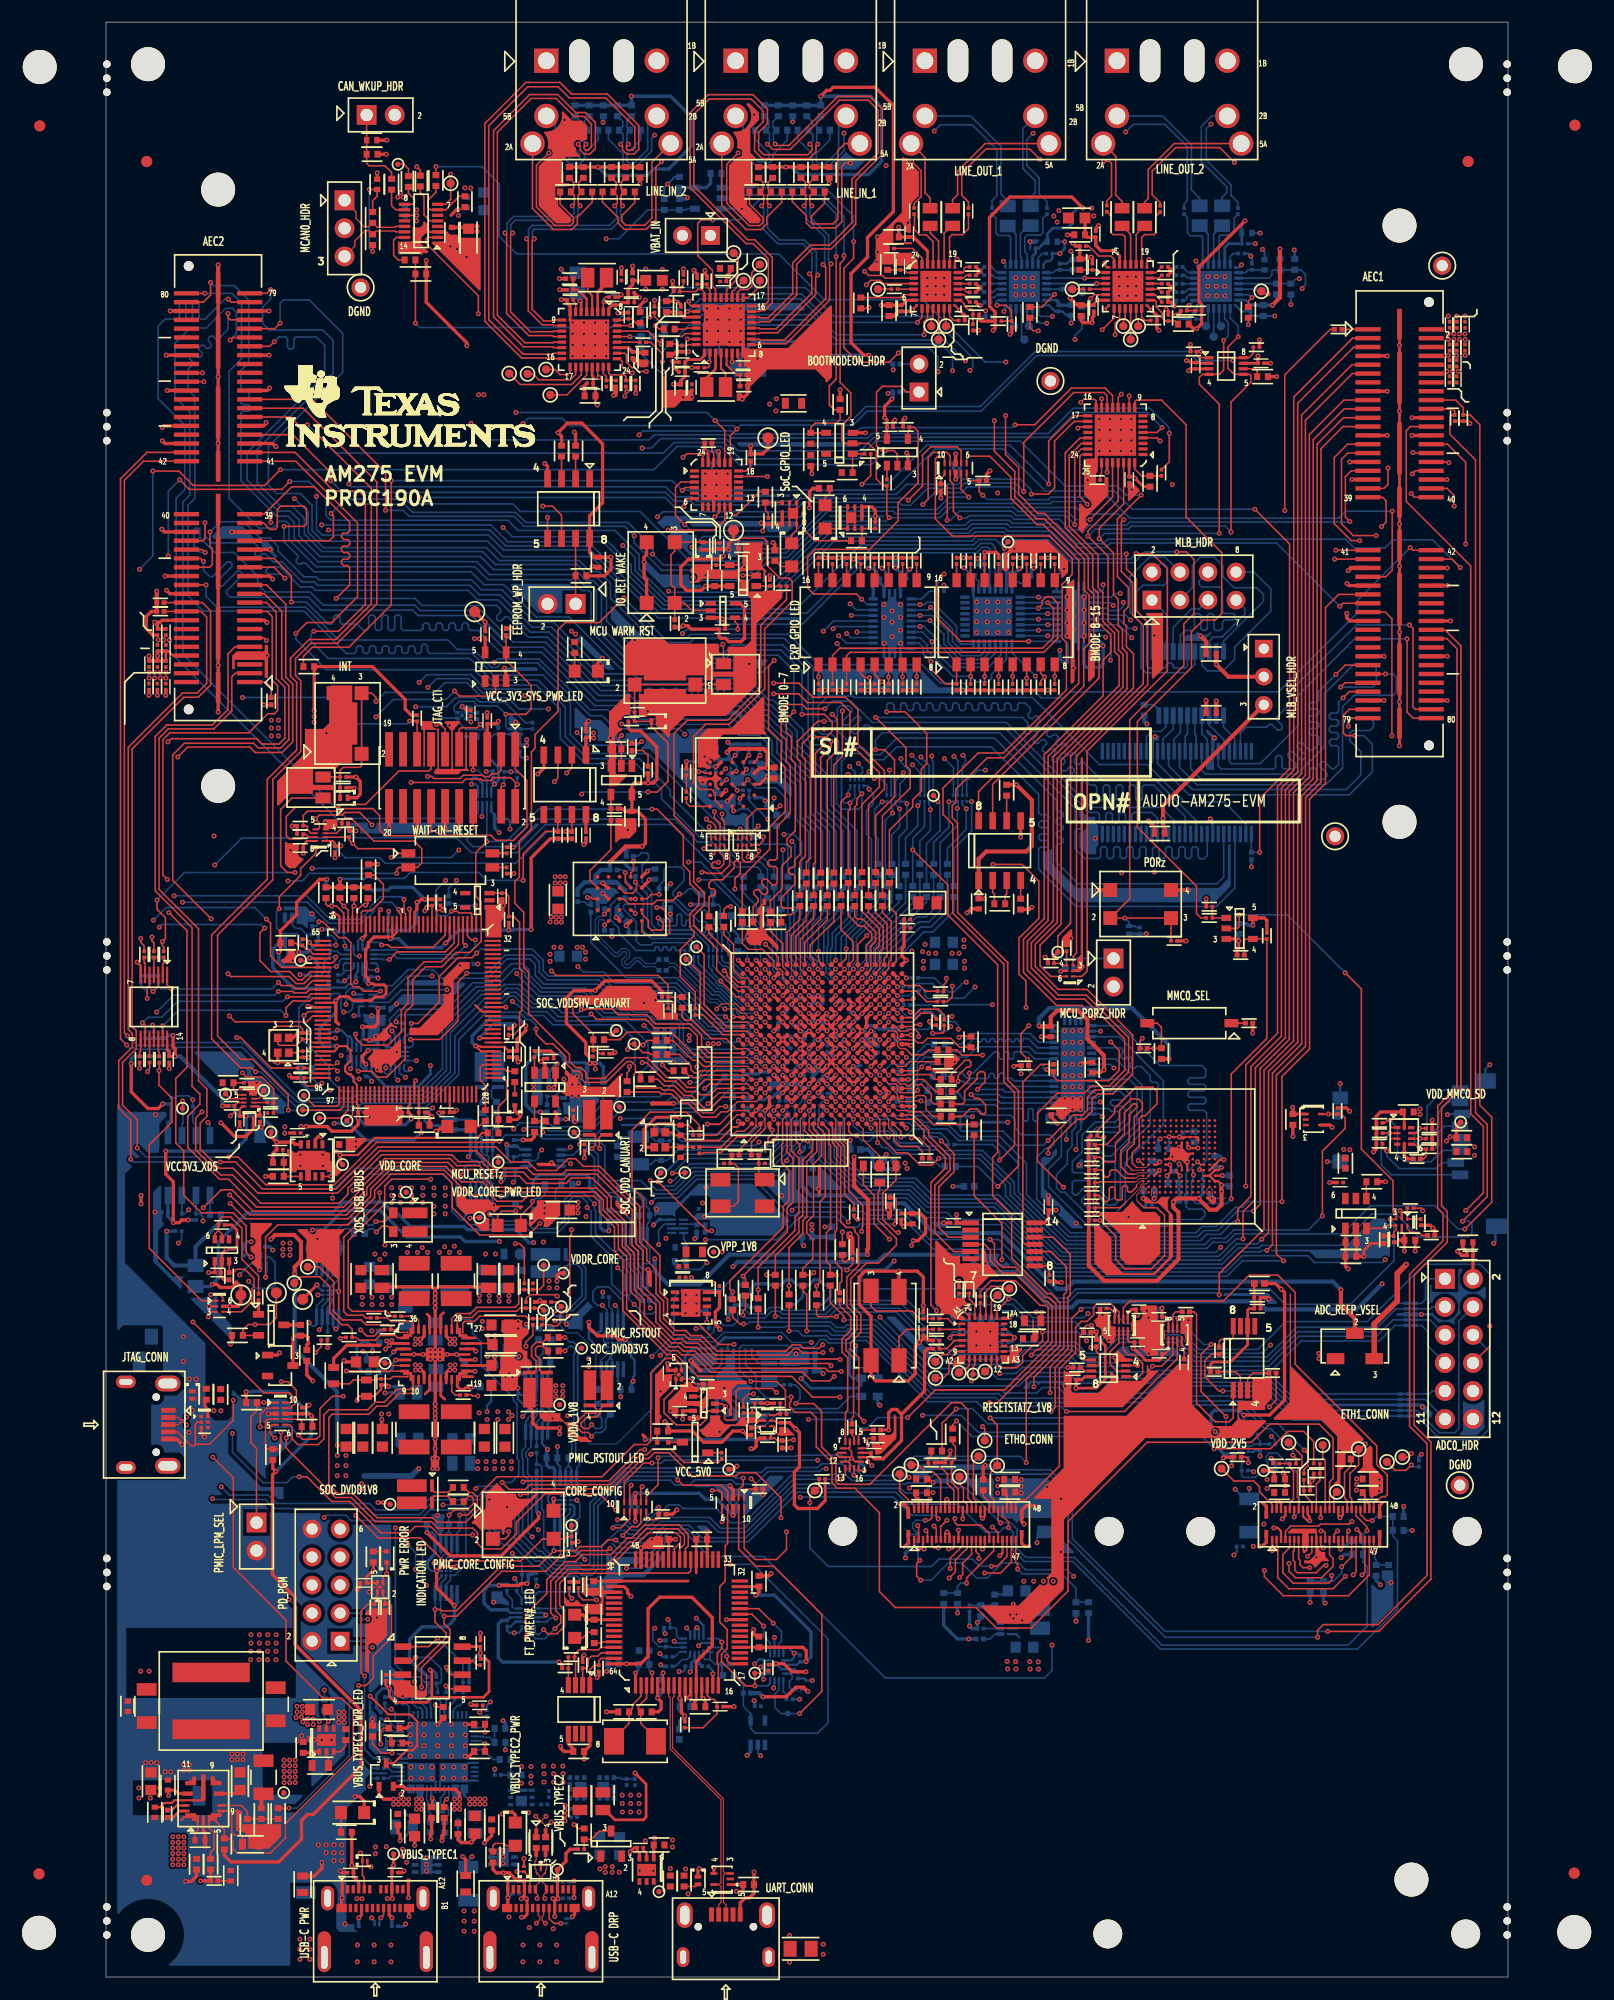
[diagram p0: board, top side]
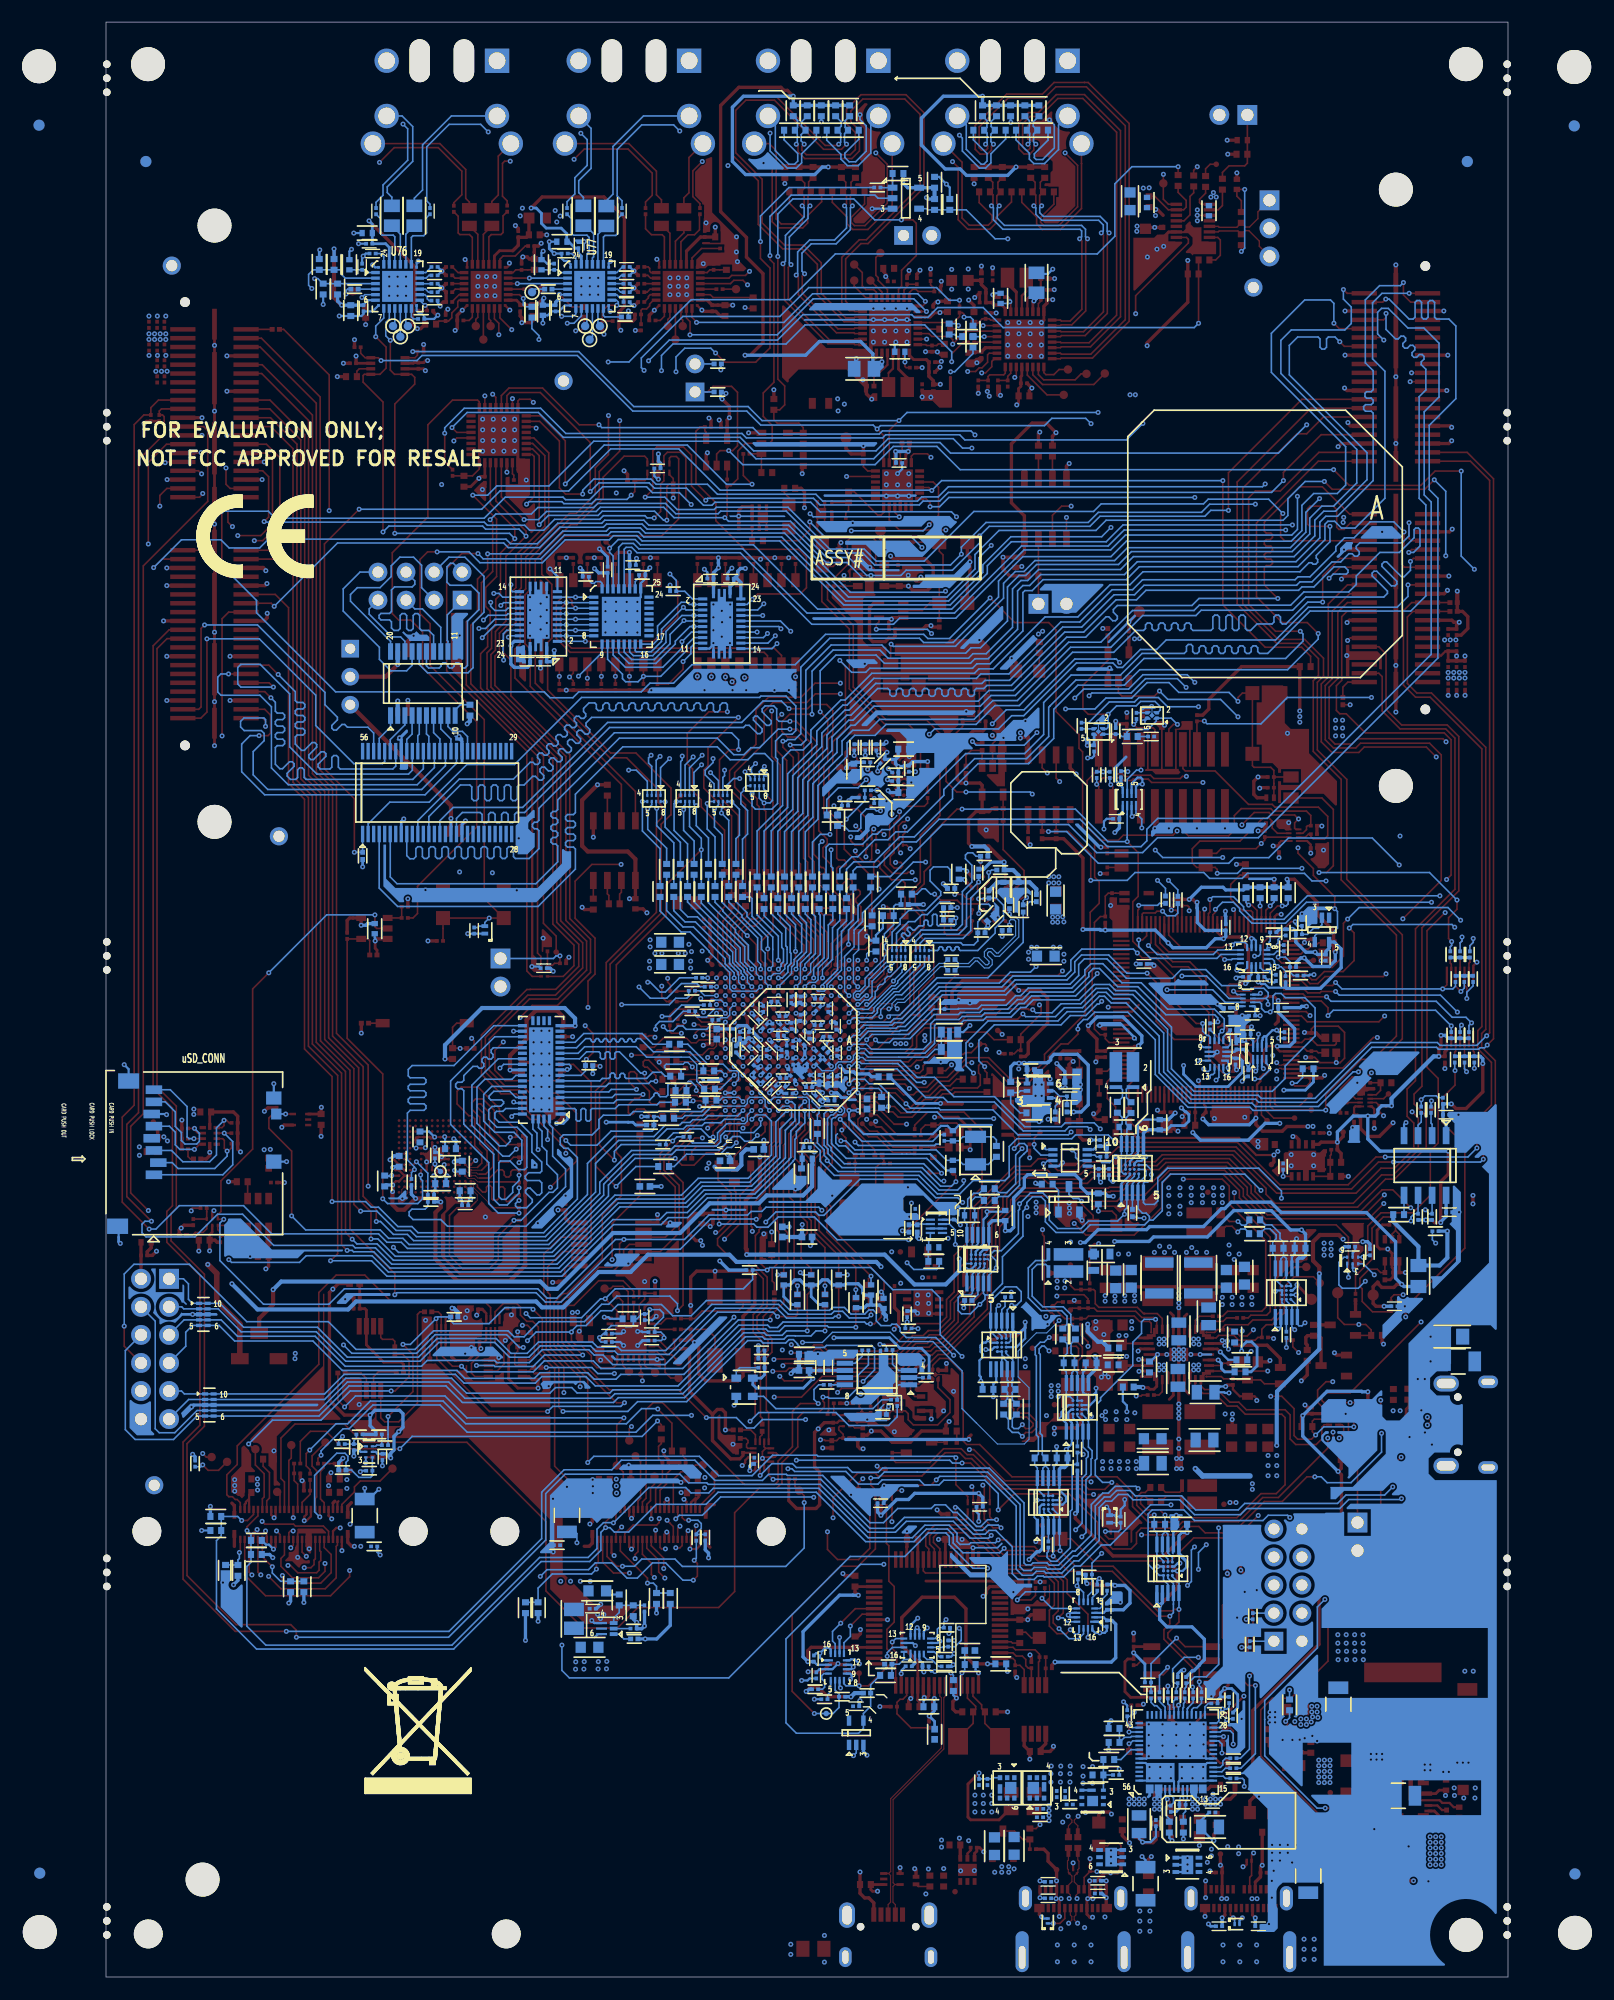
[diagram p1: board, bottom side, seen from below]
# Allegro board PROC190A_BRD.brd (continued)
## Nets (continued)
MCAN0_RX: R81.1 U136.B4
MCAN0_RX_R: R81.2 U3068.4
MCAN0_STB#: R102.1 U3068.14
MCAN0_T: C107.1 R88.1 R93.2
MCAN0_TX: R82.2 U136.C4
MCAN0_TX_R: R82.1 U3068.1
MCAN0_WAKE_R: R5635.1 U3068.9(WAKE)
MCAN1_RX: R5670.1 U136.D5
MCAN1_RX_R: J13.53 R5670.2
MCAN1_TX: J13.51 R5671.1
MCAN1_TX_R: R5671.2 U136.A4
MCAN4_RX: R5650.1 U136.B6
MCAN4_RX_R: J12.53 R5650.2
MCAN4_TX: J12.51 R5649.1
MCAN4_TX_R: R5649.2 U136.R4
MCASP0_ACLKR: J12.43 R5648.1 RA7.7
MCASP0_ACLKR_R: R5648.2 U136.R16
MCASP0_ACLKX: J12.37 R178.1 RA6.8
MCASP0_AFSR: J12.41 R498.2 RA7.6
MCASP0_AFSR_R: R498.1 U136.T17
MCASP0_AFSX: J12.39 R191.2 RA2.8
MCASP0_AFSX_R: R191.1 U136.M19
MCASP0_AXR0: J12.27 R176.2 RA5.8
MCASP0_AXR0_R: R176.1 U136.N17
MCASP0_AXR1: J12.29 R499.2 RA2.7
MCASP0_AXR1_R: R499.1 U136.M16
MCASP0_AXR2: J12.28 R493.2 RA2.6
MCASP0_AXR2_R: R493.1 U136.N18
MCASP0_AXR3: J12.30 R494.2 RA6.5
MCASP0_AXR3_R: R494.1 U136.M18
MCASP0_AXR4: J12.32 R495.2 RA7.5
MCASP0_AXR4_R: R495.1 U136.N16
MCASP0_AXR5: J12.34 R492.2 RA5.6
MCASP0_AXR5_R: R492.1 U136.P17
MCASP0_AXR6_R: R5718.1 U136.P18
MCASP0_AXR7: J12.38 R177.2 RA2.5
MCASP0_AXR7_R: R177.1 U136.P19
MCASP0_AXR8_R: R5719.1 U136.P16
MCASP0_AXR9: J12.40 R491.2 RA7.8
MCASP0_AXR9_R: R491.1 U136.R17
MCASP1_ACLKR_R: R179.2 U136.T18
MCASP1_ACLKX_R: R5646.2 U136.H19
MCASP1_AFSR_R: R5640.1 U136.T19
MCASP1_AFSX_R: R5647.1 U136.J17
MCASP1_AXR0_R: R500.1 U136.J18
MCASP1_AXR1_R: R5645.1 U136.J19
MCASP1_AXR2_R: R190.1 U136.J16
MCASP2_ACLKR: J13.43 R5669.1
MCASP2_ACLKR_R: R5669.2 U136.G17
MCASP2_ACLKX: J13.37 R5668.1
MCASP2_ACLKX_R: R5668.2 U136.L19
MCASP2_AFSR: J13.41 R5667.2
MCASP2_AFSR_R: R5667.1 U136.G16
MCASP2_AFSX: J13.39 R5666.2
MCASP2_AFSX_R: R5666.1 U136.K19
MCASP2_AXR0: J13.27 R5660.2
MCASP2_AXR0_R: R5660.1 U136.L17
MCASP2_AXR1: J13.29 R5661.2
MCASP2_AXR1_R: R5661.1 U136.K16
MCASP2_AXR2: J13.28 R5662.2
MCASP2_AXR2_R: R5662.1 U136.L18
MCASP2_AXR3: J13.30 R5663.2
MCASP2_AXR3_R: R5663.1 U136.K18
MCASP2_AXR4: J13.32 R5664.2
MCASP2_AXR4_R: R5664.1 U136.L16
MCASP2_AXR5: J13.34 R5665.2
MCASP2_AXR5_R: R5665.1 U136.M17
MCASP3_ACLKR: J13.78 R5683.1
MCASP3_ACLKX: J13.77 R5677.1
MCASP3_AFSR: J13.80 R5682.2
MCASP3_AFSX: J13.79 R5676.2
MCASP3_AXR0: J13.67 R5672.2
MCASP3_AXR1: J13.69 R5673.2
MCASP3_AXR2: J13.71 R5674.2
MCASP3_AXR3: J13.73 R5675.2
MCASP4_ACLKR: J12.78 U3072.54
MCASP4_ACLKR_FET: R5651.1 RA6.6 U3072.2
MCASP4_ACLKR_HDR: J28.3 U2345.20
MCASP4_ACLKR_LT: U2345.1 U3072.53
MCASP4_ACLKR_R: R5651.2 U136.R18
MCASP4_ACLKX: J12.77 U3072.39
MCASP4_ACLKX_FET: R5653.1 U3072.18
MCASP4_ACLKX_HDR: J28.1 U2345.12
MCASP4_ACLKX_LT: U2345.9 U3072.37
MCASP4_ACLKX_R: R5653.2 R5683.2 U136.F18
MCASP4_AFSR: J12.80 U3072.52
MCASP4_AFSR_FET: R5652.2 RA6.7 U3072.4
MCASP4_AFSR_HDR: J28.7 U2345.18
MCASP4_AFSR_LT: U2345.3 U3072.51
MCASP4_AFSR_R: R5652.1 U136.R19
MCASP4_AFSX: J12.79 U3072.41
MCASP4_AFSX_FET: R5655.2 U3072.15
MCASP4_AFSX_HDR: J28.5 U2345.13
MCASP4_AFSX_LT: U2345.8 U3072.40
MCASP4_AFSX_R: R5655.1 R5682.1 U136.F17
MCASP4_AXR0: J12.67 U3072.50
MCASP4_AXR0_FET: R5654.2 U3072.6
MCASP4_AXR0_HDR: J28.8 U2345.17
MCASP4_AXR0_LT: U2345.4 U3072.48
MCASP4_AXR0_R: R5654.1 U136.F19
MCASP4_AXR3: J12.69 U3072.43
MCASP4_AXR3_FET: R5658.2 U3072.13
MCASP4_AXR3_LT: U2345.7 U3072.42
MCASP4_AXR3_MLB0_SIG_HDR: J28.6 U2345.14
MCASP4_AXR3_R: R5658.1 U136.U18
MCASP4_AXR4: J12.71 U3072.47
MCASP4_AXR4_FET: R5656.2 U3072.9
MCASP4_AXR4_LT: U2345.5 U3072.46
MCASP4_AXR4_MLB0_CLK_HDR: J28.4 U2345.16
MCASP4_AXR4_R: R5656.1 U136.U19
MCASP4_AXR5: J12.73 U3072.45
MCASP4_AXR5_FET: R5657.2 U3072.11
MCASP4_AXR5_LT: U2345.6 U3072.44
MCASP4_AXR5_MLB0_DAT_HDR: J28.2 U2345.15
MCASP4_AXR5_R: R5657.1 U136.V19
MCASP4_FET_SEL: R5681.1 R5764.1 U18.4 U3072.1
MCASP_VSEL_HDR: C3702.1 J29.2 U2345.19(VCCB)
MCU_GPIO0_1_INTN: R108.1 R547.2 U136.C7
MCU_INTN: R299.1 U136.M2
MCU_OSC0_XI: R249.2 R252.2 U136.A2
MCU_OSC0_XO: R253.2 R254.2 U136.B1
MCU_PORZ: J32.1 R238.1 R242.2 R5775.1 R5776.1 TP49.1(TP) U43.4(Y) U136.E3
MCU_RESETZ: R550.2 TP50.1(TP) U98.7 U136.D9
MCU_SAFETY_ERRORZ_1V8: R281.1 U3091.7
MCU_SAFETY_ERRORZ_1V8_BUF: R5842.1 TP54.1(TP) U136.F3
MIC1_BIAS: C3.1 C329.1 C379.1 R7.1 R8.1 R9.1 R10.1 R405.1 R406.1 R407.1 R408.1 U7.6
MIC2_BIAS: C2.1 C330.1 C363.1 R3.1 R4.1 R5.1 R6.1 R409.1 R410.1 R411.1 R412.1 U8.6
MMC0_CLK: R558.1 U57.2
MMC0_FET_EN: R5215.2 R5216.2 U18.3 U57.8
MMC0_SD_EN: R21.1 U21.4
MMC0_SD_LS_EN: R17.1 R5823.2 U2.4(Y) U4.3
MMC0_SDIO_VSEL: U56.11 U3087.4(Y)
MMC0_SEL_1V8: U3077.4 U3086.1 U3087.1
MMC0_SEL_3V3: R5758.1 U3077.11
MMC0_SEL_IO: R5846.1 U18.17
OBSCLK0: R5719.2 RA5.5 TP587.1(TP)
OSC0: C217.2 U48.88 Y5.3
OSC1: C223.2 U48.89 Y5.1
OSC1_XI: R3732.1 U136.C1
OSC1_XO: R3733.1 U136.C2
OSPI0_CSN0: R206.2 U136.A17
OSPI0_RESET_OUT0: R121.1 U136.A16
OSPI_CLK: R197.1 R451.1 U28.B2
OSPI_CS: R206.1 R447.1 R5826.2 R5827.2
OSPI_DQ0: R446.1 RA3.1 U28.D3
OSPI_DQ1: R450.1 RA3.2 U28.D2
OSPI_DQ2: R452.1 RA3.3 U28.C4
OSPI_DQ3: R449.1 RA3.4 U28.D4
OSPI_DQ4: R448.1 RA4.1 U28.D5
OSPI_DQ5: R445.1 RA4.2 U28.E3
OSPI_DQ6: R444.1 RA4.3 U28.E2
OSPI_DQ7: R443.1 RA4.4 U28.E1
OSPI_DQS: R453.1 U28.C3
OSPI_DQS_SOC: R453.2 R454.1 R504.1 U136.B19
OSPI_INTN: R123.1 R125.1
OSPI_RSTN: R124.1 R5821.2 U27.4(Y) U28.A4
P2_PP_EXT_ENABLE: R669.1 U129.49
PCM1_ADDR_0: R20.2 R26.1 U7.24
PCM1_ADDR_1: R22.1 R23.2 U7.23
PCM1_AREG: C89.1 C378.1 U7.2
PCM1_BSTOUT: C92.2 C96.1 U7.5
PCM1_DREG: C81.1 C82.1 U7.32
PCM1_GPIO1: R34.2 R432.1 U7.28
PCM1_IN1N: C17.2 R9.2 U7.10
PCM1_IN1P: C18.2 R10.2 U7.9
PCM1_IN2N: C15.2 R7.2 U7.12
PCM1_IN2P: C16.2 R8.2 U7.11
PCM1_IN3N: C334.2 R408.2 U7.14
PCM1_IN3P: C333.2 R407.2 U7.13
PCM1_IN4N: C332.2 R406.2 U7.16
PCM1_IN4P: C331.2 R405.2 U7.15
PCM1_INT_1V8: R34.1 U21.15
PCM1_MCASP1_AXR0: R38.2 U7.29
PCM1_RESETN: R68.2 R78.1 U7.22 U14.4(Y)
PCM1_VREF: C87.1 U7.7
PCM2_ADDR_0: R62.2 R63.1 U8.24
PCM2_ADDR_1: R60.2 R61.1 U8.23
PCM2_AREG: C64.1 C368.1 U8.2
PCM2_BSTOUT: C54.1 C60.2 U8.5
PCM2_IN1N: C13.2 R5.2 U8.10
PCM2_IN1P: C14.2 R6.2 U8.9
PCM2_IN2N: C11.2 R3.2 U8.12
PCM2_IN2P: C12.2 R4.2 U8.11
PCM2_IN3N: C338.2 R412.2 U8.14
PCM2_IN3P: C337.2 R411.2 U8.13
PCM2_IN4N: C336.2 R410.2 U8.16
PCM2_IN4P: C335.2 R409.2 U8.15
PCM2_INT_1V8: R46.1 U21.16
PCM2_MCASP1_AXR0: R431.2 R433.1
PCM2_RESETN: R415.2 R416.1 U8.22 U75.4(Y)
PCM2_VREF: C65.1 U8.7
PCM6240_MCASP1_ACLKR: R179.1 U7.30 U8.30
PCM6240_MCASP1_AFSR: R5640.2 U7.31 U8.31
PCM6240_MCASP1_AXR0: R38.1 R431.1 R500.2
PCM6240_MCASP1_AXR2: R190.2 R435.1
PD_GPIO0: R674.2 U129.16
PD_HRESET: C301.1 R662.1 U129.44
PD_I2C_IRQ: R645.2 R655.1 U18.6
PD_MS_I2C1_IRQ: R660.2 U129.29
PD_MS_I2C1_SCL: R633.1 R664.2 U129.27
PD_MS_I2C1_SDA: R627.1 R658.2 U129.28
PD_S_I2C2_IRQ: R655.2 U129.34
PD_S_I2C2_SCL: R657.2 U129.32
PD_S_I2C2_SDA: R656.2 U129.33
PD_SPI_CLK: J21.7 R652.2 U69.6
PD_SPI_MISO: J21.5 R644.2 R654.2 U69.2
PD_SPI_MOSI: J21.8 R653.2 U69.5
PD_SPI_SS: J21.9 R646.2 R651.2 U69.1
PD_VIN_3V3: C320.2 U129.5(VIN_3V3)
PMIC_EN: R317.2 U56.17
PMIC_ENABLE: U54.6 U2356.10
PMIC_I2C_SCL_1V8: R296.2 TP72.1(TP) U56.1
PMIC_I2C_SDA_1V8: R294.2 TP73.1(TP) U56.2
PMIC_INT_B: R288.2 R299.2 R300.2 TP70.1(TP) U56.27
PMIC_INTN: R205.1 R300.1 U136.P3
PMIC_LPM_EN0: R5737.1 R5750.2 TP75.1(TP) U2356.2 U2356.7
PMIC_LPM_SEL: J16.1 R318.1 U2356.1 U2356.5
PMIC_NSLEEP: U56.10 U2356.6
PMIC_POWERGOOD: R290.1 U86.1
PMIC_RSTOUT: R286.1 R290.2 R291.2 TP67.1(TP) U56.28
PORT1_15W: R386.1 R5767.1 U71.2
PORT2_15W: R381.1 R390.1 U71.1
PP1_CABLE: C309.1 U129.25
PP2_CABLE: C631.1 R665.2 U129.46
PRI/SEC_REF_SEL: R75.2 R76.1 U15.4
RESET_STATZ: R5738.1 TP592.1(TP) U136.H4
RESETSTATZ: R366.1 R605.1 R5843.2 U18.24 U3083.6
RESETSTATZ_1V8: J12.55 J13.55 R377.2 R5738.2 R5760.2 TP100.1(TP) U2.3 U14.2 U15.8 U21.28 U26.2 U27.2 U75.2 U2348.2 U3083.3 U3088.2
RESETSTATZ_1V8_INV: R5832.1 R5844.1 R5845.2 U3088.4(Y)
RESETSTATZ_1V8_INV_RC: C3781.1 R5844.2 U3091.4
RGMII1_INH_3V3: J18.26 TP65.1(TP)
RGMII1_RX_ER: J18.39 TP99.1(TP)
RGMII1_RX_LINK: J18.43 R360.2 TP98.1(TP)
RGMII2_INH_3V3: J19.26 TP59.1(TP)
RGMII2_RX_ER: J19.39 TP89.1(TP)
RGMII2_RX_LINK: J19.43 R347.2 TP91.1(TP)
SD_MMC0_CLK: J26.5 R54.1 R202.1 U10.6 U57.41
SD_MMC0_CMD: J26.3 R66.1 U10.1 U57.23
SD_MMC0_D0: J26.7 R65.1 U10.8 U57.38
SD_MMC0_D1: J26.8 R57.1 U10.7 U57.36
SD_MMC0_D2: J26.1 R64.1 U10.2 U57.29
SD_MMC0_D3: J26.2 R55.1 U10.3 U57.39
SD_MMC0_SDCD: J26.9 R70.1 U12.5 U136.N2
SEC_REF_N: R74.1 U15.2
SEC_REF_P: R73.1 U15.1
SEL_XDS: U39.5 U93.4(Y) U97.1 U97.16 U109.4
SEL_XDS110_INV: J14.8 R531.2 R536.1 U90.4 U93.2 U102.5 U110.1 U110.16 U2355.2
SEL_XDS110_INV_3V3: R5735.1 U87.2 U88.2 U2355.4(Y)
SOC_CLKIN: R249.1 R349.2
SOC_DVDD1V8: C429.1 C437.1 C440.1 C453.1 C461.1 C502.1 C506.1 R334.3 TP86.1(TP) U56.24 U136.E13 U136.F8 U136.F9 U136.F12 U136.H14 U136.J6 U136.J14 U136.K6 U136.K14 U136.M6
SOC_DVDD1V8_N: C603.2 R335.1 U123.D1 U123.D2 U124.8 U124.9
SOC_DVDD1V8_P: C603.1 R331.1 U123.D3 U124.10
SOC_DVDD3V3: C451.1 C471.1 FL19.1 R327.3 TP83.1(TP) U56.22 U136.H5 U136.P11 U136.P12
SOC_DVDD3V3_FB1: C3645.1 FL19.2 U136.R9
SOC_DVDD3V3_N: C428.2 R539.1 U91.8 U91.9 U92.D1 U92.D2
SOC_DVDD3V3_P: C428.1 R540.1 U91.10 U92.D3
SOC_EMU0: R225.2 SW3.1 U39.2 U102.2 U136.C9
SOC_EMU1: R220.2 SW3.2 U39.3 U102.3 U136.C10
SOC_GPIO0_38: R213.1 U136.K17
SOC_HYPERBUS0_DQ0: RA8.8 U136.A13
SOC_HYPERBUS0_DQ1: RA8.7 U136.D12
SOC_HYPERBUS0_DQ2: RA8.5 U136.D13
SOC_HYPERBUS0_DQ3: RA8.6 U136.C13
SOC_HYPERBUS0_DQ4: RA9.8 U136.A15
SOC_HYPERBUS0_DQ5: RA9.5 U136.C15
SOC_HYPERBUS0_DQ6: RA9.7 U136.B14
SOC_HYPERBUS0_DQ7: RA9.6 U136.C14
SOC_I2C0_SCL: J18.40 J19.40 R56.2 R622.2 R625.1 R657.1 U11.8 U18.19 U25.2 U91.2 U91.5 U92.A1 U92.B3 U113.A1 U114.5 U115.A1 U116.5 U118.1 U118.5 U119.A1 U119.C3 U123.A1 U124.5 U2357.8 U3078.5 U3079.2 U3079.5 U3080.A1 U3081.A1 U3081.B3
SOC_I2C0_SDA: J18.42 J19.42 R58.2 R616.1 R618.2 R656.1 U11.1 U18.20 U25.3 U91.4 U92.A2 U113.A2 U114.4 U115.A2 U116.4 U118.4 U119.A2 U123.A2 U124.4 U2357.7 U3078.2 U3078.4 U3079.4 U3080.A2 U3080.B3 U3081.A2
SOC_MMC0_CLK: R558.2 U136.V5
SOC_MMC0_CMD: R5819.1 U57.14
SOC_MMC0_CMD_R: R5819.2 U136.T6
SOC_MMC0_DAT0: R5811.1 U57.4
SOC_MMC0_DAT0_R: R5811.2 U136.W4
SOC_MMC0_DAT1: R5812.1 U57.5
SOC_MMC0_DAT1_R: R5812.2 U136.W5
SOC_MMC0_DAT2: R5813.1 U57.11
SOC_MMC0_DAT2_R: R5813.2 U136.V6
SOC_MMC0_DAT3: R5814.1 U57.3
SOC_MMC0_DAT3_R: R5814.2 U136.U6
SOC_MMC0_DAT4: R5815.1 U57.13
SOC_MMC0_DAT4_R: R5815.2 U136.U7
SOC_MMC0_DAT5: R5816.1 U57.12
SOC_MMC0_DAT5_R: R5816.2 U136.T7
SOC_MMC0_DAT6: R5817.1 U57.6
SOC_MMC0_DAT6_R: R5817.2 U136.V7
SOC_MMC0_DAT7: R5818.1 U57.7
SOC_MMC0_DAT7_R: R5818.2 U136.W7
SOC_OSPI_CLK: R197.2 U136.B17
SOC_OSPI_DQ0: RA3.8 U136.B16
SOC_OSPI_DQ1: RA3.7 U136.D17
SOC_OSPI_DQ2: RA3.6 U136.C17
SOC_OSPI_DQ3: RA3.5 U136.D16
SOC_OSPI_DQ4: RA4.8 U136.E16
SOC_OSPI_DQ5: RA4.7 U136.B18
SOC_OSPI_DQ6: RA4.6 U136.D18
SOC_OSPI_DQ7: RA4.5 U136.C18
SOC_PORZ: R480.2 U43.3 U86.4(Y)
SOC_PORZ_PB: R268.2 TP55.1(TP) U43.1 U98.2
SOC_RGMII_MDC: R338.1 R352.1 R548.2
SOC_RGMII_MDIO: R340.1 R345.1 R541.2
SOC_TCK: R534.1 R544.1 R566.1 U136.A10
SOC_TDI: R554.1 U97.6 U110.9 U136.D10
SOC_TDO: R542.1 U90.2 U109.2
SOC_TMS: R533.1 U97.8 U110.8 U136.C11
SOC_TRST#: R564.1 U97.9 U110.6 U136.B10
SOC_UART0_RXD: R5734.2 U136.L2
SOC_UART0_RXD_XDS: R5730.1 U2353.13
SOC_UART0_TXD: R5732.2 U2353.8
SOC_UART0_TXD_XDS: R5731.1 U2353.15
SOC_USB0_DM: L10.4(OUT2) R400.1 U136.W9
SOC_USB0_DP: L10.1 R399.1 U136.V9
SOC_USB0_DRVVBUS: U136.W2 U3077.5
SOC_USB0_DRVVBUS_3V3: R673.1 R674.1 U3077.10
SOC_USB0_RCALIB: R553.1 U136.V8
SOC_USB0_VBUS: R398.1 R560.1 U136.U9
SOC_VDD_CANUART: C224.1 R3731.1 R5786.2 TP52.1(TP) U136.F6
SOC_VDD_CANUART_N: C3761.2 R5780.1 U3078.8 U3078.9 U3080.D1 U3080.D2
SOC_VDD_CANUART_P: C3761.1 R5781.1 U3078.10 U3080.D3
SOC_VDDSHV5_SDIO: C3655.1 R243.2 U136.P9 U136.R8
SOC_VDDSHV_CANUART: C512.1 R5787.2 TP597.1(TP) U136.F7
SOC_VDDSHV_CANUART_N: C3763.2 R5784.1 U3079.8 U3079.9 U3081.D1 U3081.D2
SOC_VDDSHV_CANUART_P: C3763.1 R5785.1 U3079.10 U3081.D3
SPI0_CLK: J12.17 R216.1
SPI0_CLK_R: R216.2 U136.M1
SPI0_CS0: J12.23 U136.J3
SPI0_CS1: J12.24 U136.J4
SPI0_D0: J12.19 U136.K3
SPI0_D1: J12.21 U136.K4
SPI1_CLK: J13.17 R5659.1
SPI1_CLK_R: R5659.2 U136.U2
SPI1_CS0: J13.23 U136.U1
SPI1_CS1: J13.24 U136.D15
SPI1_D0: J13.19 U136.T3
SPI1_D1: J13.21 U136.U3
SPI_HOLDN: R374.2 U69.7
SPI_WPN: R378.2 U69.3(W\P\(IO2))
SW_2V5: L11.1 U127.5
SYNC1_OUT: R5788.1 U3083.2
SYNC1_OUT_3V3: R5793.1 U3084.1
SYNC1_OUT_ETH1: J18.38 R5791.2 TP93.1(TP)
SYNC1_OUT_ETH2: J19.38 R5792.2 TP87.1(TP)
SYS_BOOTMODE0: R153.1 SW2.1 U81.10 U82.1
SYS_BOOTMODE1: R154.1 SW2.2 U81.9 U82.2
SYS_BOOTMODE2: R155.1 SW2.3 U81.8 U82.3
SYS_BOOTMODE3: R156.1 SW2.4 U81.7 U82.4
SYS_BOOTMODE4: R157.1 SW2.5 U81.6 U82.5
SYS_BOOTMODE5: R158.1 SW2.6 U81.5 U82.6
SYS_BOOTMODE6: R159.1 SW2.7 U81.4 U82.7
SYS_BOOTMODE7: R160.1 SW2.8 U81.3 U82.8
SYS_BOOTMODE8: R145.1 SW1.1 U82.9 U83.10
SYS_BOOTMODE9: R146.1 SW1.2 U82.10 U83.9
SYS_BOOTMODE10: R147.1 SW1.3 U82.11 U83.8
SYS_BOOTMODE11: R148.1 SW1.4 U82.12 U83.7
SYS_BOOTMODE12: R149.1 SW1.5 U82.13 U83.6
SYS_BOOTMODE13: R150.1 SW1.6 U82.14 U83.5
SYS_BOOTMODE14: R151.1 SW1.7 U82.15 U83.4
SYS_BOOTMODE15: R152.1 SW1.8 U82.16 U83.3
SYSBOOT_BUF_ENZ: R377.1 U23.1
TAD1_ADDR1: R29.2 R37.2 U5.13
TAD1_DREG_OUT: C42.1 C45.1 U5.1
TAD1_GPI1: R31.1 U5.12
TAD1_MICBIAS: C66.1 U5.14
TAD1_VREF: C38.1 U5.24
TAD2_ADDR2: R33.2 R36.2 U77.13
TAD2_DREG_OUT: C356.1 C358.1 U77.1
TAD2_GPI1: R429.1 U77.12
TAD2_MICBIAS: C370.1 U77.14
TAD2_VREF: C354.1 U77.24
TAD3_ADDR3: R30.1 R35.1 U6.13
TAD3_DREG_OUT: C43.1 C46.1 U6.1
TAD3_GPI3: R32.1 U6.12
TAD3_MICBIAS: C67.1 U6.14
TAD3_VREF: C35.1 U6.24
TAD4_ADDR4: R27.1 R28.1 U76.13
TAD4_DREG_OUT: C355.1 C357.1 U76.1
TAD4_GPI4: R430.1 U76.12
TAD4_MICBIAS: C369.1 U76.14
TAD4_VREF: C353.1 U76.24
TAD5212_1_DIN: R5641.2 U5.5
TAD5212_2_DIN: R5642.2 U77.5
TAD5212_3_DIN: R5643.2 U6.5
TAD5212_4_DIN: R5644.2 U76.5
TAD5212_MCASP1_ACLKX: R418.2 R419.1 R5646.1 U5.2 U6.2 U76.2 U77.2
TAD5212_MCASP1_AFSX: R422.2 R423.1 R5647.2 U5.3 U6.3 U76.3 U77.3
TAD5212_MCASP1_AXR1: R5641.1 R5642.1 R5643.1 R5644.1 R5645.2
TCA6424_EXP_INT: R457.1 U82.32
TEST_GPIO1: Q7.1 R235.1 R526.2
TEST_GPIO2: R283.1 R285.2 U21.18
TEST_GPIO3: J10.1 R227.1 R439.1 R516.2 U23.2
TEST_GPIO4: R221.1 R511.2 U82.28
TEST_PORZN: R219.1 R507.2 U43.6
TEST_POWERDOWN: R233.1 R524.2 U54.1
TEST_WARMRESETN: Q12.1 R224.1 R513.2
TM4C129_TCK: TP66.1(TP) U48.100
TM4C129_TDI: TP64.1(TP) U48.98
TM4C129_TDO: TP62.1(TP) U48.97
TM4C129_TMS: TP63.1(TP) U48.99
TMP411_ALERT: R5741.2 U2357.6
TMP411_THERM: R5742.2 U2357.4
TPS65224_EN: Q4.2(S) R303.1 R317.1 TP81.1(TP)
UART2_FET_SEL: R5799.2 U21.13 U2351.1 U2351.5
UART2_RXD: J12.62 U2351.4
UART2_RXD_FET: R5718.2 RA5.7 U2351.6
UART2_TXD: J12.60 U2351.2
UART2_TXD_FET: U136.T4 U2351.10
UART3_FET_SEL: R5800.2 U21.14 U2352.1 U2352.5
UART3_RXD: J13.62 U2352.4
UART3_RXD_FET: U136.C6 U2352.6
UART3_TXD: J13.60 U2352.2
UART3_TXD_FET: U136.N4 U2352.10
UART_SHIELD: J22.6 J22.7 J22.8 J22.9 R385.2
USB_TYPEC1_EARTH: C648.1 J24.SH1 J24.SH2 J24.SH3 J24.SH4 R404.1
USB_TYPEC2_EARTH: C651.1 J25.SH1 J25.SH2 J25.SH3 J25.SH4 R403.1
USBC_CONN1_CC1: C307.1 D7.1(CATHODE) J24.A5 U129.24
USBC_CONN1_CC2: C306.1 D17.1(CATHODE) J24.B5 U129.26
USBC_CONN2_CC1: C305.1 D8.1(CATHODE) J25.A5 U129.45
USBC_CONN2_CC2: C312.1 D16.1(CATHODE) J25.B5 U129.47
USBC_CONN2_DM: D9.3(IO2) J25.A7 J25.B7 L10.3 R400.2
USBC_CONN2_DP: D9.2 J25.A6 J25.B6 L10.2 R399.2
VMAIN: C310.1 C3625.1 C3628.1 C3629.1 C3630.1 C3631.1 C3697.2 R395.1 R5636.1 R5740.1 TP104.1(TP) U73.1(VOUT) U134.8 U134.12(VIN2) U3068.10
VMAIN_EN: LD14.1(CATHODE) R382.1 U71.4(Y)
VMAIN_PD: C302.1 C322.1 C323.1 C324.1 U73.6 U129.1 U129.11
VMON1: C3750.2 R5773.1 R5774.2 U56.9
VPHY_3V3_FT4232: C606.2 FL17.1 U64.4
VPLL_3V3_FT4232: C607.2 FL18.1 R357.2 U64.9
VPP_1V8: C517.1 R304.2 TP69.1(TP) U136.G5
VPP_EN: R319.1 U21.5
VPP_SUPPLY: C247.2 C251.2 R304.1 U59.1(OUT)
VSEL_SD_SOC: R5751.2 R5830.1 U3086.2
WD_DISABLE: R281.2 R282.2 TP56.1(TP) U56.29
WKUP_I2C0_SCL: C245.1 R284.1 R297.1 R301.2
WKUP_I2C0_SCL_RC: R284.2 U136.B9
WKUP_I2C0_SDA: C248.1 R256.1 R259.2 R307.1
WKUP_I2C0_SDA_RC: R256.2 U136.A8
WKUP_LFOSCO_XI: C216.2 R568.1 U136.E1 Y4.1
WKUP_LFOSCO_XO: C213.2 R261.2 R568.2 Y4.2
WKUP_UART0_CTSN: R322.2 U117.9 U136.D6
WKUP_UART0_RTSN: R593.2 U117.7 U136.C5
WKUP_UART0_RXD: R326.2 U117.8 U136.B5
WKUP_UART0_TXD: R592.2 U117.6 U136.A5
XDS110_DIR: R555.2 U97.4 U97.5
XDS110_EMU0: R237.2 U48.42 U102.7
XDS110_EMU1: R236.2 U48.43 U102.6
XDS110_TCK: U48.35 U97.14
XDS110_TDI: U48.38 U97.15
XDS110_TDO: U48.37 U109.7
XDS110_TMS: U48.36 U97.13
XDS110_TRST#: U48.40 U97.12
XDS_GPIO1: R235.2 U40.2
XDS_GPIO2: R283.2 U51.2
XDS_GPIO3: R227.2 U40.4
XDS_GPIO4: R221.2 U40.6
XDS_PORZN: R219.2 U40.8
XDS_POWERDOWN: R233.2 U40.12
XDS_RSTN: R549.1 R556.1 TP51.1(TP) U48.70
XDS_SHIELD: C605.2 J17.6 J17.7 J17.8 J17.9 R610.2
XDS_USB_DM: J17.2 U48.93
XDS_USB_DP: J17.3 U48.94
XDS_USB_ID: J17.4 R271.2 U60.2
XDS_USB_VBUS: C244.1 C250.1 C267.1 D1.2 J17.1(VBUS) R295.1 R314.1 R576.1 TP78.1(TP) U55.1 U55.2 U60.6(VCC)
XDS_VREF: C190.1 C215.2 R241.2 U41.3 U48.9
XDS_WARMRESETN: R224.2 U40.10
ZENER_CLAMP: D2.3 R298.1 R308.1
N16856152: C270.1 U64.3 Y6.2
N16856224: C269.1 U64.2 Y6.1
N16857368: C283.2 U66.2
N16880083: R18.1 R21.2 U2.1
N16956459: R121.2 R122.1 U27.1
N16994873: R483.2 U88.4(Y)
N16994875: R476.2 U87.4(Y)
N16995245: C417.1 R487.2
N16997746: R218.1 U48.59
N17030208: R544.2 U97.7
N17031262: LD9.2 R402.2
N17078974: J10.2 R438.2
N17269599: R363.1 R366.2 U68.6
N17269609: R362.1 R364.2 R367.1 U68.1
N17378539: LD7.1(CATHODE) R330.2
N17479799: R314.2 U55.8
N17479805: C243.2 R306.2 R313.1 U55.5
N17479881: C203.2 R246.1 U48.68
N17481587: LD5.2 R287.2
N17481598: C225.2 R576.2 U48.96
N17481613: R271.1 U48.95
N17481619: R289.1 R295.2 U48.1
N17481621: R232.2 R520.1 U48.60
N17481627: R276.1 U48.3
N17481631: LD3.2 R276.2
N17481633: R229.2 R523.1 U48.63
N17481635: R231.2 R521.1 U48.61
N17481637: R287.1 U48.4
N17481641: R230.2 R522.1 U48.62
N17824845: R654.1 U129.36
N17824852: R653.1 U129.37
N17824859: R652.1 U129.38
N17824866: R651.1 U129.39
N19741013: R390.2 U129.18
N19806973: R566.2 U110.7
N21761137: R5750.1 U136.A7
N21784165: R548.1 U136.V11
N21784176: R541.1 U136.U11
N22498870: R602.1 R605.2 U120.6
N22498881: R601.1 R604.2 R606.1 U120.1
N22682556: J21.1 R633.2
N22682559: J21.3 R627.2
N24306091: C3746.2 R293.1 U3076.5(QOD) U3076.6
N24306103: Q4.1 R293.2
N24306157: D5.3(K) R308.2
N24306190: Q4.3 R298.2
N24307354: R5828.2 U56.4
N24307356: R5829.2 U56.6
N24478126: C70.1 U4.4
N24517110: R214.2 SW3.3
N24517112: R217.2 SW3.4
N24605604: C18.1 J2.5A
N24605606: C16.1 J2.2A
N24605709: R84.2 R90.1 U14.1
N24605835: TP5.1(TP) U7.20
N24605846: L3.2 U7.4
N24605909: C333.1 J2.5B
N24606047: TP8.1(TP) U7.19
N24606049: TP9.1(TP) U7.17
N24606166: C331.1 J2.2B
N24847876: R421.1 U77.4
N24847884: C348.1 J3.5B
N24847886: C347.1 J3.2B
N24847888: C347.2 U77.21
N24847892: C344.2 U77.19
N24847894: C343.2 U77.22
N24847910: C348.2 U77.20
N24847912: TP113.1(TP) U77.11
N24847957: C367.1 U77.15
N24847963: C365.1 U77.16
N24847969: C362.1 U77.17
N24847975: C360.1 U77.18
N24847993: TP112.1(TP) U77.9
N24847995: TP115.1(TP) U77.10
N24848039: R24.1 U5.4
N24848041: C25.1 J3.5A
N24848043: C24.1 J3.2A
N24848045: C24.2 U5.21
N24848047: C23.2 U5.19
N24848049: C22.2 U5.22
N24848518: C25.2 U5.20
N24848523: TP18.1(TP) U5.11
N24848568: C61.1 U5.15
N24848574: C56.1 U5.16
N24848580: C50.1 U5.17
N24848586: C47.1 U5.18
N24848600: R24.2 TP12.1(TP)
N24848612: R421.2 TP109.1(TP)
N24848616: TP17.1(TP) U5.9
N24848618: TP22.1(TP) U5.10
N24851304: R420.1 U76.4
N24851306: R420.2 TP14.1(TP)
N24851312: C346.1 J4.5B
N24851314: C345.1 J4.2B
N24851316: C345.2 U76.21
N24851320: C342.2 U76.19
N24851322: C341.2 U76.22
N24851338: C346.2 U76.20
N24851340: TP111.1(TP) U76.11
N24851385: C366.1 U76.15
N24851391: C364.1 U76.16
N24851397: C361.1 U76.17
N24851403: C359.1 U76.18
N24851421: TP110.1(TP) U76.9
N24851423: TP114.1(TP) U76.10
N24851452: R25.1 U6.4
N24851454: R25.2 TP11.1(TP)
N24851456: C27.1 J4.5A
N24851458: C26.1 J4.2A
N24851460: C26.2 U6.21
N24851462: C21.2 U6.19
N24851464: C20.2 U6.22
N24851486: C27.2 U6.20
N24851488: TP20.1(TP) U6.11
N24851535: C62.1 U6.15
N24851541: C57.1 U6.16
N24851547: C51.1 U6.17
N24851553: C48.1 U6.18
N24851571: TP19.1(TP) U6.9
N24851573: TP23.1(TP) U6.10
N25521527: TP6.1(TP) U7.18
N25809420: C610.1 J18.SH1 J18.SH2 J18.SH3 J18.SH4 R623.2
N25815350: C611.1 J19.SH1 J19.SH2 J19.SH3 J19.SH4 R624.2
N26271323: R386.2 U129.17
N27107689: C308.1 U73.3
N27107697: R382.2 U73.5
N27107782: R395.2 U73.2
N27116765: R319.2 R320.1 U59.5
N27118410: R240.2 U46.3
N27118414: R255.2 R258.1 U46.4
N27132714: R137.1 SW2.13
N27132716: R136.1 SW2.14
N27132718: R135.1 SW2.15
N27132720: R134.1 SW2.16
N27132816: R131.1 SW1.11
N27132818: R130.1 SW1.12
N27132820: R129.1 SW1.13
N27132822: R128.1 SW1.14
N27132824: R133.1 SW1.9
N27132826: R132.1 SW1.10
N27132828: R127.1 SW1.15
N27132836: R126.1 SW1.16
N27133243: R141.1 SW2.9
N27133247: R140.1 SW2.10
N27133249: R139.1 SW2.11
N27133251: R138.1 SW2.12
N27148451: R125.2 U28.A5
N27161108: D6.3 R398.2 R401.1
N27162147: C640.1 Q8.1 Q8.2 Q8.5 Q8.6 Q8.8(S5) Q9.1 Q9.2 Q9.5 Q9.6 Q9.8(S5) R680.1
N27162183: C317.2 C318.2 C638.2 C639.2 C640.2 Q8.3 Q9.3 R675.2 R676.2 R677.1 R680.2
N27162293: Q10.1 Q10.2 Q10.5 Q10.6 Q10.8 R677.2
N27162479: Q10.3 R669.2 R672.1 R673.2
N27173972: Q1.3 R203.2 R213.2
N27173989: Q5.3 R441.2 R442.2
N27174010: LD10.1(CATHODE) Q5.1 Q5.2 Q5.5 Q5.6 Q5.8
N27174034: LD1.1(CATHODE) Q1.1 Q1.2 Q1.5 Q1.6 Q1.8
N27174097: LD1.2 R180.1
N27174144: LD10.2 R440.1
N27175817: C104.2 R74.2 Y1.1
N27175821: C105.1 R73.2 Y1.3
N27175987: C121.1 C382.1 C383.1 C384.1 C385.1 C386.1 C387.1 R97.1 U15.3 U15.15 U15.16 U15.24(VDD_VCO)
N27176057: TP36.1(TP) U15.7
N27176072: R89.2 U15.22
N27176107: TP39.1(TP) U15.21
N27176638: TP37.1(TP) U15.11
N27176640: TP38.1(TP) U15.20
N27224404: R432.2 R433.2 R435.2 U8.29
N27224468: C337.1 J1.5B
N27224561: L2.2 U8.4
N27224667: C335.1 J1.2B
N27224751: TP27.1(TP) U8.18
N27224753: TP31.1(TP) U8.20
N27224897: C14.1 J1.5A
N27225024: C77.1 C78.1 U8.32
N27225078: C12.1 J1.2A
N27225127: TP26.1(TP) U8.19
N27225129: TP25.1(TP) U8.17
N27225150: R46.2 U8.28
N27226002: R413.1 R414.2 U75.1
N27239473: R591.2 U117.5
N27239479: R590.1 U117.4
N27239774: R5832.2 R5833.1 U125.1 U125.16
N27239926: R635.2 U126.5
N27239932: R636.1 U126.4
N27240077: R613.2 U125.5
N27240083: R614.1 U125.4
N27243596: TP61.1(TP) U51.3
N27243598: TP58.1(TP) U51.6
N27248134: R579.2 U107.2
N27248136: R580.2 U107.3
N27566274: LD2.1(CATHODE) Q2.3
N27566278: LD2.2 R260.1
N27566306: Q2.1 R272.2
N27566380: LD4.2 R292.1
N27566388: LD4.1(CATHODE) Q3.3
N27566452: C613.2 D13.2 SW7.2
N27765807: C3639.1 R3661.2
N27766023: R5805.1 U134.13
N27780868: R3723.2 R3724.1 U135.2
N27781327: R3725.2 U135.4
N27827107: TP594.1(TP) U136.A12
N27866324: LD6.2 R324.1
N27969798: R329.1 U62.1
N27969912: R348.1 U65.2
N27970038: R349.1 U65.3
N27970040: R358.1 U65.5(Y2)
N27970042: R359.1 U65.8
N27972730: R261.1 U136.D2
N27975044: C205.2 R252.1 Y3.1
N27975050: C209.2 R253.1 Y3.3
N27975317: C3657.2 R3733.2 Y8.1
N27975321: C3658.1 R3732.2 Y8.3
N27995683: R5752.2 U140.C3
N28038972: R5213.1 U2.6
N28044811: C1.1 J34.1 R5635.2 R5636.2
N28049053: R69.2 U11.6
N28071414: R5684.1 U2345.10
N28080788: R143.1 U29.4
N28081065: R5686.2 U2347.7
N28082506: TP586.1(TP) U136.B11
N28084397: R530.1 U136.U13
N28084399: R535.1 U136.W13
N28084409: R537.1 U136.T14
N28084411: R529.1 U136.U14
N28084427: R509.1 U136.V16
N28084429: R518.1 U136.W16
N28084431: R527.1 U136.V17
N28084433: R528.1 U136.W18
N28084995: R5687.1 U120.3
N28086994: R5688.1 U68.3
N28088261: R5694.2 U136.A14
N28088302: R5695.2 U136.B13
N28088339: R5696.2 U136.B12
N28088462: R5697.2 R5699.1 U2348.1
N28118724: R5730.2 U48.33
N28118727: R5731.2 U48.34
N28118756: R5732.1 U136.L1
N28122339: R542.2 U136.A11
N28129103: R5736.1 U2356.4 U2356.9
N28133286: R5743.1 U2357.2
N28133288: R5743.2 U2357.3
N28157125: LD13.2 R3933.2
N28224119: R297.2 U56.36
N28224122: R307.2 U56.35
N28224348: R5751.1 U136.B7
N28238385: R166.2 U3077.8
N28248996: R5637.2 TP593.1(TP)
N28268314: R5757.1 U136.C16
N28271262: R115.2 R116.2 U26.1
N28389021: R5766.1 U54.4(Y) U3076.3
N28496978: J12.1 R5775.2
N28497016: J13.1 R5776.2
N28895418: R5790.2 U3084.2
N28895646: R5791.1 U3084.3
N28895649: R5792.1 U3084.8(Y1)
N28896188: R5789.1 U3083.4
N28896306: R5793.2 U3083.7
N28962728: R5806.1 U3086.4(Y) U3087.2
N29136309: R5808.1 U2353.5
N29136335: R5733.1 U2353.4
N29218455: R5734.1 U2353.6
N29295413: R5826.1 U28.C2
N29295438: R5827.1 U28.A3
N29438875: C615.2 R632.1 R634.2 U127.3
N29438936: R5777.2 U127.1
N29440900: R5758.2 R5759.1 R5846.2 SW9.2 U57.9 U57.10
N29522203: R562.1 TP116.1(TP) U49.H5
N29598897: R5837.2 R5842.2 U3091.2
N29649563: R5672.1 U136.G18
N29649575: R5673.1 U136.H16
N29649587: R5674.1 U136.H18
N29649599: R5675.1 U136.H17
N29649611: R5676.1 U136.G19
N29649623: R5677.2 U136.E19
N29649892: R538.1 U136.V1
N29650058: R178.2 U136.N19
N29729537: R3736.1 SW9.1
N271759124: TP32.1(TP) U15.5
N271759125: TP33.1(TP) U15.6
N275664200: Q3.1 R286.2
N284070661: LD14.2 R195.2

Pads without a net: D2 2; D6 2; J12 13 14 48 52 54 56 59 61 63 64 68 70 72 74; J13 5 13 14 38 40 48 52 54 56 59 61 63 64 68 70 72 74; J14 17 18 19; J21 4 6; J22 4; J24 A2 A3 A6 A7 A8 A10 A11 B2 B3 B6 B7 B8 B10 B11; J25 A2 A3 A8 A10 A11 B2 B3 B8 B10 B11; J31 10; U10 4 9; U12 2 3; U15 9 10 13 14 17 18; U18 1 2 5 7 8 13 14 15 16; U21 1 2 3 6 7 8 11 20; U25 5; U28 A2 B1 B5 C5; U41 2 4 5; U48 2 5 6 11 12 13 14 15 18 19 20 21 22 23 24 25 27 29 30 31 32 41 44 45 46 53 54 56 57 65 67 75 83 84 85 86 91 92 102 103 104 105 106 107 108 109 110 111 112 116 117 118 119 120 121 123 124 125 126 127 128; U49 A1 A2 A7 A8 A9 A10 A11 A12 A13 A14 B1 B7 B8 B9 B10 B11 B12 B13 B14 C1 C3 C5 C7 C8 C9 C10 C11 C12 C13 C14 D1 D2 D3 D4 D12 D13 D14 E1 E2 E3 E5 E8 E9 E10 E12 E13 E14 F1 F2 F3 F10 F12 F13 F14 G1 G2 G3 G10 G12 G13 G14 H1 H2 H3 H12 H13 H14 J1 J2 J3 J12 J13 J14 K1 K2 K3 K6 K7 K10 K12 K13 K14 L1 L2 L3 L12 L13 L14 M1 M2 M3 M7 M8 M9 M10 M11 M12 M13 M14 N1 N3 N6 N7 N8 N9 N10 N11 N12 N13 N14 P1 P2 P7 P8 P9 P10 P11 P12 P13 P14; U55 7; U57 15 16 18 19 20 21 25 27 32 34; U59 2 3 6 7; U60 1 4 5; U61 6 7; U64 18 19 21 22 23 24 28 29 30 32 33 34 36 43 44 45 46 48 52 53 54 55 57 58 59; U65 7; U66 5; U67 2; U82 17 18 19 20 21 22 23 24; U92 B2 C2; U93 1; U113 B2 C2; U115 B2 C2; U119 B2 C2; U123 B2 C2; U129 21 22 23 30 31 40 41 42 43 48 50 53 54 55; U136 A3 A18 B3 E2 E4 G3 W8; U140 A2 A5 B5 C2 C5; U2355 1; U2358 1; U3068 11; U3070 1; U3072 3 5 7 10 12 14 16 20 21 22 23 24 25 26 27 28 29 30 31 32 33 34 35 36 55 56; U3076 4; U3077 2 6 9 13; U3080 B2 C2; U3081 B2 C2; U3084 5 7; U3088 1

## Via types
v1: diameter 0.457, hole 0.203, TOP to BOTTOM, 2913 vias

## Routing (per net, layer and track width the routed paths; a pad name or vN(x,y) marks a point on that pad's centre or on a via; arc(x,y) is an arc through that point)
AVDD_3V3_DAC: length 80.7
  TOP w0.254: U5.23 74.42,156.27 ; U6.23 91.82,155.83 91.35,156.3 90.15,156.3
  TOP w0.305: R33.1 80.54,149.28 v1(80.37,149.1) ; R33.1 80.54,150.75 80.04,151.26 80.04,159.31 81.89,161.16 87.49,161.16 v1(88.49,160.17) ; R33.1 79.28,149.93 79.09,150.12 R29.1 ; 90.15,156.3 89.65,156.79 C30.1 88.92,157.51 C31.1 88.69,159.26 FL1.2 ; v1(103.17,159) 99.01,154.84 99.01,151.66 99.24,151.43 R28.2 99.24,149.68 v1(98.8,149.24) 98.49,149.24 R35.2 ; 74.42,156.27 73.15,157.54 C29.1 71.82,157.54 C32.1 v1(71.81,158.44)
  L03_SIG1 w0.381: v1(80.37,149.1) 81.13,149.86 82.02,149.86 83.13,150.98 89.01,150.98 89.53,151.5 91.51,151.5 93.17,149.83 98.21,149.83 v1(98.8,149.24)
  BOTTOM w0.254: v1(88.49,160.17) 88.03,160.17 87.55,159.69 87.55,158.78 87.12,158.34 85.76,158.34 85.27,157.85 85.27,157.12 C350.1 85.08,157.12 84.49,156.52 C352.1 84.2,156.52 84.2,156.07 83.94,155.81 U77.23 ; U76.23 101.34,156.6 101.67,156.93 C351.1 C349.1 102.88,158.71 v1(103.17,159)
  vias: v1(89.28,160.15) v1(89.48,159.45)
DGND: length 1401.3
  TOP w0.081: v1(100.15,70.48) 99.71,70.93 99.71,71.3 U49.N2 100.21,71.3 100.21,70.54 v1(100.15,70.48)
  TOP w0.091: C3774.1 51.04,54.54 U3087.3 ; v1(23.85,34.86) 24.28,35.29 U71.3
  TOP w0.102: 52.48,61.76 52.48,61.75 52.98,61.24 U59.9
  TOP w0.132: U136.W6 v1(72.64,81.26) ; 60.06,76.05 60.35,76.34 v1(60.35,76.68) ; 58.17,76.33 58.89,77.05 58.89,77.66 U136.B2 58.1,78.45 56.84,78.45 55.6,77.22
  TOP w0.147: v1(102.23,164.3) 100.89,165.63 96.9,165.63 94.77,163.5 94.77,161.37 95.49,160.64 C21.1 ; v1(57.27,165.16) 56.23,164.12 56.23,160.59 58.25,158.57 59.2,158.57 59.51,158.88 59.51,159.31 58.28,160.53 C15.1 ; C23.1 78.13,160.71 77.52,161.32 77.52,163.32 79.71,165.51 83.67,165.51 v1(84.6,164.58) ; v1(72.99,164.38) 73.84,163.52 73.84,161.2 73.2,160.56 C22.1 ; v1(50.32,164.36) 49.81,163.86 49.81,159.11 48.95,158.24 46.94,158.24 46.38,158.8 46.38,159.31 44.98,160.71 C13.1 ; v1(40.12,165.16) 38.99,164.03 38.99,160.27 40.69,158.57 42.04,158.57 42.34,158.88 42.34,159.31 41.14,160.51 C11.1 ; C17.1 62.17,160.74 63.44,159.47 63.44,158.81 63.88,158.37 66.1,158.37 66.66,158.92 66.66,163.94 66.95,164.24 v1(67.44,164.24) ; v1(90.38,164.4) 90.89,164.4 91.08,164.21 91.08,161.24 90.66,160.82 C20.1
  TOP w0.152: v1(74.92,44.78) 74.61,45.09 C272.2 ; 67.24,46.66 67.37,46.53 U2353.14 ; 67.24,46.66 v1(67.54,46.96) ; 67.24,46.66 U2353.12 ; U2353.7 67.39,48.45 67.39,48.01 67.24,47.86 ; v1(93.51,73.93) 93.58,73.93 U49.A6 ; 67.24,47.86 67.54,47.57 v1(67.54,46.96) ; 67.24,47.86 U2353.9 ; v1(68.68,45.85) 68.33,45.85 68.17,46 U2353.16 ; v1(67.54,46.96) 67.44,47.06 U2353.11 66.41,47.06 66.16,47.31 66.32,47.46 U2353.10 ; v1(67.54,46.96) 67.84,46.66 U2353.1 ; 58.17,76.33 57.91,76.07 57.15,76.07 55.73,74.65 54.17,74.65 54.09,74.57 R254.1 ; C223.1 17.5,83.26 17.03,82.79 v1(15.56,82.79) 15.2,82.79 14.81,83.18 14.81,85.52 15.37,86.08 17.56,86.08 17.81,85.83 C217.1 ; 60.06,76.05 59.97,75.96 59.97,75.47 59.74,75.23 59.74,74.68 ; v1(13.65,80.96) 13.65,80.76 13.39,80.5 U51.4
  TOP w0.178: v1(54.48,77.22) 55.6,77.22 ; Y3.4 51.26,76.47 51.52,76.22 C205.1 52.1,76.22 52.57,75.74 55.55,75.74 56.77,76.96 57.22,76.96 57.52,77.25 ; U3083.5 97.44,59.21 97.69,59.46 v1(98.05,59.46) ; v1(19.86,104.52) 20.07,104.52 20.27,104.32 20.27,104.06 20.11,103.91 U39.4
  TOP w0.203: U48.80 18.67,87.81 18.59,87.88 v1(18.26,87.88) ; J18.15 76.01,40.17 76.12,40.28 v1(76.2,40.28) 76.41,40.08 J18.17 ; U15.A3 81.91,56.14 v1(82.19,55.85) ; J18.16 76.01,43.1 v1(76.16,43.25) 76.41,43.01 J18.18 ; C203.1 18.14,93.96 v1(18.43,93.67) 18.43,93.63 18.65,93.41 U48.66 ; U49.C4 95.43,73.02 v1(95.43,73.03) ; v1(90.83,57.63) 91.03,57.63 91.36,57.95 U29.5 ; U5.A2 v1(73.02,150.92) ; C3750.1 24.92,53.2 24.3,52.58 R5773.2 22.96,52.58 22.76,52.37 v1(22.76,52.2) ; v1(24,9.98) 23.87,9.98 23.67,10.19 D7.2 ; v1(106.55,41.48) 106.82,41.75 106.82,41.77 106.84,41.79 J19.8 ; J19.18 108.84,41.88 109.04,41.68 v1(109.04,41.31) 108.84,41.31 108.44,41.71 J19.16 ; J19.31 111.64,38.93 v1(111.83,38.74) 112.04,38.94 J19.33 ; U5.A1 73.12,155.12 72.91,155.12 v1(72.9,155.13) ; J13.8 6.06,119.64 5.67,120.04 C168.2 ; D9.1 v1(39.39,10.33) ; J19.17 108.84,39.02 v1(108.59,38.77) 108.44,38.92 J19.15 ; U68.2 59.11,50.37 58.96,50.51 R367.2 58.08,50.51 v1(58.04,50.47) ; U5.A4 76.89,155.32 v1(77.1,155.52) ; J18.24 v1(77.61,41.48) ; v1(2.82,91.88) 3.14,91.56 U40.7 ; U48.10 v1(33.85,85.01) ; v1(80.97,38.16) 81.21,38.39 J18.41 ; J19.24 v1(110.04,41.59) ; U48.48 27.53,96.63 v1(27.48,96.69) ; D8.2 v1(37.86,10.71) ; J18.33 79.61,38.94 v1(79.4,38.74) 79.21,38.93 J18.31 ; v1(28.04,81.15) 28.04,81.13 27.93,81.02 U48.114 ; U49.K8 98.24,74.55 97.96,74.27 v1(97.96,73.8) U49.J5 ; J18.32 79.21,41.72 v1(79.4,41.53) 79.61,41.74 J18.34 ; v1(105.63,38.6) 105.63,39.02 105.64,39.02 J19.1 ; v1(77.22,40.46) 77.22,39.63 J18.21 ; J18.8 74.41,42.69 74.42,42.7 74.42,43.02 v1(74.65,43.25) ; U6.A3 v1(94.73,150.91) ; C55.2 56.19,153.76 56.37,153.94 v1(56.37,153.96) ; U49.P4 101.1,72.55 v1(101.12,72.57) ; v1(97.21,75.11) 97.46,75.36 U49.H10 ; v1(88.42,91.48) 88.03,91.09 U43.2 ; v1(96.6,74.27) 96.38,74.05 U49.E7 ; v1(94.47,155.5) 94.29,155.32 U6.A4 ; v1(97.31,72.54) 96.96,72.89 U49.G5 ; U49.N5 U49.P6 100.9,73.99 v1(101.27,73.99) ; U6.A1 90.66,154.8 90.46,155 v1(90.46,155.18) ; U5.A3 v1(77.33,150.91) ; J18.5 74.01,38.84 v1(74.1,38.75) 73.51,38.75 73.21,39.05 J18.1 ; U136.A1 57.52,77.25 57.3,77.47 v1(57.28,77.47) ; v1(20.55,96.22) 20.93,96.22 21.13,96.01 U48.64 ; U48.55 24.73,96.51 v1(24.87,96.65) ; v1(113.31,40.51) 113.64,40.19 J19.41 ; U54.2 v1(9.35,60.73) ; U6.A2 v1(90.42,150.92) ; J19.34 112.04,41.84 v1(111.77,41.58) 111.64,41.71 J19.32 ; U48.58 23.53,94.33 ; v1(105.78,40.66) 106.14,40.66 106.44,40.37 J19.5 ; U48.17 v1(36.22,87.81) ; J19.21 v1(109.64,38)
  TOP w0.229: v1(117.22,69.38) 117.38,69.23 U2.2
  TOP w0.254: v1(36.39,8.7) J25.A1 v1(36.39,7.18) ; U21.25 89.68,136.48 ; C3659.2 v1(84.73,85.14) ; v1(27.39,8.7) J24.A12 v1(27.39,7.18) ; C68.2 C63.2 47.87,152.5 v1(48.31,152.06) ; v1(73.23,78.82) 72.82,78.82 72.78,78.86 U136.W3 ; v1(19.12,62.67) 18.41,61.96 18.41,61.95 TP106.1 ; v1(52.48,60.1) 52.32,60.1 52.28,60.05 U59.4 ; U64.25 v1(56.21,32.35) ; v1(117.17,111.48) J12.88 v1(117.17,115.46) J12.87 v1(117.17,121.76) J12.86 v1(117.17,127.73) J12.85 v1(117.17,131.54) J12.84 J12.83 v1(117.17,141.78) J12.82 v1(117.17,147.73) J12.81 ; 42.04,150.02 U8.8 42.04,151.27 ; R5822.2 102.45,92.98 102.62,93.14 v1(102.62,93.8) ; v1(45,98.12) 45.51,97.61 U140.B3 ; C89.2 v1(53.07,145.71) ; U27.3 58.89,128.86 58.4,129.36 R5821.1 ; U3068.2 30.74,158 31.25,157.49 ; R5766.2 10.68,63.12 10.41,63.39 C3747.2 10.41,64.16 10.5,64.25 U3076.2 10.5,65.52 v1(10.9,65.91) 11.61,65.91 11.86,66.17 11.86,67.61 11.38,68.1 C3746.1 ; U60.3 8.62,49.19 v1(8.92,48.89) ; v1(48.72,74.9) 48.72,76.75 49.81,77.85 v1(51.94,77.85) ; v1(21.39,8.7) J24.A1 v1(21.39,7.18) ; U7.8 57.71,147.8 v1(57.49,148.02) ; 52.97,25.51 U64.11 ; v1(47.49,11.33) 47.86,11.71 C283.1 48.12,11.39 48.32,11.19 U66.3 ; R289.2 37.27,77.63 37.54,77.9 v1(37.54,78.16) ; U11.2 99.16,146.11 99.1,146.17 C101.2 98.23,146.17 98.04,146.35 v1(97.87,146.35) ; C245.2 49.79,87.14 v1(48.74,88.19) ; R5823.1 114.58,66.42 113.94,65.79 v1(113.94,65.24) ; v1(67.41,67.28) 67.41,66.88 67.64,66.65 C182.1 ; v1(55.3,134.09) 55.05,133.84 U18.9 ; U10.5 v1(117.6,74.66) ; C415.1 32.61,114.71 v1(32.28,115.04) ; U28.C1 59.22,107.99 v1(59.92,108.69) ; U64.13 53.97,25.35 ; U64.10 52.47,25.47 ; C172.2 C168.2 ; C3721.1 69.85,47.88 v1(70.21,48.23) 70.21,48.24 R5733.2 ; U64.51 v1(44.81,34.85) ; U64.15 54.97,27.46 ; U64.1 v1(47.97,27.53) ; C97.1 v1(53.07,143.06) ; U64.5 v1(49.97,25.25) ; U64.47 48.47,38.86 ; U64.35 54.47,38.93 ; J25.A12 v1(42.39,7.18)
  TOP w0.279: R5216.1 82.32,82.52 v1(82.25,82.45) ; C787.2 88.45,82.81 v1(88.27,82.63)
  TOP w0.305: v1(5.05,131.09) 5.3,130.84 J13.36 ; 54.47,38.93 54.45,38.95 C281.1 v1(54.45,40.35) ; C3738.2 v1(36.61,58.17) ; v1(29.59,46.03) v1(29.59,46.94) 29.82,47.17 ; v1(29.59,46.03) v1(30.02,46.03) ; v1(29.59,46.03) 29.82,46.25 ; v1(56.37,153.96) 56.34,153.99 56.34,154.12 56.59,154.46 C49.2 ; J22.5 57.45,6.71 57.9,7.16 58.28,7.16 58.7,7.57 C295.2 v1(58.7,9.51) ; v1(93.9,57) 93.73,57.17 C151.1 ; R229.1 R230.1 ; R230.1 21.19,99.39 v1(21.18,99.39) ; R230.1 R231.1 R232.1 ; D2.1 15.52,56.31 v1(15.72,56.52) ; U15.A1 77.34,59.64 v1(77.16,59.82) ; v1(68.5,87.25) U136.R14 v1(69.3,88.05) ; v1(60.35,76.68) 60.1,76.94 U136.D1 ; v1(70.84,69.44) 71.02,69.62 R560.2 ; v1(44.81,34.85) C263.2 ; C29.2 72.76,158.66 72.64,158.78 v1(72.64,158.83) ; U136.W1 v1(72.5,76.85) ; 4.45,122.66 4.9,122.66 5.08,122.84 J13.16 ; 4.45,122.66 4.65,122.46 4.65,122.41 4.66,122.39 C160.2 C161.2 ; 4.45,122.66 v1(4.42,122.66) ; R5767.2 25.3,32.77 25.12,32.59 24.59,32.59 v1(24.54,32.54) 24.33,32.75 R381.2 ; v1(6.9,48.2) 6.39,48.71 J17.5 ; C609.1 48.49,114.58 v1(49.07,114.58) 49.61,114.58 50.09,114.1 D12.1 ; J14.10 v1(31.99,104) ; C320.1 30.63,12.97 30.43,12.78 v1(30.43,12.34) ; C64.2 46.46,152.11 v1(46.67,152.31) ; U136.K15 v1(64.5,88.85) U136.J15 v1(63.7,88.85) ; 48.47,38.86 v1(48.46,38.86) ; J12.46 v1(121.49,127.58) ; v1(11.28,57.3) 11.42,57.44 R303.2 ; U28.E5 v1(54.23,110.49) ; C165.1 v1(85.37,70.74) ; J13.88 J13.87 v1(10.16,144.89) J13.86 v1(10.16,138.85) J13.85 ; v1(86.89,53.49) 87.01,53.49 87.32,53.8 C3704.1 ; v1(112.39,123.47) 112.39,123.06 112.68,122.78 J12.57 ; R278.1 v1(13.65,80.96) ; C71.2 51.57,151.73 v1(51.64,151.66) 51.81,151.66 52.07,151.41 C74.2 ; J12.76 v1(121.49,115.58) ; C171.2 v1(4.66,119.6) C167.2 C168.2 ; C171.2 C170.2 v1(3.9,119.6) ; C171.2 C172.2 ; v1(41.24,151.87) C65.2 41.76,151.87 41.76,151.55 42.04,151.27 ; R3652.2 13.85,13.02 13.54,13.33 R3727.1 12.17,13.33 v1(12.12,13.39) ; C3728.1 v1(34.34,122.68) 34.34,122.68 TP42.1 ; v1(16.61,81.64) 16.84,81.41 17.36,81.41 C225.1 ; J13.35 v1(11.4,130.84) ; R158.2 v1(70.24,116.51) R157.2 v1(69.01,116.51) R156.2 ; R217.1 v1(36.88,102.29) ; U136.H11 v1(63.7,85.65) U136.J11 ; C288.1 58.92,30.83 58.66,31.08 v1(58.66,31.46) ; v1(32.54,19.98) 32.91,19.98 C312.2 ; v1(92.9,134.67) 92.86,134.72 92.86,134.72 92.68,134.9 C126.1 ; LD6.1 44.56,119.01 v1(44.96,119.41) ; U134.3 8.82,13.25 8.97,13.1 C3627.1 8.97,11.85 v1(9,11.82) ; C175.2 v1(4.65,116.04) ; U136.H3 v1(62.9,78.46) ; Y5.2 16.93,85.03 17.38,85.48 C217.1 18.22,85.48 18.26,85.52 v1(18.44,85.52) ; v1(96.04,151) 96.04,150.98 96.23,150.78 R30.2 ; v1(52.76,147.16) C81.2 51.71,147.16 v1(51.69,147.14) 51.64,147.14 51.38,146.89 C82.2 ; U136.N15 v1(67.7,88.05) U136.N14 ; R159.2 v1(72.78,116.51) R160.2 ; R76.2 74.46,57.64 C104.1 74.03,57.8 v1(73.69,57.45) 73.31,57.08 73.31,54.62 72.66,53.97 69.75,53.97 69.29,54.42 Y1.2 69.29,59.81 68.22,60.88 68.22,63.37 68.76,63.91 v1(71.83,63.91) ; U136.E11 v1(61.3,84.85) ; v1(61.3,84.85) U136.F11 ; v1(61.3,84.85) U136.F10 ; v1(61.3,84.85) U136.E10 ; U2348.3 45.74,111.15 R5760.1 v1(45.71,112.19) ; C489.1 v1(22.64,108.65) 23.03,108.26 23.03,107.07 22.72,106.77 D11.1 ; R403.2 32.58,10.63 v1(32.31,10.9) ; v1(65.3,85.65) U136.K12 v1(64.5,85.65) ; C85.2 48.19,146.09 v1(48.12,146.16) 48.11,146.17 48.11,146.28 47.8,146.58 47.69,146.58 C84.2 ; U136.F15 v1(62.1,88.85) ; C90.2 51.46,145.76 v1(51.45,145.76) ; U136.P14 v1(68.5,88.05) U136.P15 v1(68.5,88.85) ; v1(87.4,94.06) 87.01,93.67 R238.2 ; v1(67.7,81.66) U136.N7 v1(67.7,82.46) ; C249.2 21.69,55.69 v1(21.56,55.82) ; U136.N6 v1(67.7,80.86) U136.P6 ; C3733.2 44.33,127.63 44.25,127.71 v1(44.04,127.71) ; U136.E9 v1(60.5,84.06) ; U136.N13 v1(66.9,86.45) U136.M12 ; R258.2 38.82,76.09 38.51,75.78 v1(37.8,75.78) ; U2351.3 v1(47.94,41.25) ; J12.36 v1(121.46,135.58) ; R154.2 v1(66.45,116.51) R155.2 ; U136.M5 v1(66.9,80.86) ; J12.50 v1(121.49,125.98) ; U136.L9 65.7,83.71 v1(66.07,84.07) 66.07,84.09 U136.L10 v1(65.3,84.85) ; C3774.1 50.87,53.67 v1(50.22,53.03) ; v1(36.39,7.18) 36.39,6.29 J25.B12 ; v1(51.71,42.29) 51.33,41.91 R5799.1 ; v1(76.96,135.61) U2346.3 ; TP44.1 59.97,138.38 59.49,137.9 R94.2 v1(58.39,138.63) ; C323.2 34.94,12.8 v1(34.29,12.14) ; v1(15.39,138.56) 15.11,138.84 J13.45 ; v1(58.44,144.61) 58.44,144.86 58.24,145.06 C92.1 ; v1(69.3,87.25) U136.R13 U136.R12 ; J13.26 v1(5.36,126.84) ; U46.2 39.77,82.61 39.49,82.89 v1(39.39,82.89) 39.65,83.16 C197.2 ; C136.2 71.3,140.82 v1(71.45,140.97) ; v1(41.18,20.89) 41.18,20.72 41.48,20.42 C262.1 42.34,20.66 41.88,21.11 U61.5 ; J13.25 14.81,126.84 v1(15.09,126.57) ; U136.W10 72.66,84.45 72.76,84.35 v1(72.9,84.35) ; R5745.1 42.54,139.76 v1(42.42,139.88) ; v1(53.26,154.53) 53.26,154.46 53.55,154.18 R22.2 ; U136.L14 v1(66.1,87.25) U136.L13 ; 29.82,47.17 29.82,47.14 ; 29.82,47.17 v1(29.82,47.85) v1(29.82,48.7) v1(29.82,50.58) v1(29.82,51.02) v1(29.82,51.45) v1(29.82,51.88) U56.14 v1(29.82,55.93) v1(29.82,56.36) ; 29.82,47.14 29.82,46.25 ; 29.82,47.14 v1(30.02,46.94) v1(30.02,46.03) ; R5806.2 55.7,53.7 56.01,53.39 v1(56.01,53.31) 56.01,52.86 55.7,52.56 U3086.3 ; J12.66 v1(121.49,119.58) ; C236.1 13.94,77.04 v1(14.07,76.91) ; v1(66.5,143.71) 66.5,143.7 R68.1 ; U2356.3 14.72,51 v1(14.71,50.98) ; U15.A2 77.3,56.14 v1(77.07,55.91) ; U136.C3 v1(58.9,78.46) U136.B2 ; U136.D11 v1(60.5,84.85) ; C1.2 v1(25.44,166.31) ; U41.1 35.81,96.83 v1(36,97.01) 35.87,97.14 C190.2 ; C109.2 63.93,136.72 v1(63.93,136.11) ; Q12.3 58.12,118.75 v1(58.27,118.9) ; J12.31 v1(112.67,137.18) ; C76.2 88.33,149.97 88.52,149.78 v1(89.33,149.78) 89.33,150.24 89.48,150.39 C73.2 ; v1(51.33,153.54) 51.33,153.1 51.41,153.03 R26.2 ; U136.G8 v1(62.1,83.26) U136.G9 ; 29.82,62.23 30.08,62.49 34.56,62.49 C228.2 ; 29.82,62.23 v1(29.82,61.89) v1(29.82,61.46) v1(29.82,61.02) v1(29.82,60.59) U56.32 v1(29.82,56.79) v1(29.82,56.36) ; 29.82,62.23 29.56,62.49 25.08,62.49 C227.2 ; v1(72.38,141.14) 72.2,140.96 R112.1 ; v1(56.52,44.48) 56.52,44.42 56.81,44.13 U2352.3 ; Y5.4 v1(15.56,82.79) ; v1(14.86,129.24) J13.31 ; C3732.1 78.36,96.71 v1(78,96.35) ; U136.G13 v1(62.1,86.45) ; U27.3 58.01,127.83 v1(57.81,127.64) ; C100.2 43.36,143.64 v1(43.13,143.86) C95.2 ; v1(24.56,163.35) C107.2 ; U136.N9 v1(66.9,83.26) U136.M8 ; J12.7 v1(116.05,146.78) ; v1(46.1,83.72) 45.98,83.6 C248.2 ; U136.R5 v1(68.5,80.06) ; R203.1 v1(69.68,132.27) 69.68,132.8 69.38,133.1 Q1.4 Q1.7 ; C235.1 v1(12.12,76.83) ; SW7.4 v1(40.54,43.29) ; v1(53.74,9.8) 53.62,9.68 D3.1 ; R3736.2 v1(103.87,85.46) ; U136.D8 v1(59.7,83.26) ; J14.16 v1(28.18,104) ; J13.84 J13.83 J13.82 v1(10.16,118.75) J13.81 v1(10.16,114.53) ; U136.H6 v1(62.9,80.86) ; v1(58.42,47.83) 58.67,47.83 58.9,48.06 58.9,48.52 59.18,48.8 R373.2 ; C31.2 v1(87.08,157.74) ; v1(73.02,150.92) 72.91,150.81 72.08,150.81 C72.2 71.76,150.81 71.34,150.39 C75.2 ; J12.25 v1(116.05,139.58) ; U136.U5 v1(70.9,80.06) U136.U4 ; v1(51.33,146.28) 51.4,146.21 C86.2 ; C289.1 60.05,36.33 v1(60.25,36.53) ; J13.76 v1(5.82,150.84) ; v1(43.28,102.51) 43.47,102.7 C147.2 ; U136.U8 v1(70.1,82.46) ; C306.2 27.22,22.53 v1(27.56,22.88) ; U136.T16 v1(70.1,89.65) ; v1(21.39,7.18) 21.34,7.13 J24.B12 ; 42.04,150.02 v1(42.27,149.8) ; v1(96.94,150.46) 97.05,150.46 97.36,150.77 R27.2 ; SW8.1 89.82,98.42 v1(89.79,98.39) ; U136.L7 v1(65.3,81.66) ; C3705.2 47.64,104.04 47.45,103.86 v1(47.27,103.86) 46.78,103.86 46.4,104.25 R5820.1 ; C50.2 v1(79.18,154.45) C47.2 ; J13.65 v1(14.76,146.84) ; C46.2 89.35,155.62 v1(89.24,155.74) 88.83,155.74 88.64,155.55 C43.2 88.2,156.17 88.2,156.17 C35.2 87.83,156.72 v1(87.58,156.97) ; v1(5.11,139.09) 5.35,138.84 J13.46 ; v1(29.9,76.58) 30.02,76.58 30.27,76.83 30.75,76.83 LD5.1 ; U136.V4 v1(70.9,79.26) ; v1(49.97,25.25) 50.28,24.94 50.28,24.26 50.03,24 C270.2 ; v1(42.25,5.45) 42.44,5.65 J25.B1 ; v1(37.34,82.85) 37.34,82.93 37.24,83.03 C222.2 C221.2 ; C257.2 24.99,49.67 v1(24.99,50.47) ; v1(68.5,84.85) U136.R10 v1(69.3,84.06) U136.T9 ; J13.15 14.37,122.84 v1(14.58,122.63) ; U136.E15 v1(60.5,88.85) ; R553.2 76.84,82.87 v1(76.89,82.83) ; C3769.1 v1(94.46,56.44) ; v1(61.3,89.65) U136.E17 ; U136.V18 v1(71.7,90.46) ; v1(16.71,102.03) 16.91,102.22 C3730.1 ; v1(30.91,56.36) v1(30.25,56.36) v1(29.82,56.36) ; U136.T10 v1(69.3,84.85) ; J12.35 v1(112.86,135.58) ; v1(77.33,150.91) 77.78,150.45 R31.2 ; v1(36.2,54.32) 36.2,53.89 C254.2 36.83,53.89 v1(36.83,54.31) ; C309.2 27.46,21.18 v1(27.58,21.06) ; J12.75 v1(115.76,115.58) ; C495.2 C497.2 72.29,93.29 72.11,93.12 72.11,92.44 v1(72.5,92.06) U136.W19 ; C241.2 16.65,76.42 16.65,76.42 ; C149.1 60.07,108.53 v1(59.92,108.69) ; U136.G4 v1(62.1,79.26) U136.F4 ; C61.2 v1(79.18,152.93) C56.2 ; SW10.4 48.98,128.78 48.74,128.55 v1(48.74,128.12) 48.74,126.72 48.98,126.49 SW10.1 ; v1(29.82,56.36) v1(29.39,56.36) v1(28.73,56.36) ; C3729.1 v1(20.74,101.35) ; R214.1 v1(36.94,99.9) ; v1(112.42,126.16) 112.6,125.98 J12.49 ; 23.53,94.33 v1(23.23,94.03) ; C305.2 v1(32.54,22.88) ; C121.2 84.12,57.89 v1(84.12,58.47) ; C215.1 36.7,85.87 v1(36.98,86.16) ; v1(71.83,63.91) 71.83,63.72 71.83,63.71 Y1.4 ; v1(71.83,63.91) 73.5,63.91 74.04,63.37 v1(74.04,60.8) C105.2 ; U136.U10 v1(70.9,84.85) ; R341.1 v1(111.79,47.64) ; v1(30.15,78.23) 30.2,78.29 C234.2 ; C148.2 v1(54.33,126.91) ; v1(96.72,151.28) 96.72,151.37 96.44,151.66 C67.2 C62.2 v1(96.58,152.93) C57.2 ; v1(27,9.6) 26.86,9.46 C326.2 ; U23.3 72.64,137.89 v1(72.52,138) ; C32.2 v1(69.89,157.55) ; v1(29.41,12.5) 29.41,12.93 29.48,13 C319.1 ; v1(43.71,113.72) 43.47,113.47 C140.2 ; U136.F14 v1(61.3,88.05) U136.E14 ; U14.3 v1(68.79,139.81) ; C87.2 58.39,145.95 58.67,146.23 58.72,146.23 v1(59.03,146.53) ; R63.2 v1(47.99,143.38) ; C232.2 26.83,77.96 v1(26.59,77.72) ; v1(95.37,149.08) 95.18,149.28 R32.2 95.18,150.45 v1(94.73,150.91) ; 29.82,46.25 29.82,46.23 v1(30.02,46.03) ; C3750.1 25.44,53.6 v1(25.58,53.47) ; v1(41.1,152.77) 41.12,152.76 C60.1 ; J12.15 v1(116.05,143.58) ; v1(5.49,125.55) 5.49,125.55 5.79,125.24 J13.22 ; C321.2 26.43,13.11 26.64,12.9 v1(26.64,12.34) ; v1(122.43,65.71) 122.8,65.33 C3745.1 123.27,65.67 122.91,66.03 C3744.2 ; v1(94.28,60.33) 94.23,60.33 94.11,60.45 C150.1 ; U140.E5 v1(49.03,100.11) ; LD9.1 37.07,14.69 36.82,14.94 36.11,14.94 v1(35.92,14.75) ; v1(57.64,142.86) 58.11,143.34 C96.2 ; J13.49 14.28,140.44 14.5,140.67 v1(14.5,140.74) ; v1(102.62,93.8) 102.43,93.99 U26.3 ; C176.2 v1(5.42,116.04) ; v1(86.84,78.54) 86.54,78.24 C3660.2 ; J13.75 v1(14.76,150.84) ; U136.E18 60.9,90.85 v1(60.5,90.45) ; v1(14.81,143.87) 14.58,143.64 J13.57 ; U55.9 18.63,73.58 18.6,73.58 18.31,73.28 U55.6 ; U136.C19 v1(58.9,92.06) ; R313.2 v1(14.46,72.49) ; v1(94.44,59.69) 94.51,59.77 C3768.1 ; U136.R6 v1(68.5,80.86) ; v1(111.07,76.93) 110.87,77.13 U12.4 ; v1(22.76,35.03) 23.02,35.29 C300.1 ; v1(113.94,65.24) C28.2 113.26,65.25 C33.1 113.22,66.54 U4.2 ; U136.T5 v1(70.1,80.06) ; v1(48.72,74.9) 48.94,75.13 Y3.2 ; U136.J7 v1(63.7,82.46) ; v1(45.97,143.21) 46.21,143.44 R61.2 ; U136.G15 v1(62.1,88.05) ; J13.50 5.24,140.44 v1(5.11,140.31) ; C37.2 v1(118.59,65.73) ; 53.97,25.35 v1(54.1,25.22) 54.29,25.03 C280.1 ; C98.2 52.05,143.27 v1(52.28,143.04) ; U2355.3 36.24,117.93 36.2,117.98 36.2,118.41 v1(36.09,118.52) ; J12.22 v1(118.3,141.18) ; v1(91.41,56.08) 91.63,55.87 U2347.4 ; U136.D19 v1(59.7,92.06) ; C52.2 v1(47.7,154.91) ; C2.2 v1(48.36,162.36) ; v1(24.13,23.37) 24.14,23.36 C307.2 ; C301.2 33.13,24.6 v1(33.03,24.7) ; U136.U17 v1(70.9,90.46) ; C70.2 v1(115.9,72) ; U3070.3 55.72,123.07 v1(55.85,122.94) 56.09,122.7 C3740.1 ; v1(106.62,45.66) 106.8,45.48 C273.2 ; R143.2 90.07,60.15 v1(90.27,59.94) ; v1(22.56,16.33) 22.99,16.33 23.38,15.94 LD13.1 ; U69.4 v1(26.87,25.41) ; U136.F16 v1(61.3,88.85) ; SW7.1 35.04,42.91 v1(34.72,43.23) ; C66.2 78.8,151.64 79.1,151.33 v1(79.17,151.33) ; v1(59.36,131.65) 59.46,131.55 R442.1 Q5.4 Q5.7 ; C246.2 v1(36.52,54.63) ; J12.58 v1(121.79,122.78) ; C3731.2 18.16,51.56 v1(18.39,51.79) ; LD3.1 37.03,78.46 37.33,78.16 v1(37.54,78.16) ; J12.65 v1(115.76,119.58) ; v1(23.85,77.84) 23.85,78.03 23.59,78.29 C231.1 ; v1(69.89,156.18) 70.21,156.5 C38.2 ; v1(79.65,46.34) 79.46,46.15 R355.1 ; C53.1 v1(46.69,154.75) ; J24.B1 v1(27.44,5.48) ; C207.2 42.34,77.57 v1(42.47,77.44) ; Q3.2 v1(55.59,49.37) ; U136.D4 U136.D3 v1(59.7,78.46) ; v1(117.6,74.66) 117.6,74.37 117.91,74.07 R202.2 ; U136.K8 v1(64.5,82.46) ; v1(24.6,100.74) 24.59,100.75 R218.2 ; U2357.5 v1(82.85,103.2) ; U136.G6 v1(62.1,80.86) ; C293.2 61.4,49.63 61.5,49.53 v1(61.52,49.53) ; C282.1 v1(56.9,24.48) ; C54.2 v1(41.07,153.77) ; C275.1 49.48,39.63 49.48,39.62 v1(49.45,39.62) ; TP41.1 56.85,130.23 56.41,129.79 v1(56.41,129.23) 56.35,129.29 C3741.1 55.09,129.29 55.03,129.23 D18.1 ; C169.2 v1(34.53,114.48) ; U136.K11 v1(64.5,84.85) ; C3695.1 32.84,155.91 v1(32.66,155.73) ; v1(89.92,158.57) 89.65,158.31 C30.2 ; R37.1 v1(79.05,149.08) ; C483.2 72.03,68.18 v1(72.26,67.94) 72.48,68.16 73.04,68.16 ; C48.2 v1(96.58,154.45) C51.2 ; v1(70.9,84.06) 71.3,84.45 U136.V10 ; J12.26 v1(118.3,139.58) ; U140.C1 v1(46.22,95.93) ; U136.E5 v1(61.3,80.86) ; v1(88.93,135.54) R107.2 89.5,136.29 89.68,136.48 ; v1(79.68,64.59) 79.47,64.38 U3077.7 ; v1(55.07,9.9) U67.4 ; J13.58 v1(5.55,143.64) ; R3651.2 8.2,9.14 7.72,8.66 v1(7.21,8.66) ; R153.2 v1(65.14,116.51) ; U136.T8 v1(69.3,82.46) ; R5800.1 v1(59.51,43.66) ; R85.2 v1(78.21,62.97) ; U28.B3 v1(56.29,106.46) ; v1(21.23,9.61) 21.39,9.45 C327.2 ; v1(45.33,24) C269.2 ; U25.4 39.66,109.46 v1(39.12,108.92) ; v1(105.33,61.37) 105.18,61.52 C3772.1 C3771.1 ; U136.N5 v1(66.9,80.06) ; U3084.4 v1(104.06,51.84) ; C192.2 v1(5.72,82.25) ; U136.R7 v1(69.3,81.66) ; v1(37.34,59.35) 36.83,59.35 C242.2 36.83,58.71 v1(37.34,58.71) ; J13.7 v1(14.61,119.64) ; U136.L15 v1(66.1,88.85) ; C325.2 31.89,12.44 32.17,12.16 33.05,12.16 v1(33.1,12.21) 33.42,12.53 C322.2 ; v1(105.49,146.11) C99.2 ; v1(62.9,85.65) U136.G12 ; U136.M15 v1(66.1,88.05) ; J13.66 v1(5.46,146.84) ; U136.L5 v1(66.1,80.06) ; C324.2 v1(27.96,11.91) ; C69.2 v1(110.84,71.93) ; R145.2 v1(77.6,116.51) R146.2 R147.2 R148.2 R149.2 R150.2 R151.2 v1(85.3,116.51) R152.2 ; v1(19.56,10.36) 19.56,9.83 18.86,9.13 R404.2 ; 31.25,157.49 C3692.1 31.33,156.83 v1(31.19,156.69) ; 54.97,27.46 v1(54.97,27.46) ; v1(47.88,121.05) SW6.1 SW6.4 ; C164.2 v1(75.9,68.28) ; C77.2 48.38,151.35 v1(48.86,151.83) ; C233.2 29.13,78.29 v1(29.51,77.9) 29.31,77.7 C240.2 ; U136.R15 v1(69.3,88.85) ; J14.20 v1(25.64,104) ; C78.2 46.91,150.7 46.87,150.66 46.85,150.66 v1(46.36,150.66) ; U136.D14 v1(59.7,88.05) ; J14.12 v1(30.72,104) ; v1(63.7,87.25) U136.J13 v1(64.5,87.25) ; C223.1 v1(18.34,83.26) ; C292.2 v1(33.91,31.14) ; C264.1 v1(43.5,33.33) ; U136.A19 v1(57.3,92.06) ; C3.2 v1(65.51,162.38) ; C3773.2 v1(51.12,51.26) ; v1(30.05,22.88) 30.54,23.37 C303.2 ; v1(72.9,155.13) C45.2 71.96,155.24 71.65,155.55 C42.2 70.05,155.55 v1(69.8,155.31) ; C102.1 v1(107.51,76.11) ; U136.P5 v1(67.7,80.06) ; R36.1 82.04,148.88 v1(81.89,148.73) ; U2358.4 40,136.79 v1(39.75,137.03) ; SW8.4 v1(98.06,98.42) ; 52.97,25.51 52.88,25.43 v1(52.88,25.3) 52.83,25.25 52.69,25.25 52.47,25.47 ; U15.A4 81.76,59.64 v1(81.86,59.74) ; C174.2 v1(3.89,116.04) ; U136.E12 v1(60.5,85.65)
  TOP w0.381: C3701.2 v1(99.65,115.59) ; v1(112.52,127.33) 112.77,127.58 J12.45 ; SW5.4 20.61,113.24 v1(19.98,112.61) 19.98,111.38 SW5.1 18.39,110.75 17.46,109.81 Q7.3 ; J13.88 v1(10.16,155.02) ; v1(94.44,104.67) 94.99,104.12 C3698.2 ; v1(99.14,121.44) 99.65,120.92 C3702.2
  L02_GND1 w0.381: 40.46,4.93 40.54,4.85 40.54,4.39 v1(40.51,4.37) ; v1(27.39,8.7) v1(27.39,7.18) 27.39,6 27.44,5.95 v1(27.44,5.48) 27.44,5.1 v1(27.14,4.79) ; v1(42.39,8.7) v1(42.39,7.18) 42.39,6.07 42.25,5.92 v1(42.25,5.45) ; v1(21.65,4.79) 21.65,5.26 21.39,5.52 v1(21.39,7.18) v1(21.39,8.7) ; v1(36.39,7.18) v1(36.39,8.7)
  L03_SIG1 w0.102: v1(24.13,56.67) 24.13,57.07 26.85,59.79 31.22,59.79 31.6,60.17 37.67,60.17 38.07,59.77 40.38,59.77 40.49,59.87 40.94,59.87 v1(41.71,59.11)
  L04_PWR1 w0.102: v1(61.3,80.86) 60.51,80.86 60.11,80.46 56.33,80.46 55.46,79.59 55.46,77.1 52.17,73.81 49.68,73.81 44.17,68.3 44.17,63.86 42.52,62.2 42.52,59.66 41.97,59.11 v1(41.71,59.11)
  BOTTOM w0.091: v1(32.28,115.04) 32.28,114.99 32.25,114.95 U87.3 ; U88.3 v1(37.1,113.63)
  BOTTOM w0.147: v1(92.37,167.06) 93.06,167.74 95.91,167.74 97.94,165.71 97.94,160.81 97.65,160.52 C342.1 ; v1(100.1,167.76) 99.67,167.34 99.67,164.49 101.9,162.26 101.9,161.32 102.54,160.68 C341.1 ; C343.1 85.24,160.74 84.53,161.44 84.53,162.91 83.41,164.02 83.41,166.36 v1(83.99,166.93) ; v1(66.84,166.94) 66.84,165.33 65.29,163.78 64.47,163.78 63.98,164.26 63.98,165.07 62.65,166.41 C332.1 ; C334.1 58.81,166.38 60.07,165.13 60.07,164.74 59.68,164.35 59.09,164.35 58.14,165.3 58.14,167.61 58.7,168.18 v1(58.7,168.61) ; C338.1 41.67,166.31 42.91,165.06 42.91,164.73 42.74,164.55 42.15,164.55 41.1,165.61 41.1,167.7 v1(41.54,168.14) ; v1(75.03,167.14) 75.58,167.69 78.47,167.69 80.7,165.47 80.7,161.26 80.26,160.83 C344.1 ; C336.1 45.51,166.41 46.84,165.07 46.84,164.26 47.32,163.78 47.88,163.78 49.43,165.33 49.43,166.49 v1(49.69,166.76)
  BOTTOM w0.152: 52.34,74.51 59.27,74.51 60.01,75.25 60.62,75.25 60.89,75.51 60.89,76.2 60.75,76.34 ; v1(59.15,75.59) 58.85,75.29 51.94,75.29 51.82,75.41 51.56,75.41
  BOTTOM w0.178: U3079.1 35.02,71.83 34.25,72.61 U3081.C3
  BOTTOM w0.197: U3091.3 U3091.6
  BOTTOM w0.203: C514.2 95.31,72.92 v1(95.43,73.03) ; v1(103.96,45.75) 103.95,45.75 103.86,45.84 R607.2 ; v1(62.1,80.86) 62.35,81.11 C3751.2 ; v1(26.31,88.09) 25.99,87.76 C500.1 ; U117.11 39.64,32.57 v1(39.84,32.77) 39.64,32.97 U117.10 ; U119.C1 40.66,43.17 v1(40.54,43.29) ; v1(80.11,57.18) 80.42,57.49 C387.2 ; v1(68.5,84.85) 68.5,84.82 C3649.2 ; C504.2 96.28,76.04 v1(96.32,76.08) ; U81.12 87.08,124.95 v1(87.07,124.93) ; 46.75,77.14 49.72,77.14 50.24,76.62 C213.1 50.34,76.62 50.78,77.06 51.36,77.06 52.11,76.31 58.36,76.31 59.7,77.65 v1(59.7,78.46) v1(58.9,78.46) ; C663.2 65.6,85.15 v1(65.3,84.85) 65.34,84.81 C658.2 ; v1(104.76,156.43) 104.95,156.24 104.95,155.55 ; C529.1 v1(4.49,78.07) ; v1(36.6,103.94) 36.6,104.62 36.36,104.86 C3726.1 ; C515.1 23.88,85.34 v1(23.88,84.84) ; v1(58.76,28.35) 59.16,28.75 59.54,28.75 59.62,28.67 U126.12 ; C369.2 96.96,151.59 96.73,151.37 96.73,151.29 v1(96.72,151.28) ; J26.SH2 124.95,82.2 v1(125.35,82.6) ; C382.2 78.4,58.39 78.46,58.45 v1(78.84,58.45) ; v1(81.86,59.74) 81.48,59.74 81.33,59.59 C385.2 ; C3718.2 48.14,42.1 47.94,41.9 v1(47.94,41.25) ; U77.A1 84.91,155.08 85.21,155.37 85.5,155.37 85.73,155.6 C354.2 v1(86.4,156.04) ; U76.A1 102.63,154.8 v1(102.85,155.02) ; v1(34.72,43.23) 34.72,42.7 35.09,42.33 C613.1 35.54,41.69 35.66,41.81 D13.1 36.09,42.28 v1(36.35,42.55) ; U3081.C1 34.25,73.84 33.52,74.57 U3079.7 33.52,77.24 33.14,77.63 C3764.2 ; C3703.2 77.33,135.9 77.04,135.61 v1(76.96,135.61) ; C516.1 20.76,85.55 20.93,85.72 v1(20.95,85.72) 21.34,85.72 21.89,85.17 ; U126.1 62.07,28.67 62.33,28.93 v1(62.33,29.31) ; C521.2 93.98,70.51 v1(93.96,70.49) 94.18,70.26 C527.2 ; U123.C1 30.22,37.16 29.92,37.47 v1(29.72,37.47) ; v1(19.12,62.67) 19.12,62.56 19.51,62.17 19.52,62.17 19.52,62.16 U113.C1 ; v1(32.54,19.98) 32.74,19.78 U129.51 ; v1(88.59,124.93) 88.58,124.95 U81.13 ; R632.2 81.36,34.63 C614.2 ; C505.2 67.51,81.85 v1(67.7,81.66) ; C644.2 33.42,12.53 v1(33.1,12.21) 32.37,12.21 31.9,12.69 C642.2 ; C358.2 87.05,155.13 87.47,155.55 87.55,155.55 87.55,156.1 v1(87.4,156.26) ; v1(54.97,27.46) 54.97,27.73 C612.1 ; C224.2 61.39,80.95 v1(61.3,80.86) 61.17,80.98 C509.2 60.4,80.98 C3653.2 ; v1(30.05,41.8) C604.2 30.05,40.58 30.31,40.33 U124.7 ; v1(17.58,90.75) 17.96,90.75 18.04,90.68 R556.2 ; 21.89,85.17 22.09,85.17 22.23,85.03 22.23,84.84 22.29,84.77 U109.6 ; 21.89,85.17 U109.5 ; U115.C3 39.81,51.78 40.45,51.15 v1(40.45,50.56) 40.01,50.12 U116.1 ; C660.2 64.63,82.32 v1(64.5,82.46) ; C508.2 62,79.35 v1(62.1,79.26) ; U129.20 27.36,19.78 v1(27.56,19.98) ; v1(62.33,29.31) 61.82,29.82 61.52,29.82 61.35,29.65 U126.16 ; v1(62.33,29.31) 62.67,29.31 C618.1 ; C448.2 62.29,87.86 v1(62.1,88.05) ; 37.32,52.95 37.32,52.83 37.31,52.83 37.31,52.33 37.86,51.78 U115.C1 ; 37.32,52.95 37.57,52.7 38.24,52.7 38.51,52.97 U116.7 38.51,54.75 38.25,55 C560.2 ; 37.32,52.95 v1(37.32,53.31) ; v1(34.52,51.18) 34.52,51.75 34.89,52.12 C555.2 ; v1(79.17,151.33) 79.32,151.33 79.56,151.57 C370.2 ; v1(105.87,150.39) C373.2 103.86,150.39 103.67,150.58 C371.2 102.85,150.81 U76.A2 ; C421.1 87.77,91.48 v1(88.42,91.48) ; J26.6 121.57,78.13 v1(121.51,78.08) ; C429.2 66.73,80.22 v1(66.9,80.06) ; v1(33.15,10.9) 32.83,10.58 C651.2 ; C653.2 42.34,7.12 v1(42.39,7.18) ; R609.1 50.24,25.51 49.98,25.25 v1(49.97,25.25) ; C361.2 v1(96.58,154.45) C359.2 ; C443.2 68.22,82.46 v1(67.7,82.46) ; 26.88,56.36 v1(27.89,56.36) ; v1(41.24,154.63) 41.67,154.2 42.71,154.2 ; v1(25.27,52.88) 25.65,52.88 25.71,52.94 C572.2 26.06,53.47 v1(25.58,53.47) ; C466.2 64.61,84.74 v1(64.5,84.85) 64.45,84.81 C485.2 ; C469.1 24.53,90.55 v1(24.64,90.45) ; v1(35.12,33.93) 35.24,34.06 35.79,34.06 36.04,33.81 C574.1 ; v1(61.3,88.05) 61.41,87.95 C434.2 ; v1(62.83,25.15) R635.1 ; R415.1 50.57,162.02 v1(50.88,162.33) 51.53,162.99 C340.2 ; v1(60.46,26.17) 60.55,26.25 U126.7 ; U125.9 52.92,31.29 v1(52.6,31.6) ; C216.1 50.86,73.02 52.34,74.51 ; U2349.8 U2349.3 v1(119.15,59.99) ; v1(35.96,10.3) 35.87,10.2 U132.1 ; U125.14 53.93,30.24 v1(53.68,30) ; v1(62.9,85.65) 63.04,85.51 C462.2 63.56,85.51 v1(63.7,85.65) ; C366.2 v1(96.58,152.93) C364.2 ; v1(49.76,88.44) 50.14,88.44 50.39,88.19 R564.2 ; U125.11 53.72,31.43 v1(53.52,31.63) 53.32,31.43 U125.10 ; C599.1 45.46,27.78 v1(45.34,27.66) ; v1(62.9,80.86) 63.03,80.72 C437.2 ; v1(70.1,80.06) v1(70.9,80.06) ; C650.2 42.31,8.61 v1(42.39,8.7) ; R606.2 104.08,47.69 103.93,47.55 U120.2 ; U114.7 19.58,65.19 19.32,65.44 19.32,65.98 C525.2 19.32,66.67 v1(19.15,66.84) ; v1(86.51,43.3) C610.2 v1(85.24,44.38) ; v1(66.9,83.26) 67.03,83.38 C493.2 ; v1(102.28,44.16) 103.17,43.28 C611.2 v1(103.56,44.24) ; C484.2 60.59,83.96 v1(60.5,84.06) ; v1(55.46,148.02) 55.55,147.93 C378.2 ; v1(67.7,88.05) 67.58,87.93 C662.2 ; C607.1 52.95,24.99 52.88,25.06 v1(52.88,25.3) ; C602.2 v1(101.96,46.28) ; C561.2 32.39,55.72 v1(31.75,56.36) ; C3725.1 24.61,84.99 v1(24.43,85.17) 24.43,85.57 R569.1 ; v1(29.03,10.19) 29.06,10.15 U133.2 ; v1(47.97,27.53) 48.23,27.79 C606.1 ; C617.1 63.27,27.03 63.45,26.85 v1(63.98,26.85) ; v1(29.03,10.77) 29.07,10.8 U133.1 ; U75.3 v1(57.6,160.11) ; C329.2 v1(62.2,167.97) ; v1(86.78,127.49) 86.11,126.82 U81.11 ; v1(79.68,150.85) 79.7,150.83 79.7,150.3 ; v1(34.44,109.14) 34.48,109.18 C3727.1 ; v1(86.49,38.49) 86.49,39.04 R623.1 ; U113.B3 U113.C3 21,62.16 v1(21.08,62.08) ; U3078.1 49.02,64.01 49.07,64.06 ; v1(63.7,87.25) 63.82,87.13 C657.2 ; v1(35.96,11.46) 35.93,11.5 U132.3 ; v1(51.92,27.66) 52.27,27.66 52.48,27.86 C608.1 ; R562.2 96.99,74.69 96.6,74.3 v1(96.6,74.27) ; U97.10 22.83,93.83 23.04,94.03 v1(23.23,94.03) U97.11 ; v1(30.43,12.34) 30.68,12.59 R681.2 ; C386.2 80.31,58.25 v1(80.11,58.45) ; v1(45.03,167.92) 45.06,167.94 C330.2 ; v1(78.86,124.5) 78.86,124.63 78.56,124.93 U82.25 78.56,126.19 78.15,126.6 R456.2 78.15,127.18 v1(77.73,127.59) ; U126.9 59.59,27.47 59.46,27.34 59.46,27.07 v1(59.57,26.95) ; v1(64.5,82.46) 64.3,82.66 C501.2 ; v1(64.5,82.46) 64.64,82.6 C3758.2 ; C3767.2 66.25,84.26 v1(66.07,84.07) 65.93,84.07 C3752.2 ; C349.2 v1(104.55,157.9) ; v1(56.52,44.48) 56.52,44.42 ; v1(66.1,87.25) 66,87.15 C494.2 ; v1(18.66,96.26) R531.1 18.35,95.73 18.17,95.91 U93.3 ; v1(89.5,119.73) 89.14,119.37 C408.2 ; U90.6 34.1,108.06 33.55,108.6 33.27,108.6 33.12,108.46 v1(33.12,108) 33.5,108 33.7,107.8 U90.5 ; U76.A4 98.86,155.22 v1(98.72,155.36) ; R622.1 112.51,39.15 112.24,39.15 v1(111.83,38.74) ; C470.1 21.71,90.2 v1(21.62,90.2) 21.56,90.14 21.46,90.14 21.37,90.06 21.15,90.06 R555.1 ; v1(70.48,120.77) 70.47,120.76 U83.13 ; C416.1 37.49,110.56 37.68,110.37 v1(38.08,110.37) ; v1(97.31,72.54) 97.18,72.41 C520.2 ; U76.A3 98.86,150.85 98.66,150.65 98.46,150.65 98.17,150.35 R430.2 97.28,150.13 v1(96.94,150.46) ; C453.2 63.78,88.77 v1(63.7,88.85) ; U126.10 59.5,27.87 v1(59.31,28.06) 59.31,28.07 59.51,28.27 U126.11 ; v1(101.12,72.57) 101.17,72.52 101.71,72.52 C518.2 ; D14.1 93.65,94.47 C622.1 v1(94.23,94.46) ; U132.2 35.93,10.85 v1(35.96,10.88) ; v1(42.67,81.53) 42.89,81.75 C3644.1 ; U125.12 54.12,31.84 v1(53.47,32.49) ; v1(24.07,5.35) 24.32,5.1 D17.2 ; U125.7 51.67,30.24 51.51,30.4 v1(51.46,30.4) ; v1(55.3,136.12) 54.88,136.53 C122.1 ; D16.2 42.09,5.29 v1(42.25,5.45) ; v1(78.94,128.44) 78.94,128.22 79,128.16 C391.1 ; C3655.2 69.3,84.42 v1(69.3,84.06) ; R610.1 v1(7.01,57.98) ; U127.4 82.76,32.04 v1(83,32.28) ; U114.1 21.08,58.88 20.87,58.67 v1(20.83,58.67) 20.78,58.67 20.58,58.88 U114.2 ; U77.A4 81.46,155.18 v1(81.3,155.34) ; C394.1 72.53,127.19 v1(72.8,127.46) ; C3645.2 69.35,84.85 v1(69.3,84.85) 69.45,85.01 C446.2 ; C447.2 62.25,86.3 v1(62.1,86.45) ; R422.1 v1(107.33,151.44) ; C605.1 v1(7.01,55.74) ; C3762.2 45.59,69.4 45.7,69.29 v1(47.19,69.29) 47.19,68.91 47.52,68.59 U3078.7 47.52,66.38 48.22,65.68 U3080.C1 ; R624.1 102.43,38.47 v1(102.16,38.21) ; C460.2 65.32,85.65 v1(65.3,85.65) ; v1(81.33,150.8) 81.46,150.93 U77.A3 ; C461.2 64.82,88.85 v1(64.5,88.85) ; v1(13.91,64.03) 14.07,64.19 U86.2 ; U90.3 34.1,105.14 34.05,105.09 v1(34.05,105.07) ; v1(9.35,60.73) 9.58,60.73 C538.2 ; 71.31,146.05 v1(71.31,145.51) ; v1(60.5,85.65) 60.62,85.78 C440.2 ; U135.3 42.99,79.59 v1(42.8,79.78) 42.8,79.31 42.65,79.15 R3724.2 ; R682.2 v1(29.41,12.5) ; C441.2 63.52,82.63 v1(63.7,82.46) 63.65,82.41 C3647.2 ; v1(46.63,52.54) 46.62,52.55 C427.2 46.62,53.69 46.36,53.95 U91.7 ; v1(58.1,94.23) 57.7,93.83 R504.2 57.26,94.33 56.62,94.96 R5709.2 ; J26.SH4 v1(111.8,80.88) ; C490.2 66.18,88.13 v1(66.1,88.05) ; U83.12 71.97,120.76 v1(71.98,120.77) 71.98,120.63 72.34,120.27 U83.11 ; v1(54.23,110.49) 54.26,110.53 C388.2 ; C353.2 103.47,156.04 v1(103.7,155.81) 103.8,155.71 C357.2 ; v1(97.23,76.05) 97.73,76.55 C498.2 ; C432.2 62.1,88.7 v1(62.1,88.85) ; C368.2 46.53,152.45 v1(46.67,152.31) ; R545.2 49.85,83.29 50.06,83.08 50.6,83.08 50.83,82.85 v1(51.38,82.85) ; v1(38.58,68.5) 38.82,68.74 Q2.2 ; C395.2 70.69,127.12 70.58,127.24 70.58,127.29 v1(70.31,127.56) ; C350.2 v1(86.84,157.12) ; 49.07,64.06 48.63,64.06 48.22,64.47 U3080.C3 ; 49.07,64.06 v1(49.1,64.06) ; U92.C1 46.52,57.03 46.77,56.78 47.27,56.78 v1(47.3,56.81) ; U110.10 26.37,83.77 v1(26.34,83.74) 26.71,83.37 U110.11 ; R618.1 v1(118.33,40.43) ; 36.64,109.16 v1(36.68,109.12) ; v1(36.68,109.12) R489.1 ; v1(36.68,109.12) R490.1 ; C362.2 v1(79.18,154.45) C360.2 ; v1(22.16,82.24) 22.29,82.37 U109.3 ; R662.2 34.5,24.58 v1(34.82,24.91) ; C455.1 v1(16.92,92.02) ; v1(26.64,12.34) 26.67,12.37 26.75,12.37 27.79,13.41 C643.2 27.79,14.18 C641.2 ; U117.16 37.65,31.41 37.4,31.16 v1(36.98,31.16) 36.53,31.16 36.35,31.34 C575.1 36.65,31.72 37.09,32.17 U117.1 ; v1(40.89,48.02) 40.88,48.01 C598.2 40.88,46.48 41.14,46.22 U118.7 ; C390.2 54.25,107.96 v1(54.05,108.15) ; U98.4 40.68,73.42 v1(40.36,73.74) ; U102.4 22.61,88.95 22.49,89.07 v1(22.43,89.07) ; C511.1 v1(24.07,87.04) ; v1(87.43,149.74) C374.2 86.99,150.45 86.63,150.81 C372.2 85.97,150.81 85.43,151.35 U77.A2 ; v1(37.02,36.08) 37.21,35.89 R591.1 ; v1(24.59,82.14) 24.69,82.24 C3724.1 ; v1(83.69,157.12) 83.79,157.12 83.84,157.08 C352.2 ; C367.2 v1(79.18,152.93) C365.2 ; U133.3 29.13,9.5 v1(29.03,9.6) ; C631.2 v1(36.17,20.56) ; U107.4 9.42,77.18 v1(9.24,77.36) ; C3759.2 61.3,85 v1(61.3,84.85) 61.42,84.85 61.7,84.58 61.7,84.41 C502.2 ; v1(77.16,59.82) 77.51,59.47 C384.2 ; C3708.2 49.23,100.31 v1(49.03,100.11) ; C351.2 v1(104.12,156.93) ; R613.1 50.45,29 v1(50.17,29.28) ; v1(35.13,69.87) 35.13,70.02 35.02,70.13 U3079.1 ; Q10.7 Q10.4 ; C146.2 102.66,94.09 102.62,94.05 v1(102.62,93.8) ; C473.1 v1(4.44,69.25) ; 59.13,145.61 59.13,146.43 v1(59.03,146.53) ; J26.SH3 v1(110.64,73.82) ; C468.2 64.68,85.84 v1(64.5,85.65) ; 125.86,66.98 125.86,67.88 J26.SH1 ; U126.14 v1(60.55,30.75)
  BOTTOM w0.254: v1(45,98.12) 45.16,97.96 R5754.1 ; C3716.2 63.12,61.6 62.4,60.88 62.23,60.88 62.22,60.88 C3717.2 ; v1(27.14,4.79) 26.93,4.59 C654.2 ; C3713.2 65.61,61.6 64.88,60.88 C3712.2 ; v1(62.1,83.26) 62.29,83.45 C659.2 ; v1(62.1,83.26) 61.89,83.05 C512.2 ; v1(62.1,83.26) 62.3,83.06 C449.1 ; v1(100.03,104.85) 100.25,104.62 U3072.8 ; C3661.2 67.51,81.05 v1(67.7,80.86) 67.88,81.04 C445.2 ; C451.2 62.24,79.4 v1(62.1,79.26) ; R5728.2 64,71.6 64.26,71.35 v1(64.54,71.35) ; C393.1 81.56,128.57 v1(82.3,129.3) ; v1(86.84,157.12) 86.84,156.49 v1(86.4,156.04) ; v1(100.41,112.19) 100.25,112.04 U3072.49 ; v1(24.08,81.1) 24.08,81.18 23.72,81.54 C528.1 ; C188.1 v1(78.49,77.9) ; R5829.1 23.28,54.79 22.73,55.33 22.73,57.02 23.22,57.51 23.7,57.51 24.13,57.07 v1(24.13,56.67) ; v1(66.1,80.06) 65.94,80.21 C506.2 65.64,80 C3656.2 ; C383.2 78.39,57.63 v1(78.84,57.18) ; v1(94.44,104.67) 94.44,104.67 94.75,104.36 U3072.19 ; C478.1 v1(37.8,75.78) ; C517.2 62.26,80.86 v1(62.1,80.86) ; R5681.2 v1(103.75,100.51) ; C290.2 62.54,56.38 v1(62.51,56.41) 62.33,56.23 C286.1 C284.1 ; C467.2 67.07,86.28 v1(66.9,86.45) 66.76,86.31 C463.2 ; v1(56.52,44.48) 56.55,44.44 C3719.2 ; U3072.38 94.75,111.86 95.02,112.12 v1(95.02,112.32) ; R561.2 97.29,71.17 97.18,71.27 C520.2 ; v1(107.63,156.37) 107.68,156.33 R418.1 ; U2350.8 U2350.3 119.08,51.79 v1(119.25,51.61) ; R451.2 56.67,106.46 v1(56.29,106.46) ; C389.2 59.36,108.87 59.37,108.88 59.73,108.88 v1(59.92,108.69) ; C454.2 65.37,81.58 v1(65.3,81.66) 65.24,81.6 C3652.2 ; C655.2 21.86,4.59 v1(21.65,4.79) ; v1(68.5,87.25) C465.2 ; 125.86,66.98 125.86,66.57 v1(125.7,66.42) ; C3779.1 54.08,68.99 v1(54.23,68.83)
  BOTTOM w0.305: R320.2 53.7,60.3 v1(53.49,60.1) ; C649.2 36.41,8.72 v1(36.39,8.7) ; v1(58.07,20.07) 58.39,20.39 U3088.3 ; C3714.2 56.62,60.52 56.93,60.83 57.58,60.83 57.7,60.95 ; R628.1 116.17,35.95 v1(116.41,35.71) ; v1(18.26,87.88) 18.69,87.88 18.81,87.76 C488.2 ; C409.1 v1(87.64,118.5) ; C652.2 36.77,7.56 v1(36.39,7.18) ; v1(15.11,65.81) 14.81,66.12 C414.1 ; v1(67.7,82.46) 67.86,82.29 C477.2 ; C3775.1 58.77,24.96 v1(58.7,25.02) ; R626.1 v1(109.08,33.91) ; C208.2 32.21,91.72 v1(32.07,91.58) ; v1(67.91,57.16) C265.2 C266.1 ; R639.1 v1(77.13,32.95) ; 57.7,60.95 57.82,60.83 58.06,60.83 58.3,60.6 C3715.2 ; 57.7,60.95 C3710.2 58.26,61.74 58.45,61.93 58.45,62.35 58.86,62.76 59.98,62.76 60.08,62.66 C3711.2 61.18,62.66 61.64,63.12 62.11,63.12 62.57,62.66 C3716.2 63.68,62.66 64.14,63.12 64.6,63.12 65.06,62.66 C3713.2 ; v1(101.27,73.99) 100.92,74.34 C503.2 ; C3720.1 68.48,46.46 68.68,46.25 v1(68.68,45.85) ; U65.4 53.25,55.57 v1(52.98,55.83) ; C3706.1 45.08,98.2 v1(45,98.12) 44.93,98.2 C3709.2 ; U62.2 69.91,51.96 v1(70.1,51.77) ; v1(68.5,84.85) 68.6,84.85 C471.2 ; v1(46.22,95.93) 46.22,95.95 C3707.2 ; C3764.2 30.75,77.63 v1(30.15,78.23) ; R606.2 v1(104.55,47.16) ; v1(25.6,96.49) 25.6,96.06 25.57,96.03 C430.1 ; R642.1 v1(87.86,32.21) ; v1(82.19,33.74) 82.58,33.35 C616.2
  BOTTOM w0.381: R5830.2 57.43,50.47 v1(58.04,50.47) ; C3714.2 56.57,60.1 56.36,59.89 v1(56.36,59.54) ; v1(94.96,121.46) 95.37,121.05 U2345.11
  vias: v1(3.58,19.41) v1(4.09,19.41) v1(4.6,19.41) v1(5.36,18.57) v1(5.87,18.57) v1(7.04,19.23) v1(7.04,18.72) v1(7.54,54.14) v1(7.53,49.3) v1(7.54,19.23) v1(7.54,18.72) v1(7.85,51.31) v1(8.17,54.14) v1(9.78,103.3) v1(11.4,20.19) v1(11.4,19.68) v1(11.91,20.19) v1(11.91,19.68) v1(12.42,20.19) v1(12.42,19.68) v1(16.2,76.98) v1(16.19,76.39) v1(17.29,21.37) v1(17.61,74.46) v1(17.61,73.44) v1(17.73,21.83) v1(18.42,21.62) v1(18.87,21.48) v1(19.24,11.96) v1(19.53,21.46) v1(19.64,74.46) v1(19.64,73.44) v1(19.95,11.96) v1(19.95,11.25) v1(20.42,21.46) v1(20.66,11.96) v1(20.66,11.25) v1(20.66,10.54) v1(20.95,81.31) v1(21.1,23.99) v1(21.11,23.52) v1(21.1,23.06) v1(21.31,83.44) v1(21.37,11.96) v1(21.37,11.25) v1(21.37,10.54) v1(21.56,23.97) v1(21.58,23.51) v1(21.58,23.05) v1(22.64,75.18) v1(22.65,75.66) v1(23.21,61.54) v1(23.2,60.9) v1(24.1,61.54) v1(24.1,60.88) v1(24.08,58.5) v1(24.99,61.54) v1(24.99,60.88) v1(24.96,50.98) v1(25.62,50.98) v1(25.88,61.54) v1(25.88,60.88) v1(26.43,161.16) v1(26.69,161.56) v1(26.91,161.16) v1(27.56,21.91) v1(28.81,22.88) v1(28.81,21.91) v1(28.81,20.95) v1(28.81,19.98) v1(29.39,56.79) v1(29.39,55.93) v1(30.05,21.91) v1(30.05,20.95) v1(30.05,19.98) v1(30.25,56.79) v1(30.25,55.93) v1(31.11,113.33) v1(31.3,22.88) v1(31.3,21.91) v1(31.3,20.95) v1(31.3,19.98) v1(31.8,156.44) v1(32.5,161.99) v1(32.54,21.91) v1(32.54,20.95) v1(33.04,161.97) v1(33.83,61.69) v1(33.83,61.19) v1(33.81,51.08) v1(34.52,50.47) v1(34.72,61.69) v1(34.72,61.19) v1(35.49,51.18) v1(35.49,50.47) v1(35.61,61.64) v1(35.61,61.17) v1(36.49,61.69) v1(36.49,61.19) v1(36.46,51.18) v1(36.46,50.47) v1(36.78,50.83) v1(37.63,19.05) v1(37.63,17.55) v1(38.28,14.88) v1(38.35,4.47) v1(38.49,19.05) v1(38.49,18.18) v1(38.49,17.55) v1(38.73,80.8) v1(38.73,80.34) v1(39.73,69.62) v1(39.73,69.14) v1(39.75,70.08) v1(40.23,92.6) v1(40.23,91.97) v1(40.34,14.02) v1(40.58,93.24) v1(40.69,99.62) v1(40.69,99.06) v1(41.15,99.62) v1(41.15,99.06) v1(41.19,93.24) v1(41.61,99.62) v1(41.61,99.06) v1(42.24,80.8) v1(42.24,79.78) v1(42.27,148.78) v1(42.27,147.76) v1(42.27,146.75) v1(42.8,80.8) v1(43.28,149.8) v1(43.28,148.78) v1(43.28,147.76) v1(43.28,146.75) v1(44.3,149.8) v1(44.3,148.78) v1(44.3,147.76) v1(44.3,146.75) v1(44.74,9.79) v1(45.23,9.99) v1(45.23,9.48) v1(45.32,149.8) v1(45.32,148.78) v1(45.32,147.76) v1(45.32,146.75) v1(45.86,9.99) v1(45.86,9.48) v1(46.5,9.48) v1(48.34,9.63) v1(49.58,9.61) v1(49.86,69.52) v1(50.72,66.88) v1(51.12,9.81) v1(51.31,12.4) v1(51.31,11.76) v1(52.52,61.76) v1(52.48,60.99) v1(52.5,9.78) v1(53.04,63.32) v1(53.49,61.75) v1(53.49,60.99) v1(54.28,136.12) v1(54.28,135.1) v1(54.28,134.09) v1(54.44,151.07) v1(54.44,150.05) v1(54.44,149.04) v1(54.44,148.02) v1(54.36,71.5) v1(55.02,62.81) v1(55.3,135.1) v1(55.46,151.07) v1(55.46,150.05) v1(55.46,149.04) v1(56.31,136.12) v1(56.31,135.1) v1(56.31,134.09) v1(56.47,151.07) v1(56.47,150.05) v1(56.47,149.04) v1(56.47,148.02) v1(57.49,151.07) v1(57.49,150.05) v1(57.49,149.04) v1(61.21,70.74) v1(64.97,2.96) v1(64.97,2.05) v1(65.74,56.77) v1(70.46,124.27) v1(70.46,123.11) v1(71.22,123.69) v1(71.19,122.67) v1(71.22,121.35) v1(71.98,124.27) v1(71.98,123.11) v1(71.98,121.94) v1(74.39,153.84) v1(74.39,153.08) v1(74.39,152.32) v1(74.9,43.86) v1(75.16,153.84) v1(75.16,153.08) v1(75.16,152.32) v1(75.92,153.84) v1(75.92,153.08) v1(75.92,152.32) v1(76.65,92.68) v1(77.28,92.68) v1(77.71,93.9) v1(77.71,93.27) v1(77.76,91.97) v1(77.76,91.34) v1(78.86,123.66) v1(78.86,122.7) v1(78.86,121.73) v1(79.83,124.5) v1(79.83,123.66) v1(79.83,122.7) v1(79.83,121.73) v1(80.77,134.37) v1(80.79,124.5) v1(80.79,123.66) v1(80.79,122.7) v1(80.79,121.73) v1(81.76,124.5) v1(81.76,123.66) v1(81.76,122.7) v1(81.76,121.73) v1(81.9,32.81) v1(82.2,32.46) v1(82.41,153.84) v1(82.41,153.08) v1(82.41,152.32) v1(82.47,32.83) v1(82.92,45.03) v1(82.89,44.43) v1(82.9,43.82) v1(83.18,153.84) v1(83.18,153.08) v1(83.18,152.32) v1(83.68,28.55) v1(83.71,27.88) v1(83.94,153.84) v1(83.94,153.08) v1(83.94,152.32) v1(84.45,28.53) v1(84.47,27.87) v1(86.84,85.67) v1(86.84,84.63) v1(86.84,83.62) v1(86.84,82.63) v1(86.84,81.61) v1(86.84,80.59) v1(86.84,79.55) v1(87.07,123.77) v1(87.07,122.6) v1(87.07,121.43) v1(87.63,124.35) v1(87.63,123.18) v1(87.63,122.01) v1(87.55,85.67) v1(87.55,84.63) v1(87.55,83.62) v1(87.55,82.63) v1(87.55,81.61) v1(87.55,80.59) v1(87.55,79.55) v1(87.55,78.54) v1(87.88,68.25) v1(88.16,73.51) v1(88.27,85.67) v1(88.27,84.63) v1(88.27,83.62) v1(88.27,81.61) v1(88.27,80.59) v1(88.27,79.55) v1(88.27,78.54) v1(88.59,123.77) v1(88.59,122.6) v1(88.59,121.43) v1(89.61,103.1) v1(89.99,141.05) v1(89.99,140.08) v1(89.99,139.12) v1(89.99,138.15) v1(90.95,141.05) v1(90.95,140.08) v1(90.95,139.12) v1(90.95,138.15) v1(91.77,153.95) v1(91.79,153.08) v1(91.77,152.22) v1(91.92,141.05) v1(91.92,140.08) v1(91.92,139.12) v1(91.92,138.15) v1(92,99.97) v1(92.53,153.95) v1(92.53,152.22) v1(92.56,153.08) v1(92.63,68.81) v1(92.88,141.05) v1(92.88,140.08) v1(92.88,139.12) v1(92.88,138.15) v1(93.29,153.95) v1(93.32,153.08) v1(93.29,152.22) v1(94.97,100.05) v1(96.6,135.13) v1(99.82,153.95) v1(99.81,153.08) v1(99.82,152.22) v1(100.58,153.95) v1(100.58,153.08) v1(100.58,152.22) v1(101.35,153.95) v1(101.34,153.08) v1(101.35,152.22) v1(106.84,44.48) v1(115.34,45.03) v1(115.34,44.5) v1(115.34,43.99) v1(119.04,78.58) v1(119.05,78.1) v1(121.58,150.38) v1(121.58,146.82) v1(122.35,150.38) v1(122.34,146.82) v1(123.11,150.38) v1(123.1,146.82) v1(123.98,75.16) v1(123.97,74.4)
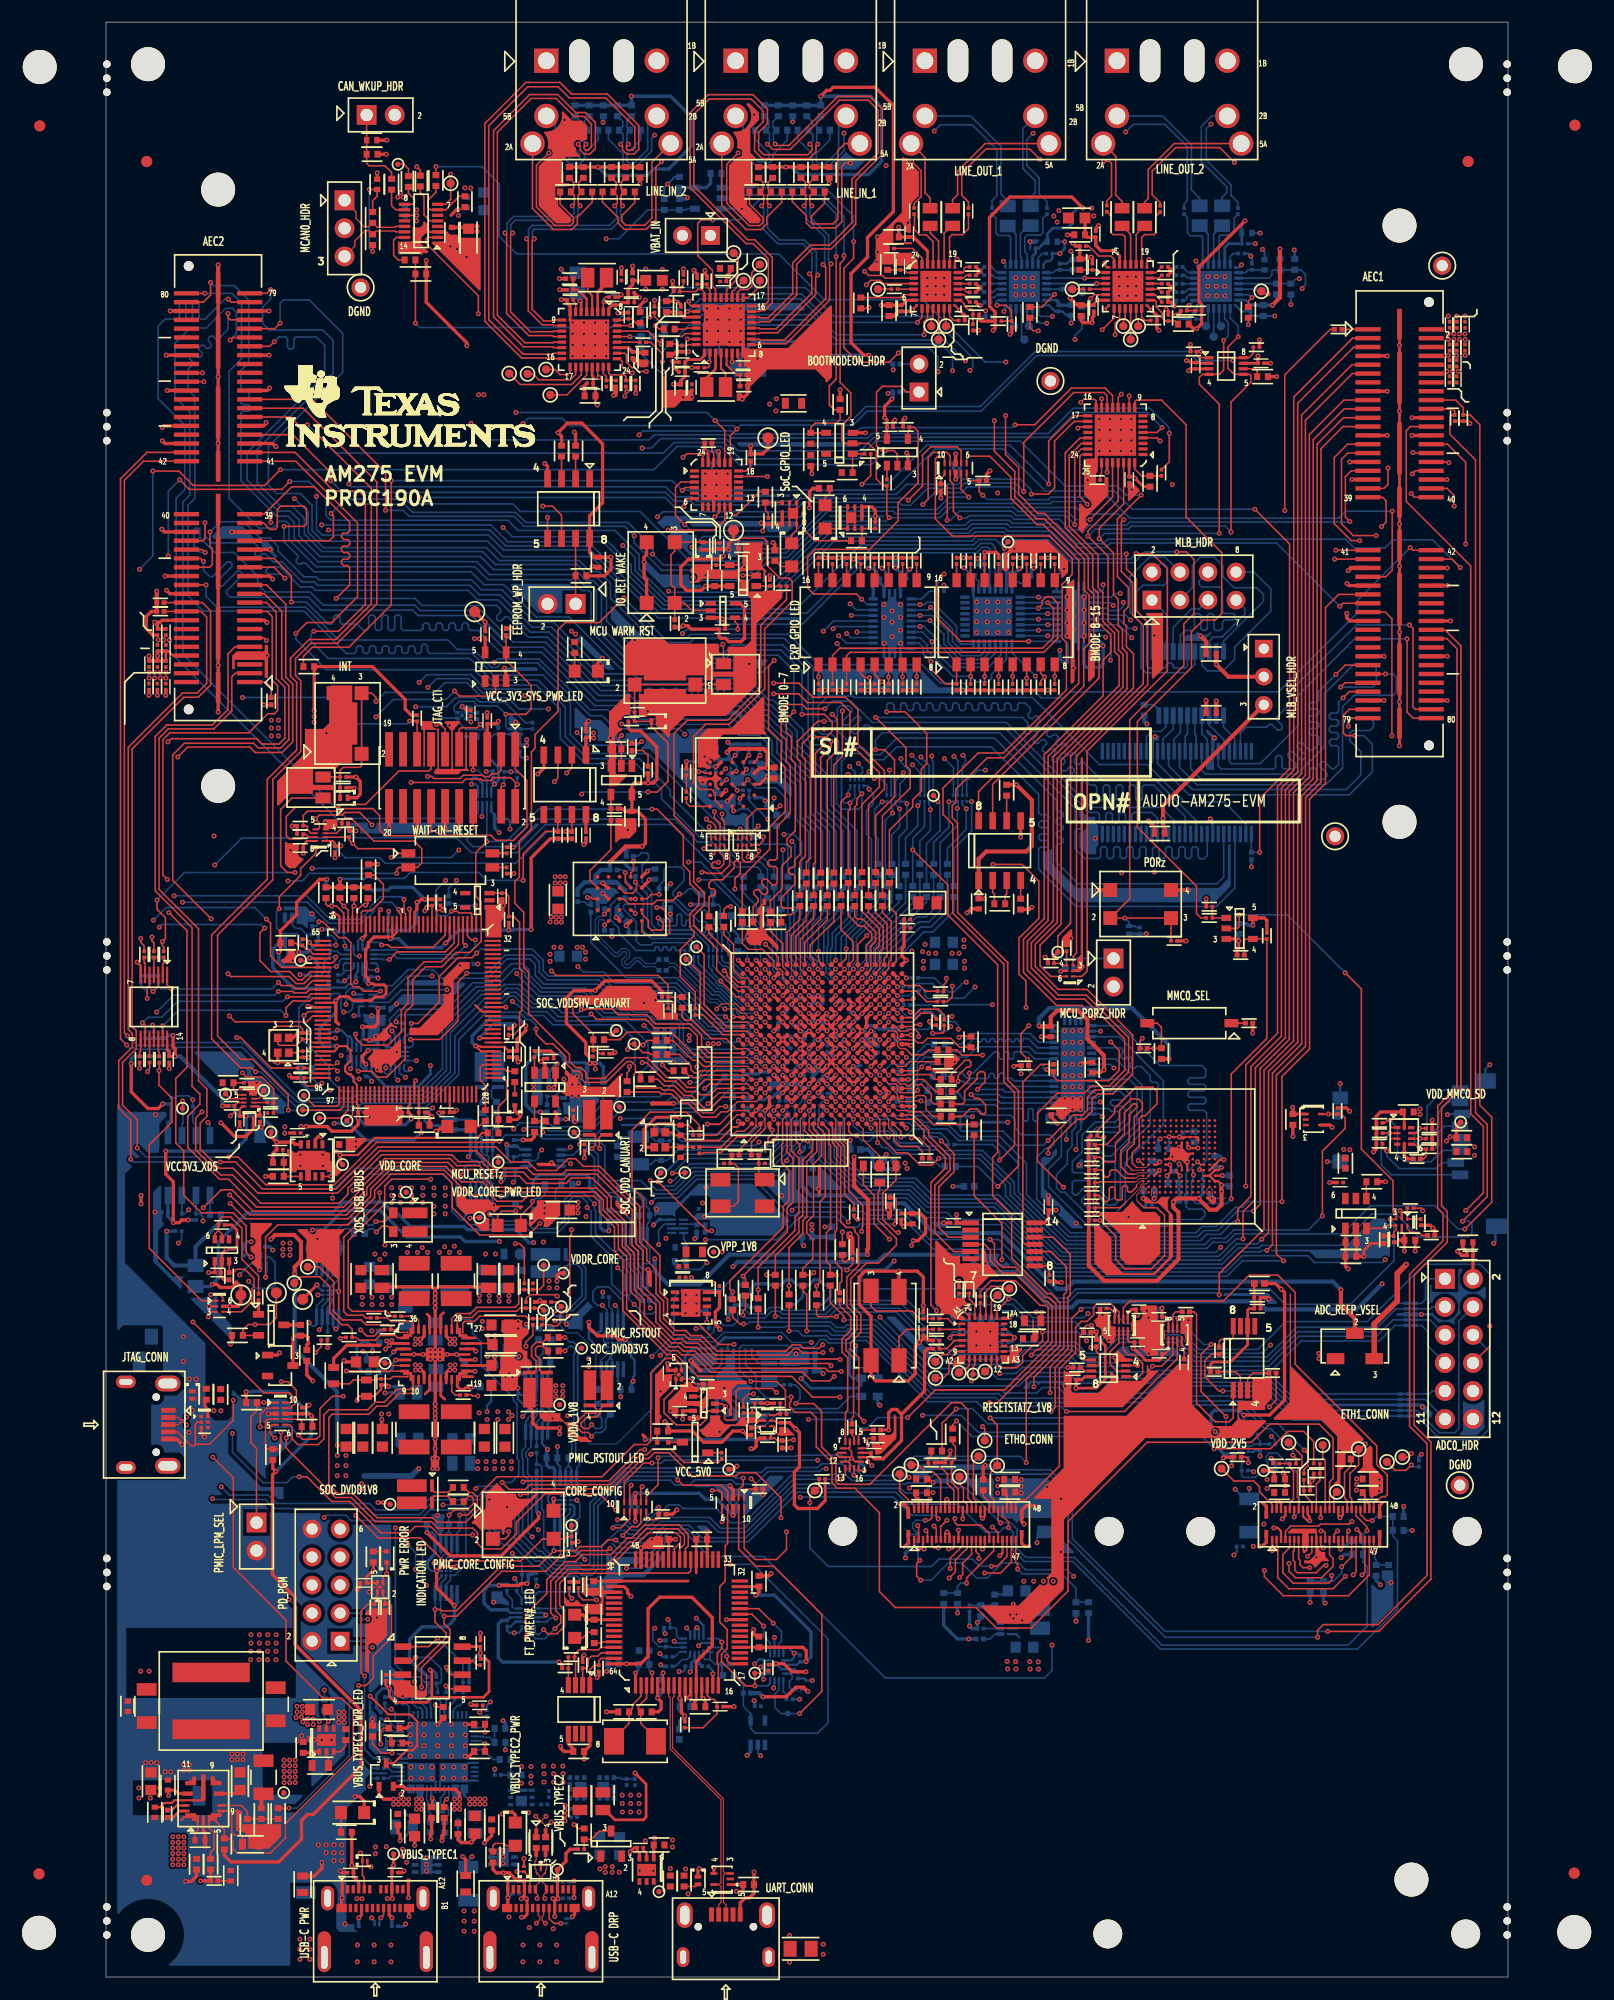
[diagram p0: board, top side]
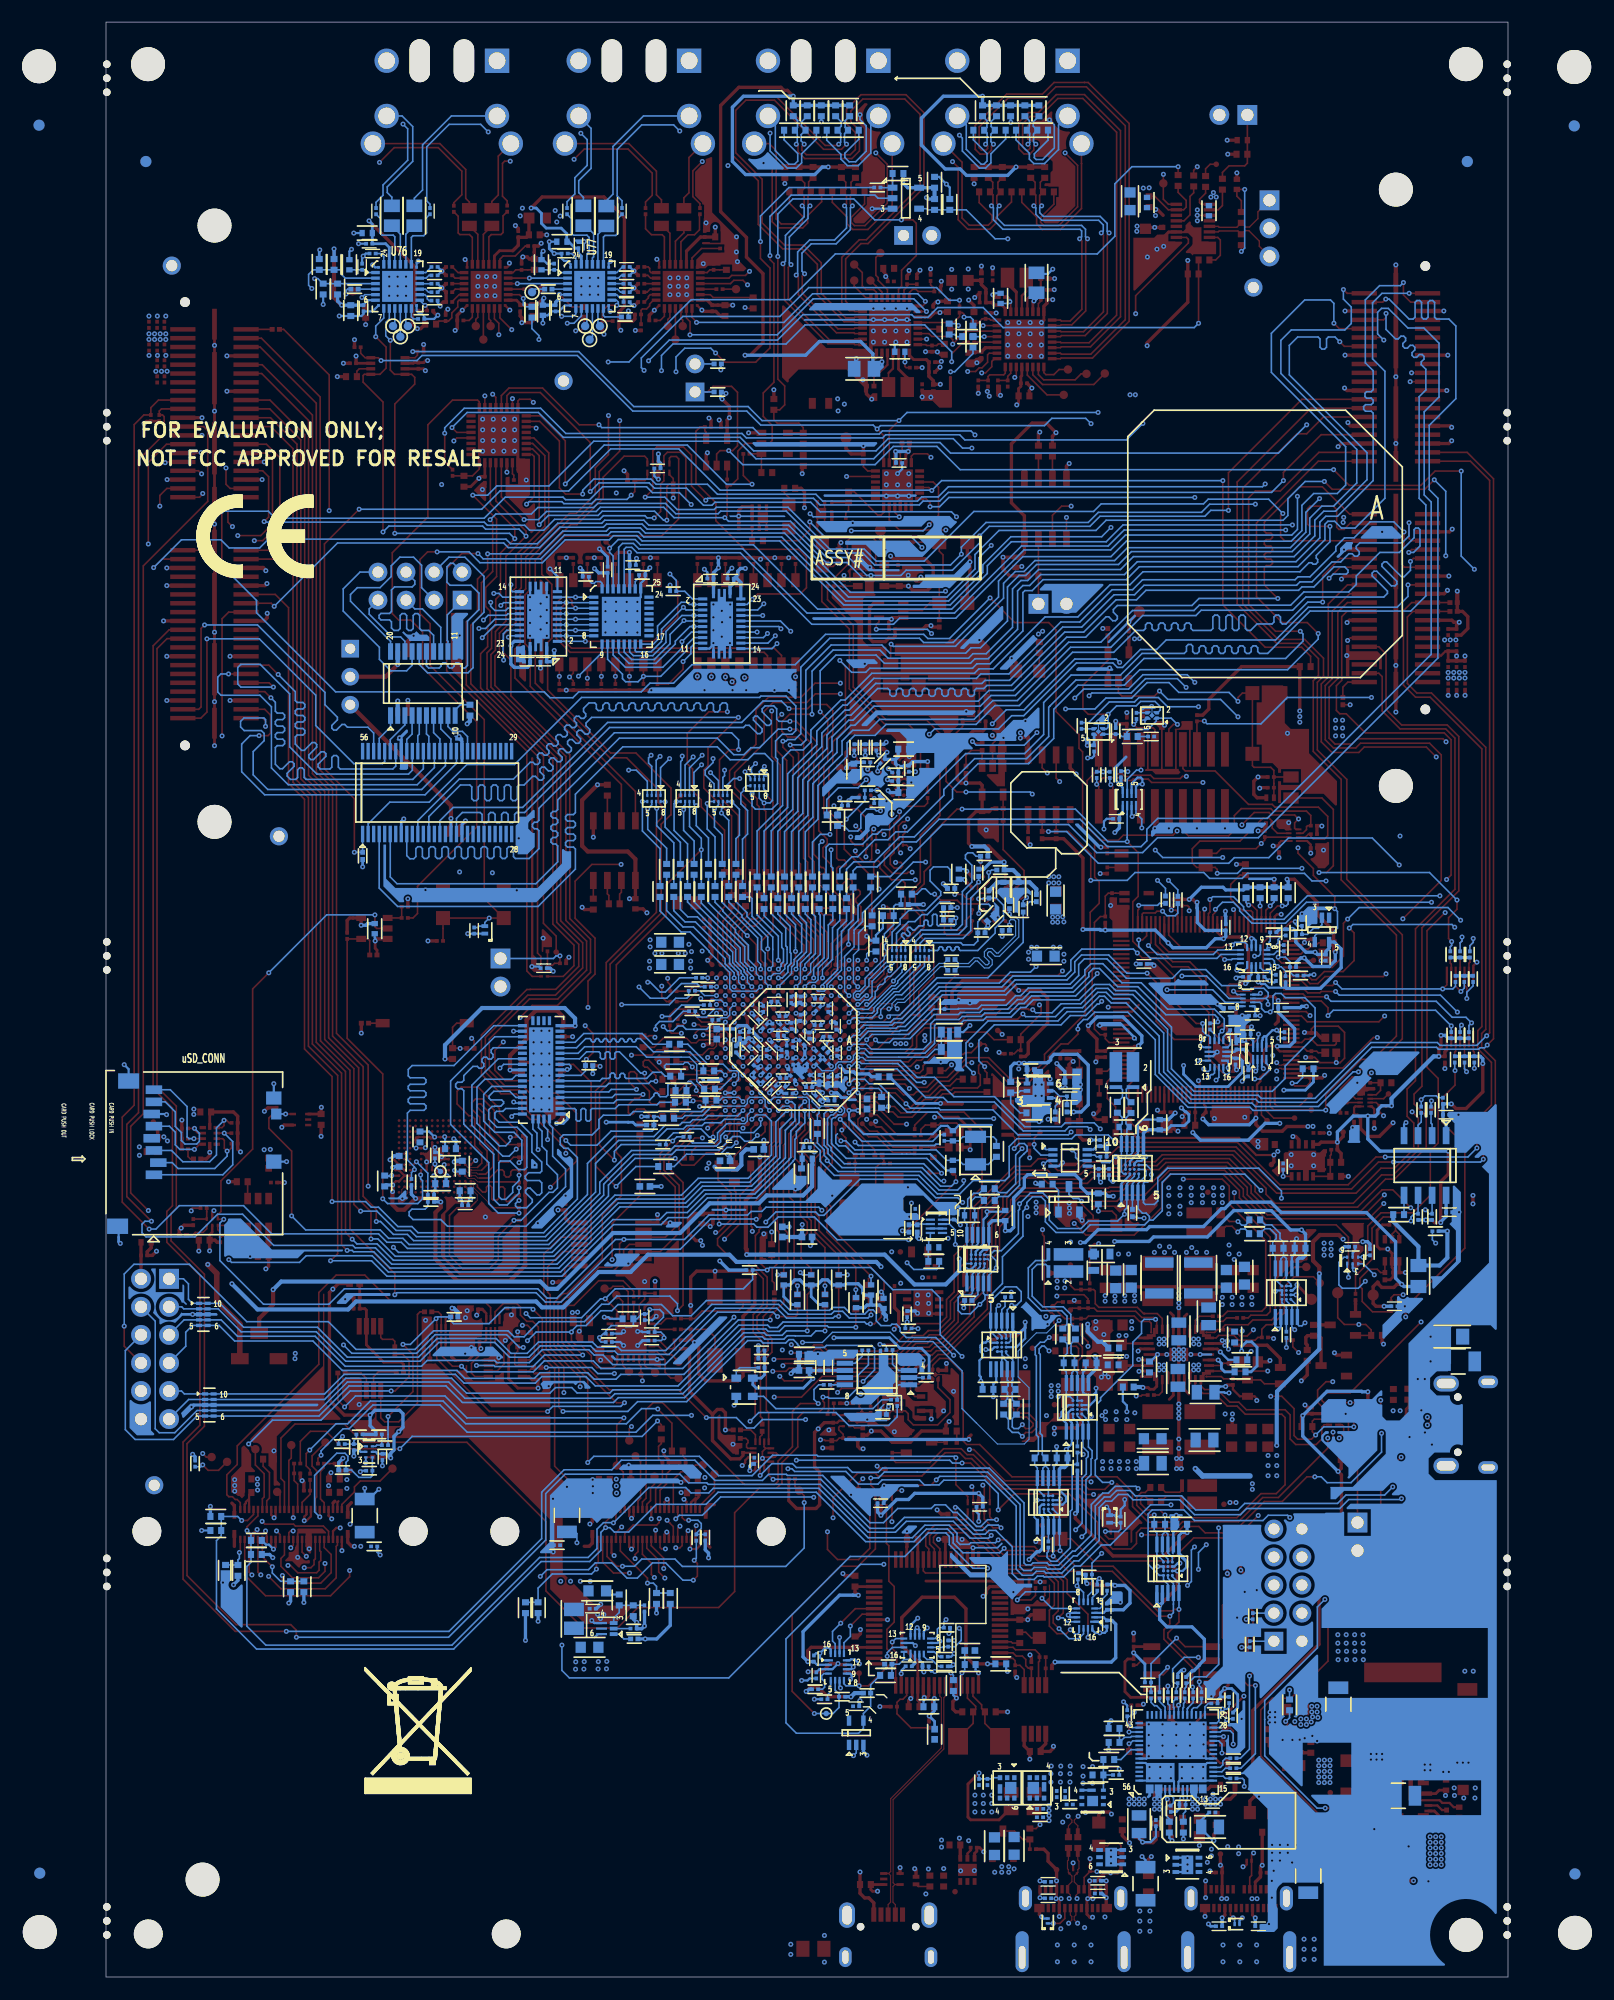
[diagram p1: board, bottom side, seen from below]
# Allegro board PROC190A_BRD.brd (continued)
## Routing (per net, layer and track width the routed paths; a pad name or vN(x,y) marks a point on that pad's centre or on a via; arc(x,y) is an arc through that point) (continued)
DVDD1V8_ALERT: length 38.4
  TOP w0.147: R305.1 19.49,57.06 v1(18.97,56.54)
  L03_SIG1 w0.091: v1(18.97,56.54) 19.76,55.75 v1(19.76,41.61)
  BOTTOM w0.147: v1(19.76,41.61) 19.96,41.81 21.72,41.81 22.2,41.33 28.4,41.33 29.36,42.29 32.23,42.29 32.6,41.92 32.6,37.38 31.59,36.36 U123.A3 31.21,35.94 30.81,35.54 U124.3
DVDD3V3_ALERT: length 4
  BOTTOM w0.147: R505.1 45.56,60.71 45.86,60.41 U91.3 45.86,58.57 45.57,58.27 45.57,58.27 45.46,58.16 U92.A3
DVDD3V3_N: length 8.3
  TOP w0.147: R327.4 44.08,51.76 44.43,51.4 44.43,51.2 44.28,51.05 43.45,51.05 42.67,50.27 42.67,49.77 43.14,49.3 43.69,49.3 43.99,49 v1(43.99,48.95)
  BOTTOM w0.147: R539.2 45.26,50.5 45.26,49.66 44.9,49.3 44.35,49.3 v1(43.99,48.95)
DVDD3V3_P: length 7.1
  TOP w0.147: R327.1 45.1,51.76 44.78,51.44 44.78,51.05 44.43,50.7 43.6,50.7 43.02,50.12 43.02,49.91 43.28,49.65 43.69,49.65 43.99,49.96 v1(43.99,50.01)
  BOTTOM w0.147: v1(43.99,50.01) 44.35,49.65 44.75,49.65 44.91,49.81 44.91,50.56 R540.2
VBAT_IN: length 28.8
  TOP w0.254: v1(44.5,142.34) 44.34,142.51 C100.1 44.34,143.82 44.13,144.03 C95.1 44.13,144.9 44.04,144.98 U8.21
  L04_PWR1 w0.381: v1(44.5,142.34) 44.5,143.08 45.89,144.47 45.89,150.15 45.72,150.32 45.72,155.96 48.87,159.11 53.33,159.11 J7.1
VBUS_TYPEC1: length 15.2
  TOP w0.254: J24.B9 23.14,5.6 v1(22.89,5.35) ; J24.B4 25.64,5.6 ; 25.89,7.13 J24.A9 C326.1 ; J24.A4 22.89,8.59
  TOP w0.305: v1(26.04,16.1) 25.15,16.1 24.73,16.52 D5.1 ; C326.1 25.89,9.96 v1(26.05,10.12) TP107.1 ; R3933.1 v1(22.26,10.11) 22.42,9.95 C327.1 22.42,9.06 22.89,8.59 ; 25.64,5.6 v1(25.89,5.35)
  BOTTOM w0.305: C655.1 v1(22.89,5.35) ; C654.1 v1(25.89,5.35)
  vias: v1(22.73,7.09) v1(23.19,7.09) v1(24.4,11.77) v1(24.4,11.16) v1(25.39,11.8) v1(25.48,7.09) v1(25.94,7.09) v1(26.04,15.65) v1(26.5,16.1) v1(26.5,15.65) v1(26.72,16.55) v1(26.87,11.57) v1(26.87,10.96) v1(26.95,16.1) v1(26.95,15.65) v1(27.24,10.38) v1(27.41,16.1) v1(27.41,15.65)
VBUS_TYPEC2: length 24
  TOP w0.254: v1(40.64,5.48) J25.B4 40.64,6.84 40.89,7.09 J25.A9 v1(40.89,8.7) ; 37.89,7.37 J25.A4 v1(37.89,8.7) ; 37.88,5.41 38.14,5.68 J25.B9 38.14,7.01
  TOP w0.305: R402.1 35.06,9.73 35.36,9.43 v1(36,9.43) 36.53,9.43 37.26,8.7 v1(37.89,8.7) ; D5.2 26.93,17.26 27.19,17 31.64,17 32.03,16.62 v1(32.03,16.1) ; v1(40.89,8.7) TP108.1 41.66,10.49 41.66,11.19 42.04,11.57 R401.2 ; 37.88,5.41 v1(37.63,5.41) ; v1(38.07,7.09) 38.14,7.01 ; 37.89,7.37 v1(37.61,7.09)
  BOTTOM w0.254: 31.49,16.27 31.49,16.86 31.57,16.94 ; 31.82,16.27 31.82,16.86 U129.3 31.65,16.43
  vias: v1(31.57,16.1) v1(31.57,15.65) v1(31.57,15.19) v1(32.03,15.65) v1(32.03,15.19) v1(36.51,5.44) v1(40.48,7.09) v1(40.94,7.09) v1(46.77,16.47) v1(46.77,15.7) v1(46.77,14.94) v1(47.53,16.47) v1(47.53,15.7) v1(47.53,14.94) v1(48.29,16.47) v1(48.29,15.7) v1(48.29,14.94)
VCC1V8_CLKBUF: length 29.8
  L03_SIG1 w0.305: v1(62.97,54.18) 61.06,56.08 v1(61.06,57.88)
  BOTTOM w0.254: U65.6 61.23,54.92 C284.2 C286.2 62.83,54.92 FL10.1 63.31,54.52 v1(62.97,54.18) 63.83,53.31 68.1,53.31 68.41,53.63 U62.4 67.65,54.22 67.35,54.52 R329.2 67.35,55.64 C266.2 C265.1 ; v1(61.06,57.88) 56.02,57.88 55.07,56.92 53.14,56.92 52.44,56.22 R348.2
VCC1V8_SYS: length 489
  TOP w0.178: C3769.2 95.96,56.44 96.24,56.72 U3083.1 ; C151.2 92.74,57.48 92.56,57.66 U29.8 ; U39.1 20.54,102.86
  TOP w0.203: U49.M4 U49.N4 ; U49.N4 U49.P5 100.79,73.05 v1(101.03,73.29) ; U49.N4 U49.P3 100.46,72.05 100.75,72.05 101.03,71.76 v1(101.03,71.71) ; U2353.3 C3721.2 ; v1(95.46,73.8) 95.21,73.55 U49.C6 ; v1(86.49,91.06) 86.52,91.09 U43.5 ; 20.54,102.86 20.74,102.65 C3729.2
  TOP w0.229: U2.5 117.38,67.45 117.61,67.21 C37.1
  TOP w0.254: v1(87.86,53.31) 89.69,53.31 90.53,54.15 90.53,57.15 89.96,57.71 R5795.1 ; R5808.2 v1(70.89,49.53) ; v1(98.07,145.44) 98.24,145.61 C101.1 U11.3 ; v1(93.22,135.69) 93.97,134.94 R5761.1 ; U21.27 v1(90.68,136.25) ; U2347.8 88.68,54.37 88.39,54.08 ; R464.1 R465.1 123.34,140.87 v1(123.55,140.67) ; v1(43.33,74.17) 43.36,74.19 R268.1 ; v1(33.07,53.37) 32.59,53.37 32.44,53.21 32.08,53.21 31.82,53.48 U56.18 ; v1(93.04,56.9) 93.19,56.74 93.29,56.74 94.21,55.83 95.38,55.83 ; U12.1 C102.2 ; C73.1 89.48,151.48 89.82,151.82 U6.6 ; C3721.2 69.29,47.21 69.59,46.91 ; U21.31 C126.2 ; U5.6 72.53,151.82 ; 33.45,57.86 U56.26
  TOP w0.305: R288.1 39.44,61.12 v1(39.29,61.26) 39.14,61.11 R291.1 ; C151.2 93.17,57.02 v1(93.04,56.9) ; v1(23.72,83.87) 23.23,83.38 23.23,82.95 v1(23.54,82.64) ; v1(22.64,103.77) 22.04,103.77 R225.1 22.03,104.08 21.92,104.19 R220.1 ; R684.1 R685.1 4.11,123.64 3.64,123.17 3.64,122.09 4.24,121.49 C160.1 ; U2352.8 v1(56.81,41.8) ; U3087.5 C3774.2 v1(50.87,55.55) ; U27.5 C148.1 v1(54.31,125.93) 53.93,125.55 52.59,125.55 52.07,126.07 52.07,127.66 52.81,128.4 R124.2 55.68,128.4 v1(55.93,128.65) ; v1(49.1,108.1) 47.84,108.1 47.64,107.9 U2348.5 C3705.1 ; v1(49.1,108.1) 49.57,108.1 49.9,108.43 49.9,111.37 48.44,112.83 47.57,112.83 47.32,113.08 R615.1 ; v1(49.1,108.1) R5699.2 ; 49.2,99.28 U140.E4 ; C3729.2 v1(21.27,102.4) ; R559.1 22.44,107.68 v1(22.49,107.63) ; v1(52.24,50.52) C3773.1 52.24,51.26 U3086.5 ; R117.1 105.16,95.66 104.93,95.89 104.63,95.89 104.63,95.89 U26.5 v1(103.89,95.22) ; v1(55.22,109.6) 55.33,109.6 U28.E4 ; U2351.8 v1(47.94,43.79) ; v1(63.58,25.86) 63.2,26.23 62.49,26.23 61.63,25.38 59.53,25.38 v1(59.52,25.36) ; v1(87.33,152.01) 87.97,151.37 C76.1 88.98,151.37 C73.1 ; R75.1 74.42,56.88 74.14,56.61 74.14,53.04 72.06,50.95 ; C3705.1 48.18,105.53 48.87,104.84 48.87,102.67 v1(48.56,102.36) ; C3705.1 47.61,105.51 47.01,105.51 46.74,105.79 R5698.2 ; v1(86.54,62.89) 86.11,62.89 86.01,62.99 R166.1 ; U140.B4 45.43,98.61 v1(45,99.04) ; v1(80.07,136.37) 79.76,136.06 R5798.1 ; R5795.1 v1(89.71,58.42) 89.28,58.42 R5796.1 ; v1(107.49,78.74) 107.51,78.72 C102.2 ; v1(112.65,78.38) 112.34,78.69 R70.2 ; R242.1 85.32,92.07 v1(85.06,92.33) ; v1(77.05,69.03) C164.1 U3077.1 ; U2346.8 v1(76.96,137.9) ; R301.1 50.36,89.24 49.41,90.19 45.19,90.19 v1(44.32,89.33) 42.39,89.33 41.71,88.65 41.71,86.36 43.46,84.61 43.46,83.6 43.72,83.34 R259.1 ; C149.2 60.48,109.46 v1(59.92,109.46) 59.19,109.46 U28.D1 ; R5744.2 41.27,139.5 v1(40.94,139.83) 41.81,140.69 43.1,140.69 44.98,138.81 44.98,133.48 43.81,132.3 U2358.8 43.81,128.96 44.22,128.55 C3733.1 v1(45.75,128.55) 45.75,127.46 45.15,126.86 R5746.2 ; v1(70.89,49.53) 70.89,51.08 71.2,51.39 71.63,51.39 72.06,50.95 ; R262.1 89.02,75.95 R263.1 R264.1 R266.1 R267.1 R269.1 R270.1 R275.1 89.02,67.55 ; v1(56.16,107.42) 56.15,107.42 56.15,107.42 U28.B4 ; R375.1 v1(97.83,93.81) ; C126.2 93.06,135.84 v1(93.22,135.69) ; C3769.2 95.68,56.13 95.38,55.83 ; R123.2 v1(52.58,110.05) ; R83.1 v1(77.26,62.99) ; R361.1 60.6,28.28 v1(60.69,28.37) 61.39,28.37 62.13,27.64 v1(63.4,27.64) ; U2355.5 C3728.2 ; 72.06,50.95 72.06,48.56 70.41,46.91 69.59,46.91 ; R115.1 v1(99.66,97.62) ; 88.39,54.08 87.89,54.08 C3704.2 87.88,53.33 v1(87.86,53.31) ; v1(70.23,151.37) C75.1 71.58,151.37 C72.1 72.53,151.82 ; R17.2 116.94,66.52 117.13,66.71 C37.1 v1(117.61,65.74) ; R18.2 119.94,68.07 v1(120.19,67.81) 120.36,67.64 R5213.2 ; R69.1 v1(106.04,144.9) ; v1(60.15,126.9) R122.2 ; R5797.1 v1(75.62,133.91) ; U140.D1 v1(47.11,95.19)
  TOP w0.381: C3701.1 v1(100.57,115.53) ; R684.1 v1(4.6,125.48) ; v1(106.34,156.46) 106.34,152.06 v1(105.65,151.37) ; v1(17.09,63.68) 17.09,64.29 17.66,64.86 17.66,66.56 17.04,67.18 15.32,67.18 v1(14.94,66.8) ; v1(48.56,102.36) 47.07,102.36 v1(45.64,100.94) ; v1(56.25,110.89) 56.57,111.2 59.59,111.2 59.92,110.87 v1(59.92,109.46) ; v1(101.03,71.71) 101.03,71.13 v1(101.05,71.11) 101.05,69.94 100.58,69.47 99.98,69.47 v1(98.96,70.49) 96.99,70.49 v1(96.68,70.17) 96.68,69.69 97.16,69.22 97.16,65 95.2,63.04 90.4,63.04 89.02,64.42 89.02,67.55
  L03_SIG1 w0.305: v1(22.49,107.63) 22.49,104.35 22.64,104.2 v1(22.64,103.77) v1(21.27,102.4) ; v1(36.3,75.39) 38.53,73.15 38.53,71.46 38,70.92 38,69.47 37.56,69.03 37.56,67.06 38,66.62 38,62.41 39.14,61.26 v1(39.29,61.26) ; v1(22.63,90.09) 23.27,89.46 23.27,88.6 22.87,88.2 22.87,87.46 v1(22.45,87.04) 22.07,86.66 22.07,84.38 22.58,83.87 v1(23.72,83.87)
  L03_SIG1 w0.381: v1(33.76,143.26) 33.12,142.62 33.12,141.45 33.66,140.92 33.66,140.41 33.5,140.26 33.5,121.78 33.38,121.65 v1(33.38,121.18) ; v1(56.81,41.8) 55.99,42.61 54.88,42.61 53.11,44.37 53.11,49.65 v1(52.24,50.52) 53.16,51.44 53.16,53.26 v1(50.87,55.55) ; v1(96.68,70.17) 94.86,72 94.86,73.27 95.38,73.8 v1(95.46,73.8) ; v1(56.25,110.89) 56.25,111.72 v1(56.33,111.8)
  L03_SIG1 w0.508: v1(28.32,46.03) 28.32,45.96 30.39,43.89 31.39,43.89 31.9,44.4 31.9,52.2 v1(33.07,53.37) 32.69,53.74 32.69,57.32 v1(34.09,58.71) v1(34.09,59.35)
  L04_PWR1 w0.305: 36.78,59.64 35.85,58.71 v1(34.09,58.71)
  L04_PWR1 w0.381: 48.46,103.53 48.56,103.43 v1(48.56,102.36) ; v1(93.04,56.9) 93.04,58.01 92.79,58.27 ; v1(34.09,59.35) 34.37,59.35 35,58.71
  BOTTOM w0.203: 53.04,28.45 53.32,28.73 U125.3 ; U90.1 34.9,105.54 35.2,105.23 ; C470.2 22.63,90.82 22.83,91.03 U97.3 ; C371.1 103.67,151.42 103.27,151.82 U76.6 ; U86.5 14.07,65.56 13.84,65.79 C414.2 ; 37.25,75.22 37.55,74.92 U98.8 ; 20.15,89.6 20.18,89.57 21.68,89.57 22.02,89.91 22.37,89.91 22.54,90.08 22.61,90.08 22.62,90.09 v1(22.63,90.09) ; C617.2 62.38,27.87 U126.3 61.19,27.87 v1(60.69,28.37) ; U102.1 23,87.9 22.9,87.8 C511.2 v1(22.45,87.04) ; U109.1 23.09,82.47 23.46,82.1 C528.2 ; C3725.2 24.61,83.92 24.77,83.77 U110.3 ; U77.6 86.08,151.82
  BOTTOM w0.254: v1(59.72,106.5) 59.79,106.43 59.79,106.07 R447.2 ; v1(81.69,77.39) 79.69,77.39 79.69,77.39 79.27,77.39 79.02,77.14 R598.1 ; R5716.2 47.37,94.93 v1(47.11,95.19) ; R5753.2 v1(45.82,94.21)
  BOTTOM w0.305: v1(35.62,103.63) 35.2,104.04 C3726.2 35.2,105.23 ; R565.1 v1(96.68,70.17) ; v1(86.49,91.06) 86.77,91.34 C421.2 ; v1(56.25,110.89) 56.28,110.89 56.44,110.72 56.44,110.26 ; v1(55.22,109.6) R449.2 55.23,109.06 R452.2 C390.1 55.98,107.24 56.15,107.42 56.15,107.42 v1(56.16,107.42) ; v1(55.22,109.6) 54.78,109.6 54.69,109.69 R448.2 54.27,109.7 53.93,110.04 53.74,110.04 53.73,110.05 v1(52.58,110.05) ; v1(55.22,109.6) 55.48,109.85 55.48,110.24 ; v1(76.96,137.9) 76.96,137.25 76.77,137.05 C3703.1 ; C528.2 v1(23.54,82.64) ; C146.1 103.3,95.38 103.45,95.22 v1(103.89,95.22) ; R480.1 12.51,66.35 12.73,66.57 v1(13.16,66.57) ; v1(101.03,73.29) 100.96,73.36 C503.1 ; C3707.1 47.11,95.54 v1(47.11,95.19) ; R612.1 50.54,31.2 v1(50.65,31.1) ; R603.1 70.58,64.01 v1(71.4,64.82) ; 56.44,110.26 56.42,110.24 55.48,110.24 ; 56.44,110.26 R446.2 ; v1(22.63,90.09) 22.63,90.12 22.63,90.12 C470.2 ; R550.1 36.36,74.89 36.3,74.96 v1(36.3,75.39) 36.46,75.22 C478.2 37.25,75.22 ; 86.08,151.82 86.27,151.63 C372.1 C374.1 87.43,151.92 v1(87.33,152.01) ; R533.2 20.72,94.86 R534.2 v1(19.57,94.86) 19.4,94.86 19.22,94.68 R536.2 19.22,93.7 18.31,92.79 v1(17.48,92.79) 17.27,92.58 C455.2 16.5,92.86 16.21,93.15 U93.5 15.75,93.71 15.11,93.07 15.11,91.39 16.99,89.51 20.06,89.51 20.15,89.6 R554.2 ; 70.12,126.61 69.84,126.61 69.49,126.27 U83.23 ; 70.12,126.61 69.78,126.96 69.78,127.28 69.52,127.53 v1(69.09,127.53) ; 70.12,126.61 C395.1 70.13,126.21 70.47,125.87 U83.24 ; v1(50.25,28.28) 50.41,28.12 R614.2 ; R5712.2 47.49,100.3 46.85,100.94 v1(45.64,100.94) ; C388.1 55.24,110.48 55.48,110.24 ; C3718.1 47.58,43.43 v1(47.94,43.79) 53.75,43.79 54.31,43.23 55.37,43.23 v1(56.81,41.8) 57.11,42.1 C3719.1 ; R636.2 63.31,26.05 63.5,25.86 v1(63.58,25.86) ; U81.24 88.58,119.59 C408.1 88.58,118.81 88.82,118.57 90.02,118.57 90.32,118.88 v1(90.32,120.52) 90.32,120.63 90.02,120.93 U81.23 ; R575.1 99.33,70.86 v1(98.96,70.49) ; R423.2 106.02,151.74 v1(105.65,151.37) C373.1 C371.1 ; R419.2 v1(106.34,156.46) ; R454.2 59.43,106.79 v1(59.72,106.5) ; C3725.2 23.84,83.98 v1(23.72,83.87) ; R5810.2 v1(52.96,97.1) ; R450.2 59.08,109.98 59.21,109.85 C389.1 59.62,109.85 59.92,109.55 v1(59.92,109.46) ; R631.1 59.53,25.38 v1(59.52,25.36) ; 53.04,28.45 C608.2 53.04,27.74 v1(52.91,27.62) ; R611.1 v1(50.17,30.47) ; R443.2 R444.2 R445.2 56.51,111.61 v1(56.33,111.8) ; v1(101.03,71.71) 101.62,71.71 C518.1
  BOTTOM w0.381: R5713.2 v1(51.13,96.24) R5711.2 ; C3708.1 49.25,99.39 v1(49.2,99.34) ; R5715.2 47.02,98.36 46.33,99.04 46.3,99.04 46.23,99.12 C3706.2 45.08,99.12 v1(45,99.04) 44.93,99.12 C3709.1 ; R5684.2 94.03,113.72 v1(94.28,113.46) ; R5714.2 50.77,98.6 v1(51.16,98.98) ; R5717.2 47.12,102.06 47.42,102.36 v1(48.56,102.36) ; v1(20.95,48.13) 20.95,52.31 20.92,52.34 20.92,53.02 17.09,56.85 v1(17.09,63.68) ; v1(33.07,53.37) 33.12,53.42 C555.1 ; C3709.1 44.34,99.73 44.83,100.23 R5710.2 v1(45.64,100.94) ; C3709.1 43.34,99.12 42.72,98.5 R5693.2 ; v1(95.46,73.8) 95.35,73.9 C514.1 ; U2345.2 v1(100.57,115.53) ; v1(53.34,66.85) 53.39,66.85 53.51,66.98 R5837.1 ; R5845.1 59.17,25.7 v1(59.52,25.36)
  BOTTOM w0.508: v1(28.32,46.03) 27.66,45.36 23.38,45.36
  vias: v1(4.73,121.06) v1(5.23,121.06) v1(5.74,121.06) v1(14.88,132.16) v1(14.94,131.7) v1(14.99,113.79) v1(14.99,113.08) v1(14.99,112.37) v1(15.62,113.79) v1(15.62,113.08) v1(15.62,112.37) v1(16.03,66.45) v1(16.03,65.89) v1(16.03,65.35) v1(16.66,66.45) v1(16.66,65.89) v1(16.66,65.35) v1(20.95,47.22) v1(20.95,46.3) v1(20.95,45.39) v1(21.74,47.22) v1(21.74,46.3) v1(21.74,45.39) v1(33.83,121.16) v1(34.24,143.26) v1(54.04,70.07) v1(60.12,142.41) v1(60.72,142.89) v1(60.68,141.79) v1(84.28,60.2) v1(84.76,60.16) v1(121.47,145.38) v1(121.98,145.38) v1(122.48,145.38)
VCC1V8_SYS_N: length 2.6
  TOP w0.147: R335.2 31.42,43.05 30.93,43.54 29.77,43.54 29.53,43.3 R334.4
VCC1V8_SYS_P: length 2.6
  TOP w0.147: R334.1 29.53,44.09 29.73,43.89 31.03,43.89 31.42,44.29 R331.2
VCC1V8_SYS_SW: length 1.5
  TOP w0.254: 28.91,52.78 29.32,53.2 U56.13
VCC1V8_TA: length 66.8
  TOP w0.203: C236.2 13.94,78.71 13.84,78.82 U51.1
  TOP w0.254: R128.2 v1(79.59,128.99)
  TOP w0.305: v1(71.19,142.87) 70.53,142.21 v1(70.53,141.18) 70.74,140.98 C136.1 U23.5 ; R141.2 R140.2 v1(71.53,128.5) 71.51,128.52 71.13,128.52 71.12,128.5 R139.2 R138.2 R137.2 67.84,128.5 v1(67.71,128.36) 67.57,128.5 R136.2 v1(66.42,128.5) R135.2 v1(65.16,128.5) R134.2 ; C236.2 13.92,78.03 13.64,78.03 13.36,77.75 13.36,76.81 12.66,76.11 11.65,76.11 v1(10.41,77.34) ; R131.2 v1(82.76,128.5) R130.2 ; R129.2 80.86,128.77 80.64,128.99 v1(79.59,128.99) ; R126.2 v1(77.68,128.5) R127.2 ; v1(5.13,79.05) 4.72,78.63 3.8,78.63 2.29,80.14 v1(2.29,82.7) ; R132.2 v1(85.3,128.5) R133.2
  BOTTOM w0.254: C393.2 U82.31 ; U82.27 79.56,127.37
  BOTTOM w0.305: v1(71.19,142.87) 71.31,142.99 71.31,143.51 ; R457.2 83.82,127.34 v1(84.04,127.56) ; R461.2 v1(75.9,126.02) ; v1(2.29,82.7) 2.29,83.13 2.51,83.36 R507.1 R513.1 R524.1 ; U81.1 C409.2 86.65,119.09 86.4,119.35 v1(86.4,120.11) ; R583.1 v1(5.5,67.53) ; U83.1 71.97,126.14 C394.2 71.97,127.14 v1(71.52,127.59) 71.52,128.02 71.53,128.03 v1(71.53,128.5) ; v1(82.75,127.51) 82.36,127.13 C393.2 ; v1(5.13,79.05) R582.1 C529.2 5.89,77.58 5.61,77.3 U107.1 ; v1(79.59,128.99) 79.59,128.33 79.56,128.3 C391.2 79.56,127.37 ; R526.1 R516.1 R511.1
  BOTTOM w0.381: v1(5.5,67.53) 5.5,65.12 6.2,64.42 R643.2 8.11,66.13 10.4,68.42 R578.1
  vias: v1(70.84,143.38)
VCC2V5_PG: length 1.5
  BOTTOM w0.147: U127.2 R637.1
VCC3V3_XDS: length 215.6
  TOP w0.203: v1(20.82,88.41) 20.62,88.21 U48.79 ; 33.45,88.01 34.05,87.41 U48.16 ; U48.39 31.13,93.97 v1(30.78,93.62) ; U48.51 26.33,94.58 25.93,94.18 U48.52 ; U40.14 5.54,83.94 ; C234.1 U48.122 ; U48.90 20.68,83.81 20.88,84.01 20.88,84.25 v1(20.9,84.28) 21.78,84.28 22.15,83.91 22.15,82.93 21.67,82.45 21.67,82.02 21.95,81.74 22.15,81.74 22.43,81.46 22.43,81.1 22.73,80.8 U48.101 22.73,79.04 22.84,78.94 C231.2 ; U48.47 27.93,96.41 28.17,96.65 ; C232.1 27.38,78.29 27.38,78.82 27.53,78.97 U48.113 ; U2353.2 68.81,47.06 69.1,46.78 69.1,46.57 v1(69.37,46.3) ; U48.69 18.52,92.21 v1(18.46,92.27) ; C235.2 12.12,78.59 12.35,78.82 U51.8 ; C221.1 36.11,84.21 U48.8 33.95,84.21 33.86,84.3 v1(33.48,84.3) 33.97,83.81 U48.7
  TOP w0.254: v1(20.82,88.41) 21.18,88.77 21.59,88.77 21.62,88.75 21.98,88.75 22.32,88.41 24.03,88.41 24.37,88.75 25.08,88.75 25.37,89.05 25.37,89.66 25.2,89.84 24.28,89.84 24.18,89.94 v1(23.77,89.94)
  TOP w0.305: R237.1 R236.1 v1(28.88,97.57) 28.55,97.57 28.29,97.31 v1(28.17,97.31) 28.17,96.65 ; v1(31.75,78.48) 31.56,78.29 C234.1 ; v1(15.46,75.59) C243.1 15.12,74.57 R306.1 ; v1(15.46,75.59) 16.93,75.59 17.12,75.39 U55.4 ; v1(15.46,75.59) 14.93,76.11 TP68.1 ; v1(38.02,86.13) 38.02,85.7 37.24,84.92 C222.1 C221.1 ; v1(15.65,92.79) 15.8,92.94 R246.2 15.8,94.71 17.27,96.19 17.27,97.31 19.35,99.39 v1(20.02,99.39) ; 21.08,86.26 20.82,86.52 v1(20.82,88.41) ; R280.1 v1(10.55,78.88) ; v1(5.41,74.78) 5.41,72.69 6.1,72.01 v1(6.1,68.3) 6.63,68.3 6.87,68.55 v1(7.44,68.55) ; v1(48.84,48.67) 48.84,48.87 48.64,49.07 ; v1(6.07,85.26) 6.07,84.24 6.26,84.05 v1(6.26,83.36) C192.1 5.72,83.77 5.54,83.94 ; v1(23.77,89.94) 23.77,90.37 23.51,90.63 23.51,93.03 23.77,93.29 23.77,93.65 24.28,94.16 25.61,94.16 v1(25.76,94) 25.93,94.18 ; v1(18.13,77.01) 20.02,77.01 20.45,76.58 22.23,76.58 22.84,77.18 v1(22.84,77.76) C231.2 ; v1(27.64,77.69) 27.64,78.03 C232.1 ; v1(23.23,86.03) 24.33,86.03 24.63,86.33 v1(24.63,87.7) ; R119.1 R118.1 40.25,103.06 38.51,101.32 v1(38.51,94.84) ; R241.1 v1(36.48,94.78) ; U25.8 C147.1 ; C235.2 v1(12.7,77.95)
  L03_SIG1 w0.381: 40.18,74.63 39.73,74.17 39.73,71.17 40.46,70.43 ; v1(31.75,78.48) 30.52,77.24 28.09,77.24 v1(27.64,77.69)
  BOTTOM w0.203: C469.2 23.23,90.76 U97.2 ; C515.2 23.31,84.99 23.09,84.77 U109.8 ; U102.8 24.44,87.9 v1(24.63,87.7)
  BOTTOM w0.305: 59.99,48.67 v1(48.84,48.67) ; R519.1 R515.1 R510.1 ; v1(10.55,78.88) 11.44,78.88 11.79,78.54 11.79,78.18 12.01,77.95 v1(12.7,77.95) ; v1(5.41,74.78) 11.6,74.78 12.7,75.88 v1(12.7,77.95) ; v1(20.82,88.41) C488.1 20.82,87.34 19.33,85.86 19.33,84.73 19.79,84.28 v1(20.9,84.28) ; U107.8 C473.2 5.61,68.86 6.1,68.37 v1(6.1,68.3) ; R551.1 v1(7.44,68.55) R552.1 ; v1(23.23,86.03) 23.31,85.95 C515.2 ; v1(22.84,77.76) 23.43,77.17 27.12,77.17 v1(27.64,77.69) ; v1(24.63,87.7) 24.7,87.76 C500.2 ; v1(38.51,94.84) 36.97,94.84 36.92,94.78 v1(36.48,94.78) 31.95,94.78 v1(30.78,93.62) 30.36,93.19 27.33,93.19 26.52,94 v1(25.76,94) 25.57,94.2 C430.2 27.42,94.76 28.14,95.48 28.14,96.75 28.17,96.77 v1(28.17,97.31) ; v1(20.02,99.39) 20.02,99.31 19.92,99.22 R523.2 R522.2 R521.2 R520.2 23.97,98.42 25.58,98.42 25.82,98.66 27.78,98.66 v1(28.88,97.57) ; v1(12.7,77.95) 14.01,77.95 15.46,76.51 v1(15.46,75.59) ; v1(6.07,85.26) 5.69,85.26 5.43,84.99 R525.1 R517.1 R512.1 ; C469.2 23.44,90.32 23.44,90.32 23.44,90.25 23.67,90.02 23.7,90.02 v1(23.77,89.94) ; v1(38.02,86.13) 37.23,86.92 34.88,86.92 33.17,85.22 33.17,84.61 v1(33.48,84.3) ; C208.1 v1(33.68,91.72) ; R549.2 19.2,91.85 18.77,92.27 v1(18.46,92.27) 17.68,91.49 16.18,91.49 15.65,92.03 v1(15.65,92.79)
  BOTTOM w0.381: v1(6.26,83.36) 6.73,83.36 10.55,79.54 v1(10.55,78.88)
  vias: v1(17.67,77.02) v1(43.48,68.86)
VCC_0V85: length 4.3
  TOP w0.147: 34.79,57.36 33.93,57.36 ; v1(35.23,58.08) 35.23,57.49 34.92,57.18 34.6,57.49 v1(34.6,58.08)
  TOP w0.254: 33.93,57.36 U56.25
VCC_1V8_FT4232: length 35.7
  TOP w0.254: 53.47,28.56 U64.12 53.47,25.09 ; 53.47,36.59 U64.37 C281.2 ; 44.19,35.85 U64.49 52.73,35.85 ; v1(47.15,28.35) U64.64
  TOP w0.305: 53.47,25.09 53.31,24.94 C280.2 ; v1(47.15,28.35) 48.43,28.35 49.1,29.02 49.1,33.34 50.14,34.38 53.07,34.38 54.92,32.54 54.92,30.01 53.47,28.56 ; 44.19,35.85 C263.1
  BOTTOM w0.147: C599.2 v1(47.15,28.35)
VCC_1V8_IOVDD: length 12.7
  TOP w0.254: v1(51.46,150.7) 51.49,150.67 C74.1 52.07,150.55 52.32,150.3 52.45,150.3 52.45,150.29 52.84,150.29 52.84,150.3 U7.27
  TOP w0.279: U8.27 46.93,147.52 46.93,147.52 47.32,147.52 ; C71.1 51.41,150.75 v1(51.46,150.7)
  TOP w0.305: R23.1 54.44,154.05 54.25,154.23 v1(54.25,154.51) ; C85.1 48.24,147.07 48.16,147.14 C84.1 47.69,147.16 47.33,147.52 47.32,147.52 ; R20.1 v1(52.31,154.65)
  BOTTOM w0.305: C340.1 U75.5 54.38,162.01 54.77,162.39 R413.2 ; v1(52.68,161.11) 52.55,160.98 R416.2
  BOTTOM w0.381: R416.2 C340.1
  vias: v1(46.99,143.13) v1(47.17,143.56)
VCC_3V3_AVDD: length 31.2
  TOP w0.254: 54.42,144.79 55.21,145.58 U7.3 ; U8.3 44.54,152.56 ; 45.85,151.38 45.54,151.08 U8.1 ; 52.69,146.44 53.83,146.44 54.21,146.82 U7.1
  TOP w0.305: v1(51.42,144.21) C98.1 52.05,144.53 52.46,144.93 C86.1 52.69,146.44 ; 44.54,152.56 45.34,153.35 L2.1 ; 54.42,144.79 L3.1 ; FL2.2 48.89,153.61 C52.1 47.7,153.24 47.3,152.83 C68.1 46.75,151.61 46.53,151.38 45.85,151.38
  L04_PWR1 w0.508: v1(48.89,154.65) v1(48.89,152.83) 48,152.83 47.45,152.27 47.45,151.05 48.36,150.14 48.36,147.29 49.61,146.05 49.61,145.15 50.55,144.21 v1(51.42,144.21)
VCC_3V3_FT4232: length 47.2
  TOP w0.254: U64.31 C289.2 ; U64.20 C288.2 ; C275.2 U64.42 ; C264.2 U64.56 ; U64.50 46.94,35.35
  TOP w0.305: v1(63.43,28.55) 63.43,29.54 63.12,29.85 C288.2 ; R333.2 44.65,27.26 v1(44.5,27.12) ; U66.1 49.62,11.95 C285.1 ; 46.94,35.35 47.24,35.04 47.24,34.77 v1(47.55,34.47) ; v1(51.59,39.62) 51.54,39.62 51.53,39.63 C275.2 ; C264.2 v1(43.5,32.35) 43.5,32.5 43.2,32.8 LD7.2 ; R328.2 43.18,29.04 v1(43.3,29.16) ; v1(43.32,19.72) C262.2 43.83,20.93 U61.8 ; R321.2 41.32,28.23 v1(41.03,28.51) ; C289.2 59.15,34.86 v1(58.85,34.56)
  BOTTOM w0.203: 53.72,28.42 U125.2 ; C618.2 62.59,28.27 U126.2 ; C575.2 36.63,32.57 U117.2
  BOTTOM w0.305: v1(41.03,28.51) 35.93,28.51 35.53,28.91 35.53,31.94 35.88,32.28 C575.2 ; C618.2 v1(63.43,28.55) 63.86,28.98 63.86,31.27 60.55,34.57 59.34,34.57 59.34,34.56 v1(58.85,34.56) ; C612.2 53.72,28.42
  vias: v1(48.86,12.34) v1(49.7,12.57)
VCC_3V3_SYS: length 397.8
  TOP w0.178: U3083.8 96.24,59.62 96.09,59.77 C3768.2 ; U39.8 18.2,102.86
  TOP w0.203: U29.1 92.56,60.09 92.68,60.22 ; U68.5 60.58,50.37 60.75,50.19 C293.1 ; U49.J10 97.96,75.2 v1(98.07,75.08) 98.1,75.05 U49.K9 v1(98.91,75.05) ; J19.44 114.04,43.66 C277.1 ; J18.46 82.01,42.91 81.84,43.08 ; v1(96.11,72.54) 96.46,72.88 U49.F5 96.46,73.46 v1(96.37,73.55) U49.E6 ; J18.44 81.61,43.58 ; J19.46 114.44,42.79 114.33,42.9 114.33,43.01 114.12,43.22 ; C3730.2 17.87,102.53 18.2,102.86
  TOP w0.254: 92.91,60.45 92.68,60.22 ; R343.2 76.04,46.84 76.47,47.27 v1(76.47,47.64) ; v1(54.33,138.13) 54.33,138.05 54.55,137.83 U18.23 ; U18.21 55.55,138.05 v1(55.47,138.13) ; U11.7 C99.1 ; 65.15,45.09 65.15,43.13
  TOP w0.279: C787.1 90.09,81.89 90.32,82.12 v1(90.4,82.12)
  TOP w0.305: v1(103.07,50.88) 105.4,50.88 106.76,52.23 106.76,61.98 v1(106.45,62.28) 105.94,62.79 FL23.2 ; v1(47.04,57.71) 46.47,57.71 46.13,58.04 44.52,58.04 44.07,58.5 44.04,58.5 43.74,58.8 v1(43.74,59.28) ; R5687.2 101.28,47.07 v1(101.21,46.99) ; R356.1 109.07,44.77 v1(109.24,44.94) 109.4,45.1 R351.2 ; v1(83.87,96.85) 83.67,96.65 R5742.1 ; v1(63.73,133.02) 63.73,134.48 64.03,134.78 R180.2 ; v1(54.33,138.13) 54.23,138.23 R98.2 ; R5759.2 v1(96.29,83.12) ; 81.61,43.58 81.39,43.8 C279.1 ; R440.2 60.59,129.71 v1(60.43,129.87) ; U25.1 C140.1 44.11,112.23 ; 92.91,60.45 C150.2 93.29,60.12 93.42,59.99 v1(93.42,59.92) ; C293.1 61.93,50.19 v1(62.48,49.63) 62.81,49.3 62.81,46.18 62.36,45.72 62.36,42.75 62.69,42.42 64.44,42.42 65.15,43.13 ; C3768.2 v1(95.66,60.55) ; C3660.1 85.62,77.85 v1(86.18,77.29) ; R5824.1 v1(62.08,47.9) ; U4.1 112.27,66.51 C33.2 112.28,65.25 C28.1 112.27,64.37 v1(112.52,64.11) ; v1(16.87,104.21) 16.9,104.24 R212.1 R211.1 ; R5688.2 58.05,49.06 v1(57.68,49.43) 56.79,49.43 55.78,48.41 54.14,48.41 53.12,49.43 R292.2 50.92,50 v1(50.63,50.29) ; R342.1 R343.2 ; v1(31.56,33.63) 29.95,35.24 v1(29.95,36.76) 30.35,37.16 v1(31.74,37.16) ; v1(105.54,46.96) 105.72,46.78 R344.1 ; R363.2 v1(59.9,51.95) R362.2 ; R58.1 v1(98.23,147.81) ; R56.1 v1(104.49,148.24) ; v1(29.07,40.23) 31.18,38.13 35.79,38.13 39.19,41.53 v1(39.19,41.96) ; R5735.2 36.65,122.09 36.65,122.1 v1(36.7,122.1) ; C99.1 v1(104.35,146.76) ; v1(86.06,69.44) C165.2 85.37,68.66 84.99,68.28 U3077.14 ; U2357.1 C3732.2 v1(79.58,97.63) ; v1(18.86,114.63) R5764.2 24.13,118.64 27.1,115.67 27.1,114.81 27.66,114.25 R482.1 ; C3730.2 v1(17.87,101.75) ; v1(35.54,113.7) 35.31,113.47 C169.1 J14.5 ; R5741.1 v1(82.48,107.95)
  TOP w0.381: U2357.1 79.04,101.21 79.74,101.9 83.36,101.9 83.87,102.41 83.87,106.55 v1(82.48,107.95) ; v1(90.4,82.12) 90.4,83.44 88.9,84.94 88.9,86.66 88.06,87.5 86.16,87.5 85.57,86.92 C3659.1 84.59,86.06 v1(84.51,86.13) ; C3698.1 95.91,104.05 95.75,104.21 v1(95.75,104.9) 95.75,106.06 J29.3
  L03_SIG1 w0.305: v1(62.08,47.9) 61.63,48.35 61.63,48.78 v1(62.48,49.63)
  L03_SIG1 w0.381: v1(37.74,50.75) 38.08,51.08 38.08,55.51 v1(37.4,56.18) ; v1(32.82,74.27) 32.82,73.63 v1(35.76,70.69) 36.1,70.36 36.1,67.06 v1(35.64,66.6) ; v1(29.39,82.52) 29.95,81.97 29.95,79.04 v1(29.59,78.69) 29.54,78.69 29.24,78.99 29.24,79.4 ; v1(47.75,53.95) 47.75,53.16 v1(50.63,50.29)
  L03_SIG1 w0.508: v1(117.54,42.61) 119.15,44.22 v1(119.15,47.33)
  L04_PWR1 w0.381: v1(45.54,67.56) 45.54,63.37 43.74,61.57 v1(43.74,59.28)
  L04_PWR1 w0.508: 43.89,37.77 43.87,37.8 v1(43.38,37.8)
  BOTTOM w0.178: U115.B1 38.14,51.38 38,51.25 38,51.01 v1(37.74,50.75)
  BOTTOM w0.203: U90.8 34.9,107.69 v1(35.2,108) ; v1(31.74,37.16) U123.C3 U123.B3 ; 43.74,58.8 43.74,57.81 44.52,57.03 U92.C3 ; U119.B1 40.34,42.77 40.03,43.07 40.03,43.49 40.64,44.09 U118.6 ; U120.5 102.58,47.55 102.4,47.37 C602.1 ; U118.2 42.14,41.57 42.43,41.86 42.43,42.56 42.22,42.77 U119.B3 ; U3081.B1 33.85,73.64 33.6,73.89 33.2,73.89 v1(32.82,74.27) ; v1(47.75,53.95) 47.75,54.33 47.88,54.46 47.88,55.83 47.55,56.15 47.56,56.16 47.56,56.39 47.78,56.61 47.78,57.01 47.78,57.02 47.78,57.18 47.52,57.44 47.31,57.44 v1(47.04,57.71) 47.04,57.61 46.86,57.43 U92.B1 ; v1(40.01,47.77) 39.51,48.27 U116.2 39.51,50.18 39.84,50.51 39.84,51.11 39.57,51.37 39.43,51.37 39.42,51.38 U115.B3 ; U110.2 25.1,83.37 24.91,83.18 C3724.2 ; U113.B1 v1(19.2,61.76) ; 47.02,68.17 U3078.6 47.02,66.04 47.22,65.84 47.52,65.84 47.81,65.55 47.81,65.39 U3080.B1 ; 29.11,37.12 29.47,36.76 v1(29.95,36.76) U123.B1
  BOTTOM w0.254: U57.30 90.38,82.13 ; C3724.2 24.29,83.18 24.06,82.94 24.06,81.92 25.36,80.62 28.27,80.62 29.39,81.74 v1(29.39,82.52) ; v1(33.05,113.64) 32.71,113.98 U87.5 ; v1(35.2,108) 35.56,108.36 35.56,109.5 34.59,110.46 ; U57.1 85.37,78.13 85.22,77.98 85.22,77.65 85.57,77.29 v1(86.18,77.29) ; v1(43.74,59.28) 43.74,58.8 44.22,58.32 44.61,58.32 44.86,58.58 U91.1 ; C3764.1 30.89,76.71 30.51,77.09 29.31,77.09 28.91,77.5 28.91,78.08 29.16,78.33 29.24,78.33 v1(29.59,78.69) ; v1(29.07,40.23) 29.54,40.23 29.81,39.97 U124.6 ; U88.5 C416.2 ; U3072.17 v1(95.75,104.9)
  BOTTOM w0.279: U57.17 v1(84.51,86.13) ; 90.38,82.13 v1(90.4,82.12)
  BOTTOM w0.305: v1(31.56,33.63) 31.56,32.37 30.89,31.7 28.63,31.7 27.51,30.58 27.51,28.73 27.95,28.28 27.95,28.23 28.45,27.74 28.58,27.74 R645.1 ; v1(31.56,33.63) 31.81,33.88 U124.1 ; v1(31.56,33.63) 31.31,33.88 U124.2 ; v1(37.4,56.18) 37.27,56.05 C560.1 37.27,55.11 38.01,54.37 U116.6 ; C122.2 55.44,138.09 v1(55.47,138.13) v1(54.33,138.13) ; v1(95.5,75.89) 95.3,75.7 C504.1 ; U124.6 29.81,38.34 29.49,38.02 29.49,38 29.11,37.62 29.11,37.12 ; v1(110.44,33.86) 110.28,34.02 R629.2 ; U118.6 40.64,45.98 40.49,46.13 40.16,46.13 39.9,46.38 C598.1 39.9,47.6 40.01,47.71 v1(40.01,47.77) ; C427.1 47.6,53.79 v1(47.75,53.95) ; U118.2 42.14,39.8 42.16,39.78 42.16,38.81 42.47,38.51 42.67,38.51 v1(43.38,37.8) ; C3727.2 35.06,108.14 v1(35.2,108) ; v1(119.15,47.33) 118.93,47.1 R347.1 ; R597.2 39.01,42.15 v1(39.19,41.96) ; C602.1 101.59,47.37 v1(101.21,46.99) 101.21,47.42 100.91,47.72 100.91,48.95 v1(100.48,49.38) 100.1,49.76 100.1,51 100.41,51.31 102.64,51.31 v1(103.07,50.88) 103.07,49.92 102.57,49.42 R602.2 R601.2 ; R5825.1 105.92,46.58 v1(105.54,46.96) ; v1(72.42,37.95) 72.42,38.38 72.72,38.68 R620.2 ; v1(35.64,66.6) 32.51,66.6 32.11,67.01 27.23,67.01 24.84,69.39 21.44,69.39 19.69,67.64 v1(18.7,67.64) 18.34,67.28 C525.1 18.34,65.35 18.6,65.1 18.93,65.1 19.08,64.95 U114.6 ; C416.2 v1(38.11,111.52) ; R616.2 v1(117.54,42.61) ; v1(111.89,37.97) 112.18,38.26 R625.2 ; v1(35.76,70.69) 36.25,70.69 36.51,70.95 R260.2 38.11,70.95 38.71,71.55 38.71,72.14 39.22,72.64 43.51,72.64 43.81,72.34 43.81,71.5 44.78,70.54 44.78,67.87 45.09,67.56 v1(45.54,67.56) C3762.1 46.71,68.48 47.02,68.17 ; R5215.1 v1(82.91,81.79) ; v1(32.82,74.27) 33.02,74.48 U3079.6 33.02,76.4 32.72,76.71 C3764.1 ; R641.2 v1(89,30.48) ; v1(115.44,35.51) 115.05,35.9 R630.2 ; R638.2 75.89,31.83 77.11,30.61 v1(78.15,30.61) R5777.1 ; v1(96.11,72.54) 96.2,72.46 C520.1 ; R485.2 v1(35.54,113.7) ; C604.1 v1(29.07,40.23)
  BOTTOM w0.381: v1(95.66,60.55) 95.5,60.55 95.12,60.17 R5843.1 ; v1(96.29,83.12) 96.29,84.38 92.94,87.73 85.45,87.73 84.51,86.79 v1(84.51,86.13) ; v1(38.11,111.52) v1(38.11,112.03)
  vias: v1(18.86,114.12) v1(18.86,113.61) v1(23.16,44.66) v1(23.16,44.15) v1(33.68,46.67) v1(33.68,46.03) v1(34.44,46.67) v1(34.44,46.03) v1(35.2,46.67) v1(35.2,46.03) v1(35.96,46.67) v1(35.96,46.03) v1(36.72,46.67) v1(36.72,46.03) v1(42.16,121.84) v1(42.54,121.59) v1(44.17,112.65) v1(44.17,112.17) v1(50.39,154.61) v1(50.39,152.81) v1(80.78,45.07) v1(80.77,44.46) v1(80.75,43.82) v1(85.86,159.43) v1(86.16,158.9) v1(86.31,159.93) v1(113.28,45.1) v1(113.28,44.6) v1(113.27,44.09)
VCC_3V3_SYS_CLK_BUF: length 10.9
  TOP w0.254: FL23.1 C3772.2 C3771.2 104.01,60.51 103.55,60.51 103.41,60.37 U3084.6 103.41,57.23 101.85,55.68 100.25,55.68 100.05,55.47 R5790.1
VCC_3V3_SYS_REG_SW: length 2
  TOP w0.254: U56.15 30.32,52.66 30.68,52.3
VCC_5V0: length 91.9
  TOP w0.203: U134.1 7.1,14.48 6.84,14.22
  TOP w0.254: v1(9.29,63.78) C3747.1 U3076.1 ; v1(33.43,54.84) 33.4,54.86 U56.20 ; 25.9,57.36 U56.3
  TOP w0.305: v1(31.17,57.76) 31.07,57.76 30.82,58.01 U56.30 ; U56.12 28.82,54.71 28.57,54.97 v1(28.47,54.97) ; v1(40.56,80.52) 40.56,80.59 40.72,80.75 U46.1 ; U56.16 30.82,54.71 31.07,54.97 v1(31.17,54.97) ; v1(28.47,57.76) 28.57,57.76 28.82,58.01 U56.34 ; R240.1 40.28,83.84 40.55,83.57 C197.1 ; v1(8.56,8.7) R3661.1 R3720.1 ; TP103.1 56.87,45.97 v1(57.15,46.25) ; 31.24,158.5 C3692.2 v1(32,158.41) 32.72,158.41 C3695.2 ; 24.79,57.18 24.77,57.2 21.82,57.2 20.62,56.01 R5774.1 ; C255.1 55.57,60.6 55.19,60.22 55.19,59.1 55.62,58.67 55.62,58.65 v1(55.6,58.65)
  TOP w0.33: U59.8 C255.1
  L03_SIG1 w0.147: v1(15.39,28.73) v1(15.39,29.49)
  L03_SIG1 w0.305: v1(15.39,28.73) 15.39,28.3 10.69,23.6 10.69,10.84 v1(8.56,8.7) ; v1(55.6,58.65) 55.62,58.65 55.62,57.07 54.74,56.18 54.74,53.75 56.13,52.35
  L04_PWR1 w0.381: v1(55.6,58.65) 55.62,58.65 55.62,58.67 54.61,58.67 51.99,56.06 51.99,55.52 51.13,54.66 47.12,54.66 46.79,54.33 39.85,54.33 38,52.48 34.79,52.48 33.68,53.58 33.68,53.67 ; v1(41.66,77.67) 41.2,78.12 41.2,78.51
  L04_PWR1 w0.508: v1(31.6,54.97) 31.7,54.86 32.87,54.86 32.89,54.84 v1(33.43,54.84)
  BOTTOM w0.203: U127.6 82.44,31.05 82.73,30.76 ; R543.1 49.35,85.55 v1(48.74,86.16)
  BOTTOM w0.305: C3643.1 40.15,81.98 v1(40.87,82.7) ; v1(35.96,23.21) 36.17,22.99 R665.1 ; R3725.1 v1(41.66,77.67)
  vias: v1(3.15,27.69) v1(3.9,118.12) v1(3.9,117.61) v1(3.91,27.69) v1(4.41,118.12) v1(4.41,117.61) v1(4.92,118.12) v1(4.92,117.61) v1(5.42,118.12) v1(5.42,117.61) v1(6.05,12.7) v1(6.05,12.19) v1(6.05,11.68) v1(6.05,11.18) v1(6.05,10.67) v1(6.05,10.16) v1(6.55,12.7) v1(6.55,12.19) v1(6.55,11.68) v1(6.55,11.18) v1(6.55,10.67) v1(6.55,10.16) v1(7.06,12.7) v1(7.06,12.19) v1(7.06,11.68) v1(7.06,11.18) v1(7.06,10.67) v1(7.06,10.16) v1(13.13,30.99) v1(13.13,30.23) v1(13.11,29.49) v1(13.11,28.73) v1(13.89,30.99) v1(13.89,30.23) v1(13.87,29.49) v1(13.87,28.73) v1(14.63,29.49) v1(14.63,28.73) v1(14.66,30.99) v1(14.66,30.23) v1(15.42,30.99) v1(15.42,30.23) v1(25.32,56.85) v1(25.43,57.58) v1(25.65,57.18) v1(25.88,57.63) v1(28.04,57.76) v1(27.99,57.28) v1(28.02,55.42) v1(28.04,54.97) v1(28.47,57.33) v1(28.47,55.4) v1(31.17,57.33) v1(31.17,55.4) v1(31.6,57.76) v1(31.6,57.3) v1(31.62,55.42) v1(33.6,158.52) v1(33.62,158.06) v1(39.65,19.09) v1(39.68,18.41) v1(39.68,17.65) v1(40.11,80.52) v1(40.52,19.09) v1(40.54,18.41) v1(40.54,17.65) v1(41.38,19.09) v1(41.41,18.41) v1(41.41,17.65) v1(41.48,81.31) v1(81.64,28.57) v1(81.67,27.9) v1(82.4,28.55) v1(82.42,27.89) v1(121.58,148.77) v1(121.58,148.27) v1(122.09,148.77) v1(122.09,148.27) v1(122.6,148.77) v1(122.6,148.27) v1(123.11,148.77) v1(123.11,148.27)
VCC_5V0_PG: length 77.2
  TOP w0.147: v1(9.27,59.77) 9.27,60.05 9.45,60.23 U54.3 ; U134.5 9.97,14.06 10.72,13.31 R3653.1 11.21,12.53 11.48,12.26 11.48,11.61 11.86,11.23 14.91,11.23 16.26,12.57 16.26,13.87 22.4,20.01 22.4,24.19 21.35,25.24 19.67,25.24 16.31,28.6 16.31,32.31 11.53,37.08 11.53,45.21 v1(9.68,47.07)
  L03_SIG1 w0.091: v1(9.68,47.07) 9.07,47.07 6.68,49.45 6.68,51.51 7.16,51.99 8.61,51.99 9.86,53.24 9.86,57.43 9.27,58.01 v1(9.27,59.77) 11.71,62.2 11.71,63.17 v1(12.12,63.58)
  BOTTOM w0.147: v1(12.12,63.58) 13.11,64.57 U86.3
VCC_CORE:
  vias: v1(24.35,65.46) v1(24.8,64.97) v1(25.27,66.27) v1(25.27,65.46) v1(27.3,65.61) v1(28.21,65.61) v1(28.65,66.04) v1(29.13,65.61) v1(30.21,65.61) v1(30.67,66.11) v1(31.12,65.61) v1(31.56,66.17) v1(32.03,65.61) v1(34.37,65.46) v1(35.29,65.46)
VCC_CORE_N: length 3.3
  TOP w0.152: v1(24.46,68.4) 25.25,68.4 R265.2
  BOTTOM w0.147: R572.2 23.43,68.41 23.77,68.07 24.13,68.07 v1(24.46,68.4)
VCC_CORE_P: length 3.3
  TOP w0.147: R265.3 25.54,67.97 25,67.97 v1(24.48,67.45)
  BOTTOM w0.147: R571.2 23.46,67.37 23.8,67.72 24.22,67.72 v1(24.48,67.45)
VDD_0V85_N: length 10.2
  BOTTOM w0.147: R581.1 41.64,64.27 41.88,64.52 42.65,64.52 43.1,64.06 43.1,61.65 42.14,60.68 40.29,60.68 39.6,59.99 39.6,59.12 R585.2
VDD_0V85_P: length 10.7
  BOTTOM w0.147: R584.2 39.95,59.09 39.95,59.84 40.44,60.33 42.28,60.33 43.45,61.5 43.45,64.2 42.79,64.87 41.78,64.87 41.64,65.01 R581.4
VDD_1V8_N: length 4.2
  TOP w0.147: R311.2 39.61,57.1 39.11,57.1 38.91,56.9 38.91,56.32 39.31,55.92 39.31,54.95 39.53,54.73 R316.4
VDD_1V8_P: length 4.8
  TOP w0.147: R310.2 39.57,57.45 38.96,57.45 38.56,57.05 38.56,56.18 38.96,55.78 38.96,54.91 38.78,54.73 R316.1
VDD_2V5: length 9.5
  TOP w0.203: J18.4 73.61,43.15 73.33,43.43 73.33,43.78 C278.1 ; J19.4 106.04,42.99 105.94,43.08 ; 106.44,42.92 J19.6 ; J18.6 74.01,42.96 73.58,43.38
  TOP w0.305: C273.1 105.82,45.66 105.62,45.85 TP92.1 ; 106.27,43.08 106.44,42.92
  BOTTOM w0.305: R634.1 79.24,32.41 78.93,32.11 v1(78.93,32.11) R637.2 78.92,31.53 78.47,31.53 v1(78.22,31.78) C615.1
  vias: v1(72.75,45.23) v1(72.78,44.28) v1(83.14,35.83) v1(84.03,35.83) v1(84.92,35.83) v1(85.81,35.83) v1(105.18,45.03) v1(105.18,44.23)
VDD_CANUART: length 0.9
  TOP w0.305: 40.67,78.33 40.81,78.19 R255.1
VDD_CANUART_ALERT: length 3.8
  BOTTOM w0.147: R5778.1 48.55,61.25 48.02,61.78 U3078.3 48.02,63.65 47.42,64.25 U3080.A3
VDD_CANUART_N: length 9.9
  TOP w0.147: R5786.1 44.93,76.25 44.68,76 44.68,75.06 v1(44.73,75.01)
  BOTTOM w0.147: R5780.2 46.13,70.67 45.27,70.67 44.24,71.69 44.24,74.14 43.83,74.55 43.81,74.55 43.56,74.8 43.56,75.21 43.81,75.46 44.27,75.46 v1(44.73,75.01)
VDD_CANUART_P: length 7.6
  TOP w0.147: v1(44.02,75.01) 44.33,75.32 44.33,76.09 44.17,76.25 R5786.4
  BOTTOM w0.147: R5781.2 46.13,71.02 45.41,71.02 44.59,71.83 44.59,74.43 v1(44.02,75.01)
VDD_CORE: length 97.7
  TOP w0.305: U136.G7 v1(62.1,81.66) ; U136.L12 v1(66.1,85.65) U136.L11 v1(66.1,84.85) ; U136.L12 v1(66.1,86.45) U136.M13 ; U136.L12 v1(65.3,86.45) U136.K13 ; U136.G14 v1(62.9,87.25) U136.H13 v1(63.7,86.45) U136.J12 v1(64.5,86.45) U136.K13 ; U136.K13 v1(65.3,87.25) ; U136.M9 v1(66.1,83.26) U136.L8 ; U136.L8 v1(65.3,82.46) U136.K7 ; U136.L8 v1(65.3,83.26) U136.K9 ; U136.L8 v1(66.1,82.46) U136.M7 v1(66.9,81.66) ; U136.P7 v1(68.5,81.66) ; U136.G11 v1(62.9,84.85) U136.H10 v1(62.9,84.06) U136.H9 v1(62.9,83.26) ; U136.P13 v1(67.7,87.25)
  L03_SIG1 w0.102: v1(41.86,59.82) 41.5,60.17 40.39,60.17 40.27,60.05 38.3,60.05 37.89,60.46 31.4,60.46 31.05,60.11 26.76,60.11 24.43,57.78 23.98,57.78 23.27,57.07 v1(23.27,56.64)
  L04_PWR1 w0.102: v1(41.86,59.82) 42.29,60.25 42.29,62.31 43.84,63.86 43.84,68.45 49.61,74.22 52.15,74.22 55.19,77.27 55.19,79.71 56.75,81.26 61.49,81.26 61.7,81.06 61.7,80.67 61.91,80.46 65.03,80.46 65.84,79.65 67.89,79.65 68.1,79.86 68.1,80.26 68.29,80.46 68.78,80.46 68.99,80.67 68.99,81.17 v1(68.5,81.66) ; v1(66.1,86.45) 66.1,86.7 66.65,87.25 66.7,87.25
  L04_PWR1 w0.127: 66.5,81.69 66.5,81.89 66.32,82.07 65.91,82.07
  L04_PWR1 w0.132: 67.64,80.46 67.89,80.46 68.1,80.66 68.1,80.77
  L04_PWR1 w0.305: v1(66.1,82.46) v1(65.3,82.46) ; v1(66.1,83.26) v1(65.3,83.26) ; v1(66.1,86.45) v1(66.1,85.65) v1(66.1,84.85) ; v1(68.5,81.66) 68.1,81.26 68.1,81.2 ; 66.52,81.2 66.9,81.58 v1(66.9,81.66)
  L04_PWR1 w0.381: v1(67.7,87.25) 66.71,87.25 66.7,87.25
  BOTTOM w0.203: v1(23.27,56.64) 23.36,56.64 23.62,56.39 R5828.1
  BOTTOM w0.254: C445.1 68.31,81.47 v1(68.5,81.66) 68.32,81.83 C477.1
  BOTTOM w0.305: v1(65.3,83.26) 65.3,83.73 C658.1 ; v1(65.3,86.45) 65.24,86.4 C468.1 ; C3752.1 65.98,83.38 v1(66.1,83.26) ; v1(66.1,84.85) 66.1,85.18 C663.1 66.16,85.6 v1(66.1,85.65) ; v1(67.7,87.25) 67.58,87.37 C662.1 ; v1(66.1,86.45) 65.93,86.29 C460.1 ; C441.1 63.08,83.07 v1(62.9,83.26) ; v1(62.9,84.85) 63,84.95 C462.1 ; C659.1 62.69,83.85 v1(62.9,84.06) ; C660.1 65.19,82.35 v1(65.3,82.46) ; C448.1 62.69,87.46 v1(62.9,87.25) ; C3661.1 67.1,81.45 v1(66.9,81.66) ; C3751.1 62.11,81.67 v1(62.1,81.66) ; C494.1 65.3,87.12 v1(65.3,87.25) ; v1(64.5,86.45) 64.38,86.57 C657.1
  vias: v1(25.88,71.46) v1(25.88,70.77) v1(25.88,70.11) v1(26.67,71.46) v1(26.67,70.77) v1(26.67,70.11) v1(27.68,71.46) v1(27.68,70.77) v1(27.68,70.11) v1(28.7,71.46) v1(28.7,70.77) v1(28.7,70.11) v1(29.71,71.46) v1(29.71,70.77) v1(29.71,69.78) v1(29.71,69.1) v1(30.73,71.46) v1(30.73,70.77) v1(30.73,69.78) v1(30.73,69.1) v1(40.23,95.53) v1(40.34,95.99) v1(40.79,95.96) v1(40.79,95.5) v1(41.25,95.96) v1(41.25,95.5) v1(42.68,93.23) v1(43.16,93.23) v1(43.43,92.79) v1(43.43,92.15) v1(73.96,92.84) v1(74.04,91.97) v1(74.04,91.34) v1(74.19,93.5) v1(74.52,92.68) v1(75.16,92.68)
VDD_CORE_ALERT: length 3.1
  BOTTOM w0.147: R586.1 U114.3 20.08,60.64 20.48,61.04 U113.A3
VDD_CORE_N: length 9.1
  BOTTOM w0.147: U113.D2 U113.D1 19.68,62.74 20.08,63.14 U114.8 20.08,65.05 20.31,65.28 ; 20.31,65.28 20.34,65.31 C524.2 20.34,66.53 20.65,66.85 20.65,67.34 21.41,68.1 22,68.1 R572.1 ; 20.31,65.28 20.58,65.02 U114.9
VDD_CORE_P: length 7
  BOTTOM w0.147: R571.1 22.03,67.75 21.56,67.75 21,67.19 21,66.85 21.32,66.53 C524.1 21.32,65.49 21.08,65.25 21.08,64.16 U114.10 21.08,63.16 U113.D3
VDD_CORE_REG_SW1: length 1.5
  TOP w0.254: 29.08,60.02 29.32,59.78 U56.33
VDD_CORE_REG_SW2: length 1.7
  TOP w0.254: 30.58,60.15 30.32,59.89 U56.31
VDD_MMC0_SD: length 1.6
  TOP w0.305: C93.2 122.32,76.61 122.35,76.64 122.35,77.05 TP21.1
  vias: v1(112.12,74.93) v1(112.67,74.9) v1(121.43,75.7) v1(121.77,76.07)
VDDA1V8: length 9.2
  TOP w0.254: 33.24,54.36 U56.19
  TOP w0.305: R316.2 38.36,51.56 38.67,51.24 38.67,50.15 39.12,49.71 v1(41.1,49.71) v1(41.1,49.17)
  BOTTOM w0.381: v1(64.95,54.64) 64.67,54.92 FL10.2 64.23,55.77 C290.1
VDDA_1V8: length 38.6
  TOP w0.305: C483.1 73.74,69.14 74.24,68.63 74.24,67.36 73.56,66.67 v1(73.13,66.67)
  L03_SIG1 w0.381: v1(63.93,68.12) v1(63.93,67.64) 63.93,65.58 63.27,64.92 55.5,64.92 55.07,65.35 55.07,66.75 58.1,69.78 v1(58.1,77.65)
  L04_PWR1 w0.254: v1(40.74,52.55) v1(41.38,52.55)
  BOTTOM w0.381: v1(63.93,67.64) 63.93,67.64 63.96,67.61 FL20.1 FL22.1 ; FL6.1 69.03,74.93 69.44,74.52 69.44,73.51 69.82,73.13 71.64,73.13 71.88,73.37
  vias: v1(40.74,53.54) v1(40.74,53.04) v1(41.38,53.54) v1(41.38,53.04) v1(72.39,73.69) v1(72.57,73.2) v1(72.97,66.24) v1(109.86,56.46) v1(109.88,55.98)
VDDA_1V8_ALERT: length 3.1
  BOTTOM w0.147: U119.A3 42.04,42.03 41.64,41.63 U118.3 R608.1
VDDA_1V8_FB1: length 16
  TOP w0.305: U136.J9 v1(63.7,83.26) ; U136.J10 v1(63.7,84.06) ; U136.M11 v1(66.9,85.65)
  L03_SIG1 w0.127: v1(63.7,84.06) 64.09,83.66 64.09,82.24 64.28,82.05 67.16,82.05 67.3,82.19 67.3,84.22 67.06,84.46 66.65,84.46 66.5,84.61 U136.M11 v1(66.9,85.65)
  L04_PWR1 w0.127: 67.34,86.69 67.5,86.86 68.02,86.86
  L04_PWR1 w0.132: 68,86.11 67.94,86.06 67.49,86.06 67.41,86.13 ; 68.1,86.79 68.02,86.87 68.02,86.86
  L04_PWR1 w0.305: v1(66.9,85.65) 66.9,85.77 67.13,86
  BOTTOM w0.305: C501.1 63.9,83.06 v1(63.7,83.26) v1(63.7,84.06) 63.7,84.33 C485.1 ; v1(66.9,85.65) 66.8,85.75 C463.1 ; v1(76.71,71.58) FL13.2
VDDA_1V8_FB2: length 13.3
  TOP w0.305: U136.K5 v1(64.5,80.06) ; v1(67.7,85.65) U136.N11
  L04_PWR1 w0.127: 67.31,82.25 67.31,82.09 67.28,82.07 ; 67.29,83.78 67.29,84.69 67.29,85.25 66.71,85.25 66.5,85.04 66.5,83.64 ; v1(67.7,85.65) 68.1,85.25 68.1,84.68 67.87,84.45 67.51,84.45 ; 66.67,82.85 66.7,82.85 ; 68.12,82.27 67.91,82.06 67.29,82.06 67.28,82.07 ; 67.28,82.07 67.28,82.06 66.71,82.06 66.5,82.27 66.5,82.68
  L04_PWR1 w0.132: 66.85,82.85 66.7,82.85 66.5,83.06 66.5,83.64 66.6,83.74 66.5,83.85 ; 67.28,83.77 67.29,83.78 ; 66.5,82.68 66.67,82.85
  L04_PWR1 w0.305: 64.49,79.55 64.5,79.56 v1(64.5,80.06) ; 67.29,85.25 v1(67.7,85.65)
  BOTTOM w0.305: C3656.1 64.55,80 v1(64.5,80.06) ; C467.1 67.52,85.83 v1(67.7,85.65)
  BOTTOM w0.381: FL6.2 v1(67.41,75.77)
VDDA_1V8_FB3: length 6.7
  TOP w0.305: U136.H7 v1(62.9,81.66)
  L03_SIG1 w0.127: 62.5,79.36 62.5,81.26 v1(62.9,81.66) 63.3,81.26 63.3,79.36
  BOTTOM w0.305: v1(62.9,81.66) 63.24,81.66 C3647.1 ; FL20.2 63.04,66.38 v1(63.2,66.22)
VDDA_1V8_FB4: length 6
  TOP w0.305: v1(67.7,84.06) U136.P10
  L04_PWR1 w0.132: 69.75,84.45 68.3,84.45 67.9,84.06 v1(67.7,84.06) 68.1,83.66 69.75,83.66
  BOTTOM w0.305: v1(67.7,84.06) 67.89,84.24 C3649.1 ; v1(70.69,74.47) 70.46,74.25 FL21.2
VDDA_1V8_FB_OSC: length 3.8
  TOP w0.305: U136.F5 v1(61.3,80.06)
  BOTTOM w0.254: 60.38,79.63 59.88,79.63 59.68,79.43 59.11,79.43
  BOTTOM w0.305: 60.38,79.63 60.8,80.06 v1(61.3,80.06) 61.01,79.77 C508.1
VDDA_1V8_N: length 17
  TOP w0.147: R311.1 v1(41.58,56.69)
  BOTTOM w0.147: v1(41.58,56.69) 42.01,57.12 42.22,57.12 42.47,56.87 42.47,56.48 42.37,56.38 42.37,49.22 42.19,49.04 42.19,47.29 C597.2 41.9,46.31 41.91,46.3 ; 41.91,46.3 42.14,46.07 U118.9 ; 41.91,46.3 41.64,46.02 U118.8 U119.D2 U119.D1
VDDA_1V8_P: length 16.2
  TOP w0.147: R310.1 v1(41.56,57.91)
  BOTTOM w0.147: U119.D3 42.64,44.17 U118.10 42.64,46.1 42.88,46.34 C597.1 42.54,47.33 42.54,48.89 42.72,49.07 42.72,56.24 42.82,56.34 42.82,57.01 42.36,57.47 42.01,57.47 41.58,57.91 v1(41.56,57.91)
VDDA_ADC0: length 2
  TOP w0.305: U136.J5 v1(64.5,80.86)
  L03_SIG1 w0.254: 64.69,80.54 64.5,80.74 v1(64.5,80.86)
  BOTTOM w0.305: FL22.2 v1(65.13,67.92) ; C3652.1 64.59,80.94 v1(64.5,80.86)
VDDA_CORE_USB: length 4.7
  TOP w0.305: U136.N10 v1(66.9,84.85)
  L03_SIG1 w0.127: 68.28,85.24 68.26,85.26 67.3,85.26 v1(66.9,84.85) 67.11,84.85 67.51,84.45 67.97,84.45
  L03_SIG1 w0.132: 69.01,84.45 67.97,84.45
  BOTTOM w0.305: C3767.1 66.7,84.66 v1(66.9,84.85)
  vias: v1(73,92.89)
VDDA_SYS_MON: length 15.5
  TOP w0.305: U136.H8 v1(62.9,82.46)
  BOTTOM w0.132: 55.19,83.29 57.96,83.29 58.33,83.65 59.06,83.65 59.29,83.42 59.29,83.1 59.53,82.86 60.65,82.86 60.89,82.62 60.89,82.3 61.13,82.06 62.13,82.06 C449.2
  BOTTOM w0.147: 55.19,83.29 52.6,83.29 51.91,83.98 R545.1 R543.2
  BOTTOM w0.254: C449.2 62.86,82.46 v1(62.9,82.46)
VDDC_1V2: length 23.5
  TOP w0.147: C240.1 28.55,76.9 v1(28.55,76.45)
  TOP w0.203: v1(20.78,85.01) U48.87 ; C240.1 28.33,77.74 C233.1 28.33,78.76 U48.115
  L03_SIG1 w0.102: v1(20.68,77.29) 21.44,78.05 21.44,82.55 21.74,82.85 21.74,83.74 21.56,83.92 21.18,83.92 21.11,83.85 20.7,83.85 20.42,84.12 20.42,84.65 v1(20.78,85.01)
  BOTTOM w0.147: 20.76,84.99 v1(20.78,85.01)
  BOTTOM w0.203: C516.2 20.76,84.99
  BOTTOM w0.305: v1(20.68,77.29) 22,77.29 23.52,75.77 27.86,75.77 v1(28.55,76.45)
VDDIM: length 3.9
  TOP w0.081: 94.71,70.74 94.71,71.3 U49.C2 95.2,71.3 95.2,70.74 v1(94.96,70.49) 94.71,70.74
  BOTTOM w0.254: C521.1 v1(94.96,70.49) 94.74,70.28 C527.1
VDDR_CANUART: length 4.4
  TOP w0.305: U136.E7 v1(60.5,82.46)
  BOTTOM w0.305: R3731.2 57.65,81.51 57.9,81.76 59.08,81.76 59.26,81.94 C3653.1 60.5,82.45 v1(60.5,82.46)
VDDR_CORE: length 14.8
  TOP w0.305: U136.H12 v1(62.9,86.45) ; TP60.1 41.1,63.72 40.84,63.47 v1(40.84,63.01) ; U136.N8 v1(66.9,82.46) ; U136.J8 v1(64.5,83.26) ; v1(66.9,88.05) U136.M14 ; U136.G10 v1(62.1,84.85) ; U136.N12 v1(67.7,86.45) ; v1(66.9,84.06) U136.M10 ; U136.K10 v1(64.5,84.06)
  L03_SIG1 w0.127: 63.3,87.45 63.5,87.66 63.93,87.66 64.08,87.5 64.13,87.55 64.16,87.55 64.26,87.65 64.73,87.65 64.81,87.58 ; 61.54,84.45 60.96,84.45
  L03_SIG1 w0.305: v1(62.1,84.85) 62.1,85.57 62.58,86.05 ; 66.5,83.64 66.9,84.04 v1(66.9,84.06) ; 66.54,82.79 66.88,82.46 v1(66.9,82.46) ; v1(67.7,86.45) 67.7,86.58 67.51,86.77 ; v1(64.5,83.26) v1(64.5,84.06)
  BOTTOM w0.305: R272.1 42.65,71.78 42.75,71.88 v1(42.8,71.88) ; C3758.1 64.59,83.16 v1(64.5,83.26) ; v1(66.9,84.06) 67.01,83.94 C493.1 ; v1(64.5,84.06) 64.62,84.18 C466.1 ; C490.1 66.74,88.22 v1(66.9,88.05) ; C447.1 62.81,86.37 v1(62.9,86.45) ; C465.1 v1(67.7,86.45) ; C3759.1 62.1,85.05 v1(62.1,84.85) ; v1(66.9,82.46) 67.11,82.24 C505.1
  vias: v1(40.13,63.02) v1(40.16,62.39) v1(40.85,62.4) v1(42.75,70.15) v1(42.75,69.67) v1(42.75,69.19) v1(54.53,84.51) v1(55.02,84.51) v1(55.5,84.51)
VDDR_CORE_ALERT: length 3.1
  BOTTOM w0.147: R596.1 U116.3 39.01,50.24 39.41,50.64 U115.A3
VDDR_CORE_N: length 7.7
  BOTTOM w0.147: R585.1 39.58,57.34 39.58,56.47 39.27,56.15 C559.2 39.27,55 39.24,54.98 ; 39.24,54.98 39.01,54.74 U116.8 U115.D2 U115.D1 ; 39.24,54.98 39.51,54.71 U116.9
VDDR_CORE_P: length 6.3
  BOTTOM w0.147: U115.D3 39.41,52.29 39.67,52.55 39.9,52.55 40.01,52.65 40.01,52.76 40.01,52.76 U116.10 40.01,54.78 40.25,55.02 C559.1 40.25,56.15 39.93,56.47 39.93,57.33 R584.1
VDDSHV_CANUART: length 194
  TOP w0.305: R326.1 v1(42.38,35.77) R322.1 ; v1(32.69,147.7) 32.69,147.96 29.01,151.64 R5692.2 v1(29.01,155.42) ; v1(42.77,39.42) 42.6,39.42 42.49,39.32 R371.1 ; v1(31.91,160.04) 31.86,159.99 31.72,159.99 31.24,159.5 ; U54.5 v1(11.23,60.73) 11.96,60.73 12.22,60.98 TP80.1 12.22,62.51 11.81,62.92 11.73,62.84 11.73,62.74 11.43,62.43 10.34,62.43 10.06,62.71 v1(9.63,62.71) ; v1(35.6,35.45) 37.41,35.45 37.57,35.62 v1(38.14,35.62) ; R3653.2 10.72,11.02 11.32,10.41 15.65,10.41 17.7,12.47 17.7,14.17 18.24,14.71 18.77,14.71 23.11,19.05 23.11,24.13 17.12,30.12 17.12,34.41 15.09,36.44 15.09,45.47 v1(15.39,45.77) 15.11,46.05 R5736.2 ; U3070.5 57.45,124.37 57.84,123.99 57.84,121.21 57.53,120.9 56.41,120.9 56.11,121.21 55.67,121.21 55.53,121.36 C3740.2 53.02,122.03 52.7,122.35 v1(52.27,122.35) 52.15,122.22 R5756.1 ; U2356.8 C3731.1 18.41,51 v1(18.59,50.83) 18.7,50.71 R5737.2 ; v1(12.7,52.98) 12.7,52.73 12.69,52.73 R318.2
  TOP w0.381: v1(44.3,82.73) v1(43.84,82.73)
  L03_SIG1 w0.381: v1(31.91,160.04) 31.44,160.04 31.11,159.71 31.11,157.53 v1(29.01,155.42) ; v1(39.62,66.55) 48.03,66.55 49.56,68.07 49.58,68.07 v1(49.61,68.1)
  L04_PWR1 w0.305: v1(42.77,39.42) 41.81,40.39 v1(41.81,50.83)
  L04_PWR1 w0.381: 42.6,50.52 42.29,50.83 v1(41.81,50.83)
  BOTTOM w0.197: U3091.8 50.23,68.57 C3780.2
  BOTTOM w0.203: C574.2 36.63,32.97 U117.3
  BOTTOM w0.254: C3780.2 50.09,68.58 v1(49.61,68.1)
  BOTTOM w0.305: v1(43.84,82.73) 43.57,82.46 C3644.2 U135.1 ; v1(43.84,82.73) v1(44.3,82.73) 44.73,82.73 45.05,82.41 R3723.1 ; v1(43.84,82.73) 43.41,82.73 43.36,82.78 41.73,82.78 41.68,82.83 41.63,82.83 41.43,83.03 41.43,83.24 41.12,83.54 39,83.54 38.02,82.57 38.02,78.97 38.67,78.32 v1(39.34,78.32) R3726.2 ; v1(12.7,52.98) 13.22,52.98 13.26,53.03 16.39,53.03 v1(18.59,50.83) 18.59,48.97 v1(15.39,45.77) ; R643.1 9.43,62.52 v1(9.63,62.71) 10.19,63.27 10.19,66.57 12.83,69.22 20.55,69.22 21.49,70.15 25.07,70.15 25.65,69.57 25.96,69.57 27.58,67.94 32.46,67.94 32.74,67.67 37.13,67.67 38.3,66.5 v1(38.73,66.5) ; R593.1 38.67,36.56 38.55,36.44 R592.1 38.25,35.72 v1(38.14,35.62) ; v1(11.23,60.73) 11.23,60.73 C538.1 ; R590.2 35.68,35.54 v1(35.6,35.45) 34.7,35.45 34.24,34.99 34.24,33.85 34.84,33.25 35.8,33.25 C574.2
  vias: v1(31.94,159.48) v1(44.32,82.22)
VDDSHV_CANUART_ALERT: length 3.5
  BOTTOM w0.147: R5782.1 U3079.3 34.02,71.82 33.45,72.39 U3081.A3
VDDSHV_CANUART_N: length 2
  BOTTOM w0.147: R5787.1 34.39,80.57 34.57,80.39 34.57,79.63 R5784.2
VDDSHV_CANUART_P: length 2
  BOTTOM w0.147: R5787.4 35.16,80.57 34.92,80.34 34.92,79.66 35.35,79.23 R5785.2
VDDSHV_CANUART_PG: length 2.5
  BOTTOM w0.147: U135.5 41.12,80.24 40.63,79.74 C3642.1 R3726.1
VDDSHV_SDIO: length 134
  TOP w0.254: 34.9,55.36 U56.21 ; U10.10 117.6,78.2
  TOP w0.305: 117.6,78.2 C103.2 115.46,78.32 115.07,77.94 R66.2 115.08,77.32 R64.2 115.07,76.39 R55.2 115.07,74.96 v1(114.82,74.7) ; 34.9,55.36 C246.1 35.21,55.67 35.21,56.15 v1(35.18,56.18) ; R54.2 R57.2 R65.2 v1(120.13,77.58)
  L03_SIG1 w0.381: v1(115.6,62.76) 115.06,62.76 113.11,64.72 113.11,67.49 117.17,71.55 118.24,71.55 120.4,73.71 120.4,77.32 v1(120.13,77.58)
  L04_PWR1 w0.381: v1(120.13,77.58) 120.13,78.65 119.38,79.4 115.95,79.4 114.82,78.26 v1(114.82,74.7) ; v1(56.79,64.31) 55.78,64.31 54.84,65.25 53.09,65.25 49.56,61.72 49.02,61.72 48.44,61.14 48.44,60.66 44.71,56.93 43.49,56.93 41.77,55.22 36.68,55.22 35.71,56.18 v1(35.18,56.18) v1(34.54,56.18)
  BOTTOM w0.381: v1(115.6,62.76) 113.27,60.44 105.06,60.44 104.34,61.16 88.04,61.16 87.5,60.63 85.57,60.63 82.37,63.83 79.48,63.83 77.91,65.39 70.53,65.39 69.88,64.74 57.23,64.74 v1(56.79,64.31)
VINT_LDO: length 3
  TOP w0.147: U56.7 25.97,55.36 25.76,55.57 TP74.1 25.15,55.69 C249.1
ADC0_AIN0: length 73.7
  TOP w0.147: v1(57.7,59.94) 57.7,60.3 57.93,60.53 R5720.2
  BOTTOM w0.147: J31.1 119.98,63.21 119.53,62.76 119.53,61.36 119.17,60.99 U2349.1 U2349.10 116.7,60.99 114.53,58.83 107.85,58.83 105.14,56.12 98.69,56.12 97.01,57.8 91.64,57.8 90.31,56.47 88.85,56.47 87.82,57.49 82.94,57.49 82.47,57.02 80.62,57.02 80.32,56.72 76.3,56.72 72.12,60.9 66.08,60.9 65.19,60.01 61.3,60.01 61.04,60.27 60.27,60.27 59.67,59.67 57.97,59.67 v1(57.7,59.94)
ADC0_AIN0_R: length 17.6
  TOP w0.132: U136.F1 61.7,75.95
  TOP w0.147: R5720.1 57.93,63.22 v1(57.7,63.45) 61.7,67.45 61.7,69.62 62.23,70.15 62.23,74.14 61.7,74.68 61.7,75.95
  BOTTOM w0.147: C3710.1 v1(57.7,63.45)
ADC0_AIN1: length 69.6
  TOP w0.147: R5721.2 v1(60.63,59.82)
  BOTTOM w0.147: v1(60.63,59.82) 60.99,59.82 61.14,59.66 65.35,59.66 66.24,60.55 71.81,60.55 75.99,56.37 80.63,56.37 80.92,56.67 82.63,56.67 83.1,57.14 87.67,57.14 88.69,56.12 90.45,56.12 91.79,57.45 96.85,57.45 98.55,55.75 105.28,55.75 107.95,58.42 114.76,58.42 116.83,60.49 U2349.9 U2349.2 119.96,60.49 120.14,60.67 J31.3
ADC0_AIN1_R: length 16.9
  TOP w0.132: 63.3,76.61 U136.H1
  TOP w0.147: 63.3,76.61 64.01,75.9 64.01,74.85 63.12,73.96 63.12,68.99 62.76,68.63 62.76,67.44 60.63,65.3 R5721.1 v1(59.84,63.58)
  BOTTOM w0.147: R5721.1 v1(59.84,63.58)
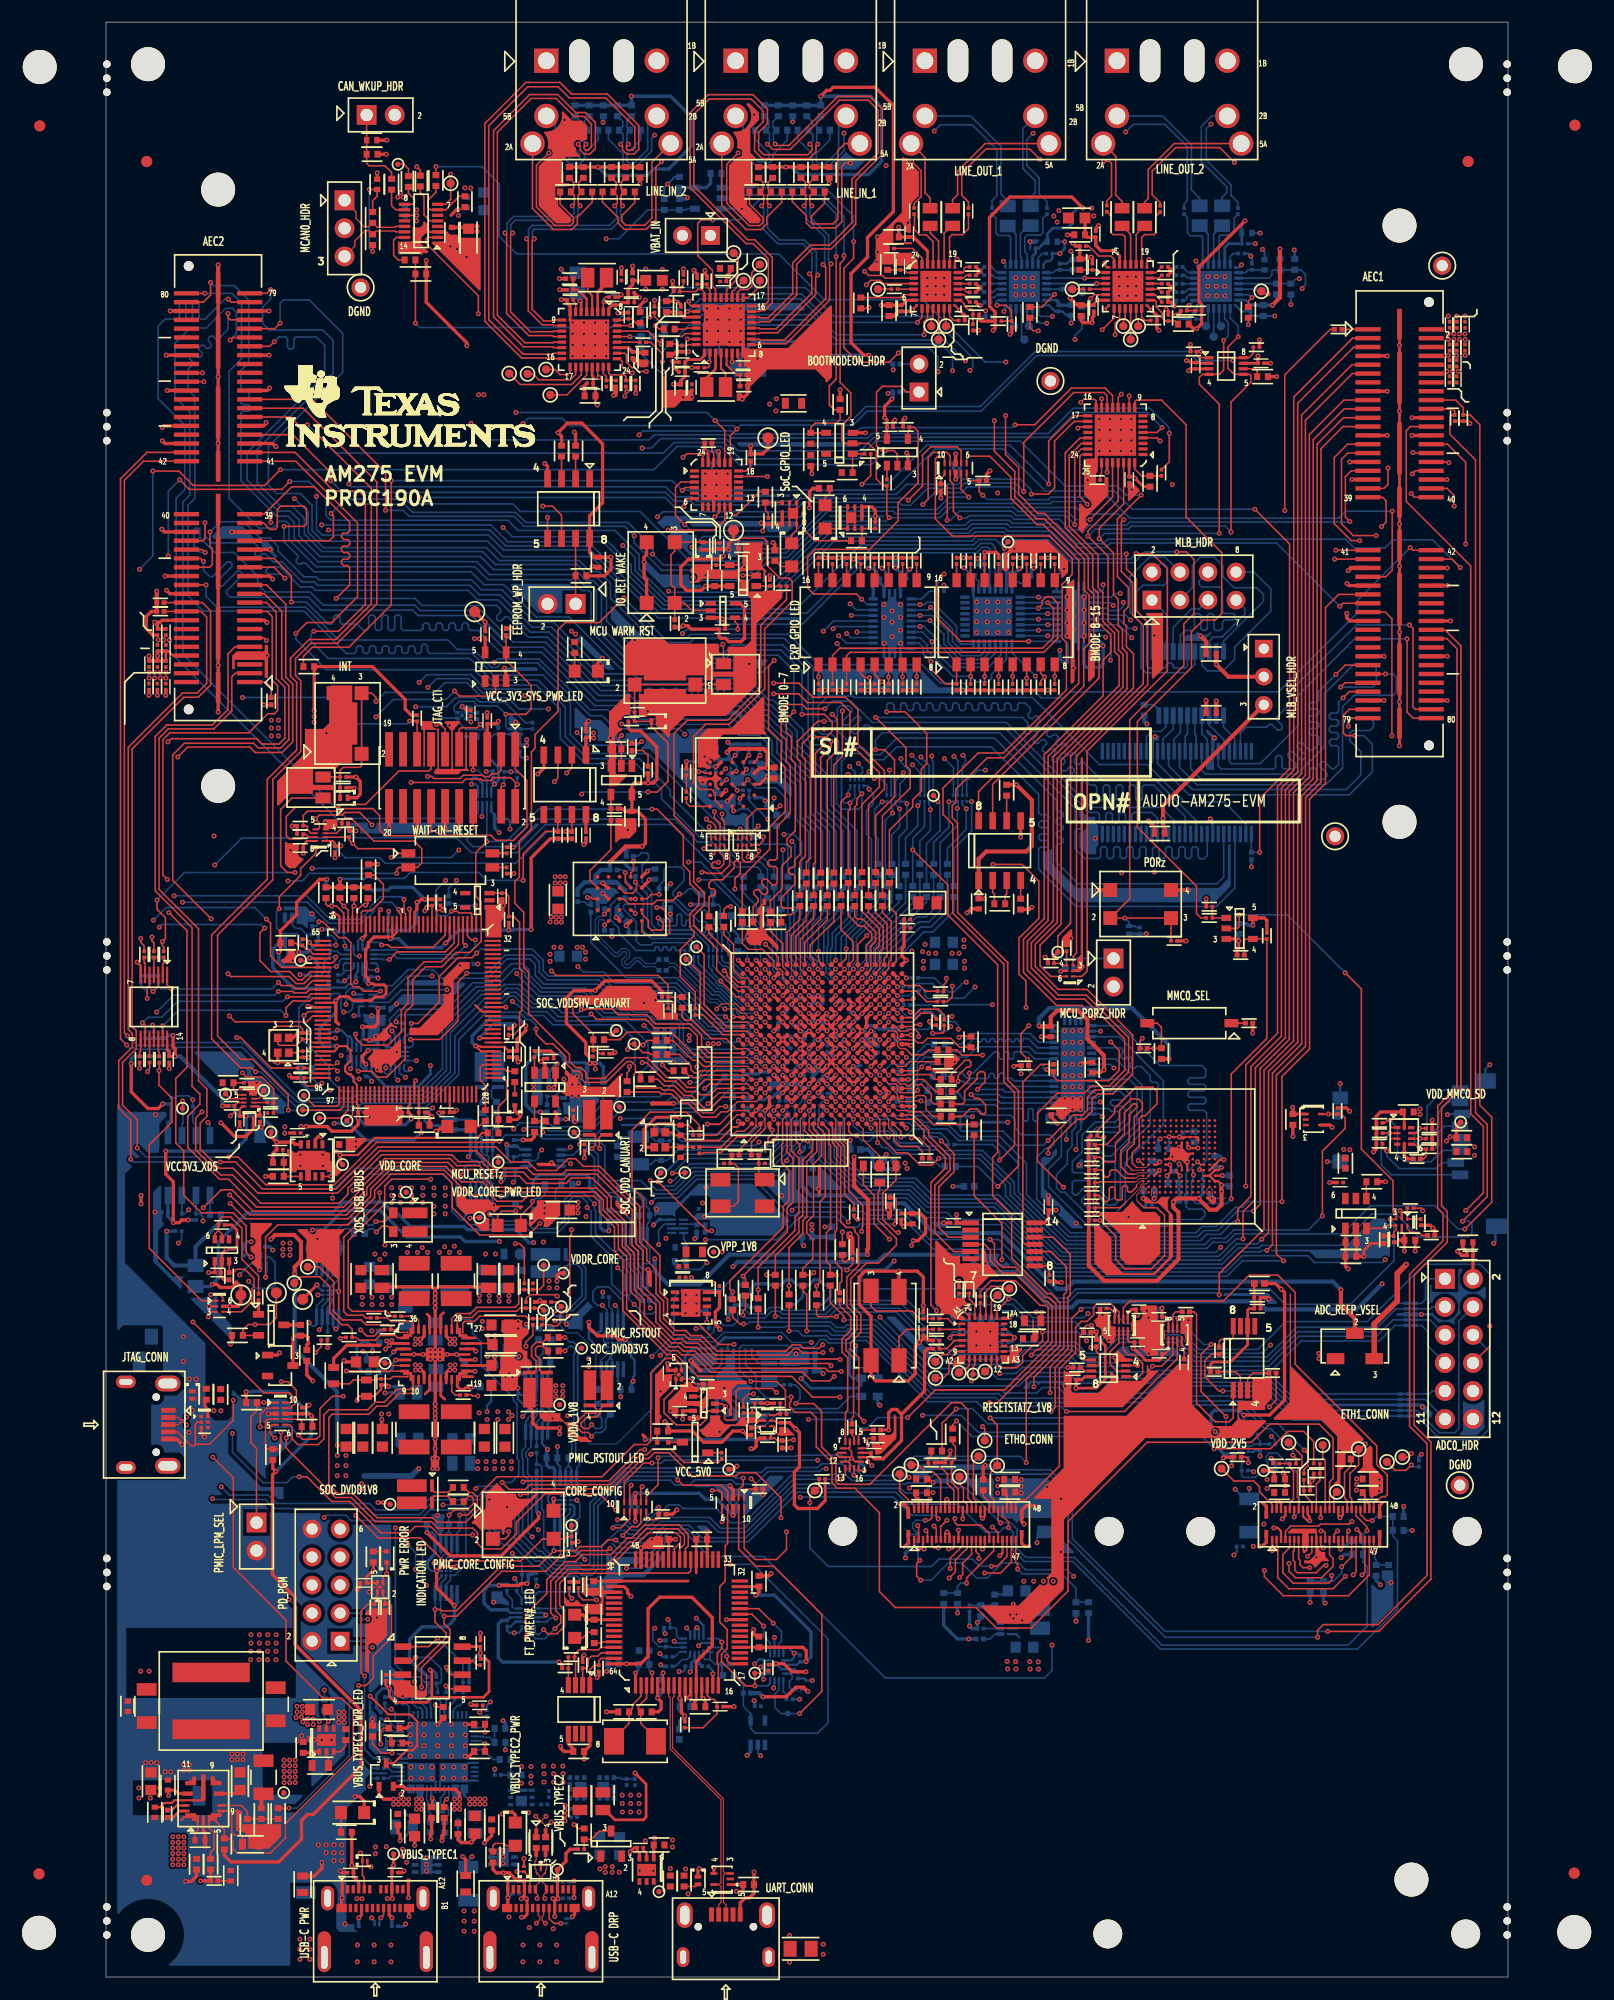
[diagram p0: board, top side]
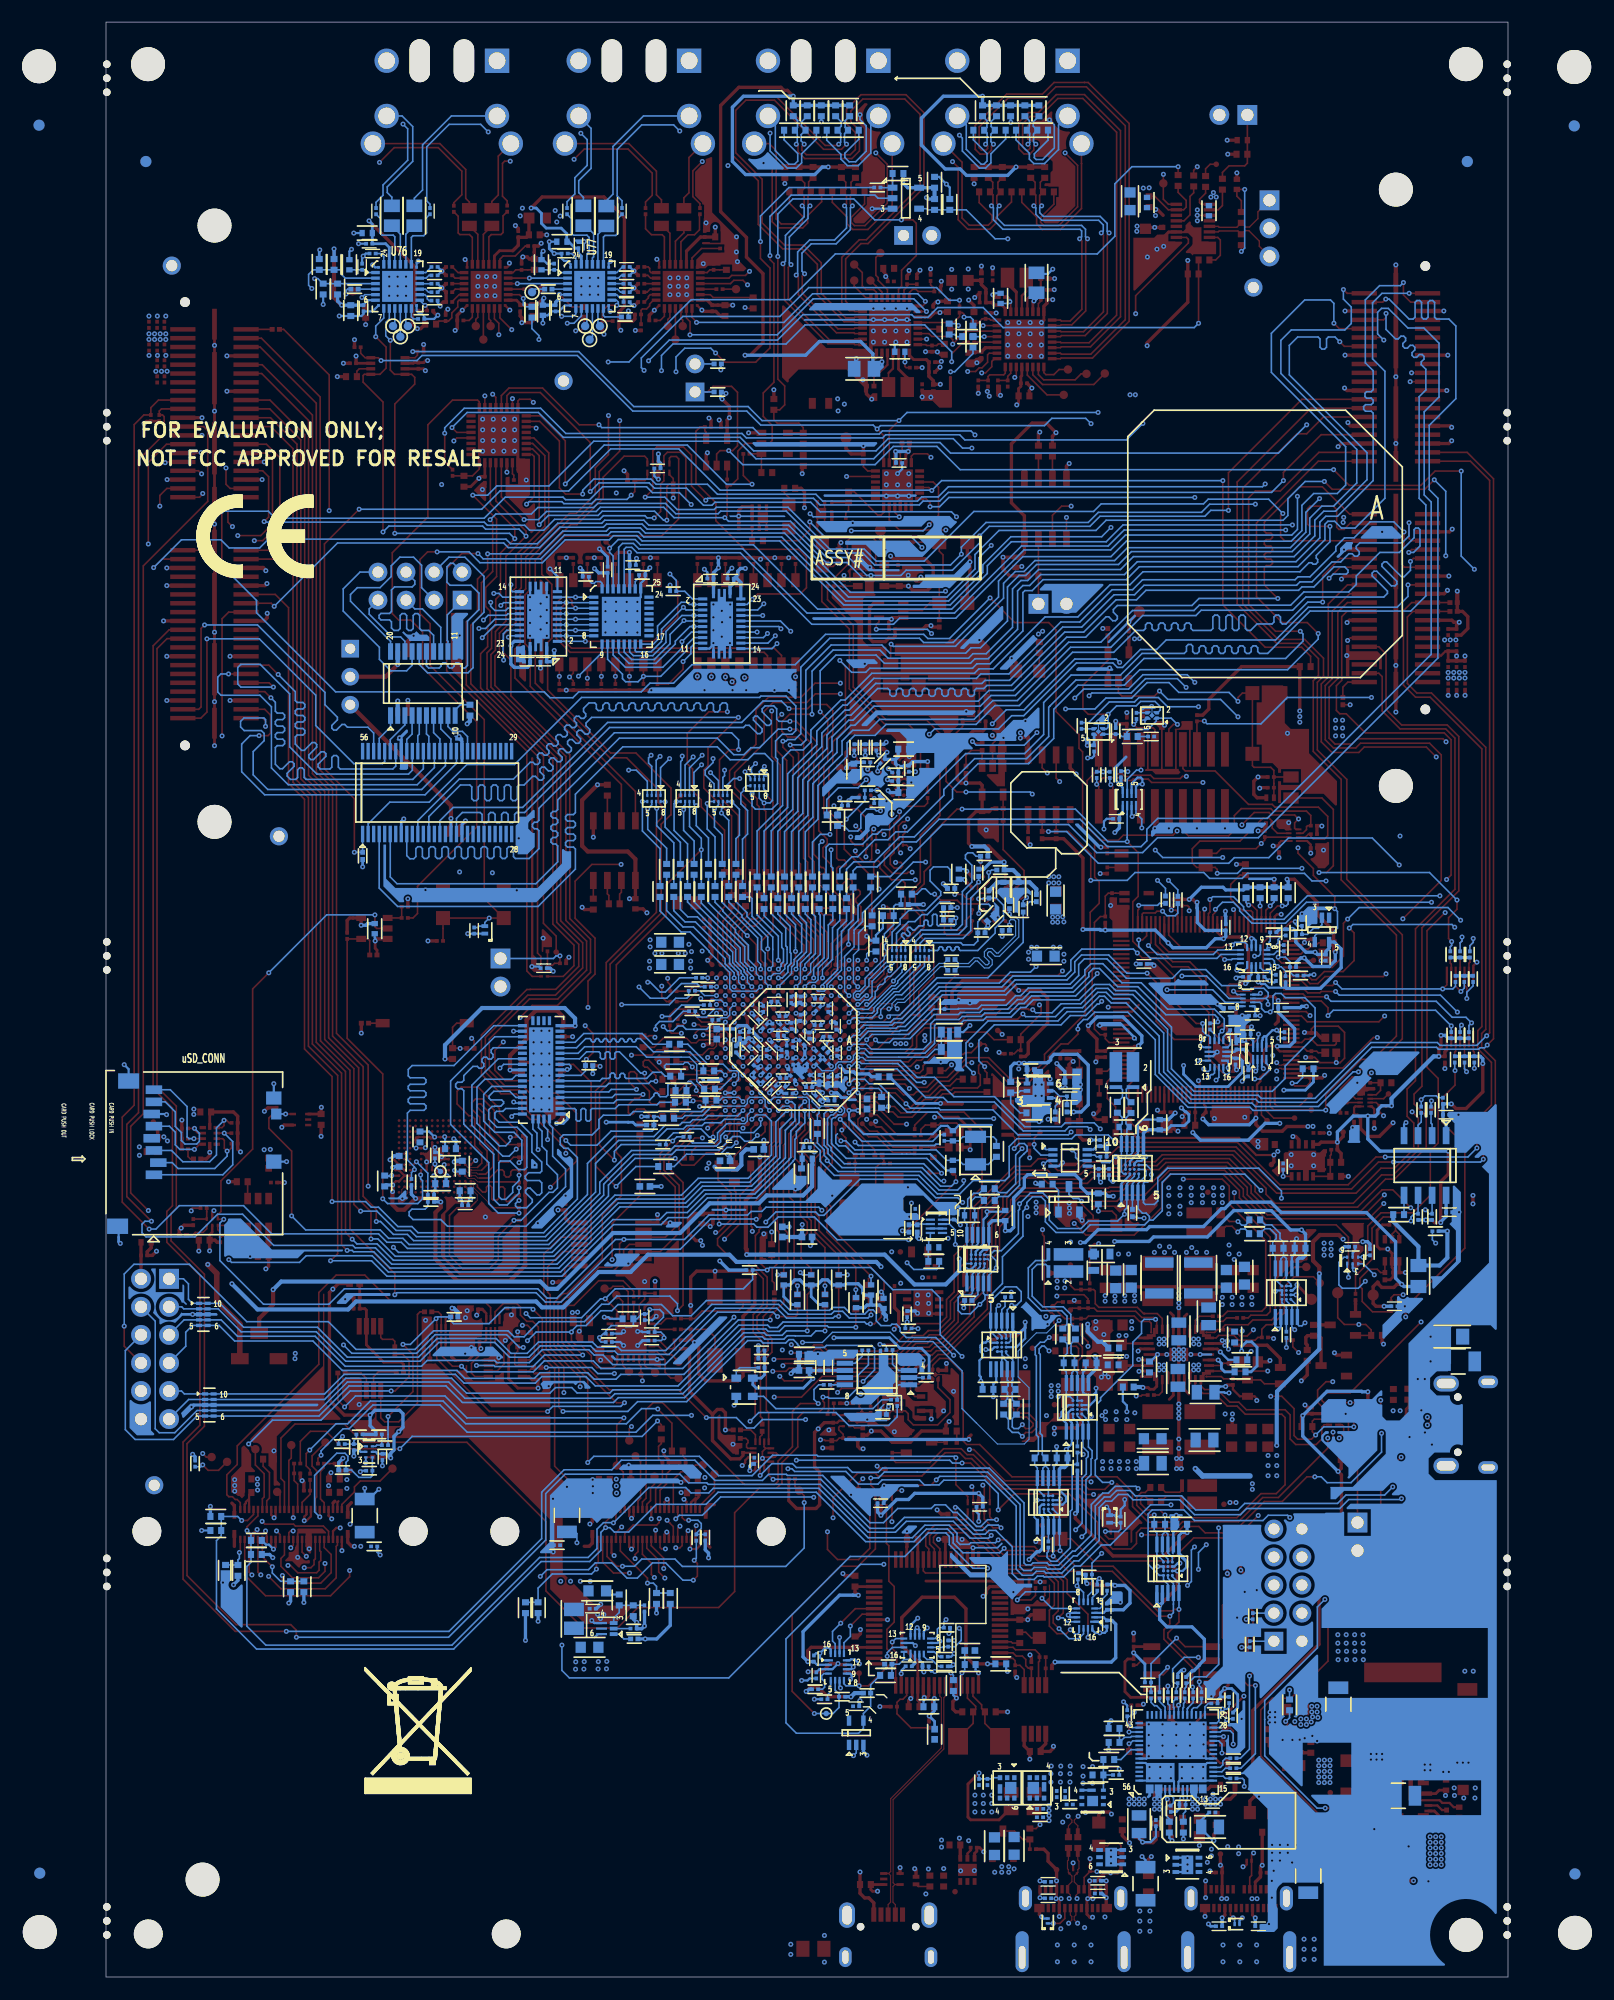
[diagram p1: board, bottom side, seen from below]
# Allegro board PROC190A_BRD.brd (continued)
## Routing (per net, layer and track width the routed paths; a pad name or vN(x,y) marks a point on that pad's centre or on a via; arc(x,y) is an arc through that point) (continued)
ADC0_AIN2: length 63.6
  TOP w0.147: v1(66.17,59.79) 64.54,59.79 64.36,59.97 R5722.2
  BOTTOM w0.147: v1(66.17,59.79) 66.57,60.2 71.61,60.2 76.35,55.45 81.1,55.45 81.97,56.31 82.78,56.31 83.26,56.79 87.48,56.79 88.65,55.63 91.6,55.63 91.8,55.82 97.9,55.82 98.43,55.3 105.33,55.3 108.05,58.01 115.09,58.01 116.57,59.49 U2349.7 U2349.4 119.93,59.49 J31.5
ADC0_AIN2_R: length 17.8
  TOP w0.132: 64.5,76.98 64.5,77.66 U136.K2
  TOP w0.147: 64.5,76.98 65.15,76.33 65.15,70.66 64.67,70.18 64.67,62.89 v1(64.36,62.59) R5722.1
  BOTTOM w0.147: R5722.1 v1(64.36,62.59)
ADC0_AIN3: length 64.9
  TOP w0.147: v1(66.83,59.49) 66.83,59.84 65.61,61.06 R5723.2
  BOTTOM w0.147: J31.7 119.78,57.1 119.78,58.38 119.16,58.99 U2349.5 U2349.6 116.75,58.99 115.34,57.58 108.25,57.58 105.59,54.92 95.2,54.92 94.49,54.2 88.19,54.2 87.68,54.71 83.36,54.71 82.78,54.13 80.8,54.13 80.37,54.56 74.65,54.56 69.72,59.49 v1(66.83,59.49)
ADC0_AIN3_R: length 15.4
  TOP w0.147: U136.K1 65.48,76.67 65.48,75.44 65.63,75.29 65.63,67.77 65.25,67.39 65.25,64.77 65.61,64.41 R5723.1 v1(66.17,63.58)
  BOTTOM w0.147: R5723.1 v1(66.17,63.58)
ADC0_AIN4: length 69.8
  TOP w0.147: R5724.2 56.77,59.76 57.4,59.13 v1(57.76,59.13)
  BOTTOM w0.147: J31.9 120.16,53.05 119.89,52.79 U2350.1 U2350.10 107.2,52.79 105.42,54.57 95.36,54.57 94.56,53.77 88.11,53.77 87.53,54.36 83.52,54.36 82.68,53.52 75.18,53.52 69.68,59.02 67.07,59.02 66.86,58.8 66.16,58.8 65.67,59.3 58.28,59.3 58.11,59.13 v1(57.76,59.13)
ADC0_AIN4_R: length 20.2
  TOP w0.132: 61.3,75.8 61.3,77.66 U136.F2
  TOP w0.147: 61.3,75.8 61.3,75.45 61.21,75.36 61.21,73.71 61.87,73.05 61.87,70.31 61.34,69.77 61.34,67.87 56.52,63.05 56.52,62.28 v1(56.77,62.03) R5724.1
  BOTTOM w0.147: C3714.1 56.57,61.82 v1(56.77,62.03)
ADC0_AIN5: length 69.1
  TOP w0.147: R5725.2 v1(59.08,58.83)
  BOTTOM w0.147: J31.11 119.51,52.29 U2350.2 U2350.9 107.2,52.29 105.27,54.22 95.69,54.22 94.34,52.86 86.79,52.86 86.28,53.37 84.81,53.37 84.33,52.88 81.36,52.88 81.08,53.16 74.96,53.16 69.45,58.67 67.23,58.67 67.01,58.45 66.01,58.45 65.51,58.95 61.67,58.95 61.54,58.83 v1(59.08,58.83)
ADC0_AIN5_R: length 19.3
  TOP w0.132: U136.G2 62.1,77.66 62.1,75.56
  TOP w0.147: 62.1,75.56 62.1,74.78 62.76,74.12 62.76,69.14 62.41,68.78 62.41,67.59 59.08,64.26 v1(59.08,62.23) R5725.1
  BOTTOM w0.147: v1(59.08,62.23) 59.08,61.54 C3715.1
ADC0_AIN6: length 80.2
  TOP w0.147: R5726.2 63.12,62.14 63.47,61.79 v1(63.47,58.5)
  BOTTOM w0.147: v1(63.47,58.5) 65.35,58.5 65.75,58.1 67.17,58.1 67.39,58.32 69.24,58.32 74.75,52.81 80.9,52.81 81.31,52.4 94.49,52.4 95.95,53.87 105.13,53.87 107.7,51.29 U2350.7 U2350.4 118.75,51.29 120.76,49.28 122.18,49.28 122.54,49.64 122.54,59.39 J31.4
ADC0_AIN6_R: length 17.3
  TOP w0.132: 64.1,76.75 U136.J1
  TOP w0.147: 64.1,76.75 64.8,76.05 64.8,74.32 64.09,73.61 64.09,68.94 63.47,68.33 63.47,67.36 64.03,66.8 64.03,65.05 63.12,64.14 R5726.1 63.91,63.58 v1(64.11,63.78)
  BOTTOM w0.147: R5726.1 63.91,63.58 v1(64.11,63.78)
ADC0_AIN7: length 80.7
  TOP w0.147: R5727.2 v1(61.87,58.5)
  BOTTOM w0.147: v1(61.87,58.5) 62.69,58.5 63.14,58.04 64.54,58.04 64.56,58.06 65.29,58.06 65.59,57.75 67.33,57.75 67.54,57.97 69.08,57.97 74.6,52.45 80.59,52.45 81.03,52.02 94.72,52.02 96.21,53.52 104.98,53.52 107.71,50.79 U2350.6 U2350.5 118.76,50.79 120.88,48.67 124.36,48.67 125.25,49.56 125.25,56.71 J31.6
ADC0_AIN7_R: length 18.5
  TOP w0.132: 63.7,76.69 63.7,77.66 U136.J2
  TOP w0.147: 63.7,76.69 64.39,76 64.39,74.73 63.48,73.81 63.48,68.84 63.12,68.48 63.12,67.28 61.87,66.04 v1(61.87,62.59) R5727.1
  BOTTOM w0.147: R5727.1 v1(61.87,62.59)
ADC0_EXT_TRIGGER: length 87
  TOP w0.132: 73.71,77.01 73.06,77.66 71.69,77.66 U136.V2
  TOP w0.147: J31.8 125.35,57.12 v1(125.35,58.93) ; v1(75.23,60.33) 74.73,60.83 74.73,71.93 76.02,73.23 76.02,74.19 74.09,76.12 74.09,76.63 73.71,77.01
  BOTTOM w0.147: v1(75.23,60.33) 75.23,60.96 75.92,61.65 80.72,61.65 81.46,60.91 82.09,60.91 83.67,59.33 87.76,59.33 89.13,57.97 90.02,57.97 90.56,58.5 97.33,58.5 99.01,56.82 104.35,56.82 106.86,59.33 114.25,59.33 119.44,64.53 124.47,64.53 125.35,63.65 v1(125.35,58.93)
ADC0_REFN: length 5.7
  TOP w0.132: U136.H2 62.9,77.66 62.9,75.88
  TOP w0.147: 62.9,75.88 63.09,75.69 v1(63.55,75.69)
  BOTTOM w0.203: R5728.1 63.94,73.27 C3742.2 63.94,75 C3743.1 63.81,75.44 v1(63.55,75.69)
ADC0_REFP: length 63.7
  TOP w0.147: v1(62.84,74.7) 62.84,75.36 62.5,75.7 U136.G1
  TOP w0.381: SW11.2 113.13,59.62 111.86,60.88 v1(111.86,62.23)
  BOTTOM w0.203: C3743.2 63.25,74.83 63.12,74.7 v1(62.84,74.7)
  BOTTOM w0.381: C3742.1 63.02,73.51 63.04,73.48 63.04,71.58 63.86,70.76 67.16,70.76 67.87,70.05 72.31,70.05 75.01,67.36 81.08,67.36 86.13,62.31 87,62.31 87.66,62.97 111.12,62.97 v1(111.86,62.23)
ADC0_REFP_HDR: length 20.5
  TOP w0.305: C3744.1 C3745.2 J31.2
  TOP w0.508: SW11.3 114.88,59.12 116.97,61.21 116.97,63.7 v1(117.78,64.52)
  L03_SIG1 w0.508: v1(117.78,64.52) 118.06,64.8 123.37,64.8 123.83,64.34 J31.2
ADCIN1: length 3.8
  BOTTOM w0.147: U129.6 30.65,16.57 30.29,16.21 30.29,15.78 R679.2 30.89,15.52 31.01,15.4 31.01,14.66 30.68,14.32 R681.1
ADCIN2: length 3.1
  BOTTOM w0.147: U129.10 29.05,16.03 29.21,15.88 R678.2 29.21,14.99 29.41,14.79 R682.1
ADDR0_IO_EXP: length 1.6
  TOP w0.147: U21.26 90.18,136.1 90.06,135.97 R107.1
ADDR1_IO_EXP: length 1.8
  TOP w0.147: R94.1 58.39,136.75 58,136.36 U18.18
AEC1_GPIO0_0: length 152.2
  TOP w0.147: U136.A6 54.23,81.26 53.52,80.55 52.65,80.55 51.74,81.46 50.8,81.46 49.02,83.24 47.04,83.24 45.16,81.36 43.61,81.36 43.48,81.48 43.48,81.89 43.03,82.35 42.55,82.35 41.99,82.91 41.99,83.54 38.28,87.25 38.28,90.96 37.85,91.39 37.85,96.39 37.03,97.21 37.03,99.17 37.44,99.58 37.44,102.85 38.54,103.94 38.54,110.93 38.86,111.25 38.86,112.5 40.94,114.58 40.94,121.97 41.61,122.63 44.68,122.63 v1(46.91,124.87) ; J12.42 118.37,129.18 v1(118.14,129.41)
  BOTTOM w0.147: v1(46.91,124.87) 50.59,121.19 52.56,121.19 52.94,121.57 61.82,121.57 64.57,118.82 73.91,118.82 75.59,117.14 77.72,117.14 78.51,116.36 84.18,116.36 84.71,115.82 86.77,115.82 87.3,116.36 106.2,116.36 113.36,123.52 113.36,124.64 v1(118.14,129.41)
AEC1_GPIO0_1: length 111.8
  TOP w0.147: v1(122.68,127.61) 121.91,128.38 J12.44
  L03_SIG1 w0.091: v1(53.7,99.34) 51.88,101.16 51.88,120.58 53.19,121.89 v1(53.19,126.75)
  BOTTOM w0.147: v1(53.19,126.75) 53.49,126.44 58.24,126.44 59.87,128.07 61.77,128.07 65.15,131.44 77.83,131.44 78.28,131.9 81.82,131.9 82.09,131.62 86.08,131.62 87.93,129.77 90.35,129.77 90.77,130.19 112.28,130.19 113.08,129.39 115.85,129.39 116.59,130.12 120.17,130.12 v1(122.68,127.61) ; v1(53.7,99.34) 54.89,99.34 57.6,96.63 R5757.2
AEC1_REFCLK_SEL: length 25
  TOP w0.147: U21.23 88.36,138.35 87.76,137.74 v1(87.76,131.5) ; U2346.1 75.96,136.02 75.62,135.68 R5797.2 75.97,135.18 76.2,134.95 v1(76.2,131.9)
  BOTTOM w0.147: v1(87.76,131.5) 86.92,132.33 82.42,132.33 82.04,132.72 77.31,132.72 76.5,131.9 v1(76.2,131.9)
AEC1_REFCLKIN: length 47.2
  TOP w0.147: v1(77.34,132.11) 76.76,132.69 76.76,135.17 76.46,135.47 U2346.2 ; J12.33 112.81,136.38 112.27,135.84 112.27,132.18 v1(112.67,131.78)
  BOTTOM w0.147: v1(112.67,131.78) 112.62,131.72 92.74,131.72 92.46,131.44 89.08,131.44 88.62,130.99 87.35,130.99 86.36,131.98 82.27,131.98 81.94,132.31 78.18,132.31 77.98,132.11 v1(77.34,132.11)
AEC1_REFCLKOUT: length 60.1
  TOP w0.147: v1(73.99,133.32) 74.47,133.8 74.47,137.57 74.96,138.05 76.15,138.05 76.46,137.74 U2346.9 ; J12.47 115.93,126.78 116.51,127.36 v1(116.51,132.72)
  BOTTOM w0.147: v1(73.99,133.32) 75.06,134.39 77.5,134.39 78.03,134.92 82.02,134.92 83.19,133.76 85.37,133.76 85.6,133.99 90.83,133.99 92.74,132.08 111.66,132.08 112.29,132.72 v1(116.51,132.72)
AEC2_GPIO0_0: length 124.6
  TOP w0.147: J13.42 3.4,137.24 1.66,135.5 1.66,85.48 v1(1.93,85.22) ; U136.A9 54.65,83.66 53.95,84.35 53.95,85.32 52.98,86.28 49.82,86.28 48.98,87.12 46.41,87.12 45.87,87.65 43.48,87.65 43.41,87.58 v1(43.05,87.58)
  BOTTOM w0.147: v1(43.05,87.58) 42.77,87.3 41.3,87.3 40.49,88.11 38.71,88.11 37.31,89.51 36.25,89.51 35.69,88.95 33.99,88.95 30.84,85.8 30.84,82.08 28.59,79.83 22.63,79.83 22.35,79.55 17.48,79.55 12.42,84.61 6.4,84.61 6.15,84.35 2.82,84.35 1.96,85.22 v1(1.93,85.22)
AEC2_GPIO0_1: length 127
  TOP w0.132: U136.B8 58.1,83.25 54.89,83.25
  TOP w0.147: J13.44 3.7,138.04 1.31,135.65 1.31,84.94 v1(1.88,84.38) ; 54.89,83.25 54.52,83.25 53.57,84.2 53.57,85.19 52.83,85.93 49.68,85.93 48.9,86.72 44.42,86.72 v1(43.94,87.2)
  BOTTOM w0.147: v1(43.94,87.2) 43.69,86.95 40.99,86.95 40.18,87.76 38.56,87.76 37.16,89.15 36.4,89.15 35.81,88.57 34.29,88.57 31.19,85.47 31.19,81.94 28.73,79.48 22.86,79.48 22.58,79.2 17.32,79.2 12.34,84.18 6.48,84.18 6.3,84 2.67,84 2.54,84.13 2.13,84.13 v1(1.88,84.38)
AEC2_REFCLK_SEL: length 18.5
  TOP w0.147: U2346.5 77.96,135.72 78.19,135.48 R5798.2 79.1,134.49 v1(79.43,134.16) ; U21.24 88.4,137.85 88.21,137.67 88.21,134.04 v1(88.9,133.35)
  BOTTOM w0.147: v1(79.43,134.16) 79.81,133.78 82.63,133.78 83.01,133.4 85.52,133.4 85.7,133.58 88.67,133.58 v1(88.9,133.35)
AEC2_REFCLKIN: length 75.6
  TOP w0.147: v1(78.16,133.99) 77.46,134.68 U2346.4 ; J13.33 20.24,130.04 20.6,130.4 20.6,132.31 v1(20.4,132.51)
  BOTTOM w0.147: v1(78.16,133.99) 76.38,133.99 75.26,132.87 71.91,132.87 71.7,133.07 65.23,133.07 61.44,129.29 58.32,129.29 57.23,128.2 52.88,128.2 48.39,132.69 37.54,132.69 36.86,133.38 27.58,133.38 27.16,133.8 21.69,133.8 v1(20.4,132.51)
AEC2_REFCLKOUT: length 72.8
  TOP w0.147: v1(20.35,135.48) 20.35,136.22 16.92,139.64 J13.47 ; v1(72.67,133.71) 73.96,135 73.96,137.79 74.7,138.53 77.11,138.53 77.46,138.18 U2346.7
  BOTTOM w0.147: v1(72.67,133.71) 72.49,133.88 62.92,133.88 62.31,133.28 53.33,133.28 52.98,133.63 51.49,133.63 50.7,134.42 21.41,134.42 v1(20.35,135.48)
AUDIO_EXT_REFCLK0: length 90.1
  TOP w0.147: U2346.10 75.96,137.52 75.82,137.67 75.34,137.67 75.12,137.45 75.12,132.01 76.67,130.47 85.45,130.47 87.52,128.39 87.52,127 86.61,126.09 86.61,121.21 87,120.83 87,116.54 81.28,110.82 78.99,110.82 75.82,107.65 75.82,105.23 75.84,105.23 76.71,104.37 76.71,96.33 81.34,91.7 81.34,81.05 82.3,80.09 82.3,75.31 v1(80.95,73.96)
  BOTTOM w0.147: R538.2 80.33,75.37 80.95,74.75 v1(80.95,73.96)
AUDIO_EXT_REFCLK1: length 85.9
  TOP w0.147: v1(80.8,71.58) 82.65,73.43 82.65,80.24 81.69,81.2 81.69,91.85 77.14,96.39 77.14,104.47 76.66,104.95 76.66,106.05 76.99,106.38 76.99,107.54 79.83,110.39 81.36,110.39 88.11,117.14 88.11,128.3 84.91,131.5 84.34,131.5 81.97,133.87 81.97,135.79 80.06,137.69 78.21,137.69 77.96,137.45 U2346.6
  BOTTOM w0.147: v1(80.8,71.58) 78.99,73.38 R506.2
AUDIO_EXT_REFCLK1__R: length 8.8
  TOP w0.132: v1(69.9,75.54) 69.82,75.62 69.82,77.13 U136.T1
  BOTTOM w0.147: v1(69.9,75.54) 70.33,75.11 70.74,75.11 71.35,74.5 74.41,74.5 75.53,73.38 R506.1
AUDIO_EXT_REFCLK2: length 29.6
  TOP w0.147: R5686.1 v1(87.12,55.18) ; R5689.1 78.64,70.74 81.15,68.22 v1(81.15,64.95)
  L03_SIG1 w0.091: v1(80.95,54.64) 81.23,54.91 81.23,64.87 v1(81.15,64.95)
  BOTTOM w0.147: v1(87.12,55.18) 82.99,55.18 82.45,54.64 v1(80.95,54.64)
AUDIO_EXT_REFCLK2_R: length 8
  TOP w0.132: U136.V3 71.69,78.46 72.68,78.46 72.8,78.33
  TOP w0.147: 72.8,78.33 73.81,78.33 74.96,77.19 R5689.2
AUDIO_EXT_REFCLK2_S0: length 150.2
  TOP w0.147: U2347.6 89.87,55.37 89.97,55.47 89.97,56.38 89.71,56.64 R5795.2 89.26,57.05 v1(89.2,57) ; U21.21 88.24,139.35 86.89,138 86.89,131.22 89.38,128.73 89.38,125.78 89.87,125.3 89.87,122.66 91.01,121.52 91.01,119.91 90.32,119.23 90.32,116 84.99,110.67 84.99,95.83 83.11,93.95 83.11,90.96 86.1,87.97 88.39,87.97 v1(89.49,86.87)
  L03_SIG1 w0.091: v1(89.49,86.87) 111.81,86.87 120.98,77.7 120.98,73.6 117.75,70.38 117.75,68.86 114.76,65.86 114.76,64.26 116.2,62.81 116.2,62.1 111.33,57.23 v1(105.49,57.23)
  BOTTOM w0.147: v1(105.49,57.23) 104.73,56.47 98.86,56.47 97.18,58.15 90.71,58.15 89.55,57 v1(89.2,57)
AUDIO_EXT_REFCLK2_S1: length 104
  TOP w0.147: U2347.5 88.64,55.87 88.19,56.32 88.19,57.89 88.19,57.89 88.19,58 88.53,58.34 R5796.2 88.54,58.73 88.81,59 v1(89.28,59) ; v1(86.74,71.5) 84.38,73.86 84.38,78.21 86.2,80.03 88.61,80.03 89.26,80.67 90.86,80.67 92.28,82.09 92.28,84.91 88.65,88.54 86.08,88.54 83.46,91.16 83.46,93.79 85.34,95.67 85.34,110.51 91.77,116.94 91.77,119.58 91.36,119.99 91.36,121.67 90.3,122.73 90.3,125.36 89.87,125.79 89.87,128.74 87.25,131.36 87.25,137.74 88.35,138.85 U21.22
  L03_SIG1 w0.091: v1(86.74,71.5) 87.27,70.97 87.27,67.97 89.65,65.59 89.65,59.38 v1(89.28,59)
BOOTMODE0: length 38.4
  L03_SIG1 w0.091: v1(90.32,126.06) 90.32,123.98 91.41,122.89 91.41,118.92 87.63,115.14 83.16,115.14 77.62,109.6 73.81,109.6 73.23,110.18 72.87,110.18 72.55,109.86 68.99,109.86 68.03,108.89 v1(67.21,108.89)
  BOTTOM w0.147: v1(90.32,126.06) 90.32,125.58 90.18,125.43 U81.14 ; v1(67.21,108.89) 67.31,108.89 67.42,108.78 RA6.1
BOOTMODE1: length 41.2
  L03_SIG1 w0.091: v1(69.6,108.51) 70.13,108.51 70.46,108.18 79.73,108.18 84.96,113.41 88.42,113.41 94.03,119.02 94.03,123.44 92.2,125.27 v1(91.87,125.27)
  BOTTOM w0.147: RA2.1 70.72,107.94 70.15,108.51 v1(69.6,108.51) ; U81.15 91.06,124.93 91.4,125.27 v1(91.87,125.27)
BOOTMODE2: length 33.2
  L03_SIG1 w0.091: v1(91.24,124.18) 91.68,123.73 91.68,118.79 87.73,114.83 83.26,114.83 77.75,109.32 73.48,109.32 v1(73.05,109.75)
  BOTTOM w0.147: v1(73.05,109.75) 73.74,109.06 RA5.1 ; v1(91.24,124.18) 90.99,124.43 U81.16
BOOTMODE3: length 36.8
  L03_SIG1 w0.091: v1(70.97,109.27) 71.25,109.55 72.33,109.55 72.87,109.02 77.85,109.02 83.39,114.55 87.86,114.55 92.15,118.85 v1(92.15,124.46)
  BOTTOM w0.147: RA2.2 71.12,108.61 70.97,108.76 v1(70.97,109.27) ; v1(92.15,124.46) 92.15,124.11 91.77,123.72 90.81,123.72 90.6,123.93 U81.17
BOOTMODE4: length 34.6
  L03_SIG1 w0.091: v1(92.81,122.86) 92.81,122.25 92.43,121.87 92.43,118.67 88.04,114.27 87.8,114.27 87.79,114.27 83.64,114.27 78.11,108.74 72.54,108.74 v1(72.24,109.04)
  BOTTOM w0.147: v1(92.81,122.86) 92.38,123.29 90.73,123.29 90.59,123.43 U81.18 ; RA2.3 71.52,108.32 v1(72.24,109.04)
BOOTMODE5: length 38
  L03_SIG1 w0.091: v1(93.22,122.1) 93.73,121.59 93.73,119.13 88.29,113.69 83.87,113.69 79.93,109.75 79.93,109.6 80.09,109.45 80.09,109.09 79.83,108.84 78.61,108.84 78.23,108.46 70.59,108.46 69.93,109.12 v1(69.11,109.12)
  BOTTOM w0.147: U81.19 91.77,122.93 92.61,122.1 v1(93.22,122.1) ; RA6.4 68.62,108.63 v1(69.11,109.12)
BOOTMODE6: length 27.3
  L03_SIG1 w0.091: v1(92.91,121.26) 92.91,118.72 88.19,114 87.93,114 87.91,113.97 87.68,113.97 87.66,114 83.77,114 79.65,109.88 v1(79.65,109.27)
  BOTTOM w0.147: RA7.4 77.96,108.27 78.97,109.27 v1(79.65,109.27) ; v1(92.91,121.26) 91.74,122.43 U81.20
BOOTMODE7: length 29.1
  L03_SIG1 w0.091: v1(73.81,110.46) 74.4,109.88 77.49,109.88 83.2,115.6 87.35,115.6 v1(90.98,119.23)
  BOTTOM w0.147: RA5.3 74.54,109.74 v1(73.81,110.46) ; v1(90.98,119.23) 90.98,119.58 91.03,119.63 91.03,121.08 91.01,121.1 91.01,121.62 90.69,121.93 U81.21
BOOTMODE8: length 20.9
  L03_SIG1 w0.091: v1(66.22,120.73) 66.22,119.46 67.59,118.08 67.59,116.1 68.99,114.71 69.7,114.71 73,111.4 v1(73,110.62)
  BOTTOM w0.147: U83.14 66.67,120.27 v1(66.22,120.73) ; v1(73,110.62) 74.14,109.47 RA5.2
BOOTMODE9: length 21.9
  L03_SIG1 w0.091: v1(72.01,110.31) 71.32,110.31 68.99,112.65 68.99,114.27 67.28,115.98 67.28,116.89 66.55,117.63 66.55,118.44 65.76,119.23 65.76,121.15 66.05,121.44 v1(66.37,121.44)
  BOTTOM w0.147: v1(66.37,121.44) 67.04,120.77 U83.15 ; RA2.4 71.92,108.04 72.72,108.84 72.72,109.25 72.01,109.96 v1(72.01,110.31)
BOOTMODE10: length 22.1
  L03_SIG1 w0.091: v1(74.8,110.54) 74.8,112.04 71.86,114.99 69.11,114.99 67.87,116.23 67.87,118.52 67.08,119.3 v1(67.08,121.64)
  BOTTOM w0.147: v1(67.08,121.64) 67.45,121.27 U83.16 ; RA5.4 74.94,110.05 74.8,110.19 v1(74.8,110.54)
BOOTMODE11: length 21.9
  L03_SIG1 w0.091: v1(68.02,121.77) 67.54,121.29 67.54,119.33 68.15,118.72 68.15,116.36 69.24,115.27 71.98,115.27 75.95,111.3 v1(75.95,110.31)
  BOTTOM w0.147: v1(75.95,110.31) 76.76,109.49 RA7.1 ; U83.17 v1(68.02,121.77)
BOOTMODE12: length 19
  L03_SIG1 w0.091: v1(68.16,109.87) 68.16,114.69 66.95,115.9 66.95,116.81 66.27,117.5 66.27,118.31 65.38,119.2 65.38,121.59 v1(65.86,122.07)
  BOTTOM w0.147: v1(68.16,109.87) 68.53,109.5 68.53,109.04 68.22,108.74 RA6.3 ; U83.18 66.06,122.27 v1(65.86,122.07)
BOOTMODE13: length 20.9
  L03_SIG1 w0.091: v1(67.36,109.6) 66.55,110.41 66.55,111.34 67.72,112.51 67.72,114.63 65.94,116.41 65.94,117.02 64.44,118.52 64.44,121.31 v1(64.97,121.84)
  BOTTOM w0.147: v1(67.36,109.6) 67.82,109.14 RA6.2 ; U83.19 65.9,122.77 v1(64.97,121.84)
BOOTMODE14: length 24.3
  L03_SIG1 w0.091: v1(76.81,110.52) 76.81,111.02 72.29,115.54 69.37,115.54 68.43,116.48 68.43,120.12 68.81,120.5 68.81,121.98 v1(67.51,123.27)
  BOTTOM w0.147: v1(67.51,123.27) U83.20 ; v1(76.81,110.52) 77.16,110.16 RA7.2
BOOTMODE15: length 25.7
  L03_SIG1 w0.091: v1(67.41,124.33) 69.19,122.56 69.19,120.47 68.73,120.02 68.73,117.4 70.28,115.85 72.39,115.85 v1(77.62,110.62)
  BOTTOM w0.147: U83.21 67.97,123.77 v1(67.41,124.33) ; RA7.3 77.56,109.62 77.85,109.91 77.85,110.39 v1(77.62,110.62)
BOOTMODE_I2C_EN: length 1.7
  BOTTOM w0.147: U107.5 R578.2
BOOTMODE_I2C_SCL: length 155.9
  TOP w0.147: v1(6.93,79.32) TP71.1
  L03_SIG1 w0.091: v1(20.14,131.01) 20.14,131.7 19.94,131.9 18.77,131.9 17.27,130.4 6.76,130.4 5.21,128.85 5.21,128.19 6.45,126.95 6.45,120.39 4.93,118.87 4.05,118.87 3.17,118 3.17,97.87 6.93,94.11 v1(6.93,79.32) 6.93,66.83 v1(6.55,66.45)
  BOTTOM w0.147: R579.1 6.97,79.28 v1(6.93,79.32) ; v1(6.55,66.45) 6.85,66.75 R583.2 ; U82.29 80.56,129.45 80.21,129.8 79.22,129.8 78.73,129.31 69.31,129.31 63.5,123.49 50.14,123.49 44.07,129.57 36.22,129.57 34.77,131.01 v1(20.14,131.01)
BOOTMODE_I2C_SDA: length 135.5
  TOP w0.147: TP45.1 81.38,129.61 v1(81.38,129.36)
  L03_SIG1 w0.091: v1(7.86,79.43) 7.34,79.95 7.34,95.71 4.33,98.71 4.33,114.16 19.53,129.36 v1(19.53,131.47)
  BOTTOM w0.147: R582.2 6.33,79.61 6.5,79.78 7.51,79.78 v1(7.86,79.43) R580.1 ; v1(19.53,131.47) 34.87,131.47 36.4,129.95 44.99,129.95 47.17,127.77 47.17,127.08 50.39,123.85 62.53,123.85 68.35,129.67 78.59,129.67 79.07,130.15 80.6,130.15 v1(81.38,129.36) 81.38,128.98 81.06,128.66 U82.30
BOOTMODEON: length 57.2
  TOP w0.147: U23.4 72.64,139.87 72.76,139.99 R112.2 73.17,140.34 73.56,139.95 73.56,135.28 71.75,133.48 71.75,131.85 69.16,129.26 64.26,129.26 63.55,128.55 63.55,125.78 64.11,125.22 67.97,125.22 v1(68.45,124.74)
  L03_SIG1 w0.091: v1(68.45,124.74) 70.16,126.45 76.47,126.45 76.63,126.29 81.5,126.29 84.44,123.36 84.67,123.36 85.04,122.99 85.88,122.99 86.16,122.71 86.16,121.62 87.33,120.45 88.98,120.45 89.84,121.31 v1(90.55,121.31)
  BOTTOM w0.147: U81.22 90.43,121.43 v1(90.55,121.31) ; v1(68.45,124.74) 68.92,124.27 U83.22
BUF_BOOTMODE_I2C0_SCL: length 60.5
  TOP w0.147: v1(11.18,87.01) 11.7,86.49 18.19,86.49 18.71,87.01 U48.82 ; v1(41.63,103.71) 41.73,103.71 41.75,103.72 R119.2 U25.7
  L03_SIG1 w0.091: v1(11.18,87.01) 11.66,87.49 11.66,91.01 10.39,92.28 10.39,100.15 v1(9.86,100.69)
  BOTTOM w0.147: v1(9.86,100.69) 12.29,103.12 19.89,103.12 21.67,101.35 24.79,101.35 25.3,100.84 37.11,100.84 39.98,103.71 v1(41.63,103.71)
BUF_BOOTMODE_I2C0_SDA: length 46
  TOP w0.147: U25.6 R118.2 39.82,103.72 37.8,101.7 v1(37.8,99.29) ; U48.81 18.3,87.41 v1(17.93,87.05)
  L03_SIG1 w0.091: v1(16.48,99.24) 16.89,98.83 16.89,96.11 18.9,94.11 18.9,87.48 18.47,87.05 v1(17.93,87.05)
  BOTTOM w0.147: v1(37.8,99.29) 34.49,99.29 33.78,100 27.56,100 27.03,99.47 24.08,99.47 23.62,99.92 18.44,99.92 17.75,99.24 v1(16.48,99.24)
BUF_BOOTMODE_I2C_SCL: length 57.2
  TOP w0.147: U48.49 27.13,96.28 27,96.42 v1(27,97.56)
  L03_SIG1 w0.091: v1(6.17,97.89) 6.17,97.31 7.67,95.81 7.67,80.54 8.31,79.91 8.31,79.2 7.49,78.38 v1(7.49,69.47)
  BOTTOM w0.147: v1(27,97.56) 26.75,97.81 24.86,97.81 23.95,96.9 23.95,96.66 23.05,95.76 20.3,95.76 18.17,97.89 v1(6.17,97.89) ; U107.7 R552.2 7.15,69.11 7.47,69.42 7.47,69.44 v1(7.49,69.47)
BUF_BOOTMODE_I2C_SDA: length 55.9
  TOP w0.147: v1(26.51,96.67) 26.51,96.4 26.73,96.18 U48.50
  L03_SIG1 w0.091: v1(8.79,68.45) 7.92,69.32 7.92,78.23 8.59,78.89 8.59,80.04 7.95,80.67 7.95,96.29 v1(6.93,97.31)
  BOTTOM w0.147: v1(6.93,97.31) 18.26,97.31 20.16,95.41 23.19,95.41 24.31,96.52 24.31,96.75 24.87,97.31 25.87,97.31 v1(26.51,96.67) ; U107.6 R551.2 8.49,69.11 8.79,68.81 v1(8.79,68.45)
BUF_TEST_GPIO1: length 17.6
  TOP w0.147: U48.74 18.71,90.21 17.98,89.48 17.17,89.48 16.89,89.77 15.9,89.77 v1(15.62,90.04) ; v1(5.92,89.46) 5.54,89.84 U40.1
  BOTTOM w0.147: R519.2 4.76,89.7 5,89.46 v1(5.92,89.46) 15.04,89.46 v1(15.62,90.04)
BUF_TEST_GPIO2: length 24.7
  TOP w0.147: U48.73 18.6,90.61 17.93,89.94 17.22,89.94 16.58,90.58 11.3,90.58 v1(11.05,90.83) ; U51.7 11.94,79.17 R280.2 11.64,78.34 v1(11.28,77.98)
  L03_SIG1 w0.091: v1(11.05,90.83) 10.44,90.22 10.44,83.54 11,82.98 11,78.25 v1(11.28,77.98)
BUF_TEST_GPIO3: length 29
  TOP w0.147: v1(4.27,89.23) 4.74,89.7 U40.3 ; U48.72 18.49,91.01 17.78,90.3 17.37,90.3 16.64,91.03 14.94,91.03 13.94,92.02 13.94,94.54 v1(14.38,94.97)
  L03_SIG1 w0.091: v1(4.27,89.23) 5.56,90.53 5.56,94.31 v1(4.83,95.05)
  BOTTOM w0.147: R515.2 3.96,89.53 v1(4.27,89.23) ; v1(4.83,95.05) 5.08,95.3 14.05,95.3 v1(14.38,94.97)
BUF_TEST_GPIO4: length 31.4
  TOP w0.147: v1(3.73,88.6) 3.73,89.56 3.94,89.77 U40.5 ; U48.71 15.93,91.41 14.91,92.43 14.91,95.4 v1(14.53,95.78)
  L03_SIG1 w0.091: v1(4.29,95.68) 4.29,94.87 4.67,94.49 4.67,90.73 3.73,89.79 v1(3.73,88.6)
  BOTTOM w0.147: v1(3.73,88.6) 3.73,89.16 3.16,89.73 R510.2 ; v1(14.53,95.78) 13.48,96.83 5.44,96.83 v1(4.29,95.68)
BUF_TEST_PORZN: length 19.9
  TOP w0.147: v1(3.3,86.39) 3.54,86.15 U40.9 ; U48.77 18.57,89.01 18.31,88.75 v1(16.43,88.75)
  BOTTOM w0.147: v1(16.43,88.75) 16.03,88.34 6.5,88.34 5.05,86.89 3.81,86.89 v1(3.3,86.39) 3.54,86.15 R512.2
BUF_TEST_POWERDOWN: length 18.1
  TOP w0.147: v1(5.14,86.11) U40.13 ; v1(16.31,87.05) 16.31,87.76 16.92,88.37 18.47,88.37 18.71,88.61 U48.78
  BOTTOM w0.147: v1(16.31,87.05) 15.82,87.53 6.56,87.53 v1(5.14,86.11) R525.2
BUF_TEST_WARMRESETN: length 19.3
  TOP w0.147: v1(4.22,86.18) 4.34,86.06 U40.11 ; U48.76 18.44,89.41 18.14,89.1 17.04,89.1 16.92,89.23 v1(15.62,89.23)
  L03_SIG1 w0.091: v1(4.22,86.18) 4.22,86.99 v1(4.59,87.36)
  BOTTOM w0.147: v1(15.62,89.23) 15.29,88.9 6.12,88.9 v1(4.59,87.36) ; R517.2 4.34,86.06 v1(4.22,86.18)
CAN-FD_INH: length 167.1
  TOP w0.147: U3068.7 30.76,160.5 31.22,160.97 TP585.1 31.22,163.21 v1(31.22,163.22) ; R3028.2 v1(16.56,15.29)
  L03_SIG1 w0.091: v1(16.59,34.19) 16.59,42.95 18.54,44.91 18.54,50.16 17.96,50.75 17.96,57.85 21.73,61.62 21.73,82.44 22.02,82.73 22.02,83.87 21.49,84.4 21.49,86.69 22.23,87.43 22.23,88.42 19.79,90.86 19.79,94.46 20.02,94.69 20.02,97.16 23.57,100.71 23.57,105.36 24.89,106.67 24.89,154.05 28.68,157.84 28.68,161.75 30.15,163.22 v1(31.22,163.22)
  BOTTOM w0.147: v1(16.56,15.29) 17.3,15.29 22.04,20.03 22.04,23.32 22.04,23.32 22.04,25.03 17.27,29.8 17.27,33.51 v1(16.59,34.19)
CAP_VDDS0: length 0.9
  TOP w0.305: U136.L6 v1(66.1,81.66)
  BOTTOM w0.305: C454.1 65.93,81.49 v1(66.1,81.66)
CAP_VDDS1: length 0.9
  TOP w0.305: U136.F13 v1(61.3,87.25)
  BOTTOM w0.305: v1(61.3,87.25) 61.43,87.39 C434.1
CAP_VDDS2: length 0.9
  TOP w0.305: U136.R11 v1(69.3,85.65)
  BOTTOM w0.305: C446.1 69.38,85.57 v1(69.3,85.65)
CAP_VDDS3: length 0.9
  TOP w0.305: U136.H15 v1(62.9,88.85)
  BOTTOM w0.305: v1(62.9,88.85) 62.78,88.73 C432.1
CAP_VDDS5: length 1
  TOP w0.305: U136.P8 v1(67.7,83.26)
  BOTTOM w0.305: C443.1 67.93,83.02 v1(67.7,83.26)
CAP_VDDS_CANUART: length 0.9
  TOP w0.305: U136.E6 v1(60.5,81.66)
  BOTTOM w0.305: C509.1 60.68,81.66 v1(60.5,81.66)
CAP_VDDS_MCU: length 0.9
  TOP w0.147: U136.E8 v1(60.5,83.26)
  BOTTOM w0.305: v1(60.5,83.26) 60.64,83.4 C484.1
CDCE_CLKOUT_1: length 24.2
  TOP w0.147: R89.1 79.2,62.08 80.16,63.04 82.37,63.04 84.61,60.81 85.14,60.81 85.34,60.6 85.34,57.61 84.56,56.82 84.33,56.82 v1(83.82,56.31) ; U2347.3 v1(93.44,55.37)
  BOTTOM w0.147: v1(93.44,55.37) 91.87,55.37 91.77,55.27 88.32,55.27 87.27,56.31 v1(83.82,56.31)
CLKOUT0: length 2.3
  BOTTOM w0.147: U65.1 55.19,53.62 55.33,53.48 R337.2
CLKOUT_OSC: length 13.3
  BOTTOM w0.147: R336.1 56.73,52.26 57.53,51.46 66.32,51.46 67.43,52.57 U62.3
CORE_CONFIG: length 42.8
  TOP w0.147: TP76.1 R371.2 41.75,39.88 41.54,39.67 SW7.3 39.57,39.67 37.57,37.67 30.56,37.67 28.47,39.75 24.66,39.75 v1(22.63,41.78) ; v1(21.77,54.86) U56.8
  L03_SIG1 w0.091: v1(22.63,41.78) 23.7,42.85 23.7,52.93 v1(21.77,54.86)
CPSW_ETH_INTN: length 54.7
  TOP w0.147: v1(73.72,37.73) 73.43,37.44 73.43,36.29 v1(73.8,35.93) ; v1(85.52,52.91) 85.52,55.24 87.12,56.85 87.12,61.49 87.34,61.71 87.34,65.45 85.81,66.98 U3077.12
  L03_SIG1 w0.091: v1(87.66,36.27) 87.66,49.66 86.31,51 86.31,52.12 v1(85.52,52.91)
  BOTTOM w0.147: R621.1 73.53,37.91 v1(73.72,37.73) ; v1(87.66,36.27) 87.05,36.88 83.29,36.88 82.68,37.49 81.18,37.49 79.81,36.12 78.87,36.12 77.5,37.49 76.3,37.49 74.74,35.93 v1(73.8,35.93)
CPSW_ETH_INTN_1V8: length 13.2
  TOP w0.147: U3077.3 76.33,66.98 75.44,67.87 75.44,71.53 76.81,72.9 76.81,74.55 v1(75.67,75.69)
  BOTTOM w0.147: R205.2 75.29,76.07 v1(75.67,75.69)
CPSW_RGMII1_BCLK: length 25.4
  TOP w0.147: J18.48 82.41,42.94 82.67,43.21 83.31,43.21 86.36,46.25 86.36,55.07 87.83,56.54 87.83,58.85 88.34,59.36 88.88,59.36 89.46,59.94 89.46,60.65 89.77,60.97 91.01,60.97 91.76,60.22 U29.3
CPSW_RGMII1_BCLK_1V8: length 5
  TOP w0.147: U29.6 91.76,57.41 90.96,56.62 90.96,55.47 91.56,54.87 U2347.2
CPSW_RGMII1_BRD_CONN_DET: length 2
  TOP w0.147: J18.36 80.01,43 79.46,43.55 R355.2
CPSW_RGMII1_COL: length 5.9
  TOP w0.147: J18.14 75.61,45.04 74.9,45.75 74.22,45.75 73.61,46.35 TP590.1
CPSW_RGMII1_CRS: length 5.1
  TOP w0.147: TP591.1 78.58,46.68 78.58,43.34 78.81,43.11 J18.30
CPSW_RGMII1_ETH1_CLK: length 36.6
  TOP w0.147: v1(62.48,51.92) 64.11,51.92 64.82,51.21 64.82,48.01 66.12,46.71 66.12,44.87 66.39,44.6 69.19,44.6 76.58,51.99 77.44,51.99 78.08,51.36 78.08,43.34 78.41,43.02 J18.28
  BOTTOM w0.147: v1(62.48,51.92) 62.87,52.3 62.87,53.19 62.44,53.62 R359.2
CPSW_RGMII1_MDC: length 6.9
  TOP w0.147: J18.20 76.81,44.07 76.23,44.65 76.23,45.54 75.63,46.13 74.76,46.13 74.49,46.4 R342.2 74.49,46.91 74.76,47.17 R338.2
CPSW_RGMII1_MDIO: length 6.8
  TOP w0.147: J18.22 77.21,44.18 76.6,44.79 R343.1 76.94,46.92 76.94,48.05 76.7,48.3 R340.2
CPSW_RGMII1_RD0: length 67.5
  TOP w0.147: J18.23 77.61,39.05 76.48,37.92 v1(76.48,36.98) ; U136.W11 72.51,85.25 72.54,85.29 v1(72.9,85.29)
  L03_SIG1 w0.091: v1(72.9,85.29) 73.33,84.86 73.33,84 74.35,82.98 74.35,81.25 74.75,80.85 74.75,77.98 75.01,77.72 75.01,75.31 75.87,74.45 75.87,73.56 74.88,72.57 74.88,63.6 72.69,61.42 72.69,54.19 71.37,52.86 71.37,50.13 71.59,49.91 71.59,45.84 70.23,44.48 70.23,37.9 71.75,36.37 74.88,36.37 75.95,37.44 77.95,37.44 78.64,36.75 78.64,36.59 78.47,36.42 78.21,36.42 77.65,36.98 v1(76.48,36.98)
CPSW_RGMII1_RD1: length 67.5
  TOP w0.147: J18.25 78.01,38.82 76.94,37.74 76.94,36.68 v1(76.38,36.12) ; U136.T11 v1(70.1,84.85)
  L03_SIG1 w0.091: v1(76.38,36.12) 76.38,35.38 75.41,34.42 71.04,34.42 69.6,35.86 69.6,44.75 70.92,46.08 70.92,48.9 70.46,49.35 70.46,49.71 70.66,49.91 70.66,52.93 72.14,54.4 72.14,61.75 74.3,63.91 74.3,77.47 73.48,78.28 73.1,78.28 72.85,78.54 72.85,78.97 73.03,79.15 73.03,83.26 72.64,83.64 71.93,83.64 71.1,84.48 70.47,84.48 v1(70.1,84.85)
CPSW_RGMII1_RD2: length 67.5
  TOP w0.147: v1(77.33,36.17) 77.6,36.44 77.6,37.47 78.41,38.28 J18.27 ; U136.T12 v1(70.1,86.45)
  L03_SIG1 w0.091: v1(70.1,86.45) 70.33,86.23 70.33,86.11 72.47,83.97 72.9,83.97 73.51,83.36 73.51,81.03 74.27,80.26 74.27,78.05 74.6,77.72 74.6,63.78 72.42,61.59 72.42,54.3 71.09,52.98 71.09,50.02 71.32,49.79 71.32,46.07 69.9,44.65 69.9,36.14 70.71,35.33 74.78,35.33 76,36.55 76.95,36.55 v1(77.33,36.17)
CPSW_RGMII1_RD3: length 67.5
  TOP w0.147: U136.U12 v1(70.9,86.45) ; v1(79.07,37.88) 79.07,38.25 78.81,38.51 J18.29
  L03_SIG1 w0.091: v1(79.07,37.88) 80.25,37.88 80.42,38.05 80.42,39.09 80.06,39.45 79.36,39.45 77.99,38.07 73.99,38.07 71.73,40.34 71.73,45.2 72.14,45.61 72.14,50.13 71.92,50.36 71.92,52.63 73.25,53.97 73.25,61.01 75.46,63.22 75.46,68.96 77.13,70.63 77.13,72.34 76.63,72.85 76.63,77.17 75.44,78.36 75.44,81.97 74.96,82.45 74.96,83.29 74.19,84.05 74.19,85.09 72.83,86.45 v1(70.9,86.45)
CPSW_RGMII1_RESETN: length 23.5
  TOP w0.147: v1(62.28,48.64) 61.93,48.64 61.85,48.56 R5824.2 60.81,48.56 60.57,48.8 R373.1 60.22,49.14 60.63,49.54 60.63,49.76 60.52,49.87 U68.4 ; v1(75.39,41.48) 75.21,41.66 J18.12
  L03_SIG1 w0.091: v1(62.28,48.64) 62.89,48.03 v1(62.89,43.43)
  BOTTOM w0.147: v1(75.39,41.48) 75.06,41.81 72.97,41.81 71.32,43.46 62.89,43.46 v1(62.89,43.43)
CPSW_RGMII1_RX_DV: length 67.5
  TOP w0.132: U136.V12 71.54,86.05 71.93,85.66 72.63,85.66 72.75,85.78 73.32,85.78 73.61,85.49 v1(73.61,85.14)
  TOP w0.147: J18.45 82.01,37.56 81.03,36.58 v1(79.58,36.58)
  L03_SIG1 w0.091: v1(73.61,85.14) 73.86,84.89 73.86,83.9 74.65,83.11 74.65,82.3 75.11,81.84 75.11,78.18 76.2,77.09 76.2,73.36 75.16,72.31 75.16,63.48 72.98,61.3 72.98,54.08 71.64,52.75 71.64,50.24 71.87,50.02 71.87,45.73 71.42,45.28 71.42,38 72.16,37.26 75.31,37.26 75.84,37.8 78.36,37.8 v1(79.58,36.58)
CPSW_RGMII1_RXC: length 67.4
  TOP w0.147: v1(76.33,38.76) 76.68,38.76 76.81,38.89 J18.19 ; U136.W12 73.1,86.05 73.28,86.23 v1(73.74,86.23)
  L03_SIG1 w0.091: v1(73.74,86.23) 74.47,85.5 74.47,84.25 75.23,83.49 75.23,82.63 75.79,82.07 75.79,78.54 76.96,77.37 76.96,73.05 77.5,72.52 77.5,70.46 76.56,69.52 76.56,65.87 75.77,65.08 75.77,63.14 73.61,60.98 73.61,60.17 73.72,60.06 74.11,60.06 74.22,59.96 74.22,59.81 74.11,59.7 73.72,59.7 73.61,59.59 73.61,59.44 73.72,59.33 74.11,59.33 74.22,59.23 74.22,59.07 74.11,58.97 73.72,58.97 73.61,58.86 73.61,58.14 74.12,57.63 74.12,57.28 73.63,56.79 73.63,56.15 73.74,56.04 74.24,56.04 74.35,55.93 74.35,55.78 74.24,55.67 73.74,55.67 73.63,55.57 73.63,55.42 73.74,55.31 74.24,55.31 74.35,55.2 74.35,55.05 74.24,54.94 73.74,54.94 73.63,54.84 73.63,53.96 72.19,52.52 72.19,50.47 72.42,50.25 72.42,49.85 72.52,49.74 72.71,49.74 72.82,49.64 72.82,49.48 72.71,49.38 72.52,49.38 72.42,49.27 72.42,49.12 72.52,49.01 72.71,49.01 72.82,48.9 72.82,48.75 72.71,48.65 72.52,48.65 72.42,48.54 72.42,48.39 72.52,48.28 72.71,48.28 72.82,48.17 72.82,48.02 72.71,47.91 72.52,47.91 72.42,47.81 72.42,47.66 72.52,47.55 72.71,47.55 72.82,47.44 72.82,47.29 72.71,47.18 72.52,47.18 72.42,47.08 72.42,46.92 72.52,46.82 72.71,46.82 72.82,46.71 72.82,46.56 72.71,46.45 72.52,46.45 72.42,46.34 72.42,45.5 72.1,45.19 72.1,43.52 72.21,43.41 72.45,43.41 72.54,43.32 72.54,43.15 72.44,43.05 72.21,43.05 72.1,42.94 72.1,42.79 72.21,42.68 72.44,42.68 72.54,42.57 72.54,42.42 72.44,42.31 72.21,42.31 72.1,42.21 72.1,42.06 72.21,41.95 72.44,41.95 72.54,41.84 72.54,41.69 72.44,41.58 72.21,41.58 72.1,41.48 72.1,40.37 73.27,39.2 74.28,39.2 75.13,38.35 75.92,38.35 v1(76.33,38.76)
CPSW_RGMII1_TD0: length 59.1
  TOP w0.147: v1(74.27,40.41) 74.41,40.27 J18.7
  L03_SIG1 w0.091: v1(77.22,85.8) 76.84,85.42 76.84,84.84 79.65,82.02 79.65,77.65 79.32,77.32 79.32,65.38 79.1,65.15 79.1,63.75 79.32,63.53 79.32,62.03 78.89,61.59 78.89,59.51 78.14,58.76 78.14,54.67 75.97,52.5 75.97,49.38 78.61,46.75 78.61,40.79 77.36,39.55 75.57,39.55 74.7,40.41 v1(74.27,40.41)
  BOTTOM w0.147: R530.2 74.71,87.44 75.64,86.51 76.86,86.51 77.22,86.15 v1(77.22,85.8)
CPSW_RGMII1_TD1: length 58.5
  TOP w0.147: J18.9 74.81,39.06 75.01,38.86 v1(75.39,38.86) ; R535.2 75.92,85.59 75.77,85.45 v1(74.88,85.45)
  L03_SIG1 w0.091: v1(74.88,85.45) 75.13,85.19 75.13,84.38 76.02,83.49 76.02,82.68 76.33,82.37 76.33,79.04 77.5,77.88 77.5,75.74 77.93,75.31 77.93,69.13 77.82,69.02 77.6,69.02 77.5,68.91 77.5,68.76 77.6,68.65 77.82,68.65 77.93,68.55 77.93,68.4 77.82,68.29 77.62,68.29 77.51,68.19 77.51,68.03 77.63,67.92 77.82,67.92 77.93,67.82 77.93,67.66 77.82,67.56 77.62,67.56 77.51,67.45 77.51,67.3 77.63,67.19 77.82,67.19 77.93,67.08 77.93,66.29 77.62,65.99 77.62,65.44 77.52,65.33 77.17,65.33 77.06,65.22 77.06,65.07 77.17,64.96 77.52,64.96 77.62,64.86 77.62,64.44 77.36,64.18 77.21,64.18 76.98,64.41 76.8,64.41 76.71,64.32 76.71,64.16 76.95,63.92 76.95,63.77 76.85,63.66 76.69,63.66 76.51,63.84 76.39,63.84 76.28,63.74 76.28,63.56 76.44,63.41 76.44,63.25 76,62.81 76,58.45 75.16,57.61 75.16,54.71 74.02,53.57 74.02,52.22 73.25,51.46 73.25,43.61 73.03,43.38 73.03,40.46 73.86,39.62 74.95,39.62 75.39,39.19 v1(75.39,38.86)
CPSW_RGMII1_TD2: length 60.4
  TOP w0.147: v1(75.01,40.82) 75.21,40.61 J18.11
  L03_SIG1 w0.091: v1(76.53,86.06) 76.28,85.81 76.28,84.98 79.38,81.89 79.38,77.77 79.04,77.44 79.04,65.51 78.82,65.28 78.82,63.63 79.04,63.4 79.04,62.15 78.59,61.7 78.59,59.61 77.83,58.85 77.83,54.89 75.52,52.58 75.52,49.24 78.33,46.43 78.33,40.92 77.27,39.85 75.97,39.85 v1(75.01,40.82)
  BOTTOM w0.147: R537.2 72.08,86.31 72.59,85.8 74.45,85.8 74.75,86.11 75.18,86.11 75.62,85.67 76.15,85.67 v1(76.53,86.06)
CPSW_RGMII1_TD3: length 60.8
  TOP w0.147: J18.13 75.61,40.78 75.92,41.1 75.92,41.1 v1(76.17,41.35)
  L03_SIG1 w0.091: v1(76.17,41.35) 76.56,40.96 77.84,40.96 78.05,41.17 78.05,44.36 77.7,44.71 77.7,44.87 77.83,45 77.83,45.15 77.73,45.26 77.58,45.26 77.44,45.13 77.29,45.13 77.18,45.23 77.18,45.38 77.32,45.52 77.32,45.67 77.21,45.78 77.06,45.78 76.92,45.64 76.77,45.64 76.67,45.75 76.67,45.9 76.8,46.04 76.8,46.19 76.69,46.29 76.54,46.29 76.41,46.16 76.26,46.16 75.19,47.23 75.19,52.77 77.52,55.1 77.52,58.95 78.31,59.74 78.31,61.82 78.77,62.28 78.77,63.27 78.54,63.5 78.54,65.41 78.77,65.63 78.77,77.57 78.92,77.72 78.92,78.08 77.93,79.07 77.93,80.82 78.69,81.58 78.69,82.17 76,84.86 76,86.33 v1(76.63,86.97)
  BOTTOM w0.147: v1(76.63,86.97) 75.9,86.97 74.86,88 R529.2
CPSW_RGMII1_TX_EN: length 63.3
  TOP w0.147: J18.35 80.01,40.16 79.25,40.92 77.12,40.92 76.89,41.15 v1(76.89,41.5) ; U136.T13 v1(70.1,87.25)
  L03_SIG1 w0.091: v1(70.1,87.25) 70.47,87.63 71.05,87.63 71.32,87.36 71.32,87.1 71.54,86.88 73.36,86.88 73.47,86.99 74.75,86.99 75.72,86.02 75.72,84.63 77.62,82.73 77.62,78.56 78.05,78.13 78.05,76 78.49,75.56 78.49,66.04 78.26,65.81 78.26,63.83 77.77,63.35 77.77,62.89 76.71,61.82 76.71,59.66 77.04,59.33 77.04,57.68 76.61,57.25 76.61,54.81 74.88,53.09 74.88,46.05 75.25,45.68 75.4,45.68 75.68,45.96 75.84,45.96 75.94,45.85 75.94,45.7 75.66,45.42 75.66,45.27 75.77,45.16 75.92,45.16 76.2,45.44 76.35,45.44 76.46,45.33 76.46,45.18 76.18,44.9 76.18,44.75 76.89,44.04 76.89,43.8 76.99,43.69 77.26,43.69 77.38,43.58 77.38,43.42 77.28,43.33 76.99,43.33 76.89,43.22 76.89,43.07 76.99,42.96 77.25,42.96 77.34,42.87 77.34,42.69 77.25,42.6 76.99,42.6 76.89,42.49 v1(76.89,41.5)
CPSW_RGMII1_TXC: length 58.6
  TOP w0.132: 74.9,86.18 74.73,86.18 74.6,86.31 v1(74.6,86.51)
  TOP w0.147: 74.9,86.18 R239.2 ; v1(73.53,40.87) 73.61,40.79 J18.3
  L03_SIG1 w0.091: v1(74.6,86.51) 75.41,85.7 75.41,84.51 76.35,83.57 76.35,82.75 76.61,82.5 76.61,79.17 77.77,78 77.77,75.87 78.21,75.44 78.21,66.17 77.98,65.94 77.98,64.39 76.28,62.69 76.28,58.32 75.44,57.48 75.44,57.21 75.55,57.1 76.05,57.1 76.17,56.99 76.17,56.84 76.07,56.74 75.55,56.74 75.44,56.63 75.44,56.48 75.55,56.37 76.05,56.37 76.17,56.26 76.17,56.1 76.07,56 75.55,56 75.44,55.9 75.44,55.75 75.55,55.64 76.04,55.64 76.14,55.54 76.14,55.36 76.05,55.27 75.55,55.27 75.44,55.17 75.44,54.58 74.3,53.44 74.3,52.1 73.53,51.33 73.53,49.32 73.64,49.21 73.84,49.21 73.94,49.11 73.94,48.95 73.84,48.85 73.64,48.85 73.53,48.74 73.53,48.59 73.64,48.48 73.84,48.48 73.94,48.37 73.94,48.22 73.84,48.12 73.64,48.12 73.53,48.01 73.53,47.86 73.64,47.75 73.84,47.75 73.94,47.64 73.94,47.49 73.84,47.38 73.64,47.38 73.53,47.28 73.53,47.12 73.64,47.02 73.84,47.02 73.94,46.91 73.94,46.76 73.84,46.65 73.64,46.65 73.53,46.54 73.53,46.39 73.64,46.29 73.78,46.29 73.92,46.14 73.92,46.01 73.83,45.92 73.64,45.92 73.53,45.81 73.53,45.66 73.64,45.55 73.81,45.55 73.92,45.45 73.92,45.3 73.81,45.19 73.64,45.19 73.53,45.08 73.53,44.93 73.64,44.82 73.81,44.82 73.92,44.72 73.92,44.56 73.81,44.46 73.64,44.46 73.53,44.35 v1(73.53,40.87)
CPSW_RGMII2_BCLK: length 42.4
  TOP w0.147: U29.2 92.16,60.61 92.74,61.19 101.19,61.19 103.56,63.55 106.15,63.55 107.72,61.98 107.72,55.47 115.11,48.08 115.11,46.41 116.05,45.47 116.05,43.66 115.87,43.48 115.54,43.48 115.29,43.23 115.12,43.23 114.84,42.95 J19.48
CPSW_RGMII2_BCLK_1V8: length 6.4
  TOP w0.147: U2347.1 93.59,54.37 93.9,54.68 93.9,55.56 93.12,56.34 92.61,56.34 92.16,56.79 U29.7
CPSW_RGMII2_BRD_CONN_DET: length 4.9
  TOP w0.147: J19.36 112.44,43.11 112.19,43.36 112.19,45.67 112.77,46.24 R341.2
CPSW_RGMII2_COL: length 6.8
  TOP w0.147: J19.14 108.04,43.35 107.92,43.46 107.92,45.84 108.33,46.25 108.33,47.18 TP588.1
CPSW_RGMII2_CRS: length 1.7
  TOP w0.147: TP589.1 111.24,43.66 J19.30
CPSW_RGMII2_ETH2_CLK: length 91.1
  TOP w0.147: v1(62.05,52.5) 62.05,52.13 61.93,52 61.93,51.63 62.42,51.13 63.83,51.13 64.34,50.62 64.34,48 65.77,46.57 65.77,44.73 66.24,44.25 67.84,44.25 70.05,42.04 70.05,34.9 71.5,33.45 78.82,33.45 80.67,31.6 83.79,31.6 87.15,34.95 87.15,41.25 94.31,48.41 103.76,48.41 105.41,50.06 109.88,50.06 111.15,48.79 111.15,45.14 110.84,44.82 J19.28
  BOTTOM w0.147: v1(62.05,52.5) 61.62,52.5 61.52,52.4 59.84,52.4 58.88,53.37 58.88,54.48 57.94,55.42 R358.2
CPSW_RGMII2_MDC: length 3
  TOP w0.147: J19.20 109.24,42.97 108.51,43.7 R356.2 R352.2
CPSW_RGMII2_MDIO: length 4.3
  TOP w0.147: R345.2 R351.1 109.96,44.95 109.64,44.63 J19.22
CPSW_RGMII2_RD0: length 86.1
  TOP w0.147: v1(110.26,38.86) 110.04,39.09 J19.23 ; U136.U15 v1(70.9,88.85)
  L03_SIG1 w0.091: v1(70.9,88.85) 71.27,88.48 71.92,88.48 72.77,89.33 74.04,89.33 74.37,89 76.94,89 81.79,84.15 81.79,78.49 82.6,77.67 82.6,66.6 83.41,65.79 83.41,59.79 84.38,58.83 85.01,58.83 85.29,58.55 85.29,55.75 86.44,54.61 87.2,54.61 87.78,54.03 88.16,54.03 88.57,53.62 88.57,52.7 95.86,45.42 99.67,45.42 102.84,42.24 103.51,42.24 103.62,42.13 103.62,41.66 103.73,41.55 103.88,41.55 103.98,41.66 103.98,42.13 104.09,42.24 104.24,42.24 104.35,42.13 104.35,41.66 104.46,41.55 104.61,41.55 104.72,41.66 104.72,42.13 104.82,42.24 104.97,42.24 105.08,42.13 105.08,41.66 105.19,41.55 105.34,41.55 105.45,41.66 105.45,42.13 105.56,42.24 106.14,42.24 106.25,42.35 106.25,42.84 106.35,42.95 106.5,42.95 106.61,42.84 106.61,42.35 106.72,42.24 106.87,42.24 106.98,42.35 106.98,42.84 107.08,42.95 107.24,42.95 107.34,42.84 107.34,42.35 107.45,42.24 107.6,42.24 107.71,42.35 107.71,42.84 107.82,42.95 107.97,42.95 108.08,42.84 108.08,42.35 108.18,42.24 108.76,42.24 109.86,41.15 110.24,41.15 110.52,40.87 110.52,39.78 110.26,39.52 v1(110.26,38.86)
CPSW_RGMII2_RD1: length 86.1
  TOP w0.147: v1(110.04,40.38) 110.28,40.38 110.44,40.23 J19.25 ; U136.V15 v1(71.7,88.05)
  L03_SIG1 w0.091: v1(71.7,88.05) 72.02,88.05 72.94,88.97 73.87,88.97 74.12,88.72 76.76,88.72 81.51,83.97 81.51,78.36 82.32,77.55 82.32,66.45 83.13,65.63 83.13,58.98 83.69,58.42 83.69,57.76 84.53,56.92 84.53,56.06 86.36,54.23 87.17,54.23 87.66,53.75 88.04,53.75 88.29,53.49 88.29,53.14 88.04,52.88 88.04,52.55 95.48,45.11 99.57,45.11 105,39.67 105.3,39.67 105.41,39.78 105.41,39.9 105.51,40.01 105.67,40.01 105.77,39.9 105.77,39.78 105.88,39.67 106.26,39.67 106.42,39.83 106.42,40.76 106.53,40.87 106.68,40.87 106.79,40.76 106.79,39.83 106.89,39.73 107.05,39.73 107.15,39.83 107.15,40.76 107.26,40.87 107.41,40.87 107.52,40.76 107.52,39.83 107.63,39.73 107.78,39.73 107.88,39.83 107.88,40.76 107.99,40.87 108.14,40.87 108.25,40.76 108.25,39.83 108.36,39.73 108.51,39.73 108.62,39.83 108.62,40.76 108.72,40.87 108.87,40.87 108.98,40.76 108.98,39.43 109.19,39.22 109.45,39.22 110.04,39.81 v1(110.04,40.38)
CPSW_RGMII2_RD2: length 86.1
  TOP w0.147: J19.27 110.84,38.21 111.15,37.9 111.15,37.19 110.11,36.14 107.75,36.14 107.16,36.73 v1(107.16,37.44) ; U136.W14 72.57,87.65 v1(72.87,87.36)
  L03_SIG1 w0.091: v1(72.87,87.36) 73.24,87.73 76.53,87.73 80.67,83.59 80.67,75.77 81.41,75.03 81.41,65.84 82.3,64.95 82.3,58.5 82.73,58.06 82.73,56.39 94.87,44.25 99.22,44.25 102.95,40.52 102.95,35.53 103.94,34.54 106.78,34.54 107.67,35.43 107.67,36.93 v1(107.16,37.44)
CPSW_RGMII2_RD3: length 86.1
  TOP w0.147: v1(111.55,40.38) 111.55,40.38 111.24,40.06 J19.29 ; U136.T15 v1(70.1,88.85)
  L03_SIG1 w0.091: v1(111.55,40.38) 111.2,40.38 111,40.59 111,41.26 108.75,43.51 108.18,43.51 108.08,43.62 108.08,43.89 107.97,43.99 107.82,43.99 107.71,43.89 107.71,43.62 107.6,43.51 107.45,43.51 107.34,43.62 107.34,43.89 107.24,43.99 107.08,43.99 106.98,43.89 106.98,43.62 106.87,43.51 106.72,43.51 106.61,43.62 106.61,43.89 106.5,43.99 106.35,43.99 106.25,43.89 106.25,43.62 106.14,43.51 105.6,43.51 105.49,43.4 105.49,42.98 105.39,42.88 105.24,42.88 105.13,42.98 105.13,43.4 105.02,43.51 104.87,43.51 104.76,43.4 104.76,42.98 104.66,42.88 104.5,42.88 104.4,42.98 104.4,43.4 104.29,43.51 104.14,43.51 104.03,43.4 104.03,42.98 103.92,42.88 103.77,42.88 103.66,42.98 103.66,43.4 103.56,43.51 103.41,43.51 103.3,43.4 103.3,42.98 103.19,42.88 103.04,42.88 102.93,42.98 102.93,43.4 102.83,43.51 102.31,43.51 99.85,45.97 96.01,45.97 89.48,52.5 89.48,53.44 85.83,57.1 85.83,60.33 84.25,61.9 84.25,66.6 83.08,67.77 83.08,78.16 82.48,78.76 82.48,79.91 82.59,80.01 82.8,80.01 82.91,80.12 82.91,80.27 82.8,80.38 82.59,80.38 82.48,80.49 82.48,80.64 82.59,80.74 82.84,80.74 82.93,80.84 82.93,80.98 82.8,81.11 82.59,81.11 82.48,81.22 82.48,82.07 82.68,82.27 82.68,83.74 77.14,89.28 75.08,89.28 74.6,89.76 72.62,89.76 72.11,89.26 70.5,89.26 v1(70.1,88.85)
CPSW_RGMII2_RSTN: length 14.3
  TOP w0.147: J19.12 v1(107.64,41.66)
  BOTTOM w0.147: U120.4 102.87,47.04 R607.1 102.87,45.4 103.03,45.24 104.1,45.24 104.76,45.9 R5825.2 105.26,46.6 105.08,46.78 105.08,47.15 105.35,47.42 106.1,47.42 108.1,45.42 108.1,42.12 v1(107.64,41.66)
CPSW_RGMII2_RX_DV: length 86.1
  TOP w0.147: U136.V14 v1(71.7,87.25) ; v1(104.93,36.8) 104.93,36.25 106.65,34.52 112.55,34.52 114.44,36.41 J19.45
  L03_SIG1 w0.091: v1(104.93,36.8) 103.23,38.51 103.23,40.63 99.33,44.53 94.98,44.53 83.01,56.5 83.01,58.19 82.58,58.62 82.58,65.38 81.71,66.24 81.71,75.16 80.95,75.92 80.95,83.72 76.66,88.01 72.45,88.01 v1(71.7,87.25)
CPSW_RGMII2_RXC: length 86.1
  TOP w0.132: U136.W15 72.99,88.45 v1(73.13,88.6)
  TOP w0.147: v1(108.85,38.09) 109.24,38.47 J19.19
  L03_SIG1 w0.091: v1(73.13,88.6) 73.36,88.37 76.71,88.37 81.23,83.85 81.23,76.05 81.99,75.29 81.99,66.37 82.85,65.51 82.85,58.75 83.29,58.32 83.29,57.58 84.25,56.62 84.25,55.78 86.08,53.95 87.04,53.95 87.43,53.56 87.43,52.52 95.12,44.83 99.41,44.83 104.93,39.32 104.93,37.85 105.35,37.42 105.35,36.49 105.08,36.22 104.7,36.22 104.44,35.97 104.44,35.46 104.67,35.23 105.51,35.23 105.94,35.66 105.94,37.82 106.34,38.22 106.34,39.16 106.45,39.27 106.6,39.27 106.71,39.16 106.71,38.19 106.82,38.09 106.97,38.09 107.07,38.19 107.07,39.16 107.18,39.27 107.33,39.27 107.44,39.16 107.44,38.19 107.55,38.09 v1(108.85,38.09)
CPSW_RGMII2_TD0: length 96.8
  TOP w0.147: v1(112.86,41.25) 112.61,41 110.01,41 109.84,40.83 107.31,40.83 106.84,40.35 J19.7
  L03_SIG1 w0.091: v1(80.29,88.04) 84.35,83.97 84.35,82.93 83.95,82.52 83.95,68.28 85.12,67.11 85.12,66.34 85.22,66.23 85.92,66.23 86.03,66.12 86.03,65.97 85.92,65.86 85.22,65.86 85.12,65.76 85.12,65.61 85.22,65.5 85.95,65.5 86.06,65.39 86.06,65.24 85.95,65.13 85.22,65.13 85.12,65.03 85.12,64.87 85.22,64.77 85.99,64.77 86.08,64.68 86.08,64.53 85.95,64.4 85.22,64.4 85.12,64.29 85.12,64.14 85.22,64.04 85.97,64.04 86.08,63.93 86.08,63.78 85.97,63.67 85.22,63.67 85.12,63.56 85.12,63.41 85.22,63.3 85.97,63.3 86.08,63.2 86.08,63.05 85.97,62.94 85.22,62.94 85.12,62.83 85.12,62.26 86.72,60.66 86.72,57.43 96.74,47.4 97.06,47.4 97.2,47.53 97.2,48.02 97.3,48.13 97.45,48.13 97.56,48.02 97.56,47.49 97.65,47.4 97.8,47.4 97.9,47.51 97.9,48.02 98.01,48.13 98.16,48.13 98.27,48.02 98.27,47.51 98.38,47.4 98.53,47.4 98.63,47.51 98.63,48.02 98.74,48.13 98.89,48.13 99,48.02 99,47.51 99.11,47.4 99.26,47.4 99.37,47.51 99.37,48.02 99.47,48.13 99.62,48.13 99.73,48.02 99.73,47.51 99.84,47.4 100.56,47.4 100.85,47.69 101.08,47.69 101.18,47.8 101.18,48.02 101.29,48.13 101.44,48.13 101.55,48.02 101.55,47.8 101.66,47.69 101.81,47.69 101.92,47.8 101.92,48.02 102.02,48.13 102.17,48.13 102.28,48.02 102.28,47.8 102.39,47.69 102.54,47.69 102.65,47.8 102.65,48.02 102.75,48.13 102.91,48.13 103.01,48.02 103.01,47.8 103.12,47.69 103.39,47.69 104.71,46.38 109.04,46.38 113.36,42.06 113.36,41.75 v1(112.86,41.25)
  BOTTOM w0.147: v1(80.29,88.04) 75.97,88.04 75.39,88.62 74.38,88.62 74.21,88.79 R509.2
CPSW_RGMII2_TD1: length 99.5
  TOP w0.147: v1(111.02,36.35) 111.02,35.92 110.77,35.66 107.54,35.66 106.6,36.6 106.6,38.25 107.24,38.88 J19.9 ; R518.2 76.22,88.32 76.66,88.75 v1(76.66,89.71)
  L03_SIG1 w0.091: v1(111.02,36.35) 109.14,36.35 108.62,36.88 108.62,37.24 108.87,37.49 109.73,37.49 110.69,38.45 110.69,38.98 111.42,39.71 111.69,39.71 111.99,40.01 111.99,40.74 111.33,41.4 111.33,41.91 110.82,42.41 110.82,42.57 111.19,42.93 111.19,43.09 111.09,43.19 110.93,43.19 110.57,42.82 110.41,42.82 110.31,42.93 110.31,43.08 110.68,43.45 110.68,43.6 110.57,43.71 110.42,43.71 110.05,43.34 109.9,43.34 109.79,43.45 109.79,43.6 110.16,43.97 110.16,44.12 110.05,44.23 109.9,44.23 109.53,43.86 109.38,43.86 108.03,45.21 107.73,45.21 107.63,45.32 107.63,45.56 107.52,45.67 107.37,45.67 107.26,45.56 107.26,45.32 107.15,45.21 106.27,45.21 106.03,45.46 104.59,45.46 104.09,44.96 103.46,44.96 103.35,45.07 103.35,45.79 103.25,45.9 103.1,45.9 102.99,45.79 102.99,45.07 102.88,44.96 102.73,44.96 102.62,45.07 102.62,45.79 102.52,45.9 102.36,45.9 102.26,45.79 102.26,45.07 102.15,44.96 101.63,44.96 101.41,45.17 101.41,45.32 101.69,45.6 101.69,45.75 101.59,45.86 101.43,45.86 101.15,45.58 101,45.58 100.89,45.69 100.89,45.84 101.17,46.12 101.17,46.27 101.07,46.38 100.92,46.38 100.64,46.1 100.48,46.1 100.33,46.25 96.14,46.25 89.76,52.63 89.76,53.57 86.11,57.23 86.11,60.45 84.53,62.03 84.53,66.73 83.39,67.87 83.39,82.58 83.06,82.91 83.06,84.15 78.99,88.21 78.64,88.21 77.14,89.71 v1(76.66,89.71)
CPSW_RGMII2_TD2: length 98.4
  TOP w0.147: J19.11 107.64,38.6 107.54,38.51 107.54,37.72 107.7,37.57 107.7,36.83 107.92,36.6 109.63,36.6 110.29,37.26 v1(110.52,37.26)
  L03_SIG1 w0.091: v1(78.71,89.64) 82.12,89.64 85.6,86.16 85.6,83.38 84.51,82.29 84.51,68.71 87.33,65.89 87.33,57.63 88.75,56.21 90.07,56.21 90.25,56.02 90.25,55.87 90.14,55.76 90.14,55.61 90.25,55.5 90.4,55.5 90.51,55.61 90.66,55.61 90.77,55.51 90.77,55.36 90.66,55.24 90.66,55.09 90.76,54.98 90.91,54.98 91.03,55.1 91.18,55.1 91.29,54.99 91.29,54.84 91.17,54.72 91.17,54.57 91.28,54.47 91.43,54.47 91.55,54.58 91.7,54.58 91.81,54.47 91.81,54.32 91.69,54.21 91.69,54.05 91.8,53.95 91.95,53.95 92.06,54.06 92.22,54.06 92.32,53.96 92.32,53.8 92.21,53.69 92.21,53.54 92.31,53.43 92.47,53.43 92.58,53.55 92.73,53.55 92.84,53.44 92.84,53.29 92.72,53.17 92.72,53.02 92.83,52.91 92.98,52.91 93.1,53.03 93.25,53.03 93.36,52.92 93.36,52.77 93.24,52.65 93.24,52.5 93.35,52.4 93.5,52.4 93.62,52.51 93.77,52.51 93.87,52.4 93.87,52.25 93.76,52.14 93.76,51.99 93.87,51.88 94.02,51.88 94.13,51.99 94.28,51.99 94.39,51.89 94.39,51.74 94.25,51.6 94.25,51.47 94.36,51.36 94.54,51.36 94.65,51.48 94.8,51.48 97.6,48.68 104.85,48.68 105.31,48.21 109.3,48.21 112.24,45.26 112.24,44.12 114.13,42.23 114.13,41.29 114.66,40.77 114.66,40.24 113.58,39.16 111.65,39.16 111.38,38.89 111.38,37.45 111.19,37.26 v1(110.52,37.26)
  BOTTOM w0.147: v1(78.71,89.64) 77.7,88.62 76.2,88.62 74.87,89.95 73.46,89.95 73.17,89.65 R527.2
CPSW_RGMII2_TD3: length 98.5
  TOP w0.147: v1(109.04,37.06) 108.43,37.06 108.15,37.34 108.15,37.74 108.04,37.86 J19.13
  L03_SIG1 w0.091: v1(77.93,90.07) 77.93,89.74 78.9,88.77 81.1,88.77 82.14,87.73 82.14,86.87 84.79,84.23 84.79,82.96 84.23,82.4 84.23,68.58 87.04,65.77 87.04,57.51 88.62,55.93 89.33,55.93 89.62,55.64 89.62,55.49 89.51,55.38 89.51,55.23 89.62,55.12 89.77,55.12 89.88,55.23 90.03,55.23 90.14,55.13 90.14,54.97 90.03,54.86 90.03,54.71 90.13,54.6 90.28,54.6 90.4,54.72 90.55,54.72 90.65,54.61 90.65,54.46 90.54,54.35 90.54,54.19 90.65,54.09 90.8,54.09 90.91,54.2 91.06,54.2 91.17,54.09 91.17,53.94 91.06,53.83 91.06,53.68 91.17,53.57 91.32,53.57 91.43,53.68 91.58,53.68 91.69,53.57 91.69,53.42 91.58,53.31 91.58,53.16 91.68,53.05 91.84,53.05 91.95,53.16 92.1,53.16 92.21,53.06 92.21,52.91 92.09,52.79 92.09,52.64 92.2,52.53 92.35,52.53 92.46,52.65 92.62,52.65 92.72,52.54 92.72,52.39 92.61,52.28 92.61,52.12 92.72,52.02 92.87,52.02 92.98,52.13 93.13,52.13 93.24,52.02 93.24,51.87 93.13,51.76 93.13,51.61 93.24,51.5 93.39,51.5 93.5,51.61 93.65,51.61 93.76,51.5 93.76,51.35 93.65,51.24 93.65,51.09 93.75,50.98 93.9,50.98 94.02,51.09 94.17,51.09 94.28,50.99 94.28,50.84 94.16,50.72 94.16,50.57 94.27,50.47 94.42,50.47 94.53,50.58 94.69,50.58 94.79,50.47 94.79,50.32 94.68,50.21 94.68,50.06 94.79,49.95 94.94,49.95 95.05,50.06 95.2,50.06 95.31,49.95 95.31,49.8 95.2,49.69 95.2,49.54 95.31,49.43 95.46,49.43 95.57,49.54 95.72,49.54 95.83,49.44 95.83,49.28 95.72,49.17 95.72,49.02 95.82,48.91 95.97,48.91 96.09,49.03 96.24,49.03 96.86,48.4 104.71,48.4 106.38,46.74 109.09,46.74 109.3,46.53 109.45,46.53 109.7,46.79 109.86,46.79 109.96,46.68 109.96,46.53 109.71,46.27 109.71,46.12 109.82,46.01 109.97,46.01 110.22,46.27 110.37,46.27 110.48,46.16 110.48,46.01 110.23,45.75 110.23,45.6 110.33,45.5 110.48,45.5 110.74,45.75 110.89,45.75 111,45.64 111,45.49 110.74,45.24 110.74,45.09 110.85,44.98 111,44.98 111.31,45.28 111.48,45.28 111.59,45.18 111.59,45.03 111.26,44.7 111.26,44.57 113.74,42.09 113.74,39.72 113.45,39.44 111.54,39.44 110.96,38.86 110.96,38.33 109.69,37.06 v1(109.04,37.06)
  BOTTOM w0.147: R528.2 75.04,90.46 76.33,89.18 76.81,89.18 77.7,90.07 v1(77.93,90.07)
CPSW_RGMII2_TX_EN: length 99.5
  TOP w0.147: v1(112.55,40.39) 112.44,40.27 J19.35 ; U136.U16 v1(70.9,89.65)
  L03_SIG1 w0.091: v1(70.9,89.65) 71.31,90.07 71.83,90.07 71.91,89.99 76.3,89.99 76.48,90.17 77.09,90.17 78.77,88.49 79.2,88.49 83.34,84.35 83.34,83.85 83.92,83.26 83.92,82.91 83.67,82.65 83.67,68 84.84,66.83 84.84,62.13 86.39,60.58 86.39,57.35 90.47,53.27 90.47,53.12 90.19,52.85 90.19,52.69 90.3,52.59 90.45,52.59 90.72,52.86 90.88,52.86 90.98,52.76 90.98,52.6 90.71,52.33 90.71,52.18 90.81,52.07 90.97,52.07 91.24,52.35 91.39,52.35 91.5,52.24 91.5,52.09 91.22,51.81 91.22,51.66 91.33,51.55 91.48,51.55 91.76,51.83 91.91,51.83 92.02,51.72 92.02,51.57 91.74,51.29 91.74,51.14 91.85,51.03 92,51.03 92.28,51.31 92.43,51.31 92.53,51.2 92.53,51.05 92.26,50.78 92.26,50.62 92.37,50.52 92.52,50.52 92.79,50.79 92.94,50.79 93.05,50.69 93.05,50.54 92.78,50.26 92.78,50.11 92.88,50 93.03,50 93.31,50.28 93.46,50.28 93.57,50.17 93.57,50.02 93.29,49.74 93.29,49.59 93.4,49.48 93.55,49.48 93.83,49.76 93.98,49.76 94.09,49.65 94.09,49.5 93.81,49.22 93.81,49.07 93.92,48.97 94.07,48.97 94.35,49.24 94.5,49.24 94.6,49.13 94.6,48.98 94.33,48.71 94.33,48.56 94.43,48.45 94.59,48.45 94.86,48.72 95.01,48.72 95.12,48.62 95.12,48.47 94.84,48.19 94.84,48.04 94.95,47.93 95.1,47.93 95.38,48.21 95.53,48.21 95.64,48.1 95.64,47.97 95.31,47.65 95.31,47.5 95.42,47.39 95.57,47.39 95.87,47.69 96.05,47.69 96.15,47.58 96.15,47.46 95.8,47.1 95.8,47 95.95,46.85 96.09,46.85 96.41,47.17 96.57,47.17 96.65,47.09 97.31,47.09 97.42,46.98 97.42,46.63 97.52,46.53 97.67,46.53 97.78,46.63 97.78,46.98 97.89,47.09 98.04,47.09 98.15,46.98 98.15,46.63 98.25,46.53 98.41,46.53 98.51,46.63 98.51,46.98 98.62,47.09 98.77,47.09 98.88,46.98 98.88,46.63 98.99,46.53 99.14,46.53 99.24,46.63 99.24,46.98 99.35,47.09 99.5,47.09 99.61,46.98 99.61,46.63 99.72,46.53 99.87,46.53 99.98,46.63 99.98,46.98 100.08,47.09 100.64,47.09 100.96,47.42 101.69,47.42 101.79,47.31 101.79,46.81 101.9,46.71 102.05,46.71 102.16,46.81 102.16,47.31 102.27,47.42 102.42,47.42 102.55,47.29 102.55,46.61 102.66,46.5 102.81,46.5 102.92,46.61 102.92,47.33 103.01,47.42 103.28,47.42 104.6,46.1 104.82,46.1 104.92,45.99 104.92,45.84 105.03,45.73 105.18,45.73 105.29,45.84 105.29,45.99 105.4,46.1 105.55,46.1 105.66,45.99 105.66,45.84 105.76,45.73 105.91,45.73 106.02,45.84 106.02,45.99 106.13,46.1 107.92,46.1 108.08,45.94 108.08,45.57 108.19,45.47 108.34,45.47 108.45,45.57 108.45,46.01 108.54,46.1 108.71,46.1 112.27,42.55 112.27,41.02 112.55,40.74 v1(112.55,40.39)
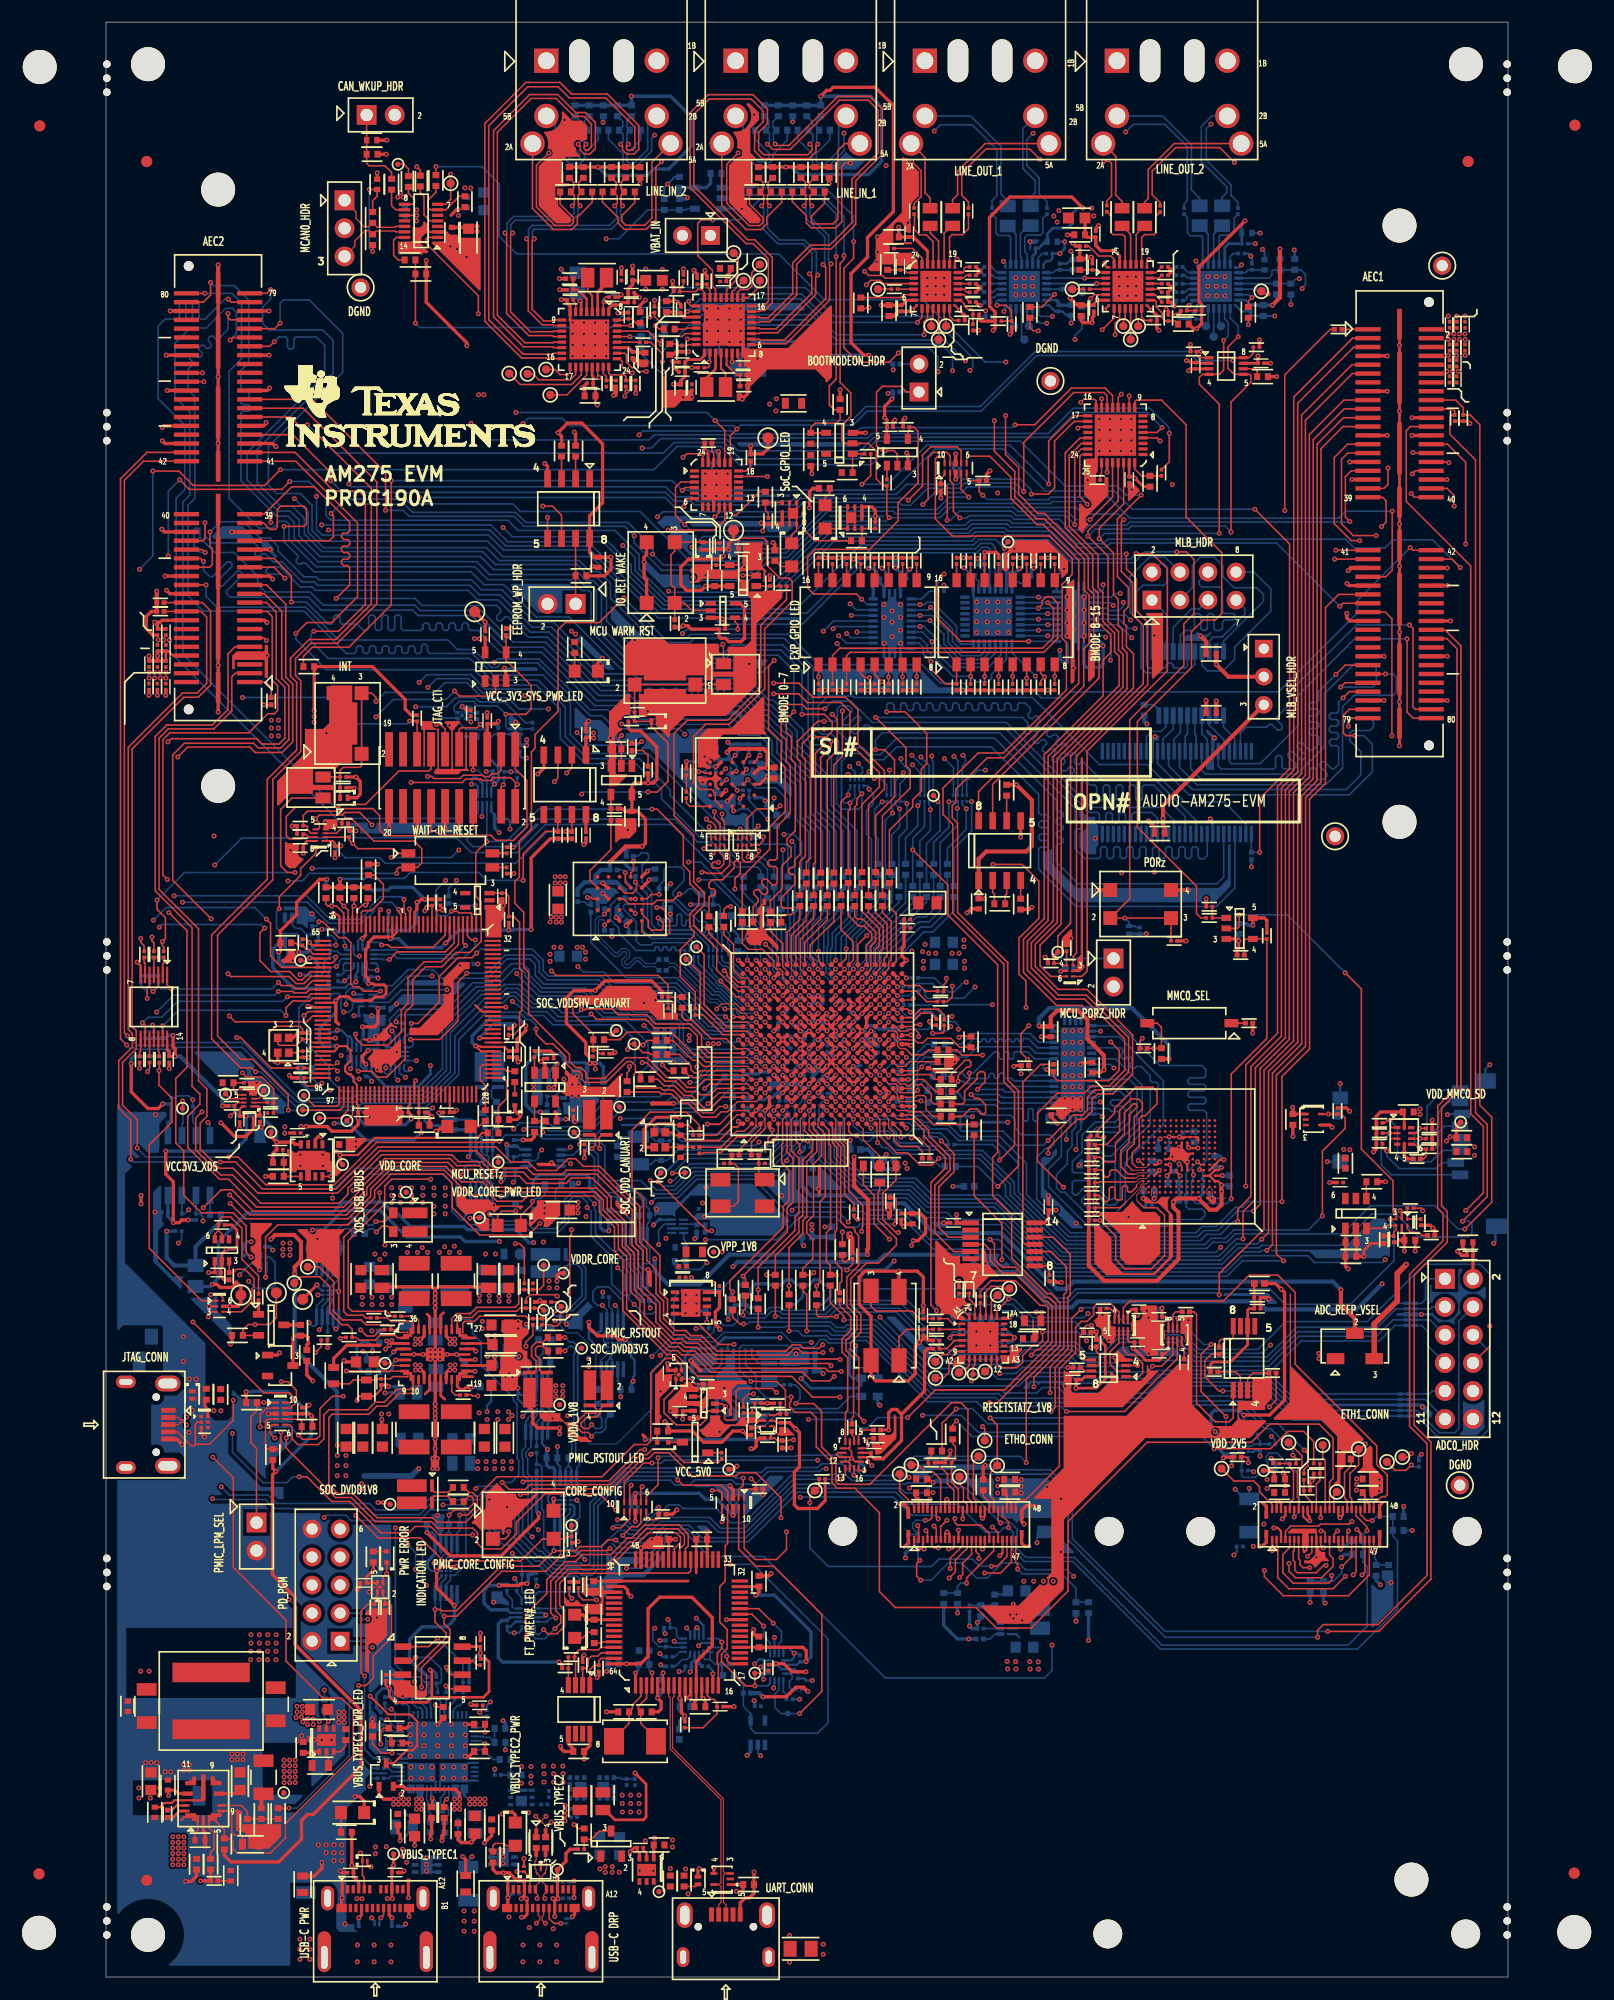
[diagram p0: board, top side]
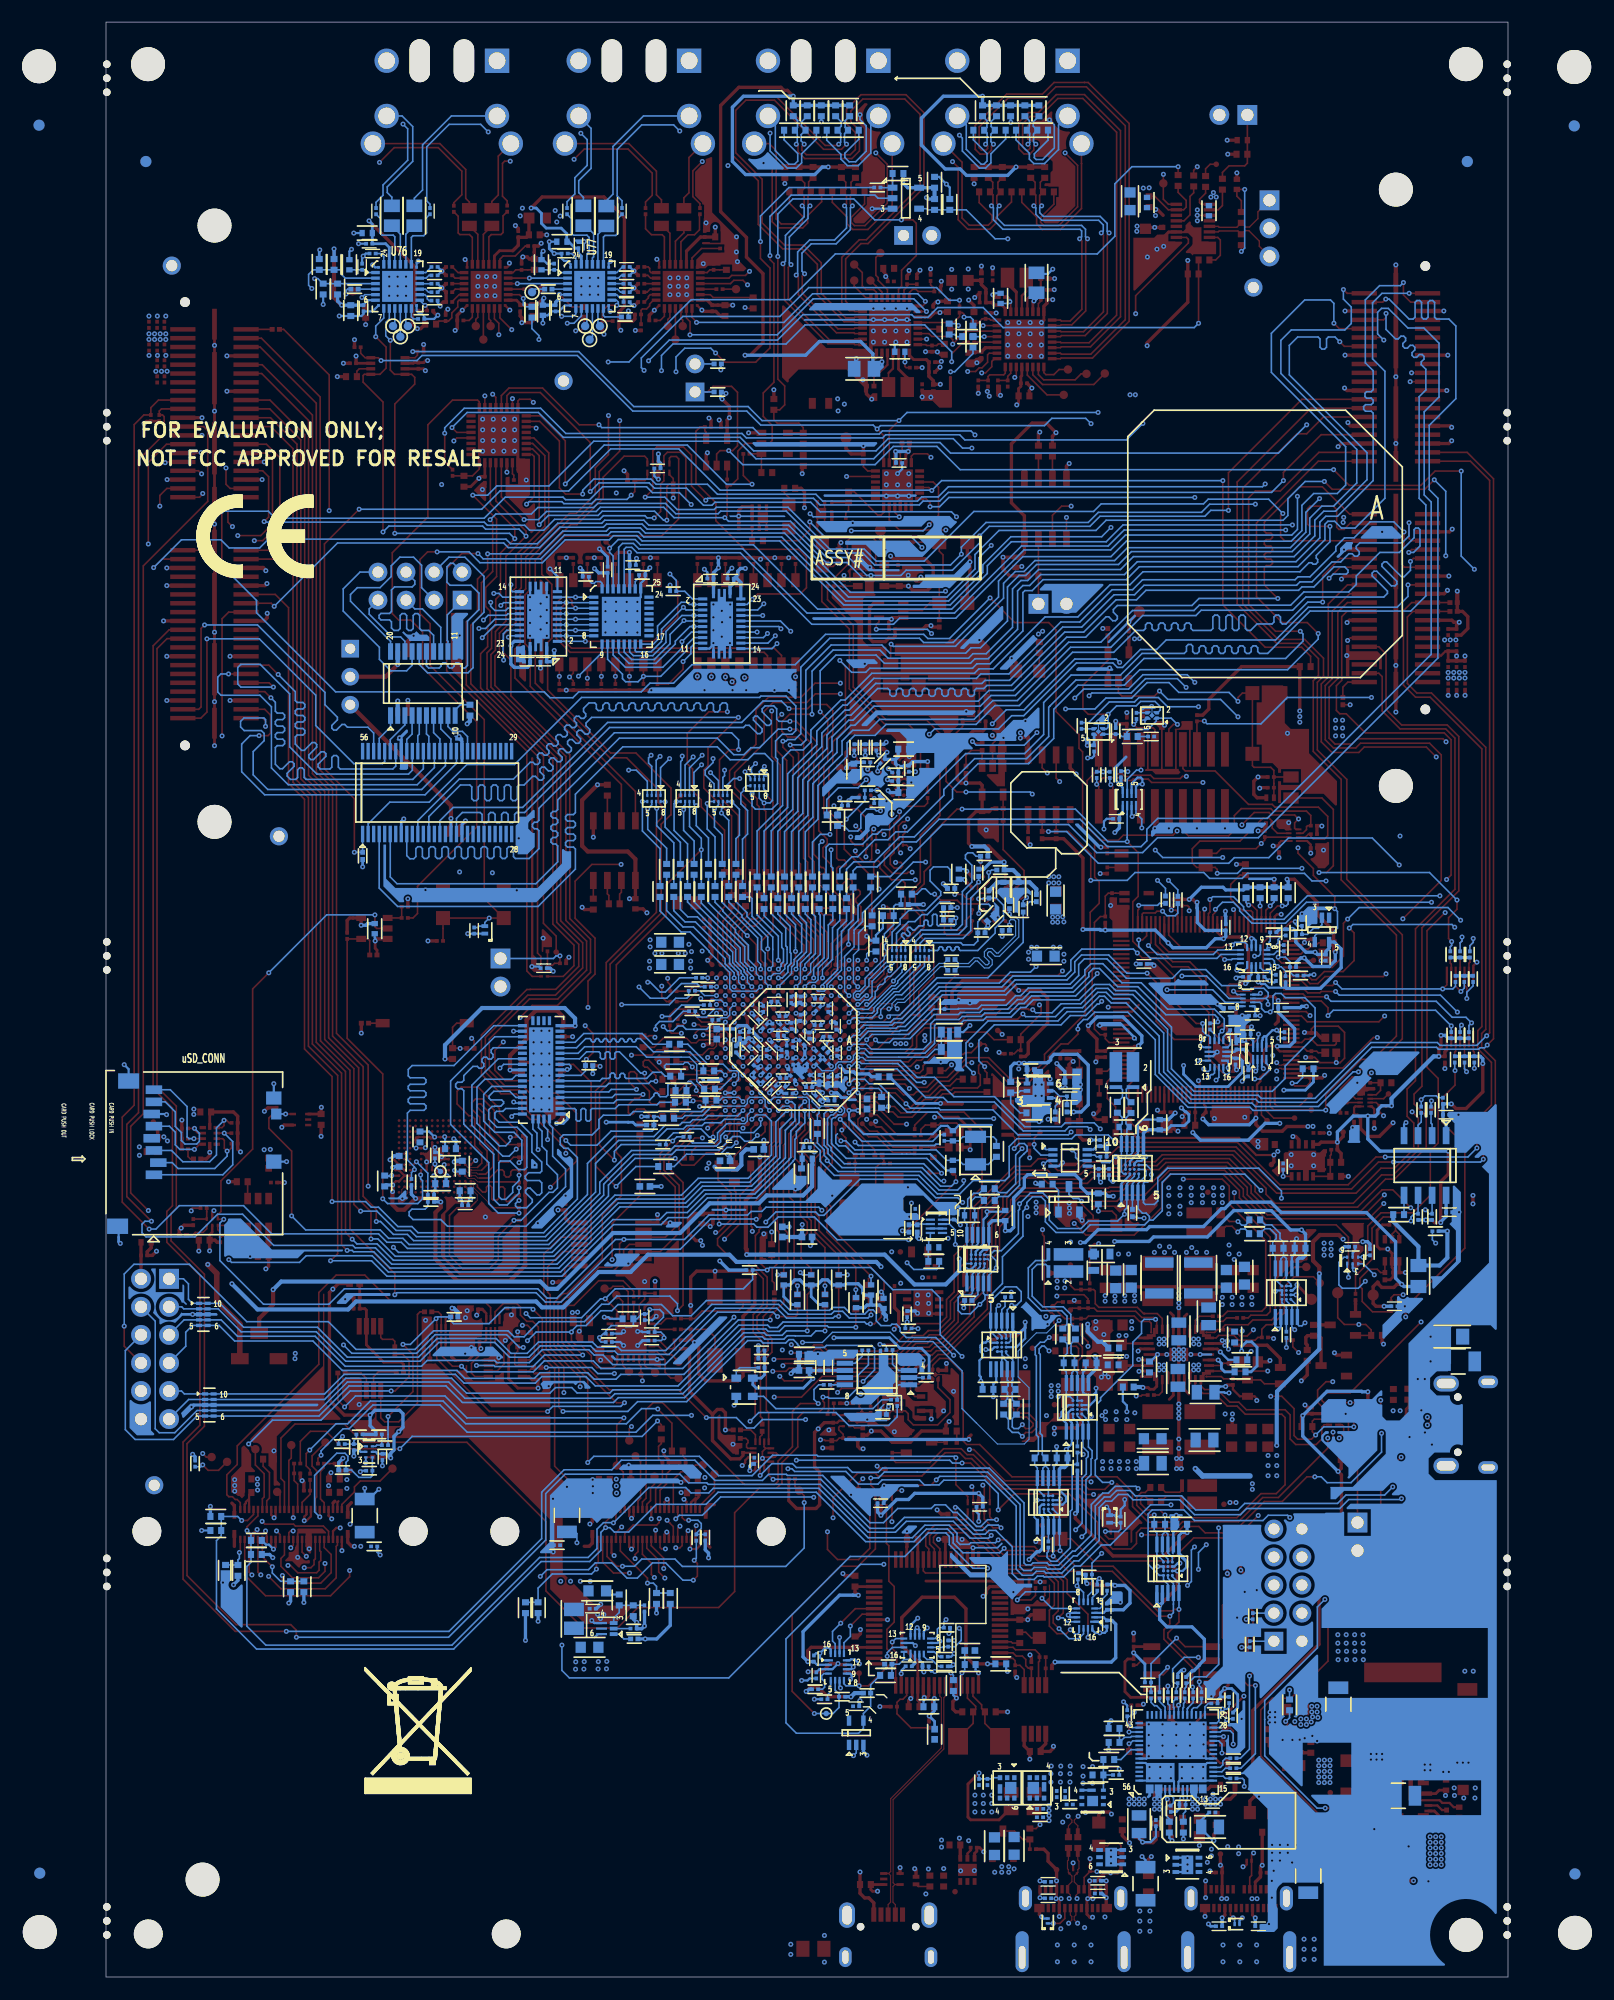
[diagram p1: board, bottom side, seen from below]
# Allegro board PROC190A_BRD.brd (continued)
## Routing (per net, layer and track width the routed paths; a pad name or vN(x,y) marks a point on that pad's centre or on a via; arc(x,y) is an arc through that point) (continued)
CPSW_RGMII2_TXC: length 95.9
  TOP w0.147: R228.2 75.88,89.83 76.12,90.07 v1(76.12,90.42) ; J19.3 106.04,39.1 106.15,38.99 106.15,36.14 107.14,35.15 111.15,35.15 v1(112.27,36.27)
  L03_SIG1 w0.091: v1(76.12,90.42) 76.53,90.83 81.36,90.83 85.88,86.31 85.88,81.03 84.79,79.93 84.79,68.83 87.61,66.01 87.61,57.75 88.87,56.49 90.4,56.49 96.9,49.99 103.92,49.99 105.4,48.51 109.7,48.51 111.99,46.23 112.98,46.23 113.89,45.31 113.89,42.86 115.14,41.62 115.14,40.23 112.62,37.72 112.62,37.06 112.27,36.7 v1(112.27,36.27)
CPSW_RGMII2_TXC_R: length 3.6
  TOP w0.147: U136.W17 72.38,89.77 73.68,89.77 74.2,89.25 R228.1
CPSW_RGMII_INTN: length 52.7
  TOP w0.147: J18.10 74.81,41.59 74.57,41.35 v1(74.22,41.35) ; R346.1 107.8,46.96 v1(107.52,47.24)
  L03_SIG1 w0.091: v1(74.22,41.35) 74.22,48.92 74.52,49.23 74.52,50.29 v1(73.96,50.85)
  BOTTOM w0.147: v1(74.22,41.35) 73.37,41.35 73.08,41.06 73.08,40.62 73.53,40.17 R621.2 72.73,40.07 R620.1 ; v1(107.52,47.24) 107.52,47.64 105.52,49.63 104.98,49.63 102.82,51.79 96.75,51.79 94.28,49.33 78.99,49.33 77.47,50.85 v1(73.96,50.85)
CPSW_RGMII_INTN_R: length 5.4
  TOP w0.147: R344.2 106.73,46.49 106.74,46.48 R346.2 107.24,46.1 107.57,45.77 107.57,43.28 107.42,43.13 107.42,43.13 107.24,42.95 J19.10
CPSW_RGMII_TXC_R: length 4.6
  TOP w0.132: 73.05,86.46 71.69,86.46
  TOP w0.147: 71.69,86.46 U136.V13 ; R239.1 75.21,86.75 74.69,87.27 73.86,87.27 73.05,86.46
DEBOUNCE_GPIO_INT_MCU_SOC: length 78.1
  TOP w0.147: C489.2 21.21,109.24 21.49,109.52 23.01,109.52 23.15,109.67 SW5.2 SW5.3 24.06,116.25 24.46,115.85 v1(24.46,115.49) ; C489.2 21.21,108.05 R559.2 D11.2 ; C489.2 Q7.2
  L03_SIG1 w0.091: v1(42.09,73.63) 41.02,74.7 41.02,77.24 41.2,77.42 41.2,80.49 40.89,80.8 40.89,81.74 41.92,82.76 41.92,85.65 43.48,87.22 43.48,87.76 41.3,89.94 41.3,90.75 40.51,91.54 40.05,91.54 39.73,91.86 39.73,95.05 39.27,95.5 39.27,107.95 40.08,108.76 v1(40.08,114.81)
  BOTTOM w0.147: U98.3 41.7,73.92 41.99,73.63 v1(42.09,73.63) ; v1(24.46,115.49) 25.28,116.31 29.82,116.31 30.71,117.2 32.69,117.2 34.09,115.8 36.42,115.8 37.41,114.81 v1(40.08,114.81)
DEBOUNCE_IORET_WAKE: length 14.9
  TOP w0.147: SW10.2 51.52,125.75 51.18,126.09 51.18,128.76 51.52,129.1 SW10.3 D18.2 55.08,129.91 55.14,129.85 C3741.2 ; SW10.2 R5756.2 ; SW10.2 52.38,124.41 53.06,123.72 U3070.2
DEBOUNCE_MCU_RESETZ: length 63.3
  TOP w0.147: Q12.2 SW6.3 SW6.2 47.88,116.2 C609.2 47.88,114.2 R615.2 D12.2 49.41,113.21 50.9,111.72 50.9,108.25 49.94,107.29 v1(49.1,107.29)
  L03_SIG1 w0.091: v1(43.09,107.1) 42.52,106.53 42.52,94.89 43.92,93.5 43.92,91.59 43.54,91.21 43.54,89.03 44.93,87.63 44.93,86.77 43.03,84.87 43.03,82.24 43.56,81.71 43.56,76.63 v1(42.06,75.13)
  BOTTOM w0.147: v1(42.06,75.13) 41.85,74.92 U98.1 ; v1(49.1,107.29) 43.28,107.29 v1(43.09,107.1)
DEBOUNCE_SOC_PORZ: length 179.7
  TOP w0.147: R375.2 96.47,94.94 96.47,94.94 SW8.3 v1(92.29,95.88) SW8.2 92.74,97.64 92.74,113.84 97.64,118.75 97.64,122.52 98.55,123.44 98.55,128.35 97.87,129.03 v1(97,129.03)
  L03_SIG1 w0.091: v1(35.97,131.24) 35.97,120.35 36.91,119.41 36.91,116.33 35.08,114.5 35.08,110.85 33.93,109.7 33.93,106.22 36.07,104.09 36.07,103.31 35.46,102.7 35.46,94.03 38.33,91.16 38.33,88.67 36.28,86.62 36.28,80.3 39.07,77.52 39.07,75.29 v1(39.47,74.88)
  BOTTOM w0.147: U98.6 38.89,73.92 39.17,74.19 39.17,74.57 v1(39.47,74.88) ; v1(92.29,95.88) 92.68,95.48 D14.2 93.19,95.15 93.31,95.02 C622.2 ; v1(97,129.03) 94.11,129.03 93.12,128.05 87.47,128.05 85.39,130.12 81.41,130.12 81.03,130.5 78.91,130.5 78.44,130.02 65.96,130.02 60.17,124.23 50.52,124.23 47.57,127.18 47.57,127.86 45.03,130.4 36.8,130.4 v1(35.97,131.24)
DIR: length 20.5
  TOP w0.147: v1(83.58,120.93) 77.42,120.93 75.21,123.14 75.21,126.32 v1(75.92,127.03)
  BOTTOM w0.147: v1(75.92,127.03) 75.34,126.45 R461.1 74.57,125.47 73.88,124.77 U83.2 ; U81.2 v1(83.58,120.93)
DRAIN1: length 3.2
  BOTTOM w0.191: v1(29.54,18) 29.85,17.69 U129.8 ; v1(27.61,18) 27.4,17.78 U129.15 ; U129.19 27.25,19.38 v1(27.61,19.01)
  vias: v1(28.58,19.01) v1(28.58,18) v1(29.54,19.01)
DRAIN2: length 3.2
  BOTTOM w0.191: U129.56 32.69,17.78 v1(32.47,18) ; U129.7 30.25,17.71 v1(30.54,18) ; U129.52 32.84,19.38 v1(32.47,19.01)
  vias: v1(30.54,19.01) v1(31.5,19.01) v1(31.5,18)
ECAP0_IN_APWM_OUT: length 172.8
  TOP w0.147: J13.11 14.29,121.24 v1(14.53,121.01) ; v1(16.33,48.79) 16.33,47.88 20.8,43.41 22.23,43.41 24.41,41.22 29.48,41.22 30.06,40.64 33.23,40.64 33.65,40.22 33.65,39.25 34.14,38.76 35.81,38.76 37.19,40.13 37.19,41.17 39.75,43.74 44.73,43.74 v1(46.18,42.29) ; R5685.1 71.56,72.17 70.36,70.97 70.36,68.61 71.55,67.41 v1(71.78,67.41)
  L03_SIG1 w0.091: v1(71.78,67.41) 72.19,67.01 72.19,65.01 70.56,63.38 70.56,57.19 65.38,52.01 65.38,46.17 v1(65.23,46.02) ; v1(16.33,48.79) 15.75,48.21 14.76,48.21 13.36,49.61 13.36,54.66 14.27,55.58 14.27,62.76 13.28,63.75 13.28,64.08 12.34,65.02 12.34,68.78 12.7,69.14 12.7,77.04 12.27,77.47 12.27,78.74 11.94,79.07 11.94,83.6 12.6,84.25 12.6,91.01 11.25,92.35 11.25,103.94 13.46,106.15 13.46,119.94 v1(14.53,121.01)
  BOTTOM w0.147: v1(65.23,46.02) 64.87,46.02 64.62,45.77 59.99,45.77 58.84,44.63 57.07,44.63 56.69,45.01 53.31,45.01 52.86,44.55 51.53,44.55 51.11,44.98 47.39,44.98 46.18,43.77 v1(46.18,42.29)
ECAP1_IN_APWM_OUT: length 131.2
  TOP w0.147: U136.P2 v1(68.5,77.65) ; J12.9 112.86,145.98 108.3,141.42 108.3,108.96 106.83,107.49 106.83,85.04 104.11,82.32 104.11,70.41 103,69.29 v1(103,66.83)
  BOTTOM w0.132: v1(68.5,77.65) 68.1,78.05 67.28,78.05
  BOTTOM w0.147: 67.28,78.05 66.73,77.5 66.73,74.42 68.83,72.31 73.36,72.31 74.88,70.79 80.9,70.79 86.44,65.25 100.8,65.25 102.37,66.83 v1(103,66.83)
ECAP2_IN_APWM_OUT: length 123.5
  TOP w0.147: U136.R3 v1(69.3,78.46) ; v1(103.94,69.34) 104.54,69.95 104.54,82.24 107.19,84.89 107.19,107.34 108.65,108.8 108.65,140.93 112.89,145.18 J12.11
  BOTTOM w0.147: v1(69.3,78.46) 69.77,77.98 72.47,77.98 72.82,77.62 73.84,77.62 74.09,77.37 74.81,77.37 75.04,77.14 76.33,77.14 77.37,76.1 80.95,76.1 83.39,73.66 83.39,70.84 87.2,67.03 98.88,67.03 99.44,67.59 100.71,67.59 102.46,69.34 v1(103.94,69.34)
ECAP3_IN_APWM_OUT: length 156.5
  TOP w0.147: U136.P4 v1(68.5,79.26) ; J13.9 11.7,120.44 11.05,119.79 11.05,114.78 9.63,113.36 5.5,113.36 4.46,112.31 4.46,98.34 7.8,95 7.8,80.64 8.51,79.93 8.51,79.04 7.41,77.94 7.41,75.11 10.28,72.24 11.1,72.24 13.63,69.71 21.5,69.71 22.91,71.11 22.91,71.76 25.24,74.09 31.16,74.09 31.8,73.46 33.81,73.46 34.75,72.52 37.44,72.52 38.1,71.86 41.68,71.86 42.16,72.34 44.04,72.34 45.75,70.63 45.75,69.7 47.11,68.34 47.11,66.29 47.86,65.54 47.86,62.24 48.77,61.33 48.77,59.86 51.22,57.41 52.06,57.41 52.45,57.02 53.5,57.02 54.97,55.55 65.48,55.55 v1(65.68,55.35)
  L03_SIG1 w0.091: v1(65.68,55.35) 66.07,55.73 66.07,56.08 68.12,58.14 68.12,66.17 68.91,66.95 68.91,72.03 69.25,72.37 69.25,75.75 69.67,76.18 69.67,78.61 69.43,78.85 68.9,78.85 v1(68.5,79.26)
EEPROM_A1: length 2
  TOP w0.147: U2358.2 R5745.2
EEPROM_A2: length 2
  TOP w0.147: U2358.3 R5744.1
EEPROM_WP: length 5.9
  TOP w0.147: U2358.7 R5746.1 J33.1
EMMC_CLK: length 30.2
  TOP w0.147: v1(98.88,73.81) 99.15,73.55 U49.M6
  BOTTOM w0.147: v1(98.88,73.81) 97.85,72.78 R561.1 R565.2 97.85,69.77 98.09,69.52 99.29,69.52 99.54,69.27 99.54,68.93 99.18,68.58 96.67,68.58 96.06,67.97 88.95,67.97 85.37,71.55 85.37,73.15 86.54,74.32 86.54,76.89 86.83,77.18 U57.42
EMMC_CMD: length 31.1
  TOP w0.147: U49.M5 99.11,73.05 v1(99.06,73.1)
  BOTTOM w0.147: U57.22 91.87,86.13 95.48,82.52 99.26,82.52 99.62,82.17 99.62,81.59 99.45,81.41 98.19,81.41 98.02,81.24 98.02,81 98.19,80.83 99.45,80.83 99.62,80.65 99.62,80.41 99.45,80.24 98.19,80.24 98.02,80.06 98.02,79.82 98.19,79.65 99.45,79.65 99.62,79.47 99.62,79.23 99.45,79.06 98.19,79.06 98.02,78.89 98.02,78.64 98.19,78.47 99.45,78.47 99.7,78.22 99.7,73.98 99.06,73.34 v1(99.06,73.1) 99.33,72.83 R575.2
EMMC_D0: length 30.2
  TOP w0.081: U49.A3 93.71,72.05 93.35,71.7
  TOP w0.147: v1(89.58,70.31) R269.2 89.94,70.79 90.52,70.21 90.68,70.21 90.88,70.4 90.88,71.37 91.05,71.55 91.26,71.55 91.41,71.4 91.41,70.51 91.56,70.36 91.96,70.36 92.05,70.45 92.05,71.5 92.21,71.65 92.38,71.65 92.53,71.51 92.53,71.17 92.64,71.07 92.89,71.07 93.35,71.54 93.35,71.7
  BOTTOM w0.147: U57.37 90.8,78.63 91.05,78.38 91.62,78.38 91.77,78.23 91.77,77.76 91.4,77.39 89.59,77.39 88.42,76.23 88.42,74.68 87.53,73.79 87.53,72.97 87.68,72.82 88.72,72.82 89.03,72.52 89.03,72.31 88.83,72.11 87.73,72.11 87.53,71.91 87.53,71.01 87.72,70.81 87.97,70.81 88.58,71.43 88.79,71.43 88.99,71.22 88.99,71.01 88.38,70.4 88.38,70.15 88.89,69.65 89.74,69.65 89.91,69.81 89.91,70.02 89.62,70.31 v1(89.58,70.31)
EMMC_D1: length 30.2
  TOP w0.081: U49.A4 93.53,72.55 93.32,72.34 93.17,72.34
  TOP w0.147: 93.17,72.34 92.25,72.34 91.51,73.08 91.1,73.08 90.92,72.91 90.92,72.6 90.75,72.43 90.51,72.43 90.33,72.6 90.33,72.91 90.16,73.08 R266.2 v1(89.58,72.59)
  BOTTOM w0.147: U57.35 89.86,79.63 90.41,80.19 91.87,80.19 92.29,79.77 92.29,79.56 92.15,79.41 91.16,79.41 90.98,79.24 90.98,79.1 91.24,78.84 91.8,78.84 91.82,78.82 92.03,78.82 92.33,78.52 92.33,77.67 91.59,76.94 89.76,76.94 88.87,76.05 88.87,73.3 89.08,73.1 89.62,73.1 90.4,73.88 91.27,73.88 91.41,73.73 91.41,70.66 91.16,70.41 90.78,70.41 90.16,71.03 90.16,71.54 89.58,72.11 v1(89.58,72.59)
EMMC_D2: length 30.3
  TOP w0.081: U49.A5 92.97,73.05
  TOP w0.147: v1(89.84,74.96) 89.58,75.21 R263.2 90.63,75.37 91.82,76.56 91.82,78.46 92.86,79.5 93.52,79.5 93.88,79.15 93.88,78.59 93.14,77.85 93.14,75.46 92.48,74.8 92.48,73.53 92.97,73.05
  BOTTOM w0.147: v1(89.84,74.96) 90.47,74.32 91.06,74.32 93.85,77.11 93.85,80.75 91.47,83.13 U57.28
EMMC_D3: length 30.6
  TOP w0.081: U49.B2 94.21,71.3 93.85,71.3 93.37,70.82 93.37,70.31 93.52,70.15
  TOP w0.147: R275.2 v1(90.04,68.51) 91.47,67.08 91.47,64.95 92.3,64.11 94.69,64.11 95.89,65.3 95.89,68.96 95.2,69.65 94.03,69.65 93.52,70.15
  BOTTOM w0.147: v1(90.04,68.51) 89.4,68.51 86.87,71.04 86.51,71.04 86.11,71.45 86.11,72.64 87.07,73.61 87.07,74.78 87.5,75.21 87.5,76.58 87.83,76.91 U57.40
EMMC_D4: length 30.3
  TOP w0.081: U49.B3 94.2,71.8 93.84,71.8 93.7,71.65 93.7,71.48 92.38,70.15
  TOP w0.147: 92.38,70.15 91.88,69.65 R270.2 v1(89.58,69.16)
  BOTTOM w0.147: v1(89.58,69.16) 91.47,69.16 92.33,70.03 92.33,73.74 95.78,77.19 95.78,81.13 91.78,85.13 U57.24
EMMC_D5: length 30.3
  TOP w0.081: 93.17,71.99 93.31,71.99 93.62,72.3 94.2,72.3 U49.B4
  TOP w0.147: 93.17,71.99 89.99,71.99 89.94,71.94 R267.2 v1(89.58,71.45)
  BOTTOM w0.147: v1(89.58,71.45) 89.58,70.97 90.65,69.9 91.36,69.9 91.87,70.41 91.87,74.5 94.59,77.22 94.59,80.25 94.76,80.42 95.15,80.42 95.33,80.59 95.33,80.84 95.15,81.01 94.76,81.01 94.59,81.18 94.59,81.61 93.75,82.44 93.36,82.44 93.19,82.28 92.95,82.28 92.77,82.45 92.77,82.69 92.94,82.86 92.94,83.11 92.77,83.28 92.53,83.28 92.36,83.11 92.11,83.11 91.94,83.28 91.94,83.53 92.11,83.69 92.11,83.94 91.91,84.13 U57.26
EMMC_D6: length 30.4
  TOP w0.081: U49.B5 94.21,72.8 93.42,72.8 93.32,72.69 93.17,72.69
  TOP w0.147: 93.17,72.69 92.61,72.69 91.95,73.36 91.95,74.85 92.68,75.59 92.68,78.06 93.36,78.74 93.36,78.95 93.26,79.05 93.05,79.05 92.25,78.26 92.25,76.34 91.44,75.52 91.44,73.93 91.29,73.79 90.53,73.79 90.09,74.22 R264.2 v1(89.58,73.74)
  BOTTOM w0.147: U57.33 92.06,80.63 92.79,79.91 92.79,77.5 91.77,76.48 90.04,76.48 89.33,75.77 89.33,73.99 v1(89.58,73.74)
EMMC_D7: length 30.1
  TOP w0.081: 93.35,73.3 94.21,73.3 U49.B6
  TOP w0.147: v1(90.37,76.02) 89.92,76.02 R262.2 89.79,76.63 91.36,78.21 91.36,78.64 93.29,80.57 94.82,80.57 95.2,80.19 95.2,79.04 94.13,77.98 93.88,77.98 93.6,77.7 93.6,75.26 92.96,74.63 92.96,73.69 93.35,73.3
  BOTTOM w0.147: v1(90.37,76.02) 90.37,75.67 90.79,75.25 91.35,75.25 93.4,77.29 93.4,80.57 92.68,81.28 90.22,81.28 89.87,81.63 U57.31
EMMC_RSTN: length 34.9
  TOP w0.147: R5822.1 103.11,93.83 103.27,93.99 U26.4 R117.2 105.16,84.99 101.93,81.76 v1(101.93,70.46) ; U49.K5 98.46,72.66 v1(98.5,72.62)
  BOTTOM w0.147: v1(101.93,70.46) 101.5,70.03 98.76,70.03 98.32,70.46 98.32,72.09 98.5,72.27 v1(98.5,72.62)
EN_VSYS_5V0: length 6.1
  TOP w0.147: R3028.1 R5740.2 R3727.2 12.8,14.99 12.26,15.53 U134.7
EPWM0_A: length 127.3
  TOP w0.132: 72.82,74.42 72.62,74.63 71.58,74.63 70.1,76.11 70.1,77.65
  TOP w0.147: 72.82,74.42 72.82,74.42 73.73,73.51 74.83,73.51 v1(75.44,74.12) ; v1(103.25,71.6) 103.25,82.58 106.12,85.45 106.12,107.8 107.6,109.28 107.6,143.06 112.92,148.38 J12.3 ; 70.1,77.65 U136.T2
  L03_SIG1 w0.091: v1(100.97,66.07) 100.97,67.92 103.25,70.21 v1(103.25,71.6)
  BOTTOM w0.147: v1(75.44,74.12) 79.07,74.12 81.48,71.7 81.48,70.71 86.59,65.61 100.51,65.61 v1(100.97,66.07)
EPWM0_B: length 125.4
  TOP w0.147: J12.5 113.03,147.58 107.95,142.49 107.95,109.12 106.48,107.65 106.48,85.19 103.71,82.42 103.71,70.69 102.51,69.49 v1(102.51,68.4) ; U136.R2 v1(69.3,77.65)
  BOTTOM w0.147: v1(102.51,68.4) 102.13,68.4 100.97,67.23 99.69,67.23 99.14,66.67 87.05,66.67 82.65,71.07 82.65,73.66 80.57,75.74 77.22,75.74 76.17,76.78 74.7,76.78 74.4,77.09 73,77.09 72.75,77.34 71.3,77.34 70.99,77.65 v1(69.3,77.65)
EPWM1_A: length 147.1
  TOP w0.147: U136.R1 v1(69.3,76.85) ; J13.3 11.7,118.04 11.4,117.74 11.4,114.63 9.77,113 5.64,113 4.81,112.17 4.81,98.48 8.38,94.91 8.38,81.15 9.14,80.39 9.14,77.92 8.53,77.32 8.53,74.97 10.28,73.23 11.51,73.23 13.77,70.97 20.95,70.97 24.78,74.8 33.56,74.8 35.11,73.24 38.14,73.24 38.71,72.67 41.33,72.67 41.7,73.05 44.58,73.05 48,69.62 48,66.4 48.64,65.75 48.64,62.57 50.16,61.05 50.16,59.46 51.48,58.14 52.41,58.14 52.83,57.72 53.79,57.72 55.2,56.31 61.75,56.31 62.31,56.87 62.71,56.87 63.09,56.49 64.9,56.49 v1(64.95,56.54)
  L03_SIG1 w0.091: v1(69.3,76.85) 69.3,76.13 68.98,75.81 68.98,72.51 68.55,72.09 68.55,68.33 67.92,67.69 67.92,67.08 65.53,64.69 65.53,57.25 64.95,56.67 v1(64.95,56.54)
EXT_CLKOUT0: length 41.4
  TOP w0.147: v1(68.66,50.32) 68.2,50.77 68.2,56.08 67.44,56.84 67.44,57.43 68.38,58.37 68.38,59.97 67.46,60.88 67.46,63.22 68.88,64.64 69.98,64.64 71.6,66.27 71.6,66.85 69.95,68.5 69.95,71.07 70.08,71.2 R170.1
  BOTTOM w0.147: R337.1 55.33,50.72 56.11,49.94 59.71,49.94 60.88,51.1 67.87,51.1 v1(68.66,50.32)
EXT_CLKOUT0_R: length 4.6
  TOP w0.132: 69.98,74.42 68.58,75.82 68.58,76.77 U136.P1
  TOP w0.147: R5788.2 70.08,74.32 69.98,74.42
EXT_VMON2_1: length 3.8
  TOP w0.147: TP95.1 71.89,43.99 73.21,42.67 J18.2
EXT_VMON2_2: length 6.6
  TOP w0.147: TP94.1 102.17,44.91 103.96,44.91 104.5,44.37 104.5,43.92 105.64,42.78 J19.2
FT4232_DO: length 2.5
  TOP w0.147: U61.4 R321.1 R323.2
FT4232_EECLK: length 5.3
  TOP w0.147: U64.62 44.84,29.35 44.55,29.06 43.99,29.06 43.68,28.75 43.68,28.19 43.45,27.96 R328.1 U61.2
FT4232_EECS: length 4.3
  TOP w0.147: U64.63 44.85,28.85 44.65,28.64 R333.1 44.22,28.22 43.83,27.83 U61.1
FT4232_EEDATA: length 6.7
  TOP w0.147: U64.61 44.83,29.85 44.61,29.62 42.84,29.62 42.44,29.22 R323.1 42.44,28.6 42.53,28.51 U61.3
FT4232_REF: length 1.9
  TOP w0.147: U64.6 v1(50.47,27.54)
  BOTTOM w0.147: v1(50.47,27.54) 50.24,27.31 R609.2
FT4232_RESET: length 6.5
  TOP w0.147: U64.14 54.47,25.49 54.81,25.15 55.07,25.15 55.35,24.87 C282.2 55.35,23.83 54.09,22.57 R357.1
FT4232_SOC_UART2_RX_3V3: length 5.3
  TOP w0.147: U64.16 55.47,28.35 55.37,28.45 55.37,29.34 55.78,29.74 v1(55.78,30.33)
  BOTTOM w0.147: U125.13 55.46,30.64 v1(55.78,30.33)
FT4232_SOC_UART2_TX_3V3: length 3.7
  TOP w0.147: U64.17 56.56,28.35 56.24,28.68 v1(56.24,29.03)
  BOTTOM w0.147: U125.15 55.76,29.84 56.24,29.36 v1(56.24,29.03)
FT4232_SOC_UART3_RX_3V3: length 5.3
  TOP w0.147: U64.26 58.5,32.85 v1(59.57,31.78)
  BOTTOM w0.147: v1(59.57,31.78) 59.57,30.84 60.15,30.26 U126.13
FT4232_SOC_UART3_TX_3V3: length 6.7
  TOP w0.147: v1(60.44,32.03) 59.13,33.35 U64.27
  BOTTOM w0.147: U126.15 60.95,30.18 61.19,30.42 61.19,31.29 v1(60.44,32.03)
FT4232_UART2_RXD_1V8: length 17.3
  TOP w0.147: U2351.7 48.44,44.28 v1(48.56,44.4)
  L03_SIG1 w0.091: v1(50.9,32.36) 50.9,39.19 48.56,41.53 v1(48.56,44.4)
  BOTTOM w0.147: U125.8 51.91,30.64 51.69,30.86 51.69,31.49 51.56,31.62 R612.2 51.1,32.16 v1(50.9,32.36)
FT4232_UART2_TXD_1V8: length 20.2
  TOP w0.147: U2351.9 47.44,44.39 v1(47.57,44.53)
  L03_SIG1 w0.091: v1(47.57,44.53) 46.89,43.84 46.89,41.3 49.71,38.48 v1(49.71,31.57)
  BOTTOM w0.147: U125.6 51.23,29.84 51.16,29.91 R611.2 50.09,29.91 49.53,30.47 49.53,31.39 v1(49.71,31.57)
FT4232_UART3_RXD_1V8: length 23
  TOP w0.147: R361.2 59.67,27.72 59.46,27.51 TP97.1 v1(58.78,26.36) 57.95,26.36 55.75,28.56 55.75,29.21 56.26,29.72 56.26,31.47 55.6,32.13 55.6,35.36 56.09,35.84 56.09,39.04 56.31,39.26 U2352.7
  BOTTOM w0.147: v1(58.78,26.36) 59.96,26.36 60.15,26.55 U126.8
FT4232_UART3_TXD_1V8: length 28.7
  TOP w0.147: U2352.9 57.31,38.76 58.88,37.19 60.48,37.19 64.85,32.82 64.85,25.86 v1(62.84,23.85)
  BOTTOM w0.147: v1(62.84,23.85) TP117.1 61.14,23.85 60.6,24.4 R631.2 60.6,25.63 60.95,25.98 U126.6
FT4232_USB_DM: length 23.4
  TOP w0.107: 55.54,8.37 55.71,8.2 55.71,6.77 55.5,6.55 J22.2 ; 55.54,8.37 U67.5 ; 55.54,8.37 55.7,8.53 55.7,16.05 51.11,20.65 51.11,25.28 50.97,25.42 U64.7
FT4232_USB_DP: length 23.4
  TOP w0.107: 56.1,9.37 55.92,9.55 55.92,16.14 51.33,20.74 51.33,25.28 51.47,25.42 U64.8 ; 56.1,9.37 56.1,9.36 55.93,9.19 55.93,6.77 56.15,6.55 J22.3 ; 56.1,9.37 U67.3
FT4232_USB_VBUS: length 8.3
  TOP w0.147: D3.2 53.43,8.2 C291.2
  TOP w0.254: U67.1 C295.1 57.72,7.91 57.57,7.76 v1(57.11,7.76)
  L04_PWR1 w0.254: v1(52.73,7.52) 53.27,8.05 56.82,8.05 v1(57.11,7.76)
FT4232_WKUP_UART0_CTSN_3V3: length 22
  TOP w0.147: U64.40 51.97,38.76 52.39,39.18 52.39,39.96 51.78,40.57 48.95,40.57 47.78,39.4 47.42,39.4 45.29,37.26 41.73,37.26 40.28,35.82 40.28,32.97 v1(40.74,32.51)
  BOTTOM w0.147: v1(40.74,32.51) 40.29,32.51 39.94,32.17 U117.12
FT4232_WKUP_UART0_RTSN_3V3: length 23.5
  TOP w0.147: v1(40.67,31.54) 41.2,32.07 41.2,32.7 40.74,33.16 40.74,35.78 41.87,36.91 45.44,36.91 47.57,39.04 47.93,39.04 49.11,40.22 51.63,40.22 52.04,39.81 52.04,39.35 51.47,38.77 U64.41
  BOTTOM w0.147: v1(40.67,31.54) 39.76,30.63 38.88,30.63 38.45,31.07 U117.14
FT4232_WKUP_UART0_RXD_3V3: length 21.2
  TOP w0.147: U64.38 52.97,36.77 52.77,36.58 47.37,36.58 47.35,36.55 42.01,36.55 41.1,35.64 41.1,33.65 41.55,33.21 41.55,31.77 40.86,31.08 40.01,31.08 v1(39.65,31.45)
  BOTTOM w0.147: v1(39.65,31.45) 39.23,31.02 39.02,31.02 38.85,31.19 U117.13
FT4232_WKUP_UART0_TXD_3V3: length 24.4
  TOP w0.147: U64.39 52.47,38.75 52.74,39.03 52.74,40.1 51.92,40.92 48.8,40.92 47.62,39.75 47.24,39.75 45.74,38.25 43.18,38.25 42.55,37.62 41.59,37.62 39.93,35.96 39.93,34.72 38.05,32.84 v1(38.05,30.75)
  BOTTOM w0.147: v1(38.05,30.75) 38.05,30.75 U117.15
FT_PWREN#: length 1.8
  TOP w0.147: R330.1 44.89,30.23 45,30.35 U64.60
GPIO2_BUF_EN: length 2.7
  TOP w0.147: R278.2 12.48,80.97 R277.1 11.55,80.27 11.95,79.87 U51.5
GPIO_CPSW1_RST: length 92.7
  TOP w0.147: U18.11 56.05,131.92 55.14,131.01 v1(50.93,131.01) ; v1(58.64,52.79) 58.23,52.79 57.74,52.3 R364.1
  L03_SIG1 w0.091: v1(58.64,52.79) 57.99,53.44 57.99,57.91 56.97,58.93 56.97,59.77 54.15,62.59 53.17,62.59 52.04,63.71 52.04,70.41 52.37,70.74 52.37,73.69 49.53,76.53 49.53,81.03 49.83,81.33 49.83,82.83 50.46,83.46 50.46,93.21 51.56,94.31 51.56,96.8 51.13,97.23 51.13,98.4 50.53,99 50.53,126.6 50.93,127 v1(50.93,131.01)
GPIO_CPSW2_RST: length 170.1
  TOP w0.147: U18.10 55.55,132.61 v1(55.14,132.21)
  L03_SIG1 w0.091: v1(105.57,48.94) 116.59,59.95 116.59,62.94 115.45,64.08 115.45,65.99 118.11,68.65 118.11,70.28 124.05,76.23 124.05,135.97 121.57,138.45 111.88,138.45 110.41,136.98 68.71,136.98 64.24,132.51 63.25,132.51 63.25,132.49 v1(63.22,132.49)
  BOTTOM w0.147: R604.1 105.92,48.26 105.92,48.59 v1(105.57,48.94) ; v1(55.14,132.21) 62.94,132.21 v1(63.22,132.49)
GPIO_EMMC_RSTN: length 58.8
  TOP w0.147: R116.1 99.18,95.89 98.78,96.29 98.78,98.76 93.42,104.11 93.42,113.67 98.32,118.57 98.32,121.79 99.39,122.86 100.48,122.86 101.07,123.44 101.07,128.96 97.84,132.18 97.84,140.54 95.61,142.77 93.34,142.77 93.18,142.61 U21.9
GPIO_HYPERRAM_RSTN: length 47.8
  TOP w0.147: U136.C12 v1(58.9,86.45) ; v1(48.51,111.86) 48.37,111.71 R5697.1
  L03_SIG1 w0.091: v1(42.75,91.49) 42.25,91.99 42.25,107.18 42.67,107.6 v1(42.67,112.67)
  BOTTOM w0.132: v1(58.9,86.45) 58.05,86.45
  BOTTOM w0.147: v1(42.75,91.49) 43.26,90.98 45.09,90.98 46.08,89.99 51.69,89.99 54.91,86.77 55.61,86.77 55.93,86.45 58.05,86.45 ; v1(42.67,112.67) 43.81,111.53 48.18,111.53 v1(48.51,111.86)
GPIO_MCU_SOC: length 2.1
  BOTTOM w0.147: R546.1 R547.1 37.35,73.16 37.6,73.42 U98.5
GPIO_MCU_SOC_INTN: length 34.3
  TOP w0.147: U136.C8 v1(58.9,83.26)
  L03_SIG1 w0.091: v1(36.93,76.78) 36.5,77.22 35.23,77.22 34.39,76.37 34.39,73.44 v1(35.79,72.03)
  BOTTOM w0.132: v1(58.9,83.26) 58.45,83.26 58.18,82.98 55.04,82.98
  BOTTOM w0.147: v1(36.93,76.78) 37.48,77.33 40.12,77.33 40.46,76.99 43.79,76.99 46.51,79.71 50.19,79.71 51.94,81.46 53.52,81.46 55.04,82.98 ; R546.2 36.14,72.18 35.99,72.03 v1(35.79,72.03)
GPIO_PCM1_RST: length 31.3
  TOP w0.147: v1(68.48,135.15) 69.27,135.94 R84.1 ; v1(85.39,135.18) 85.39,139.09 87.65,141.35 U21.17
  BOTTOM w0.147: v1(85.39,135.18) 81.87,138.7 74.34,138.7 70.79,135.15 v1(68.48,135.15)
GPIO_PCM2_RST: length 51
  TOP w0.147: v1(67.72,157.12) 67.72,155.6 66.85,154.74 66.85,147.5 68.15,146.2 70.94,146.2 v1(71.78,147.04) ; v1(88.04,140.23) 88.15,140.35 U21.19
  L03_SIG1 w0.091: v1(88.04,140.23) 87.6,139.8 80.91,139.8 v1(75.37,145.34)
  BOTTOM w0.147: v1(71.78,147.04) 72.21,147.47 74.57,147.47 75.37,146.68 v1(75.37,145.34) ; v1(67.72,157.12) 67.72,159.44 65.13,162.02 R414.1
HW/SW_CTRL_SEL: length 3.3
  TOP w0.147: R83.2 78.2,61.9 R85.1 78.21,61.37 78.7,60.88 U15.23
HYPERBUS0_CK: length 12.7
  TOP w0.108: U140.B2 v1(45.16,96.24)
  BOTTOM w0.108: R5754.2 v1(45.16,96.24) 44.94,96.02 44.63,96.02 44.31,95.7 44.31,94.16 46.06,92.42 46.45,92.42 46.86,92.83 47.02,92.83 47.14,92.71 47.14,92.5 46.72,92.08 46.72,91.66 47.02,91.36 47.44,91.36 48.06,91.99 48.24,91.99 48.76,91.47 49.76,91.47 50.08,91.15 R5694.1
HYPERBUS0_CK#: length 12.1
  TOP w0.108: U140.B1 v1(45.16,95.24)
  BOTTOM w0.108: R5695.1 49.72,91.76 48.88,91.76 48.36,92.28 47.94,92.28 47.32,91.65 47.14,91.65 47.01,91.78 47.01,91.96 47.43,92.38 47.43,92.83 47.14,93.12 46.74,93.12 46.33,92.71 46.18,92.71 44.6,94.28 44.6,95.58 44.75,95.73 45.05,95.73 45.16,95.62 v1(45.16,95.24) R5753.1
HYPERBUS0_CS#: length 3.1
  TOP w0.147: v1(43.61,97.74) 43.96,97.74 44.09,97.61 U140.A3
  BOTTOM w0.147: R5693.1 43.33,97.36 43.61,97.08 R5696.1 43.92,97.43 v1(43.61,97.74)
HYPERBUS0_DQ0: length 13.8
  TOP w0.147: v1(47.96,97.61) U140.D3
  BOTTOM w0.147: RA8.1 51.68,92.94 51.57,93.05 51.57,93.17 51.46,93.28 51.31,93.28 51.2,93.17 51.2,93.05 51.09,92.94 50.94,92.94 50.83,93.05 50.83,93.17 50.72,93.28 50.57,93.28 50.46,93.17 50.46,93.05 50.36,92.94 50.2,92.94 50.1,93.05 50.1,93.17 49.99,93.28 49.84,93.28 49.73,93.17 49.73,93.05 49.62,92.94 48.03,92.94 46.46,94.51 46.46,94.97 45.69,95.73 45.69,97.03 46.35,97.69 R5715.1 47.5,97.69 47.58,97.61 v1(47.96,97.61)
HYPERBUS0_DQ1: length 11.7
  TOP w0.147: U140.D2 47.62,96.61 v1(47.94,96.29)
  BOTTOM w0.147: RA8.2 52.86,93.4 52.6,93.65 49.58,93.65 49.38,93.45 48.39,93.45 48.03,93.8 R5716.1 48.03,95.53 46.89,96.67 46.89,96.98 47.04,97.13 47.79,97.13 47.94,96.98 v1(47.94,96.29)
HYPERBUS0_DQ2: length 13.6
  TOP w0.147: v1(47.96,99.14) 48.06,99.03 48.06,98.45 47.73,98.12 47.03,98.12 U140.C4
  BOTTOM w0.147: RA8.4 53.66,93.76 53.01,94.41 49.76,94.41 49.05,95.12 49.05,98.04 v1(47.96,99.14) R5712.1
HYPERBUS0_DQ3: length 14.1
  TOP w0.147: v1(47.04,100) 47.04,99.11 U140.D4
  BOTTOM w0.147: R5710.1 46.79,100.23 47.02,100 v1(47.04,100) 47.04,99.31 48.67,97.69 48.67,94.74 49.38,94.03 52.81,94.03 53.26,93.59 RA8.3
HYPERBUS0_DQ4: length 16.8
  TOP w0.147: U140.D5 47.53,99.97 47.78,100.21 v1(47.78,101.02)
  BOTTOM w0.147: v1(47.78,101.02) R5717.1 48.18,101.47 48.49,101.78 48.95,101.78 49.15,101.57 49.15,101.24 48.56,100.66 48.56,99.14 49.43,98.27 49.43,95.3 49.94,94.79 53.16,94.79 54.59,93.36 RA9.1
HYPERBUS0_DQ5: length 16.6
  TOP w0.147: v1(50.11,98.02) 49.4,98.02 49,97.61 U140.E3
  BOTTOM w0.147: RA9.4 55.79,94.6 55.07,95.33 55.07,95.79 54.28,96.57 52.76,96.57 51.38,97.94 51.38,98.27 52.35,99.24 52.35,100.2 52.04,100.51 50.77,100.51 50.55,100.28 50.55,99.26 50.11,98.83 R5714.1 v1(50.11,98.02)
HYPERBUS0_DQ6: length 16.2
  TOP w0.147: v1(50.01,95.89) 50.47,95.43 50.47,94.97 50.3,94.79 49.4,94.79 49.15,95.05 49.15,95.64 48.53,96.26 U140.E2
  BOTTOM w0.147: RA9.2 54.99,93.55 54.69,93.85 54.69,94.01 54.93,94.25 54.93,94.41 54.83,94.51 54.67,94.51 54.43,94.27 54.27,94.27 54.17,94.37 54.17,94.53 54.41,94.77 54.41,94.93 54.31,95.03 54.15,95.03 53.91,94.79 53.75,94.79 53.37,95.17 53.01,95.17 52.9,95.28 52.9,95.57 52.79,95.68 52.64,95.68 52.53,95.57 52.53,95.28 52.42,95.17 52.27,95.17 52.14,95.31 52.14,96.11 52.03,96.22 51.83,96.22 51.72,96.11 51.72,95.28 51.61,95.17 50.16,95.17 50.01,95.33 v1(50.01,95.89) 50.09,95.81 50.34,95.81 R5713.1
HYPERBUS0_DQ7: length 15.4
  TOP w0.147: v1(49.89,96.82) 50.32,96.82 50.67,96.47 50.67,96.04 51.05,95.66 51.05,94.56 50.83,94.34 48.87,94.34 48.53,94.67 U140.E1
  BOTTOM w0.147: 55.39,92.94 55.39,94.47 54.31,95.55 53.72,95.55 53.09,96.19 52.6,96.19 51.46,97.33 50.59,97.33 50.47,97.22 R5711.1 v1(49.89,96.82)
HYPERBUS0_RST#: length 9.5
  TOP w0.147: U2348.4 R5698.1 R5820.2 45.74,102.07 43.84,100.18 43.84,99.31 U140.A4
HYPERBUS0_RWDS: length 13.9
  TOP w0.147: U136.B15 v1(58.1,88.85)
  BOTTOM w0.132: 56.49,94.44 56.49,94.15 56.31,93.97 56.31,93.62 56.49,93.44 56.49,93.09 56.31,92.92 56.31,92.57 56.49,92.39 56.49,92.18 58.24,90.42 58.24,89.75 58.73,89.26 59.05,89.26 59.29,89.02 59.29,88.69 59.06,88.46 58.73,88.46 58.34,88.85 v1(58.1,88.85)
  BOTTOM w0.147: 56.49,94.44 55.64,95.28 R5709.1 55.64,96.93 55.47,97.1 R5810.1 R5752.1
I2C0_SCL_1V8: length 374.7
  TOP w0.147: U2358.6 41.27,132.34 40.44,133.17 v1(39.57,133.17) ; v1(90.25,149.15) 91.32,150.22 U6.7 ; v1(47.68,145.24) 47.32,145.24 46.76,145.8 46.76,146.28 46.52,146.52 U8.25 ; v1(84.84,58.39) 84.84,57.61 84.4,57.18 83.95,57.18 83.03,56.26 83.03,55.67 82.53,55.17 81.04,55.17 80.7,55.51 U15.12 ; v1(85.34,75.74) 87.66,78.05 88.47,78.05 88.9,78.49 88.9,79.65 89.56,80.31 91.01,80.31 92.63,81.94 92.63,85.06 88.8,88.9 86.28,88.9 83.82,91.36 83.82,93.64 85.82,95.63 85.82,110.48 92.13,116.79 92.13,119.74 91.72,120.14 91.72,121.82 90.78,122.76 90.78,128.63 v1(88.95,130.45) 88.95,130.91 91.68,133.64 U21.29 ; v1(52.78,151.71) 52.78,151.53 53.01,151.3 U7.25 ; v1(101.9,130.84) 101.9,142.6 103.71,144.4 103.71,145 103.6,145.11 U11.5 102.19,145.11 101.63,145.67 101.63,147.58 v1(102.57,148.51) ; v1(23.06,58.6) 23.62,58.04 24.28,58.04 24.86,58.61 R296.1 ; U5.7 73.92,150.27 73.51,149.86 v1(73.51,149.81)
  L03_SIG1 w0.091: v1(85.34,75.74) 86.31,74.78 86.31,70.92 86.92,70.31 86.92,67.87 89.38,65.41 89.38,59.89 88.82,59.34 v1(88.82,57.61) ; v1(23.06,58.6) 21.89,57.43 21.89,56.52 23.95,54.46 25.19,54.46 26.43,53.22 26.43,41.82 28.4,39.85 v1(28.4,38.94) ; v1(52.78,151.71) 52.78,152.07 52.35,152.5 50.98,152.5 49.86,151.38 49.1,151.38 48.18,150.47 47.04,150.47 46.69,150.11 46.69,148.18 47.68,147.19 v1(47.68,145.24) 48.64,144.27 48.64,141.63 40.18,133.17 v1(39.57,133.17) ; v1(73.51,149.81) 73.96,149.81 75.12,148.66 81.19,148.66 81.71,149.17 82.35,149.17 83.53,150.36 v1(85.72,150.36) 87.59,150.36 88.8,149.15 v1(90.25,149.15) 91.56,149.15 92.05,148.66 101.56,148.66 101.7,148.51 v1(102.57,148.51) ; v1(50.22,56.29) 50.22,53.92 51.94,52.2 51.94,50.85 51.74,50.65 51.74,47.65 52.53,46.86 52.53,42.16 51.87,41.5 49.71,41.5 49.1,42.11 49.1,44.6 48.75,44.95 45.94,44.95 44.96,43.97 44.96,35.66 42.88,33.58 41.66,33.58 39.01,36.22 37.97,36.22 36.35,34.59 29.9,34.59 v1(29.03,35.46)
  BOTTOM w0.147: R234.2 76.84,77.75 76.99,77.9 C188.2 R598.2 77.37,76.75 77.54,76.58 81.25,76.58 82.52,75.31 84.91,75.31 v1(85.34,75.74) ; v1(101.9,130.84) 101.37,131.37 92.89,131.37 92.61,131.09 89.59,131.09 v1(88.95,130.45) ; v1(102.57,148.51) 102.57,149.48 101.84,150.21 U76.7 ; v1(28.4,38.94) 28.68,38.66 28.68,35.81 v1(29.03,35.46) ; v1(52.78,151.71) 53.47,152.4 62.99,152.4 65.58,149.81 v1(73.51,149.81) ; v1(50.22,56.29) 51.83,57.9 54.5,57.9 55.07,58.46 55.07,58.76 55.14,58.84 55.14,58.85 55.4,59.11 55.8,59.11 55.93,58.98 56.79,58.98 57.23,59.41 57.23,60.11 57.51,60.4 57.89,60.4 58.27,60.02 59.51,60.02 60.11,60.62 61.2,60.62 61.46,60.36 65.03,60.36 65.92,61.25 72.61,61.25 73.99,59.87 75.67,59.87 76.68,60.88 80.62,60.88 81.18,60.33 82.17,60.33 83.52,58.98 84.33,58.98 84.84,58.47 v1(84.84,58.39) 88.04,58.39 v1(88.82,57.61) ; U77.7 84.44,150.58 84.66,150.36 v1(85.72,150.36)
I2C0_SCL_1V8_RC: length 11
  TOP w0.147: U136.M3 v1(66.9,78.46)
  BOTTOM w0.132: v1(66.9,78.46) 67.29,78.85 67.29,79.41 67.53,79.65 68.68,79.65 68.9,79.44 68.9,79.09 69.14,78.85 72.1,78.85
  BOTTOM w0.147: R234.1 74.8,77.75 74.56,77.99 72.96,77.99 72.1,78.85
I2C0_SDA_1V8: length 352.3
  TOP w0.147: v1(74.1,148.69) 74.1,148.73 74.09,148.74 74.09,149.88 74.42,150.2 U5.8 ; v1(101.24,148.18) 101.24,145.49 100.86,145.11 U11.4 99.31,145.11 99.03,144.83 99.03,144.22 100.84,142.42 v1(100.84,130.71) ; v1(85.34,74.57) 85.34,75.03 87.96,77.65 88.57,77.65 89.33,78.41 89.33,79.45 89.84,79.96 91.21,79.96 92.99,81.74 92.99,85.29 88.87,89.41 88.59,89.41 88.57,89.42 86.26,89.42 84.18,91.5 84.18,93.5 86.17,95.49 86.17,110.32 92.48,116.64 92.48,119.89 92.08,120.29 92.08,121.97 91.69,122.35 91.69,124.74 91.26,125.17 91.26,128.93 v1(89.97,130.23) 89.97,131.17 92.18,133.38 U21.30 ; v1(21.23,57.81) 21.33,57.91 R294.1 ; v1(48.95,145.36) 48.23,145.36 47.9,145.69 47.65,145.69 47.14,146.2 47.14,146.87 47,147.02 U8.26 ; v1(52.68,150.8) 52.81,150.8 52.81,150.8 U7.26 ; U2358.5 v1(40,132.15) ; U6.8 91.82,150.14 91.41,149.73 v1(91.41,148.69) ; U15.19 80.7,60.33 v1(81.78,61.4) ; v1(67.11,64.01) 67.64,64.54 C182.2 67.3,65.01 67.04,64.75 66.85,64.75 66.7,64.9 R210.2
  L03_SIG1 w0.091: v1(74.1,148.69) 74.75,148.03 82.8,148.03 84.51,149.73 v1(85.22,149.73) 86.26,148.69 v1(91.41,148.69) 91.74,148.36 101.07,148.36 v1(101.24,148.18) ; v1(49.45,56.18) 49.45,52.91 50.24,52.12 51.13,52.12 51.56,51.69 51.56,51.08 51.46,50.98 51.46,46.35 51.05,45.95 51.05,42.34 50.81,42.09 49.89,42.09 49.48,42.5 49.48,44.7 48.79,45.39 45.92,45.39 44.6,44.07 44.6,35.71 42.75,33.86 41.84,33.86 38.95,36.75 37.1,36.75 36.61,36.27 28.68,36.27 v1(28.04,36.91) ; v1(40,132.15) 40,132.6 48.95,141.55 v1(48.95,145.36) 48.95,146.33 46.96,148.31 46.96,149.99 47.17,150.19 48.31,150.19 49.23,151.1 49.99,151.1 50.98,152.1 51.99,152.1 52.3,151.79 52.3,151.18 v1(52.68,150.8) ; v1(27.33,39.14) 27.33,40.46 26.11,41.68 26.11,51.31 24.38,53.04 24.38,53.62 21.23,56.77 v1(21.23,57.81) ; v1(85.34,74.57) 86.03,73.89 86.03,70.79 86.61,70.21 86.61,67.77 88.95,65.43 v1(88.95,60.07)
  BOTTOM w0.147: U76.8 101.34,150.12 101.66,149.8 101.66,148.59 v1(101.24,148.18) ; v1(28.04,36.91) 28.04,38.43 v1(27.33,39.14) ; v1(100.84,130.71) 90.45,130.71 v1(89.97,130.23) ; v1(49.45,56.18) 51.44,58.17 51.44,61.48 52.2,62.24 55.74,62.24 57.73,64.23 66.88,64.23 v1(67.11,64.01) R603.2 68.43,63.15 69.27,62.31 80.87,62.31 v1(81.78,61.4) 82.21,61.4 83.92,59.69 88.57,59.69 v1(88.95,60.07) ; v1(85.22,149.73) 84.6,149.73 83.94,150.4 U77.8 ; v1(74.1,148.69) 66.2,148.69 62.94,151.94 53.82,151.94 v1(52.68,150.8)
I2C0_SDA_1V8_RC: length 13.7
  TOP w0.147: U136.N3 v1(67.7,78.45) ; R210.1 v1(66.7,67.46)
  L03_SIG1 w0.091: v1(66.7,67.46) 66.7,68.68 67.69,69.67 67.69,72.09 68.43,72.82 68.43,77.11 68.1,77.44 68.1,78.05 v1(67.7,78.45)
I2C3_SCL_1V8: length 144.3
  TOP w0.147: v1(123.09,67.72) 125.53,70.15 125.53,77.85 124.45,78.93 124.45,140.55 123.57,141.43 R465.2 122.94,142.09 122.25,142.78 J12.18 ; v1(68,76.2) 67.64,76.2 67.3,76.54 U136.N1
  BOTTOM w0.147: v1(68,76.2) 68.53,75.67 69.14,75.67 69.57,76.1 70.23,76.1 71.45,74.88 75.34,74.88 75.74,74.47 79.22,74.47 81.92,71.78 81.92,70.79 86.74,65.96 99.69,65.96 100.25,66.52 101.55,66.52 102.31,67.28 111.99,67.28 114.54,69.84 120.36,69.84 122.48,67.72 v1(123.09,67.72)
I2C3_SDA_1V8: length 151.5
  TOP w0.147: v1(122.89,68.43) 125.11,70.66 125.11,77.2 124.05,78.26 124.05,137.36 121.73,139.68 121.73,141.28 121.88,141.43 R464.2 122.17,141.78 121.98,141.98 J12.20 ; U136.L3 v1(66.1,78.46)
  BOTTOM w0.132: v1(66.1,78.46) 65.7,78.85 65.13,78.85 64.9,78.62 64.9,77.82
  BOTTOM w0.147: 64.9,77.82 65.95,76.77 65.95,74.18 68.53,71.6 72.97,71.6 74.5,70.08 80.59,70.08 86.13,64.54 101.12,64.54 102.59,66.01 104.42,66.01 104.65,66.24 111.81,66.24 114.63,69.06 116.89,69.06 118.95,67.01 123.37,67.01 123.74,67.37 123.74,68.16 123.47,68.43 v1(122.89,68.43)
I2C5_SCL_1V8: length 160.8
  TOP w0.147: v1(2.24,74.04) 2.24,77.6 1.15,78.68 1.15,82.96 2.39,84.2 2.39,85.42 2.02,85.79 2.02,111.33 6.94,116.26 8.26,116.26 9.12,117.12 9.12,123.13 8.61,123.64 J13.18 R685.2 ; v1(10.36,73.79) 11.73,73.79 14.17,71.35 20.83,71.35 24.63,75.15 35.32,75.15 36.68,73.79 38.25,73.79 39.01,73.03 40.79,73.03 41.86,74.09 42.55,74.09 43.24,73.4 44.72,73.4 48.35,69.77 48.35,66.54 48.99,65.9 48.99,64.88 49.82,64.04 49.82,61.88 50.51,61.19 50.51,59.61 51.59,58.53 52.52,58.53 52.55,58.49 52.56,58.49 52.97,58.07 53.94,58.07 54.14,57.87 55.34,56.67 61.59,56.67 62.15,57.23 62.87,57.23 63.17,56.92 64.59,56.92 v1(64.92,57.25) ; U136.L4 v1(66.1,79.26)
  L03_SIG1 w0.091: v1(64.92,57.25) 65.25,57.58 65.25,64.8 66.24,65.79 66.24,68.86 66.52,69.14 66.52,72.54 65.72,73.34 65.72,78.88 v1(66.1,79.26)
  BOTTOM w0.147: v1(10.36,73.79) 2.49,73.79 v1(2.24,74.04)
I2C5_SDA_1V8: length 136.2
  TOP w0.147: U136.M4 v1(66.9,79.26) ; v1(2.82,75.06) 2.82,77.62 1.5,78.94 1.5,82.81 2.74,84.04 2.74,85.68 2.37,86.05 2.37,111.19 7.05,115.87 8.37,115.87 9.47,116.98 9.47,123.7 8.73,124.44 J13.20 R684.2 ; v1(35.64,75.67) 35.28,75.67 35.18,75.56 24.51,75.56 20.68,71.73 14.48,71.73 11.96,74.24 v1(11.13,74.24)
  BOTTOM w0.132: 63.88,79.65 63.53,79.65 63.3,79.43 63.3,77.75 ; 63.88,79.65 66.5,79.65
  BOTTOM w0.147: 63.88,79.65 63.88,79.65 ; v1(35.64,75.67) 36.21,76.24 39.18,76.24 39.52,75.9 44.48,75.9 45.19,75.19 45.19,72.49 45.57,72.11 48.45,72.11 49.65,70.9 51.69,70.9 53.36,72.58 61.02,72.58 62.31,73.86 62.31,74.83 63.14,75.67 63.14,77.6 63.3,77.75 ; v1(2.82,75.06) 3.63,74.24 v1(11.13,74.24) ; 66.5,79.65 v1(66.9,79.26)
I2C_ADDR0_A0: length 11.2
  TOP w0.147: J18.47 82.41,37.55 82.58,37.39 v1(82.58,36.93)
  BOTTOM w0.147: v1(82.58,36.93) 83.02,36.49 86.58,36.49 87.86,35.21 R642.2 R641.1
I2C_ADDR0_A2: length 7.8
  TOP w0.147: v1(77.95,35.66) 77.95,36.12 80.41,38.58 J18.37
  BOTTOM w0.147: R638.1 R639.2 77.13,35.37 77.42,35.66 v1(77.95,35.66)
I2C_ADDR1_A0: length 3.5
  TOP w0.147: v1(114.92,38.43) 114.84,38.52 J19.47
  BOTTOM w0.147: R628.2 R630.1 115.05,37.76 114.92,37.89 v1(114.92,38.43)
I2C_ADDR1_A2: length 6.6
  TOP w0.147: v1(111.93,37.14) 112.84,38.05 J19.37
  BOTTOM w0.147: v1(111.93,37.14) 111.93,36.58 111.18,35.82 R629.1 R626.2
INA_ALERT: length 188.3
  TOP w0.147: R305.2 20.05,57.02 v1(20.08,57) ; TP46.1 33.39,68.74 33.35,68.71 v1(32.97,68.71)
  L03_SIG1 w0.091: v1(49.3,60.58) 49.3,62.56 47.14,64.72 46.08,64.72 45,63.64 v1(45,62) 45,61.87 44.42,61.29 44.42,48.77 42.97,47.32 v1(38.48,47.32) 38.48,46.74 38.73,46.48 38.73,42.34 37.77,41.38 37.77,38.23 36.73,37.19 32.87,37.19 32,38.05 27.2,38.05 24.31,40.94 22.4,40.94 20.08,43.27 v1(20.08,57) 20.08,58.63 22.38,60.93 22.38,69.62 23.42,70.66 23.42,79.25 25.96,81.79 25.96,83.24 25.45,83.74 25.45,85.67 25.15,85.98 25.15,88.93 25.48,89.26 25.48,90.85 24.74,91.59 21.74,91.59 21.03,90.88 20.69,90.88 20.35,91.23 20.35,93.54 22.02,95.22 22.02,97.54 v1(25.84,101.36) ; v1(32.97,68.71) 31.61,70.07 31.61,74.64 32.86,75.89 32.86,88.03 33.15,88.32 33.15,93.59 32.84,93.9 32.84,97.31 31.22,98.94 31.22,101.3 v1(31.95,102.03)
  BOTTOM w0.147: R5782.2 33.61,68.84 33.48,68.71 v1(32.97,68.71) ; v1(25.84,101.36) 31.28,101.36 v1(31.95,102.03) ; R608.2 41.64,38.52 41.76,38.4 41.76,38 41.4,37.64 40.87,37.64 39.65,38.86 39.65,42.16 39.48,42.33 39.48,46.22 39.28,46.42 R597.1 R596.2 38.64,47.48 v1(38.48,47.32) ; v1(20.08,57) R586.2 ; v1(45,62) R505.2 ; v1(49.3,60.58) 49.22,60.66 R5778.2
IO_EXP0_INTN: length 3.2
  TOP w0.147: U21.32 93.18,136.53 93.8,135.92 R5761.2 R108.2
IO_EXP1_INTN: length 1.8
  TOP w0.147: R98.1 54.89,138.1 55.05,137.94 U18.22
IO_EXP_ADDR: length 1.4
  BOTTOM w0.147: R456.1 78.71,126.69 79.06,126.34 U82.26
IO_EXP_TEST_LED: length 4.7
  TOP w0.147: R441.1 59.22,134.48 57.11,132.37 56.79,132.37 56.55,132.6 U18.12
IO_MCAN0_EN: length 76.2
  TOP w0.147: U21.10 v1(92.68,143.15) ; R5639.2 v1(29.88,163.91)
  L03_SIG1 w0.091: v1(92.68,143.15) 92.68,143.48 89.93,146.23 v1(81.51,146.23)
  BOTTOM w0.147: v1(29.88,163.91) 34.06,163.91 35.61,162.36 35.61,157.61 37.21,156.01 60.93,156.01 65.07,151.87 73.99,151.87 79.63,146.23 v1(81.51,146.23)
IO_MCAN0_STB#: length 75.4
  TOP w0.147: v1(91.97,143.31) 91.68,143.02 U21.12 ; v1(28.03,149.73) R5692.1 R102.2
  L03_SIG1 w0.091: v1(91.97,143.31) 89.51,145.77 79.02,145.77 78.46,146.33 v1(77.85,146.33)
  BOTTOM w0.147: v1(28.03,149.73) 28.42,149.34 45.73,149.34 47.55,151.15 51.67,151.15 52.55,150.27 53.77,150.27 54.01,150.51 63.87,150.51 66.17,148.21 75.97,148.21 v1(77.85,146.33)
IORET_WAKE: length 57.1
  TOP w0.147: U3070.4 56.98,122.69 57.23,122.45 v1(57.23,122.02) ; U136.D7 v1(59.7,82.46)
  L03_SIG1 w0.091: v1(52.88,81) 52.17,81.71 52.17,82.75 51.34,83.59 51.34,92.46 52.4,93.52 52.4,97.49 52.65,97.74 52.65,99.77 51.6,100.82 51.6,121.02 v1(52.22,121.64)
  BOTTOM w0.132: 55.75,82.7 58.57,82.7 58.72,82.85 59.06,82.85 59.46,82.46 v1(59.7,82.46)
  BOTTOM w0.147: 55.75,82.7 55.27,82.7 53.57,81 v1(52.88,81) ; v1(52.22,121.64) 52.6,122.02 v1(57.23,122.02)
JTAG_CTI_RTCK: length 4.5
  TOP w0.147: J14.9 31.99,112.93 32.16,113.11 33.6,113.11 v1(33.91,113.41)
  BOTTOM w0.147: R476.1 33.66,113.64 33.88,113.41 v1(33.91,113.41)
JTAG_CTI_TCK: length 10.9
  TOP w0.147: v1(29.95,113.41) 30.3,113.41 30.72,112.99 J14.11
  BOTTOM w0.147: v1(29.95,113.41) 30.52,113.98 U87.1 31.86,113.71 32.61,112.95 34.26,112.95 34.53,112.69 R487.1 34.97,112.31 35.18,112.53 R485.1 U88.1
JTAG_DIR: length 3.1
  BOTTOM w0.147: U110.5 25.79,85.13 R569.2 25.17,84.4 25.4,84.17 U110.4
JTAG_EMU0: length 21.6
  TOP w0.147: J14.13 29.45,109.41 29.23,109.19 26.53,109.19 23.51,106.17 21.36,106.17 21.11,105.92 17.17,105.92 16.33,105.08 16.33,103.33 16.63,103.03 17.63,103.03 17.87,103.27 R211.2 18.07,103.48 18.35,103.21 U39.7
JTAG_EMU1: length 18.5
  TOP w0.147: U39.6 18.59,103.56 18.25,103.89 18.25,104.15 18.16,104.24 R212.2 17.87,105.17 18.26,105.56 21.26,105.56 21.48,105.79 24.16,105.79 24.79,105.16 24.79,103.84 25.3,103.33 28.96,103.33 29.45,103.82 J14.14
JTAG_EMU_RSTN: length 84.3
  TOP w0.147: v1(27.51,113.72) 28.15,113.72 R482.2 J14.15
  L03_SIG1 w0.091: v1(12.93,62.99) 12.93,63.98 12.07,64.84 12.07,69.07 12.38,69.38 12.38,74.26 11.56,75.08 11.56,77.14 11.98,77.56 11.98,78.55 11.67,78.86 11.67,83.73 12.32,84.38 12.32,90.83 10.92,92.23 10.92,100.25 6.53,104.65 6.53,109.14 12.37,114.99 v1(12.37,115.85)
  BOTTOM w0.147: v1(12.37,115.85) 19.99,115.85 22.37,113.47 27.26,113.47 v1(27.51,113.72) ; v1(12.93,62.99) 13.56,62.36 15.01,62.36 15.32,62.66 15.32,64.7 14.85,65.17 U86.6
JTAG_TCK: length 51.8
  L03_SIG1 w0.091: v1(27.13,81.46) 27.13,82.8 28.85,84.53 28.85,86.56 27.86,87.55 27.86,93.47 25.73,95.61 24.79,95.61 24.43,95.96 24.43,97.28 27.05,99.9 27.05,106.73 28.68,108.36 28.68,109.42 28.04,110.06 v1(28.04,115.01)
  BOTTOM w0.147: v1(28.04,115.01) 30.84,115.01 31.67,115.84 33.43,115.84 33.83,115.44 36.12,115.44 37.99,113.57 R483.1 ; U110.14 26.58,81.85 26.73,81.71 26.88,81.71 v1(27.13,81.46)
JTAG_TDI: length 38.7
  TOP w0.147: v1(29.13,108.71) 29.49,108.71 29.69,108.51 32.08,108.51 32.38,108.81 34.11,108.81 34.24,108.69 34.7,108.69 34.95,108.94 35.46,108.94 35.8,109.28 J14.3
  L03_SIG1 w0.091: v1(29.13,108.71) 29.13,107.75 27.33,105.94 27.33,99.57 26.04,98.27 26.04,95.94 28.15,93.82 28.15,87.68 29.13,86.69 29.13,83.99 v1(28.12,82.97)
  BOTTOM w0.147: v1(28.12,82.97) U110.12
JTAG_TDIS: length 2.7
  TOP w0.147: v1(35.98,107.96) 35.8,107.77 J14.4
  BOTTOM w0.147: v1(35.98,107.96) 36.07,108.04 R490.2
JTAG_TDO: length 4.7
  TOP w0.147: J14.7 33.26,109.28 v1(33.25,109.27)
  BOTTOM w0.147: v1(33.25,109.27) 33.66,109.27 34.5,108.43 U90.7
JTAG_TMS: length 42.7
  TOP w0.147: J14.1 37.07,109.39 38.13,108.33 38.13,104.11 36.93,102.92 35.31,102.92 34.85,103.38 30.35,103.38 v1(29.97,103.76)
  L03_SIG1 w0.091: v1(27.56,82.21) 27.98,82.21 29.41,83.64 29.41,86.82 28.57,87.66 28.57,93.9 27.03,95.45 27.03,96.93 26.44,97.51 26.44,97.84 27.84,99.24 27.84,101.63 v1(29.97,103.76)
  BOTTOM w0.147: U110.13 26.98,82.14 27.13,81.99 27.34,81.99 v1(27.56,82.21)
JTAG_TRST#: length 45.9
  TOP w0.147: v1(27.64,108.15) 32.28,108.15 32.59,108.46 33.96,108.46 34.09,108.33 34.85,108.33 35.1,108.58 36.66,108.58 v1(37.26,107.99) 37.07,107.8 J14.2
  L03_SIG1 w0.091: v1(26.44,81.2) 26.67,81.43 26.67,82.75 28.57,84.66 28.57,86.44 27.58,87.43 27.58,93.34 25.65,95.28 24.59,95.28 24.05,95.81 24.05,98.35 26.77,101.07 26.77,107.29 v1(27.64,108.15)
  BOTTOM w0.147: R489.2 v1(37.26,107.99) ; v1(26.44,81.2) 26.19,81.46 U110.15
LDO_1V8: length 1.7
  TOP w0.147: v1(29.84,24.61) 29.87,24.59 29.88,24.59 30.02,24.44 C303.1
  BOTTOM w0.147: v1(29.84,24.61) 29.84,24.56 29.85,24.55 U129.35
LDO_3V3: length 71.4
  TOP w0.254: 29.51,25.32 34.18,25.32 34.7,25.83 34.7,28.54 34.44,28.79 R374.1 v1(33.91,29.35) C292.1 U69.8 ; 29.51,25.32 29.06,24.87 26.21,24.87 25.66,25.42 v1(25.66,26.12) 25.34,26.44 R378.1 ; 29.51,25.32 29.51,27.64 v1(29.36,27.79) ; v1(29.55,16.18) 29.55,15.46 C319.2 ; R195.1 24.22,36.84 v1(24.21,36.83) 23.58,36.21 C300.2 U71.5
  L03_SIG1 w0.305: v1(29.55,16.18) 29.55,16.88 29.11,17.32 25.98,17.32 25.38,16.72 23.67,16.72 22.81,17.59 22.81,21.08 24.49,22.76 25.7,22.76 25.86,22.91 26.77,22.91 29.36,25.5 v1(29.36,27.79) 29.36,28.74 26.31,31.79 26.31,36.42 25.64,37.1 24.48,37.1 v1(24.21,36.83)
  BOTTOM w0.229: U129.9 29.45,16.28 v1(29.55,16.18) 29.77,15.97 R678.1 29.77,15.24 30.05,14.96 R679.1
  BOTTOM w0.254: R646.1 32.89,28.33 v1(33.91,29.35) ; R660.1 26.31,25.1 26.06,25.36 ; v1(29.36,27.79) 29.59,27.79 29.92,27.46 R644.1 ; 26.06,25.36 R658.1 ; 26.06,25.36 26.06,25.72 v1(25.66,26.12) 25.04,26.12 24.49,25.57 24.49,24.37 24.91,23.95 R664.1
LM61460_BOOT: length 1.9
  TOP w0.254: U134.14 6.67,15.03 6.1,14.45 R5805.2
LM61460_FB: length 3.9
  TOP w0.147: U134.4 9.35,13.49 9.78,13.06 9.78,11.61 9.47,11.3 R3720.2
LM61460_RT: length 4.5
  TOP w0.147: U134.6 11.11,15.03 11.38,14.76 11.38,13.13 11.68,12.83 12.22,12.83 12.37,12.68 R3652.1
LM61460_SW: length 5.7
  TOP w0.203: U134.10 8.82,16.16 8.66,16 6.2,16 5.95,15.76 5.3,15.76 4.91,15.37 C3494.2
LM61460_VCC: length 2
  TOP w0.147: U134.2 8.3,13.27 8.05,13.03 C3627.2
MCAN0_CAN_H: length 7
  TOP w0.127: J9.3 22.53,156.71 22.53,157.18 23.47,158.12 23.83,158.12 R88.2 24.46,158.09 26.17,158.09 26.25,158 U3068.13
MCAN0_CAN_L: length 7.2
  TOP w0.127: U3068.12 26.25,158.5 26.17,158.42 24.56,158.42 R93.1 23.77,158.45 23.42,158.45 22.66,159.21 22.66,159.82 J9.1
MCAN0_EN: length 6.2
  TOP w0.147: R5638.1 31.99,161.23 30.77,160 U3068.6 29.39,160 29.15,160.24 29.15,160.85 29.88,161.58 R5639.1
MCAN0_FAULT#: length 2.6
  TOP w0.147: R5637.1 27.39,161.5 27.94,160.96 27.94,160.66 27.79,160.5 U3068.8
MCAN0_RX: length 119.5
  TOP w0.132: 54.89,79.43 55.51,80.05 58.1,80.05 U136.B4
  TOP w0.147: v1(28.15,163.91) 28.47,163.58 R81.1 ; v1(54.53,79.07) 54.89,79.43
  L03_SIG1 w0.091: v1(39.57,76.5) 39.57,77.47 36.56,80.49 36.56,86.47 38.56,88.47 38.56,88.49 38.61,88.54 38.61,91.29 36.93,92.96 36.93,96.7 36.37,97.26 36.37,102.88 37.03,103.54 37.03,107.54 36.12,108.46 36.12,113.54 37.31,114.73 37.31,139.27 36.27,140.31 36.27,155.85 34.85,157.28 34.85,160.76 31.28,164.33 28.57,164.33 v1(28.15,163.91)
  BOTTOM w0.147: v1(54.53,79.07) 54.13,78.66 51.56,78.66 51.41,78.51 46.66,78.51 44.4,76.25 39.83,76.25 v1(39.57,76.5)
MCAN0_RX_R: length 4.2
  TOP w0.147: U3068.4 29.35,159 28.8,159.55 28.8,161.21 28.47,161.54 R81.2
MCAN0_STB#: length 3.6
  TOP w0.147: R102.1 26.48,155.46 26.06,155.88 26.06,157.28 26.29,157.5 U3068.14
MCAN0_T: length 9.2
  TOP w0.147: v1(23.85,161.85) C107.1 24.56,161.24 24.16,160.83 R93.2 ; R88.1 v1(24.16,156.24)
  BOTTOM w0.147: v1(24.16,156.24) 23.85,156.54 v1(23.85,161.85)
MCAN0_TX: length 13.8
  TOP w0.132: 55.57,78.18 55.73,78.33 56.29,78.33 57.21,79.26 58.9,79.26 U136.C4
  TOP w0.147: 55.57,78.18 55.24,77.85 53.98,77.85 52.73,79.1 52.07,79.1 51.21,79.96 50.27,79.96 50.1,80.13 R82.2
MCAN0_TX_R: length 94.1
  TOP w0.147: v1(47.4,82.42) 47.4,82.07 47.2,81.87 R82.1 ; v1(33.73,150.6) 33.73,152.22 28.96,157 28.96,157.33 29.13,157.5 U3068.1
  L03_SIG1 w0.091: v1(36.8,88.34) 37.72,89.26 37.72,90.96 34.72,93.95 34.72,97.59 33.88,98.42 33.88,104.55 32.33,106.1 32.33,108.33 31.55,109.12 31.55,114.96 34.49,117.91 34.49,119.18 35.53,120.22 35.53,148.79 v1(33.73,150.6)
  BOTTOM w0.147: v1(47.4,82.42) 47.93,82.95 47.93,84.81 46.53,86.21 40.49,86.21 39.65,87.05 38.25,87.05 37.21,88.09 37.05,88.09 v1(36.8,88.34)
MCAN0_WAKE_R: length 2.8
  TOP w0.147: U3068.9 26.25,160 25.87,160.39 R5635.1
MCAN1_RX: length 4.3
  TOP w0.147: U136.D5 v1(59.7,80.06)
  BOTTOM w0.132: R5670.1 56.74,80.18 57.02,80.45 59.3,80.45 v1(59.7,80.06)
MCAN1_RX_R: length 136
  TOP w0.132: v1(56.13,78.82) 55.58,78.82 54.99,78.23 54.1,78.23 53.45,78.88
  TOP w0.147: v1(38.96,85.83) 38.96,85.37 39.85,84.48 40.49,84.48 41.63,83.34 41.63,82.75 42.39,81.99 42.88,81.99 43.13,81.74 43.13,81.25 43.38,81 45.31,81 47.19,82.88 47.6,82.88 47.96,82.52 47.96,81.84 47.8,81.69 47.8,80.75 48.06,80.49 50.24,80.49 50.42,80.31 51.36,80.31 52.22,79.45 52.88,79.45 53.45,78.88 ; v1(16.51,78.49) 16.51,79.86 13.28,83.08 12.22,83.08 10.11,85.19 10.11,94.34 15.11,99.34 15.11,108.43 17.64,110.96 17.64,117.36 17.17,117.83 17.17,119.37 18.55,120.75 20.96,120.75 24.54,124.33 24.54,135.36 17.85,142.04 J13.53
  BOTTOM w0.132: v1(56.13,78.82) 56.25,78.7 R5670.2
  BOTTOM w0.147: v1(38.96,85.83) 38.96,86.18 38.45,86.69 38.1,86.69 37.44,87.35 34.44,87.35 31.95,84.86 31.95,81.71 28.98,78.74 23.37,78.74 23.09,78.46 16.54,78.46 v1(16.51,78.49)
MCAN1_TX: length 124.9
  TOP w0.147: v1(13.55,81.95) 13.18,82.32 12.19,82.32 9.58,84.94 9.58,94.36 14.61,99.39 14.61,108.43 17.27,111.1 17.27,117.22 16.71,117.78 16.71,119.41 18.41,121.11 20.82,121.11 24.03,124.32 24.03,134.8 19.1,139.73 18.24,139.73 16.72,141.24 J13.51 ; R5671.1 v1(48.41,81.84)
  BOTTOM w0.147: v1(13.55,81.95) 14.03,81.95 17.17,78.82 22.89,78.82 23.19,79.12 28.87,79.12 31.6,81.85 31.6,85.19 34.59,88.19 35.94,88.19 36.55,88.8 37.01,88.8 38.4,87.4 39.93,87.4 40.77,86.56 47.1,86.56 49.1,84.57 49.1,82.52 v1(48.41,81.84)
MCAN1_TX_R: length 9.8
  TOP w0.147: U136.A4 55.78,79.66 54.74,78.61 54.23,78.61 53.04,79.81 52.37,79.81 51.49,80.7 50.55,80.7 49.95,81.29 R5671.2
MCAN4_RX: length 6.7
  TOP w0.132: U136.B6 58.1,81.65 54.89,81.65
  TOP w0.147: R5650.1 52.39,82.02 52.81,81.59 53.05,81.59 53.24,81.41 53.7,81.41 53.94,81.65 54.89,81.65
MCAN4_RX_R: length 114.7
  TOP w0.147: v1(111.76,124.1) 112.03,124.38 J12.53 ; v1(50.41,82.59) 50.94,82.06 R5650.2
  L03_SIG1 w0.091: v1(50.95,125.48) 50.95,100.1 51.69,99.36 51.69,98.91 51.51,98.73 51.51,97.26 51.84,96.93 51.84,94.18 50.77,93.12 50.77,83.34 50.41,82.97 v1(50.41,82.59)
  BOTTOM w0.147: v1(50.95,125.48) 51.05,125.37 59.59,125.37 65.3,131.09 77.98,131.09 78.44,131.55 81.66,131.55 81.94,131.27 85.88,131.27 87.72,129.42 90.56,129.42 90.98,129.84 106.03,129.84 v1(111.76,124.1)
MCAN4_TX: length 106.2
  TOP w0.147: v1(106.52,70.21) 106.52,81.53 109.02,84.02 109.02,106.63 110.46,108.08 110.46,123.98 111.67,125.18 J12.51
  BOTTOM w0.147: R5649.1 72.69,78.72 73.05,78.36 79.22,78.36 79.55,78.03 81.94,78.03 82.35,77.62 82.35,76.86 82.96,76.25 85.57,76.25 85.85,75.97 85.85,75.36 85.52,75.03 85.14,75.03 84.3,74.19 84.3,70.43 87.35,67.39 98.73,67.39 99.29,67.94 100.56,67.94 102.31,69.7 102.97,69.7 103.48,70.21 v1(106.52,70.21)
MCAN4_TX_R: length 3.2
  TOP w0.147: U136.R4 v1(69.3,79.26)
  BOTTOM w0.132: v1(69.3,79.26) 69.69,79.65 71.12,79.65 71.39,79.39
  BOTTOM w0.147: R5649.2 71.39,79.39
MCASP0_ACLKR: length 86.4
  TOP w0.147: v1(111.3,128.38) J12.43
  L03_SIG1 w0.091: v1(111.3,128.38) 110.65,128.38 108.36,126.09 107.36,126.09 107.26,126.19 107.26,126.74 107.15,126.85 107,126.85 106.89,126.74 106.89,126.19 106.78,126.09 106.63,126.09 106.52,126.19 106.52,126.74 106.42,126.85 106.27,126.85 106.16,126.74 106.16,126.19 106.05,126.09 105.9,126.09 105.79,126.19 105.79,126.74 105.69,126.85 105.53,126.85 105.43,126.74 105.43,126.19 105.32,126.09 105.17,126.09 105.06,126.19 105.06,126.74 104.95,126.85 104.8,126.85 104.7,126.74 104.7,126.19 104.59,126.09 104.44,126.09 104.33,126.19 104.33,126.74 104.22,126.85 104.07,126.85 103.96,126.74 103.96,126.19 103.86,126.09 101.9,126.09 101.24,125.43 101.24,122.71 91.97,113.44 91.97,112.95 91.39,112.37 91.24,112.37 90.68,112.93 90.53,112.93 90.42,112.82 90.42,112.67 90.98,112.11 90.98,111.96 90.87,111.85 90.72,111.85 90.16,112.41 90.01,112.41 89.9,112.3 89.9,112.15 90.46,111.59 90.46,111.44 90.35,111.33 90.2,111.33 89.64,111.89 89.49,111.89 89.38,111.79 89.38,111.63 89.94,111.08 89.94,110.92 89.84,110.82 89.68,110.82 89.12,111.38 88.97,111.38 88.87,111.27 88.87,111.12 89.43,110.56 89.43,110.41 89.32,110.3 89.17,110.3 88.61,110.86 88.46,110.86 88.35,110.75 88.35,110.6 88.91,110.04 88.91,109.89 88.8,109.78 88.65,109.78 88.09,110.34 87.94,110.34 87.83,110.23 87.83,110.08 88.39,109.52 88.39,109.37 88.28,109.26 88.13,109.26 87.57,109.82 87.42,109.82 87.31,109.72 87.31,109.57 87.87,109.01 87.87,108.85 87.77,108.75 87.62,108.75 87.06,109.31 86.9,109.31 86.8,109.2 86.8,109.05 87.36,108.49 87.36,108.34 87.25,108.23 87.1,108.23 86.54,108.79 86.39,108.79 86.28,108.68 86.28,108.53 86.84,107.97 86.84,107.82 86.73,107.71 86.58,107.71 86.02,108.27 85.87,108.27 85.76,108.17 85.76,108.01 86.32,107.45 86.32,107.3 86.22,107.2 86.06,107.2 85.5,107.76 85.35,107.76 85.25,107.65 85.25,107.5 85.81,106.94 85.81,106.79 85.7,106.68 85.55,106.68 84.99,107.24 84.84,107.24 84.73,107.13 84.73,106.98 85.29,106.42 85.29,106.27 85.18,106.16 85.03,106.16 84.47,106.72 84.32,106.72 84.21,106.61 84.21,106.46 84.77,105.9 84.77,105.75 84.36,105.34 77.59,105.34 v1(77.11,105.82)
  BOTTOM w0.147: R5648.1 75.56,102.69 77.11,104.24 v1(77.11,105.82) 77.16,105.87 RA7.7
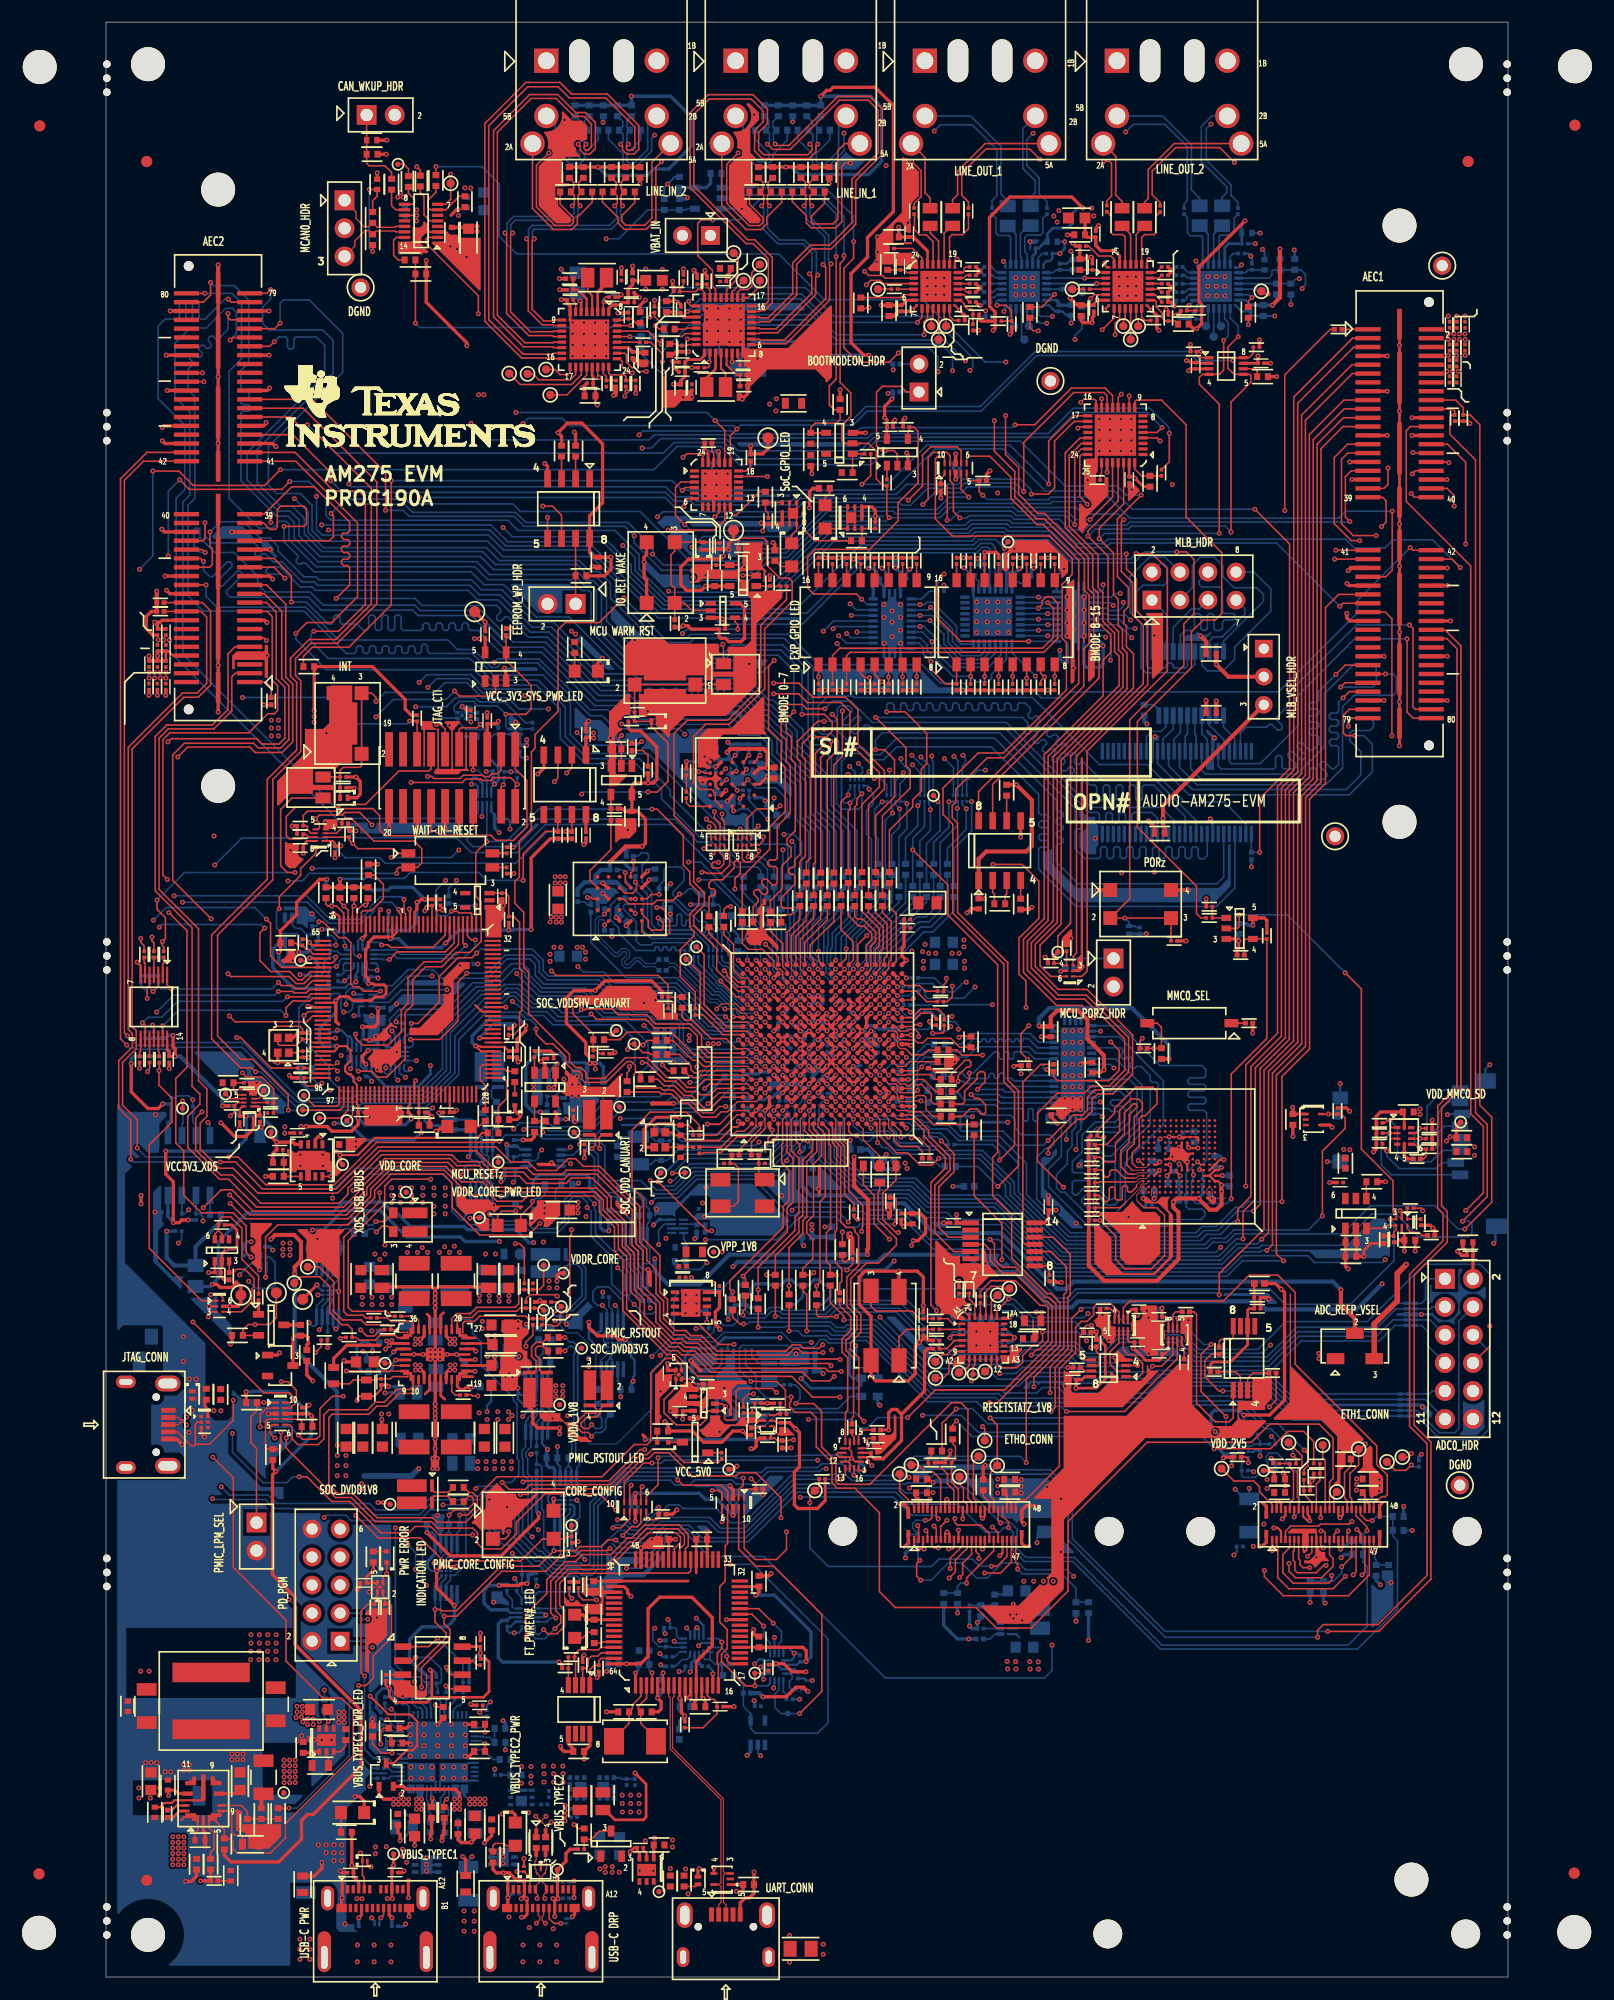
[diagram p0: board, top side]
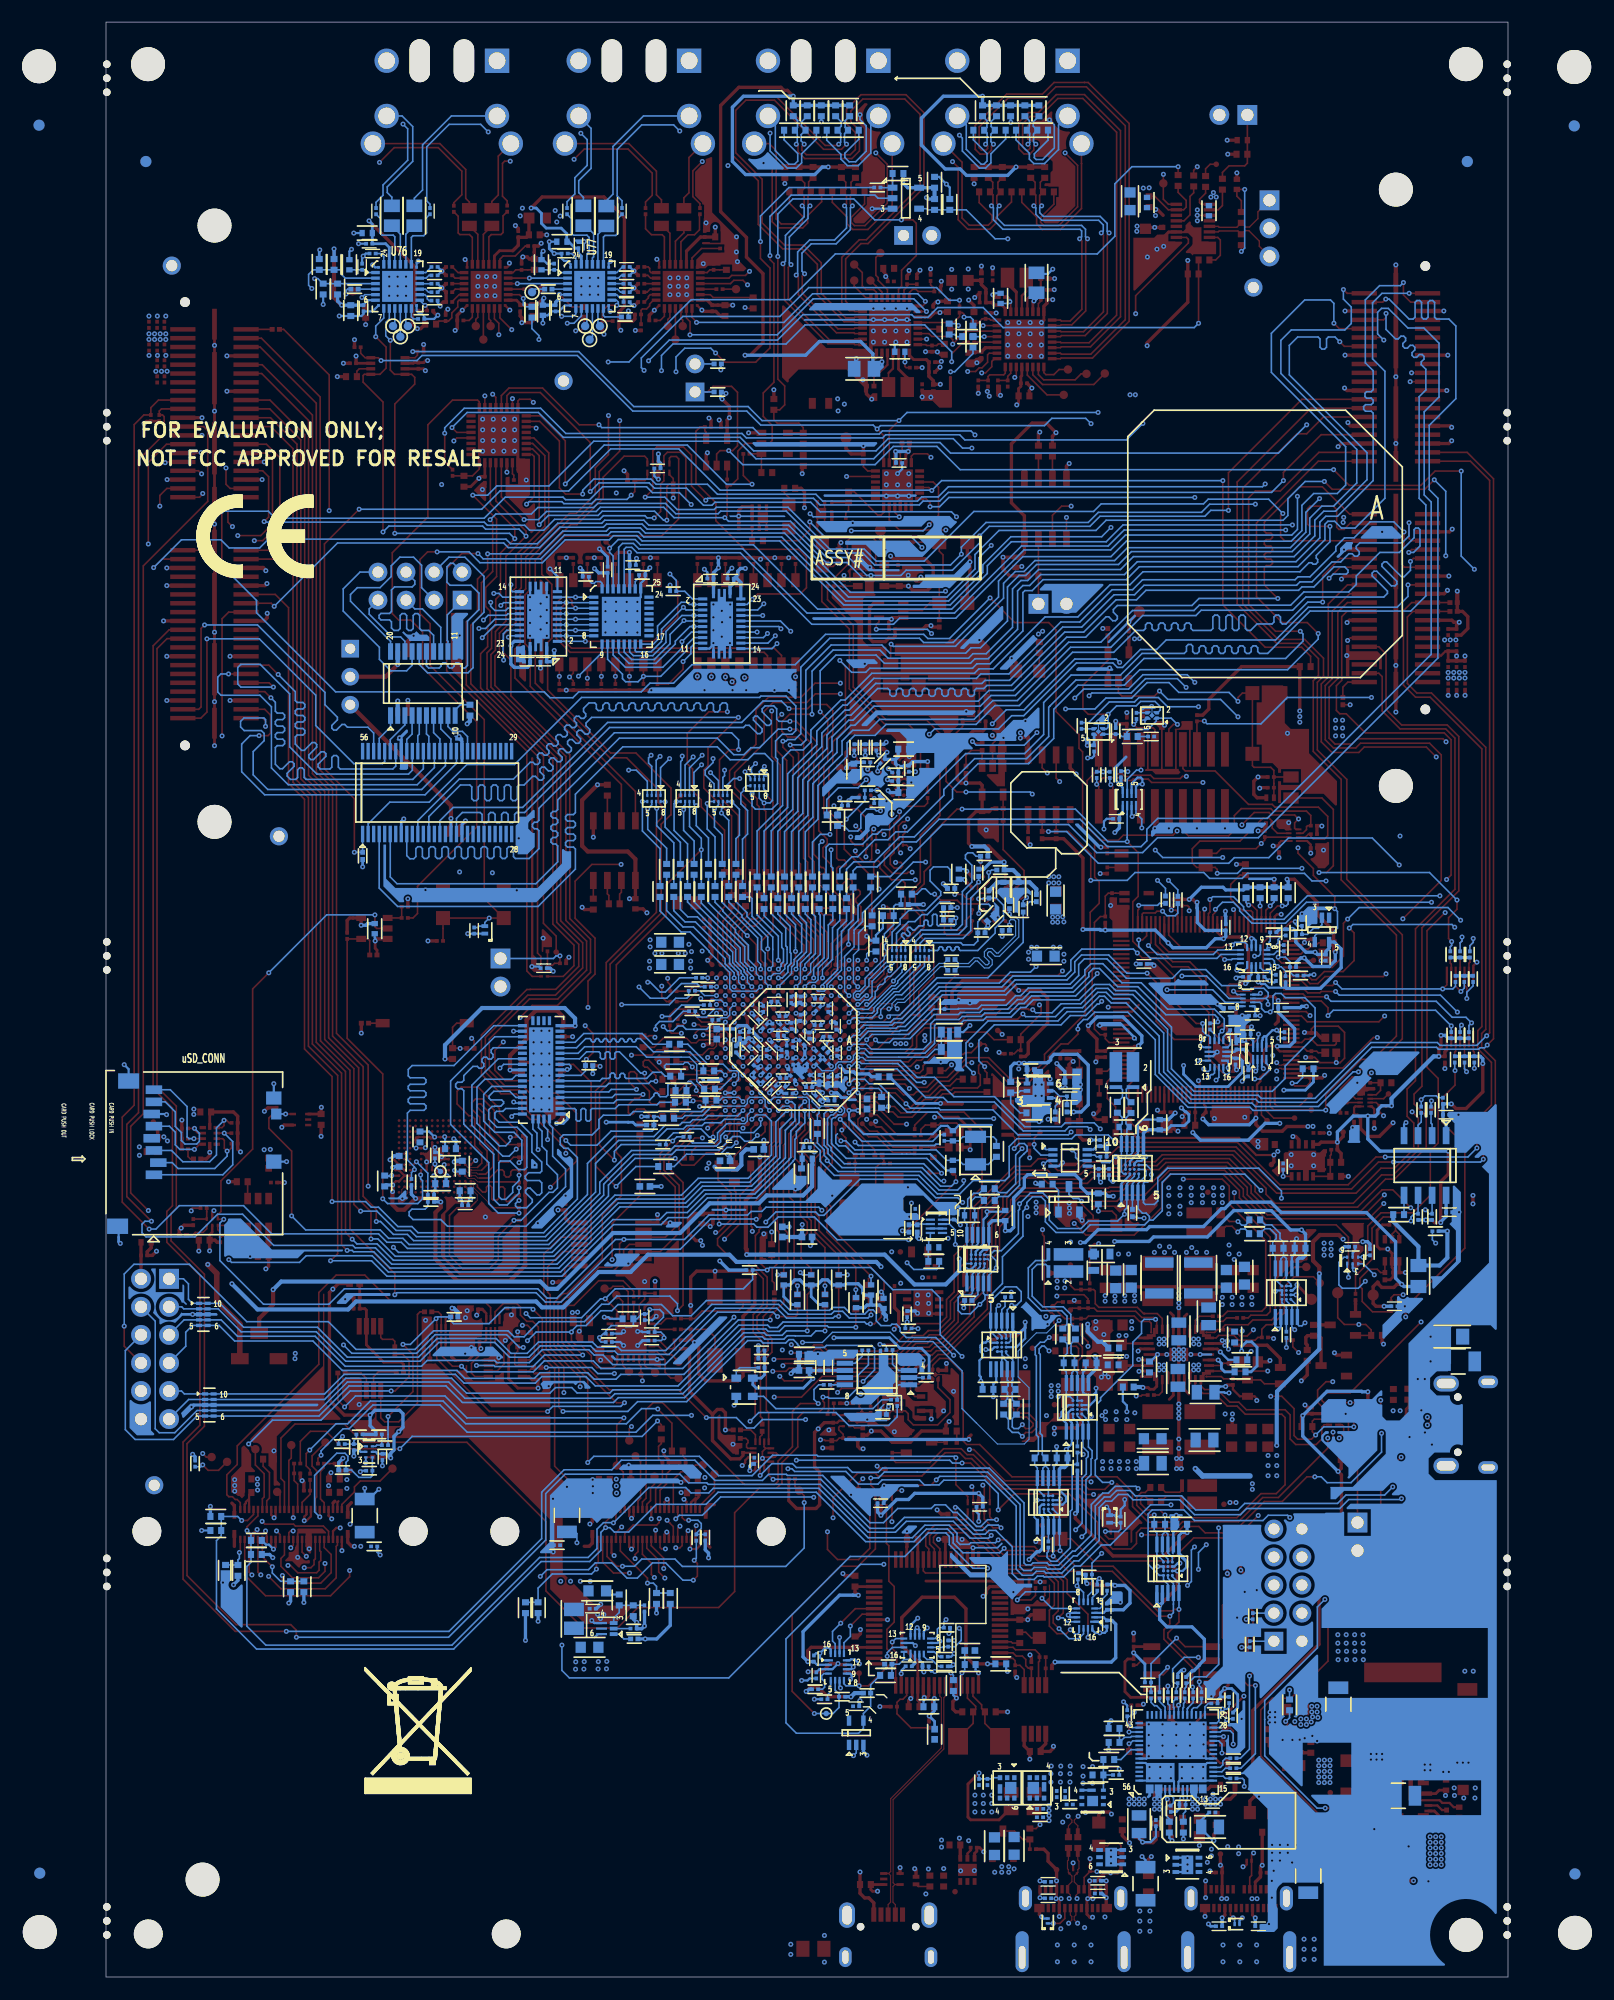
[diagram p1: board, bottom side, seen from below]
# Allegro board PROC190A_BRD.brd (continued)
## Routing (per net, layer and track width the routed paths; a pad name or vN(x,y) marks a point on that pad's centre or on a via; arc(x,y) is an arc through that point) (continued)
MCASP0_ACLKR_R: length 11.8
  TOP w0.147: U136.R16 v1(69.3,89.65)
  BOTTOM w0.132: v1(69.3,89.65) 69.7,90.06 69.7,90.73 69.75,90.78 69.75,90.98
  BOTTOM w0.147: 69.75,90.98 70.51,91.74 70.51,92.43 73.61,95.53 74.55,95.53 75.56,96.55 R5648.2
MCASP0_ACLKX: length 92.9
  TOP w0.147: R178.1 66.58,106.38 v1(67.23,107.04) ; J12.37 115.75,134.78 116.13,135.15 v1(116.13,136.63)
  L03_SIG1 w0.091: v1(116.13,136.63) 112.45,136.63 107.54,131.72 101.31,131.72 101.2,131.83 101.2,132.23 101.09,132.33 100.94,132.33 100.84,132.23 100.84,131.83 100.73,131.72 100.58,131.72 100.47,131.83 100.47,132.23 100.36,132.33 100.21,132.33 100.1,132.23 100.1,131.83 100,131.72 99.85,131.72 99.74,131.83 99.74,132.23 99.63,132.33 99.48,132.33 99.37,132.23 99.37,131.83 99.27,131.72 99.11,131.72 99.01,131.83 99.01,132.23 98.9,132.33 98.75,132.33 98.64,132.23 98.64,131.83 98.53,131.72 97.76,131.72 96.57,130.53 96.57,129.11 96.02,128.56 96.02,120.61 88.54,113.13 85.17,113.13 84.37,112.34 84.37,112.19 84.67,111.89 84.67,111.74 84.56,111.63 84.41,111.63 84.11,111.93 83.96,111.93 83.86,111.82 83.86,111.67 84.15,111.38 84.15,111.22 84.04,111.12 83.89,111.12 83.6,111.41 83.45,111.41 83.34,111.3 83.34,111.15 83.63,110.86 83.63,110.71 83.52,110.6 83.37,110.6 83.08,110.89 82.93,110.89 82.82,110.79 82.82,110.63 83.11,110.34 83.11,110.19 83.01,110.08 82.86,110.08 82.56,110.38 82.41,110.38 82.3,110.27 82.3,110.12 82.6,109.82 82.6,109.67 82.49,109.57 82.34,109.57 82.04,109.86 81.89,109.86 81.79,109.75 81.79,109.6 82.08,109.31 82.08,109.16 81.97,109.05 81.82,109.05 81.53,109.34 81.38,109.34 81.27,109.23 81.27,109.08 81.56,108.79 81.56,108.64 81.45,108.53 81.3,108.53 81.01,108.82 80.86,108.82 80.75,108.72 80.75,108.57 81.04,108.27 81.04,108.12 80.94,108.01 80.79,108.01 80.49,108.31 80.34,108.31 80.21,108.18 80.14,108.18 79.86,107.9 69.37,107.9 69.09,108.18 67.64,108.18 67.23,107.77 v1(67.23,107.04)
  BOTTOM w0.147: RA6.8 67.42,107.58 67.23,107.39 v1(67.23,107.04)
MCASP0_AFSR: length 85.7
  TOP w0.147: v1(111.4,129.18) J12.41
  L03_SIG1 w0.091: v1(111.4,129.18) 111.16,128.93 106.85,128.93 106.74,128.82 106.74,128.25 106.63,128.14 106.48,128.14 106.38,128.25 106.38,128.82 106.27,128.93 106.12,128.93 106.01,128.82 106.01,128.25 105.9,128.14 105.75,128.14 105.64,128.25 105.64,128.82 105.54,128.93 105.39,128.93 105.28,128.82 105.28,128.25 105.17,128.14 105.02,128.14 104.91,128.25 104.91,128.82 104.81,128.93 104.65,128.93 104.55,128.82 104.55,128.25 104.44,128.14 104.29,128.14 104.18,128.25 104.18,128.82 104.07,128.93 102.15,128.93 100.94,127.72 100.94,123.98 100.17,123.21 100.17,123.06 100.61,122.61 100.61,122.46 100.5,122.36 100.35,122.36 99.91,122.8 99.76,122.8 99.65,122.69 99.65,122.54 100.09,122.1 100.09,121.95 99.99,121.84 99.84,121.84 99.39,122.28 99.24,122.28 98.39,121.43 98.39,121.28 98.83,120.84 98.83,120.68 98.73,120.58 98.57,120.58 98.13,121.02 97.98,121.02 97.78,120.81 97.78,120.66 98.22,120.22 98.22,120.07 98.11,119.96 97.96,119.96 97.52,120.4 97.37,120.4 97.26,120.3 97.26,120.15 97.7,119.7 97.7,119.55 97.59,119.45 97.44,119.45 97,119.89 96.85,119.89 96.74,119.78 96.74,119.63 97.18,119.19 97.18,119.04 97.08,118.93 96.93,118.93 96.48,119.37 96.33,119.37 96.23,119.26 96.23,119.11 96.67,118.67 96.67,118.52 96.56,118.41 96.41,118.41 95.97,118.85 95.82,118.85 95.71,118.75 95.71,118.59 96.15,118.15 96.15,118 96.04,117.89 95.89,117.89 95.45,118.34 95.3,118.34 95.19,118.23 95.19,118.08 95.63,117.64 95.63,117.48 95.53,117.38 95.37,117.38 94.93,117.82 94.78,117.82 94.67,117.71 94.67,117.56 95.12,117.12 95.12,116.97 95.01,116.86 94.86,116.86 94.41,117.3 94.26,117.3 94.16,117.19 94.16,117.04 94.6,116.6 94.6,116.45 94.49,116.34 94.34,116.34 93.9,116.78 93.75,116.78 93.64,116.68 93.64,116.53 94.08,116.08 94.08,115.93 93.97,115.82 93.82,115.82 93.38,116.27 93.23,116.27 93.12,116.16 93.12,116.01 93.56,115.57 93.56,115.41 93.46,115.31 93.3,115.31 92.86,115.75 92.71,115.75 92.6,115.64 92.6,115.49 93.05,115.05 93.05,114.9 92.94,114.79 92.79,114.79 92.35,115.23 92.19,115.23 92.09,115.12 92.09,114.97 92.53,114.53 92.53,114.38 92.42,114.27 92.27,114.27 91.83,114.71 91.68,114.71 91.57,114.61 91.57,114.46 92.01,114.01 92.01,113.86 91.9,113.76 91.75,113.76 91.31,114.2 91.16,114.2 90.96,114 90.96,113.84 91.5,113.3 91.5,113.15 91.39,113.04 91.24,113.04 90.7,113.59 90.55,113.59 84.77,107.81 84.62,107.81 84.49,107.94 84.34,107.94 84.23,107.83 84.23,107.68 84.36,107.55 84.36,107.4 84.26,107.29 84.1,107.29 83.98,107.42 83.82,107.42 83.72,107.31 83.72,107.16 83.85,107.03 83.85,106.88 82.73,105.77 v1(77.93,105.77)
  BOTTOM w0.147: R498.2 76.22,102.2 77.93,103.91 v1(77.93,105.77) 77.56,106.13 RA7.6
MCASP0_AFSR_R: length 13
  TOP w0.147: U136.T17 v1(70.1,90.45)
  BOTTOM w0.132: 70.1,90.92 v1(70.1,90.45)
  BOTTOM w0.147: 70.1,90.92 70.92,91.74 70.92,92.2 73.79,95.07 74.73,95.07 76.22,96.56 R498.1
MCASP0_AFSX: length 88.6
  TOP w0.147: v1(115.54,131.32) 115.95,131.72 115.95,133.66 115.63,133.98 J12.39
  L03_SIG1 w0.091: v1(115.54,131.32) 116.51,131.32 117.68,130.15 117.68,125.7 108.36,116.38 102.51,116.38 101.47,115.34 101.47,109.83 94.92,103.28 94.77,103.28 94.15,103.9 94,103.9 93.89,103.8 93.89,103.64 94.51,103.02 94.51,102.87 94.41,102.76 94.25,102.76 93.63,103.38 93.48,103.38 93.37,103.28 93.37,103.13 93.99,102.5 93.99,102.35 93.89,102.24 93.74,102.24 93.11,102.87 92.96,102.87 92.85,102.76 92.85,102.61 93.48,101.99 93.48,101.83 93.27,101.63 71.02,101.63 70.31,102.34 v1(70.31,106.4)
  BOTTOM w0.147: R191.2 69.94,103.06 69.62,103.38 69.62,105.71 v1(70.31,106.4) 70.34,106.43 RA2.8
MCASP0_AFSX_R: length 9.6
  TOP w0.147: v1(67.06,93.09) 67.06,92.21 U136.M19
  BOTTOM w0.147: R191.1 69.94,97.37 68.94,96.37 68.94,96.04 67.06,94.16 v1(67.06,93.09)
MCASP0_AXR0: length 86.3
  TOP w0.147: v1(113.56,130.05) 112.8,130.05 111.25,131.6 111.25,137.57 112.46,138.78 J12.27
  L03_SIG1 w0.091: v1(73.53,106.05) 75.64,103.94 78.61,103.94 78.72,103.83 78.72,103.12 78.83,103.01 78.98,103.01 79.09,103.12 79.09,103.83 79.19,103.94 79.57,103.94 79.68,103.83 79.68,103.15 79.78,103.05 79.93,103.05 80.04,103.15 80.04,103.83 80.15,103.94 80.3,103.94 80.41,103.83 80.41,103.15 80.51,103.05 80.67,103.05 80.77,103.15 80.77,103.83 80.88,103.94 81.03,103.94 81.14,103.83 81.14,103.15 81.25,103.05 81.4,103.05 81.5,103.15 81.5,103.83 81.61,103.94 81.76,103.94 81.87,103.83 81.87,103.15 81.98,103.05 82.13,103.05 82.24,103.15 82.24,103.83 82.34,103.94 83.75,103.94 83.86,103.83 83.86,103.28 83.96,103.17 84.11,103.17 84.22,103.28 84.22,103.83 84.33,103.94 86.33,103.94 88.63,106.23 88.78,106.23 88.95,106.06 89.11,106.06 89.21,106.16 89.21,106.31 89.04,106.49 89.04,106.64 89.15,106.75 89.3,106.75 89.47,106.57 89.62,106.57 89.73,106.68 89.73,106.83 89.56,107.01 89.56,107.16 89.66,107.26 89.81,107.26 89.99,107.09 90.14,107.09 90.25,107.2 90.25,107.35 90.07,107.52 90.07,107.68 90.18,107.78 90.33,107.78 90.51,107.61 90.66,107.61 90.77,107.71 90.77,107.87 90.59,108.04 90.59,108.19 90.7,108.3 90.85,108.3 91.02,108.12 91.18,108.12 91.28,108.23 91.28,108.38 91.11,108.56 91.11,108.71 91.21,108.82 91.37,108.82 91.54,108.64 91.69,108.64 91.8,108.75 91.8,108.9 91.62,109.08 91.62,109.23 93.68,111.28 93.68,113.87 102.49,122.68 108.03,122.68 112.24,126.9 112.7,126.9 113.56,127.76 v1(113.56,130.05)
  BOTTOM w0.147: R176.2 72.43,103.13 73.53,104.24 v1(73.53,106.05) 73.59,106.05 73.74,106.19 RA5.8
MCASP0_AXR0_R: length 11.9
  TOP w0.147: U136.N17 v1(67.7,90.45)
  BOTTOM w0.132: v1(67.7,90.45) 68.1,90.86 68.1,91.42 68.81,92.13
  BOTTOM w0.147: 68.81,92.13 68.81,93.42 69.98,94.59 69.98,94.82 72.43,97.27 R176.1
MCASP0_AXR1: length 88.9
  TOP w0.147: v1(115.06,130.51) 112.98,130.51 111.92,131.57 111.92,137.42 112.48,137.98 J12.29
  L03_SIG1 w0.091: v1(115.06,130.51) 115.57,130 115.57,124.94 109.75,119.13 101.75,119.13 99.09,116.46 99.09,110.59 97.12,108.62 97.12,108.47 97.41,108.18 97.41,108.03 97.3,107.92 97.15,107.92 96.86,108.21 96.71,108.21 96.6,108.11 96.6,107.96 96.89,107.66 96.89,107.51 96.79,107.4 96.63,107.4 96.34,107.7 96.19,107.7 96.08,107.59 96.08,107.44 96.38,107.15 96.38,106.99 96.27,106.89 96.12,106.89 95.82,107.18 95.67,107.18 95.57,107.07 95.57,106.92 95.86,106.63 95.86,106.48 95.75,106.37 95.6,106.37 95.31,106.66 95.16,106.66 90.4,101.9 74.27,101.9 71.25,104.93 v1(71.25,105.38)
  BOTTOM w0.147: R499.2 70.59,104.72 v1(71.25,105.38) 71.25,105.74 71.12,105.87 RA2.7
MCASP0_AXR1_R: length 10.2
  TOP w0.147: U136.M16 v1(66.9,89.65)
  BOTTOM w0.132: 67.61,93.04 67.29,92.72 67.29,90.05 v1(66.9,89.65)
  BOTTOM w0.147: 67.61,93.04 67.61,94.18 69.39,95.96 69.39,96.14 70.59,97.33 R499.1
MCASP0_AXR2: length 88.1
  TOP w0.147: v1(123.16,129.74) 123.16,137.13 121.52,138.78 J12.28
  L03_SIG1 w0.091: v1(123.16,129.74) 120.85,132.05 115.37,132.05 114.64,131.32 114.64,126.34 110.36,122.07 102.79,122.07 97.38,116.66 97.38,113.51 86.11,102.23 75.41,102.23 v1(71.88,105.77)
  BOTTOM w0.147: RA2.6 71.52,106.13 v1(71.88,105.77) 71.88,104.11 71.18,103.41 R493.2
MCASP0_AXR2_R: length 10.6
  TOP w0.147: U136.N18 v1(67.7,91.26)
  BOTTOM w0.132: 67.97,93.04 67.97,91.98 67.7,91.7 v1(67.7,91.26)
  BOTTOM w0.147: R493.1 71.18,97.29 67.97,94.08 67.97,93.04
MCASP0_AXR3: length 89.6
  TOP w0.147: J12.30 118.43,137.98 v1(118.39,138.02)
  L03_SIG1 w0.091: v1(118.39,138.02) 116.37,136 112.41,136 106.25,129.84 105.42,129.84 105.31,129.95 105.31,130.3 105.2,130.41 105.05,130.41 104.95,130.3 104.95,129.95 104.84,129.84 104.69,129.84 104.58,129.95 104.58,130.3 104.47,130.41 104.32,130.41 104.21,130.3 104.21,129.95 104.11,129.84 103.96,129.84 103.85,129.95 103.85,130.3 103.74,130.41 103.59,130.41 103.48,130.3 103.48,129.95 103.38,129.84 103.22,129.84 103.12,129.95 103.12,130.3 103.01,130.41 102.86,130.41 102.75,130.3 102.75,129.95 102.64,129.84 102.49,129.84 102.39,129.95 102.39,130.3 102.28,130.41 102.13,130.41 102.02,130.3 102.02,129.95 101.91,129.84 101.76,129.84 101.65,129.95 101.65,130.3 101.55,130.41 101.4,130.41 101.29,130.3 101.29,129.95 101.18,129.84 100.52,129.84 98.4,127.72 98.4,122.58 88.67,112.85 86.23,112.85 85.95,112.57 85.95,112.42 86.78,111.6 86.78,111.44 86.67,111.34 86.52,111.34 85.7,112.16 85.54,112.16 85.44,112.06 85.44,111.9 86.26,111.08 86.26,110.93 86.16,110.82 86,110.82 85.18,111.65 85.03,111.65 84.92,111.54 84.92,111.39 85.75,110.56 85.75,110.41 85.64,110.3 85.49,110.3 84.66,111.13 84.51,111.13 80.82,107.44 69.54,107.44 69.44,107.54 v1(69.11,107.54)
  BOTTOM w0.147: R494.2 69.34,103.02 68.88,103.48 68.88,105.61 69.49,106.22 69.49,107.17 v1(69.11,107.54) 69.11,107.71 68.97,107.86 RA6.5
MCASP0_AXR3_R: length 8.8
  TOP w0.147: U136.M18 v1(66.9,91.26)
  BOTTOM w0.132: 66.6,93.04 66.6,91.55 v1(66.9,91.26)
  BOTTOM w0.147: R494.1 68.63,97.79 68.48,97.64 68.48,96.04 66.6,94.16 66.6,93.04
MCASP0_AXR4: length 83.2
  TOP w0.147: J12.32 121.57,137.18 v1(121.64,137.11)
  L03_SIG1 w0.091: v1(121.64,137.11) 118.36,137.11 116.46,135.2 115.32,135.2 112.53,132.42 112.38,132.42 112.06,132.73 111.91,132.73 111.8,132.63 111.8,132.48 112.12,132.16 112.12,132.01 112.01,131.9 111.86,131.9 111.54,132.22 111.39,132.22 111.28,132.11 111.28,131.96 111.6,131.64 111.6,131.49 111.49,131.38 111.34,131.38 111.02,131.7 110.87,131.7 110.77,131.59 110.77,131.44 111.08,131.12 111.08,130.97 110.98,130.86 110.83,130.86 110.51,131.18 110.36,131.18 110.25,131.08 110.25,130.92 110.57,130.61 110.57,130.45 110.46,130.35 110.31,130.35 109.99,130.67 109.84,130.67 109.73,130.56 109.73,130.41 110.05,130.09 110.05,129.94 109.5,129.39 100.45,129.39 98.68,127.62 98.68,122.45 88.8,112.57 88.44,112.57 85.58,109.71 85.43,109.71 85.09,110.04 84.94,110.04 84.84,109.93 84.84,109.78 85.17,109.45 85.17,109.3 85.06,109.19 84.91,109.19 84.58,109.52 84.43,109.52 84.32,109.41 84.32,109.26 84.65,108.93 84.65,108.78 84.54,108.67 84.39,108.67 84.06,109 83.91,109 83.8,108.9 83.8,108.74 84.13,108.41 84.13,108.26 84.02,108.15 83.87,108.15 83.54,108.49 83.39,108.49 83.28,108.38 83.28,108.23 83.61,107.9 83.61,107.74 82.3,106.43 81.87,106.43 81.76,106.54 81.76,106.95 81.65,107.06 81.5,107.06 81.39,106.95 81.39,106.54 81.29,106.43 81.13,106.43 81.03,106.54 81.03,106.95 80.92,107.06 80.77,107.06 80.66,106.95 80.66,106.54 80.55,106.43 80.4,106.43 80.29,106.54 80.29,106.95 80.19,107.06 80.04,107.06 79.93,106.95 79.93,106.54 79.82,106.43 79.67,106.43 79.56,106.54 79.56,106.95 79.46,107.06 79.3,107.06 79.2,106.95 79.2,106.54 79.09,106.43 v1(78.41,106.43)
  BOTTOM w0.147: RA7.5 v1(78.41,106.43) 78.41,103.76 76.81,102.16 R495.2
MCASP0_AXR4_R: length 15
  TOP w0.147: U136.N16 v1(67.7,89.65)
  BOTTOM w0.132: 72.36,92.81 70.5,90.95 70.5,89.5 70.26,89.26 68.09,89.26 v1(67.7,89.65)
  BOTTOM w0.147: 72.36,92.81 72.36,92.89 74.09,94.61 74.9,94.61 76.81,96.52 R495.1
MCASP0_AXR5: length 86.7
  TOP w0.147: v1(118.34,136.09) 118.62,136.38 J12.34
  L03_SIG1 w0.091: v1(74.68,105.69) 75.31,105.69 75.48,105.52 75.48,105.37 75.19,105.08 75.19,104.93 75.29,104.82 75.44,104.82 75.74,105.11 75.89,105.11 76.66,104.35 76.78,104.35 76.88,104.44 76.88,104.68 76.98,104.79 77.13,104.79 77.24,104.68 77.24,104.37 77.35,104.27 77.5,104.27 77.61,104.37 77.61,104.68 77.71,104.79 77.87,104.79 77.97,104.68 77.97,104.37 78.08,104.27 78.23,104.27 78.34,104.37 78.34,104.68 78.45,104.79 78.6,104.79 78.7,104.68 78.7,104.37 78.81,104.27 78.96,104.27 79.07,104.37 79.07,104.68 79.18,104.79 79.33,104.79 79.44,104.68 79.44,104.37 79.54,104.27 79.7,104.27 79.8,104.37 79.8,104.68 79.91,104.79 80.06,104.79 80.17,104.68 80.17,104.37 80.28,104.27 80.43,104.27 80.53,104.37 80.53,104.68 80.64,104.79 80.79,104.79 80.9,104.68 80.9,104.37 81.01,104.27 81.16,104.27 81.27,104.37 81.27,104.68 81.37,104.79 81.52,104.79 81.63,104.68 81.63,104.37 81.74,104.27 81.89,104.27 82,104.37 82,104.68 82.1,104.79 82.26,104.79 82.36,104.68 82.36,104.37 82.47,104.27 82.62,104.27 82.73,104.37 82.73,104.68 82.84,104.79 82.99,104.79 83.09,104.68 83.09,104.37 83.2,104.27 83.35,104.27 83.46,104.37 83.46,104.68 83.57,104.79 83.72,104.79 83.83,104.68 83.83,104.37 83.93,104.27 84.08,104.27 84.19,104.37 84.19,104.68 84.3,104.79 84.45,104.79 84.56,104.68 84.56,104.37 84.66,104.27 84.82,104.27 84.92,104.37 84.92,104.68 85.03,104.79 85.18,104.79 85.29,104.68 85.29,104.37 85.4,104.27 85.8,104.27 86.09,104.55 86.24,104.55 86.32,104.47 86.48,104.47 86.58,104.57 86.58,104.73 86.5,104.81 86.5,104.96 86.6,105.07 86.76,105.07 86.84,104.98 86.99,104.98 87.1,105.09 87.1,105.24 87.01,105.33 87.01,105.48 87.12,105.59 87.27,105.59 87.36,105.5 87.51,105.5 87.62,105.61 87.62,105.76 87.53,105.85 87.53,106 87.64,106.1 87.79,106.1 87.88,106.02 88.03,106.02 88.14,106.13 88.14,106.28 88.05,106.36 88.05,106.51 88.16,106.62 88.31,106.62 88.39,106.54 88.55,106.54 88.65,106.64 88.65,106.79 88.57,106.88 88.57,107.03 88.67,107.14 88.82,107.14 88.91,107.05 89.06,107.05 89.17,107.16 89.17,107.31 89.08,107.4 89.08,107.55 89.19,107.66 89.34,107.66 89.43,107.57 89.58,107.57 89.69,107.68 89.69,107.83 89.6,107.92 89.6,108.07 89.71,108.17 89.86,108.17 89.95,108.09 90.1,108.09 90.2,108.19 90.2,108.35 90.12,108.43 90.12,108.58 90.23,108.69 90.38,108.69 90.46,108.6 90.61,108.6 90.72,108.71 90.72,108.86 90.64,108.95 90.64,109.1 90.74,109.21 90.89,109.21 90.98,109.12 91.13,109.12 91.24,109.23 91.24,109.38 91.15,109.47 91.15,109.62 91.26,109.73 91.41,109.73 91.5,109.64 91.65,109.64 91.76,109.75 91.76,109.9 91.67,109.98 91.67,110.14 91.78,110.24 91.93,110.24 92.01,110.16 92.17,110.16 92.27,110.26 92.27,110.42 92.19,110.5 92.19,110.65 92.53,111 92.53,111.55 92.64,111.66 92.83,111.66 92.94,111.77 92.94,111.92 92.83,112.03 92.64,112.03 92.53,112.13 92.53,112.29 92.64,112.39 92.83,112.39 92.94,112.5 92.94,112.65 92.83,112.76 92.64,112.76 92.53,112.87 92.53,113.13 102.36,122.96 107.37,122.96 112.83,128.42 112.83,130.35 116.16,133.68 118.74,133.68 119.15,134.09 119.15,135.28 v1(118.34,136.09)
  BOTTOM w0.147: R492.2 73.73,102.86 74.68,103.81 v1(74.68,105.69) 74.68,105.99 74.54,106.13 RA5.6
MCASP0_AXR5_R: length 12.1
  TOP w0.147: U136.P17 v1(68.5,90.45)
  BOTTOM w0.132: v1(68.5,90.45) 68.5,90.67 68.91,91.08 68.91,91.29 69.55,91.92
  BOTTOM w0.147: 69.55,91.92 69.55,93.17 73.73,97.35 R492.1
MCASP0_AXR6_R: length 9
  TOP w0.147: U136.P18 v1(68.5,91.26)
  BOTTOM w0.132: 69.14,91.9 v1(68.5,91.26)
  BOTTOM w0.147: R5718.1 73.08,97.23 69.14,93.29 69.14,91.9
MCASP0_AXR7: length 90.7
  TOP w0.147: J12.38 121.48,134.78 122.12,134.14 v1(122.12,133.17)
  L03_SIG1 w0.091: v1(122.12,133.17) 121.89,133.4 116.27,133.4 114.15,131.28 114.15,127.25 109.25,122.35 102.67,122.35 97.1,116.79 97.1,113.67 88.93,105.49 88.78,105.49 88.64,105.63 88.48,105.63 88.38,105.52 88.38,105.37 88.52,105.23 88.52,105.08 88.41,104.97 88.26,104.97 88.12,105.11 87.97,105.11 87.86,105 87.86,104.85 88,104.71 88,104.56 87.89,104.45 87.74,104.45 87.6,104.59 87.45,104.59 87.34,104.49 87.34,104.34 87.48,104.19 87.48,104.04 87.38,103.94 87.22,103.94 87.08,104.08 86.93,104.08 86.82,103.97 86.82,103.82 86.97,103.68 86.97,103.53 86.86,103.42 86.71,103.42 86.57,103.56 86.41,103.56 86.31,103.45 86.31,103.3 86.45,103.16 86.45,103.01 86.11,102.67 85.19,102.67 85.08,102.77 85.08,103.35 84.97,103.45 84.82,103.45 84.71,103.35 84.71,102.77 84.61,102.67 78.57,102.67 78.23,103 78.23,103.55 78.13,103.66 77.97,103.66 77.87,103.55 77.87,103 77.76,102.9 77.61,102.9 77.5,103 77.5,103.55 77.39,103.66 77.24,103.66 77.14,103.55 77.14,103 77.03,102.9 76.88,102.9 76.77,103 76.77,103.55 76.66,103.66 76.51,103.66 76.4,103.55 76.4,103 76.3,102.9 76.15,102.9 76.04,103 76.04,103.55 75.93,103.66 75.13,103.66 74.63,104.17 74.47,104.17 74.25,103.94 74.1,103.94 73.99,104.05 73.99,104.2 74.22,104.42 74.22,104.58 74.11,104.68 73.96,104.68 73.73,104.46 73.58,104.46 73.47,104.56 73.47,104.72 73.7,104.94 73.7,105.09 73.59,105.2 73.44,105.2 73.21,104.97 73.06,104.97 72.95,105.08 72.95,105.23 73.18,105.46 73.18,105.61 v1(72.54,106.25)
  BOTTOM w0.147: RA2.5 72.36,106.43 v1(72.54,106.25) 72.54,103.94 71.83,103.23 R177.2
MCASP0_AXR7_R: length 7.7
  TOP w0.147: v1(68.91,94.28) 68.1,93.47 U136.P19
  BOTTOM w0.147: R177.1 71.83,97.31 71.12,96.6 71.12,96.49 v1(68.91,94.28)
MCASP0_AXR8_R: length 11.2
  TOP w0.147: U136.P16 v1(68.5,89.65)
  BOTTOM w0.132: v1(68.5,89.65) 68.9,90.06 68.9,90.69 69.19,90.98 69.19,91.19 69.95,91.95 69.95,93.04 70.77,93.86
  BOTTOM w0.147: 70.77,93.86 70.84,93.86 74.32,97.34 R5719.1
MCASP0_AXR9: length 85.6
  TOP w0.147: J12.40 118.52,133.98 118.24,134.26 v1(118.24,134.32)
  L03_SIG1 w0.091: v1(76.35,106.4) 76.35,105.33 76.62,105.06 86.07,105.06 86.63,105.63 86.63,105.78 86.19,106.23 86.19,106.38 86.3,106.49 86.45,106.49 86.89,106.04 87.04,106.04 87.15,106.15 87.15,106.3 86.71,106.75 86.71,106.9 86.81,107.01 86.96,107.01 87.41,106.56 87.56,106.56 87.67,106.67 87.67,106.82 87.22,107.26 87.22,107.42 87.33,107.52 87.48,107.52 87.93,107.08 88.08,107.08 88.19,107.18 88.19,107.34 87.74,107.78 87.74,107.93 87.85,108.04 88,108.04 88.44,107.59 88.6,107.59 88.7,107.7 88.7,107.85 88.26,108.3 88.26,108.45 88.36,108.56 88.52,108.56 88.96,108.11 89.11,108.11 89.22,108.22 89.22,108.37 88.77,108.82 88.77,108.97 88.88,109.07 89.03,109.07 89.48,108.63 89.63,108.63 89.74,108.74 89.74,108.89 89.29,109.33 89.29,109.48 89.4,109.59 89.55,109.59 90,109.15 90.15,109.15 90.25,109.25 90.25,109.41 89.81,109.85 89.81,110 89.92,110.11 90.07,110.11 90.51,109.66 90.66,109.66 90.77,109.77 90.77,109.92 90.33,110.37 90.33,110.52 90.43,110.63 90.59,110.63 91.03,110.18 91.18,110.18 91.29,110.29 91.29,110.44 90.84,110.89 90.84,111.04 90.95,111.14 91.1,111.14 91.55,110.7 91.7,110.7 92.25,111.25 92.25,113.26 102.23,123.24 107.24,123.24 107.88,123.88 107.88,124.03 107.59,124.33 107.59,124.48 107.7,124.59 107.85,124.59 108.14,124.29 108.29,124.29 108.4,124.4 108.4,124.55 108.11,124.85 108.11,125 108.21,125.1 108.36,125.1 108.66,124.81 108.81,124.81 108.92,124.92 108.92,125.07 108.62,125.36 108.62,125.51 108.73,125.62 108.88,125.62 109.17,125.33 109.33,125.33 109.43,125.44 109.43,125.59 109.14,125.88 109.14,126.03 109.25,126.14 109.4,126.14 109.69,125.85 109.84,125.85 109.95,125.95 109.95,126.1 109.66,126.4 109.66,126.55 109.76,126.66 109.92,126.66 110.21,126.36 110.36,126.36 112.37,128.37 112.37,130.45 116.23,134.32 v1(118.24,134.32)
  BOTTOM w0.147: R491.2 74.97,102.73 76.35,104.11 v1(76.35,106.4) 76.38,106.43 RA7.8
MCASP0_AXR9_R: length 12.8
  TOP w0.147: v1(69.3,90.46) U136.R17
  BOTTOM w0.132: 71.14,93.69 70.23,92.79 70.23,91.85 69.47,91.08 69.47,90.88 69.3,90.71 v1(69.3,90.46)
  BOTTOM w0.147: 71.14,93.69 73.43,95.99 74.3,95.99 74.97,96.66 R491.1
MCASP1_ACLKR_R: length 6.9
  TOP w0.132: U136.T18 70.09,91.25 70.09,92.86 70.27,93.04
  TOP w0.147: R179.2 69.07,96.39 70.4,95.06 70.4,93.17 70.27,93.04
MCASP1_ACLKX_R: length 6.1
  TOP w0.147: R5646.2 65.34,95.71 63.3,93.68 U136.H19
MCASP1_AFSR_R: length 8.2
  TOP w0.132: 69.7,93.04 69.7,93.04 U136.T19
  TOP w0.147: R5640.1 68.48,96.49 70.05,94.92 70.05,93.39 69.7,93.04
MCASP1_AFSX_R: length 7.4
  TOP w0.147: U136.J17 v1(63.7,90.45)
  BOTTOM w0.132: 62.31,92.58 63.17,91.72 63.17,90.98 v1(63.7,90.45)
  BOTTOM w0.147: 62.31,92.58 62.31,96.14 62.41,96.24 R5647.1
MCASP1_AXR0_R: length 8.5
  TOP w0.147: U136.J18 v1(63.7,91.26)
  BOTTOM w0.132: v1(63.7,91.26) 63.7,91.7 63.07,92.33
  BOTTOM w0.147: 63.07,92.33 62.74,92.66 62.74,96.01 63,96.28 R500.1
MCASP1_AXR1_R: length 8.4
  TOP w0.147: U136.J19 64.1,92.06 63.78,92.38 63.78,93.42 65.93,95.57 R5645.1
MCASP1_AXR2_R: length 9
  TOP w0.147: U136.J16 v1(63.7,89.65)
  BOTTOM w0.132: 61.57,93.78 61.57,92.25 62.49,91.33 62.49,90.3 62.74,90.05 63.3,90.05 v1(63.7,89.65)
  BOTTOM w0.147: 61.57,93.78 61.57,95.25 61.16,95.66 R190.1
MCASP2_ACLKR: length 81.6
  TOP w0.147: J13.43 17.13,138.04 20.62,134.54 22.89,134.54 23.5,133.93 23.5,124.28 21.06,121.84 v1(18.82,121.84)
  BOTTOM w0.147: R5669.1 60.53,100.33 59.44,101.42 58.9,101.42 57.35,102.97 56.16,102.97 55.45,103.68 54.41,103.68 51.1,106.98 51.1,107.52 48.31,110.31 43.61,110.31 41.61,112.32 41.61,114.96 41.5,115.06 41.5,115.07 39.15,117.42 34.92,117.42 32.97,119.38 20.14,119.38 18.57,120.95 18.57,121.59 v1(18.82,121.84)
MCASP2_ACLKR_R: length 9.4
  TOP w0.147: U136.G17 v1(62.1,90.45)
  BOTTOM w0.132: 61.65,91.67 62.1,91.22 v1(62.1,90.45)
  BOTTOM w0.147: R5669.2 60.53,95.66 61.19,95 61.19,92.13 61.65,91.67
MCASP2_ACLKX: length 82.9
  TOP w0.147: v1(16.13,131.34) 17.96,131.34 18.16,131.55 18.16,132.94 17.93,133.17 15.82,133.17 15.52,132.87 15.52,131.27 15.32,131.06 14.86,131.06 14.28,131.64 J13.37
  BOTTOM w0.147: R5668.1 68.02,103.76 65.71,106.07 65.71,110.36 64.97,111.1 63.86,111.1 63.14,111.81 63.14,112.9 60.43,115.62 60.05,115.62 57.63,118.03 48.34,118.03 47.93,118.44 46.63,118.44 41.94,123.14 38.96,123.14 36.04,126.06 34.24,126.06 33.07,127.23 18.85,127.23 18.03,128.05 17.79,128.05 17.66,127.92 17.41,127.92 17.24,128.09 17.24,128.34 17.37,128.46 17.37,128.71 16.13,129.95 v1(16.13,131.34)
MCASP2_ACLKX_R: length 8
  TOP w0.147: U136.L19 v1(66.1,92.06)
  BOTTOM w0.147: R5668.2 68.02,96.16 66.1,94.24 v1(66.1,92.06)
MCASP2_AFSR: length 82.3
  TOP w0.147: v1(17.2,121.64) 18.19,122.63 20.45,122.63 22.78,124.97 22.78,131.65 17.19,137.24 J13.41
  BOTTOM w0.147: R5667.2 59.92,100.3 59.26,100.97 57.38,100.97 55.12,103.23 53.77,103.23 50.32,106.68 50.32,107.54 48.01,109.86 43.43,109.86 41.15,112.14 41.15,114.78 38.96,116.97 34.75,116.97 33.35,118.36 19.96,118.36 17.2,121.13 v1(17.2,121.64)
MCASP2_AFSR_R: length 8.5
  TOP w0.147: U136.G16 v1(62.1,89.65)
  BOTTOM w0.147: R5667.1 59.92,95.63 60.73,94.82 60.73,91.19 62.1,89.82 v1(62.1,89.65)
MCASP2_AFSX: length 83.3
  TOP w0.147: v1(20.85,124.82) 22.07,126.03 22.07,127.61 21.9,127.79 21.53,127.79 21.34,127.99 21.34,128.23 21.48,128.38 21.9,128.38 22.07,128.55 22.07,128.79 21.9,128.97 21.53,128.97 21.34,129.16 21.34,129.41 21.48,129.55 21.9,129.55 22.07,129.73 22.07,129.97 21.9,130.14 21.53,130.14 21.34,130.34 21.34,130.59 21.48,130.73 21.9,130.73 22.07,130.91 22.07,131.72 18.87,134.92 16.82,134.92 14.34,132.44 J13.39
  BOTTOM w0.147: v1(20.85,124.82) 27.99,124.82 28.63,124.18 35.38,124.18 35.75,123.82 35.75,123.57 35.39,123.21 35.39,122.97 35.56,122.8 35.81,122.8 36.16,123.15 36.41,123.15 38.25,121.31 39.98,121.31 44.81,116.48 47.02,116.48 47.98,115.52 57.61,115.52 59.33,113.79 59.72,113.79 61.24,112.27 61.24,111.05 63.88,108.41 63.88,105.36 65.53,103.71 R5666.2
MCASP2_AFSX_R: length 7.6
  TOP w0.147: U136.K19 64.54,92.01 v1(64.54,92.86)
  BOTTOM w0.132: 64.54,93.21 v1(64.54,92.86)
  BOTTOM w0.147: 64.54,93.21 64.54,95.28 65.53,96.27 R5666.1
MCASP2_AXR0: length 83
  TOP w0.147: v1(16.21,126.64) 15.21,127.64 J13.27
  BOTTOM w0.147: R5660.2 66.14,103.73 64.34,105.54 64.34,108.58 61.7,111.23 61.7,112.45 59.89,114.25 59.51,114.25 57.1,116.66 56.17,116.66 56,116.49 56,116.13 55.82,115.96 55.58,115.96 55.41,116.13 55.41,116.49 55.24,116.66 54.99,116.66 54.82,116.49 54.82,116.13 54.65,115.96 54.4,115.96 54.23,116.13 54.23,116.49 54.06,116.66 53.81,116.66 53.64,116.49 53.64,116.13 53.47,115.96 53.22,115.96 53.05,116.13 53.05,116.49 52.88,116.66 52.63,116.66 52.46,116.49 52.46,116.13 52.29,115.96 52.04,115.96 51.87,116.13 51.87,116.49 51.7,116.66 51.46,116.66 51.28,116.49 51.28,116.13 51.11,115.96 50.87,115.96 50.69,116.13 50.69,116.49 50.52,116.66 50.28,116.66 50.1,116.49 50.1,116.13 49.93,115.96 49.69,115.96 49.51,116.13 49.51,116.49 49.34,116.66 49.1,116.66 48.93,116.49 48.93,116.13 48.75,115.96 48.51,115.96 48.34,116.13 48.34,116.49 48.16,116.66 47.47,116.66 47.19,116.94 44.98,116.94 40.16,121.77 38.43,121.77 35.51,124.69 33.66,124.69 32.79,125.55 18.97,125.55 18.67,125.86 17.59,125.86 15.77,127.68 14.79,127.68 14.5,127.38 14.5,127.17 14.64,127.02 15.83,127.02 v1(16.21,126.64)
MCASP2_AXR0_R: length 8
  TOP w0.147: U136.L17 v1(66.1,90.45)
  BOTTOM w0.147: R5660.1 66.14,96.24 65.02,95.12 65.02,92.76 64.95,92.68 64.95,91.77 65.23,91.49 65.23,90.97 65.74,90.45 v1(66.1,90.45)
MCASP2_AXR1: length 82.8
  TOP w0.147: J13.29 15.22,128.44 16.79,126.87 v1(16.79,124.49)
  BOTTOM w0.147: R5661.2 63.65,103.68 62.51,104.83 62.51,107.87 59.87,110.52 59.87,111.73 59.18,112.42 57.33,112.42 56.34,113.41 48.18,113.41 46.48,115.11 44.27,115.11 39.45,119.94 35.71,119.94 33.73,121.92 33.01,121.92 32.84,122.09 32.84,122.42 32.67,122.59 32.42,122.59 32.25,122.42 32.25,122.09 32.08,121.92 31.83,121.92 31.66,122.09 31.66,122.42 31.49,122.59 31.24,122.59 31.07,122.42 31.07,122.09 30.9,121.92 30.65,121.92 30.48,122.09 30.48,122.42 30.31,122.59 30.06,122.59 29.89,122.42 29.89,122.09 29.72,121.92 29.47,121.92 29.3,122.09 29.3,122.42 29.13,122.59 28.89,122.59 28.71,122.42 28.71,122.09 28.54,121.92 26.91,121.92 26.73,122.09 26.73,123.13 26.56,123.31 26.32,123.31 26.15,123.13 26.15,122.09 25.97,121.92 25.73,121.92 25.56,122.09 25.56,123.13 25.38,123.31 25.14,123.31 24.97,123.13 24.97,122.09 24.79,121.92 24.55,121.92 24.38,122.09 24.38,123.13 24.21,123.31 23.96,123.31 23.79,123.13 23.79,122.09 23.62,121.92 23.32,121.92 22.73,122.5 21.37,122.5 21.2,122.68 21.2,123.13 21.03,123.31 20.78,123.31 20.61,123.13 20.61,122.68 20.44,122.5 20.12,122.5 18.14,124.49 v1(16.79,124.49)
MCASP2_AXR1_R: length 8.4
  TOP w0.147: U136.K16 v1(64.5,89.65)
  BOTTOM w0.132: v1(64.5,89.65) 64.09,90.06 64.09,91.79 63.45,92.43
  BOTTOM w0.147: 63.45,92.43 63.14,92.74 63.14,95.74 63.65,96.24 R5661.1
MCASP2_AXR2: length 84.2
  TOP w0.147: v1(9.42,130.84) 9.42,129.52 9.63,129.31 9.63,127.89 9.38,127.64 J13.28
  BOTTOM w0.147: R5662.2 67.39,103.76 65.25,105.89 65.25,108.94 62.61,111.58 62.61,112.8 60.25,115.16 59.87,115.16 57.45,117.58 48.16,117.58 47.75,117.98 45.21,117.98 40.51,122.68 38.79,122.68 35.86,125.6 34.01,125.6 33.11,126.51 19.29,126.51 19.02,126.77 17.94,126.77 15.6,129.11 15.6,129.51 14.81,130.3 13.94,130.3 12.5,131.75 10.34,131.75 v1(9.42,130.84)
MCASP2_AXR2_R: length 6.9
  TOP w0.147: U136.L18 v1(66.1,91.26)
  BOTTOM w0.147: R5662.1 67.39,96.09 65.79,94.49 65.79,93.22 65.63,93.07 65.63,91.92 65.85,91.71 65.85,91.5 v1(66.1,91.26)
MCASP2_AXR3: length 82.5
  TOP w0.147: v1(8.84,128.17) 8.57,128.44 J13.30
  BOTTOM w0.147: R5663.2 64.25,103.72 62.97,105 62.97,108.05 60.33,110.69 60.33,111.91 59.36,112.88 57.91,112.88 56.92,113.87 48.36,113.87 46.66,115.57 44.45,115.57 39.62,120.4 35.97,120.4 33.1,123.27 28.27,123.27 27.79,123.75 19.51,123.75 18.31,124.94 11.25,124.94 10.92,125.27 10.92,125.48 12.31,126.87 12.31,127.11 12.14,127.28 11.89,127.28 10.56,125.95 10.24,125.95 10.07,126.13 10.07,126.37 11.42,127.72 11.42,127.93 11.21,128.14 11,128.14 9.65,126.79 9.41,126.79 8.84,127.36 v1(8.84,128.17)
MCASP2_AXR3_R: length 8.6
  TOP w0.147: U136.K18 v1(64.5,91.26)
  BOTTOM w0.147: R5663.1 64.25,96.15 63.55,95.45 63.55,92.81 64.39,91.97 64.39,91.36 v1(64.5,91.26)
MCASP2_AXR4: length 82.3
  TOP w0.147: J13.32 8.73,129.24 v1(8.99,128.98)
  BOTTOM w0.147: R5664.2 64.9,103.71 63.42,105.18 63.42,108.23 60.78,110.87 60.78,112.09 59.54,113.33 59.16,113.33 57.43,115.06 47.8,115.06 46.84,116.03 44.63,116.03 39.8,120.85 36.88,120.85 34.01,123.72 28.45,123.72 27.97,124.21 19.68,124.21 18.49,125.4 14.43,125.4 13.75,126.08 13.75,126.84 11.61,128.98 9.84,128.98 8.51,130.31 8.51,131.04 8.36,131.19 8.12,131.19 7.98,131.04 7.98,129.57 8.56,128.98 v1(8.99,128.98)
MCASP2_AXR4_R: length 8.9
  TOP w0.147: U136.L16 v1(66.1,89.65)
  BOTTOM w0.132: v1(66.1,89.65) 64.9,90.85 64.9,91.44 64.67,91.67 64.67,92.13 64.08,92.71
  BOTTOM w0.147: 64.08,92.71 63.98,92.81 63.98,95.33 64.9,96.24 R5664.1
MCASP2_AXR5: length 80.8
  TOP w0.147: v1(8.97,131.67) 8.97,131.32 8.97,131.32 8.97,130.25 8.76,130.04 J13.34
  BOTTOM w0.147: R5665.2 66.74,103.77 64.8,105.71 64.8,108.76 62.15,111.4 62.15,112.62 60.07,114.71 59.69,114.71 57.28,117.12 47.65,117.12 47.37,117.4 45.16,117.4 40.34,122.22 38.61,122.22 35.69,125.15 33.83,125.15 32.97,126.01 19.15,126.01 18.85,126.31 17.75,126.31 15.95,128.12 15.16,128.12 14.41,128.87 14.12,128.87 13.89,128.64 13.65,128.64 13.48,128.81 13.48,129.06 13.75,129.33 13.75,129.53 13.44,129.84 9.6,129.84 8.97,130.48 v1(8.97,131.67)
MCASP2_AXR5_R: length 10.3
  TOP w0.147: U136.M17 v1(66.9,90.45)
  BOTTOM w0.132: 66.5,90.85 65.94,90.85 65.51,91.29 65.51,91.59 65.3,91.8 65.3,93.04
  BOTTOM w0.147: 65.3,93.04 65.3,93.24 65.42,93.36 65.42,94.96 66.74,96.28 R5665.1 ; 66.5,90.85 v1(66.9,90.45)
MCASP3_ACLKR: length 111.1
  TOP w0.147: v1(62.31,114.55) 61.62,113.87 61.62,112.73 62.08,112.27 62.08,110.24 62.43,109.88 62.43,103.78 61.67,103.02 61.67,102.62 62.05,102.23 62.05,101.45 61.26,100.66 61.26,98.53 60.19,97.45 R5683.1 ; J13.78 8.82,151.64 9.47,152.3 v1(9.47,153.42)
  BOTTOM w0.147: v1(62.31,114.55) 62.31,118.26 60.88,119.68 57.23,119.68 56.49,118.95 48.69,118.95 48.29,119.35 47.09,119.35 44.42,122.02 44.42,125.5 43.94,125.98 43.33,125.98 42.34,126.97 34.75,126.97 33.58,128.14 19.2,128.14 17.04,130.3 17.04,131.72 16.51,132.26 15.44,132.26 12.22,135.48 12.22,141.6 12.39,141.77 12.91,141.77 13.08,141.94 13.08,142.19 12.91,142.36 12.39,142.36 12.22,142.53 12.22,142.78 12.39,142.95 12.81,142.95 12.95,143.1 12.95,143.39 12.81,143.54 12.39,143.54 12.22,143.71 12.22,145.44 12.93,146.15 12.93,151.84 11.63,153.14 9.75,153.14 v1(9.47,153.42)
MCASP3_ACLKX: length 108.4
  TOP w0.147: J13.77 11.35,151.64 v1(11.07,151.92)
  BOTTOM w0.147: R5677.1 55.94,99.63 51.23,104.34 39.8,104.34 37.26,101.8 33.1,101.8 31.75,103.15 22.62,103.15 6.35,119.42 6.35,133.88 7.14,134.67 7.14,140.49 4.72,142.9 4.72,149.48 5.36,150.11 6.48,150.11 6.65,150.29 6.65,151.62 6.82,151.79 7.07,151.79 7.24,151.62 7.24,150.29 7.41,150.11 7.66,150.11 7.83,150.29 7.83,151.62 8,151.79 8.25,151.79 8.42,151.62 8.42,150.29 8.59,150.11 8.97,150.11 10.77,151.92 v1(11.07,151.92)
MCASP3_AFSR: length 108.4
  TOP w0.147: v1(8.96,152.44) J13.80 ; R5682.2 57.64,99.62 60.12,102.11 60.12,104.14 61.52,105.54 61.52,109.52 61.16,109.88 61.16,111.84 60.02,112.98 60.02,118.69 v1(60.53,119.2)
  BOTTOM w0.147: v1(8.96,152.44) 11.41,152.44 12.27,151.59 12.27,146.51 11.15,145.39 11.15,133.88 13.84,131.19 15.09,131.19 15.7,131.8 16.31,131.8 16.59,131.53 16.59,130.12 19.02,127.69 33.4,127.69 34.57,126.52 42.11,126.52 43.1,125.53 43.76,125.53 43.94,125.35 43.94,121.87 46.91,118.9 48.11,118.9 48.51,118.49 57.81,118.49 58.18,118.13 59.45,118.13 v1(60.53,119.2)
MCASP3_AFSX: length 110.3
  TOP w0.147: R5676.2 64.09,100.77 64.26,100.94 64.26,110.79 v1(65.02,111.56) ; v1(14.91,152.78) 14.57,152.44 J13.79
  BOTTOM w0.147: v1(14.91,152.78) 14.91,151.92 14.2,151.21 14.2,149.71 14.78,149.12 19.63,149.12 20.57,148.18 20.57,145.19 13.7,138.31 13.7,135.27 15.8,133.17 16.87,133.17 17.96,132.08 17.96,130.66 19.56,129.06 34.11,129.06 35.28,127.89 42.7,127.89 43.69,126.9 44.3,126.9 45.34,125.86 45.34,122.78 47.78,120.35 48.64,120.35 49.12,119.86 55.98,119.86 56.72,120.6 61.32,120.6 63.6,118.31 63.6,111.99 64.03,111.56 v1(65.02,111.56)
MCASP3_AXR0: length 107.3
  TOP w0.147: J13.67 14.83,147.64 v1(15.24,148.06) ; v1(63.04,114.33) 65.07,114.33 65.79,113.61 65.79,112.8 65.25,112.27 64.3,112.27 63.8,111.77 63.8,101.3 63.44,100.93 R5672.2
  BOTTOM w0.147: v1(15.24,148.06) 15.67,148.49 16.27,148.49 16.44,148.32 16.44,147.57 16.61,147.4 16.86,147.4 17.03,147.57 17.03,148.32 17.2,148.49 19.05,148.49 19.81,147.73 19.81,145.06 12.78,138.02 12.78,135.56 15.62,132.72 16.69,132.72 17.5,131.9 17.5,130.48 19.38,128.6 33.93,128.6 35.1,127.43 42.52,127.43 43.51,126.44 44.12,126.44 44.88,125.68 44.88,122.2 47.27,119.81 48.46,119.81 48.87,119.41 56.16,119.41 56.9,120.14 61.14,120.14 63.04,118.24 v1(63.04,114.33)
MCASP3_AXR1: length 104.3
  TOP w0.147: v1(11.25,148.21) 11.49,148.44 J13.69
  BOTTOM w0.147: R5673.2 59.32,100.16 58.98,100.51 57.15,100.51 54.89,102.77 53.59,102.77 51.54,104.83 38.77,104.83 36.29,102.34 33.24,102.34 32.72,102.87 32.72,103.92 31.73,104.9 21.81,104.9 6.96,119.75 6.96,133.55 7.59,134.19 7.59,141.71 6.25,143.05 6.25,147.93 7.62,149.3 9.07,149.3 10.85,151.08 11.46,151.08 11.81,150.72 11.81,148.77 v1(11.25,148.21)
MCASP3_AXR2: length 107.2
  TOP w0.147: v1(15.77,149.73) 15.28,149.24 J13.71 ; v1(65.68,111.89) 65.68,111.35 64.74,110.41 R5674.2
  BOTTOM w0.147: v1(15.77,149.73) 15.77,151.54 16.08,151.84 18.41,151.84 21.44,148.82 21.44,145.29 14.71,138.56 14.71,135.08 15.47,134.32 17.6,134.32 18.67,133.25 18.67,130.96 19.63,130 34.57,130 35.97,128.6 43.94,128.6 46.15,126.39 46.15,124.94 50.27,120.83 52.93,120.83 53.31,121.21 61.44,121.21 64.06,118.59 64.06,112.57 64.59,112.04 65.25,112.04 65.41,111.89 v1(65.68,111.89)
MCASP3_AXR3: length 107.1
  TOP w0.147: J13.73 11.28,150.04 11.05,150.27 v1(11.05,150.62)
  BOTTOM w0.147: v1(11.05,150.62) 11.05,149.17 10.19,148.31 9.95,148.31 9.69,148.57 9.45,148.57 9.28,148.39 9.28,148.15 9.53,147.9 9.53,147.65 9.36,147.48 9.11,147.48 8.86,147.73 8.62,147.73 8.44,147.56 8.44,147.32 8.7,147.06 8.7,146.82 8.52,146.65 8.28,146.65 8.03,146.9 7.78,146.9 7.61,146.73 7.61,146.48 7.86,146.23 7.86,145.99 7.44,145.57 7.44,143.69 8.05,143.08 8.05,133.88 7.44,133.27 7.44,125.04 8.81,123.67 17.93,123.67 21.77,119.84 22.5,119.84 22.67,120.01 22.67,120.35 22.84,120.52 23.09,120.52 23.26,120.35 23.26,120.01 23.43,119.84 23.68,119.84 23.85,120.01 23.85,120.35 24.02,120.52 24.27,120.52 24.44,120.35 24.44,120.01 24.61,119.84 24.86,119.84 25.03,120.01 25.03,120.35 25.2,120.52 25.45,120.52 25.62,120.35 25.62,120.01 25.79,119.84 26.03,119.84 26.21,120.01 26.21,120.35 26.38,120.52 26.62,120.52 26.8,120.35 26.8,120.01 26.97,119.84 27.21,119.84 27.39,120.01 27.39,120.35 27.56,120.52 27.8,120.52 27.98,120.35 27.98,120.01 28.15,119.84 28.39,119.84 28.56,120.01 28.56,120.5 28.71,120.65 28.96,120.65 29.13,120.48 29.13,120.04 29.33,119.84 33.15,119.84 35.1,117.88 39.57,117.88 42.06,115.39 42.06,112.5 43.79,110.77 49.12,110.77 56.01,103.89 56.72,103.89 57.12,103.48 57.56,103.48 58.47,102.57 61.5,102.57 61.77,102.29 R5675.2
MCASP4_ACLKR: length 32.7
  TOP w0.147: J12.78 118.6,114.78 118.39,114.99 118.39,122.1 v1(118.07,122.42)
  BOTTOM w0.147: v1(118.07,122.42) 113.27,122.42 107.16,116.31 107.16,115.19 106.04,114.07 106.04,113.82 106.54,113.32 106.54,113.07 106.37,112.9 106.13,112.9 105.62,113.4 105.38,113.4 105.13,113.16 103.28,113.16 102.75,112.63 U3072.54
MCASP4_ACLKR_FET: length 69
  TOP w0.147: v1(68.48,107.14) 68.02,106.68 68.02,106.15 67.83,105.95 67.83,98.67 67.83,98.66 R5651.1
  BOTTOM w0.147: RA6.6 68.22,107.39 v1(68.48,107.14) 68.48,106.05 68.17,105.74 66.67,105.74 66.17,106.25 66.17,110.26 66.34,110.44 66.34,111.91 65.74,112.52 64.85,112.52 64.52,112.85 64.52,115.09 65.4,115.98 67.67,115.98 67.79,115.85 83.92,115.85 89.99,109.78 94.31,109.78 97.71,106.38 101.29,106.38 103.25,104.41 U3072.2
MCASP4_ACLKR_HDR: length 19
  BOTTOM w0.147: J28.3 98.41,125.79 98.41,127.82 99.14,128.55 100.38,128.55 101.17,127.76 101.17,126.8 102.17,125.79 104.23,125.79 104.85,125.17 104.85,124.57 101.22,120.94 U2345.20
MCASP4_ACLKR_LT: length 3.7
  BOTTOM w0.147: U3072.53 102.25,112.15 101.22,113.18 U2345.1
MCASP4_ACLKR_R: length 7.5
  TOP w0.132: 69.29,93.32 69.29,91.25 U136.R18
  TOP w0.147: R5651.2 67.83,96.03 68.07,95.78 68.55,95.78 69.7,94.63 69.7,93.73 69.29,93.32
MCASP4_ACLKX: length 32.2
  TOP w0.147: J12.77 112.62,114.78 112.09,114.25 112.09,112.62 112.32,112.39 v1(113.13,112.39)
  BOTTOM w0.147: v1(113.13,112.39) 113.94,112.39 114.71,111.63 114.71,109.12 112.62,107.04 98.09,107.04 95.25,109.88 U3072.39
MCASP4_ACLKX_FET: length 69.1
  TOP w0.147: v1(65.05,113.69) 64.48,113.69 62.63,111.84 62.63,110.32 62.89,110.06 62.89,101.65 62.38,101.14 62.38,100.62 62.21,100.45 62.03,100.45 61.85,100.28 61.85,100.03 62.03,99.86 62.21,99.86 62.38,99.69 62.38,98.93 61.17,97.72 61.17,96.95 61.34,96.77 62.06,96.77 62.23,96.6 62.23,96.36 62.06,96.18 61.34,96.18 61.17,96.01 R5653.1
  BOTTOM w0.147: U3072.18 95.25,104.9 94.72,105.44 93.1,105.44 92.93,105.26 92.93,104.69 92.76,104.51 92.51,104.51 92.34,104.69 92.34,105.26 92.17,105.44 91.93,105.44 91.75,105.26 91.75,104.69 91.58,104.51 91.34,104.51 91.16,104.69 91.16,105.26 90.99,105.44 90.75,105.44 90.57,105.26 90.57,104.69 90.4,104.51 90.16,104.51 89.98,104.69 89.98,105.26 89.81,105.44 89.08,105.44 81.38,113.13 69.25,113.13 69.05,113.33 68.73,113.33 67.98,112.58 67.74,112.58 67.57,112.75 67.57,113.02 68.35,113.81 68.35,114.01 68.21,114.16 68,114.16 67.16,113.32 66.92,113.32 66.74,113.5 66.74,113.74 67.56,114.55 67.56,114.82 67.3,115.08 66.51,115.08 66.25,114.82 66.25,113.9 66.04,113.69 v1(65.05,113.69)
MCASP4_ACLKX_HDR: length 5.2
  BOTTOM w0.147: J28.1 96.09,123.32 96.09,121 96.02,120.94 U2345.12
MCASP4_ACLKX_LT: length 4.5
  BOTTOM w0.147: U2345.9 96.02,113.22 95.58,112.78 94.72,112.78 94.25,112.31 U3072.37
MCASP4_ACLKX_R: length 5.3
  TOP w0.132: 61.3,93.04 61.3,91.49 61.7,91.09 U136.F18
  TOP w0.147: R5683.2 60.19,94.68 61.3,93.56 61.3,93.04
MCASP4_AFSR: length 32.4
  TOP w0.147: v1(117.86,121.16) 117.86,114.53 118.41,113.98 J12.80
  BOTTOM w0.147: U3072.52 101.75,110.06 101.96,109.86 104.55,109.86 108,113.31 108,116.05 113.11,121.16 v1(117.86,121.16)
MCASP4_AFSR_FET: length 68.8
  TOP w0.147: R5652.2 67.23,105.53 67.39,105.69 v1(67.39,106.3)
  BOTTOM w0.147: U3072.4 102.25,98.59 100.58,96.93 87.86,96.93 84.48,100.3 84.48,102.13 84.65,102.3 85.2,102.3 85.37,102.47 85.37,102.72 85.2,102.89 84.65,102.89 84.48,103.06 84.48,103.31 84.65,103.48 85.2,103.48 85.37,103.65 85.37,103.9 85.2,104.07 84.65,104.07 84.48,104.24 84.48,104.49 84.65,104.66 85.2,104.66 85.37,104.83 85.37,105.08 85.2,105.25 84.65,105.25 84.48,105.42 84.48,107.09 80.19,111.38 71.63,111.38 70.46,110.21 68.86,110.21 68.3,110.77 67.33,110.77 66.62,110.07 66.62,106.53 66.85,106.3 v1(67.39,106.3) 67.82,106.74 RA6.7
MCASP4_AFSR_HDR: length 6.8
  BOTTOM w0.147: U2345.18 99.92,120.94 100.31,121.33 101.1,121.33 103.16,123.39 103.16,123.87 J28.7
MCASP4_AFSR_LT: length 3.8
  BOTTOM w0.147: U3072.51 101.25,112.03 99.92,113.36 U2345.3
MCASP4_AFSR_R: length 8.8
  TOP w0.147: U136.R19 68.9,93.42 69.36,93.89 69.36,94.47 68.69,95.15 68.21,95.15 67.23,96.13 R5652.1
MCASP4_AFSX: length 32.6
  TOP w0.147: J12.79 112.81,113.98 112.55,113.72 v1(112.55,113.23)
  BOTTOM w0.147: U3072.41 96.25,109.67 98.4,107.52 112.34,107.52 113.67,108.84 113.67,110.95 112.67,111.94 112.67,112.6 112.93,112.85 114.48,112.85 114.81,113.18 114.81,113.69 114.5,114 112.69,114 112.55,113.85 v1(112.55,113.23)
MCASP4_AFSX_FET: length 67.4
  TOP w0.147: v1(65.13,114.83) 63.45,114.83 63.07,115.21 61.72,115.21 61.16,114.66 61.16,112.47 61.62,112.01 61.62,110.06 61.98,109.7 61.98,105.36 60.81,104.19 60.81,101.31 60.64,101.13 60.12,101.13 59.94,100.96 59.94,100.72 60.12,100.55 60.64,100.55 60.81,100.37 60.81,99.09 60.58,98.86 60.37,98.86 59.83,99.41 59.58,99.41 59.41,99.24 59.41,98.99 59.91,98.49 59.91,98.19 59.74,98.02 59.52,98.02 59.09,98.45 58.85,98.45 58.68,98.28 58.68,98.03 59.08,97.63 59.08,97.36 58.62,96.89 R5655.2
  BOTTOM w0.147: U3072.15 96.75,104.7 95.55,105.89 89.26,105.89 81.56,113.59 69.42,113.59 67.48,115.53 65.82,115.53 v1(65.13,114.83)
MCASP4_AFSX_HDR: length 6.4
  BOTTOM w0.147: J28.5 99.02,123.87 98.34,123.87 96.67,122.2 U2345.13
MCASP4_AFSX_LT: length 3.6
  BOTTOM w0.147: U3072.40 95.75,112.08 96.67,113 U2345.8
MCASP4_AFSX_R: length 8.1
  TOP w0.132: U136.F17 61.3,90.45 61.3,91.01 61.05,91.26 60.73,91.26 60.5,91.49 60.5,92 59.46,93.04 58.19,93.04
  TOP w0.147: 58.19,93.04 57.64,93.6 R5655.1
MCASP4_AXR0: length 32.3
  TOP w0.147: J12.67 112.25,118.78 v1(111.4,117.93)
  BOTTOM w0.147: v1(111.4,117.93) 109.86,116.38 109.86,115.57 109.68,115.4 109.16,115.4 108.99,115.23 108.99,114.98 109.16,114.81 109.68,114.81 109.86,114.64 109.86,114.39 109.68,114.22 109.16,114.22 108.99,114.05 108.99,113.8 109.16,113.63 109.68,113.63 109.86,113.46 109.86,113.22 109.68,113.04 109.16,113.04 108.99,112.87 108.99,112.63 109.16,112.45 109.68,112.45 109.86,112.28 109.86,111.63 109.28,111.06 109.04,111.06 108.33,111.77 108.09,111.77 107.91,111.6 107.91,111.35 108.62,110.64 108.62,110.4 108.45,110.23 108.21,110.23 107.5,110.94 107.25,110.94 107.08,110.76 107.08,110.52 107.79,109.81 107.79,109.57 107.59,109.37 106.71,109.37 106.54,109.54 106.54,110.42 106.37,110.59 106.12,110.59 105.95,110.42 105.95,109.54 105.78,109.37 101.02,109.37 100.75,109.64 U3072.50
MCASP4_AXR0_FET: length 69.7
  TOP w0.147: v1(65.05,112.98) 64.39,112.98 63.07,111.66 63.07,110.52 63.35,110.24 63.35,101.47 62.85,100.97 R5654.2
  BOTTOM w0.147: U3072.6 101.25,99.6 100.63,98.98 88.06,98.98 86.08,100.97 86.08,102.41 86.25,102.58 86.52,102.58 86.69,102.75 86.69,103 86.52,103.17 86.25,103.17 86.08,103.34 86.08,103.59 86.25,103.76 86.52,103.76 86.69,103.93 86.69,104.18 86.52,104.35 86.25,104.35 86.08,104.52 86.08,104.77 86.25,104.94 86.52,104.94 86.69,105.11 86.69,105.36 86.52,105.53 86.25,105.53 86.08,105.7 86.08,106.58 80.49,112.17 71.63,112.17 70.13,110.67 69.21,110.67 68.58,111.3 67.79,111.3 66.12,112.98 v1(65.05,112.98)
MCASP4_AXR0_HDR: length 16.4
  BOTTOM w0.147: U2345.17 99.27,118.76 99.77,118.26 101.19,118.26 102.23,119.3 102.23,120.4 105.51,123.67 105.51,125.68 103.99,127.2 J28.8
MCASP4_AXR0_LT: length 3.4
  BOTTOM w0.147: U3072.48 99.75,112.06 99.27,112.54 U2345.4
MCASP4_AXR0_R: length 5.8
  TOP w0.147: R5654.1 62.85,95.74 61.7,94.59 U136.F19
MCASP4_AXR3: length 32.5
  TOP w0.147: J12.69 v1(115.9,117.98)
  BOTTOM w0.147: v1(115.9,117.98) 116.59,117.98 116.87,117.7 116.87,116.34 116.59,116.05 113.06,116.05 112.01,115.01 112.01,109.47 110.49,107.95 98.81,107.95 97.25,109.5 U3072.43
MCASP4_AXR3_FET: length 68.9
  TOP w0.147: R5658.2 70.33,105.13 72.85,107.65 72.85,109.3 72.47,109.68 72.47,111.3 v1(69.72,114.05)
  BOTTOM w0.147: U3072.13 97.75,105.07 94.89,107.92 94.04,107.92 93.87,107.75 93.87,106.68 93.69,106.51 93.45,106.51 93.28,106.68 93.28,107.75 93.1,107.92 92.86,107.92 92.69,107.75 92.69,106.68 92.51,106.51 92.27,106.51 92.1,106.68 92.1,107.75 91.93,107.92 91.68,107.92 91.51,107.75 91.51,106.68 91.34,106.51 91.09,106.51 90.92,106.68 90.92,107.75 90.75,107.92 90.5,107.92 90.33,107.75 90.33,106.68 90.16,106.51 89.91,106.51 89.74,106.68 89.74,107.75 89.57,107.92 89.13,107.92 88.35,108.71 88.1,108.71 87.76,108.37 87.52,108.37 87.35,108.54 87.35,108.78 87.69,109.12 87.69,109.37 87.51,109.54 87.27,109.54 86.93,109.2 86.68,109.2 86.51,109.37 86.51,109.62 86.85,109.96 86.85,110.2 86.68,110.37 86.44,110.37 86.1,110.03 85.85,110.03 85.68,110.21 85.68,110.45 86.02,110.79 86.02,111.03 85.85,111.21 85.6,111.21 85.26,110.87 85.02,110.87 84.85,111.04 84.85,111.28 85.19,111.62 85.19,111.87 85.01,112.04 84.77,112.04 84.43,111.7 84.18,111.7 84.01,111.87 84.01,112.12 84.35,112.46 84.35,112.7 84.18,112.87 83.94,112.87 83.6,112.53 83.35,112.53 83.18,112.71 83.18,112.95 83.52,113.29 83.52,113.53 83.01,114.05 v1(69.72,114.05)
MCASP4_AXR3_LT: length 3.5
  BOTTOM w0.147: U3072.42 96.75,112.09 97.32,112.66 U2345.7
MCASP4_AXR3_MLB0_SIG_HDR: length 19.9
  BOTTOM w0.147: U2345.14 97.32,121.48 97.76,121.92 98.41,121.92 98.59,122.09 98.59,123.27 98.76,123.44 99,123.44 99.17,123.27 99.17,122.09 99.35,121.92 99.59,121.92 99.76,122.09 99.76,123.27 99.94,123.44 100.18,123.44 100.35,123.27 100.35,122.09 100.53,121.92 100.91,121.92 101.14,122.15 101.14,122.7 101.32,122.87 102.09,122.87 102.26,123.04 102.26,123.29 102.09,123.46 101.32,123.46 101.14,123.63 101.14,125.58 100.86,125.86 99.26,125.86 99.02,126.1 99.02,126.41 J28.6
MCASP4_AXR3_R: length 6.7
  TOP w0.132: U136.U18 70.89,91.25 70.89,91.82 71.12,92.05
  TOP w0.147: R5658.1 70.33,96.39 71.12,95.6 71.12,92.05
MCASP4_AXR4: length 32.2
  TOP w0.147: J12.71 112.23,117.18 v1(111.84,116.79)
  BOTTOM w0.147: U3072.47 99.25,109.26 99.59,108.92 107.9,108.92 110.36,111.38 110.36,116.18 113.03,118.85 114.78,118.85 115.06,118.57 115.06,117.07 114.78,116.79 v1(111.84,116.79)
MCASP4_AXR4_FET: length 67.7
  TOP w0.147: v1(69.7,111.12) 70.51,111.12 71.42,110.21 71.42,106.86 69.72,105.15 R5656.2
  BOTTOM w0.147: v1(69.7,111.12) 69.7,112.01 70.33,112.65 80.95,112.65 87.78,105.82 87.78,104.72 87.95,104.55 88.19,104.55 88.37,104.38 88.37,104.13 88.19,103.96 87.95,103.96 87.78,103.79 87.78,102.16 88.67,101.27 89.92,101.27 90.09,101.44 90.09,102.16 90.26,102.34 90.51,102.34 90.68,102.16 90.68,101.44 90.85,101.27 91.1,101.27 91.27,101.44 91.27,102.16 91.44,102.34 91.68,102.34 91.86,102.16 91.86,101.44 92.03,101.27 92.27,101.27 92.45,101.44 92.45,102.16 92.62,102.34 92.86,102.34 93.04,102.16 93.04,101.44 93.21,101.27 93.45,101.27 93.63,101.44 93.63,102.16 93.8,102.34 94.04,102.34 94.21,102.16 94.21,101.44 94.39,101.27 94.63,101.27 94.8,101.44 94.8,102.16 94.98,102.34 95.22,102.34 95.39,102.16 95.39,101.44 95.57,101.27 95.81,101.27 95.98,101.44 95.98,102.16 96.15,102.34 96.4,102.34 96.57,102.16 96.57,101.44 96.74,101.27 96.99,101.27 97.16,101.44 97.16,102.16 97.33,102.34 97.58,102.34 97.75,102.16 97.75,101.44 97.92,101.27 98.17,101.27 98.34,101.44 98.34,102.16 98.51,102.34 98.76,102.34 98.93,102.16 98.93,101.44 99.13,101.24 99.47,101.24 99.75,101.53 U3072.9
MCASP4_AXR4_LT: length 3.3
  BOTTOM w0.147: U3072.46 98.75,112.4 98.62,112.53 U2345.5
MCASP4_AXR4_MLB0_CLK_HDR: length 21
  BOTTOM w0.147: J28.4 95.94,128.55 94.49,128.55 92.76,126.82 92.76,123.56 93.75,122.57 93.75,118.54 94.21,118.08 97.87,118.08 98.62,118.84 U2345.16
MCASP4_AXR4_R: length 7.9
  TOP w0.147: U136.U19 70.5,92.16 70.75,92.42 70.75,95.34 69.72,96.37 R5656.1
MCASP4_AXR5: length 32.2
  TOP w0.147: J12.73 112.62,116.38 v1(112.06,115.82)
  BOTTOM w0.147: v1(112.06,115.82) 111.66,115.42 111.66,114.61 111.49,114.44 110.99,114.44 110.82,114.26 110.82,114.02 110.99,113.85 111.49,113.85 111.66,113.67 111.66,113.43 111.49,113.26 110.99,113.26 110.82,113.08 110.82,112.84 110.99,112.67 111.49,112.67 111.66,112.5 111.66,112.25 111.49,112.08 110.99,112.08 110.82,111.91 110.82,111.66 110.99,111.49 111.49,111.49 111.66,111.32 111.66,109.8 111.25,109.4 111.01,109.4 110.38,110.03 110.13,110.03 109.96,109.86 109.96,109.61 110.59,108.98 110.59,108.74 110.29,108.43 109.81,108.43 109.64,108.61 109.64,109.3 109.47,109.47 109.22,109.47 109.05,109.3 109.05,108.61 108.88,108.43 99.21,108.43 98.25,109.39 U3072.45
MCASP4_AXR5_FET: length 67.8
  TOP w0.147: R5657.2 70.97,103.84 73.08,105.94 73.08,106.58 73.86,107.37 73.86,109.37 74.35,109.86 74.35,112.6 72.39,114.55 v1(70.71,114.55)
  BOTTOM w0.147: v1(70.71,114.55) 70.71,115.21 70.86,115.36 71.16,115.36 71.39,115.13 71.39,114.74 71.58,114.54 71.83,114.54 71.98,114.69 71.98,115.21 72.12,115.36 72.34,115.36 72.56,115.13 72.56,114.84 72.74,114.67 72.98,114.67 73.15,114.84 73.15,115.21 73.3,115.36 73.52,115.36 73.74,115.13 73.74,114.84 73.92,114.67 74.16,114.67 74.33,114.84 74.33,115.21 74.48,115.36 74.7,115.36 74.92,115.13 74.92,114.84 75.09,114.67 75.34,114.67 75.51,114.84 75.51,115.21 75.66,115.36 75.88,115.36 76.1,115.13 76.1,114.84 76.27,114.67 76.52,114.67 76.69,114.84 76.69,115.21 76.84,115.36 77.06,115.36 77.28,115.13 77.28,114.84 77.45,114.67 77.7,114.67 77.87,114.84 77.87,115.21 78.02,115.36 78.23,115.36 78.46,115.13 78.46,114.84 78.63,114.67 78.87,114.67 79.05,114.84 79.05,115.21 79.19,115.36 79.41,115.36 79.64,115.13 79.64,114.84 79.81,114.67 80.05,114.67 80.23,114.84 80.23,115.21 80.37,115.36 80.59,115.36 80.81,115.13 80.81,114.84 80.99,114.67 81.23,114.67 81.4,114.84 81.4,115.21 81.55,115.36 81.77,115.36 81.99,115.13 81.99,114.84 82.17,114.67 82.41,114.67 82.58,114.84 82.58,115.21 82.73,115.36 83.25,115.36 83.74,114.86 83.74,114.57 83.55,114.38 83.55,114.13 83.72,113.96 83.96,113.96 84.16,114.15 84.4,114.15 84.57,113.98 84.57,113.73 84.38,113.54 84.38,113.3 84.55,113.12 84.8,113.12 85.02,113.34 85.28,113.34 85.46,113.17 85.46,112.95 85.21,112.71 85.21,112.46 85.39,112.29 85.63,112.29 85.82,112.48 86.07,112.48 86.24,112.31 86.24,112.07 86.05,111.87 86.05,111.63 86.22,111.46 86.46,111.46 86.66,111.65 86.9,111.65 87.07,111.48 87.07,111.23 86.88,111.04 86.88,110.8 87.05,110.62 87.3,110.62 87.49,110.82 87.73,110.82 87.91,110.64 87.91,110.4 87.71,110.21 87.71,109.96 87.89,109.79 88.13,109.79 88.32,109.98 88.57,109.98 90.09,108.46 95,108.46 98.75,104.7 U3072.11
MCASP4_AXR5_LT: length 3.3
  BOTTOM w0.147: U3072.44 97.75,112.33 97.97,112.55 U2345.6
MCASP4_AXR5_MLB0_DAT_HDR: length 19.8
  BOTTOM w0.147: J28.2 95.54,128 95.8,128 96.11,127.69 96.11,126.29 95.83,126.01 93.93,126.01 93.22,125.3 93.22,123.8 94.26,122.76 94.26,118.75 94.49,118.52 94.7,118.52 94.87,118.69 94.87,118.81 95.05,118.99 95.29,118.99 95.46,118.81 95.46,118.69 95.64,118.52 95.88,118.52 96.05,118.69 96.05,118.81 96.22,118.99 96.47,118.99 96.64,118.81 96.64,118.69 96.81,118.52 97.76,118.52 97.97,118.72 U2345.15
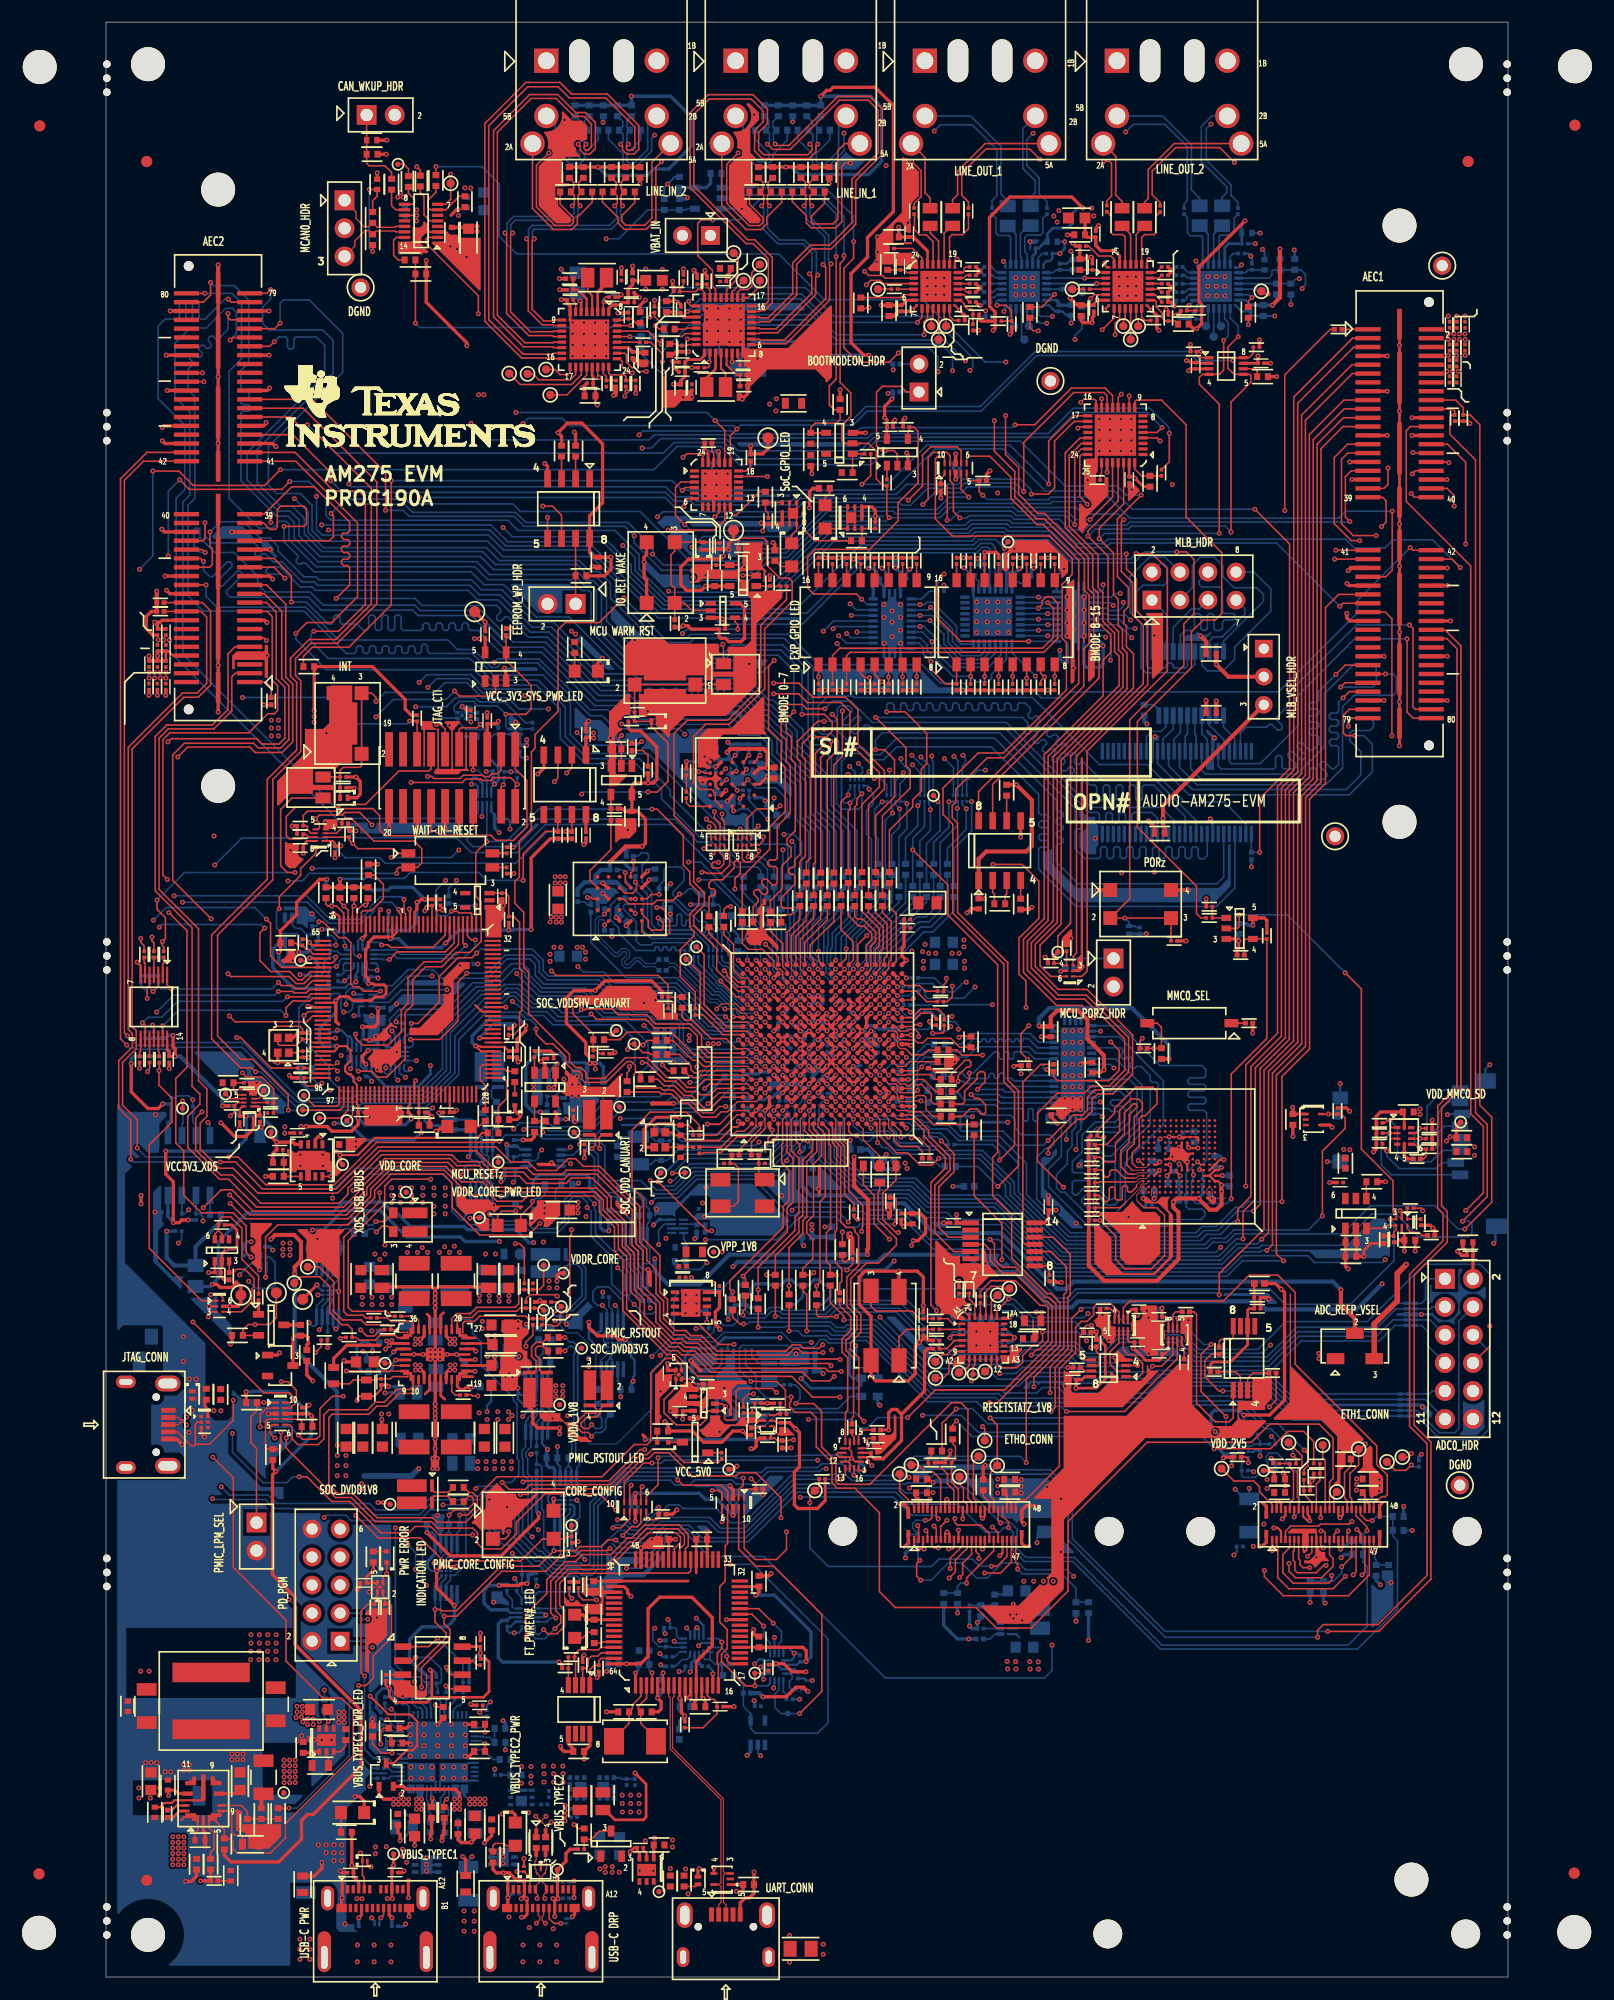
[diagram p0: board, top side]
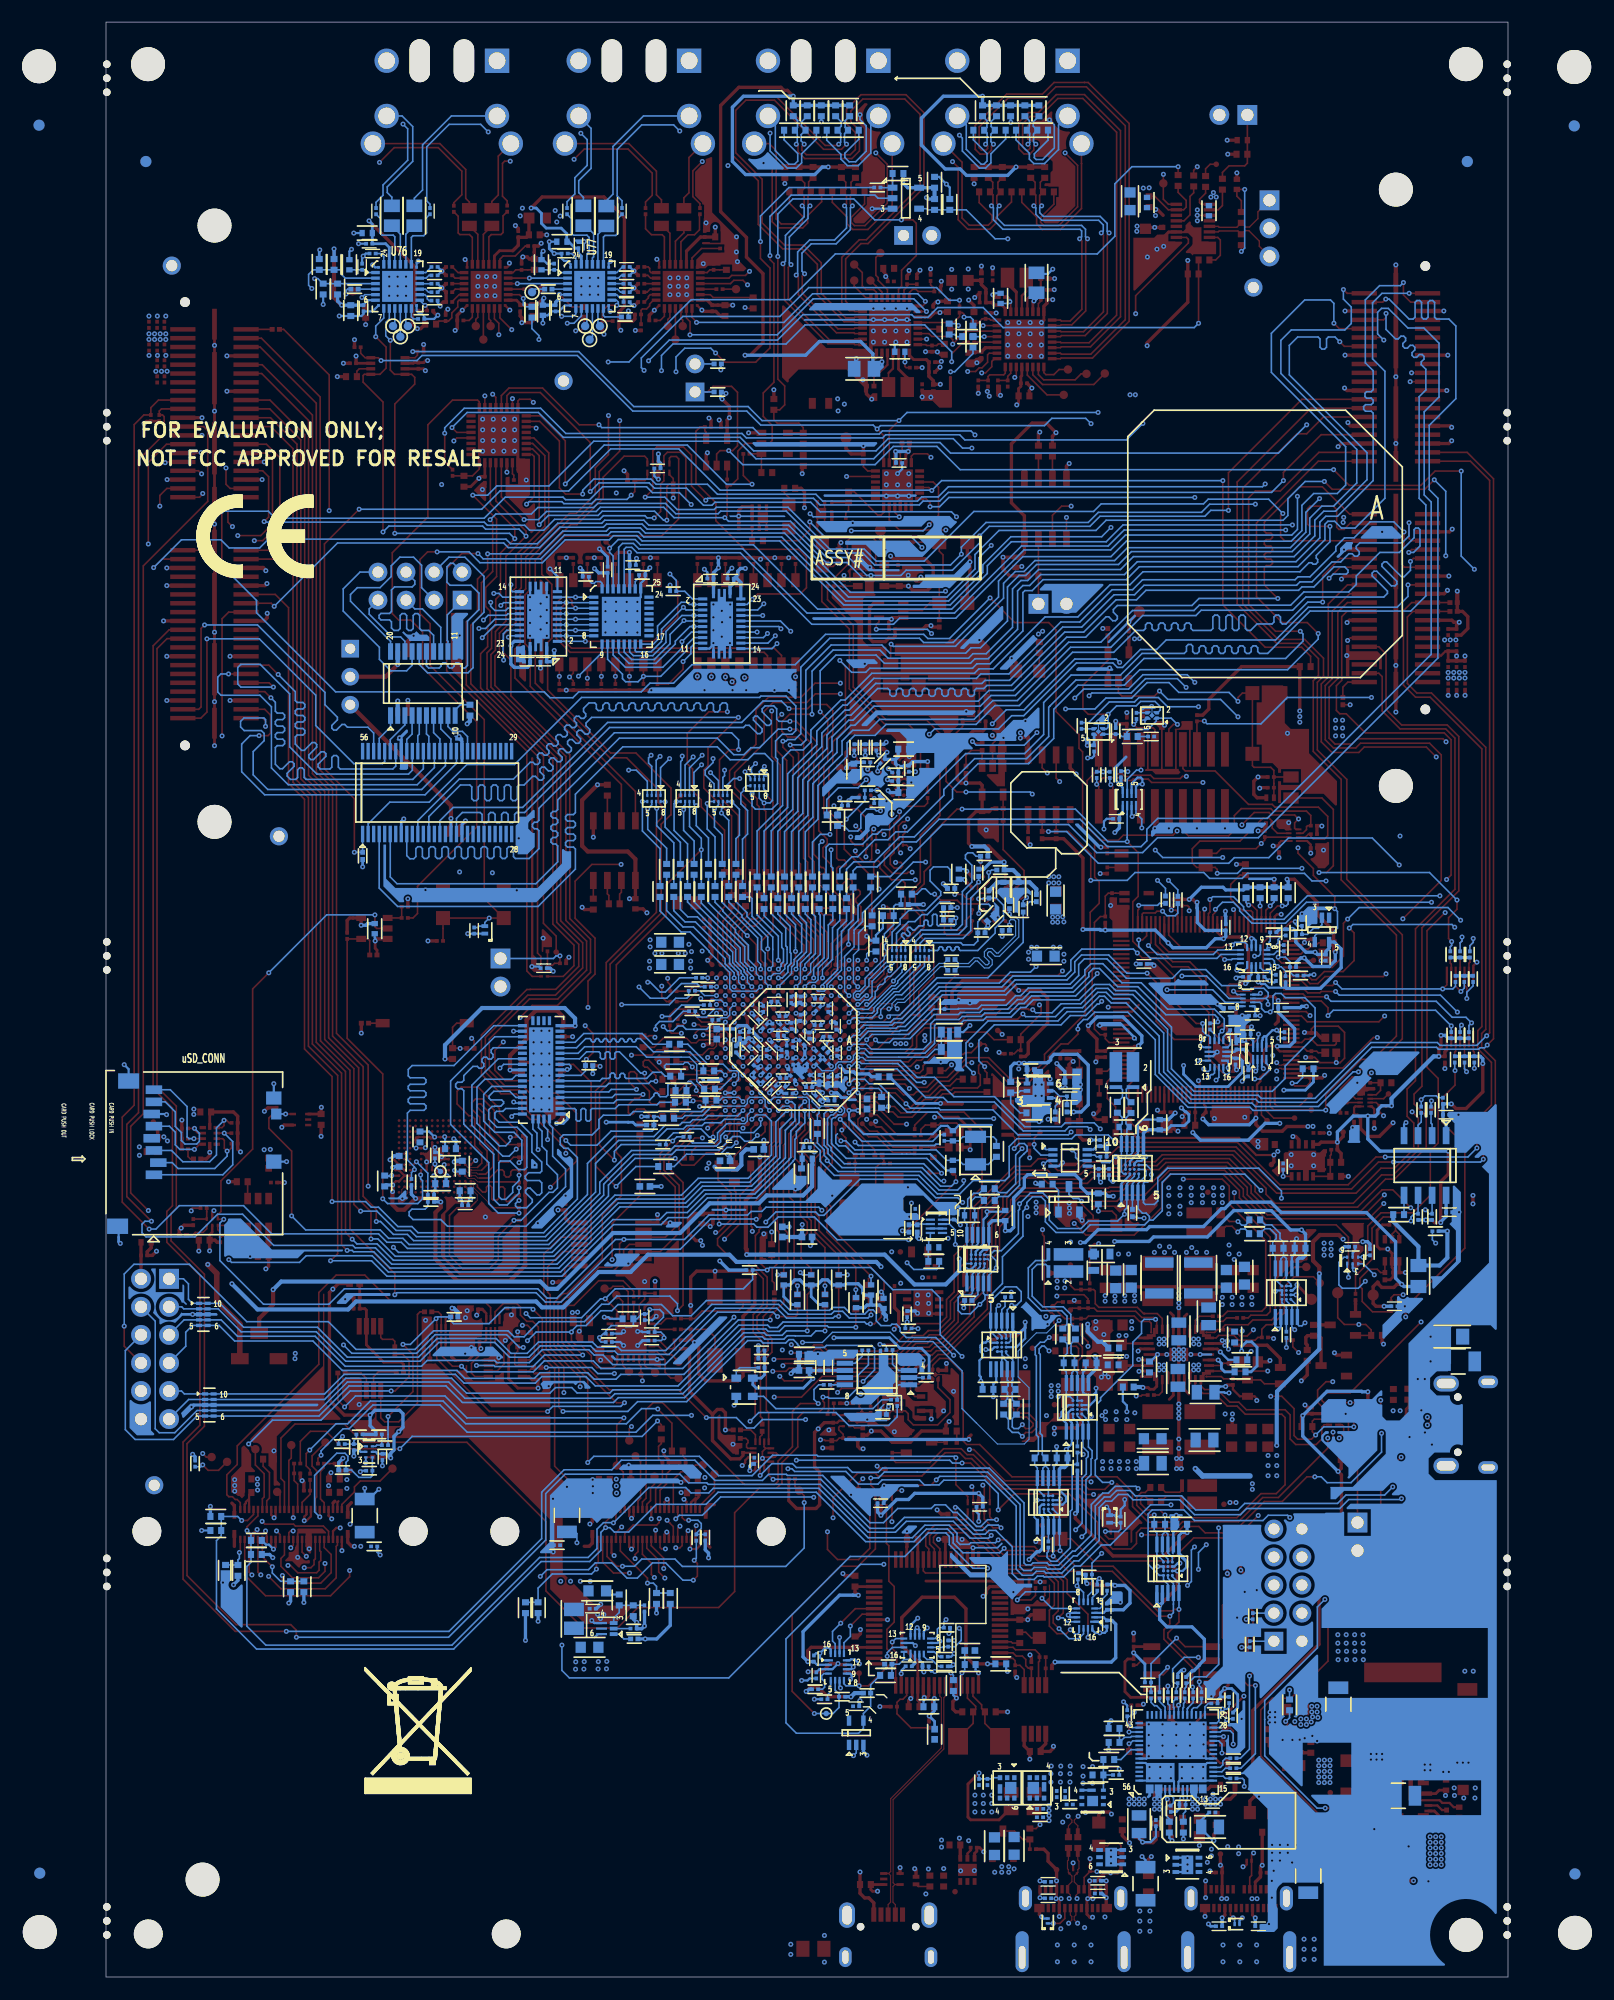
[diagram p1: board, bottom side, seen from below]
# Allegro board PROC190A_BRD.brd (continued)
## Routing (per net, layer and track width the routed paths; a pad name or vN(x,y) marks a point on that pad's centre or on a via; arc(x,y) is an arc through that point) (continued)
MCASP4_AXR5_R: length 7.8
  TOP w0.147: R5657.1 70.97,96.9 71.58,96.29 71.58,91.94 U136.V19
MCASP4_FET_SEL: length 141.6
  TOP w0.147: v1(104.07,132.89) 107.21,129.75 107.21,109.4 104.5,106.69 v1(104.5,101.84) ; v1(52.2,134.59) 52.46,134.86 U18.4 ; R5764.1 17.88,119.58 18.69,120.4 22,120.4 25.83,124.23 v1(25.83,135.48)
  BOTTOM w0.147: v1(104.07,132.89) 92.96,132.89 91.31,134.54 85.09,134.54 81.28,138.35 75.11,138.35 71.37,134.62 52.22,134.62 v1(52.2,134.59) 51.31,135.48 v1(25.83,135.48) ; U3072.1 R5681.1 v1(104.5,101.84)
MCASP_VSEL_HDR: length 6.9
  TOP w0.381: C3702.1 v1(100.57,118.83) 101.68,117.73 J29.2
  BOTTOM w0.381: U2345.19 v1(100.57,118.83)
MCU_GPIO0_1_INTN: length 172.3
  TOP w0.147: R108.1 96.32,137.19 v1(96.32,139.78) ; U136.C7 v1(58.9,82.46)
  L03_SIG1 w0.091: v1(33.08,140.67) 32.85,140.44 32.84,140.44 32.13,139.73 32.13,116.15 30.51,114.53 30.51,109.75 32.05,108.2 32.05,105.97 33.6,104.42 33.6,98.3 34.44,97.46 34.44,93.7 35.23,92.91 35.23,79.07 37.13,77.17 37.41,77.17 v1(37.85,76.73) 37.64,76.53 37.29,76.53 37.11,76.35 36.75,76.35 36.27,76.83 35.26,76.83 34.66,76.24 34.66,74.2 v1(36.9,71.97)
  BOTTOM w0.132: 55.87,82.21 58.65,82.21 v1(58.9,82.46)
  BOTTOM w0.147: v1(96.32,139.78) 96.32,140.27 94.55,142.04 87.63,142.04 85.35,139.75 69.4,139.75 68.99,139.35 56.66,139.35 56.38,139.63 49.66,139.63 49.2,139.17 34.57,139.17 v1(33.08,140.67) ; v1(37.85,76.73) 38.1,76.98 39.76,76.98 40.13,76.61 43.92,76.61 46.53,79.22 50.75,79.22 51.16,79.63 52.76,79.63 55.34,82.21 55.87,82.21 ; v1(36.9,71.97) 37.08,72.14 R547.2
MCU_INTN: length 91.1
  TOP w0.132: U136.M2 66.89,77.66 66.89,75.63 67.28,75.23
  TOP w0.147: 67.28,75.23 67.28,71.12 68.55,69.85 68.55,67.97 68.45,67.87 v1(68.45,67.51) ; v1(38.05,57.1) 38.05,57.51 38.67,58.13 R299.1 ; v1(61.14,41.58) 61.14,43.38 58.88,45.64 57.35,45.64 57.07,45.36 53.09,45.36 50.98,47.47 49.68,47.47 49.15,46.94 48.59,46.94 45.84,44.19 38.73,44.19 38.23,43.69 v1(37.54,43.69)
  L03_SIG1 w0.091: v1(61.14,41.58) 61.65,41.58 63.32,43.26 63.32,47.52 64.33,48.53 64.33,54.63 65.79,56.08 65.79,56.21 67.84,58.26 67.84,66.42 68.45,67.03 v1(68.45,67.51) ; v1(38.05,57.1) 36.58,57.1 35.61,56.13 35.61,53.93 33.25,51.57 33.25,45.82 35.38,43.69 v1(37.54,43.69)
MCU_OSC0_XI: length 4.7
  TOP w0.132: U136.A2 57.15,78.05 56.35,77.25
  TOP w0.147: 56.35,77.25 55.31,76.21 R249.2
MCU_OSC0_XO: length 5.6
  TOP w0.132: U136.B1 57.82,76.58 57.15,76.58
  TOP w0.147: 57.15,76.58 55.7,75.13 R254.2
MCU_PORZ: length 260.4
  TOP w0.147: v1(106.78,132.77) 106.78,145.06 110.9,149.18 R5775.1 ; R5776.1 v1(14.3,115.19) ; U136.E3 v1(60.5,78.46) ; v1(92.2,131.95) 91.97,131.72 91.97,127.25 92.99,126.24 92.99,123.34 93.95,122.38 93.95,117.09 87.38,110.52 87.38,95.4 86.22,94.25 TP49.1 v1(85.88,92.45) R242.2 86.38,91.78 86.56,91.59 U43.4 R238.1
  L03_SIG1 w0.091: v1(106.78,132.77) 105.92,133.63 93.88,133.63 v1(92.2,131.95) ; v1(49.52,128.83) 49.52,127.37 48.65,126.5 48.65,112.85 48.94,112.55 48.94,109.57 48.67,109.3 48.67,105.43 49.63,104.48 49.63,98.98 49.28,98.63 49.28,89.79 48.32,88.83 48.32,85.97 49.34,84.95 49.34,83.58 49,83.24 49,81.71 48.71,81.42 48.71,75.68 50.8,73.58 50.8,72.36 v1(51.1,72.06) ; v1(14.3,115.19) 22.45,123.34 22.45,132.92 v1(22.89,133.35)
  BOTTOM w0.132: v1(60.5,78.46) 60.74,78.46 61.13,78.06 61.31,78.06 61.65,77.72
  BOTTOM w0.147: 61.65,77.72 61.65,75.41 61.32,75.08 61.32,74.83 60.12,73.63 52.93,73.63 51.36,72.06 v1(51.1,72.06) ; v1(22.89,133.35) 27.03,133.35 27.76,132.61 37.11,132.61 38.03,131.69 47.28,131.69 49.52,129.46 v1(49.52,128.83) 50.5,127.85 57.38,127.85 58.46,128.93 61.59,128.93 65.38,132.72 71.32,132.72 71.55,132.49 75.39,132.49 76.32,133.42 82.45,133.42 82.83,133.05 87.88,133.05 88.47,132.46 91.69,132.46 v1(92.2,131.95) ; J32.1 86.47,92.22 86.23,92.45 v1(85.88,92.45)
MCU_RESETZ: length 53.8
  TOP w0.147: U136.D9 v1(59.7,84.06) ; v1(35.53,74.3) TP50.1
  L03_SIG1 w0.091: v1(37.21,90.86) 35.51,89.15 35.51,79.2 37.25,77.45 38.01,77.45 38.46,77.01 38.46,76.63 38.05,76.23 37.37,76.23 37.22,76.07 36.63,76.07 36.32,76.38 35.2,76.38 34.94,76.11 34.94,74.89 v1(35.53,74.3)
  BOTTOM w0.132: v1(59.7,84.06) 59.3,84.45 58.11,84.45 57.66,84 55.04,84
  BOTTOM w0.147: 55.04,84 52.96,84 52.3,84.66 52.3,86.31 51.92,86.69 49.73,86.69 49.45,86.97 47.7,86.97 47.4,87.27 45.16,87.27 44.3,88.14 43.84,88.14 43.15,88.82 39.17,88.82 37.21,90.78 v1(37.21,90.86) ; U98.7 37.43,74.42 37.28,74.27 R550.2 36.92,73.88 36.78,73.74 36.09,73.74 v1(35.53,74.3)
MCU_SAFETY_ERRORZ_1V8: length 68.3
  TOP w0.147: v1(37.08,66.4) 37.47,66.4 37.89,65.97 R281.1 ; v1(37.77,44.83) 37.87,44.93 45.57,44.93 48.39,47.75 v1(48.79,47.75)
  L03_SIG1 w0.091: v1(37.77,44.83) 37.77,48.13 39.34,49.71 39.34,53.24 42.82,56.72 42.82,60.02 42.04,60.81 40.24,60.81 40.11,60.68 38.63,60.68 37.08,62.23 v1(37.08,66.4) ; v1(48.79,47.75) 51.05,50.01 51.05,50.72 49.03,52.75 49.03,56.37 50.39,57.73 50.39,65.99 v1(50.06,66.32)
  BOTTOM w0.147: v1(50.06,66.32) 50.06,67.64 50.59,68.17 U3091.7
MCU_SAFETY_ERRORZ_1V8_BUF: length 26.3
  TOP w0.147: U136.F3 v1(61.3,78.46) ; v1(54.86,67.56) 54.46,67.56 v1(50.01,72.01) 50.01,72.55 TP54.1
  BOTTOM w0.147: R5842.1 54.74,67.44 v1(54.86,67.56) ; v1(61.3,78.46) 61.65,78.46 61.95,78.16 61.95,75.31 61.59,74.96 61.59,74.55 60.33,73.28 53.07,73.28 51.4,71.61 50.42,71.61 v1(50.01,72.01)
MIC1_BIAS: length 81.4
  TOP w0.254: U7.6 v1(56.71,146.25)
  TOP w0.305: v1(69.11,146.84) 68.64,146.84 67.49,147.99 67.49,154.23 68.98,155.72 68.98,157.5 71.32,159.84 71.32,169.44 69.67,171.09 65.86,171.09 65.58,170.81 65.27,170.81 v1(64.75,170.29) ; R7.1 R8.1 v1(61.57,163.88) R9.1 R10.1 C3.1
  BOTTOM w0.305: R408.1 R407.1 C329.1 R406.1 R405.1 v1(64.75,170.29) 69.26,170.29 70.26,169.29 70.26,164.39 69.06,163.19 62.79,163.19 62.11,163.88 v1(61.57,163.88) ; v1(69.11,146.84) 63.63,146.84 62.38,148.08 58.65,148.08 57.53,146.97 57.53,145.61 C379.1 56.9,145.61 56.71,145.8 v1(56.71,146.25)
  vias: v1(70.66,164.01)
MIC2_BIAS: length 45.9
  TOP w0.254: U8.6 43.04,151.65
  TOP w0.305: C2.1 R6.1 R5.1 v1(44.57,163.88) R4.1 R3.1 ; 43.04,151.65 v1(42.94,151.75)
  L03_SIG1 w0.305: v1(42.94,151.75) 42.94,158.92 44.57,160.54 v1(44.57,163.88)
  BOTTOM w0.305: R412.1 R411.1 C330.1 R410.1 R409.1 v1(47.6,170.29) 51.15,170.29 53.14,168.3 53.14,165.86 50.98,163.7 49.63,163.7 49.05,163.12 45.33,163.12 v1(44.57,163.88) ; 42.71,152.6 C363.1 42.71,151.98 v1(42.94,151.75)
MMC0_CLK: length 14.6
  BOTTOM w0.147: U57.2 84.55,78.63 84.42,78.5 84.42,77.62 84.29,77.5 84.11,77.5 83.98,77.62 83.98,78.5 83.85,78.63 83.67,78.63 83.54,78.5 83.54,77.62 83.41,77.5 83.23,77.5 83.1,77.62 83.1,78.5 82.97,78.63 80.88,78.63 80.54,78.97 77.09,78.97 76.86,79.2 R558.1
MMC0_FET_EN: length 86.2
  TOP w0.147: v1(52.43,131.5) 51.59,132.33 51.59,134.87 52.07,135.36 U18.3 ; v1(83.59,86.13) 82.88,85.42 82.88,83.69 v1(83.49,83.08) 83.57,83.01 R5216.2 ; v1(83.34,87.78) 83.34,90.17 82.7,90.81 82.7,94.06 84.51,95.86 84.51,99.21 82.98,100.74 v1(80.34,100.74)
  L03_SIG1 w0.091: v1(83.59,86.13) 83.34,86.39 v1(83.34,87.78) ; v1(59.49,130.94) 60.2,130.94 63.6,127.53 63.6,118.07 64.36,117.3 64.95,117.3 65.66,116.59 65.66,116.28 67.31,114.63 67.31,112.88 65.74,111.3 65.74,105.69 70.69,100.74 v1(80.34,100.74)
  BOTTOM w0.147: U57.8 83.96,81.63 83.57,82.03 R5216.2 83.57,83.01 v1(83.49,83.08) ; v1(59.49,130.94) 52.98,130.94 v1(52.43,131.5)
MMC0_SD_EN: length 101.8
  TOP w0.147: v1(119.28,69.37) 119.28,69.52 119.19,69.62 R21.1 ; v1(95.49,139.08) 95.22,139.35 U21.4
  L03_SIG1 w0.091: v1(95.49,139.08) 121.55,139.08 124.38,136.25 124.38,76.17 119.28,71.06 v1(119.28,69.37)
MMC0_SD_LS_EN: length 4.8
  TOP w0.147: R5823.2 R17.1 116.65,67.44 116.88,67.67 U2.4 116.13,68.05 115.86,67.78 U4.3
MMC0_SDIO_VSEL: length 60.5
  TOP w0.147: U56.11 28.32,53.52 27.64,52.83 26.57,52.83 25.43,51.69 24.54,51.69 23.8,50.95 20.5,50.95 20.19,50.65 20.19,44.57 21,43.76 22.38,43.76 24.56,41.58 29.62,41.58 30.02,41.17 32.59,41.17 34.01,42.59 34.01,43.89 35.41,45.29 44.93,45.29 47.85,48.21 49.03,48.21 49.35,48.53 49.35,54.67 50.69,56.01 51.48,56.01 52.11,55.37 U3087.4
MMC0_SEL_1V8: length 61.4
  TOP w0.147: U3077.4 79.59,66.33 80.11,65.81 80.11,64.85 81.23,63.73 82.35,63.73 84.91,61.16 85.29,61.16 85.7,60.76 85.7,57.45 81.41,53.16 75.13,53.16 v1(72.62,50.65) ; v1(60.73,52.93) 60.38,53.29 57.35,53.29 57.07,53.01 57.07,50.62 56.87,50.42 56.18,50.42 56.03,50.57 56.03,51.05 55.83,51.26 U3086.1 54.58,51.26 54.33,51 54.33,50.45 53.87,49.99 51.66,49.99 50.55,51.1 50.55,52.28 51.63,53.37 U3087.1
  L03_SIG1 w0.091: v1(63.63,50.47) 63.2,50.47 v1(60.73,52.93)
  BOTTOM w0.147: v1(72.62,50.65) 69.9,50.65 68.96,49.71 68.3,49.71 67.54,50.47 v1(63.63,50.47)
MMC0_SEL_3V3: length 19.1
  TOP w0.147: R5758.1 84.66,82.63 83.06,81.03 83.06,66.52 83.25,66.33 U3077.11
MMC0_SEL_IO: length 75
  TOP w0.147: R5846.1 93.66,84.77 v1(93.88,84.99) ; U18.17 v1(59.92,135.86)
  L03_SIG1 w0.091: v1(93.88,84.99) 92.58,86.28 88.82,86.28 74.85,100.25 70.36,100.25 64.19,106.43 64.19,115.57 61.34,118.41 61.34,126.82 58.01,130.15 58.01,133.95 v1(59.92,135.86)
OBSCLK0: length 9.4
  TOP w0.147: v1(75.35,106.43) 75.35,106.58 TP587.1
  BOTTOM w0.147: RA5.5 75.35,106.43 v1(75.35,106.43) 75.54,106.24 75.54,103.81 74.32,102.59 R5719.2
OSC0: length 5
  TOP w0.147: Y5.3 15.56,84.5 15.7,84.36 17.26,84.36 17.81,84.9 C217.2 18.39,84.92 18.69,84.61 U48.88
OSC1: length 3.3
  TOP w0.147: Y5.1 17.19,83.68 17.33,83.82 C223.2 18.19,83.82 18.57,84.21 U48.89
OSC1_XI: length 3.6
  TOP w0.132: 58.74,76.28 59.3,76.83 U136.C1
  TOP w0.147: 58.74,76.28 58.74,76.28 57.35,74.89 R3732.1
OSC1_XO: length 4.3
  TOP w0.132: R3733.1 58.47,75.57 59.69,76.79 59.69,77.66 U136.C2
OSPI0_CSN0: length 6.5
  TOP w0.147: R206.2 54.62,94.51 56.54,92.58 56.54,90.81 57.29,90.05 U136.A17
OSPI0_RESET_OUT0: length 46.7
  TOP w0.132: U136.A16 57.23,89.25 55.32,91.16 55.32,93.12 55.04,93.4
  TOP w0.147: R121.1 61.64,124.71 59.31,122.38 59.31,116.79 56.31,113.79 52.65,113.79 51.46,112.6 51.46,105.16 53.24,103.38 53.24,99.14 54.2,98.17 54.2,97.05 53.24,96.09 53.24,95.2 55.04,93.4
OSPI_CLK: length 29.7
  TOP w0.147: R197.1 55.96,96.65 56.24,96.93 v1(56.59,96.93) ; v1(57.41,106.71) 57.44,106.71 U28.B2
  L03_SIG1 w0.091: v1(57.41,106.71) 57.18,106.94 55.29,106.94 55.16,107.07 55.16,108.28 55.05,108.39 54.9,108.39 54.79,108.28 54.79,107.03 54.7,106.94 54.56,106.94 54.45,107.04 54.45,107.62 54.35,107.73 54.19,107.73 54.09,107.62 54.09,107.04 53.98,106.94 53.83,106.94 53.72,107.04 53.72,107.62 53.61,107.73 53.46,107.73 53.36,107.62 53.36,107.04 53.25,106.94 53.01,106.94 52.73,106.65 52.73,106.37 52.84,106.26 53.54,106.26 53.64,106.15 53.64,106 53.54,105.89 52.84,105.89 52.73,105.79 52.73,105.63 52.84,105.53 53.54,105.53 53.64,105.42 53.64,105.27 53.54,105.16 52.84,105.16 52.73,105.05 52.73,104.9 52.84,104.8 53.54,104.8 53.64,104.69 53.64,104.54 53.54,104.43 52.84,104.43 52.73,104.32 52.73,104.06 53.21,103.58 54.81,103.58 55.91,102.49 55.91,101.24 56.54,100.61 56.54,98.32 56.95,97.92 56.95,97.28 v1(56.59,96.93)
  BOTTOM w0.147: v1(57.41,106.71) R451.1
OSPI_CS: length 23
  TOP w0.147: v1(56.97,98.5) 56.97,99.46 57.45,99.94 57.45,100.86 57.25,101.06 57.04,101.06 56.9,100.91 56.9,100.41 55.83,99.34 54.91,99.34 54.62,99.04 54.62,98.68 54.79,98.51 55.05,98.51 55.19,98.36 55.19,98.07 55.05,97.92 54.79,97.92 54.62,97.75 R206.1
  L03_SIG1 w0.091: v1(56.97,98.5) 56.97,100.71 56.29,101.4 56.29,102.41 56.87,103 57.71,103 58.6,103.89 58.6,104.55 60.2,106.15 60.2,106.43 v1(60.53,106.76)
  BOTTOM w0.147: R5826.2 60.73,105.68 60.35,106.06 R447.1 60.34,106.34 60.53,106.53 v1(60.53,106.76)
OSPI_DQ0: length 9.6
  TOP w0.147: v1(57.1,109.17) 57.05,109.12 56.85,109.12 U28.D3 ; v1(55.8,105.31) 55.8,104.83 56.02,104.61 RA3.1
  L03_SIG1 w0.091: v1(57.1,109.17) 57.42,109.17 57.71,108.88 57.71,108.23 57.89,108.06 57.89,106.5 57.61,106.22 56.87,106.22 56.64,105.99 56.11,105.99 55.8,105.69 v1(55.8,105.31)
  BOTTOM w0.147: R446.1 57.1,109.63 57.1,109.61 57.12,109.59 57.12,109.19 v1(57.1,109.17)
OSPI_DQ1: length 11.5
  TOP w0.147: U28.D2 57.73,109.06 v1(58.01,109.35) ; RA3.2 55.62,104.45 55.12,104.95 v1(55.12,105.51)
  L03_SIG1 w0.091: v1(58.01,109.35) 58.57,108.79 58.57,108.22 58.17,107.82 58.17,106.25 56.74,104.83 55.48,104.83 55.12,105.19 v1(55.12,105.51)
  BOTTOM w0.147: v1(58.01,109.35) 57.77,109.59 R450.1
OSPI_DQ2: length 15.2
  TOP w0.147: U28.C4 55.8,107.99 v1(56.21,108.41) ; RA3.3 55.22,104.22 54.83,104.6 54.63,104.6 v1(54.38,104.85)
  L03_SIG1 w0.091: v1(54.38,104.85) 54.76,104.85 55.12,104.5 56.82,104.5 58.45,106.12 58.45,107.7 58.85,108.1 58.85,109.11 58.19,109.77 57.73,109.77 57.56,109.6 56.93,109.6 56.56,109.23 56.56,108.76 v1(56.21,108.41)
  BOTTOM w0.147: R452.1 56.12,108.29 56.21,108.38 v1(56.21,108.41)
OSPI_DQ3: length 14.2
  TOP w0.147: v1(54.64,104.14) 54.64,103.58 54.82,103.4 RA3.4 ; U28.D4 v1(56.13,109.4)
  L03_SIG1 w0.091: v1(56.13,109.4) 56.61,109.88 57.43,109.88 57.6,110.05 58.35,110.05 59.21,109.19 59.21,108.05 58.72,107.57 58.72,105.99 56.87,104.14 v1(54.64,104.14)
  BOTTOM w0.147: v1(56.13,109.4) 55.8,109.06 R449.1
OSPI_DQ4: length 18.9
  TOP w0.147: RA4.1 58.44,103.57 v1(59.08,104.22) ; U28.D5 54.23,108.99 54.09,109.13 v1(53.68,109.13)
  L03_SIG1 w0.091: v1(59.08,104.22) 59.51,104.65 59.51,105 59.77,105.26 60.38,105.26 60.63,105.51 60.63,106.22 61.04,106.63 61.04,109.88 59.72,111.2 57.99,111.2 57.61,110.82 57.61,110.52 57.25,110.15 54.7,110.15 v1(53.68,109.13)
  BOTTOM w0.147: v1(53.68,109.13) R448.1
OSPI_DQ5: length 16.3
  TOP w0.147: v1(57,110.62) 56.73,110.35 U28.E3 ; 58.04,103.04 58.04,104.85 58.95,105.77 60.78,105.77 v1(61.06,106.05)
  L03_SIG1 w0.091: v1(61.06,106.05) 61.44,106.43 61.44,110.24 60.2,111.48 57.86,111.48 v1(57,110.62)
  BOTTOM w0.147: R445.1 57.23,110.85 v1(57,110.62)
OSPI_DQ6: length 10.5
  TOP w0.147: v1(58.23,110.62) 57.98,110.37 57.98,110.24 U28.E2 ; v1(57.45,103.94) 57.45,103.92 57.64,103.74 RA4.3
  L03_SIG1 w0.091: v1(58.23,110.62) 58.55,110.62 59.21,109.96 59.21,109.6 59.49,109.32 59.49,107.92 59,107.44 59,105.87 57.91,104.78 57.91,104.39 v1(57.45,103.94)
  BOTTOM w0.147: R444.1 v1(58.23,110.62)
OSPI_DQ7: length 13
  TOP w0.147: RA4.4 57.24,103.48 57.05,103.68 56.77,103.68 v1(56.52,103.43) ; v1(59.23,110.59) 58.98,110.34 58.98,110.24 U28.E1
  L03_SIG1 w0.091: v1(59.23,110.59) 59.87,110.59 60.45,110.01 60.45,108.15 59.28,106.98 59.28,105.74 58.19,104.65 58.19,103.91 57.71,103.43 v1(56.52,103.43)
  BOTTOM w0.147: R443.1 v1(59.23,110.59)
OSPI_DQS: length 1.3
  TOP w0.147: v1(57.18,107.44) 57.15,107.47 57.15,107.57 U28.C3
  BOTTOM w0.147: R453.1 v1(57.18,107.44)
OSPI_DQS_SOC: length 36
  TOP w0.147: U136.B19 v1(58.1,92.06)
  L03_SIG1 w0.091: v1(59.94,104.83) 60.45,104.83 61.72,106.1 61.72,106.27 61.82,106.38 62.06,106.38 62.15,106.28 62.15,105.94 60.53,104.32 59.98,104.32 58.3,102.64 57.05,102.64 56.67,102.26 56.67,101.6 57.81,100.46 57.81,100.24 57.7,100.13 57.51,100.13 57.4,100.02 57.4,99.87 57.51,99.77 57.7,99.77 57.81,99.66 57.81,99.51 57.7,99.4 57.51,99.4 57.4,99.29 57.4,99.14 57.51,99.03 57.7,99.03 57.81,98.93 57.81,98.78 57.7,98.67 57.51,98.67 57.4,98.56 57.4,98.41 57.51,98.3 57.7,98.3 57.81,98.2 57.81,97.41 57.4,97 57.4,96.43 57.3,96.32 56.64,96.32 56.54,96.22 56.54,96.06 56.64,95.96 57.3,95.96 57.4,95.85 57.4,95.7 57.3,95.59 56.64,95.59 56.54,95.48 56.54,95.33 56.64,95.23 57.3,95.23 57.4,95.12 57.4,94.97 57.3,94.86 56.64,94.86 56.54,94.75 56.54,94.6 56.64,94.49 57.3,94.49 57.4,94.39 57.4,94.24 57.3,94.13 56.64,94.13 56.54,94.02 56.54,93.87 56.64,93.76 57.3,93.76 57.4,93.66 57.4,93.5 57.3,93.4 56.64,93.4 56.54,93.29 56.54,93.14 56.64,93.03 57.3,93.03 57.4,92.92 57.4,92.75 v1(58.1,92.06)
  BOTTOM w0.132: v1(58.1,92.06) 58.1,92.63 57.87,92.85 R504.1
  BOTTOM w0.147: R453.2 58.26,107.44 R454.1 58.26,106.51 v1(59.94,104.83)
OSPI_INTN: length 1.5
  TOP w0.147: R125.1 R123.1
OSPI_RSTN: length 39
  TOP w0.147: R124.1 55.26,127.83 U27.4 57.11,127.83 57.28,128 R5821.2 57.28,130.05 57.51,130.28 59.59,130.28 59.84,130.02 59.84,127.84 61.04,126.64 61.87,126.64 62.15,126.36 62.15,124.54 59.66,122.05 59.66,116.64 56.46,113.44 54.33,113.44 53.22,112.33 53.22,108.12 53.82,107.52 54.84,107.52 55.18,107.18 55.18,106.54 U28.A4
P2_PP_EXT_ENABLE: length 2.6
  BOTTOM w0.147: R669.1 35.06,19.69 34.17,20.58 U129.49
PCM1_ADDR_0: length 4
  TOP w0.147: 51.98,152.6 53.42,152.6 53.63,152.81 53.93,152.81 54.21,152.52 U7.24 ; 51.98,152.6 R26.1 ; 51.98,152.6 51.98,152.88 52.31,153.21 R20.2
PCM1_ADDR_1: length 2.2
  TOP w0.147: R22.1 R23.2 54.44,153.02 54.71,152.74 U7.23
PCM1_AREG: length 2.7
  TOP w0.147: C89.1 54.53,145.71 54.63,145.82 v1(54.63,146.22) 54.71,146.3 U7.2
  BOTTOM w0.147: C378.1 v1(54.63,146.22)
PCM1_BSTOUT: length 3.7
  TOP w0.147: C96.1 57.43,145.06 C92.2 57.12,145.06 56.6,145.58
  TOP w0.203: U7.5 56.21,145.97 56.6,145.58
PCM1_DREG: length 2.5
  TOP w0.147: C82.1 51.6,147.87 51.75,147.72 C81.1 52.66,147.72 52.74,147.8 U7.32
PCM1_GPIO1: length 6.6
  TOP w0.147: v1(49.28,150.29) 49.28,150.55 49.43,150.7 R34.2 49.68,150.34 50.23,149.8 U7.28
  BOTTOM w0.147: v1(49.28,150.29) 48.69,150.29 48.46,150.06 R432.1
PCM1_IN1N: length 20.6
  TOP w0.147: v1(64.95,155.04) 65.2,154.79 65.2,151.96 61.46,148.22 59.24,148.22 59.16,148.3 U7.10 ; v1(63.23,160.36) 63.41,160.54 63.41,161.31 63.15,161.57 C17.2 63.15,161.65 63.35,161.85 63.35,162.53 62.99,162.9 R9.2
  BOTTOM w0.147: v1(64.95,155.04) 65.1,155.2 65.1,157.54 63.41,159.23 63.41,160.18 v1(63.23,160.36)
PCM1_IN1P: length 21.4
  TOP w0.147: R10.2 64.18,162.9 63.71,162.42 63.71,161.99 64.07,161.63 C18.2 63.76,161.27 63.76,160.54 v1(63.94,160.36) ; v1(65.68,155.12) 65.55,154.99 65.55,151.82 61.6,147.87 59.24,147.87 59.16,147.8 U7.9
  BOTTOM w0.147: v1(65.68,155.12) 65.45,155.34 65.45,157.68 63.76,159.37 63.76,160.18 v1(63.94,160.36)
PCM1_IN2N: length 21.1
  TOP w0.147: v1(59.39,160.36) 59.57,160.54 59.57,161.32 C15.2 59.51,161.88 59.51,162.5 R7.2 ; v1(63.72,154.21) 63.93,153.99 63.93,152.46 60.69,149.22 59.24,149.22 59.16,149.3 U7.12
  BOTTOM w0.147: v1(63.72,154.21) 63.95,154.45 63.95,156.08 63.11,156.92 60.86,156.92 59.57,158.21 59.57,160.18 v1(59.39,160.36)
PCM1_IN2P: length 21.7
  TOP w0.147: v1(64.48,154.09) 64.28,153.9 64.28,152.32 60.84,148.87 59.24,148.87 59.16,148.8 U7.11 ; v1(60.1,160.36) 59.92,160.54 59.92,161.32 C16.2 59.98,161.87 59.98,162.5 R8.2
  BOTTOM w0.147: v1(60.1,160.36) 59.92,160.18 59.92,158.35 61,157.27 63.26,157.27 64.35,156.18 64.35,154.22 v1(64.48,154.09)
PCM1_IN3N: length 41
  TOP w0.147: U7.14 59.16,150.3 59.24,150.22 59.99,150.22 62.21,152.44 62.21,155.21 63.81,156.81 65.55,156.81 67.56,158.83 67.56,162.78 69.96,165.17 69.96,169.01 69.03,169.93 66.45,169.93 62,165.48 60.38,165.48 v1(59.92,165.95)
  BOTTOM w0.147: R408.2 60.05,168.07 60.05,167.46 C334.2 60.1,166.91 60.1,166.12 v1(59.92,165.95)
PCM1_IN3P: length 41.3
  TOP w0.147: v1(60.63,165.95) 60.74,165.83 61.85,165.83 66.3,170.28 69.18,170.28 70.31,169.15 70.31,165.02 67.91,162.63 67.91,158.68 65.7,156.46 63.96,156.46 62.56,155.07 62.56,152.3 60.13,149.87 59.24,149.87 59.16,149.8 U7.13
  BOTTOM w0.147: R407.2 60.4,167.97 60.4,167.57 60.73,167.24 C333.2 60.45,166.93 60.45,166.13 v1(60.63,165.95)
PCM1_IN4N: length 43.4
  TOP w0.147: U7.16 59.16,151.3 59.24,151.22 59.5,151.22 60,151.72 60,155.56 58.61,156.94 57.97,156.94 52.91,162.01 52.91,168.79 54.54,170.43 58.61,170.43 59.92,169.11 59.92,167.8 59.12,167.01 59.12,165.45 59.58,164.99 63.56,164.99 63.96,165.4 63.96,165.74 v1(63.76,165.95)
  BOTTOM w0.147: R406.2 64.01,167.95 64.01,167.59 C332.2 64.03,166.81 64.03,166.24 63.85,166.06 63.85,166.04 v1(63.76,165.95)
PCM1_IN4P: length 43.6
  TOP w0.147: v1(64.47,165.95) 64.31,165.79 64.31,165.25 63.7,164.64 59.44,164.64 58.75,165.33 58.75,167.19 59.52,167.97 59.52,168.95 58.44,170.03 54.64,170.03 53.26,168.65 53.26,162.16 58.12,157.29 58.76,157.29 60.35,155.7 60.35,151.57 59.65,150.87 59.24,150.87 59.16,150.8 U7.15
  BOTTOM w0.147: R405.2 64.36,168.09 64.36,167.45 C331.2 64.38,167 64.38,166.03 v1(64.47,165.95)
PCM1_INT_1V8: length 47.5
  TOP w0.147: v1(90.18,142.9) U21.15 ; R34.1 v1(49.68,151.82)
  L03_SIG1 w0.091: v1(90.18,142.9) 90.06,143.03 80.7,143.03 v1(78.26,145.47)
  BOTTOM w0.147: v1(78.26,145.47) 78.51,145.72 78.51,146.59 74.74,150.35 65.96,150.35 63.35,152.96 51.77,152.96 50.62,151.82 v1(49.68,151.82)
PCM1_MCASP1_AXR0: length 2
  TOP w0.147: R38.2 52.5,149.2 52.6,149.3 U7.29
PCM1_RESETN: length 45.8
  TOP w0.147: U7.22 55.21,152.81 54.93,153.09 54.93,154.53 53.6,155.86 53.6,158.78 53.91,159.09 v1(54.95,159.09) ; v1(66.14,155.78) 66.14,144.68 65.52,144.06 65.52,142.34 65.97,141.89 R68.2 66.5,141 66.19,140.69 64.24,140.69 63.84,140.29 R78.1 U14.4
  BOTTOM w0.147: v1(66.14,155.78) 66.14,159.62 64.78,160.98 59.26,160.98 57.36,159.09 v1(54.95,159.09)
PCM1_VREF: length 1.2
  TOP w0.147: U7.7 57.21,146.58 57.43,146.36 C87.1
PCM2_ADDR_0: length 3.5
  TOP w0.147: R63.1 R62.2 47.1,144.91 46.95,145.06 45.69,145.06 45.54,145.2 U8.24
PCM2_ADDR_1: length 2.2
  TOP w0.147: R61.1 R60.2 45.32,144.93 45.04,145.2 U8.23
PCM2_AREG: length 2.6
  TOP w0.147: C64.1 45.27,152.11 45.13,151.96 v1(45.13,151.69) 45.04,151.6 U8.2
  BOTTOM w0.147: v1(45.13,151.69) 45.29,151.53 C368.1
PCM2_BSTOUT: length 3.8
  TOP w0.203: C54.1 C60.2 42.74,152.76 43.54,151.96 U8.5
PCM2_IN1N: length 23.8
  TOP w0.147: v1(38.09,157.38) 38.25,157.22 38.25,150.85 39.52,149.59 40.48,149.59 40.54,149.52 U8.10 ; v1(46.08,160.36) 46.3,160.58 46.3,161.28 C13.2 45.96,161.67 46.21,161.93 46.21,162.5 R5.2
  BOTTOM w0.147: v1(46.08,160.36) 46.26,160.18 46.26,159.24 45.61,158.59 38.63,158.59 38.27,158.24 38.27,157.56 v1(38.09,157.38)
PCM2_IN1P: length 23.1
  TOP w0.147: v1(38.8,157.38) 38.6,157.18 38.6,151 39.66,149.94 40.46,149.94 40.54,150.02 U8.9 ; R6.2 46.68,162.5 46.68,161.93 46.93,161.67 C14.2 46.65,161.36 46.65,160.5 v1(46.79,160.36)
  BOTTOM w0.147: v1(38.8,157.38) 38.62,157.56 38.62,158.09 38.77,158.24 45.76,158.24 46.61,159.1 46.61,160.18 v1(46.79,160.36)
PCM2_IN2N: length 24.4
  TOP w0.147: v1(36.13,157.91) 36.3,157.75 36.3,150.62 38.3,148.62 40.45,148.62 40.54,148.52 U8.12 ; R3.2 42.37,162.5 42.37,161.93 42.12,161.67 C11.2 42.42,161.32 42.42,160.54 v1(42.24,160.36)
  BOTTOM w0.147: v1(42.24,160.36) 42.42,160.19 42.42,159.74 42.08,159.41 36.94,159.41 36.31,158.78 36.31,158.06 36.16,157.91 v1(36.13,157.91)
PCM2_IN2P: length 23.8
  TOP w0.147: R4.2 42.84,162.5 42.84,161.93 43.09,161.67 43.09,161.65 C12.2 42.78,161.34 42.78,160.54 v1(42.96,160.36) ; U8.11 40.54,149.02 40.49,148.97 38.45,148.97 36.65,150.77 36.65,157.72 v1(36.84,157.91)
  BOTTOM w0.147: v1(42.96,160.36) 42.77,160.17 42.77,159.6 42.23,159.05 37.08,159.05 36.66,158.63 36.66,158.09 v1(36.84,157.91)
PCM2_IN3N: length 43.6
  TOP w0.147: U8.14 40.54,147.52 40.47,147.6 37.82,147.6 35.1,150.32 35.1,167.17 38.37,170.43 40.92,170.43 42.55,168.81 43.43,168.81 44.32,167.92 44.32,165.54 43.84,165.06 43.31,165.06 42.95,165.41 42.95,165.76 v1(42.77,165.95)
  BOTTOM w0.147: R412.2 43.01,167.97 43.01,167.57 C338.2 42.98,166.88 42.98,166.15 v1(42.77,165.95)
PCM2_IN3P: length 40.6
  TOP w0.147: v1(43.48,165.95) 43.3,165.76 43.3,165.56 43.45,165.41 43.7,165.41 43.97,165.68 43.97,167.78 43.29,168.46 42.4,168.46 40.77,170.08 38.51,170.08 35.45,167.03 35.45,150.46 37.95,147.97 40.49,147.97 40.54,148.02 U8.13
  BOTTOM w0.147: v1(43.48,165.95) 43.33,166.1 43.33,166.95 C337.2 43.59,167.24 43.36,167.46 43.36,168.08 R411.2
PCM2_IN4N: length 51.1
  TOP w0.147: U8.16 40.54,146.52 40.48,146.58 37.64,146.58 34.32,149.91 34.32,167.82 38.03,171.53 38.36,171.53 41.12,171.53 42.17,170.48 45.42,170.48 48.26,167.64 48.26,165.48 47.83,165.05 47.14,165.05 46.79,165.4 46.79,165.76 v1(46.61,165.95)
  BOTTOM w0.147: v1(46.61,165.95) 46.84,166.17 46.84,166.86 C336.2 46.82,167.54 46.82,167.99 R410.2
PCM2_IN4P: length 48
  TOP w0.147: v1(47.32,165.95) 47.14,165.78 47.14,165.55 47.29,165.4 47.69,165.4 47.91,165.63 47.91,167.49 45.28,170.13 41.97,170.13 40.96,171.14 38.2,171.14 34.67,167.62 34.67,150.05 37.79,146.93 40.46,146.93 40.54,147.02 U8.15
  BOTTOM w0.147: v1(47.32,165.95) 47.19,166.08 47.19,166.95 C335.2 47.2,167.46 47.2,168.08 R409.2
PCM2_INT_1V8: length 48.3
  TOP w0.147: R46.1 49.35,148.01 50.39,146.96 v1(50.39,146.25) ; U21.16 89.68,142.7 89.54,142.85 88.57,142.85 v1(88.29,142.57)
  L03_SIG1 w0.091: v1(88.29,142.57) 79.55,142.57 v1(76.68,145.44)
  BOTTOM w0.147: v1(50.39,146.25) 50.39,147.14 52.83,149.58 63.68,149.58 65.41,147.85 75.64,147.85 76.68,146.81 v1(76.68,145.44)
PCM2_MCASP1_AXR0: length 1.3
  BOTTOM w0.147: R433.1 49.93,148.52 50.13,148.72 R431.2
PCM2_RESETN: length 23.7
  TOP w0.147: U8.22 44.54,144.97 v1(44.68,144.83)
  L03_SIG1 w0.091: v1(44.68,144.83) 43.79,145.72 43.79,155.85 v1(45.31,157.38)
  BOTTOM w0.147: U75.4 52.66,160.11 52.56,160 R416.1 R415.2 49.08,160 46.46,157.38 v1(45.31,157.38)
PCM2_VREF: length 1.2
  TOP w0.147: C65.1 42.32,151.73 42.54,151.51 U8.7
PCM6240_MCASP1_ACLKR: length 72.7
  TOP w0.147: v1(60.48,117.14) 62.76,117.14 64.03,115.87 66.98,115.87 68.12,114.73 68.12,111.61 70.51,109.22 70.51,107.57 69.07,106.13 R179.1 ; U8.30 49.12,149.02 v1(50.3,147.84) 50.3,148.24 50.6,148.54 52.2,148.54 52.45,148.8 U7.30
  L03_SIG1 w0.091: v1(60.48,117.14) 58.14,117.14 56.52,118.77 56.52,122.33 56.85,122.66 56.85,129.4 53.67,132.58 53.67,144.17 52.32,145.52 52.32,147.27 51.76,147.84 v1(50.3,147.84)
PCM6240_MCASP1_AFSR: length 68
  TOP w0.147: v1(47.55,149.52) U8.31 ; v1(60.48,116.18) 62.74,116.18 63.53,115.39 66.58,115.39 67.39,114.59 67.39,111.71 70.05,109.04 70.05,107.75 68.48,106.17 R5640.2 ; U7.31 v1(52.66,148.3)
  L03_SIG1 w0.091: v1(47.55,149.52) 49.11,149.52 49.6,150.01 50.95,150.01 v1(52.66,148.3) 54.08,146.88 54.08,141.22 54.87,140.43 54.87,133.29 57.2,130.96 57.2,122.61 56.79,122.2 56.79,121.44 60.9,117.33 60.9,116.61 v1(60.48,116.18)
PCM6240_MCASP1_AXR0: length 67.7
  TOP w0.147: R38.1 50.11,149.2 v1(49.78,149.53)
  L03_SIG1 w0.091: v1(61.42,103.45) 63.37,105.41 63.37,111.38 55.42,119.33 55.42,123.73 55.51,123.82 56.18,123.82 56.29,123.93 56.29,124.08 56.18,124.18 55.5,124.18 55.37,124.32 55.37,124.46 55.46,124.55 56.18,124.55 56.29,124.66 56.29,124.81 56.18,124.92 55.5,124.92 55.37,125.05 55.37,125.19 55.46,125.28 56.18,125.28 56.29,125.39 56.29,125.54 56.18,125.65 55.5,125.65 55.37,125.78 55.37,125.93 55.48,126.04 56.01,126.04 56.11,126.15 56.11,126.3 56.01,126.4 55.48,126.4 55.37,126.51 55.37,126.66 55.48,126.77 56.01,126.77 56.11,126.88 56.11,127.03 56.01,127.14 55.48,127.14 55.37,127.24 55.37,127.39 55.48,127.5 56.01,127.5 56.11,127.61 56.11,127.76 56.01,127.87 55.48,127.87 55.37,127.97 55.37,128.5 53.29,130.58 53.29,141.2 51,143.49 51,145.45 50.82,145.62 50.82,146.56 49.78,147.6 v1(49.78,149.53)
  BOTTOM w0.147: v1(61.42,103.45) 62.31,103.45 63,102.76 R500.2 ; v1(49.78,149.53) 49.95,149.7 R431.1
PCM6240_MCASP1_AXR2: length 66.2
  L03_SIG1 w0.091: v1(50.5,145.34) 50.5,143.41 52.98,140.92 52.98,130.43 55.09,128.32 55.09,125.51 54.99,125.4 54.26,125.4 54.15,125.29 54.15,125.14 54.26,125.04 54.99,125.04 55.09,124.93 55.09,124.78 54.99,124.67 54.26,124.67 54.15,124.56 54.15,124.41 54.26,124.3 54.99,124.3 55.09,124.2 55.09,124.05 54.99,123.94 54.18,123.94 54.08,123.83 54.08,123.68 54.18,123.57 54.99,123.57 55.09,123.47 55.09,123.31 54.99,123.21 54.13,123.21 54.03,123.1 54.03,122.95 54.13,122.84 54.99,122.84 55.09,122.73 55.09,122.58 54.99,122.48 54.11,122.48 54,122.37 54,122.22 54.11,122.11 54.95,122.11 55.04,122.02 55.04,119.3 63.09,111.25 63.09,105.77 60.83,103.5 60.83,102.54 v1(61.32,102.06)
  BOTTOM w0.147: R435.1 48.46,146.99 50.11,145.34 v1(50.5,145.34) ; v1(61.32,102.06) 61.32,100.56 61.16,100.41 R190.2
PD_GPIO0: length 1.6
  BOTTOM w0.147: R674.2 25.6,17.98 25.8,18.18 U129.16
PD_HRESET: length 3.4
  TOP w0.147: v1(33.86,23.96) 34.13,24.23 C301.1
  BOTTOM w0.147: v1(33.86,23.96) 34.21,23.6 R662.1 34.5,23.04 34.04,22.58 U129.44
PD_I2C_IRQ: length 146.7
  TOP w0.147: v1(52.35,133.12) 52.35,133.48 52.73,133.86 U18.6
  L03_SIG1 w0.091: v1(28.37,133.96) 26.34,131.93 26.34,101.14 23.06,97.87 23.06,96.27 24.41,94.92 25.45,94.92 27.3,93.07 27.3,87.3 28.29,86.32 28.29,84.83 26.34,82.88 26.34,81.74 24.46,79.86 24.46,71.29 22.68,69.51 22.68,59.87 20.8,57.99 20.8,55.88 21.31,55.37 21.95,55.37 24.1,53.21 24.1,42.77 v1(26.21,40.67)
  BOTTOM w0.147: R655.1 29.29,26.13 29.16,26.26 R645.2 28.97,26.6 28.4,27.18 27.33,27.18 26.21,28.3 v1(26.21,40.67) ; v1(28.37,133.96) 50.65,133.96 51.49,133.12 v1(52.35,133.12)
PD_MS_I2C1_IRQ: length 1.4
  BOTTOM w0.147: R660.2 27.15,24.77 27.45,24.46 U129.29
PD_MS_I2C1_SCL: length 10
  L03_SIG1 w0.091: v1(24.13,29.84) 24.79,29.18 24.79,23.98 v1(25.48,23.29)
  BOTTOM w0.147: R633.1 v1(24.13,29.84) ; R664.2 25.39,23.38 v1(25.48,23.29) 26.19,22.58 U129.27
PD_MS_I2C1_SDA: length 12.4
  L03_SIG1 w0.091: v1(23.71,32.38) 25.07,31.03 25.07,25.04 v1(25.86,24.26)
  BOTTOM w0.147: R627.1 v1(23.71,32.38) ; U129.28 26.39,22.98 26.19,23.18 26.19,23.93 v1(25.86,24.26) 25.46,24.26 25.26,24.45 R658.2
PD_S_I2C2_IRQ: length 1.6
  BOTTOM w0.147: U129.34 29.45,24.34 29.39,24.41 29.39,24.77 29.29,24.87 R655.2
PD_S_I2C2_SCL: length 2
  BOTTOM w0.147: R657.2 27.76,24.78 28.16,24.38 28.47,24.38 28.65,24.21 28.65,24.1 28.65,24.1 U129.32
PD_S_I2C2_SDA: length 1.7
  BOTTOM w0.147: R656.2 28.52,24.84 29.01,24.36 29.01,24.33 29.03,24.31 29.03,24.28 29.05,24.26 U129.33
PD_SPI_CLK: length 21.9
  TOP w0.147: U69.6 31.23,27.37 30.84,27.76 v1(30.84,28.04)
  L03_SIG1 w0.091: J21.7 21.99,38.8 25.31,38.8 27.33,36.78 27.33,31.98 30.84,28.47 v1(30.84,28.04)
  BOTTOM w0.147: v1(30.84,28.04) 31.57,27.31 R652.2
PD_SPI_MISO: length 17.8
  TOP w0.147: U69.2 27.75,28.64 v1(28.05,28.94)
  L03_SIG1 w0.091: J21.5 24.33,35.48 25.58,34.24 25.58,31.42 v1(28.05,28.94)
  BOTTOM w0.147: R654.2 30.05,26.15 29.92,26.28 R644.2 30.23,26.6 30.38,26.75 30.38,27.89 29.32,28.94 v1(28.05,28.94)
PD_SPI_MOSI: length 23.5
  TOP w0.147: v1(30.81,26.34) 31.05,26.1 U69.5
  L03_SIG1 w0.091: v1(30.81,26.34) 30.05,27.1 30.05,28.75 26.87,31.93 26.87,36.75 25.98,37.64 23.01,37.64 22.25,36.88 19.81,36.88 J21.8
  BOTTOM w0.147: R653.2 v1(30.81,26.34)
PD_SPI_SS: length 24.8
  TOP w0.147: v1(30.02,30.68) 29.25,29.91 U69.1
  L03_SIG1 w0.091: v1(30.02,30.68) 29.41,30.68 27.61,32.49 27.61,36.91 23.95,40.56 J21.9
  BOTTOM w0.147: v1(30.02,30.68) 32.33,28.37 R646.2 R651.2
PD_VIN_3V3: length 1.8
  TOP w0.147: v1(30.86,16.11) 30.63,15.88 C320.2
  BOTTOM w0.147: U129.5 31.05,16.3 v1(30.86,16.11)
PMIC_EN: length 2
  TOP w0.147: R317.2 31.62,52.69 31.32,52.99 U56.17
PMIC_ENABLE: length 17.5
  TOP w0.147: v1(9.5,61.77) 10.32,61.77 10.59,61.5 U54.6 ; U2356.10 16.67,52 16.87,52.2 16.87,52.65 16.64,52.88 14.3,52.88 v1(7.87,59.31)
  L03_SIG1 w0.091: v1(7.87,59.31) 7.87,60.15 v1(9.5,61.77)
PMIC_I2C_SCL_1V8: length 13.2
  TOP w0.147: TP72.1 19.3,64.29 20.62,62.97 20.62,60.28 21.42,59.49 23.11,59.49 23.55,59.05 25.6,59.05 25.79,58.86 R296.2 26.32,58.61 26.58,58.36 U56.1
PMIC_I2C_SDA_1V8: length 14.7
  TOP w0.147: TP73.1 17.62,63.4 19.35,63.4 20.27,62.48 20.27,60.14 21.35,59.06 21.89,59.06 22.3,58.65 R294.2 22.65,57.91 22.9,57.66 24.4,57.66 24.83,58.09 26.21,58.09 26.44,57.86 U56.2
PMIC_INT_B: length 11.7
  TOP w0.147: R288.2 40.82,61.12 TP70.1 40.15,59.61 R300.2 R299.2 38.23,59.61 38,59.84 33.86,59.84 33.38,59.36 32.49,59.36 32.32,59.19 U56.27
PMIC_INTN: length 59.1
  TOP w0.147: U136.P3 v1(68.5,78.46) ; v1(42.16,67.67) 42.16,67.21 42.01,67.06 42.01,60.71 41.45,60.15 41.3,60.15 41.15,59.99 41.15,59.23 40.87,58.95 40.46,58.95 40.37,59.05 R300.1
  L03_SIG1 w0.091: v1(68.5,78.46) 68.87,78.08 68.87,76.04 68.7,75.86 68.7,72.64 68.15,72.09 68.15,69.27 v1(67.23,68.35) ; v1(42.16,67.67) 42.49,67.99 47.26,67.99 v1(49.4,70.13)
  BOTTOM w0.132: 70.77,77.26 69.13,77.26 68.9,77.49 68.9,78.05 v1(68.5,78.46)
  BOTTOM w0.147: v1(49.4,70.13) 49.42,70.13 49.84,70.55 51.84,70.55 53.51,72.23 58.7,72.23 61.97,68.96 62.4,68.96 62.71,69.27 66.32,69.27 v1(67.23,68.35) ; R205.1 74.13,75.76 73.88,75.51 71.91,75.51 71.6,75.82 71.6,76.43 70.77,77.26
PMIC_LPM_EN0: length 103.7
  TOP w0.147: U2356.7 17.55,50.5 17.72,50.33 R5737.1 17.72,49.37 v1(17.42,49.07) 17.81,48.69 19.05,48.69 19.38,49.02 19.38,51.46 20.5,52.58 v1(21.49,52.58) ; v1(47.25,83.97) 47.25,84.36 47.37,84.48 TP75.1 48.62,83.69 49.17,83.69 49.34,83.53 R5750.2 ; v1(13.97,49.81) 13.97,50.93 14.55,51.5 U2356.2
  L03_SIG1 w0.091: v1(21.49,52.58) 22.2,51.87 22.2,41.58 22.55,41.24 24.63,41.24 27.53,38.33 32.23,38.33 33.1,37.47 36.55,37.47 37.47,38.38 37.47,41.48 38.28,42.29 38.28,46.46 38.05,46.69 38.05,48.01 39.62,49.58 39.62,53.09 43.26,56.72 43.26,62.79 46.3,65.84 48,65.84 50.31,68.15 50.31,69.91 49.56,70.66 49.12,70.66 46.08,73.71 46.08,79.88 46.76,80.57 46.76,81.64 46.41,81.99 46.41,83.12 v1(47.25,83.97)
  BOTTOM w0.147: v1(17.42,49.07) 16.69,49.81 v1(13.97,49.81)
PMIC_LPM_SEL: length 18.4
  TOP w0.147: U2356.5 15.03,50 14.88,49.86 14.88,49.2 v1(15.29,48.79) ; U2356.1 v1(14.31,52) R318.1 13.67,51.29 13.13,50.74 13.13,48.37 13.64,47.86 J16.1
  L03_SIG1 w0.091: v1(15.29,48.79) 15.29,51.02 v1(14.31,52)
PMIC_NSLEEP: length 17
  TOP w0.147: U2356.6 16.64,50 16.87,49.78 16.87,48.72 17.37,48.21 19.23,48.21 19.74,48.72 19.74,50.9 20.19,51.36 23.7,51.36 24.38,52.04 25.2,52.04 26.34,53.19 27.49,53.19 27.82,53.52 U56.10
PMIC_POWERGOOD: length 47.6
  TOP w0.147: v1(39.29,68.22) 38.24,67.17 33.86,67.17 31.37,69.67 31.37,71.84 30.51,72.69 25.82,72.69 24.34,71.21 24.34,70.55 21.88,68.1 15.57,68.1 14.45,66.98 v1(14.45,63.35) ; R290.1 38.04,61.4 38.41,61.77 40.74,61.77 v1(40.87,61.65)
  L03_SIG1 w0.091: v1(40.87,61.65) 40.13,61.65 39.16,62.62 39.16,68.09 v1(39.29,68.22)
  BOTTOM w0.147: v1(14.45,63.35) 14.45,63.7 14.57,63.82 U86.1
PMIC_RSTOUT: length 50.2
  TOP w0.147: v1(35.89,44.78) 36.53,44.15 37.97,44.15 38.4,44.58 45.72,44.58 48.44,47.29 49,47.29 49.53,47.83 51.13,47.83 52.37,46.58 55.45,46.58 R286.1 ; TP67.1 39.48,60.55 R291.2 R290.2 37.49,60.55 37.21,60.27 33.73,60.27 33.17,59.72 32.1,59.72 v1(31.93,59.54) 31.82,59.44 U56.28
  BOTTOM w0.147: v1(31.93,59.54) 32.96,59.54 33.2,59.31 33.2,58.27 33.99,57.48 33.99,56.86 33.99,55.37 36.91,52.45 36.91,52.2 37.24,51.87 37.24,46.93 37.39,46.78 37.39,45.44 36.73,44.78 v1(35.89,44.78)
PORT1_15W: length 19.1
  TOP w0.147: v1(22.89,26.39) 23.55,26.39 24.21,27.05 24.21,29.08 25.86,30.73 25.86,33.65 25.71,33.8 R5767.1 25.3,34.29 25.08,34.51 U71.2
  BOTTOM w0.147: v1(22.89,26.39) 22.89,20.22 24.2,18.9 R386.1
PORT2_15W: length 16.9
  TOP w0.147: v1(23.42,27.25) 23.1,27.58 23.1,33.13 23.72,33.76 R381.1 24.33,34.28 24.6,34.56 U71.1
  BOTTOM w0.147: v1(23.42,27.25) 23.42,20.62 24.24,19.81 R390.1
PP1_CABLE: length 1.6
  TOP w0.147: C309.1 25.88,21.66 v1(25.77,21.77)
  BOTTOM w0.147: v1(25.77,21.77) 25.79,21.78 U129.25
PP2_CABLE: length 3.3
  BOTTOM w0.147: U129.46 34.11,21.78 34.19,21.7 34.73,21.7 C631.1 R665.2
PRI/SEC_REF_SEL: length 3.1
  TOP w0.147: U15.4 76.89,57.64 76.14,56.88 R75.2 R76.1
RESET_STATZ: length 22.7
  TOP w0.147: TP592.1 52.39,72.77 v1(51.31,72.77) ; v1(63.7,80.06) U136.H4
  BOTTOM w0.132: v1(63.7,80.06) 63.56,80.06 63.04,79.53 63.04,79.27 62.41,78.64 ; 60.65,78.06 60.33,78.06 60.1,78.29 60.1,78.62 60.33,78.85 62.19,78.85 62.41,78.64 ; R5738.1 62.56,78.05 62.41,78.21 62.41,78.64 ; 60.68,78.05 60.93,77.8 61.11,77.8 61.26,77.65
  BOTTOM w0.147: 61.26,77.65 61.26,75.44 59.94,74.12 52.65,74.12 v1(51.31,72.77) ; 60.65,78.06 60.66,78.05 60.68,78.05
RESETSTATZ: length 168.3
  TOP w0.147: U3083.6 97.04,59.54 97.1,59.6 v1(97.1,59.61) ; v1(52.27,137.59) 52.59,137.91 53.83,137.91 54.05,137.69 U18.24 ; v1(100.1,57.28) 99.19,56.37 99.19,53 v1(101.45,50.75) ; v1(88.32,60.45) 87.48,59.61 87.48,56.69 85.98,55.19 85.98,51.58 v1(85.6,51.21) ; v1(58.42,53.92) 60.76,53.92 61.54,53.14 61.54,51.28 61.63,51.19 R366.1
  L03_SIG1 w0.091: v1(58.42,53.92) 58.42,57.87 57.25,59.04 57.25,59.97 52.32,64.9 52.32,70.28 52.65,70.61 52.65,73.91 49.8,76.76 49.8,80.79 50.85,81.84 50.85,82.98 51.05,83.19 51.05,92.84 52.12,93.9 52.12,97.61 52.37,97.87 52.37,99.64 51.33,100.69 51.33,125.01 51.74,125.43 51.74,137.06 v1(52.27,137.59)
  BOTTOM w0.147: v1(100.1,57.28) 99.43,57.28 v1(97.1,59.61) 96.94,59.77 R5843.2 95.78,59.43 95.51,59.16 92.3,59.16 90.86,60.6 88.47,60.6 v1(88.32,60.45) ; v1(101.45,50.75) 101.45,49.13 101.45,49.12 R605.1 ; v1(58.42,53.92) 57.38,54.97 57.38,56.92 57.64,57.19 61.74,57.19 61.92,57 64.09,57 64.36,57.27 64.36,57.33 64.73,57.71 65.13,57.71 65.43,57.4 67.49,57.4 67.7,57.62 68.87,57.62 74.4,52.09 78.85,52.09 79.73,51.21 v1(85.6,51.21)
RESETSTATZ_1V8: length 461.2
  TOP w0.147: U15.8 78.7,55.43 78.55,55.28 TP100.1 78.41,54.45 v1(78.41,53.98) ; v1(70.94,132.13) 70.74,132.34 R377.2 70.4,135.02 69.77,135.64 69.77,138.15 69.06,138.86 U14.2 66.91,138.86 66.65,139.12 66.65,140.49 67.46,141.3 67.46,143.42 66.5,144.39 66.5,155.14 66.85,155.5 v1(66.85,155.85) ; U26.2 102.48,94.94 102.64,95.1 v1(102.64,96.16) ; U27.2 58.1,126.88 58.09,126.9 v1(57.71,126.9) ; v1(89.13,131.95) 91.18,134.01 U21.28 ; v1(80.09,66.78) 80.48,66.38 80.48,64.98 81.2,64.26 82.36,64.26 85.1,61.52 85.45,61.52 86.06,60.91 86.06,57.3 80.75,51.99 v1(80.04,51.99) ; U3083.3 97.04,55.97 92.26,51.2 v1(86.99,51.2) ; J12.55 115.89,123.58 116.48,122.98 v1(116.48,112.37) ; v1(46.71,112.42) 46.46,112.17 46.46,111.9 46.69,111.67 R5760.2 U2348.2 ; v1(116.33,68.61) 116.83,68.61 U2.3 116.88,69.01 116.59,69.3 116.59,72.09 113.72,74.96 113.72,89.46 v1(112.26,90.92) ; J13.55 18.68,142.84 25.32,136.19 v1(25.32,132.79)
  L03_SIG1 w0.091: v1(116.48,112.37) 116.48,111.35 102.64,97.51 v1(102.64,96.16) ; v1(47.85,130.48) 47.85,126.8 46.08,125.02 46.08,113.06 v1(46.71,112.42) 46.84,112.29 46.84,100.86 48.39,99.31 48.39,98.96 48.69,98.65 48.69,90.35 47.77,89.42 47.77,85.71 47.95,85.52 47.95,83.64 46.98,82.66 46.98,82.23 47.32,81.89 47.32,74.09 v1(49.3,72.11) ; v1(80.04,51.99) 80.04,52.35 v1(78.41,53.98) 78.09,53.98 76.44,52.32 76.44,49.44 78.95,46.93 78.95,41.21 81.48,38.68 81.48,35.92 65.6,20.04 v1(59.29,20.04) ; v1(62.15,69.42) 61.67,69.9 v1(61.67,73.91)
  BOTTOM w0.147: v1(49.3,72.11) 49.3,71.81 49.86,71.25 51.55,71.25 53.22,72.93 60.69,72.93 v1(61.67,73.91) 61.67,74.12 61.95,74.4 61.95,74.9 62.56,75.51 R5738.2 ; v1(59.29,20.04) 59.04,20.29 U3088.2 ; v1(80.04,51.99) 80.36,51.67 86.53,51.67 v1(86.99,51.2) ; v1(116.33,68.61) 116.68,68.26 116.68,64.86 112.73,60.91 106.8,60.91 105.41,62.31 87.88,62.31 87.05,61.47 86.16,61.47 80.85,66.78 v1(80.09,66.78) 74.6,66.78 72.39,68.99 68.88,68.99 68.55,69.32 67.59,69.32 67.21,69.7 62.43,69.7 v1(62.15,69.42) ; v1(25.32,132.79) 26.92,132.79 27.46,132.26 36.96,132.26 37.87,131.34 46.99,131.34 v1(47.85,130.48) 47.85,129.85 50.33,127.37 54.52,127.37 54.99,126.9 v1(57.71,126.9) 58.09,126.9 59.72,128.52 61.72,128.52 65,131.8 70.61,131.8 v1(70.94,132.13) 75.54,132.13 76.48,133.07 82.22,133.07 82.6,132.69 87.1,132.69 87.83,131.95 v1(89.13,131.95) ; v1(102.64,96.16) 107.01,96.16 v1(112.26,90.92) ; v1(66.85,155.85) 66.85,159.41 64.93,161.33 57.35,161.33 57.07,161.06 U75.2
RESETSTATZ_1V8_INV: length 67.8
  L03_SIG1 w0.091: v1(56.54,37.36) 56.54,38.53 60.28,42.27 60.28,49.97 60.43,50.12 60.43,52.1 60.15,52.37 60.15,59.66 55.58,64.23 54.87,64.23 v1(54.43,64.67)
  BOTTOM w0.147: v1(56.54,37.36) 58.65,37.36 65.41,30.61 65.41,23.01 64.47,22.07 58.83,22.07 58.39,22.51 U3088.4 58.39,23.86 57.73,24.51 R5845.2 57.73,26.45 R5832.1 ; v1(54.43,64.67) 53.82,64.06 51.77,64.06 51.53,64.29 R5844.1
RESETSTATZ_1V8_INV_RC: length 2.6
  BOTTOM w0.147: R5844.2 52.51,66.04 C3781.1 52.48,66.65 52.33,66.8 U3091.4
RGMII1_INH_3V3: length 3.3
  TOP w0.147: TP65.1 77.32,44.63 77.67,44.27 77.67,43.13 78.01,42.79 J18.26
RGMII1_RX_ER: length 12.1
  TOP w0.147: J18.39 80.81,40.22 v1(80.29,40.74) ; v1(79.4,49.83) 79.6,49.64 TP99.1
  L03_SIG1 w0.091: v1(79.4,49.83) 80.29,48.95 v1(80.29,40.74)
RGMII1_RX_LINK: length 27.6
  TOP w0.147: R360.2 64.59,44.42 TP98.1 63.75,43.58 v1(63.75,42.95) ; v1(80.21,37.19) 80.72,37.19 81.61,38.07 J18.43
  BOTTOM w0.147: v1(80.21,37.19) 79.12,37.19 78.47,37.84 75.46,37.84 74.79,37.17 65.42,37.17 63.75,38.84 v1(63.75,42.95)
RGMII2_INH_3V3: length 5.9
  TOP w0.147: J19.26 110.44,46.76 110.21,46.99 TP59.1
RGMII2_RX_ER: length 17.4
  TOP w0.147: TP89.1 117.91,47.07 v1(118.24,47.4) ; J19.39 113.24,36.67 v1(112.98,36.41)
  L03_SIG1 w0.091: v1(118.24,47.4) 116.18,45.34 116.18,40.74 112.98,37.54 v1(112.98,36.41)
RGMII2_RX_LINK: length 18.6
  TOP w0.147: J19.43 114.04,36.66 v1(113.78,36.4) ; v1(118.24,46.37) 117.75,45.87 116.8,45.87 TP91.1
  L03_SIG1 w0.091: v1(118.24,46.37) 116.76,44.89 116.76,40.92 113.78,37.94 v1(113.78,36.4)
  BOTTOM w0.147: R347.2 118.41,46.2 v1(118.24,46.37)
SD_MMC0_CLK: length 44.4
  TOP w0.147: U10.6 118.52,75.4 v1(118.99,74.93) 119.01,74.95 R54.1 119.57,74.29 119.35,74.07 R202.1
  L03_SIG1 w0.091: v1(118.99,74.93) 118.72,75.2 114.35,75.2 113.41,74.27 105.59,74.27 102.49,77.37 88.54,77.37 v1(87,75.82)
  BOTTOM w0.147: J26.5 121.25,77.03 120.73,76.5 120.73,75.35 120.31,74.93 v1(118.99,74.93) ; v1(87,75.82) 87,76.71 87.33,77.04 U57.41
SD_MMC0_CMD: length 43.5
  TOP w0.147: U10.1 116.49,76.9 116.31,77.09 v1(116.31,77.57) 116.07,77.57 115.84,77.33 R66.1
  L03_SIG1 w0.091: v1(116.31,77.57) 115.06,78.81 110.03,78.81 109.12,77.9 106.25,77.9 104.09,80.06 94.61,80.06 90.08,84.59 v1(90.08,85.63)
  BOTTOM w0.147: J26.3 121.06,74.83 120.04,73.81 117.6,73.81 116.99,74.42 116.99,76.88 v1(116.31,77.57) ; U57.23 v1(90.08,85.63)
SD_MMC0_D0: length 43
  TOP w0.147: U10.8 118.7,76.4 118.98,76.69 v1(118.98,76.83) R65.1
  L03_SIG1 w0.091: v1(118.98,76.83) 117.74,75.59 105.18,75.59 102.44,78.33 93.85,78.33 93.74,78.23 93.74,78.09 93.63,77.98 93.48,77.98 93.38,78.09 93.38,78.23 93.27,78.33 93.12,78.33 93.01,78.23 93.01,78.09 92.9,77.98 92.75,77.98 92.64,78.09 92.64,78.23 92.54,78.33 92.39,78.33 92.28,78.23 92.28,78.09 92.17,77.98 92.02,77.98 91.91,78.09 91.91,78.23 91.81,78.33 90.68,78.33 v1(90.25,77.9)
  BOTTOM w0.147: v1(90.25,77.9) 90.02,78.13 U57.38 ; v1(118.98,76.83) 118.54,76.39 118.54,75.66 118.78,75.42 119.85,75.42 120.17,75.74 120.17,76.45 120.73,77.01 120.73,78.33 121.62,79.23 J26.7
SD_MMC0_D1: length 42.6
  TOP w0.147: R57.1 119.56,75.9 v1(119.03,75.9) U10.7
  L03_SIG1 w0.091: v1(119.03,75.9) 119.52,75.9 119.66,76.05 119.66,76.91 119.1,77.47 118.08,77.47 116.59,75.97 110.08,75.97 109.3,76.76 105.05,76.76 102.97,78.84 90.45,78.84 v1(90.07,79.22)
  BOTTOM w0.147: v1(119.03,75.9) 119.49,75.9 119.65,76.07 119.65,78.81 121.18,80.33 J26.8 ; U57.36 89.98,79.13 v1(90.07,79.22)
SD_MMC0_D2: length 43
  TOP w0.147: R64.1 v1(116.29,76.4) U10.2
  L03_SIG1 w0.091: v1(91.31,82.3) 91.31,79.98 91.92,79.38 103.81,79.38 105.87,77.32 109.52,77.32 110.44,76.4 v1(116.29,76.4)
  BOTTOM w0.147: v1(91.31,82.3) 90.98,82.63 U57.29 ; v1(116.29,76.4) 115.52,75.64 115.52,73.53 116.42,72.63 J26.1
SD_MMC0_D3: length 44.2
  TOP w0.147: U10.3 116.43,75.9 116.28,75.76 116.28,75.03 v1(116.03,74.78) 115.93,74.78 115.63,75.07 R55.1
  L03_SIG1 w0.091: v1(116.03,74.78) 114.45,73.2 105.54,73.2 101.9,76.83 89.79,76.83 v1(87.86,74.9)
  BOTTOM w0.147: J26.2 121,73.73 120.47,73.2 117.14,73.2 116.03,74.32 v1(116.03,74.78) ; v1(87.86,74.9) 87.86,74.93 87.96,75.03 87.96,76.4 88.33,76.77 U57.39
SD_MMC0_SDCD: length 63.1
  TOP w0.147: U12.5 v1(110.73,78.13) R70.1 111.88,78.13 112.24,77.78 112.24,76.83 110.19,74.78 v1(110.19,68.91) ; U136.N2 v1(67.7,77.65)
  BOTTOM w0.147: J26.9 v1(110.73,78.13) ; v1(110.19,68.91) 108.92,67.64 102.16,67.64 101.4,66.88 100.1,66.88 99.54,66.32 86.89,66.32 82.27,70.94 82.27,71.96 79.4,74.83 75.9,74.83 75.49,75.23 71.7,75.23 71.32,75.62 71.32,76.16 70.9,76.58 69.62,76.58 69.49,76.45 68.33,76.45 67.7,77.08 v1(67.7,77.65)
SEC_REF_N: length 2.1
  TOP w0.147: U15.2 R74.1
SEC_REF_P: length 2.3
  TOP w0.147: U15.1 76.74,59.14 76.26,59.61 R73.1
SEL_XDS: length 59.1
  TOP w0.147: v1(24.1,104.32) 22.99,105.44 21.64,105.44 21.41,105.21 19.33,105.21 v1(18.97,104.85) 19.33,104.5 19.33,104.01 19.22,103.91 U39.5 ; v1(19.02,102.23) 19.02,101.75 17.63,100.36 17.63,99.74 15.7,97.81 v1(15.7,96.72)
  L03_SIG1 w0.091: v1(18.97,104.85) 18.67,104.55 18.67,102.59 v1(19.02,102.23) ; v1(24.1,104.32) 24.1,100.63 21.11,97.64 21.11,95.25 20.07,94.21 20.07,90.98 20.45,90.6 21.16,90.6 21.72,91.16 v1(24.56,91.16) 25.07,90.65 25.07,90.14 24.41,89.48 24.41,88.7 23.29,87.58 23.29,86.64 24.23,85.7 24.61,85.7 24.87,85.45 24.87,83.24 v1(22.94,81.31)
  BOTTOM w0.147: U97.1 23.63,91.38 23.85,91.16 v1(24.56,91.16) 24.64,91.24 24.64,91.6 24.46,91.78 U97.16 ; U93.4 17.51,94.27 17.31,94.47 15.94,94.47 15.45,94.97 15.45,96.47 v1(15.7,96.72) ; U109.4 21.89,82.73 21.64,82.48 21.64,82.09 22.43,81.31 v1(22.94,81.31)
SEL_XDS110_INV: length 79.7
  TOP w0.147: U2355.2 35.29,116.29 34.98,115.98 32.03,115.98 v1(31.57,116.43) ; v1(33.17,104.04) 33.2,104.06 33.2,104.11 33.26,104.18 J14.8 ; v1(19.28,95.55) 19.65,95.55 21.09,94.11 21.72,94.11 22.17,93.65 22.17,89.89 22.43,89.64 22.94,89.64 23.32,89.26 v1(24.87,89.26)
  L03_SIG1 w0.091: v1(19.28,95.55) 19.28,96.82 23.29,100.84 23.29,105.49 24.46,106.65 v1(24.46,114.1) ; v1(24.87,89.26) 24.87,88.67 23.57,87.38 23.57,86.77 24.36,85.98 24.74,85.98 25.15,85.57 25.15,83.21 25.35,83.01 v1(25.35,82.32) ; v1(31.57,116.43) 29.39,114.25 29.39,110.46 31.72,108.13 31.72,105.49 v1(33.17,104.04)
  BOTTOM w0.147: U90.4 33.7,105.38 33.17,104.85 v1(33.17,104.04) ; v1(24.46,114.1) 26.04,115.67 30.81,115.67 v1(31.57,116.43) ; v1(19.28,95.55) 19.28,95.35 19.1,95.17 R531.2 R536.1 18.17,94.4 17.63,94.95 17.18,94.95 16.86,95.27 U93.2 ; v1(24.87,89.26) 24.83,89.26 24.52,88.95 U102.5 ; U110.16 25.79,81.93 25.6,81.74 25.38,81.74 25.24,81.88 25.24,82.21 v1(25.35,82.32) 25.35,82.82 25.5,82.97 U110.1
SEL_XDS110_INV_3V3: length 17.9
  TOP w0.147: v1(36.22,114.33) 38.02,114.33 38.51,114.81 38.51,116.95 36.24,119.21 U2355.4 36.24,120.9 36.25,120.9 R5735.1
  BOTTOM w0.147: U87.2 31.74,114.46 31.51,114.7 31.51,115.02 31.98,115.49 33.28,115.49 33.68,115.09 35.46,115.09 v1(36.22,114.33) 36.22,113.87 36.22,113.87 36.22,113.16 36.37,113.01 U88.2
SOC_CLKIN: length 33.9
  TOP w0.147: R249.1 53.75,77.12 52.56,78.31 49.28,78.31 47.64,76.67 47.64,71.51 48.7,70.45 48.7,66.79 50.17,65.32 50.17,62.02 50.66,61.54 50.86,61.34 50.86,59.75 51.46,59.16 53.63,59.16 55.51,57.28 v1(56.9,57.28)
  BOTTOM w0.147: v1(56.9,57.28) 56.47,57.28 56.31,57.12 R349.2
SOC_DVDD1V8: length 92.2
  TOP w0.254: U56.24 33.31,56.86
  TOP w0.305: U136.K14 v1(64.5,88.05) ; v1(66.1,80.86) U136.M6 ; U136.F9 v1(61.3,84.06) ; 33.31,56.86 v1(33.5,56.67) ; v1(24.64,42.96) v1(25.19,42.96) ; U136.F8 v1(61.3,83.26) ; U136.E13 v1(61.3,86.45) U136.F12 ; U136.J14 v1(63.7,88.05) ; U136.J6 v1(63.7,80.86) ; U136.H14 v1(62.9,88.05) ; U136.K6 v1(65.3,80.86)
  L03_SIG1 w0.102: v1(63.7,80.86) 64.1,80.46 64.1,69.76 64.52,69.34 64.52,65.13 64.92,64.72 64.92,58.47 v1(63.91,57.45) ; v1(40.67,59.44) 38.76,57.53 34.37,57.53 v1(33.5,56.67)
  L03_SIG1 w0.254: 61.3,83.8 61.66,83.44 ; 61.3,83.8 v1(61.3,83.26) ; 61.3,83.8 v1(61.3,84.06) ; 61.3,83.8 60.93,83.44 ; v1(61.3,84.06) 60.84,83.6 ; v1(61.3,84.06) 61.75,83.6 ; 63.7,88.08 v1(63.7,88.05)
  L03_SIG1 w0.305: v1(63.7,80.86) 63.7,81.51
  L03_SIG1 w0.381: v1(64.5,88.05) v1(63.7,88.05) v1(62.9,88.05) v1(61.3,86.45) 60.75,87
  BOTTOM w0.102: v1(40.67,59.44) 41.78,58.32 42.72,58.32 44.37,56.67 44.37,54.33 43.38,53.34 43.38,48.69 43.81,48.26 46.25,48.26 48.16,50.16
  BOTTOM w0.127: 48.16,50.16 49.45,51.46 49.45,54.89 52.1,57.53 55.12,57.53 55.96,58.37 61.2,58.37 62.11,57.45 v1(63.91,57.45)
  BOTTOM w0.254: C461.1 64.79,88.05
  BOTTOM w0.305: C429.1 66.26,80.7 v1(66.1,80.86) ; v1(61.3,86.45) 60.98,86.45 C440.1 ; C437.1 63.59,80.75 v1(63.7,80.86) ; v1(61.3,84.06) 61.64,83.71 C502.1 ; 64.79,88.05 v1(64.5,88.05) 64.34,88.21 C453.1 63.94,88.05 v1(63.7,88.05) ; C506.1 65.45,80.7 v1(65.3,80.86)
  vias: v1(52.83,85.24) v1(52.83,84.79)
SOC_DVDD1V8_N: length 11.9
  TOP w0.147: v1(31.07,41.82) 31.53,42.29 32.71,42.29 33.28,42.86 33.28,43.3 33.07,43.51 32.86,43.51 R335.1
  BOTTOM w0.147: 31.04,40.32 31.31,40.06 U124.9 31.31,38.34 30.81,37.84 U123.D2 ; 31.04,40.32 31.07,40.35 C603.2 v1(31.07,41.82) ; 31.04,40.32 30.81,40.09 U124.8 30.81,38.38 30.41,37.98 U123.D1
SOC_DVDD1V8_P: length 8.9
  TOP w0.147: R331.1 32.86,43.86 33.22,43.86 33.63,43.45 33.63,42.71 32.75,41.83 v1(32.05,41.83)
  BOTTOM w0.147: U123.D3 31.21,37.65 31.81,38.25 U124.10 31.81,40.2 32.05,40.44 C603.1 v1(32.05,41.83)
SOC_DVDD3V3: length 58.1
  TOP w0.254: U56.22 33.41,55.86 v1(33.45,55.91)
  TOP w0.305: U136.P12 v1(68.5,85.65) U136.P11 v1(67.7,84.85) ; U136.H5 v1(62.9,80.06)
  L04_PWR1 w0.102: v1(33.45,55.91) 35.53,53.82 38.13,53.82 39.12,54.81 41.89,54.81 43.64,56.57 45.08,56.57 48.87,60.35 48.87,60.86 49.28,61.26 49.73,61.26 52.22,63.75 56.9,63.75 57.47,64.33 57.47,74.79 57.68,75.01 57.68,78.31 58.57,79.2 59.82,79.2 60.27,79.65 62.45,79.65
  L04_PWR1 w0.127: v1(62.9,80.06) 62.47,79.63 62.45,79.65
  BOTTOM w0.203: C451.1 62.72,79.87 v1(62.9,80.06)
  BOTTOM w0.305: v1(67.7,84.85) v1(68.5,85.65) ; v1(68.5,85.65) 68.68,85.65 C471.1 ; v1(68.5,85.65) 68.98,86.14 69.71,86.14 70.01,85.83 FL19.1
  vias: v1(43.73,55.98) v1(43.73,55.27)
SOC_DVDD3V3_FB1: length 1.4
  TOP w0.305: U136.R9 v1(69.3,83.26)
  BOTTOM w0.305: C3645.1 69.47,83.26 v1(69.3,83.26)
SOC_DVDD3V3_N: length 6.9
  BOTTOM w0.147: 45.66,56.12 45.66,56 45.36,55.7 U91.9 45.36,54.05 45.29,53.97 45.29,53.52 C428.2 45.34,52.94 45.34,52.35 45.68,52.01 R539.1 ; 45.66,56.12 45.84,56.3 45.84,56.61 U92.D2 U92.D1 ; 45.66,56.12 45.86,55.92 U91.8
SOC_DVDD3V3_P: length 5.4
  BOTTOM w0.147: R540.1 44.91,52.27 44.91,52.92 C428.1 44.94,53.52 44.94,53.97 44.86,54.05 U91.10 44.86,55.86 45.46,56.46 U92.D3
SOC_EMU0: length 94.7
  TOP w0.147: U136.C9 v1(58.9,84.06) ; SW3.1 26.41,101.73 25.98,102.16 22.82,102.16 v1(22.35,102.63) 22.03,102.95 R225.2 U39.2
  L03_SIG1 w0.091: v1(22.35,102.63) 22.35,101.73 21.54,100.91 18.49,100.91 17.55,99.97 17.55,95.85 19.2,94.2 19.2,89.05 20.88,87.37 v1(21.54,87.37)
  BOTTOM w0.132: v1(58.9,84.06) 58.25,84.06 57.84,83.64
  BOTTOM w0.147: 57.84,83.64 52.82,83.64 51.94,84.52 51.94,86.14 51.75,86.33 49.58,86.33 49.3,86.61 47.55,86.61 47.24,86.92 45.01,86.92 44.15,87.78 43.69,87.78 43,88.47 38.86,88.47 37.47,89.87 36.09,89.87 35.53,89.31 33.78,89.31 30.49,86.01 30.49,82.23 28.45,80.19 21.35,80.19 20.19,81.35 20.19,82.47 17.48,85.19 17.48,87.74 18.41,88.67 20.17,88.67 20.55,89.05 21.06,89.05 21.29,88.82 21.29,87.62 v1(21.54,87.37) 22.01,87.37 22.33,87.69 22.33,88.1 22.47,88.25 U102.2
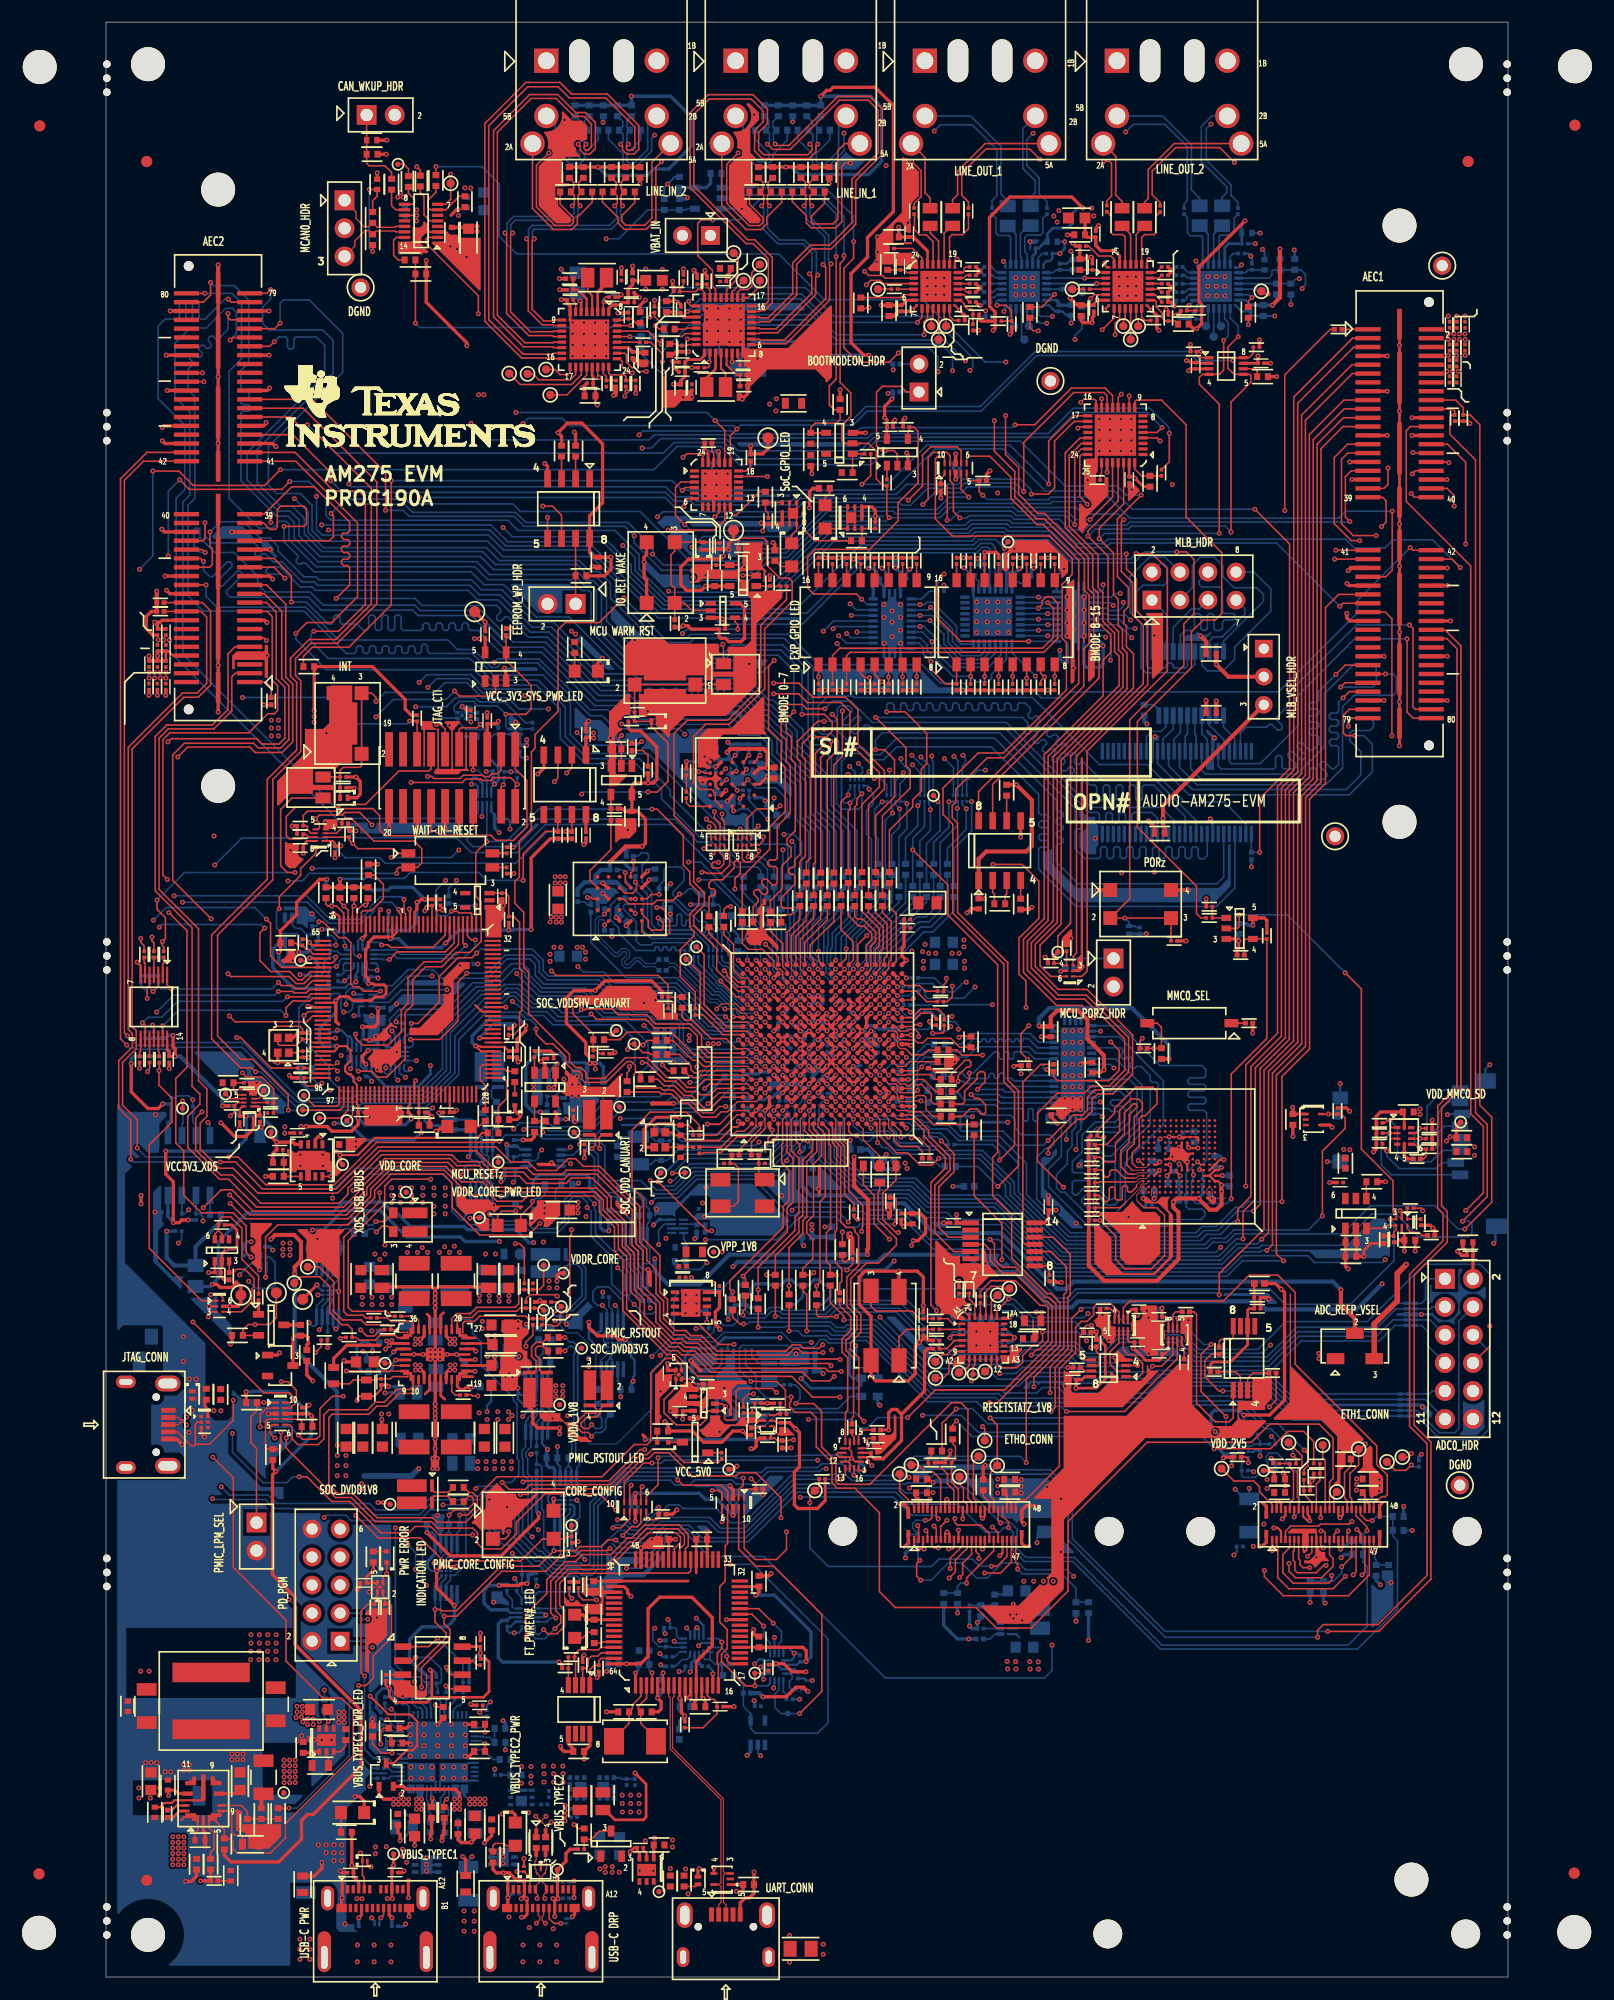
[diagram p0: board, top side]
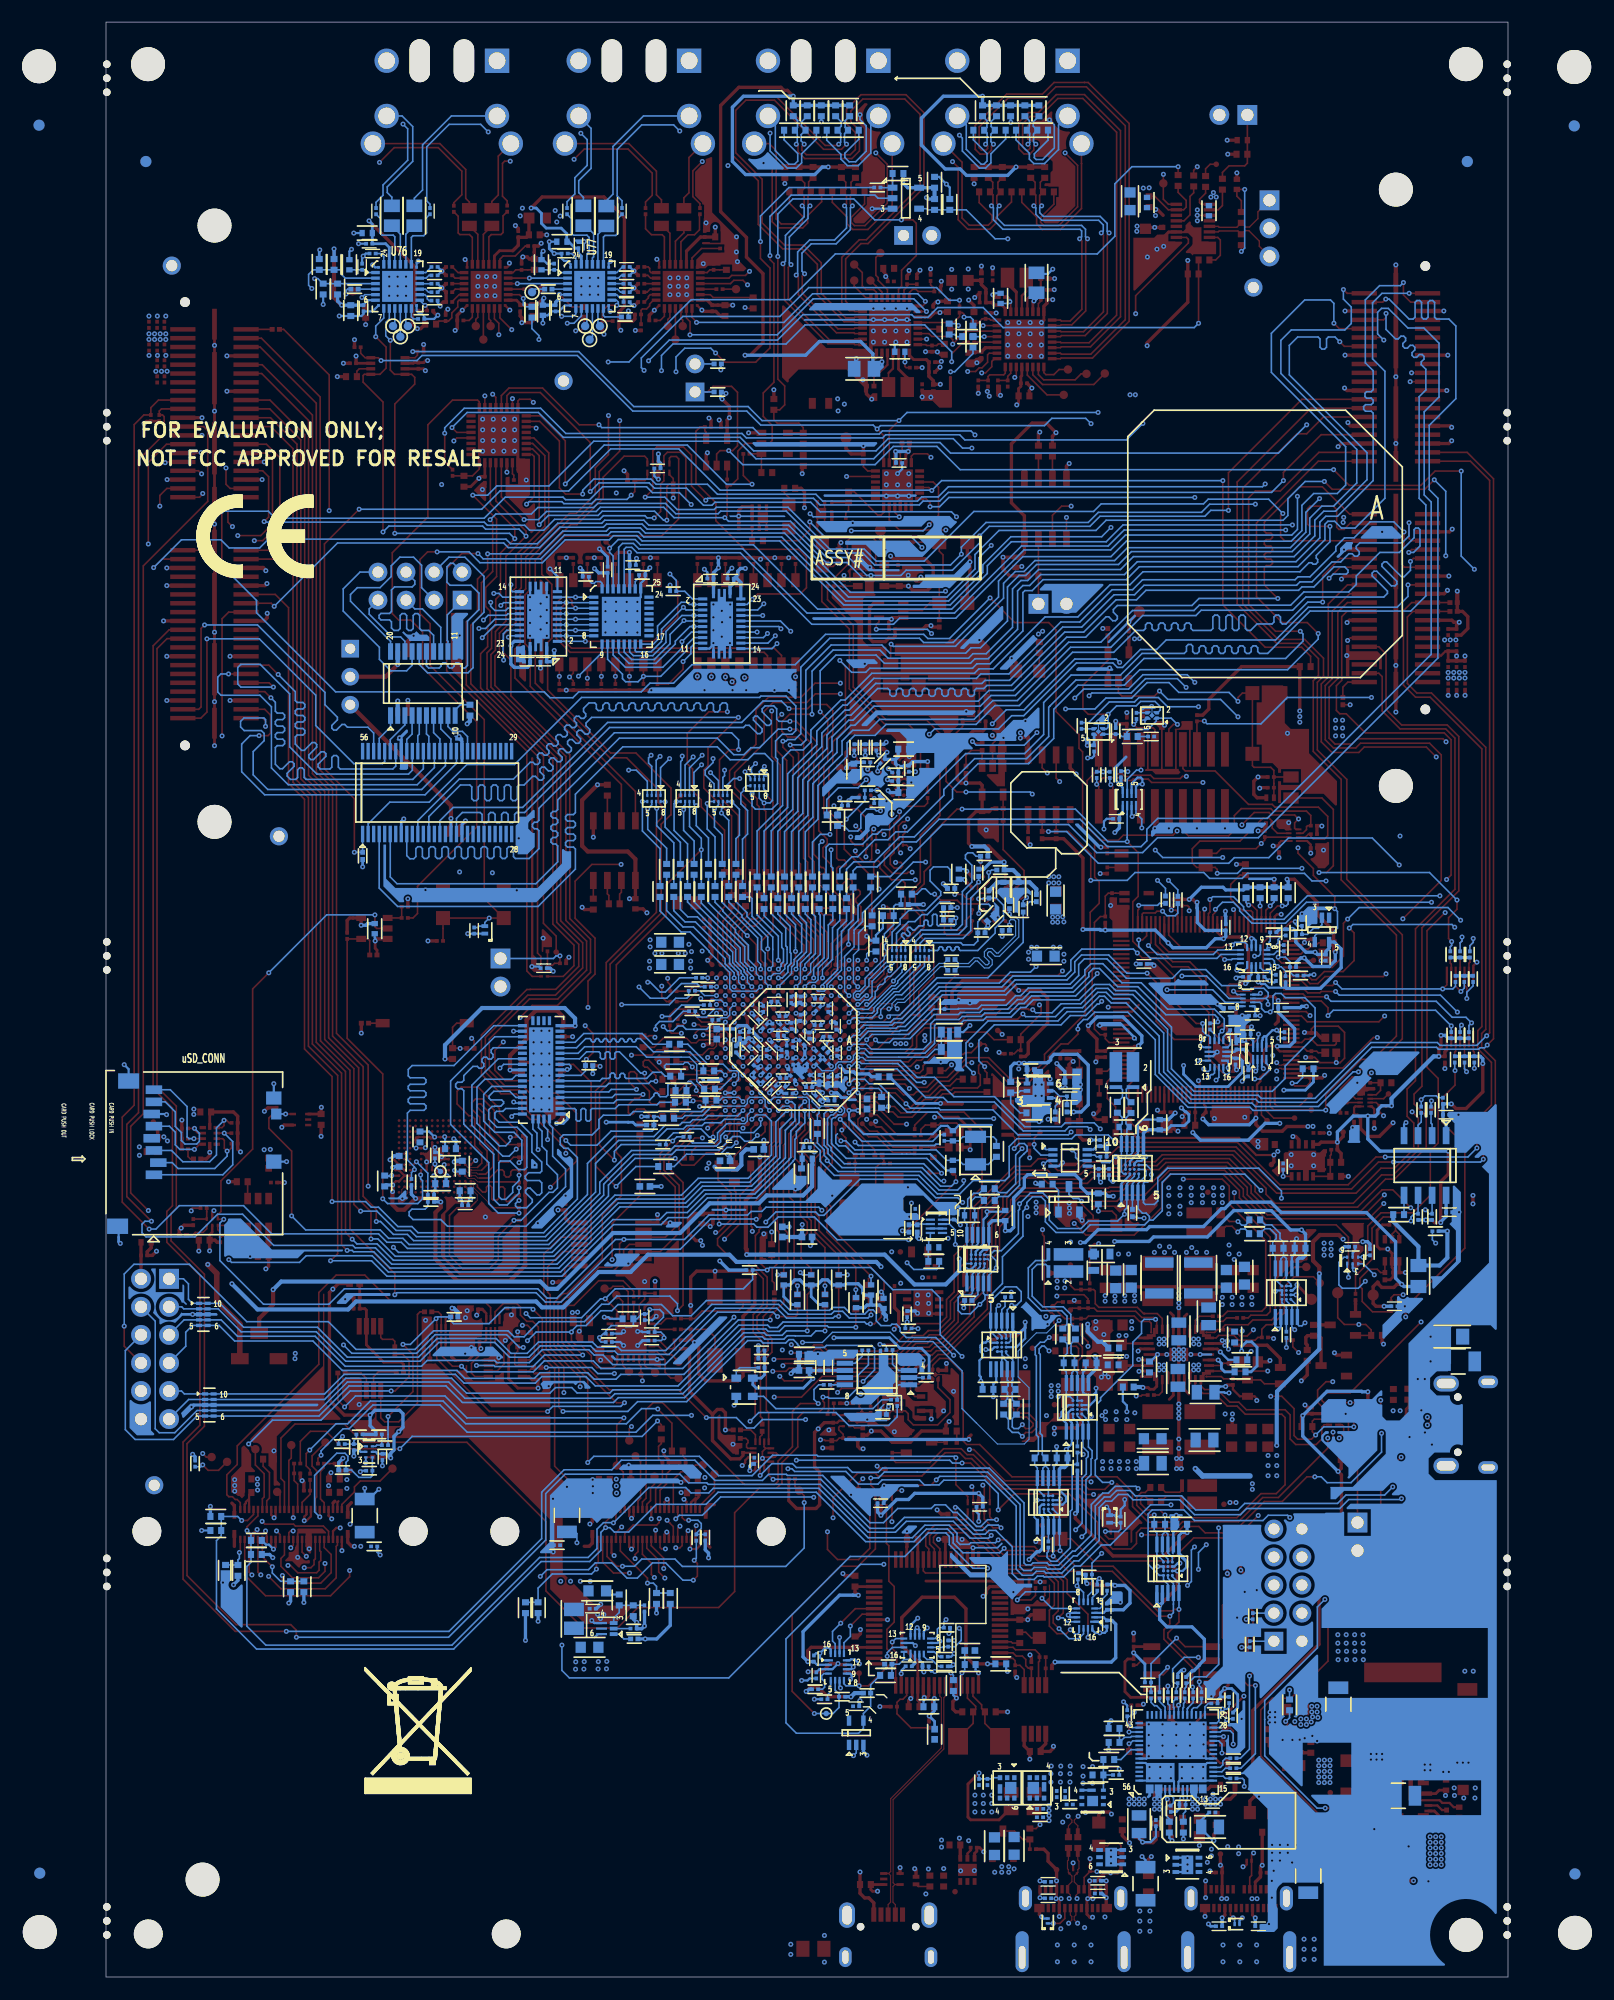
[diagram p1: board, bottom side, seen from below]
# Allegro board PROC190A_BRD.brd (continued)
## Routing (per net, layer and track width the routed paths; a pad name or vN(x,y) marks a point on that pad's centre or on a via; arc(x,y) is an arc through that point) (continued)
SOC_EMU1: length 82.9
  TOP w0.147: U136.C10 v1(58.9,84.85) ; U39.3 20.89,103.56 21.36,104.03 R220.2 21.36,104.65 21.64,104.93 22.2,104.93 24.28,102.84 27.91,102.84 28.6,102.16 28.6,100.86 28.2,100.46 SW3.2 26.53,100.46 26.34,100.28 v1(26.34,99.92)
  L03_SIG1 w0.091: v1(21.74,88.06) 21.74,88.44 19.48,90.7 19.48,94.31 17.88,95.91 17.88,99.59 v1(18.67,100.38)
  BOTTOM w0.147: U102.3 21.92,88.6 ; 21.92,88.6 21.73,88.79 21.73,89.13 22.12,89.52 23.28,89.52 23.44,89.36 23.98,89.36 24.38,89.76 25.93,89.76 27.38,91.21 29.62,91.21 30.4,90.42 34.57,90.42 36.32,92.18 38.38,92.18 38.89,91.67 38.89,90.68 39.67,89.89 44.53,89.89 45.49,88.93 51.23,88.93 54.46,85.7 55.04,85.7 55.12,85.62 57.94,85.62 58.71,84.85 v1(58.9,84.85) ; 21.92,88.6 21.74,88.41 v1(21.74,88.06) ; v1(26.34,99.92) 24.51,99.92 24.05,100.38 v1(18.67,100.38)
SOC_GPIO0_38: length 62.9
  TOP w0.147: v1(63.25,131.75) 63.25,131.01 64.21,130.05 R213.1 ; U136.K17 v1(64.5,90.45)
  L03_SIG1 w0.091: v1(53.09,129.44) 53.64,128.88 53.64,119.86 62.59,110.92 62.59,105.66 60.48,103.56 60.48,101.9 64.92,97.46 64.92,90.88 v1(64.5,90.45)
  BOTTOM w0.147: v1(63.25,131.75) 61.93,130.43 54.08,130.43 v1(53.09,129.44)
SOC_HYPERBUS0_DQ0: length 8.5
  TOP w0.147: v1(56.82,86.94) 57.3,86.94 57.39,86.85 U136.A13
  BOTTOM w0.132: v1(56.82,86.94) 56.82,87.58 55.47,88.93 54.97,88.93
  BOTTOM w0.147: RA8.8 52.46,91.38 54.91,88.93 54.97,88.93
SOC_HYPERBUS0_DQ1: length 10.6
  TOP w0.147: U136.D12 v1(59.7,86.45)
  BOTTOM w0.132: 57.95,86.85 59.3,86.85 v1(59.7,86.45) ; 54.81,89.56 55.17,89.2 55.6,89.2 57.07,87.73
  BOTTOM w0.147: 57.95,86.85 57.6,86.85 57.12,87.33 57.12,87.68 57.07,87.73 ; RA8.7 52.86,91.52 54.81,89.56
SOC_HYPERBUS0_DQ2: length 9.2
  TOP w0.147: U136.D13 v1(59.7,87.25)
  BOTTOM w0.132: v1(59.7,87.25) 59.3,87.65 58.47,87.65 58.42,87.6 57.96,87.6 55.82,89.74 55.54,89.74 55.28,90.01 55.28,90.17 54.89,90.56
  BOTTOM w0.147: 54.89,90.56 53.66,91.8 RA8.5
SOC_HYPERBUS0_DQ3: length 9
  TOP w0.147: U136.C13 v1(58.9,87.25)
  BOTTOM w0.132: v1(58.9,87.25) 57.63,87.25 57.43,87.45 57.43,87.76 55.7,89.48 55.41,89.48 54.88,90.02
  BOTTOM w0.147: 54.88,90.02 53.26,91.64 RA8.6
SOC_HYPERBUS0_DQ4: length 5.4
  TOP w0.147: v1(55.68,90.17) 57.11,88.74 57.41,88.74 U136.A15
  BOTTOM w0.132: 54.89,91.16 54.89,90.98 55.68,90.2 v1(55.68,90.17)
  BOTTOM w0.147: RA9.8 54.59,91.46 54.89,91.16
SOC_HYPERBUS0_DQ5: length 5.7
  TOP w0.147: U136.C15 v1(58.9,88.85)
  BOTTOM w0.132: RA9.5 55.79,92.07 56.01,91.85 56.36,91.85 57.89,90.32 57.89,89.74 58.77,88.85 v1(58.9,88.85)
SOC_HYPERBUS0_DQ6: length 6.6
  TOP w0.147: U136.B14 v1(58.1,88.05)
  BOTTOM w0.132: v1(58.1,88.05) 57.92,88.05 57.33,88.65 57.33,89.2 57.11,89.43 57.11,89.63 56.87,89.87 56.67,89.87 56.44,90.09 56.44,90.35 56.19,90.59 55.94,90.59 54.99,91.54 RA9.7
SOC_HYPERBUS0_DQ7: length 6.9
  TOP w0.147: U136.C14 v1(58.9,88.05)
  BOTTOM w0.132: 55.39,92.39 55.39,92.01 55.88,91.52 56.24,91.52 57.61,90.14 57.61,88.78 57.93,88.46 58.3,88.46 58.71,88.05 v1(58.9,88.05)
SOC_I2C0_SCL: length 476.7
  TOP w0.147: U2357.8 79.04,107.34 88.57,116.87 88.57,120.24 89.05,120.72 89.05,125.12 88.62,125.55 88.62,128.4 84.99,132.03 84.3,132.03 82.32,134.01 82.32,136.3 80.47,138.15 v1(80.47,140.92) ; v1(41.73,109.02) 42.2,109.49 U25.2 ; J19.40 113.24,41.75 114.22,40.76 v1(114.22,40.41) ; v1(27.97,26.72) 27.97,27.9 30.81,30.74 30.81,31.14 29.81,32.14 v1(29.81,33.28) 30.27,33.28 30.4,33.15 31.72,33.15 35.76,37.19 39.17,37.19 v1(40.58,38.6) 42.52,38.6 42.89,38.96 44.83,38.96 45.44,39.57 v1(46.18,39.57) ; J18.40 80.81,41.34 v1(81.04,41.11) ; v1(57.15,140.16) 56.55,139.56 U18.19 ; R56.2 103.93,147.02 103.52,146.61 U11.8 102.34,146.61 v1(102.08,146.35)
  L03_SIG1 w0.091: v1(32.31,72.64) 32.31,71.5 v1(34.75,69.06) ; v1(18.39,59.23) 19.84,60.68 19.84,69.82 v1(20.52,70.51) ; v1(80.47,140.92) 81.66,140.92 82.52,141.78 95.53,141.78 100.1,146.35 v1(102.08,146.35) ; v1(37.77,140.64) 38.38,140.03 38.38,118.31 41.73,114.96 v1(41.73,109.02) 41.73,108.43 40.03,106.73 40.03,97.87 41.96,95.94 41.96,90.2 44.64,87.51 44.64,86.88 42.72,84.96 42.72,82.14 43.23,81.64 43.23,77.19 41.64,75.6 41.64,74.9 41.96,74.57 42.16,74.57 44.25,72.49 v1(44.25,70) ; v1(40.58,38.6) 39.87,38.6 v1(38.61,39.85) 38.61,40.56 40.54,42.49 41.97,42.49 v1(42.65,43.17) 42.65,45.69 44.96,48.01 v1(44.96,60.81) 46.35,62.2 v1(46.35,64.21)
  BOTTOM w0.147: U3078.5 47.02,63.55 v1(46.35,64.21) 46.35,64.85 46.9,65.39 ; U118.1 42.64,41.34 42.91,41.62 42.91,42.91 v1(42.65,43.17) U119.C3 ; v1(40.58,38.6) 40.58,39.05 40.64,39.11 U118.5 40.64,41.77 U119.A1 ; v1(102.08,146.35) 98.83,146.35 98.37,146.81 84.31,146.81 79.28,141.78 68.96,141.78 67.69,140.51 57.51,140.51 v1(57.15,140.16) 56.85,140.46 41.99,140.46 41.33,141.12 38.25,141.12 v1(37.77,140.64) ; v1(38.61,39.85) 38.23,40.23 38.23,45.02 37.77,45.47 37.77,46.89 37.68,46.99 37.68,47.65 38.01,47.99 U116.5 38.01,50.28 38.2,50.47 38.2,50.57 U115.A1 ; v1(29.81,33.28) U124.5 29.81,35.66 30.41,36.26 U123.A1 ; v1(46.18,39.57) 46.43,39.32 48.67,39.32 48.82,39.17 49.64,39.17 49.91,39.44 49.91,40.18 50.63,40.91 52.82,40.91 53.96,39.77 57.96,39.77 62.43,44.25 71.98,44.25 72.4,43.83 74,43.83 74.49,44.31 77.84,44.31 v1(81.04,41.11) 81.06,41.14 81.93,41.14 82.52,40.55 82.52,38.79 83.33,37.98 87.72,37.98 95.66,30.05 112.52,30.05 114.24,31.76 114.24,37.17 113.87,37.54 R625.1 R622.2 113.87,40.05 v1(114.22,40.41) ; v1(18.39,59.23) 18.67,58.95 18.93,58.95 19.08,59.1 U114.5 19.08,60.76 U113.A1 ; v1(27.97,26.72) 27.97,26.37 27.76,26.16 R657.1 ; U92.A1 46.86,58.43 U91.5 46.86,61.17 45.54,62.48 44.53,62.48 44.1,62.05 44.1,61.23 44.52,60.81 v1(44.96,60.81) 45.36,60.4 U91.2 45.36,58.53 45.24,58.4 45.24,58.39 45.06,58.22 45.06,57.57 45.18,57.45 45.19,57.45 45.21,57.43 45.31,57.43 45.32,57.43 U92.B3 ; 46.9,65.39 U3080.A1 ; 46.9,65.39 46.53,65.76 45.9,65.76 44.35,67.31 44.35,69.4 44.25,69.51 v1(44.25,70) 43.26,70.99 43.24,70.99 43.23,70.99 42.14,70.99 41.55,70.41 41.55,68.53 40.79,67.77 38.68,67.77 38,68.45 35.36,68.45 v1(34.75,69.06) 34.75,69.42 34.52,69.64 U3079.2 34.52,71.83 33.85,72.5 U3081.B3 ; U3081.A1 32.75,73.52 32.31,73.08 v1(32.31,72.64) 32.31,72.29 32.63,71.97 32.93,71.97 33.02,71.88 U3079.5 33.02,70.11 32.86,69.95 32.03,69.95 31.72,70.26 31.72,72.34 30.84,73.23 22.58,73.23 20.52,71.17 v1(20.52,70.51)
SOC_I2C0_SDA: length 469.9
  TOP w0.147: J18.42 81.21,41.74 81.74,41.2 v1(81.74,40.68) ; v1(99.21,147.17) 99.19,147.17 99.18,147.17 R58.2 98.79,146.83 99.01,146.61 U11.1 ; U18.20 56.05,140.04 v1(55.17,140.92) ; v1(81.48,141.38) 81.48,137.85 82.68,136.65 82.68,134.24 84.4,132.51 85.01,132.51 88.98,128.55 88.98,125.69 89.48,125.18 89.48,120.7 89.95,120.23 89.95,117.61 80.31,107.98 U2357.7 ; v1(114.71,41.33) 114.18,41.33 113.64,41.88 J19.42 ; U25.3 40.93,108.55 v1(40.61,108.23) ; v1(28.58,26.25) 28.58,27.99 31.17,30.58 31.17,31.45 30.63,31.98 v1(30.63,32.66) 31.78,32.66 35.84,36.73 39.83,36.73 v1(41.2,38.1) 42.52,38.1 43.03,38.61 45.44,38.61 v1(45.64,38.81)
  L03_SIG1 w0.091: v1(81.48,141.38) 82.17,142.06 95.29,142.06 99.21,145.98 v1(99.21,147.17) ; v1(37.13,141.66) 37.13,140.36 37.9,139.6 37.9,118.19 40.84,115.24 40.84,108.46 v1(40.61,108.23) 39.62,107.24 39.62,95.54 41.68,93.48 41.68,90.07 44.37,87.38 44.37,87.02 42.19,84.84 42.19,81.36 41.81,80.98 41.81,78.89 42.9,77.81 42.9,77.27 41.36,75.73 41.36,75.73 41.35,75.72 41.35,74.78 41.99,74.14 42.19,74.14 43.59,72.75 v1(43.59,69.67) ; v1(46.13,60.81) 46.22,60.9 v1(47.84,60.9) 47.84,60.46 45.67,58.29 45.67,48.18 43.18,45.69 43.18,43.03 42.19,42.04 40.72,42.04 v1(39.17,40.49) 39.17,40.06 40.08,39.14 40.64,39.14 41.2,38.58 v1(41.2,38.1) ; v1(22.38,71.22) 22.02,70.86 22.02,61.31 v1(19.32,58.61)
  BOTTOM w0.147: U119.A2 41.64,42.18 41.14,41.68 U118.4 41.14,38.52 41.2,38.45 v1(41.2,38.1) ; v1(114.71,41.33) 115.07,41.7 R616.1 R618.2 116.56,39.93 116.99,39.5 116.99,33.32 113.36,29.69 95.5,29.69 87.58,37.62 83.19,37.62 82.17,38.63 82.17,40.26 v1(81.74,40.68) 81.35,40.68 80.95,40.29 79.65,40.29 77.14,42.79 72.65,42.79 71.55,43.89 62.66,43.89 58.19,39.42 53.81,39.42 52.67,40.56 50.78,40.56 50.26,40.04 50.26,39.29 49.38,38.41 46.05,38.41 v1(45.64,38.81) ; 47.38,61.75 47.52,61.89 U3078.4 47.52,63.63 46.94,64.21 46.94,64.83 47.1,64.99 U3080.A2 ; 47.38,61.75 47.38,61.36 v1(47.84,60.9) 48.69,60.05 49.5,60.05 49.81,60.35 49.81,61.52 49.58,61.75 48.66,61.75 48.52,61.89 U3078.2 48.52,63.62 47.82,64.32 U3080.B3 ; 47.38,61.75 46.83,61.75 45.8,62.79 45.8,65.21 43.94,67.07 43.94,69.32 v1(43.59,69.67) 43.59,70.13 43.08,70.63 42.29,70.63 41.91,70.26 41.91,68.38 40.94,67.41 38.53,67.41 37.85,68.1 32.92,68.1 32.49,68.53 ; v1(19.32,58.61) 19.58,58.86 U114.4 19.58,60.72 20.08,61.22 U113.A2 ; v1(30.63,32.66) 30.31,32.99 30.31,33.76 30.31,33.76 U124.4 30.31,35.61 30.81,36.11 U123.A2 ; 32.49,68.53 32.16,68.53 31.32,69.37 31.32,71.96 30.58,72.69 23.85,72.69 v1(22.38,71.22) ; 32.49,68.53 32.49,68.87 32.78,69.16 33.12,69.16 33.52,69.57 U3079.4 33.52,71.84 32.79,72.57 32.79,72.97 32.94,73.12 U3081.A2 ; v1(37.13,141.66) 54.43,141.66 v1(55.17,140.92) 67.56,140.92 68.83,142.19 79.19,142.19 84.17,147.17 v1(99.21,147.17) ; U115.A2 39.01,50.79 38.51,50.29 U116.4 38.51,47.99 38.03,47.51 38.03,47.13 38.2,46.96 38.2,45.54 38.58,45.16 38.58,41.08 v1(39.17,40.49) ; U92.A2 45.86,58.02 46.36,58.52 U91.4 46.36,60.57 v1(46.13,60.81) ; v1(28.58,26.25) 28.52,26.2 R656.1
SOC_MMC0_CLK: length 4.1
  TOP w0.132: v1(73.81,79.32) 73.1,79.32 73.04,79.26 71.93,79.26 71.69,79.5 71.69,79.93 71.3,80.33 U136.V5
  BOTTOM w0.147: R558.2 73.94,79.2 v1(73.81,79.32)
SOC_MMC0_CMD: length 10.6
  BOTTOM w0.147: U57.14 84.51,84.63 83.72,85.42 78.44,85.42 77.47,84.45 R5819.1
SOC_MMC0_CMD_R: length 8.1
  TOP w0.147: U136.T6 v1(70.1,80.86)
  BOTTOM w0.132: v1(70.1,80.86) 69.7,81.25 69.7,81.92 69.83,82.05 70.49,82.05 71.09,82.65 72.49,82.65 72.9,83.06
  BOTTOM w0.147: 72.9,83.06 74.29,84.45 R5819.2
SOC_MMC0_DAT0: length 13.7
  TOP w0.147: v1(78.36,79.91) 78.71,79.55 79.1,79.55 79.68,78.97 79.68,78.25 79.53,78.11 79.29,78.11 79.15,78.25 79.15,78.36 78.92,78.59 78.26,78.59 77.6,77.93 R5811.1
  BOTTOM w0.147: U57.4 81.15,79.63 80.87,79.91 v1(78.36,79.91)
SOC_MMC0_DAT0_R: length 5
  TOP w0.132: 74.9,77.93 74.27,78.56 74.27,79.65 74.11,79.81 73.46,79.81 73.31,79.66 U136.W4
  TOP w0.147: 74.9,77.93 R5811.2
SOC_MMC0_DAT1: length 13.9
  TOP w0.147: R5812.1 77.6,79.04 77.77,79.22 77.77,80.19 78.92,81.33 78.92,81.74 79.15,81.97 79.48,81.97 79.63,81.82 79.63,81.05 v1(78.95,80.36)
  BOTTOM w0.147: U57.5 81.46,80.13 81.23,80.36 v1(78.95,80.36)
SOC_MMC0_DAT1_R: length 4.8
  TOP w0.132: U136.W5 73.06,80.46 73.41,80.8 73.89,80.8 74.75,79.93 74.75,79.27 74.9,79.12
  TOP w0.147: R5812.2 74.98,79.04 74.9,79.12
SOC_MMC0_DAT2: length 13.4
  TOP w0.147: v1(78.21,81.84) 78.21,81.25 77.11,80.16 R5813.1
  BOTTOM w0.147: U57.11 84.1,83.13 83.46,83.77 82.35,83.77 82.22,83.64 82.22,83.24 82.09,83.11 81.91,83.11 81.78,83.24 81.78,83.64 81.65,83.77 81.47,83.77 81.34,83.64 81.34,83.24 81.21,83.11 81.03,83.11 80.9,83.24 80.9,83.64 80.77,83.77 80.49,83.77 78.56,81.84 v1(78.21,81.84)
SOC_MMC0_DAT2_R: length 5.2
  TOP w0.132: U136.V6 71.53,81.26 71.93,80.85 72.41,80.85 72.54,80.72 72.85,80.72 73.38,81.25 74.07,81.25 74.9,80.42
  TOP w0.147: R5813.2 75.16,80.16 74.9,80.42
SOC_MMC0_DAT3: length 12.7
  BOTTOM w0.147: R5814.1 75.4,80.76 75.55,80.9 75.97,80.9 76.1,80.77 76.1,79.86 76.25,79.71 76.8,79.71 76.93,79.83 76.93,79.91 77.06,80.04 77.25,80.04 77.38,79.91 77.38,79.78 77.73,79.43 80.72,79.43 81.01,79.13 U57.3
SOC_MMC0_DAT3_R: length 6
  TOP w0.132: v1(73.53,80.26) 73.51,80.26 73.3,80.06 71.93,80.06 71.7,80.29 71.7,80.7 71.54,80.86 70.89,80.86 U136.U6
  BOTTOM w0.147: v1(73.53,80.26) 73.53,80.62 74,81.09 74.24,81.09 74.42,80.9 R5814.2
SOC_MMC0_DAT4: length 16.9
  BOTTOM w0.147: R5815.1 72.89,82.53 74.12,83.77 77.42,83.77 78.61,84.96 78.89,84.96 79,84.86 79,84.78 79.1,84.67 79.26,84.67 79.36,84.78 79.36,84.86 79.47,84.96 79.62,84.96 79.73,84.86 79.73,84.78 79.84,84.67 79.99,84.67 80.1,84.78 80.1,84.86 80.21,84.96 80.36,84.96 80.47,84.86 80.47,84.78 80.58,84.67 80.73,84.67 80.84,84.78 80.84,84.86 80.94,84.96 81.1,84.96 81.2,84.86 81.2,84.78 81.31,84.67 81.47,84.67 81.57,84.78 81.57,84.86 81.68,84.96 81.83,84.96 81.94,84.86 81.94,84.78 82.05,84.67 82.2,84.67 82.31,84.78 82.31,84.86 82.42,84.96 82.57,84.96 82.68,84.86 82.68,84.78 82.79,84.67 82.94,84.67 83.05,84.78 83.05,84.86 83.15,84.96 83.54,84.96 84.37,84.13 U57.13
SOC_MMC0_DAT4_R: length 1.7
  TOP w0.132: U136.U7 v1(70.9,81.66)
  BOTTOM w0.147: R5815.2 71.28,82.04 v1(70.9,81.66)
SOC_MMC0_DAT5: length 15.8
  BOTTOM w0.132: R5816.1 72.81,80.43 73.48,81.1 73.48,82.63 74.14,83.29 74.9,83.29
  BOTTOM w0.147: U57.12 84.24,83.63 83.64,84.23 78.97,84.23 78.03,83.29 74.9,83.29
SOC_MMC0_DAT5_R: length 2.8
  TOP w0.147: U136.T7 v1(70.1,81.66)
  BOTTOM w0.132: 70.99,80.77 v1(70.1,81.66)
  BOTTOM w0.147: 70.99,80.77 71.36,80.39 R5816.2
SOC_MMC0_DAT6: length 14.1
  TOP w0.147: v1(77.19,81.1) 77.19,81.61 77.95,82.37 78.19,82.37 78.33,82.52 78.33,82.86 78.19,83.01 77.83,83.01 76.6,81.77 R5817.1
  BOTTOM w0.147: U57.6 81.72,80.63 81.46,80.9 77.85,80.9 77.65,81.1 v1(77.19,81.1)
SOC_MMC0_DAT6_R: length 4.7
  TOP w0.132: 72.86,81.7 72.46,81.7 72.41,81.65 71.7,81.65 71.69,81.66
  TOP w0.147: 72.86,81.7 74.66,81.7 75.08,81.28 R5817.2 ; 71.69,81.66 U136.V7
SOC_MMC0_DAT7: length 11.7
  BOTTOM w0.147: U57.7 82.27,81.13 82.04,81.36 81.46,81.36 81.33,81.49 81.33,81.71 81.2,81.84 81.02,81.84 80.89,81.71 80.89,81.49 80.76,81.36 80.58,81.36 80.45,81.49 80.45,81.68 80.32,81.81 80.14,81.81 80.01,81.68 80.01,81.49 79.88,81.36 78.03,81.36 77.47,81.92 76.7,81.92 76.34,81.56 R5818.1
SOC_MMC0_DAT7_R: length 7
  TOP w0.132: U136.W7 73.55,82.06 v1(73.89,82.4)
  BOTTOM w0.132: 74.9,82.64 74.72,82.64 74.56,82.8 74.3,82.8 v1(73.89,82.4)
  BOTTOM w0.147: 74.9,82.64 76.26,82.64 76.4,82.49 76.4,82.35 76.26,82.2 75.05,82.2 74.91,82.05 R5818.2
SOC_OSPI_CLK: length 6.4
  TOP w0.132: 56.85,92.25 56.85,91.14 57.54,90.45 58.1,90.45 U136.B17
  TOP w0.147: 56.85,92.25 56.85,93.49 55.96,94.37 R197.2
SOC_OSPI_DQ0: length 26.8
  TOP w0.132: U136.B16 58.1,89.65 57.29,89.65 56.26,90.68 56.26,90.85 v1(56,91.11)
  TOP w0.147: v1(53.98,100.03) 54.33,100.03 54.43,99.92 55.75,99.92 56.49,100.66 56.49,101.57 56.02,102.05 RA3.8
  L03_SIG1 w0.091: v1(56,91.11) 53.62,91.11 53.01,91.72 53.01,92.46 53.12,92.57 53.69,92.57 53.8,92.68 53.8,92.83 53.69,92.94 53.12,92.94 53.01,93.04 53.01,93.19 53.12,93.3 53.69,93.3 53.8,93.41 53.8,93.56 53.69,93.67 53.12,93.67 53.01,93.77 53.01,93.93 53.12,94.03 53.69,94.03 53.8,94.14 53.8,94.29 53.69,94.4 53.12,94.4 53.01,94.51 53.01,94.66 53.12,94.76 53.69,94.76 53.8,94.87 53.8,95.02 53.69,95.13 53.12,95.13 53.01,95.24 53.01,95.39 53.12,95.5 53.69,95.5 53.8,95.6 53.8,95.75 53.69,95.86 53.35,95.86 53.24,95.97 53.24,96.57 53.44,96.77 53.44,97.92 54.36,98.83 54.36,99.65 v1(53.98,100.03)
SOC_OSPI_DQ1: length 25
  TOP w0.147: v1(55.48,100.92) 55,100.92 54.86,100.77 54.86,100.55 55,100.41 55.6,100.41 55.96,100.76 55.96,101.45 55.62,101.79 RA3.7 ; U136.D17 v1(59.7,90.45)
  L03_SIG1 w0.091: v1(55.48,100.92) 56.16,100.23 56.16,99.57 56.06,99.46 55.93,99.46 55.82,99.35 55.82,99.2 55.93,99.09 56.06,99.09 56.16,98.99 56.16,98.84 56.06,98.73 55.93,98.73 55.82,98.62 55.82,98.47 55.93,98.36 56.06,98.36 56.16,98.26 56.16,98.1 56.06,98 55.93,98 55.82,97.89 55.82,97.74 55.93,97.63 56.06,97.63 56.16,97.52 56.16,95.37 56.06,95.26 55.05,95.26 54.94,95.15 54.94,95 55.05,94.89 56.06,94.89 56.16,94.79 56.16,94.63 56.06,94.53 55.05,94.53 54.94,94.42 54.94,94.27 55.05,94.16 56.06,94.16 56.16,94.05 56.16,93.7 56.06,93.59 55.38,93.59 55.27,93.49 55.27,93.33 55.38,93.23 56.06,93.23 56.16,93.12 56.16,92.37 57.68,90.86 59.3,90.86 v1(59.7,90.45)
SOC_OSPI_DQ2: length 20.8
  TOP w0.147: RA3.6 55.22,101.98 v1(55.02,101.78) ; U136.C17 v1(58.9,90.45)
  L03_SIG1 w0.091: v1(55.02,101.78) 55.02,100.71 55.55,100.18 55.55,98.63 54.66,97.74 54.66,97.52 54.77,97.41 55.52,97.41 55.63,97.31 55.63,97.16 55.52,97.05 54.77,97.05 54.66,96.94 54.66,96.79 54.77,96.68 55.52,96.68 55.63,96.57 55.63,96.42 55.52,96.32 54.77,96.32 54.66,96.21 54.66,96.06 54.77,95.95 55.52,95.95 55.63,95.84 55.63,95.69 55.52,95.58 54.77,95.58 54.66,95.48 54.66,93.42 57.63,90.45 v1(58.9,90.45)
SOC_OSPI_DQ3: length 21.9
  TOP w0.147: RA3.5 54.48,102.49 v1(54.15,102.16) ; v1(59.7,89.65) U136.D16
  L03_SIG1 w0.091: v1(59.7,89.65) 59.3,90.06 57.59,90.06 54.2,93.45 54.2,97.99 55.19,98.98 55.19,100 54.25,100.94 53.62,100.94 52.91,101.65 52.91,102.92 53.21,103.23 53.87,103.23 54.15,102.95 v1(54.15,102.16)
SOC_OSPI_DQ4: length 17.4
  TOP w0.147: RA4.8 59.16,102.49 59.54,102.87 v1(59.54,103.23) ; U136.E16 v1(60.5,89.65)
  L03_SIG1 w0.091: v1(60.5,89.65) 60.12,90.03 60.12,90.96 61.62,92.46 61.62,99.85 59.97,101.5 59.97,102.8 v1(59.54,103.23)
SOC_OSPI_DQ5: length 19.9
  TOP w0.147: 58.04,102.49 58.04,102.13 58.17,102.01 v1(58.17,101.42) ; U136.B18 v1(58.1,91.26)
  L03_SIG1 w0.091: v1(58.17,101.42) 58.47,101.12 58.47,100.66 58.58,100.55 58.73,100.55 58.83,100.46 58.83,100.28 58.73,100.19 58.58,100.19 58.47,100.08 58.47,99.93 58.58,99.82 58.9,99.82 59.01,99.71 59.01,99.56 58.9,99.45 58.58,99.45 58.47,99.35 58.47,99.2 58.58,99.09 58.9,99.09 59.01,98.98 59.01,98.83 58.9,98.72 58.58,98.72 58.47,98.62 58.47,98.46 58.58,98.36 58.9,98.36 59.01,98.25 59.01,98.1 58.9,97.99 58.58,97.99 58.47,97.88 58.47,97.73 58.58,97.63 58.9,97.63 59.01,97.52 59.01,97.37 58.9,97.26 58.58,97.26 58.47,97.15 58.47,97 58.58,96.89 58.9,96.89 59.01,96.79 59.01,96.64 58.9,96.53 58.58,96.53 58.47,96.42 58.47,96.27 58.58,96.16 58.9,96.16 59.01,96.06 59.01,95.9 58.9,95.8 58.58,95.8 58.47,95.69 58.47,95.54 58.58,95.43 58.9,95.43 59.01,95.32 59.01,95.17 58.9,95.06 58.58,95.06 58.47,94.96 58.47,94.81 58.58,94.7 58.9,94.7 59.01,94.59 59.01,94.44 58.9,94.33 58.58,94.33 58.47,94.23 58.47,94.07 58.58,93.97 58.87,93.97 58.96,93.88 58.96,93.73 58.83,93.6 58.58,93.6 58.47,93.49 58.47,91.63 v1(58.1,91.26)
SOC_OSPI_DQ6: length 25.6
  TOP w0.147: RA4.6 57.64,101.21 57.88,100.97 58.35,100.97 59.12,101.74 v1(59.12,101.96) ; U136.D18 v1(59.7,91.26)
  L03_SIG1 w0.091: v1(59.12,101.96) 59.12,101.54 60.33,100.34 60.33,99.84 60.43,99.74 60.93,99.74 61.04,99.63 61.04,99.48 60.93,99.37 60.43,99.37 60.33,99.26 60.33,99.11 60.43,99.01 60.9,99.01 61.01,98.9 61.01,98.75 60.9,98.64 60.43,98.64 60.33,98.53 60.33,98.38 60.43,98.27 60.9,98.27 61.01,98.17 61.01,98.02 60.9,97.91 60.43,97.91 60.33,97.8 60.33,97.65 60.43,97.54 60.9,97.54 61.01,97.44 61.01,97.28 60.9,97.18 60.43,97.18 60.33,97.07 60.33,96.92 60.43,96.81 60.9,96.81 61.01,96.7 61.01,96.55 60.9,96.45 60.43,96.45 60.33,96.34 60.33,96.19 60.43,96.08 60.9,96.08 61.01,95.97 61.01,95.82 60.9,95.71 60.43,95.71 60.33,95.61 60.33,95.46 60.43,95.35 60.9,95.35 61.01,95.24 61.01,95.09 60.9,94.98 60.43,94.98 60.33,94.88 60.33,94.72 60.43,94.62 60.9,94.62 61.01,94.51 61.01,94.36 60.9,94.25 60.43,94.25 60.33,94.14 60.33,93.99 60.43,93.89 60.9,93.89 61.01,93.78 61.01,93.63 60.9,93.52 60.43,93.52 60.33,93.41 60.33,91.88 v1(59.7,91.26)
SOC_OSPI_DQ7: length 23.1
  TOP w0.147: U136.C18 v1(58.9,91.26) ; RA4.5 57.24,102.04 v1(57.1,101.9)
  L03_SIG1 w0.091: v1(57.1,101.9) 58.37,101.9 59.28,100.99 59.28,99.99 59.39,99.88 59.89,99.88 60.02,99.75 60.02,99.61 59.93,99.52 59.39,99.52 59.28,99.41 59.28,99.26 59.39,99.15 59.89,99.15 59.99,99.05 59.99,98.89 59.89,98.79 59.39,98.79 59.28,98.68 59.28,98.53 59.39,98.42 59.89,98.42 59.99,98.31 59.99,98.16 59.89,98.06 59.39,98.06 59.28,97.95 59.28,97.8 59.39,97.69 59.89,97.69 59.99,97.58 59.99,97.43 59.89,97.32 59.39,97.32 59.28,97.22 59.28,97.07 59.39,96.96 59.89,96.96 59.99,96.85 59.99,96.7 59.89,96.59 59.39,96.59 59.28,96.49 59.28,96.33 59.39,96.23 59.89,96.23 59.99,96.12 59.99,95.97 59.89,95.86 59.39,95.86 59.28,95.75 59.28,95.6 59.39,95.5 59.89,95.5 59.99,95.39 59.99,95.24 59.89,95.13 59.39,95.13 59.28,95.02 59.28,94.87 59.39,94.76 59.89,94.76 59.99,94.66 59.99,94.51 59.89,94.4 59.39,94.4 59.28,94.29 59.28,91.64 v1(58.9,91.26)
SOC_PORZ: length 218.2
  TOP w0.147: v1(13.14,65.17) 12.7,65.61 12.7,67.99 11.51,69.19 8.63,69.19 7.04,70.78 7.04,74.8 6.32,75.51 6.32,81.36 7.34,82.37 7.34,94.73 v1(5.69,96.37) ; U43.3 87.61,92.41 87.91,92.71 87.91,110.54 94.36,116.99 94.36,122.68 93.34,123.7 93.34,126.57 92.43,127.48 v1(92.43,128.85) ; v1(16.64,135.41) 15.93,134.7 7.54,134.7 v1(6.68,135.56)
  L03_SIG1 w0.091: v1(5.69,96.37) 5.16,96.37 3.46,98.07 3.46,116.22 4.42,117.17 5.59,117.17 6.91,118.49 6.91,127.41 v1(5.64,128.68)
  BOTTOM w0.147: U86.4 v1(13.14,65.17) 12.97,65.34 R480.2 ; v1(92.43,128.85) 87.68,128.85 85.62,130.91 81.69,130.91 81.4,131.2 78.59,131.2 78.13,130.73 65.53,130.73 59.74,124.94 50.83,124.94 48.29,127.48 48.29,128.79 46.1,130.97 37.33,130.97 36.41,131.9 20.37,131.9 19.94,132.33 19.94,133.84 18.37,135.41 v1(16.64,135.41) ; v1(5.64,128.68) 5.64,134.52 v1(6.68,135.56)
SOC_PORZ_PB: length 160.7
  TOP w0.147: U43.1 88.38,90.59 88.88,91.08 88.88,111 96.14,118.26 96.14,127.51 94.77,128.88 v1(93.31,128.88) ; R268.2 v1(42.93,75.39) 42.93,75.96 TP55.1
  L03_SIG1 w0.091: v1(42.93,75.39) 43.87,76.33 43.87,81.81 43.31,82.37 43.31,84.73 45.21,86.64 45.21,87.81 43.81,89.2 43.81,91.08 44.2,91.47 44.2,93.62 42.8,95.02 42.8,104.88 45.21,107.29 45.21,114.99 44.48,115.72 44.48,124.49 46.81,126.82 v1(46.81,129.62)
  BOTTOM w0.147: v1(42.93,75.39) 42.93,75.03 42.31,74.42 U98.2 ; v1(93.31,128.88) 92.83,128.4 87.63,128.4 85.47,130.56 81.53,130.56 81.24,130.85 78.75,130.85 78.28,130.38 65.79,130.38 59.99,124.59 50.67,124.59 47.93,127.33 47.93,128.5 v1(46.81,129.62)
SOC_RGMII_MDC: length 81.3
  TOP w0.147: R548.2 77.07,83.94 77.55,83.46 v1(79.4,83.46) ; R352.1 108.51,45.93 108.86,46.28 108.86,47.39 v1(108.54,47.71) ; R338.1 75.74,50.14 v1(77.02,51.43)
  L03_SIG1 w0.091: v1(79.4,83.46) 80.11,82.75 80.11,75.51 79.93,75.34 79.93,68.35 80.52,67.77 80.52,65.33 80.44,65.25 80.44,64.64 80.67,64.41 80.67,56.29 80.24,55.85 80.24,53.34 80.62,52.95 80.62,51.82 80.23,51.43 v1(77.02,51.43)
  BOTTOM w0.147: v1(77.02,51.43) 77.05,51.46 78.49,51.46 79.86,50.09 94.41,50.09 96.47,52.15 103.05,52.15 105.11,50.09 106.16,50.09 v1(108.54,47.71)
SOC_RGMII_MDIO: length 79
  TOP w0.147: R541.2 77.87,85.16 77.79,85.23 77.43,85.23 v1(77.28,85.08) ; R340.1 76.7,50 v1(77.04,50.34) ; R345.1 109.4,48.49 108.48,49.4 107.06,49.4 105.49,47.83 v1(100.38,47.83)
  L03_SIG1 w0.091: v1(77.04,50.34) 77.77,51.07 80.27,51.07 80.9,51.71 80.9,53.09 80.52,53.47 80.52,55.7 80.95,56.13 80.95,64.54 80.72,64.77 80.72,65.13 80.8,65.2 80.8,67.89 80.21,68.48 80.21,75.06 80.39,75.23 80.39,83.08 78.39,85.08 v1(77.28,85.08)
  BOTTOM w0.147: v1(77.04,50.34) 78.44,48.95 99.26,48.95 v1(100.38,47.83)
SOC_TCK: length 51.9
  TOP w0.147: U136.A10 v1(57.3,84.85)
  L03_SIG1 w0.091: v1(20.83,93.42) 21.34,92.91 21.82,92.91 22.3,93.4 24.38,93.4 25.02,92.76 25.65,92.76 26.75,91.67 26.75,86.94 v1(26.29,86.49)
  BOTTOM w0.147: R544.1 20.78,93.43 20.79,93.42 v1(20.83,93.42) 20.83,93.93 20.46,94.3 R534.1 ; v1(57.3,84.85) 57.05,84.61 56.03,84.61 55.68,84.96 54.18,84.96 51.99,87.15 49.78,87.15 49.61,87.33 47.85,87.33 47.55,87.63 45.31,87.63 44.45,88.49 43.99,88.49 43.31,89.18 39.37,89.18 37.97,90.58 37.97,90.91 37.57,91.31 37.01,91.31 35.36,89.66 33.53,89.66 30.99,87.12 26.57,87.12 26.29,86.84 v1(26.29,86.49) 26.43,86.35 R566.1
SOC_TDI: length 59.6
  TOP w0.147: v1(27.58,84.89) 30.23,84.89 31.88,86.54 31.88,90.07 v1(32.69,90.88) ; U136.D10 v1(59.7,84.85)
  L03_SIG1 w0.091: v1(27.58,84.89) 27.28,84.89 25.86,86.31 25.86,88.82 26.14,89.1 26.14,91.03 24.1,93.07 22.45,93.07 v1(20.88,91.49)
  BOTTOM w0.132: v1(59.7,84.85) 59.29,85.26 58.73,85.26 58.09,85.9 55.42,85.9 55.27,86.06
  BOTTOM w0.147: 55.27,86.06 54.61,86.06 51.38,89.28 45.64,89.28 44.65,90.27 39.95,90.27 39.24,90.98 39.24,91.92 38.63,92.53 36.17,92.53 34.52,90.88 v1(32.69,90.88) ; v1(27.58,84.89) 27.83,84.64 27.83,84.41 27.6,84.17 U110.9 ; U97.6 21.35,92.18 21.16,91.99 21.16,91.77 v1(20.88,91.49) 20.85,91.47 20.54,91.47 20.15,91.07 R554.1
SOC_TDO: length 72.1
  TOP w0.147: v1(22.86,82.02) 24.05,82.02 24.59,81.48 25.45,81.48 27.1,83.13 27.1,87.33 27.79,88.01 27.79,90.3 28.96,91.47 30.43,91.47 31.72,92.76 32.97,92.76 33.99,93.78 33.99,97.36 33.5,97.84 33.5,101.81 v1(34.49,102.8) ; v1(49.45,105.74) 49.91,105.74 52.3,103.35 52.3,100.66 52.88,100.08 52.88,98.98 53.7,98.17 53.7,97.05 52.88,96.24 52.88,95.05 53.26,94.67 53.26,94.26 52.01,93.01 52.01,90.56 53.37,89.2 R542.1
  BOTTOM w0.147: v1(49.45,105.74) 39.19,105.74 36.25,102.8 v1(34.49,102.8) 34.49,103.15 34.5,103.16 34.5,105.26 34.5,105.27 U90.2 ; U109.2 22.69,82.48 22.69,82.47 22.69,82.14 22.81,82.02 v1(22.86,82.02)
SOC_TMS: length 56
  TOP w0.147: U136.C11 v1(58.9,85.65) ; v1(27.66,86.33) 28.24,86.33 30.18,88.27 30.18,90.58 31.88,92.28 33.15,92.28 v1(33.58,92.71)
  L03_SIG1 w0.091: v1(21.64,93.34) 22.75,94.46 24.57,94.46 27.03,92 27.03,86.97 v1(27.66,86.33)
  BOTTOM w0.132: 55.75,86.23 55.8,86.18 58.37,86.18 v1(58.9,85.65)
  BOTTOM w0.147: 55.75,86.23 55.58,86.41 54.76,86.41 51.54,89.64 45.85,89.64 44.86,90.63 40.1,90.63 39.6,91.13 39.6,92.08 38.61,93.07 33.93,93.07 v1(33.58,92.71) ; U97.8 21.83,93.15 v1(21.64,93.34) 21.64,93.7 21.55,93.79 R533.1 ; v1(27.66,86.33) 27.66,85.65 27.26,85.25 27.12,85.25 26.98,85.11 U110.8
SOC_TRST#: length 50.6
  TOP w0.147: U136.B10 v1(58.1,84.85)
  L03_SIG1 w0.091: v1(22.96,92.43) 24.28,92.43 25.81,90.91 25.81,89.18 25.45,88.82 25.45,86.11 v1(25.91,85.65)
  BOTTOM w0.132: v1(58.1,84.85) 57.61,85.34 55.17,85.34
  BOTTOM w0.147: 55.17,85.34 54.31,85.34 52.02,87.63 R564.1 49.81,87.63 49.76,87.68 48.01,87.68 47.7,87.99 45.47,87.99 44.6,88.85 44.15,88.85 43.46,89.53 39.52,89.53 38.33,90.73 38.33,91.19 37.77,91.74 36.7,91.74 34.98,90.02 33.22,90.02 30.84,87.63 26.59,87.63 25.7,86.74 25.7,85.85 v1(25.91,85.65) 26.19,85.37 U110.6 ; v1(22.96,92.43) 22.61,92.43 22.43,92.61 U97.9
SOC_UART0_RXD: length 30.9
  TOP w0.132: 66.1,76.79 66.1,77.65 U136.L2
  TOP w0.147: R5734.2 67.56,50.6 67.72,50.75 67.72,56.06 67.03,56.74 67.03,57.63 68.02,58.62 68.02,59.82 67.11,60.73 67.11,63.36 68.17,64.43 68.17,67.13 67.84,67.46 67.84,67.67 67.64,67.87 67.06,67.87 66.55,68.38 66.55,75.18 66.1,75.63 66.1,76.79
SOC_UART0_RXD_XDS: length 119.6
  TOP w0.147: U2353.13 66.97,45.46 v1(66.57,45.06)
  L03_SIG1 w0.091: v1(31.75,99.29) 31.79,99.29 34.16,96.92 34.16,93.24 34.95,92.46 34.95,77.57 31.88,74.5 31.88,70.63 33.4,69.12 33.4,68.19 32.51,67.31 27.99,67.31 24.56,63.88 24.56,58.37 24.26,58.06 23.72,58.06 22.83,57.18 22.83,56.46 24.03,55.27 25.27,55.27 27.1,53.44 27.1,45.36 29.72,42.75 v1(30.53,42.75)
  BOTTOM w0.147: R5730.1 31.03,98.57 v1(31.75,99.29) ; v1(66.57,45.06) 62.24,45.06 57.81,40.62 55.66,40.62 54.68,41.61 49.95,41.61 48.44,40.09 47.36,40.09 47.02,40.43 46.4,40.43 44.91,38.95 44.91,36.53 44.37,35.99 42.93,35.99 42.62,36.3 42.09,36.3 42.01,36.22 40.26,36.22 39.27,37.21 38.73,37.21 36.83,39.12 36.01,39.12 32.38,42.75 v1(30.53,42.75)
SOC_UART0_TXD: length 13.9
  TOP w0.147: U2353.8 66.97,51.1 67.18,51.31 67.18,56.06 66.67,56.57 66.67,57.78 67.46,58.57 67.46,59.79 66.46,60.8 R5732.2
SOC_UART0_TXD_XDS: length 122.5
  TOP w0.147: U2353.15 67.77,45.47 67.74,45.44 v1(67.74,45.42)
  L03_SIG1 w0.091: v1(30.76,99.29) 30.76,98.35 32,97.1 32,93.32 31.62,92.94 31.62,84.1 32.58,83.14 32.58,76.02 31.17,74.6 31.17,68.86 30.68,68.38 26.34,68.38 23.65,65.68 23.65,58.57 22.4,57.33 22.4,56.41 23.9,54.91 25.2,54.91 26.72,53.39 26.72,45.16 29.59,42.3 31.58,42.3 v1(33.5,44.22)
  BOTTOM w0.147: R5731.1 29.91,98.44 v1(30.76,99.29) ; v1(33.5,44.22) 33.71,44.42 35.59,44.42 36.2,43.81 36.71,43.81 37.74,42.78 37.74,40.03 39.22,38.56 39.45,38.56 40.72,37.29 41.55,37.29 41.76,37.49 43.03,37.49 43.21,37.31 43.67,37.31 43.84,37.49 43.84,42.93 46.99,46.08 56.67,46.08 57.05,45.69 59.39,45.69 59.82,46.13 64.47,46.13 64.81,46.47 66.68,46.47 v1(67.74,45.42)
SOC_USB0_DM: length 88.3
  TOP w0.107: L10.4 39.82,13.69 39.5,14.01 39.5,14.2 v1(39.85,14.55) ; U136.W9 v1(72.5,83.26)
  L03_SIG1 w0.094: v1(39.85,14.55) 39.55,14.86 39.55,15.98 40.36,16.8 42.94,16.8 52.59,26.44 53.11,26.44 54.55,27.89 54.55,32.23 66.05,43.73 66.05,49.85 71.59,55.39 71.59,62.1 73.85,64.36 73.85,76.71 72.43,78.13 72.43,80.57 71.82,81.18 71.82,81.69 72.2,82.06 72.2,82.95 v1(72.5,83.26)
SOC_USB0_DP: length 88.4
  TOP w0.107: U136.V9 v1(71.7,83.26) ; L10.1 38.97,13.69 39.28,14.01 39.28,14.21 v1(38.94,14.55)
  L03_SIG1 w0.094: v1(71.7,83.26) 71.95,83 71.95,82.16 71.58,81.79 71.58,81.07 72.19,80.46 72.19,78.03 73.61,76.6 73.61,64.47 71.35,62.21 71.35,55.49 65.81,49.95 65.81,43.84 54.31,32.33 54.31,27.99 53,26.69 52.48,26.69 42.84,17.04 40.26,17.04 39.3,16.09 39.3,14.92 v1(38.94,14.55)
SOC_USB0_DRVVBUS: length 17.6
  TOP w0.132: 74.52,76.66 74.52,76.19 74.9,75.81
  TOP w0.147: 74.9,75.81 76.45,74.26 76.45,73.05 75.08,71.68 75.08,67.39 76.79,65.68 U3077.5 ; U136.W2 73.13,78.05 74.52,76.66
SOC_USB0_DRVVBUS_3V3: length 138.2
  TOP w0.147: v1(84.05,53.44) 84.05,54.28 86.77,57 86.77,61.77 86.99,62 86.99,64.3 85.61,65.68 U3077.10
  L03_SIG1 w0.091: v1(85.7,30.05) 87.15,31.5 87.15,49.02 84.05,52.12 v1(84.05,53.44) ; v1(47.14,37.01) 46.91,36.78 46.91,33.79 37.07,23.95 35.05,23.95 33.48,22.38 25.88,22.38 25.76,22.25 25.46,22.25 23.89,20.69 v1(23.89,17.26) 24.72,17.26 25.93,18.47 34.86,18.47 v1(35.21,18.82)
  BOTTOM w0.147: v1(23.89,17.26) 23.89,17.82 24.05,17.98 R674.1 ; v1(85.7,30.05) 85.7,27.76 85.02,27.08 70.58,27.08 59.59,38.07 54.64,38.07 52.5,40.21 50.92,40.21 50.61,39.89 50.61,39.15 48.47,37.01 v1(47.14,37.01) ; R673.1 v1(35.21,18.82)
SOC_USB0_RCALIB: length 4.4
  TOP w0.132: 74.88,82.87 72.84,82.87 72.43,82.46 71.69,82.46 U136.V8
  TOP w0.147: 74.88,82.87 R553.1
SOC_USB0_VBUS: length 116.7
  TOP w0.147: U136.U9 v1(70.9,83.26) ; v1(42.39,13.8) 42.75,13.44 R398.1 ; R560.1 71.41,70.59 71.58,70.42 71.58,68.65 71.45,68.53 v1(71.45,68.17)
  L03_SIG1 w0.091: v1(42.39,13.8) 41.98,13.39 38.89,13.39 37.85,14.42 37.85,15.7 39.01,16.87 39.01,19.41 48.46,28.85 50.9,28.85 53.03,30.98 53.03,32.66 57.07,36.7 57.07,38.61 60.55,42.09 60.55,49.86 61.14,50.44 62.33,50.44 62.73,50.04 63.8,50.04 64.05,50.29 64.05,55.68 62.69,57.05 62.69,59.23 58.04,63.88 56.62,63.88 55.99,64.51 55.2,64.51 54.31,65.41 v1(54.31,66.75) ; v1(70.9,83.26) 70.52,82.88 70.52,81.47 71.4,80.59 71.4,79.1 71.91,78.59 71.91,76.68 72.39,76.2 72.39,75.9 71.91,75.41 71.91,68.63 v1(71.45,68.17)
  BOTTOM w0.147: v1(71.45,68.17) 68.33,68.17 68.05,67.89 67.03,67.89 66.12,68.81 62.82,68.81 60.76,66.75 v1(54.31,66.75)
SOC_VDD_CANUART: length 10.4
  TOP w0.305: U136.F6 v1(61.3,81.66)
  TOP w0.381: 49.48,79.07 49.5,79.1 v1(51.41,79.1)
  L03_SIG1 w0.132: 60.86,80.52 60.86,81.02 61.3,81.46 v1(61.3,81.66) 61.75,81.2
  BOTTOM w0.254: v1(51.41,79.1) 53.62,79.1 R3731.1
  BOTTOM w0.305: C224.1 61.44,81.51 v1(61.3,81.66)
SOC_VDD_CANUART_N: length 8.3
  BOTTOM w0.147: 48.52,66.17 48.24,66.17 48.02,66.39 U3078.8 ; 48.52,66.17 U3078.9 48.52,68.12 48.31,68.33 C3761.2 48.31,69.49 48.59,69.77 48.59,70.28 48.26,70.61 47.78,70.61 R5780.1 ; 48.52,66.17 48.62,66.07 U3080.D1 U3080.D2
SOC_VDD_CANUART_P: length 8.5
  BOTTOM w0.147: R5781.1 47.88,70.96 48.41,70.96 48.94,70.42 48.94,69.77 49.23,69.49 C3761.1 49.23,68.38 49.02,68.17 U3078.10 49.02,66.22 49.25,65.99 49.25,64.77 49.07,64.59 U3080.D3
SOC_VDDSHV5_SDIO: length 57.4
  TOP w0.305: v1(68.5,83.26) U136.R8 ; v1(68.5,84.06) U136.P9
  TOP w0.381: v1(68.96,65.41) 68.96,65.87 69.04,65.95 69.04,70.36 67.77,71.63 v1(67.77,74.24)
  L03_SIG1 w0.254: 68.71,83.67 68.5,83.88 v1(68.5,84.06)
  L04_PWR1 w0.381: v1(38.07,59.11) 39.54,59.11 40.12,58.52 42.04,58.52 43.08,59.56 43.08,62.02 44.68,63.62 44.68,67.51 45.47,68.3 46.43,68.3 v1(49.71,65.02)
  BOTTOM w0.381: C3655.1 68.67,84.23 v1(68.5,84.06) ; v1(68.96,65.41) 56.46,65.41 53.76,62.71 50.93,62.71 49.71,63.93 v1(49.71,65.02) ; v1(38.07,59.11) 38.07,58.45 37.15,57.52 36.74,57.52 36.21,56.99 R243.2
SOC_VDDSHV_CANUART: length 3.4
  TOP w0.305: v1(45.82,85.34) 46.18,85.7 TP597.1 ; U136.F7 v1(61.3,82.46)
  L03_SIG1 w0.127: 60.9,81.82 60.9,81.49 60.63,81.23 60.05,81.23
  L03_SIG1 w0.132: 59.92,81.36 60.05,81.23
  L03_SIG1 w0.191: 60.9,82.05 v1(61.3,82.46)
  BOTTOM w0.254: C512.1 61.49,82.65 v1(61.3,82.46)
  vias: v1(53.52,82.4)
SOC_VDDSHV_CANUART_N: length 6.9
  BOTTOM w0.147: 34.52,74.4 34.65,74.27 U3081.D1 U3081.D2 ; 34.52,74.4 34.25,74.4 34.02,74.62 U3079.8 ; 34.52,74.4 U3079.9 34.52,76.75 C3763.2 34.6,77.25 34.6,77.78 R5784.1
SOC_VDDSHV_CANUART_P: length 6.2
  BOTTOM w0.147: U3081.D3 34.82,72.72 35.02,72.92 U3079.10 35.02,76.75 C3763.1 34.95,77.25 34.95,77.82 R5785.1
SPI0_CLK: length 124.8
  TOP w0.147: v1(100.84,61.77) 100.84,63.68 104.9,67.74 104.9,82.09 107.57,84.76 107.57,107.21 109,108.65 109,139.63 112.15,142.78 J12.17 ; R216.1 67.75,68.75 67.9,68.61 v1(68.1,68.61)
  BOTTOM w0.147: v1(68.1,68.61) 68.12,68.63 72.24,68.63 74.98,65.89 81,65.89 85.78,61.11 87.2,61.11 88.04,61.95 100.66,61.95 v1(100.84,61.77)
SPI0_CLK_R: length 8.3
  TOP w0.147: U136.M1 66.5,75.64 66.9,75.23 66.9,70.84 67.75,69.99 R216.2
SPI0_CS0: length 132.9
  TOP w0.147: U136.J3 v1(63.7,78.46) ; v1(106.65,64.85) 106.01,65.49 106.01,81.63 108.66,84.28 108.66,106.78 110.06,108.18 110.06,138.38 112.06,140.38 J12.23
  BOTTOM w0.147: v1(63.7,78.46) 63.7,77.32 64.47,76.55 64.47,75.97 64.59,75.84 64.59,74.07 64.74,73.91 64.74,73.86 68.07,70.54 72.52,70.54 74.3,68.76 76.07,68.76 76.71,68.12 81.03,68.12 85.7,63.45 101.55,63.45 102.95,64.85 v1(106.65,64.85)
SPI0_CS1: length 148.7
  TOP w0.147: J12.24 118.15,140.38 117.78,140.01 117.78,133.6 123.62,127.76 123.62,78.16 124.76,77.02 124.76,70.99 v1(123.16,69.39) ; U136.J4 v1(63.7,79.26)
  L03_SIG1 w0.091: v1(115.87,64.95) 115.87,66.02 118.66,68.81 122.58,68.81 v1(123.16,69.39)
  BOTTOM w0.147: v1(115.87,64.95) 115.63,64.7 109.47,64.7 108.87,65.3 102.89,65.3 101.42,63.83 85.83,63.83 81.08,68.58 76.84,68.58 76.2,69.22 74.35,69.22 72.67,70.89 68.22,70.89 65.1,74.02 65.1,74.07 64.96,74.2 64.96,76.62 64.21,77.37 64.21,78.74 v1(63.7,79.26)
SPI0_D0: length 128.6
  TOP w0.147: J12.19 112.16,141.98 109.35,139.17 109.35,108.49 107.95,107.09 107.95,84.63 105.31,81.99 105.31,67.41 v1(104.7,66.8) ; U136.K3 v1(65.3,78.46)
  BOTTOM w0.147: v1(65.3,78.46) 66.32,77.43 66.32,74.32 68.68,71.96 73.13,71.96 74.65,70.43 80.75,70.43 86.28,64.9 100.97,64.9 102.44,66.37 104.27,66.37 v1(104.7,66.8)
SPI0_D1: length 131.5
  TOP w0.147: J12.21 112.1,141.18 109.7,138.79 109.7,108.33 108.31,106.93 108.31,84.48 105.66,81.84 105.66,66.29 v1(105.16,65.79) ; U136.K4 v1(65.3,79.26)
  BOTTOM w0.147: v1(105.16,65.79) 104.7,65.79 104.57,65.66 102.74,65.66 101.27,64.19 85.98,64.19 80.44,69.72 74.35,69.72 72.82,71.25 68.38,71.25 65.46,74.16 65.46,76.65 64.59,77.52 64.59,78.97 64.88,79.26 v1(65.3,79.26)
SPI1_CLK: length 169
  TOP w0.132: 74.6,74.42 74.6,75.03 73.66,75.97 v1(72.97,75.97)
  TOP w0.147: v1(11.25,70.03) 12.63,68.65 21.94,68.65 23.98,70.69 23.98,71.34 25.68,73.04 30.65,73.04 32.91,70.79 34.87,70.79 35.43,70.23 37.69,70.23 38.17,70.71 44.18,70.71 44.7,70.19 44.7,69.27 46.06,67.91 46.06,65.71 46.81,64.97 46.81,60.33 50.79,56.36 51.63,56.36 53.6,54.38 62.12,54.38 64,52.5 v1(66.47,52.5) ; v1(5.56,99.36) 5.16,99.77 5.16,112.02 5.78,112.64 12.92,112.64 14.65,114.37 15.24,114.37 15.54,114.67 15.54,116.92 15.06,117.4 15.06,123.16 14.58,123.64 J13.17 ; 74.6,74.42 R5659.1
  L03_SIG1 w0.091: v1(5.56,99.36) 6.78,99.36 8.99,97.16 8.99,81.03 9.67,80.35 9.67,76.95 8.86,76.15 8.86,72.42 v1(11.25,70.03) ; v1(66.47,52.5) 70.94,56.97 70.94,62.42 72.52,63.99 72.52,67.51 73.2,68.2 73.2,75.74 v1(72.97,75.97)
SPI1_CLK_R: length 6.3
  TOP w0.132: 71.4,75.74 71.4,76.4 70.89,76.91 70.89,77.66 U136.U2
  TOP w0.147: 71.4,75.74 71.96,75.18 73.51,75.18 73.94,74.75 R5659.2
SPI1_CS0: length 171.3
  TOP w0.147: v1(66.6,54.84) 65.41,54.84 65.13,55.12 54.91,55.12 53.36,56.67 52.31,56.67 51.92,57.06 51.08,57.06 48.36,59.78 48.36,61.22 47.51,62.06 47.51,65.39 46.76,66.14 46.76,68.2 45.4,69.56 45.4,70.48 44.46,71.43 36.19,71.43 36.12,71.5 35.1,71.5 33.5,73.1 31.62,73.1 30.98,73.74 25.39,73.74 23.27,71.62 23.27,70.97 21.65,69.35 13.32,69.35 11.41,71.27 10.44,71.27 v1(8.81,69.65) ; J13.23 14.55,126.04 16.28,124.31 16.28,117.7 16.92,117.07 16.92,111.84 15.95,110.87 13.51,110.87 13.03,111.36 7.4,111.36 v1(6.5,110.46) ; U136.U1 70.5,76.42 v1(70.87,76.05)
  L03_SIG1 w0.091: v1(66.6,54.84) 66.96,54.84 69.14,57.02 69.14,64.14 69.8,64.8 69.8,71.66 70.1,71.96 70.1,74.6 70.87,75.36 v1(70.87,76.05) ; v1(6.5,110.46) 4.88,108.84 4.88,99.44 5.55,98.78 6.96,98.78 8.64,97.1 8.64,80.8 9.3,80.14 9.3,78.23 8.2,77.14 8.2,70.26 v1(8.81,69.65)
SPI1_CS1: length 80.1
  TOP w0.147: v1(9.06,126.04) J13.24 ; U136.D15 v1(59.7,88.85)
  L03_SIG1 w0.091: v1(52.42,112.52) 52.15,112.25 52.15,101.55 v1(52.76,100.94)
  BOTTOM w0.132: 59.23,94.49 59.23,93.27 60.09,92.41 60.09,89.25 v1(59.7,88.85)
  BOTTOM w0.147: v1(9.06,126.04) 9.06,125 10.04,124.02 18.09,124.02 21.06,121.06 30.96,121.06 31.83,120.19 33.3,120.19 34.92,118.57 35.38,118.57 35.79,118.97 39.09,118.97 43.87,114.2 44.96,114.2 46.15,113 51.94,113 v1(52.42,112.52) ; v1(52.76,100.94) 53.87,100.94 58.47,96.34 58.47,95.55 59.23,94.79 59.23,94.49
SPI1_D0: length 166.3
  TOP w0.147: U136.T3 v1(70.1,78.46) ; v1(66.5,55.91) 66.45,55.96 55.06,55.96 53.65,57.37 52.6,57.37 52.21,57.76 51.37,57.76 49.81,59.32 49.81,60.83 48.21,62.43 48.21,65.69 47.65,66.25 47.65,69.48 44.44,72.69 41.96,72.69 41.5,72.24 38.43,72.24 37.8,72.87 34.98,72.87 34.04,73.81 31.95,73.81 31.32,74.44 24.96,74.44 21.92,71.41 21.92,70.87 21.11,70.06 14.02,70.06 11.46,72.62 10.39,72.62 8.13,74.88 8.13,77.77 v1(8.69,78.33) ; v1(5.61,111.84) 5.89,112.12 13.67,112.12 14.15,111.63 15.67,111.63 16.21,112.17 16.21,116.78 15.42,117.56 15.42,123.57 14.55,124.44 J13.19
  L03_SIG1 w0.091: v1(66.5,55.91) 67.25,55.91 68.4,57.05 68.4,65.93 69.26,66.79 69.26,71.92 69.52,72.19 69.52,75.7 70.1,76.27 v1(70.1,78.46) ; v1(8.69,78.33) 9.02,78.66 9.02,80.01 8.28,80.75 8.28,97 6.78,98.5 5.43,98.5 4.61,99.33 4.61,110.83 v1(5.61,111.84)
SPI1_D1: length 167.4
  TOP w0.147: v1(11.2,70.82) 13.01,69 21.79,69 23.62,70.83 23.62,71.48 25.53,73.39 30.8,73.39 32.21,71.98 34.11,71.98 34.95,71.15 35.97,71.15 36.03,71.08 44.31,71.08 45.05,70.34 45.05,69.41 46.41,68.05 46.41,65.98 47.16,65.23 47.16,60.48 50.93,56.71 51.77,56.71 52.16,56.32 53.21,56.32 54.77,54.76 63.12,54.76 63.91,53.98 65.56,53.98 v1(65.96,54.38) ; U136.U3 v1(70.9,78.46) ; v1(9.52,95.81) 6.05,99.29 6.05,110.65 7.1,111.71 13.36,111.71 13.79,111.28 15.81,111.28 16.56,112.02 16.56,116.92 15.93,117.55 15.93,123.65 14.34,125.24 J13.21
  L03_SIG1 w0.091: v1(11.2,70.82) 9.32,72.69 9.32,76.05 9.98,76.71 9.98,80.77 9.52,81.23 v1(9.52,95.81) ; v1(70.9,78.46) 71.24,78.11 71.24,72.61 70.08,71.45 70.08,64.67 69.41,64 69.41,56.9 66.89,54.38 v1(65.96,54.38)
SPI_HOLDN: length 1.8
  TOP w0.147: U69.7 33.23,28.64 33.63,28.23 R374.2
SPI_WPN: length 1.5
  TOP w0.147: U69.3 R378.2
SYNC1_OUT: length 46.1
  TOP w0.147: v1(70.97,66.8) 69.57,68.2 69.57,70.78 68.6,71.75 R5788.1 ; U3083.2 96.64,56.32 95.61,55.3 v1(94.79,55.3)
  L03_SIG1 w0.091: v1(70.11,59.74) 70.11,63.89 70.97,64.74 v1(70.97,66.8)
  BOTTOM w0.147: v1(94.79,55.3) 94.28,54.79 88.29,54.79 87.3,55.78 82.85,55.78 82.17,55.09 74.76,55.09 v1(70.11,59.74)
SYNC1_OUT_3V3: length 15.4
  TOP w0.147: R5793.1 98.55,60.22 98.79,59.99 98.79,51.96 100.48,50.27 101.75,50.27 102.11,50.63 U3084.1
SYNC1_OUT_ETH1: length 38.8
  TOP w0.147: v1(80.09,50.62) 80.73,49.98 TP93.1 80.14,45.72 80.14,43.5 80.41,43.24 J18.38 ; R5791.2 105.99,52.22 v1(105.38,51.61)
  BOTTOM w0.147: v1(105.38,51.61) 104.39,52.6 96.29,52.6 94.31,50.62 v1(80.09,50.62)
SYNC1_OUT_ETH2: length 26.7
  TOP w0.147: v1(114.08,48.26) 113.61,47.79 TP87.1 113.47,46.36 112.67,45.57 112.67,43.46 112.84,43.3 J19.38 ; R5792.2 100.13,56.39 99.55,55.81 99.55,54.33 100.82,53.06 v1(101.17,53.06)
  BOTTOM w0.147: v1(114.08,48.26) 111.92,50.42 107.52,50.42 104.88,53.06 v1(101.17,53.06)
SYS_BOOTMODE0: length 33.6
  TOP w0.147: R153.1 v1(64.54,117.73) SW2.1
  L03_SIG1 w0.091: v1(84.47,124.93) 84.47,125.77 83.31,126.92 77.06,126.92 76.26,127.73 74.56,127.73 73.87,127.03 69.51,127.03 64.17,121.69 64.17,118.1 v1(64.54,117.73)
  BOTTOM w0.147: U81.10 v1(84.47,124.93) U82.1
SYS_BOOTMODE1: length 29.9
  TOP w0.147: R154.1 SW2.2 65.81,119.66 66.47,120.31 84.83,120.31 85.83,121.31 85.83,123.91 v1(85.31,124.43)
  BOTTOM w0.147: U81.9 v1(85.31,124.43) U82.2
SYS_BOOTMODE2: length 31.4
  TOP w0.147: R155.1 SW2.3 67.08,119.63 67.39,119.94 84.95,119.94 86.21,121.2 86.21,124.38 85.62,124.97 85.17,124.97 84.79,124.59 84.79,124.25 v1(84.47,123.93)
  BOTTOM w0.147: U82.3 v1(84.47,123.93) U81.8
SYS_BOOTMODE3: length 34.6
  TOP w0.147: SW2.4 68.35,118.04 68.73,117.65 v1(69.16,117.65) 69.16,117.22 69.02,117.07 R156.1
  L03_SIG1 w0.091: v1(85.31,123.43) 85.31,123.76 84.7,124.36 83.95,124.36 81.74,126.57 76.99,126.57 76.1,127.45 75,127.45 74.31,126.76 69.87,126.76 68.03,124.92 68.03,124.45 69.46,123.02 69.46,117.95 v1(69.16,117.65)
  BOTTOM w0.147: U82.4 v1(85.31,123.43) U81.7
SYS_BOOTMODE4: length 29.6
  TOP w0.147: SW2.5 69.62,117.93 v1(70.28,117.27) 70.28,117.22 70.13,117.07 R157.1
  L03_SIG1 w0.091: v1(84.47,122.93) 84.08,122.93 81.47,125.54 70.73,125.54 69.76,124.56 69.76,117.8 v1(70.28,117.27)
  BOTTOM w0.147: U82.5 v1(84.47,122.93) U81.6
SYS_BOOTMODE5: length 29
  TOP w0.147: SW2.6 v1(70.89,117.7) R158.1
  L03_SIG1 w0.091: v1(70.89,117.7) 70.03,118.57 70.03,124.45 70.84,125.26 76.54,125.26 78.56,123.24 81.83,123.24 82.63,122.43 v1(85.31,122.43)
  BOTTOM w0.147: U81.5 v1(85.31,122.43) U82.6
SYS_BOOTMODE6: length 25.1
  TOP w0.147: R159.1 v1(72.16,117.73) SW2.7
  L03_SIG1 w0.091: v1(72.16,117.73) 72.67,118.23 72.67,124.19 73.47,124.99 75.97,124.99 78.8,122.16 82.59,122.16 82.82,121.93 v1(84.47,121.93)
  BOTTOM w0.147: U82.7 v1(84.47,121.93) U81.4
SYS_BOOTMODE7: length 25.7
  TOP w0.147: R160.1 v1(73.43,117.76) SW2.8
  L03_SIG1 w0.091: v1(73.43,117.76) 73.2,117.99 73.2,124.33 73.58,124.72 75.28,124.72 78.96,121.03 82.65,121.03 83.05,121.43 v1(85.31,121.43)
  BOTTOM w0.147: U82.8 v1(85.31,121.43) U81.3
SYS_BOOTMODE8: length 22.9
  TOP w0.147: SW1.1 R145.1 76.05,117.07 74.73,118.39 v1(74.73,119.1)
  L03_SIG1 w0.091: v1(74.73,119.1) 76.89,116.94 83.74,116.94 84.2,117.4 v1(84.2,117.78)
  BOTTOM w0.147: U82.9 82.06,119.92 v1(84.2,117.78) ; U83.10 73.64,120.77 74.02,120.4 74.02,119.81 v1(74.73,119.1)
SYS_BOOTMODE9: length 14.8
  TOP w0.147: SW1.2 v1(78.32,117.76) R146.1
  BOTTOM w0.147: U83.9 73.72,121.27 74.37,120.62 74.37,120.14 76.75,117.76 v1(78.32,117.76) 78.81,117.27 79.93,117.27 80.21,117.55 80.21,117.96 81.56,119.31 U82.10
SYS_BOOTMODE10: length 19.1
  TOP w0.147: R147.1 v1(79.59,117.76) SW1.3
  L03_SIG1 w0.091: v1(74.83,120.9) 76.96,118.77 78.58,118.77 v1(79.59,117.76)
  BOTTOM w0.147: U83.8 73.96,121.77 v1(74.83,120.9) 74.83,120.32 76.56,118.58 79.95,118.58 81.06,119.7 U82.11
SYS_BOOTMODE11: length 21.1
  TOP w0.147: SW1.4 v1(80.86,117.76) R148.1
  L03_SIG1 w0.091: v1(73.74,122.27) 74.53,121.49 75.39,121.49 77.67,119.2 79.42,119.2 v1(80.86,117.76)
  BOTTOM w0.147: U83.7 v1(73.74,122.27) 74.1,122.27 75.43,120.95 75.43,120.69 77.18,118.93 79.62,118.93 80.56,119.88 U82.12
SYS_BOOTMODE12: length 21.5
  TOP w0.147: SW1.5 v1(82.13,117.76) R149.1
  L03_SIG1 w0.091: v1(82.13,117.76) 79.98,119.91 78.21,119.91 75.3,122.82 v1(74.64,122.82)
  BOTTOM w0.147: U82.13 80.06,119.97 79.38,119.29 77.33,119.29 75.91,120.71 75.91,121.55 v1(74.64,122.82) 74.6,122.77 U83.6
SYS_BOOTMODE13: length 23.9
  TOP w0.147: SW1.6 v1(83.4,117.59) R150.1
  L03_SIG1 w0.091: v1(73.74,123.27) 74.09,123.27 74.19,123.16 74.19,122.66 74.81,122.05 75.44,122.05 77.93,119.56 79.67,119.56 82,117.22 83.02,117.22 v1(83.4,117.59)
  BOTTOM w0.147: U82.14 79.56,119.97 79.22,119.64 77.47,119.64 76.28,120.83 76.28,121.83 74.83,123.27 v1(73.74,123.27) U83.5
SYS_BOOTMODE14: length 24.2
  TOP w0.147: R151.1 84.67,117.36 v1(85.01,117.7) 84.67,118.05 SW1.7
  L03_SIG1 w0.091: v1(85.01,117.7) 82.45,120.27 78.44,120.27 v1(74.7,124.01)
  BOTTOM w0.147: U83.4 74.46,123.77 v1(74.7,124.01) 76.68,122.03 76.68,120.92 77.62,119.99 78.96,119.99 79.06,120.09 U82.15
SYS_BOOTMODE15: length 24.8
  TOP w0.147: SW1.8 v1(85.94,117.76) R152.1
  L03_SIG1 w0.091: v1(73.74,124.27) 74.17,124.27 74.34,124.44 74.9,124.44 78.77,120.57 83.13,120.57 v1(85.94,117.76)
  BOTTOM w0.147: U83.3 v1(73.74,124.27) 74.17,124.27 74.37,124.47 74.89,124.47 77.04,122.32 77.04,121.06 77.42,120.68 U82.16
SYSBOOT_BUF_ENZ: length 1.3
  TOP w0.147: U23.1 R377.1
TAD1_ADDR1: length 3.1
  TOP w0.147: U5.13 77.41,151.82 77.76,151.47 77.76,151.3 78.03,151.03 78.41,151.03 78.53,150.91 R29.2 R37.2
TAD1_DREG_OUT: length 2.5
  TOP w0.147: U5.1 72.54,154.32 72.3,154.57 C45.1 71.4,154.57 C42.1
TAD1_GPI1: length 1.7
  TOP w0.147: U5.12 76.42,150.36 76.79,149.99 R31.1
TAD1_MICBIAS: length 1.4
  TOP w0.147: U5.14 77.7,152.32 77.86,152.16 77.86,152.03 C66.1
TAD1_VREF: length 3.5
  TOP w0.147: C38.1 73.06,156.5 73.92,155.64 U5.24
TAD2_ADDR2: length 4.4
  TOP w0.147: v1(80.72,151.36) 81.53,151.36 82.04,150.85 R36.2 R33.2
  BOTTOM w0.147: U77.13 80.77,151.82 80.59,151.65 80.59,151.43 80.67,151.36 v1(80.72,151.36)
TAD2_DREG_OUT: length 2.5
  BOTTOM w0.147: U77.1 85.8,154.32 86.04,154.57 C358.1 86.96,154.57 C356.1
TAD2_GPI1: length 2.3
  BOTTOM w0.147: U77.12 81.95,151.06 81.95,150.44 81.81,150.3 R429.1
TAD2_MICBIAS: length 1.5
  BOTTOM w0.147: U77.14 80.74,152.32 80.49,152.07 80.27,152.07 80.12,151.92 C370.1
TAD2_VREF: length 1.5
  BOTTOM w0.147: C354.1 84.82,156.04 84.44,155.66 U77.24
TAD3_ADDR3: length 4
  TOP w0.147: U6.13 95.02,151.82 95.14,151.7 95.14,151.2 95.67,150.67 95.67,150.23 95.97,149.93 R30.1 96.82,149.93 R35.1
TAD3_DREG_OUT: length 2.5
  TOP w0.147: U6.1 90.13,154.32 89.88,154.57 C46.1 88.8,154.57 C43.1
TAD3_GPI3: length 1.7
  TOP w0.147: U6.12 93.82,150.28 94.11,149.99 R32.1
TAD3_MICBIAS: length 1.4
  TOP w0.147: C67.1 95.64,151.7 95.01,152.32 U6.14
TAD3_VREF: length 3.5
  TOP w0.147: C35.1 89.02,156.72 89.92,155.82 91.03,155.82 91.32,155.53 U6.24
TAD4_ADDR4: length 2
  TOP w0.147: R28.1 R27.1 97.92,151.17 v1(98.1,151.35)
  BOTTOM w0.147: U76.13 98.11,151.35 v1(98.1,151.35)
TAD4_DREG_OUT: length 2.5
  BOTTOM w0.147: C355.1 104.36,154.57 C357.1 103.46,154.57 103.22,154.32 U76.1
TAD4_GPI4: length 1.4
  BOTTOM w0.147: U76.12 99.34,150.32 99.15,150.13 R430.1
TAD4_MICBIAS: length 1.4
  BOTTOM w0.147: U76.14 98.12,152.32 97.89,152.1 97.89,151.93 97.74,151.78 C369.1
TAD4_VREF: length 1.5
  BOTTOM w0.147: U76.24 101.84,155.76 102.12,156.04 C353.1
TAD5212_1_DIN: length 4.9
  TOP w0.147: U5.5 72.26,152.32 72,152.06 R5641.2
TAD5212_2_DIN: length 3.5
  TOP w0.147: v1(85.93,152.35) 84.79,151.21 R5642.2
  BOTTOM w0.147: U77.5 85.9,152.32 v1(85.93,152.35)
TAD5212_3_DIN: length 2.9
  TOP w0.147: U6.5 89.55,152.32 v1(89.2,151.97)
  BOTTOM w0.147: R5643.2 89.03,151.22 89.2,151.39 v1(89.2,151.97)
TAD5212_4_DIN: length 2.3
  TOP w0.147: R5644.2 103.48,151.73 v1(103.82,152.07)
  BOTTOM w0.147: U76.5 103.56,152.32 v1(103.82,152.07)
TAD5212_MCASP1_ACLKX: length 126.9
  TOP w0.147: U5.2 70.56,153.82 70.32,154.06 69.08,154.06 v1(68.71,154.43) ; U6.2 v1(88.65,153.82) ; v1(65.79,114.33) 66.24,113.87 66.24,111.05 65.34,110.14 R5646.1
  L03_SIG1 w0.091: v1(108.36,152.88) 104.37,152.88 102.34,154.91 91.95,154.91 89.93,152.89 88.94,152.89 88.65,153.19 v1(88.65,153.82) 88.65,154.23 88,154.88 74.97,154.88 74.52,154.43 v1(68.71,154.43) 68.71,154.11 69.42,153.4 69.42,152.58 68.22,151.38 68.22,143.38 58.39,133.55 58.39,130.4 61.72,127.08 61.72,120.35 61.83,120.24 62.02,120.24 62.13,120.13 62.13,119.98 62.02,119.87 61.83,119.87 61.72,119.77 61.72,118.8 64.92,115.6 65.23,115.6 65.79,115.04 v1(65.79,114.33)
  BOTTOM w0.147: v1(108.36,152.88) 108.65,153.17 108.65,154.15 108.23,154.57 R418.2 R419.1 105.75,154.57 105.61,154.44 105.61,154.1 105.33,153.82 U76.2 ; U77.2 v1(88.65,153.82)
TAD5212_MCASP1_AFSX: length 125.7
  TOP w0.147: U6.3 v1(89.74,153.32) ; U5.3 70.43,153.32 70.13,153.62 69.29,153.62 v1(68.88,153.21)
  L03_SIG1 w0.091: v1(108.1,153.77) 106.68,153.77 104.21,156.24 92.66,156.24 v1(89.74,153.32) 89.28,153.78 89.28,154.33 88.19,155.42 84.89,155.42 83.7,156.61 69.72,156.61 68.28,155.17 68.28,153.82 v1(68.88,153.21) 68.88,152.76 67.84,151.71 67.84,144.42 57.71,134.29 57.71,130.02 61.07,126.66 61.07,117.9 63.8,115.16 63.8,104.5 v1(62.13,102.82)
  BOTTOM w0.147: U77.3 v1(89.74,153.32) ; v1(62.13,102.82) 62.41,102.54 R5647.2 ; U76.3 R423.1 R422.2 107.35,153.32 107.8,153.77 v1(108.1,153.77)
TAD5212_MCASP1_AXR1: length 117.1
  TOP w0.147: v1(69.11,151.16) 69.04,151.08 R5641.1 ; R5642.1 83.69,149.35 84,149.05 v1(84.45,149.05) ; v1(66.7,114.63) 66.7,110.52 65.93,109.75 R5645.2 ; v1(103.48,149.61) R5644.1
  L03_SIG1 w0.091: v1(66.7,114.63) 65.3,116.03 64.95,116.03 62.46,118.52 62.46,119.73 62.57,119.84 63.16,119.84 63.27,119.95 63.27,120.1 63.16,120.21 62.57,120.21 62.46,120.31 62.46,120.47 62.57,120.57 63.16,120.57 63.27,120.68 63.27,120.83 63.16,120.94 62.57,120.94 62.46,121.05 62.46,121.2 62.57,121.3 63.16,121.3 63.27,121.41 63.27,121.56 63.16,121.67 62.57,121.67 62.46,121.78 62.46,121.93 62.57,122.04 63.16,122.04 63.27,122.14 63.27,122.3 63.16,122.4 62.57,122.4 62.46,122.51 62.46,122.66 62.57,122.77 63.16,122.77 63.27,122.88 63.27,123.03 63.16,123.13 62.57,123.13 62.46,123.24 62.46,123.39 62.57,123.5 63.16,123.5 63.27,123.61 63.27,123.76 63.16,123.87 62.57,123.87 62.46,123.97 62.46,124.12 62.57,124.23 63.16,124.23 63.27,124.34 63.27,124.49 63.16,124.6 62.57,124.6 62.46,124.7 62.46,124.86 62.57,124.96 63.16,124.96 63.27,125.07 63.27,125.22 63.16,125.33 62.57,125.33 62.46,125.44 62.46,125.59 62.57,125.69 63.16,125.69 63.27,125.8 63.27,125.95 63.16,126.06 62.57,126.06 62.46,126.17 62.46,126.97 58.75,130.68 58.75,133.1 68.55,142.9 68.55,150.6 v1(69.11,151.16) 69.77,151.82 70.87,151.82 71.73,150.95 71.73,149.73 74.09,147.37 82.78,147.37 v1(84.45,149.05) 85.01,149.05 85.8,148.26 v1(87.78,148.26) 90.83,148.26 91.77,147.32 98.58,147.32 99.01,147.75 102.41,147.75 103.48,148.82 v1(103.48,149.61)
  BOTTOM w0.147: R5643.1 88.42,149.25 87.78,148.61 v1(87.78,148.26)
TCA6424_EXP_INT: length 2.3
  BOTTOM w0.147: R457.1 83.26,126.44 83.01,126.19 82.78,126.19 82.63,126.34 82.22,126.34 82.06,126.18 U82.32
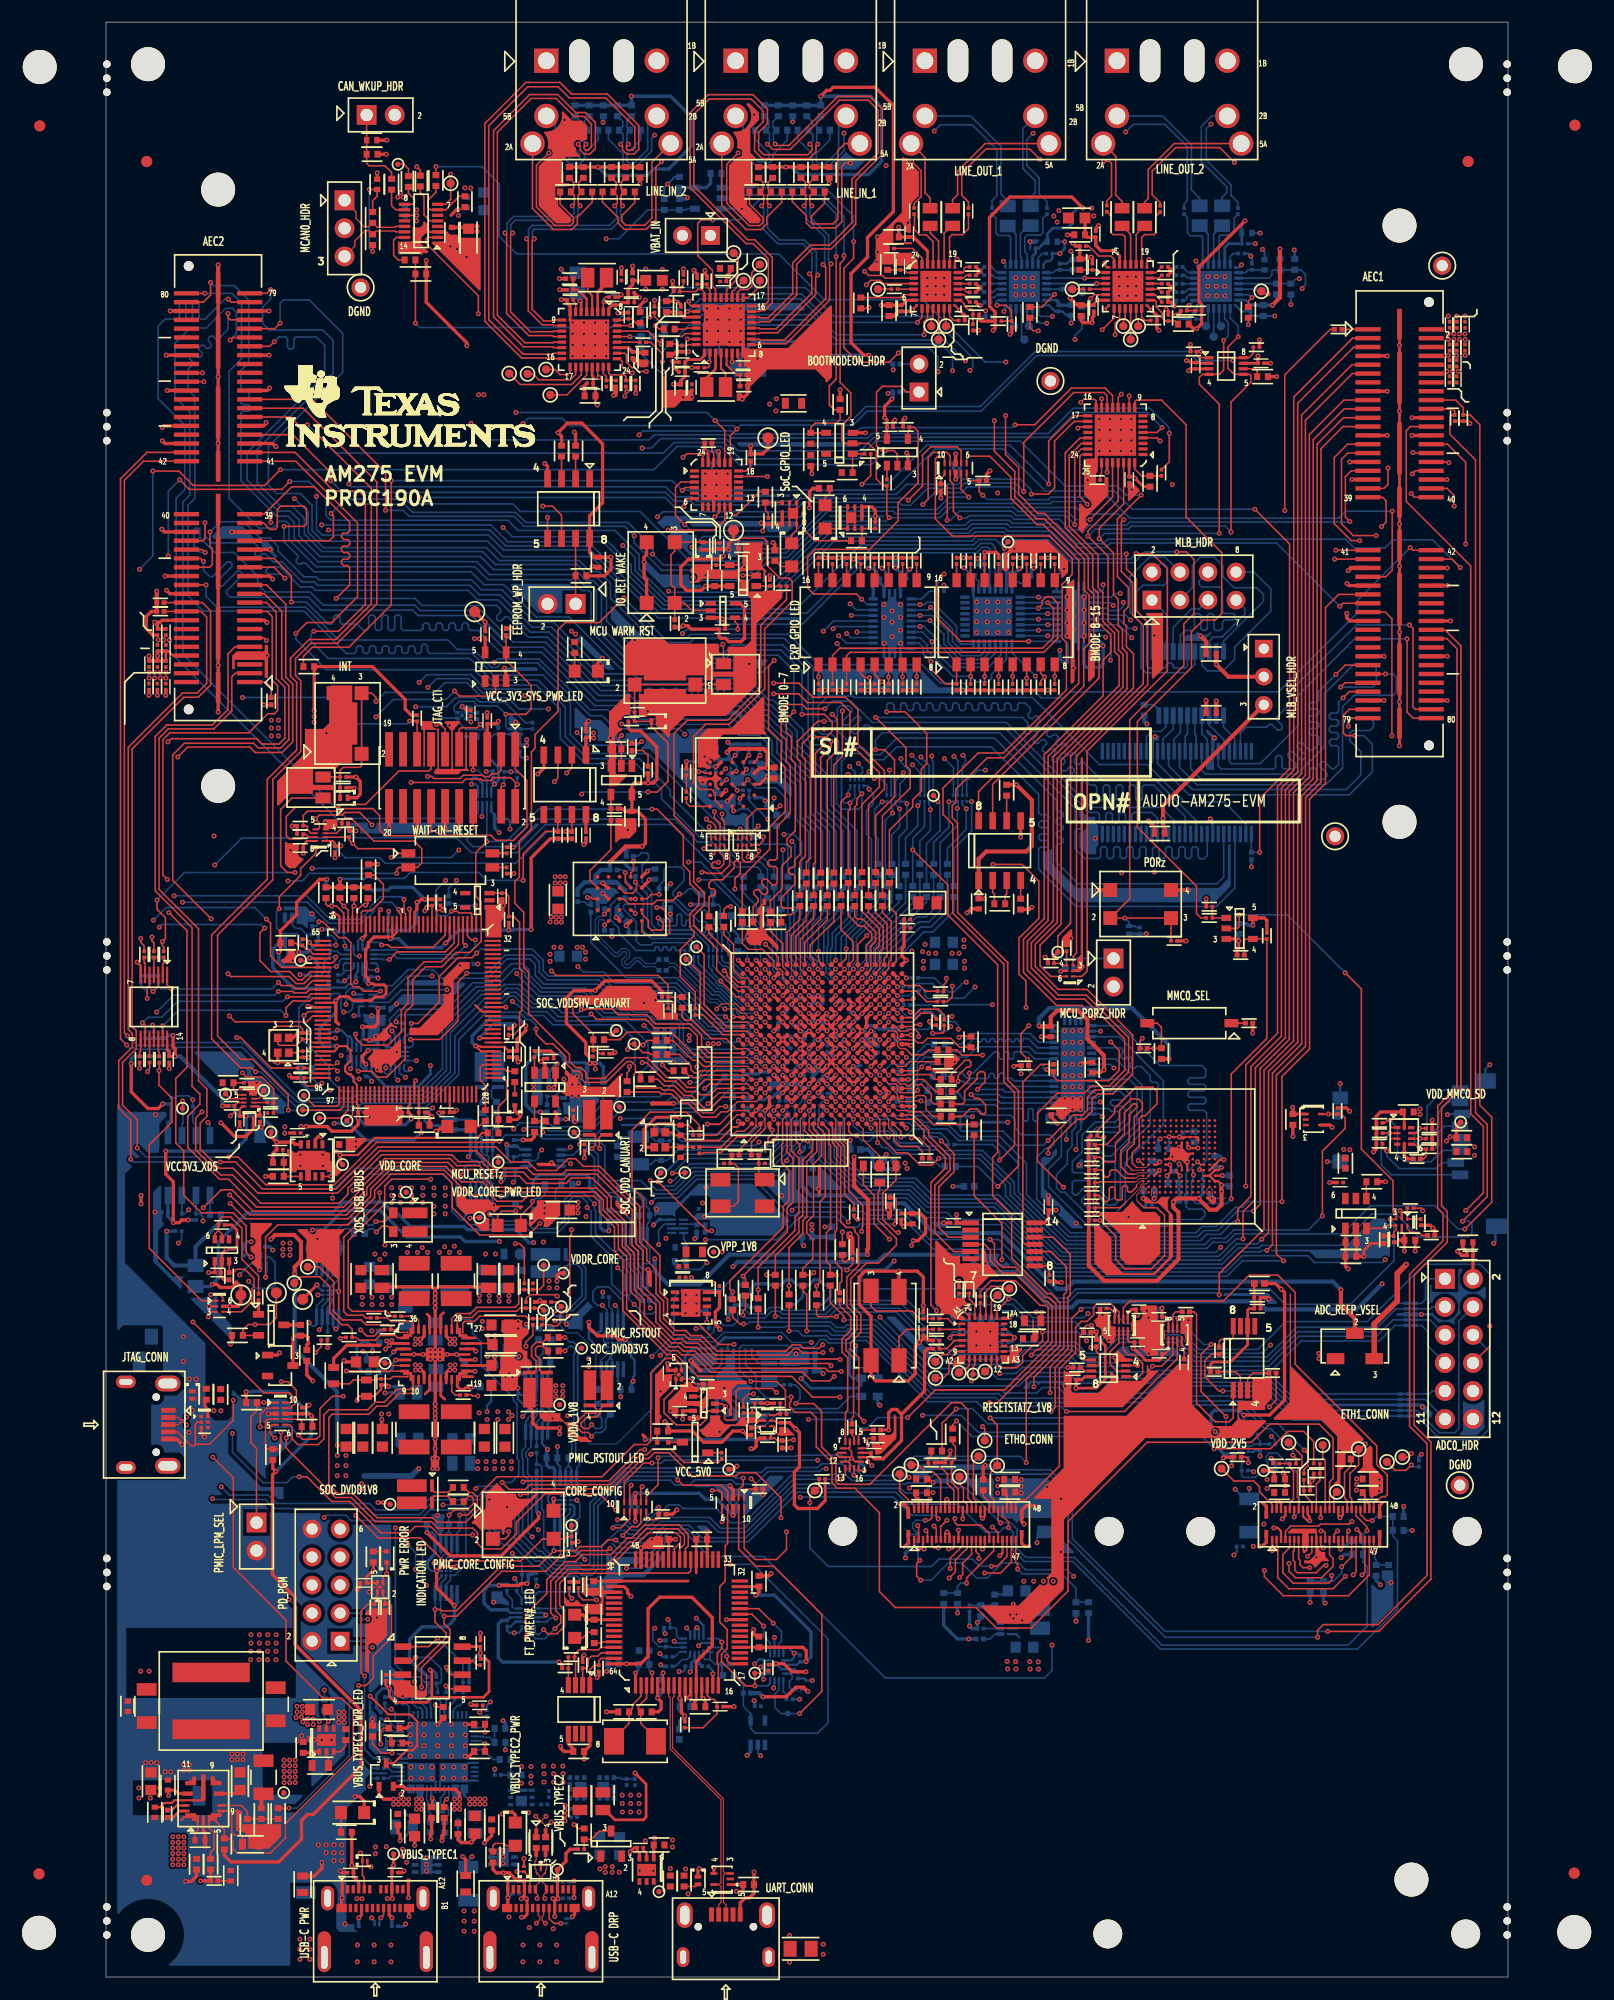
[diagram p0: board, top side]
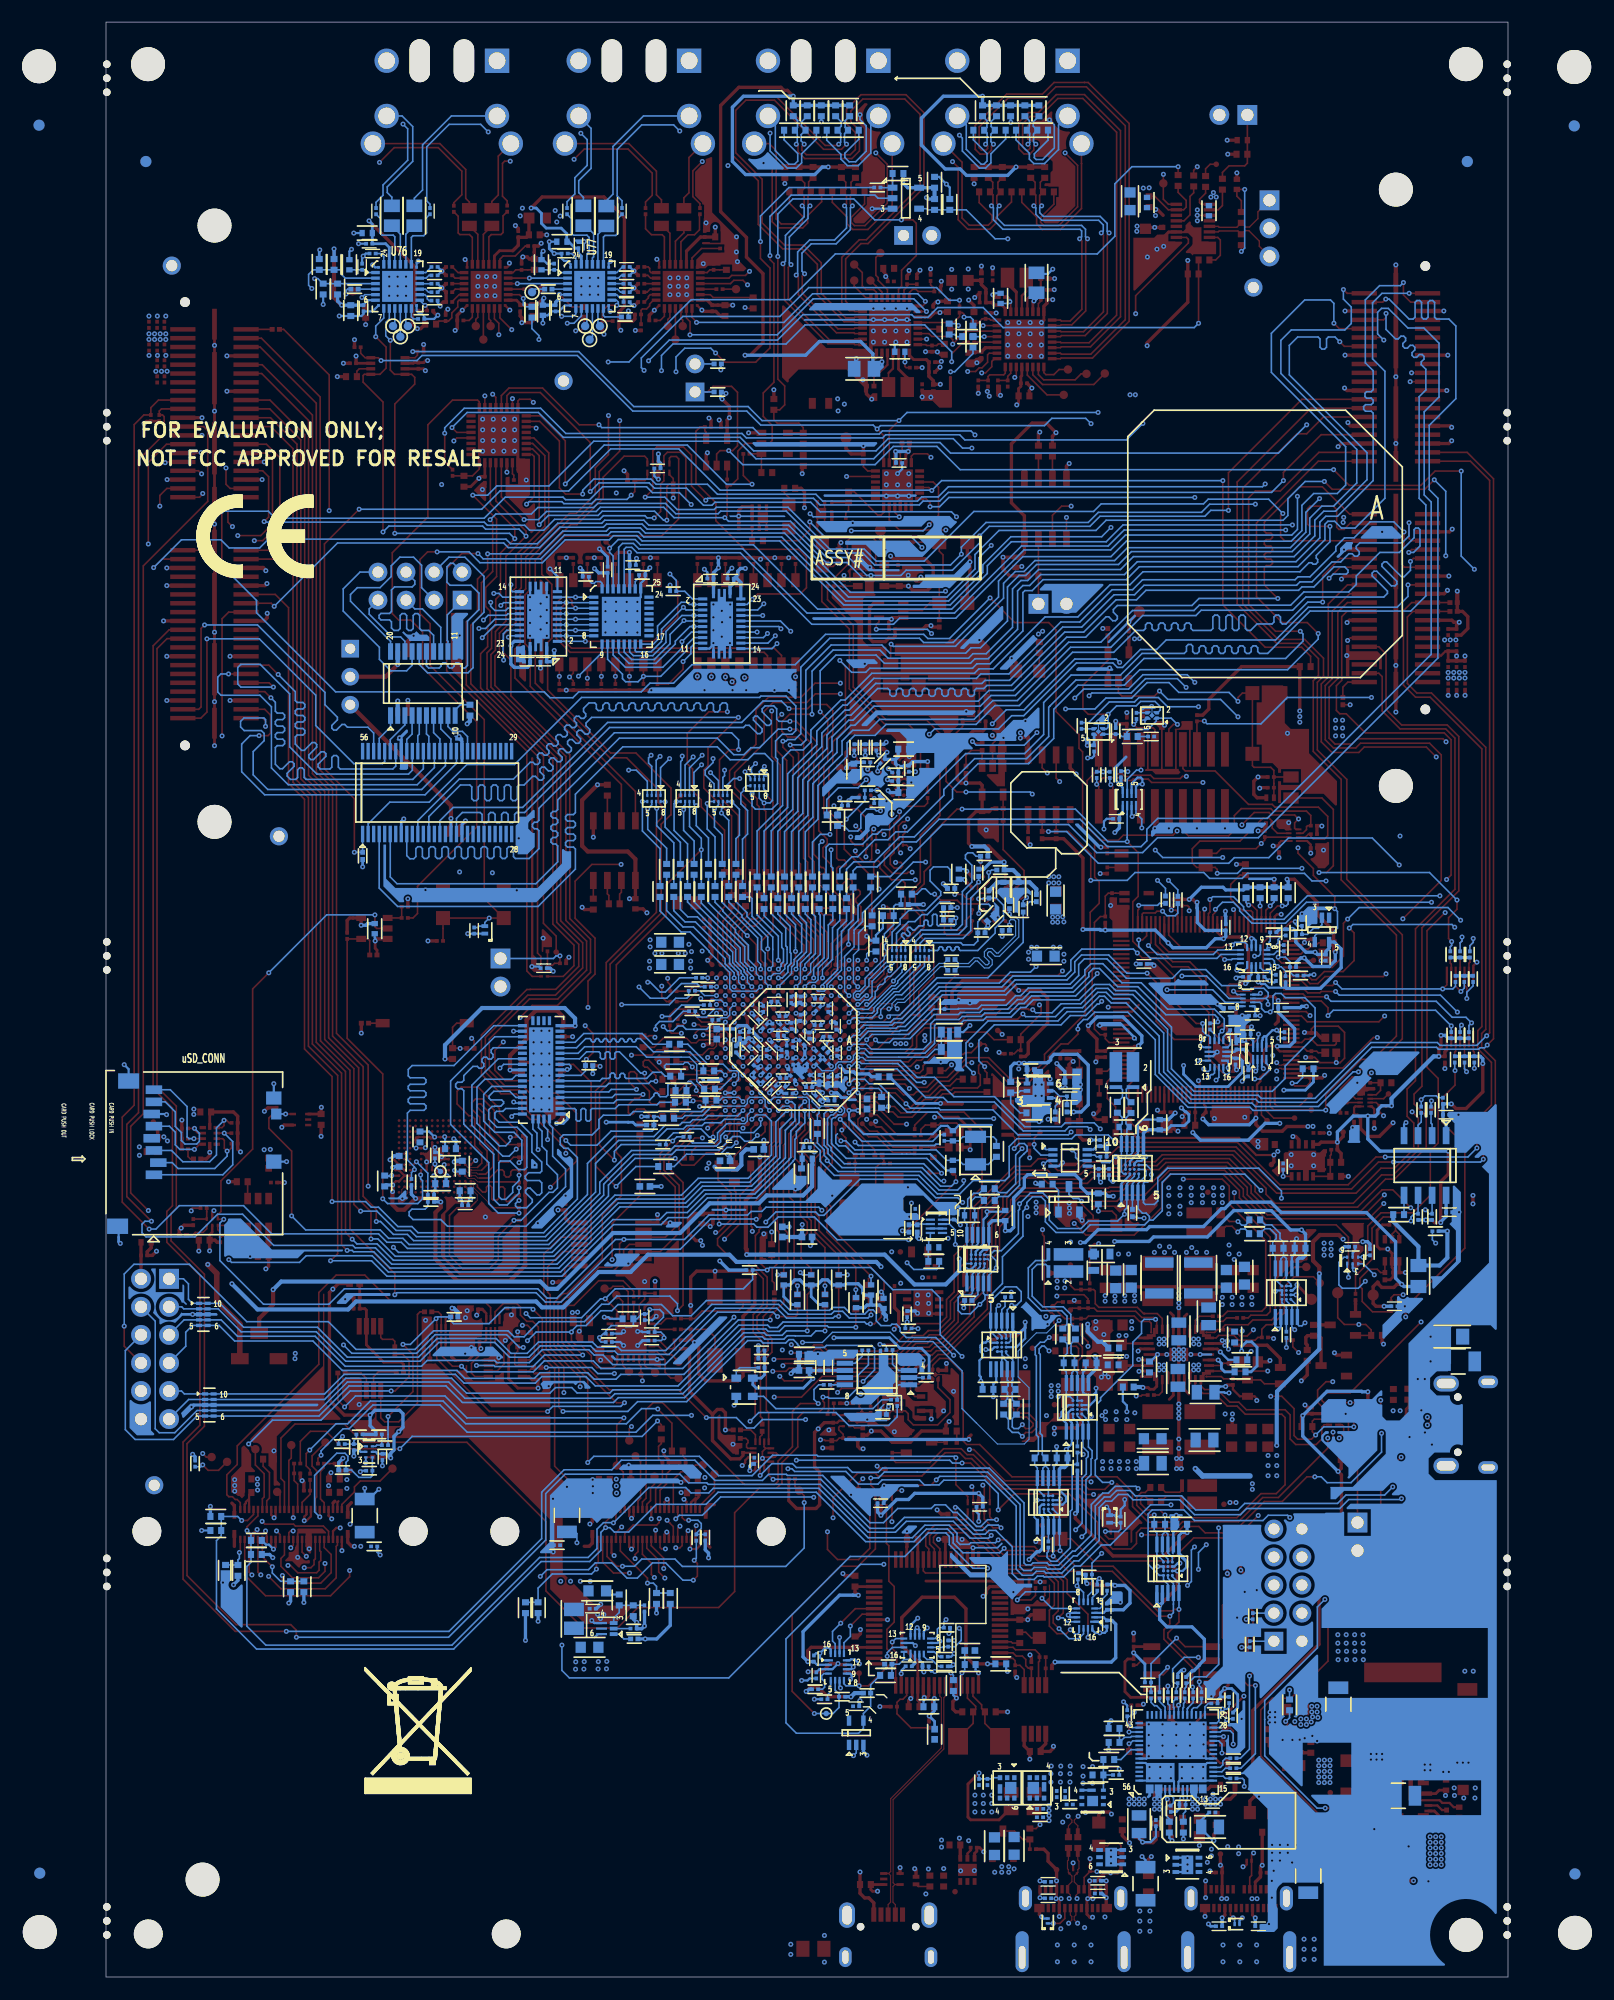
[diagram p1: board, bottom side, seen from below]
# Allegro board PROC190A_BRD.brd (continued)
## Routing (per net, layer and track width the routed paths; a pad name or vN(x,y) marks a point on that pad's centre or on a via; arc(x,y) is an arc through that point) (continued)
TEST_GPIO1: length 30.5
  TOP w0.147: v1(17.12,100) 16.43,100 15.82,100.61 15.82,105.71 16.86,106.75 Q7.1 ; R235.1 5.23,93.27 5.11,93.4 v1(5.11,93.75) 5.38,94.03 5.38,95.91 4.62,96.67 v1(4.62,97.51)
  BOTTOM w0.147: v1(5.11,93.75) 5.11,93.4 5.23,93.27 R235.1 ; v1(17.12,100) 7.11,100 v1(4.62,97.51)
TEST_GPIO2: length 138.4
  TOP w0.147: U21.18 87.71,140.85 85.93,139.06 85.93,134.82 85.37,134.26 v1(83.82,134.26) ; v1(12.37,81.86) 12.75,81.48 14.12,81.48 15.18,80.43 R283.1 R285.2
  L03_SIG1 w0.091: v1(12.37,81.86) 12.37,83.34 12.88,83.85 12.88,91.44 11.53,92.79 11.53,103.78 13.74,105.99 13.74,115.47 21.54,123.27 21.54,134.72 v1(22,135.18)
  BOTTOM w0.147: v1(83.82,134.26) 83.82,134.62 82.81,135.63 77.64,135.63 77.17,135.15 72.52,135.15 71.61,134.25 62.69,134.25 62.08,133.63 53.49,133.63 53.11,134.01 51.61,134.01 50.69,134.93 22.25,134.93 v1(22,135.18)
TEST_GPIO3: length 129.7
  TOP w0.147: J10.1 72.52,143.51 72.01,144.02 70.33,144.02 69.8,143.48 69.8,138.64 70.23,138.2 v1(70.59,138.2) 71.38,138.2 71.69,137.89 U23.2 ; v1(15.8,136.47) 14.38,135.05 7.9,135.05 6.6,136.35 v1(4.24,136.35) ; R227.1 4.34,93.63 4.17,93.8 v1(4.17,94.16)
  L03_SIG1 w0.091: v1(3.05,127.46) 2.82,127.23 2.82,95.51 v1(4.17,94.16)
  BOTTOM w0.147: R227.1 4.34,93.63 4.17,93.8 v1(4.17,94.16) ; R439.1 J10.1 ; v1(15.8,136.47) 49.63,136.47 51.74,138.58 55.68,138.58 57.33,136.93 69.32,136.93 v1(70.59,138.2) ; v1(3.05,127.46) 4.24,128.65 v1(4.24,136.35)
TEST_GPIO4: length 132
  TOP w0.147: R221.1 3.45,93.38 3.15,93.68 v1(3.15,94.03)
  L03_SIG1 w0.091: v1(19.08,134.06) 18.24,133.22 4.29,133.22 2.54,131.47 2.54,94.64 v1(3.15,94.03)
  BOTTOM w0.147: U82.28 80.06,129.27 79.88,129.44 79.38,129.44 78.89,128.95 69.54,128.95 63.07,122.48 55.67,122.48 55.12,123.03 50.02,123.03 43.84,129.21 35.99,129.21 34.65,130.56 19.58,130.56 19.08,131.06 v1(19.08,134.06) ; v1(3.15,94.03) 3.15,93.68 3.45,93.38 R221.1
TEST_PORZN: length 202.3
  TOP w0.147: v1(93.78,134.16) 91.62,132.01 91.62,126.8 92.61,125.81 92.61,124.08 92.2,123.67 92.2,122.56 92.43,122.33 92.43,120.45 93.07,119.81 93.07,116.71 86.52,110.16 86.52,95.33 84.61,93.42 84.61,91.56 85.58,90.59 U43.6 ; R219.1 v1(3.05,82.27)
  L03_SIG1 w0.091: v1(18.24,140.54) 11.89,134.19 3.99,134.19 1.8,132 1.8,87.12 3.05,85.87 v1(3.05,82.27)
  BOTTOM w0.147: v1(93.78,134.16) 92.43,134.16 91.59,135 86.87,135 82.82,139.05 69.71,139.05 68.12,137.46 57.46,137.46 55.99,138.93 51.45,138.93 50.5,137.98 20.8,137.98 v1(18.24,140.54) ; R219.1 v1(3.05,82.27)
TEST_POWERDOWN: length 27
  TOP w0.147: U54.1 8.67,61.23 3.91,65.99 3.91,75.34 5.97,77.39 5.97,79.58 4.8,80.75 v1(4.8,82.07) 4.83,82.1 R233.1
  BOTTOM w0.147: v1(4.8,82.07) 4.83,82.1 R233.1
TEST_WARMRESETN: length 116.2
  TOP w0.147: v1(55.88,120.68) 55.92,120.63 Q12.1 ; v1(3.76,81.97) 3.76,82.04 3.94,82.22 R224.1
  L03_SIG1 w0.091: v1(17.07,133.86) 4.06,133.86 2.18,131.98 2.18,88.6 3.76,87.02 v1(3.76,81.97)
  BOTTOM w0.147: v1(3.76,81.97) 3.76,82.04 3.94,82.22 R224.1 ; v1(55.88,120.68) 55.68,120.48 50.06,120.48 45.69,124.84 45.69,126.19 44.63,127.25 43.84,127.25 42.85,128.24 35.64,128.24 34.47,129.41 19.71,129.41 18.31,130.81 18.31,132.61 v1(17.07,133.86)
TM4C129_TCK: length 2.6
  TOP w0.147: TP66.1 22.33,78.05 U48.100
TM4C129_TDI: length 4.9
  TOP w0.147: TP64.1 21.2,78.5 21.53,78.83 U48.98
TM4C129_TDO: length 4.6
  TOP w0.147: TP62.1 18.89,78.85 20.93,78.85 21.13,79.06 U48.97
TM4C129_TMS: length 4.3
  TOP w0.147: U48.99 21.93,78.48 21.22,77.76 TP63.1
TMP411_ALERT: length 2.3
  TOP w0.147: R5741.2 U2357.6
TMP411_THERM: length 1.7
  TOP w0.147: U2357.4 R5742.2
TPS65224_EN: length 60.5
  TOP w0.147: v1(33.2,40.03) 30.17,40.03 29.41,40.79 28.01,40.79 27.43,40.21 24.91,40.21 22.07,43.05 20.45,43.05 18.21,45.29 v1(17.5,45.29) ; v1(33.68,52.6) 33.23,52.6 33.14,52.69 R317.1 ; TP81.1 15.43,59.69 14.82,59.08 v1(13.51,59.08) 12.89,59.08 12.39,58.58 R303.1 Q4.2
  L03_SIG1 w0.091: v1(13.51,59.08) 13.51,55.52 12.09,54.1 12.09,49.86 v1(11.46,49.23) ; v1(33.2,40.03) 33.93,40.77 33.93,44.55 32.97,45.52 32.97,51.89 v1(33.68,52.6)
  BOTTOM w0.147: v1(11.46,49.23) 11.46,47.52 14.22,44.75 16.38,44.75 16.92,45.29 v1(17.5,45.29)
UART2_FET_SEL: length 160.3
  TOP w0.147: U2351.5 48.94,41.57 49.12,41.4 49.96,41.4 50.06,41.5 R5799.2 v1(50.06,42.52) ; v1(82.35,140.54) 84.12,140.54 87.45,143.87 90.5,143.87 91.18,143.18 U21.13 ; v1(46.33,41.4) 46.68,41.4 46.94,41.66 U2351.1
  L03_SIG1 w0.091: v1(50.06,42.52) 50.06,44.6 47.14,47.52 47.14,55.14 50.01,58.01 50.01,64.11 49.28,64.85 49.28,66.27 50.88,67.87 50.88,70.23 49.79,71.31 49.49,71.31 47.04,73.77 47.04,81.76 46.7,82.1 46.7,82.8 47.68,83.77 47.68,85.39 47.49,85.58 47.49,89.56 48.41,90.47 48.41,98.02 46.61,99.82 46.61,99.85 46.48,99.97 46.48,112.04 45.8,112.72 45.8,125.25 47.29,126.75 47.29,138.63 v1(48.29,139.62)
  BOTTOM w0.147: v1(82.35,140.54) 82.09,140.28 68.4,140.28 67.82,139.7 56.94,139.7 56.66,139.98 48.64,139.98 v1(48.29,139.62) ; v1(50.06,42.52) 49.86,42.52 48.13,40.79 47.75,40.79 47.15,41.4 v1(46.33,41.4)
UART2_RXD: length 180.1
  TOP w0.147: U2351.4 48.44,41.08 48.13,40.77 47.6,40.77 v1(46.81,39.98) ; v1(109.75,30.76) 109.75,31.39 110.26,31.9 115.21,31.9 119.66,36.35 119.66,48.29 118.08,49.86 118.08,63.63 121.11,66.65 121.11,69.14 120.63,69.62 120.63,78.85 122.38,80.59 122.38,120.27 121.47,121.18 J12.62
  BOTTOM w0.147: v1(46.81,39.98) 47.06,39.73 48.72,39.73 50.25,41.26 54.5,41.26 55.49,40.27 57.96,40.27 62.3,44.6 72.44,44.6 72.58,44.74 74.23,44.74 75.02,45.53 85.41,45.53 87.17,43.76 87.17,39.56 95.97,30.76 v1(109.75,30.76)
UART2_RXD_FET: length 110.6
  TOP w0.147: U2351.6 48.94,43.51 50.01,44.58 v1(50.01,47.02) ; v1(83.36,46.58) 83.36,54.1 86.41,57.15 86.41,61.06 85.6,61.87 85.25,61.87 82.04,65.09 82.04,69.01 80.31,70.74 80.31,74.19 80.77,74.65 80.77,91.64 76.27,96.14 76.27,98.86 v1(73.08,102.06)
  BOTTOM w0.147: R5718.2 v1(73.08,102.06) 73.08,103.1 74.14,104.16 RA5.7 ; v1(83.36,46.58) 82.8,47.14 73.25,47.14 71.5,45.39 68.47,45.39 66.62,47.24 62.61,47.24 62.51,47.14 50.14,47.14 v1(50.01,47.02)
UART2_TXD: length 182.8
  TOP w0.147: v1(110.67,31.29) 115.29,31.29 120.02,36.02 120.02,48.44 118.49,49.96 118.49,63.53 121.49,66.52 121.49,69.32 120.98,69.82 120.98,78.69 122.73,80.44 122.73,120.53 121.28,121.98 J12.60 ; U2351.2 47.44,41.47 46.63,40.67 v1(45.92,40.67)
  BOTTOM w0.147: v1(110.67,31.29) 95.93,31.29 87.53,39.69 87.53,43.9 85.51,45.92 81.18,45.92 80.31,46.79 73.66,46.79 71.83,44.96 67.54,44.96 66.98,45.51 65.38,45.51 65.28,45.42 62.09,45.42 57.8,41.13 56.57,41.13 55.28,42.42 52.25,42.42 51.92,42.75 50.95,42.75 50.27,42.06 49.9,42.06 48.28,40.44 47.6,40.44 47.13,40.92 46.17,40.92 v1(45.92,40.67)
UART2_TXD_FET: length 56.3
  TOP w0.147: U2351.10 46.94,44.78 48.69,46.53 v1(49.45,46.53) ; U136.T4 v1(70.1,79.26)
  L03_SIG1 w0.091: v1(70.1,79.26) 70.1,79.02 70.47,78.64 70.47,75.4 69.83,74.76 69.83,72.09 69.53,71.79 69.53,64.93 68.86,64.27 68.86,57.13 67.21,55.47 66.45,55.47 64.7,53.72 64.7,47.02 v1(64.47,46.79)
  BOTTOM w0.147: v1(49.45,46.53) 50.32,46.53 50.57,46.79 v1(64.47,46.79)
UART3_FET_SEL: length 151.4
  TOP w0.147: U2352.1 57.81,43.99 57.99,44.17 R5800.2 58.85,44.7 v1(58.45,45.11) ; U21.14 90.68,143.17 90.4,143.46 87.66,143.46 83.13,138.94 v1(83.13,134.49) ; v1(54.91,44.04) 55.58,44.04 55.81,43.81 U2352.5
  L03_SIG1 w0.091: v1(54.91,44.04) 57.38,44.04 v1(58.45,45.11) 59.18,45.85 59.18,48.06 58.57,48.67 58.57,52.2 57.72,53.05 57.72,57.51 55.71,59.52 55.71,60.26 53.66,62.31 53.06,62.31 51.77,63.6 51.77,70.54 52.1,70.87 52.1,73.33 49.26,76.17 49.26,81.16 49.56,81.46 49.56,82.96 50.19,83.59 50.19,93.95 50.59,94.35 50.59,98.41 50.25,98.75 50.25,126.81 50.44,127 50.44,131.72 v1(49.96,132.21)
  BOTTOM w0.147: v1(49.96,132.21) 50.42,132.66 62.31,132.66 63.17,133.53 71.83,133.53 72.11,133.25 72.88,133.25 74.42,134.8 77.32,134.8 77.8,135.28 82.35,135.28 v1(83.13,134.49)
UART3_RXD: length 177.7
  TOP w0.147: v1(51.79,45.01) 52.27,44.53 55.75,44.53 56.31,43.97 U2352.4 ; J13.62 v1(8.74,145.24)
  L03_SIG1 w0.091: v1(8.74,145.24) 8.01,145.24 1.09,138.33 1.09,60.06 2.52,58.62 7.34,58.62 9.16,56.81 9.16,53.48 8.22,52.54 6.94,52.54 6.13,51.74 6.13,47.74 9.65,44.22 v1(9.65,43.31)
  BOTTOM w0.147: v1(51.79,45.01) 51.47,45.33 47.24,45.33 44.55,42.64 44.55,36.93 43.99,36.37 43.08,36.37 42.72,36.73 42.01,36.73 41.86,36.58 40.41,36.58 39.32,37.67 38.89,37.67 37.03,39.52 37.03,42.5 36.46,43.08 35.92,43.08 35.31,43.69 34.44,43.69 33.96,43.21 29.74,43.21 28.4,41.86 24.23,41.86 23.67,42.42 15.24,42.42 14.43,43.23 9.73,43.23 v1(9.65,43.31)
UART3_RXD_FET: length 57.7
  TOP w0.147: U136.C6 v1(58.9,80.86) ; U2352.6 v1(55.81,41.22)
  L03_SIG1 w0.091: v1(58.9,80.86) 57.95,79.91 52.91,79.91 52.74,80.08 51,80.08 50.35,79.43 50.35,77.36 53.21,74.5 53.21,70.36 52.88,70.03 52.88,65.2 54.43,63.65 55.19,63.65 56.16,62.69 56.16,61.93 56.87,61.21 57.61,61.21 58.62,60.2 58.62,58.57 59.36,57.84 59.36,52.5 59.13,52.27 59.13,48.9 59.73,48.3 59.73,44.48 59.09,43.84 59.09,42.52 57.35,40.79 56.24,40.79 v1(55.81,41.22)
UART3_TXD: length 178.5
  TOP w0.147: v1(8.86,144.44) J13.60 ; v1(57.72,45.17) 57.72,44.54 57.31,44.12 U2352.2
  L03_SIG1 w0.091: v1(8.86,144.44) 7.69,144.44 1.45,138.2 1.45,60.1 2.64,58.9 7.47,58.9 9.45,56.92 9.45,53.24 8.48,52.27 7.05,52.27 6.41,51.62 6.41,47.95 9.98,44.37 v1(10.44,44.37)
  BOTTOM w0.147: v1(57.72,45.17) 57.71,45.19 57.02,45.19 56.49,45.72 53.52,45.72 53.51,45.71 47.13,45.71 44.2,42.78 44.2,37.13 43.87,36.8 43.21,36.8 42.93,37.08 41.86,37.08 41.71,36.93 40.56,36.93 39.37,38.13 39.04,38.13 37.39,39.78 37.39,42.64 36.57,43.46 36.04,43.46 35.46,44.04 34.24,44.04 33.76,43.56 29.57,43.56 28.3,42.29 24.43,42.29 23.85,42.88 15.44,42.88 14.68,43.64 11.18,43.64 v1(10.44,44.37)
UART3_TXD_FET: length 57.4
  TOP w0.147: v1(61.65,40.31) 61.65,38.71 60.73,37.8 58.83,37.8 57.81,38.81 U2352.10 ; U136.N4 v1(67.7,79.26)
  L03_SIG1 w0.091: v1(61.65,40.31) 61.72,40.31 64.67,43.26 64.67,46.38 64.97,46.69 64.97,51.99 69.69,56.71 69.69,63.87 70.36,64.54 70.36,71.32 71.52,72.48 71.52,78.37 71.03,78.85 70.77,78.85 70.5,79.12 70.5,79.39 70.25,79.63 68.07,79.63 v1(67.7,79.26)
UART_SHIELD:
  vias: v1(61.92,3.76) v1(61.92,1.35)
USB_TYPEC1_EARTH:
  vias: v1(17.56,3.42) v1(17.56,2.51) v1(17.56,1.59) v1(18.48,3.42) v1(18.48,2.51) v1(18.48,1.59) v1(22.77,2.9) v1(22.77,1.37) v1(24.29,2.9) v1(24.29,1.37) v1(25.82,2.9) v1(25.82,1.37)
USB_TYPEC2_EARTH:
  vias: v1(32.44,5.97) v1(32.44,5.06) v1(32.44,4.14) v1(33.35,5.97) v1(33.35,5.06) v1(33.35,4.14) v1(37.77,2.9) v1(37.77,1.37) v1(39.29,2.9) v1(39.29,1.37) v1(40.82,2.9) v1(40.82,1.37)
USBC_CONN1_CC1: length 41
  TOP w0.147: v1(23.05,11.23) 23.23,11.04 D7.1 23.23,9.19 23.39,9.02 J24.A5 ; v1(25.91,20.27) 24.98,20.27 24.14,21.11 C307.1
  L03_SIG1 w0.091: v1(25.91,20.27) 26.66,19.53 35.48,19.53 36.35,18.67 36.35,12.97 32.56,9.17 24.21,9.17 23.05,10.34 v1(23.05,11.23)
  BOTTOM w0.147: U129.24 26.21,21.38 25.91,21.09 v1(25.91,20.27)
USBC_CONN1_CC2: length 40
  TOP w0.147: J24.B5 25.14,5.6 v1(24.89,5.35) ; C306.1 25.15,22.53 24.89,22.28 v1(24.89,21.08)
  L03_SIG1 w0.091: v1(24.89,21.08) 26.31,21.08 26.97,20.42 32.97,20.42 33.4,19.99 35.46,19.99 36.62,18.82 36.62,12.85 32.61,8.84 28.38,8.84 v1(24.89,5.35)
  BOTTOM w0.147: v1(24.89,21.08) 24.89,22.02 25.17,22.3 25.94,22.3 26.06,22.18 U129.26 ; v1(24.89,5.35) 24.76,5.22 D17.1
USBC_CONN2_CC1: length 18.9
  TOP w0.147: J25.A5 38.39,9.01 D8.1 v1(37.24,9.55) ; C305.1 v1(34.33,22.18)
  L03_SIG1 w0.091: v1(34.33,22.18) 33.9,21.75 33.9,20.94 34.38,20.47 35.53,20.47 36.9,19.11 36.9,9.89 v1(37.24,9.55)
  BOTTOM w0.147: U129.45 v1(34.33,22.18)
USBC_CONN2_CC2: length 25
  TOP w0.147: v1(41.2,4.85) 40.59,4.85 40.14,5.3 J25.B5 ; C312.1 v1(34.33,21.12)
  L03_SIG1 w0.091: v1(34.33,21.12) 36.22,21.12 37.17,20.16 37.17,14.47 41.61,10.03 41.61,5.26 v1(41.2,4.85)
  BOTTOM w0.147: U129.47 33.99,21.38 34.25,21.12 v1(34.33,21.12) ; D16.1 v1(41.2,4.85)
USBC_CONN2_DM: length 14.7
  TOP w0.107: v1(38.99,4.87) 39.29,5.17 39.29,5.46 39.14,5.61 J25.B7 ; v1(39.75,7.1) 39.64,7.21 39.64,7.44 39.89,7.69 J25.A7 39.89,8.24 39.5,8.63 39.5,9.15 D9.3 39.83,9.47 39.83,9.73 39.9,9.8 39.9,10.51 39.82,10.59 L10.3
  L03_SIG1 w0.094: v1(39.75,7.1) 39.52,7.33 39.52,7.77 39.22,8.08 37.34,8.08 36.91,7.65 36.91,6.55 37.47,5.99 38.86,5.99 39.27,5.58 39.27,5.15 v1(38.99,4.87)
USBC_CONN2_DP: length 13.9
  TOP w0.107: L10.2 38.97,10.6 38.86,10.49 38.86,9.83 38.96,9.73 38.96,9.47 D9.2 39.29,9.15 39.29,8.6 38.89,8.21 J25.A6 38.89,7.64 39.15,7.38 39.15,7.23 39.04,7.12 v1(39.04,7.1) ; J25.B6 39.64,5.61 39.51,5.48 39.51,5.16 v1(39.8,4.87)
  L03_SIG1 w0.094: v1(39.8,4.87) 39.52,5.15 39.52,5.69 38.96,6.24 37.57,6.24 37.15,6.66 37.15,7.54 37.44,7.83 39.12,7.83 39.28,7.67 39.28,7.34 v1(39.04,7.1)
VMAIN: length 8.7
  TOP w0.147: U3068.10 v1(28.15,159.5)
  TOP w0.254: U134.8 11.82,16.6 C3629.1 ; U134.12 6.54,16.6 6.24,16.91 C3631.1
  TOP w0.305: C310.1 18.53,20.3 18.64,20.41 U73.1 ; R5636.1 v1(25.39,165.04)
  TOP w0.381: R5740.1 14.07,16.38 C3625.1
  vias: v1(2.97,17.12) v1(3,16.21) v1(4.01,16.21) v1(4.88,17.12) v1(4.85,16.43) v1(5.66,16.43) v1(16.13,19.63) v1(16.13,19.13) v1(16.13,18.62) v1(16.13,18.11) v1(16.13,17.6) v1(16.64,19.63) v1(16.64,19.13) v1(16.64,18.62) v1(16.64,18.11) v1(16.64,17.6) v1(17.14,19.63) v1(17.14,19.13) v1(17.14,18.62) v1(17.14,18.11) v1(17.14,17.6) v1(28.14,159.99) v1(28.14,159)
VMAIN_EN: length 19.2
  TOP w0.147: LD14.1 25.43,37.52 v1(25.43,36.53) 25.08,36.18 U71.4
  L03_SIG1 w0.091: v1(19.79,25.98) 19.79,36.07 20.32,36.6 22.81,36.6 23.37,36.04 24.94,36.04 v1(25.43,36.53)
  BOTTOM w0.147: R382.1 v1(19.79,25.98)
VMAIN_PD: length 3.5
  BOTTOM w0.254: 32.59,16.31 32.45,16.44 U129.1 ; 28.62,16.27 28.62,16.86 U129.11 ; U129.11 28.29,16.86 28.29,16.27 ; U129.11 28.45,16.43 28.29,16.27 ; 28.29,16.27 v1(28.12,16.1)
  vias: v1(17.22,23.5) v1(17.3,24.51) v1(17.3,23.99) v1(17.7,23.55) v1(17.78,24.5) v1(17.78,24) v1(17.83,23.09) v1(18.26,23.36) v1(18.26,22.85) v1(18.77,23.36) v1(18.77,22.85) v1(19.31,23.13) v1(28.12,15.65) v1(28.12,15.19) v1(28.58,16.1) v1(28.58,15.65) v1(28.58,15.19) v1(32.95,16.11) v1(32.95,15.66) v1(33.41,16.11) v1(33.41,15.66) v1(33.87,16.11) v1(33.87,15.66) v1(34.32,16.11) v1(34.32,15.66)
VMON1: length 7
  TOP w0.147: R5774.2 22.06,53.71 22.41,54.06 R5773.1 24.52,54.06 24.62,54.16 C3750.2 25.76,54.16 25.97,54.36 U56.9
VPHY_3V3_FT4232: length 3.3
  TOP w0.147: U64.4 v1(49.47,27.54)
  BOTTOM w0.147: FL17.1 C606.2 49.21,27.79 v1(49.47,27.54)
VPLL_3V3_FT4232: length 6.6
  TOP w0.254: v1(51.97,25.22) U64.9
  TOP w0.305: v1(51.97,25.22) 52.12,25.06 52.12,23.93 v1(52.43,23.63) 52.44,23.61 R357.2
  BOTTOM w0.254: FL18.1 51.94,23.14 v1(52.43,23.63) 51.97,24.09 C607.2 v1(51.97,25.22)
VPP_1V8: length 1.9
  TOP w0.305: U136.G5 v1(62.1,80.06)
  L03_SIG1 w0.254: 61.85,79.65 62.1,79.9 v1(62.1,80.06) 61.92,80.06 61.72,79.86
  BOTTOM w0.254: v1(62.1,80.06) 62.22,80.18 C517.1
  vias: v1(55.83,65.66)
VPP_EN: length 136.7
  TOP w0.147: v1(95.66,140.28) 95.22,139.85 U21.5
  L03_SIG1 w0.091: v1(48.56,138.43) 49.5,137.49 49.5,130.51 50.17,129.84 50.17,127.28 49.91,127.03 49.91,98.42 49.69,98.2 49.69,97.63 50.31,97.01 50.31,96.65 49.98,96.32 49.84,96.32 49.59,96.06 49.59,89.44 49.33,89.18 49.33,86.48 49.62,86.2 49.62,83.42 49.28,83.08 49.28,81.58 48.98,81.29 48.98,76.04 51.82,73.2 51.82,70.99 51.44,70.61 51.44,60.07 52.8,58.7 v1(53.44,58.7)
  BOTTOM w0.147: v1(48.56,138.43) 49.4,138.43 50.25,139.28 56.15,139.28 57.25,138.18 68.33,138.18 69.55,139.4 85.58,139.4 87.83,141.66 94.28,141.66 v1(95.66,140.28) ; v1(53.44,58.7) 53.47,58.72 R319.1
VSEL_SD_SOC: length 39.6
  TOP w0.147: v1(48.64,84.38) 49.06,84.8 R5751.2 ; v1(56.11,51.64) 55.84,51.91 U3086.2
  L03_SIG1 w0.091: v1(56.11,51.64) 51.16,56.59 51.16,70.48 50.52,71.12 50.52,72.4 47.99,74.93 47.99,83.07 48.64,83.73 v1(48.64,84.38)
  BOTTOM w0.147: v1(56.11,51.64) 56.31,51.43 R5830.1
WD_DISABLE: length 13
  TOP w0.147: U56.29 31.32,59.61 31.77,60.07 32.91,60.07 32.95,60.07 32.97,60.07 33.02,60.07 33.57,60.63 37.06,60.63 37.39,60.96 37.39,62.1 37.53,62.24 R281.2 R282.2 39.26,62.24 39.64,62.62 TP56.1
WKUP_I2C0_SCL: length 119
  TOP w0.147: v1(40.36,91.08) 40.77,90.68 50.04,90.68 50.92,89.79 R301.2 ; R301.2 C245.1 ; R301.2 R284.1 ; R297.1 23.54,59.67 23.29,59.92 21.87,59.92 21.54,60.25 21.54,66.98 24.79,70.23 v1(24.79,71.02)
  L03_SIG1 w0.091: v1(28.37,117.22) 28.73,116.87 28.73,110.08 31.15,107.66 31.15,103.75 28.32,100.93 28.32,98.53 27.48,97.69 27.48,97.31 28.07,96.72 28.07,95.12 28.85,94.34 28.85,87.78 29.74,86.89 29.74,83.57 27.61,81.43 27.61,81.2 24.79,78.38 v1(24.79,71.02) ; v1(40.36,91.08) 40.04,91.08 39.44,91.68 39.44,94.95 38.99,95.39 38.99,108.08 39.55,108.64 39.55,109.09 39.54,109.1 39.54,115.5 v1(39.24,115.8)
  BOTTOM w0.147: v1(39.24,115.8) 38.43,116.61 34.37,116.61 33.07,117.91 29.06,117.91 v1(28.37,117.22)
WKUP_I2C0_SCL_RC: length 8.5
  TOP w0.132: 57.07,84.05 58.1,84.05 U136.B9
  TOP w0.147: 57.07,84.05 56.16,84.96 54.81,84.96 53.14,86.64 52.43,86.64 52.19,86.87 R284.2
WKUP_I2C0_SDA: length 115.6
  TOP w0.147: v1(42.44,88.01) 42.29,87.86 42.29,87.21 44.14,85.36 R256.1 R259.2 44.42,83.9 44.72,83.6 C248.1 ; R307.1 25.85,59.82 25.4,60.27 22.3,60.27 21.95,60.63 21.95,66.67 25.25,69.98 25.25,71.6 25.88,72.24 v1(29.41,72.24)
  L03_SIG1 w0.091: v1(29.16,116.76) 29.16,116.44 29.01,116.29 29.01,110.21 31.45,107.77 31.45,102.74 30.33,101.63 30.33,98.32 31.72,96.93 31.72,93.45 31.34,93.07 31.34,83.97 32.31,83.01 32.31,76.15 29.41,73.25 v1(29.41,72.24) ; v1(37.95,116) 37.95,113 37.59,112.65 37.59,109.19 38.68,108.1 38.68,95.31 39.16,94.83 39.16,91.3 v1(42.44,88.01)
  BOTTOM w0.147: v1(37.95,116) 37.69,116.26 34.14,116.26 32.84,117.55 29.95,117.55 v1(29.16,116.76)
WKUP_I2C0_SDA_RC: length 14
  TOP w0.147: R256.2 46.56,84.87 47.24,85.55 51.21,85.55 53.28,83.48 53.71,83.48 54.33,82.86 U136.A8
WKUP_LFOSCO_XI: length 17
  TOP w0.147: U136.E1 60.9,76.17 v1(60.43,75.7)
  BOTTOM w0.147: v1(60.43,75.7) 59.98,75.7 59.16,74.88 51.8,74.88 50.85,73.94 C216.2 49.82,73.94 49.82,73.94 49.73,73.94 49.36,73.57 Y4.1 47.07,73.57 46.38,74.26 R568.1
WKUP_LFOSCO_XO: length 5.5
  BOTTOM w0.147: R568.2 46.34,75.8 46.62,76.07 Y4.2 49.38,76.07 49.75,75.7 C213.2 50.29,75.71 R261.2
WKUP_UART0_CTSN: length 69.6
  TOP w0.147: v1(42.21,34.29) 41.96,34.54 R322.2 ; U136.D6 v1(59.7,80.86)
  L03_SIG1 w0.091: v1(46.58,77.72) 46.58,73.84 49.48,70.94 49.76,70.94 50.6,70.1 50.6,68.02 48.59,66.02 48.59,63.78 49.73,62.64 49.73,58.27 46.08,54.61 46.08,47.93 44.12,45.97 44.12,36.2 v1(42.21,34.29)
  BOTTOM w0.147: v1(59.7,80.86) 59.27,81.28 58.27,81.28 57.86,80.87 57,80.87 54.43,78.31 51.71,78.31 51.13,77.72 v1(46.58,77.72) ; v1(42.21,34.29) 41.29,33.37 U117.9
WKUP_UART0_RTSN: length 91.5
  TOP w0.147: U136.C5 v1(58.9,80.06)
  L03_SIG1 w0.091: v1(39.04,35.41) 41.55,32.9 43.93,32.9 45.75,34.72 45.75,36.67 46.51,37.43 47.86,37.43 48.56,36.73 48.56,31.19 49.78,29.98 50.43,29.98 52.02,31.57 52.02,34.49 60,42.48 60,48.43 59.41,49.02 59.41,52.07 59.82,52.48 59.82,59.59 55.45,63.96 54.53,63.96 53.77,64.72 53.77,69.7 53.49,69.98 53.49,74.63 50.63,77.49 50.63,79.32 51.11,79.8 52.38,79.8 52.63,79.55 58.39,79.55 v1(58.9,80.06)
  BOTTOM w0.147: R593.2 38.96,35.61 38.99,35.59 38.99,35.46 v1(39.04,35.41) 38.45,34.82 U117.7
WKUP_UART0_RXD: length 92.2
  TOP w0.132: 55.1,80.85 58.1,80.85
  TOP w0.147: 55.1,80.85 54.64,80.85 v1(54.23,80.44) ; v1(44.45,34.14) 43.21,34.14 42.8,34.54 R326.2 ; 58.1,80.85 U136.B5
  L03_SIG1 w0.091: v1(44.45,34.14) 44.78,34.14 45.47,34.83 45.47,36.78 46.39,37.71 47.99,37.71 49.02,36.68 49.02,31.65 49.53,31.15 49.97,31.15 50.65,31.83 50.97,31.83 51.54,32.39 51.54,38.6 54.65,41.71 55.94,41.71 56.52,41.13 57.3,41.13 58.78,42.6 58.78,43.92 59.46,44.6 59.46,48.17 58.84,48.79 58.84,52.39 59.08,52.63 59.08,57.66 58.34,58.39 58.34,60.07 57.48,60.93 56.69,60.93 55.88,61.75 55.88,62.56 55.07,63.37 54.28,63.37 52.6,65.05 52.6,70.15 52.93,70.48 52.93,74.37 50.08,77.23 50.08,79.54 50.98,80.44 v1(54.23,80.44)
  BOTTOM w0.147: v1(44.45,34.14) 43.71,34.87 39.15,34.87 38.85,34.57 U117.8
WKUP_UART0_TXD: length 161.8
  TOP w0.147: U136.A5 55.33,80.46 54.76,79.88 53.85,79.88 53.57,80.16 52.53,80.16 51.59,81.1 50.65,81.1 48.97,82.78 v1(48.57,82.78)
  L03_SIG1 w0.091: v1(36.8,38.35) 37.19,38.73 37.19,41.61 37.97,42.39 37.97,43.87 37.72,44.12 37.71,44.12 37.34,44.49 37.34,48.11 39.07,49.83 39.07,53.49 42.37,56.79 42.37,59.92 41.78,60.5 40.32,60.5 40.22,60.4 38.51,60.4 36.65,62.26 36.65,71.12 37.33,71.79 37.33,73.16 35.21,75.28 35.21,75.84 35.46,76.09 36.2,76.09 36.5,75.79 37.16,75.79 37.62,75.34 38.07,75.34 38.73,76 38.73,77.17 38.17,77.73 37.36,77.73 36.01,79.09 36.01,86.81 38,88.8 38,91.08 35.18,93.9 35.18,104.57 33.55,106.2 33.55,108.36 32.51,109.4 32.51,114.15 35.18,116.81 v1(35.18,119.02) ; v1(46.72,113.46) 48.09,112.09 48.09,105.1 49.17,104.01 49.17,101.27 48.39,100.48 48.39,99.72 48.67,99.44 48.67,99.24 49,98.91 49,90.25 48.04,89.29 48.04,85.84 49.07,84.82 49.07,83.76 48.57,83.27 v1(48.57,82.78)
  BOTTOM w0.147: v1(46.72,113.46) 45.45,114.73 43.84,114.73 39.24,119.33 35.64,119.33 35.63,119.32 35.48,119.32 v1(35.18,119.02) ; U117.6 38.05,34.52 37.67,34.91 37.67,35.84 37.69,35.86 R592.2 37.69,37.47 v1(36.8,38.35)
XDS110_DIR: length 2.9
  BOTTOM w0.147: U97.5 21.64,91.78 21.5,91.64 21.5,91.2 21.58,91.12 ; 21.58,91.12 21.58,90.96 21.36,90.74 R555.2 ; 21.58,91.12 22.17,91.12 22.43,91.38 U97.4
XDS110_EMU0: length 17.3
  TOP w0.147: R237.2 30.51,96.8 v1(30.51,96.6) 30.08,96.6 29.93,96.45 U48.42
  L03_SIG1 w0.091: v1(30.89,89.38) 30.07,90.2 30.07,96.16 v1(30.51,96.6)
  BOTTOM w0.147: U102.7 25.61,88.25 26.75,89.38 v1(30.89,89.38)
XDS110_EMU1: length 15.3
  TOP w0.147: U48.43 R236.2 29.02,97.01 28.88,96.86 v1(28.88,96.54)
  L03_SIG1 w0.091: v1(29.54,90.63) 29.54,95.88 v1(28.88,96.54)
  BOTTOM w0.147: U102.6 25.27,88.6 27.3,90.63 v1(29.54,90.63)
XDS110_TCK: length 12.3
  TOP w0.147: U48.35 32.73,94.27 33.1,93.9 v1(33.45,93.9)
  BOTTOM w0.147: v1(33.45,93.9) 33.45,93.29 32.38,92.23 26.37,92.23 26.01,92.58 U97.14
XDS110_TDI: length 9.6
  TOP w0.147: U48.38 31.53,93.62 30.74,92.82 26.38,92.82 v1(25.68,92.11)
  BOTTOM w0.147: U97.15 24.97,92.18 25.04,92.11 v1(25.68,92.11)
XDS110_TDO: length 19.3
  TOP w0.147: U48.37 31.93,93.48 30.38,91.92 28.83,91.92 27.36,90.45 27.36,88.16 26.75,87.55 26.75,85.57 25.55,84.38 23.24,84.38 22.61,85.02 v1(22.61,85.37)
  BOTTOM w0.147: v1(22.61,85.37) 22.61,85.02 22.69,84.93 U109.7
XDS110_TMS: length 10.9
  TOP w0.147: U48.36 32.33,93.63 v1(32.58,93.39)
  BOTTOM w0.147: v1(32.58,93.39) 31.77,92.58 26.7,92.58 26.29,92.98 U97.13
XDS110_TRST#: length 9.1
  TOP w0.147: U48.40 30.73,94.34 29.62,93.22 25.81,93.22 25.58,93.45 v1(24.97,93.45)
  BOTTOM w0.147: v1(24.97,93.45) 24.74,93.68 23.83,93.68 23.63,93.48 U97.12
XDS_GPIO1: length 1.6
  TOP w0.147: U40.2 5.14,91.71 5.23,91.8 R235.2
XDS_GPIO2: length 1.2
  TOP w0.147: U51.2 R283.2
XDS_GPIO3: length 1.6
  TOP w0.147: U40.4 R227.2
XDS_GPIO4: length 1.6
  TOP w0.147: U40.6 3.54,91.79 3.45,91.88 R221.2
XDS_PORZN: length 1.6
  TOP w0.147: R219.2 3.05,83.73 3.14,83.82 U40.8
XDS_POWERDOWN: length 1.6
  TOP w0.147: U40.12 4.74,83.82 4.83,83.73 R233.2
XDS_RSTN: length 6.6
  TOP w0.147: TP51.1 17.96,92.05 18.2,91.81 U48.70 20.51,91.81 20.82,92.12 v1(20.82,92.34)
  BOTTOM w0.147: v1(20.82,92.34) 20.17,92.34 19.76,91.92 R549.1 19.76,91 19.43,90.68 R556.1
XDS_USB_DM: length 53
  TOP w0.107: v1(20.96,82.79) 20.72,82.55 20.49,82.55 20.44,82.61 U48.93 ; v1(7.31,50.69) 7.06,50.44 6.74,50.44 6.52,50.66 J17.2
  L03_SIG1 w0.094: v1(20.96,82.79) 20.73,82.56 19.4,82.56 18.63,81.79 18.63,69.93 17.93,69.24 17.93,62 17,61.07 17,50.82 17.97,49.85 17.97,48.19 17.3,47.52 11.96,47.52 9.05,50.44 7.56,50.44 v1(7.31,50.69)
XDS_USB_DP: length 53
  TOP w0.107: v1(7.31,49.98) 7.06,50.22 6.74,50.22 6.52,50.01 J17.3 ; v1(20.96,82.03) 20.71,82.28 20.56,82.28 20.49,82.21 U48.94
  L03_SIG1 w0.094: v1(20.96,82.03) 20.67,82.31 19.5,82.31 18.87,81.69 18.87,69.83 18.18,69.14 18.18,61.9 17.25,60.97 17.25,50.92 18.21,49.95 18.21,48.09 17.4,47.28 11.86,47.28 8.95,50.19 7.52,50.19 v1(7.31,49.98)
XDS_USB_ID: length 52.9
  TOP w0.147: 8.1,48.23 7.96,48.09 7.74,48.09 6.47,49.36 J17.4 ; 8.1,48.23 8.1,50.08 8.27,50.24 U60.2 ; 8.1,48.23 9.37,48.23 11.53,50.39 v1(11.53,52.22) ; R271.2 14.96,82.3 12.19,85.06 v1(11.84,85.06)
  L03_SIG1 w0.091: v1(11.53,52.22) 11.53,54.36 12.24,55.07 12.24,62.94 12.57,63.27 12.57,63.89 11.8,64.67 11.8,69.38 12.04,69.62 12.04,74.19 11.28,74.96 11.28,77.32 11.7,77.74 11.7,78.15 11.28,78.58 11.28,84.51 v1(11.84,85.06)
XDS_USB_VBUS: length 27.4
  TOP w0.203: R295.1 34.07,76.43 33.61,75.97 24.36,75.97 22.81,74.42 v1(21.21,74.42)
  TOP w0.254: C250.1 8.97,52.17 8.97,51.67 9.22,51.41 U60.6
  TOP w0.305: v1(3.17,70) v1(3.17,70.76) ; TP78.1 21.21,73.78 v1(21.21,74.42) ; v1(19.48,76.1) 19.23,76.1 18.96,75.82 U55.2
  L03_SIG1 w0.305: v1(19.48,76.1) 19.48,79.47 v1(20.31,80.3)
  BOTTOM w0.254: v1(20.31,80.3) 18.36,80.3 17.62,81.03 R576.1
  vias: v1(9.77,51.27) v1(10.41,51.27) v1(20.85,74.75)
XDS_VREF: length 17.9
  TOP w0.147: U48.9 36.14,84.61 36.48,84.95 C215.2 36.95,85.31 37.47,85.83 37.47,87.33 37.67,87.53 37.67,91.06 37.47,91.26 37.47,95.48 36.93,96.02 R241.2 36.48,97.86 36.21,98.13 C190.1 35.53,98.13 35.53,98.13 U41.3
XDS_WARMRESETN: length 1.6
  TOP w0.147: U40.10 R224.2
ZENER_CLAMP: length 5.2
  TOP w0.305: R308.1 18.19,57.22 18.31,57.35 18.31,57.91 18.16,58.06 R298.1 17.13,58.06 16.93,57.86 D2.3
N16856152: length 6
  TOP w0.147: U64.3 48.97,25.25 48.22,24.5 48.22,24.23 C270.1 48.45,22.96 49.82,21.59 Y6.2
N16856224: length 6.1
  TOP w0.147: U64.2 48.47,25.43 47.68,24.64 47.68,24.3 C269.1 47.38,22.96 46.02,21.59 Y6.1
N16857368: length 1.1
  TOP w0.203: U66.2 48.97,11.18 48.68,11.47 C283.2
N16880083: length 2.2
  TOP w0.147: R21.2 117.88,69.28 U2.1 R18.1
N16956459: length 2.2
  TOP w0.147: R121.2 61.08,125.93 R122.1 60.14,125.93 U27.1
N16994873: length 1.1
  BOTTOM w0.147: R483.2 U88.4
N16994875: length 1
  BOTTOM w0.147: U87.4 R476.2
N16995245: length 0.9
  BOTTOM w0.147: C417.1 R487.2
N16997746: length 6.6
  TOP w0.147: R218.1 24.28,99.77 25.12,98.92 25.12,97.62 24.04,96.55 23.28,96.55 23.13,96.4 U48.59
N17030208: length 1.6
  BOTTOM w0.147: U97.7 21.22,92.58 20.93,92.87 R544.2
N17031262: length 2.7
  TOP w0.147: LD9.2 36.27,11.89 36.07,12.09 35.24,12.09 35.06,11.91 R402.2
N17078974: length 1.7
  BOTTOM w0.147: R438.2 J10.2
N17269599: length 1.9
  TOP w0.147: R363.1 R366.2 60.75,50.97 60.64,50.87 U68.6
N17269609: length 3
  TOP w0.147: R364.2 R367.1 ; R367.1 58.93,51.07 59.14,50.87 U68.1 ; R367.1 58.54,51.38 58.76,51.6 R362.1
N17378539: length 2
  TOP w0.147: R330.2 43.69,31.21 43.17,30.7 LD7.1
N17479799: length 1.4
  TOP w0.147: U55.8 v1(20.37,72.49)
  BOTTOM w0.147: R314.2 v1(20.37,72.49)
N17479805: length 4
  TOP w0.147: C243.2 16.02,74.46 16.1,74.38 R306.2 R313.1 U55.5
N17479881: length 3.3
  TOP w0.147: R246.1 17.16,93.64 17.39,93.4 C203.2 17.8,93.39 18.12,93.07 18.31,93.07 18.77,92.61 U48.68
N17481587: length 1.5
  TOP w0.147: LD5.2 33.81,77 34.32,77.52 R287.2
N17481598: length 6
  TOP w0.147: U48.96 C225.2 17.93,80.98 18.23,80.67 19.31,80.67 v1(19.56,80.92)
  BOTTOM w0.147: R576.2 18.6,81.45 19.13,80.92 v1(19.56,80.92)
N17481613: length 1.9
  TOP w0.147: U48.95 18.76,81.81 18.26,82.3 R271.1
N17481619: length 6.4
  TOP w0.147: U48.1 35.96,81.41 36.3,81.07 36.3,79.54 35.55,78.79 R289.1 R295.2
N17481621: length 3.7
  TOP w0.147: U48.60 22.73,96.57 23.22,97.05 v1(23.5,97.05) 23.58,97.05 23.73,97.2 R232.2
  BOTTOM w0.147: v1(23.5,97.05) 23.73,97.29 R232.2
N17481627: length 2.1
  TOP w0.147: R276.1 36.3,82.01 36.1,82.21 U48.3
N17481631: length 1.1
  TOP w0.147: R276.2 LD3.2
N17481633: length 4.6
  TOP w0.147: U48.63 21.53,96.32 20.88,96.98 v1(20.45,96.98) 20.09,96.98 19.92,97.15 R229.2
  BOTTOM w0.147: v1(20.45,96.98) 20.09,96.98 19.92,97.15 R229.2
N17481635: length 3.1
  TOP w0.147: U48.61 22.33,96.85 v1(22.46,96.97) R231.2
  BOTTOM w0.147: R231.2 v1(22.46,96.97)
N17481637: length 5.3
  TOP w0.147: R287.1 34.36,80.75 33.9,81.21 33.9,82.38 34.14,82.61 U48.4
N17481641: length 3.5
  TOP w0.147: U48.62 21.93,96.58 v1(21.54,96.97) 21.19,97.33 R230.2
  BOTTOM w0.147: v1(21.54,96.97) 21.19,97.33 R230.2
N17824845: length 1.6
  BOTTOM w0.147: R654.1 30.3,24.97 30.3,24.41 30.25,24.36 U129.36
N17824852: length 1.6
  BOTTOM w0.147: R653.1 30.81,24.73 30.65,24.58 U129.37
N17824859: length 1.7
  BOTTOM w0.147: R652.1 31.57,24.96 31.07,24.45 31.07,24.11 31.05,24.1 U129.38
N17824866: length 2
  BOTTOM w0.147: R651.1 32.33,24.87 32.03,24.56 31.83,24.56 31.45,24.19 U129.39
N19741013: length 2.1
  BOTTOM w0.147: U129.18 26.05,18.98 25.83,19.2 25.83,19.56 25.58,19.81 R390.2
N19806973: length 1.2
  BOTTOM w0.147: R566.2 27,85.77 26.58,85.36 U110.7
N21761137: length 7.8
  TOP w0.147: U136.A7 53.84,82.06 53.64,81.86 53.29,81.86 52.98,82.17 52.98,82.5 51.96,83.53 R5750.1
N21784165: length 5.3
  TOP w0.132: U136.V11 71.3,85.11 71.7,84.7 71.7,84.29 71.93,84.06 72.41,84.06 72.78,83.69
  TOP w0.147: 72.78,83.69 72.97,83.5 74.05,83.5 74.49,83.94 R548.1
N21784176: length 9.2
  TOP w0.132: 74.9,84.99 74.4,84.99 73.99,84.58 73.53,84.58 73.28,84.84 72.72,84.84 72.7,84.86 71.93,84.86 71.7,85.09 71.7,85.41 71.46,85.65 70.89,85.65 U136.U11
  TOP w0.147: 74.9,84.99 76.53,84.99 77.34,84.18 R541.1
N22498870: length 1.9
  BOTTOM w0.147: R602.1 R605.2 102.47,48.15 102.57,48.05 U120.6
N22498881: length 3
  BOTTOM w0.147: R606.1 103.97,48.25 103.76,48.05 U120.1 ; R606.1 105,48.25 R604.2 ; R606.1 104.55,48.54 104.32,48.77 R601.1
N22682556: length 2.2
  BOTTOM w0.147: J21.1 22.93,30.4 R633.2
N22682559: length 1.9
  BOTTOM w0.147: J21.3 22.65,32.94 R627.2
N24306091: length 12
  TOP w0.147: U3076.5 10.5,67.27 10.19,67.58 ; 10.19,67.58 C3746.2 10.19,68.48 10.52,68.81 11.3,68.81 12.32,67.79 12.32,64.97 13.81,63.48 R293.1 ; 10.19,67.58 9.85,67.25 U3076.6
N24306103: length 1.3
  TOP w0.305: Q4.1 13.81,60.93 13.81,60.94 R293.2
N24306157: length 47.9
  TOP w0.203: D5.3 26.06,19.36 27.23,20.52 27.79,20.52 28.19,20.93 28.19,23.14 27.56,23.77 25.58,23.77 v1(23.93,25.43)
  TOP w0.305: R308.2 18.19,54.51 v1(18.72,53.98)
  L03_SIG1 w0.254: v1(18.72,53.98) 19.18,53.52 19.18,43.74 17.14,41.71 17.14,27.71 19.43,25.43 v1(23.93,25.43)
N24306190: length 1.5
  TOP w0.305: Q4.3 R298.2
N24307354: length 3
  TOP w0.254: U56.4 26.33,56.86 v1(26.06,56.59)
  BOTTOM w0.203: R5828.2 25.35,55.88 v1(26.06,56.59)
N24307356: length 3.1
  TOP w0.254: U56.6 v1(26.26,55.86)
  BOTTOM w0.254: v1(26.26,55.86) 25.96,55.57 25.96,55.09 25.65,54.79 R5829.2
N24478126: length 1.5
  TOP w0.147: C70.1 U4.4
N24517110: length 1.3
  TOP w0.147: R214.2 36.3,100.46 SW3.3
N24517112: length 1.3
  TOP w0.147: SW3.4 R217.2
N24605604: length 14.3
  TOP w0.147: J2.5A 66.92,166 66.29,165.38 66.29,159.18 65.84,158.72 64.08,158.72 63.91,158.9 63.91,159.42 65.1,160.61 C18.1
N24605606: length 14.2
  TOP w0.147: C16.1 61.21,160.68 59.86,159.33 59.86,158.72 59.36,158.22 57.98,158.22 55.78,160.42 J2.2A
N24605709: length 2.8
  TOP w0.147: R84.2 68.7,137.91 U14.1 67.63,137.91 R90.1
N24605835: length 4.7
  TOP w0.147: U7.20 56.21,152.78 57.05,153.62 57.05,153.87 57.26,154.08 57.26,155.69 TP5.1
N24605846: length 3.3
  TOP w0.147: L3.2 56.12,145.23
  TOP w0.203: 56.12,145.23 55.71,145.63 U7.4
N24605909: length 10.2
  BOTTOM w0.147: J2.5B 57.72,167.81 57.72,165.14 58.86,164 59.83,164 60.43,164.59 60.43,165.02 61.71,166.31 C333.1
N24606047: length 2
  TOP w0.147: U7.19 56.71,152.56 56.84,152.69 TP8.1
N24606049: length 2.4
  TOP w0.147: TP9.1 59.22,153.1 58.17,152.05 U7.17
N24606166: length 9.4
  BOTTOM w0.147: C331.1 65.58,166.34 64.34,165.1 64.34,164.41 64.62,164.13 65.15,164.13 66.37,165.35 66.37,167.84 J2.2B
N24847876: length 1.4
  BOTTOM w0.147: R421.1 U77.4
N24847884: length 13.7
  BOTTOM w0.147: C348.1 81.68,160.81 81.08,161.42 81.08,165.73 78.31,168.5 J3.5B
N24847886: length 9.2
  BOTTOM w0.147: J3.2B 83.06,167.38 83.06,163.75 84.18,162.64 84.18,161.56 83.76,161.14 C347.1
N24847888: length 4
  BOTTOM w0.147: C347.2 83.55,158.57 82.83,157.84 82.83,155.75 82.94,155.64 U77.21
N24847892: length 5.8
  BOTTOM w0.147: C344.2 80.62,159.24 80.62,157.89 80.82,157.68 81.79,157.68 81.94,157.54 U77.19
N24847894: length 6.2
  BOTTOM w0.147: C343.2 84.86,159.23 84.86,157.91 84.66,157.71 83.44,157.71 83.24,157.51 83.24,156.21 83.44,156.01 U77.22
N24847910: length 3.8
  BOTTOM w0.147: C348.2 82.44,157.79 U77.20
N24847912: length 1.7
  BOTTOM w0.147: TP113.1 82.44,149.66 U77.11
N24847957: length 1.2
  BOTTOM w0.147: C367.1 80.39,152.55 80.66,152.82 U77.15
N24847963: length 1.1
  BOTTOM w0.147: U77.16 80.13,153.32 C365.1
N24847969: length 1.2
  BOTTOM w0.147: C362.1 80.32,154.07 80.57,153.82 U77.17
N24847975: length 1.3
  BOTTOM w0.147: U77.18 80.73,154.32 80.22,154.83 C360.1
N24847993: length 1.7
  BOTTOM w0.147: U77.9 83.44,149.64 TP112.1
N24847995: length 2.9
  BOTTOM w0.147: U77.10 82.94,148.51 TP115.1
N24848039: length 1.5
  TOP w0.147: R24.1 U5.4
N24848041: length 12.9
  TOP w0.147: C25.1 76.68,160.91 77.14,161.37 77.14,163.5 79.64,166 J3.5A
N24848043: length 6.6
  TOP w0.147: J3.2A 74.19,164.73 74.19,161.54 74.65,161.09 C24.1
N24848045: length 3.8
  TOP w0.147: C24.2 74.65,157.92 75.42,157.16 U5.21
N24848047: length 5.8
  TOP w0.147: U5.19 76.42,157.55 76.62,157.75 77.59,157.75 78.13,158.29 C23.2
N24848049: length 5.6
  TOP w0.147: C22.2 73.24,159.56 73.24,158.19 73.69,157.74 74.29,157.74 74.92,157.11 U5.22
N24848518: length 3.9
  TOP w0.147: U5.20 75.92,157.88 76.58,158.54 C25.2
N24848523: length 1.7
  TOP w0.147: TP18.1 76.1,150.08 75.92,150.27 U5.11
N24848568: length 1.2
  TOP w0.147: U5.15 77.71,152.82 77.99,152.55 C61.1
N24848574: length 1.1
  TOP w0.147: C56.1 78.23,153.32 U5.16
N24848580: length 1.2
  TOP w0.147: C50.1 77.92,154.07 77.67,153.82 U5.17
N24848586: length 1.4
  TOP w0.147: U5.18 77.64,154.32 77.75,154.43 77.75,154.7 77.88,154.83 C47.1
N24848600: length 1.2
  TOP w0.147: R24.2 TP12.1
N24848612: length 1.3
  BOTTOM w0.147: TP109.1 88.13,152.82 R421.2
N24848616: length 1.7
  TOP w0.147: TP17.1 74.76,150.02 74.92,150.18 U5.9
N24848618: length 2.8
  TOP w0.147: U5.10 TP22.1
N24851304: length 1.6
  BOTTOM w0.147: R420.1 U76.4
N24851306: length 1.5
  TOP w0.147: v1(105.26,152.39) 104.89,152.39 TP14.1
  BOTTOM w0.147: R420.2 105.11,152.82 105.26,152.67 v1(105.26,152.39)
N24851312: length 13.7
  BOTTOM w0.147: C346.1 99.07,161.05 98.32,161.8 98.32,165.89 95.71,168.5 J4.5B
N24851314: length 11.1
  BOTTOM w0.147: C345.1 101.1,161.15 101.52,161.57 101.52,162.08 99.21,164.39 99.21,167.54 100.17,168.5 J4.2B
N24851316: length 3.8
  BOTTOM w0.147: U76.21 100.34,157.8 C345.2
N24851320: length 5.8
  BOTTOM w0.147: C342.2 97.96,159.29 97.96,157.92 98.22,157.66 99.19,157.66 99.34,157.51 U76.19
N24851322: length 5.8
  BOTTOM w0.147: C341.2 102.19,159.26 102.19,157.92 101.98,157.71 100.98,157.71 100.84,157.56 U76.22
N24851338: length 3.8
  BOTTOM w0.147: C346.2 99.84,157.8 U76.20
N24851340: length 1.7
  BOTTOM w0.147: U76.11 99.84,149.66 TP111.1
N24851385: length 1.2
  BOTTOM w0.147: C366.1 97.78,152.55 98.06,152.82 U76.15
N24851391: length 1.1
  BOTTOM w0.147: C364.1 98.58,153.31 U76.16
N24851397: length 1.2
  BOTTOM w0.147: C361.1 97.75,154.07 98,153.82 U76.17
N24851403: length 1.3
  BOTTOM w0.147: C359.1 98.03,154.32 U76.18
N24851421: length 1.7
  BOTTOM w0.147: U76.9 100.84,149.64 TP110.1
N24851423: length 2.6
  BOTTOM w0.147: U76.10 TP114.1
N24851452: length 1.5
  TOP w0.147: R25.1 U6.4
N24851454: length 1
  TOP w0.147: R25.2 TP11.1
N24851456: length 13
  TOP w0.147: C27.1 94.08,160.71 94.41,161.04 94.41,163.65 96.76,166 J4.5A
N24851458: length 6.6
  TOP w0.147: C26.1 92.05,160.76 91.47,161.34 91.47,164.86 J4.2A
N24851460: length 3.8
  TOP w0.147: C26.2 92.82,157.78 U6.21
N24851462: length 6
  TOP w0.147: C21.2 95.1,159.42 95.1,157.91 94.95,157.76 94.08,157.76 93.82,157.5 U6.19
N24851464: length 6
  TOP w0.147: U6.22 92.32,155.07 92.32,157.55 92.1,157.76 91.22,157.76 91.03,157.95 91.03,159.46 C20.2
N24851486: length 3.8
  TOP w0.147: U6.20 93.32,157.78 C27.2
N24851488: length 1.7
  TOP w0.147: U6.11 93.32,150.27 93.5,150.08 TP20.1
N24851535: length 1.2
  TOP w0.147: C62.1 95.36,152.82 U6.15
N24851541: length 1.1
  TOP w0.147: U6.16 95.62,153.32 C57.1
N24851547: length 1.2
  TOP w0.147: C51.1 95.39,153.82 U6.17
N24851553: length 1.3
  TOP w0.147: U6.18 95.11,154.32 95.62,154.83 C48.1
N24851571: length 1.7
  TOP w0.147: U6.9 92.32,150.13 92.16,149.97 TP19.1
N24851573: length 2.8
  TOP w0.147: U6.10 TP23.1
N25521527: length 4.3
  TOP w0.147: U7.18 57.21,152.53 57.46,152.78 58.17,152.78 58.49,153.1 58.49,154.32 TP6.1
N25809420: length 9.1
  TOP w0.152: 71.88,42.75 71.9,42.77
  TOP w0.305: 84.12,42.65 84.1,42.67 83.36,42.67 82.94,42.25 J18.SH4 82.94,41.24 v1(83.17,41.01) ; 72.29,38.91 72.67,39.29 J18.SH1 ; 71.9,42.77 72.33,42.77 72.67,42.43 J18.SH2 ; J18.SH3 82.94,39.28 83.23,39 83.67,39
  BOTTOM w0.147: C610.1 84.49,40.3 84.34,40.15 v1(84.34,39.32)
N25815350: length 5.1
  TOP w0.305: J19.SH1 105.1,39.36 104.73,38.99 v1(104.5,38.99) ; J19.SH4 115.37,42.68 115.38,42.68 115.6,42.9 ; J19.SH2 105.1,42.62 104.77,42.95 ; J19.SH3 115.37,38.99
  vias: v1(103.92,38.99) v1(104.88,41)
N26271323: length 1.7
  BOTTOM w0.147: R386.2 25.6,18.9 25.92,18.58 U129.17
N27107689: length 1.8
  TOP w0.147: C308.1 21.71,20.9 21.22,20.41 U73.3
N27107697: length 1.9
  TOP w0.147: v1(20.14,23.14) 19.97,22.97 U73.5
  BOTTOM w0.147: R382.2 19.79,23.47 20.11,23.15 20.13,23.15 v1(20.14,23.14)
N27107782: length 1.3
  TOP w0.147: R395.2 20.15,19.81 19.97,19.98 U73.2
N27116765: length 1.8
  TOP w0.147: U59.5 54.43,59.66 54.43,59.66 v1(54.43,59.31)
  BOTTOM w0.147: R319.2 54.59,58.97 54.43,59.13 v1(54.43,59.31) R320.1
N27118410: length 1.4
  TOP w0.147: U46.3 R240.2
N27118414: length 2.8
  TOP w0.147: U46.4 R258.1 R255.2
N27132714: length 1.5
  TOP w0.147: SW2.13 R137.1
N27132716: length 1.5
  TOP w0.147: SW2.14 R136.1
N27132718: length 1.5
  TOP w0.147: SW2.15 R135.1
N27132720: length 1.5
  TOP w0.147: SW2.16 R134.1
N27132816: length 1.5
  TOP w0.147: SW1.11 R131.1
N27132818: length 1.5
  TOP w0.147: SW1.12 R130.1
N27132820: length 1.5
  TOP w0.147: SW1.13 R129.1
N27132822: length 1.5
  TOP w0.147: SW1.14 R128.1
N27132824: length 1.5
  TOP w0.147: SW1.9 R133.1
N27132826: length 1.5
  TOP w0.147: SW1.10 R132.1
N27132828: length 1.5
  TOP w0.147: SW1.15 R127.1
N27132836: length 1.5
  TOP w0.147: SW1.16 R126.1
N27133243: length 1.5
  TOP w0.147: SW2.9 R141.1
N27133247: length 1.5
  TOP w0.147: SW2.10 R140.1
N27133249: length 1.5
  TOP w0.147: SW2.11 R139.1
N27133251: length 1.5
  TOP w0.147: SW2.12 R138.1
N27148451: length 2.7
  TOP w0.147: R125.2 52.58,106.29 52.87,105.99 U28.A5
N27161108: length 3.6
  TOP w0.147: D6.3 44.71,13.21 43.95,12.46 R398.2 R401.1
N27162183: length 11.3
  TOP w0.254: C318.2 45.22,15.11 46.11,14.22 48.67,14.22 48.92,14.48 48.92,17.47 v1(47.92,18.47)
  BOTTOM w0.147: v1(47.92,18.47) R675.2 C638.2 46.71,17.93 46.61,18.04 Q8.3
  vias: v1(41.57,15.53) v1(41.57,15.07) v1(41.57,14.61) v1(41.57,14.15)
N27162479: length 3.7
  BOTTOM w0.147: R672.1 R673.2 ; R672.1 R669.2 ; R672.1 Q10.3
N27173972: length 2.3
  TOP w0.147: R203.2 69.68,131.15 Q1.3 R213.2
N27173989: length 3
  TOP w0.147: Q5.3 R441.2 59.73,132.82 59.99,132.56 R442.2
N27174010: length 6.4
  TOP w0.147: Q5.5 61.91,132.2 Q5.8 ; Q5.1 62.56,132.85 Q5.8 ; Q5.8 62.56,132.2 Q5.6 62.56,130.98 62.11,130.53 LD10.1 ; Q5.8 61.91,132.85 Q5.2
N27174034: length 6.5
  TOP w0.147: Q1.8 67.17,132.45 Q1.6 ; Q1.8 67.17,131.8 Q1.1 LD1.1 ; Q1.8 67.82,131.8 Q1.2 ; Q1.8 67.82,132.45 Q1.5
N27174097: length 1.7
  TOP w0.147: R180.1 65.55,134.36 65.14,133.95 LD1.2
N27174144: length 1.7
  TOP w0.147: LD10.2 61.13,127.71 60.62,128.22 R440.1
N27175817: length 5.5
  TOP w0.147: R74.2 74.47,58.64 C104.2 72.53,58.64 71.83,57.94 Y1.1
N27175821: length 7.5
  TOP w0.147: Y1.3 69.29,60.73 69.72,60.3 73.01,60.3 73.7,59.61 C105.1 74.04,59.61 R73.2
N27175987: length 16.8
  TOP w0.147: U15.3 76.71,58.14 v1(76.45,57.87) ; v1(77.75,60.43) 77.75,60.24 U15.24 ; U15.15 82.04,57.64 v1(82.3,57.89) 82.05,58.14 U15.16
  BOTTOM w0.147: C383.1 76.69,57.63 v1(76.45,57.87) 76.45,58.1 76.74,58.39 C382.1 77.3,58.94 76.5,59.74 76.5,60.1 76.83,60.43 v1(77.75,60.43) 77.75,60.27 77.99,60.03 C384.1 78.46,60.03 78.9,59.59 C385.1 79.23,59.05 79.4,58.88 79.9,58.88 80,58.98 81.23,58.98 81.74,58.47 C386.1 81.94,58.25 v1(82.3,57.89) 82.3,57.64 82.15,57.49 C387.1
N27176057: length 1.8
  TOP w0.147: TP36.1 77.65,55.11 77.94,55.11 78.2,55.37 U15.7
N27176072: length 1.3
  TOP w0.147: U15.22 R89.2
N27176107: length 4.7
  TOP w0.147: TP39.1 81.28,62.33 81.08,62.53 80.19,62.53 79.7,62.05 U15.21
N27176638: length 1.4
  TOP w0.147: U15.11 80.2,55.39 TP37.1
N27176640: length 2.2
  TOP w0.147: U15.20 80.2,61.17 TP38.1
N27224404: length 2.2
  TOP w0.147: v1(47.45,148.52) U8.29
  BOTTOM w0.147: v1(47.45,148.52) R433.2
N27224468: length 9.8
  BOTTOM w0.147: J1.5B 40.72,167.67 40.72,165.46 41.99,164.19 42.95,164.19 43.36,164.59 43.36,165.13 44.57,166.33 C337.1
N27224561: length 3.3
  TOP w0.147: L2.2 43.64,152.62 ; U8.4 44.05,150.78
  TOP w0.203: U8.4 44.04,152.22 43.64,152.62
N27224667: length 9.2
  BOTTOM w0.147: J1.2B 49.07,167.68 49.07,165.48 47.73,164.13 47.47,164.13 47.19,164.41 47.19,165.1 48.43,166.34 C335.1
N27224751: length 5.5
  TOP w0.147: U8.18 42.54,145.09 42.06,144.61 39.21,144.61 38.67,145.15 TP27.1
N27224753: length 4.8
  TOP w0.147: U8.20 43.54,145.04 41.75,143.25 TP31.1
N27224897: length 13.7
  TOP w0.147: C14.1 47.91,160.66 46.74,159.49 46.74,158.95 47.08,158.61 48.8,158.61 49.45,159.26 49.45,164.32 J1.5A
N27225024: length 2.3
  TOP w0.147: U8.32 46.87,150.02 46.98,150.14 C78.1 47.63,150.14 48,149.76 C77.1
N27225078: length 14.4
  TOP w0.147: C12.1 44.04,160.68 42.7,159.33 42.7,158.72 42.19,158.22 40.54,158.22 38.63,160.12 38.63,164.19 38.64,164.19 J1.2A
N27225127: length 8
  TOP w0.147: U8.19 43.04,145.06 42.17,144.19 37.52,144.19 TP26.1
N27225129: length 3
  TOP w0.147: TP25.1 40.67,145.55 41.14,145.08 41.86,145.08 42.04,145.26 U8.17
N27225150: length 2.1
  TOP w0.147: R46.2 48.34,148.02 U8.28
N27226002: length 2.4
  BOTTOM w0.147: R414.2 56.84,162.01 U75.1 55.75,162.01 R413.1
N27239473: length 1.2
  BOTTOM w0.147: R591.2 37.21,34.8 37.65,34.36 U117.5
N27239479: length 2.4
  BOTTOM w0.147: U117.4 36.96,33.37 36.8,33.53 36.8,34.16 36.32,34.65 R590.1
N27239774: length 4.1
  BOTTOM w0.147: U125.16 54.72,28.75 54.73,28.75 ; 54.73,28.75 55.15,28.32 R5833.1 55.8,27.4 R5832.2 ; 54.73,28.75 54.27,28.75 54.12,28.89 U125.1
N27239926: length 1.8
  BOTTOM w0.147: R635.2 61.64,25.55 61.35,25.84 61.35,25.84 61.36,25.85 61.36,26.52 61.35,26.52 U126.5
N27239932: length 2.5
  BOTTOM w0.147: U126.4 61.98,27.47 62.17,27.28 62.17,27 61.91,26.74 61.91,26.24 62.1,26.05 R636.1
N27240077: length 1.2
  BOTTOM w0.147: U125.5 51.97,29.44 51.52,29 R613.2
N27240083: length 2.2
  BOTTOM w0.147: R614.1 51.58,28.12 52.2,28.74 52.62,28.74 52.92,29.04 U125.4
N27243596: length 1.4
  TOP w0.147: U51.3 13.81,79.52 14.1,79.81 14.1,80.08 TP61.1
N27243598: length 1.8
  TOP w0.147: U51.6 11.26,79.52 TP58.1
N27248134: length 2.1
  BOTTOM w0.147: R579.2 6.97,77.31 6.88,77.21 U107.2
N27248136: length 2.2
  BOTTOM w0.147: R580.2 7.86,77.41 8.15,77.12 U107.3
N27566274: length 4.7
  TOP w0.147: LD2.1 37.58,68.94 38.63,70 v1(38.63,70.23)
  BOTTOM w0.147: v1(38.63,70.23) 38.88,70.48 39.38,70.48 39.77,70.88 Q2.3
N27566278: length 3.3
  TOP w0.147: v1(37.11,69.34) 35.87,69.34 35.48,68.95 LD2.2
  BOTTOM w0.147: R260.1 v1(37.11,69.34)
N27566306: length 2.7
  BOTTOM w0.147: R272.2 41.25,71.74 40.72,71.21 Q2.1
N27566380: length 1
  TOP w0.147: LD4.2 R292.1
N27566388: length 1.3
  TOP w0.147: Q3.3 LD4.1
N27566452: length 5
  TOP w0.147: SW7.2 36.16,39.67 36.47,39.98 v1(36.47,40.34)
  BOTTOM w0.147: D13.2 35.09,41.13 C613.2 35.09,40.53 35.29,40.34 v1(36.47,40.34)
N27765807: length 1.2
  TOP w0.147: R3661.2 C3639.1
N27766023: length 1.8
  TOP w0.203: R5805.1 5.98,15.11 6.4,15.53 U134.13
N27780868: length 4.3
  BOTTOM w0.147: U135.2 44.17,80.24 44.34,80.07 R3723.2 45.05,79.08 44.2,78.24 R3724.1
N27781327: length 1.9
  BOTTOM w0.147: R3725.2 41.01,78.85 40.82,79.04 40.82,79.35 41.06,79.59 U135.4
N27827107: length 9.8
  TOP w0.147: TP594.1 54.18,92.57 54.18,88.06 56.19,86.05 U136.A12
N27866324: length 1.7
  TOP w0.147: LD6.2 R324.1
N27969798: length 2.8
  BOTTOM w0.147: R329.1 69.6,55.16 69.91,54.86 U62.1
N27969912: length 1.3
  BOTTOM w0.147: U65.2 R348.1
N27970038: length 3
  BOTTOM w0.147: U65.3 55.19,54.92 55.75,55.48 R349.1
N27970040: length 2.4
  BOTTOM w0.147: U65.5 59.14,55.57 58.5,56.22 R358.1
N27970042: length 1.4
  BOTTOM w0.147: R359.1 61.07,53.62 61.06,53.62 U65.8
N27972730: length 11.1
  TOP w0.147: U136.D2 v1(60.5,77.65)
  BOTTOM w0.147: R261.1 51.51,76.27 52.11,75.66 58.5,75.66 v1(60.5,77.65)
N27975044: length 5
  TOP w0.147: Y3.1 49.67,77.03 49.95,77.32 51.4,77.32 51.58,77.14 C205.2 52.78,77.14 53.19,76.74 R252.1
N27975050: length 2.5
  TOP w0.147: R253.1 52.52,75.13 52.51,75.13 C209.2 Y3.3
N27975317: length 2.5
  TOP w0.147: R3733.2 C3657.2 59.13,72.57 59.51,72.19 Y8.1
N27975321: length 6.6
  TOP w0.147: Y8.3 56.86,69.79 57.28,70.21 57.28,73.28 56.89,73.66 C3658.1 56.54,73.97 56.69,74.12 R3732.2
N27995683: length 8.4
  TOP w0.147: v1(51.94,98.04) 51.38,97.49 49.89,97.49 49.57,97.16 47.34,97.16 46.89,97.61 U140.C3
  BOTTOM w0.147: R5752.2 53.55,98.04 53.07,98.53 52.78,98.53 52.3,98.04 v1(51.94,98.04)
N28038972: length 2.4
  TOP w0.147: U2.6 117.88,67.75 118.21,67.42 118.91,67.42 119.18,67.15 R5213.1
N28044811: length 7.6
  TOP w0.147: J34.1 C1.1 R5636.2 23.61,164.22 23.85,163.98 25.27,163.98 25.87,163.38 R5635.2
N28049053: length 1.8
  TOP w0.147: R69.2 104.27,145.39 104.06,145.61 U11.6
N28071414: length 2
  BOTTOM w0.147: U2345.10 95.37,114.71 94.89,115.19 R5684.1
N28080788: length 1.5
  TOP w0.147: U29.4 91.36,60.13 90.95,60.53 R143.1
N28081065: length 1.1
  TOP w0.147: U2347.7 88.67,54.87 88.49,55.05 88.39,55.05 R5686.2
N28082506: length 10.5
  TOP w0.132: 56.79,85.65 57.53,85.65 57.53,85.65 58.1,85.65 U136.B11 ; 54.89,86.84 56.08,85.65 56.31,85.65
  TOP w0.147: 54.89,86.84 53.82,87.91 53.82,90.87 TP586.1 ; 56.31,85.65 56.79,85.65
N28084397: length 4.2
  TOP w0.147: U136.U13 v1(70.9,87.25)
  BOTTOM w0.132: 73.44,86.92 72.59,86.92 71.86,87.65 71.29,87.65 v1(70.9,87.25)
  BOTTOM w0.147: R530.1 73.62,87.1 73.44,86.92
N28084399: length 4.8
  TOP w0.147: R535.1 75.92,87.12 75.41,87.63 73.79,87.63 73.01,86.85 U136.W13
N28084409: length 2.9
  TOP w0.147: U136.T14 v1(70.1,88.05)
  BOTTOM w0.132: v1(70.1,88.05) 70.5,87.65 70.5,87.09 70.74,86.85 71.32,86.85 R537.1
N28084411: length 2.5
  TOP w0.147: U136.U14 v1(70.9,88.05)
  BOTTOM w0.132: v1(70.9,88.05) 71.29,88.45 71.83,88.45
  BOTTOM w0.147: R529.1 72.28,88.34 72.17,88.45 71.83,88.45
N28084427: length 2.7
  TOP w0.147: U136.V16 v1(71.7,88.85)
  BOTTOM w0.132: R509.1 73.22,89.3 72.78,88.85 v1(71.7,88.85)
N28084429: length 3.6
  TOP w0.147: R518.1 74.35,88.32 73.41,89.25 U136.W16
N28084431: length 1.1
  TOP w0.147: U136.V17 v1(71.7,89.65)
  BOTTOM w0.132: R527.1 72.2,89.65 v1(71.7,89.65)
N28084433: length 1.1
  TOP w0.147: U136.W18 v1(72.5,90.46)
  BOTTOM w0.147: R528.1 72.51,90.46 v1(72.5,90.46)
N28084995: length 1.5
  TOP w0.147: R5687.1 103.3,47.07 103.48,46.89 v1(103.48,46.56)
  BOTTOM w0.147: v1(103.48,46.56) 103.48,46.63 103.47,46.65 U120.3
N28086994: length 1.2
  TOP w0.147: U68.3 59.33,49.87 59.18,49.72 R5688.1
N28088261: length 9.5
  TOP w0.108: U136.A14 57.54,87.65 57.09,88.11 55.78,88.11 v1(55.32,87.66)
  BOTTOM w0.108: v1(55.32,87.66) 55.51,87.85 55.51,88 55.28,88.24 54.66,88.24 51.42,91.48 51.08,91.48 R5694.2
N28088302: length 10.1
  TOP w0.108: v1(56.08,87.66) 57.1,87.66 57.5,87.25 57.86,87.25 58.26,86.85 U136.B13
  BOTTOM w0.108: v1(56.08,87.66) 55.91,87.66 55.8,87.76 55.8,88.12 55.4,88.53 54.78,88.53 51.54,91.77 51.12,91.77 50.76,92.13 R5695.2
N28088339: length 20.5
  TOP w0.132: v1(56.11,86.94) 56.13,86.94 56.63,86.45 58.1,86.45 U136.B12
  BOTTOM w0.132: v1(56.11,86.94) 56.11,86.96 55.98,87.1 55.09,87.1 54.89,87.3
  BOTTOM w0.147: R5696.2 43.92,93.68 47.12,90.47 51.71,90.47 54.89,87.3
N28088462: length 4
  TOP w0.147: U2348.1 R5697.2 48.64,111.05 49.1,110.59 R5699.1
N28118724: length 4.3
  TOP w0.147: U48.33 33.53,96.59 33.45,96.67 v1(33.45,97.03)
  BOTTOM w0.147: R5730.2 31.57,97.21 31.75,97.03 v1(33.45,97.03)
N28118727: length 5.4
  TOP w0.147: v1(31.29,96.49) 31.8,96.49 31.95,96.34 33.03,96.34 33.13,96.23 U48.34
  BOTTOM w0.147: R5731.2 29.91,96.33 30.15,96.09 30.89,96.09 v1(31.29,96.49)
N28118756: length 15.9
  TOP w0.147: U136.L1 65.81,77.14 65.81,75.51 66.19,75.13 66.19,67.61 66.04,67.46 66.04,64.72 66.65,64.11 66.65,63.02 66.46,62.83 R5732.1
N28122339: length 5.1
  TOP w0.147: R542.2 54.08,87.11 55.88,85.32 57.63,85.32 U136.A11
N28129103: length 14.9
  TOP w0.147: v1(15.88,53.9) 16.48,53.9 17.25,53.14 17.25,52.04 16.71,51.5 U2356.9 ; v1(15.85,49.33) 15.85,47.94 15.7,47.79 R5736.1 14.6,47.79 14.45,47.94 14.45,50.29 14.66,50.5 U2356.4
  L03_SIG1 w0.091: v1(15.85,49.33) 15.88,49.35 v1(15.88,53.9)
N28133286: length 2.2
  TOP w0.147: R5743.1 80.47,98.05 80.31,98.21 U2357.2
N28133288: length 2.2
  TOP w0.147: U2357.3 81.58,98.07 81.45,97.93 R5743.2
N28157125: length 1.8
  TOP w0.147: R3933.2 LD13.2
N28224119: length 4
  TOP w0.147: U56.36 27.82,59.18 27.64,59.36 25.81,59.36 25.49,59.67 R297.2
N28224122: length 2.6
  TOP w0.147: R307.2 27.96,59.82 28.32,59.46 U56.35
N28224348: length 8.8
  TOP w0.132: 56.89,82.45 58.1,82.45 U136.B7
  TOP w0.147: R5751.1 51.35,84.8 53.15,82.99 53.58,82.99 54.12,82.45 56.89,82.45
N28238385: length 2
  TOP w0.147: R166.2 85.45,64.13 85.19,64.38 U3077.8
N28248996: length 1.8
  TOP w0.147: R5637.2 27.39,163.71 26.98,164.13 TP593.1
N28268314: length 7.3
  TOP w0.147: U136.C16 v1(58.9,89.65)
  BOTTOM w0.132: 58.83,92.99 59.29,92.52 59.29,90.05 v1(58.9,89.65)
  BOTTOM w0.147: 58.83,92.99 58.83,94.54 58.23,95.13 R5757.1
N28271262: length 2.3
  TOP w0.147: R115.2 R116.2 U26.1
N28389021: length 8.9
  TOP w0.147: U3076.3 R5766.1 11.54,63.78 11.85,64.08 12.57,64.08 13.41,63.25 13.41,62.51 13.21,62.31 13.21,61.16 12.27,60.23 U54.4
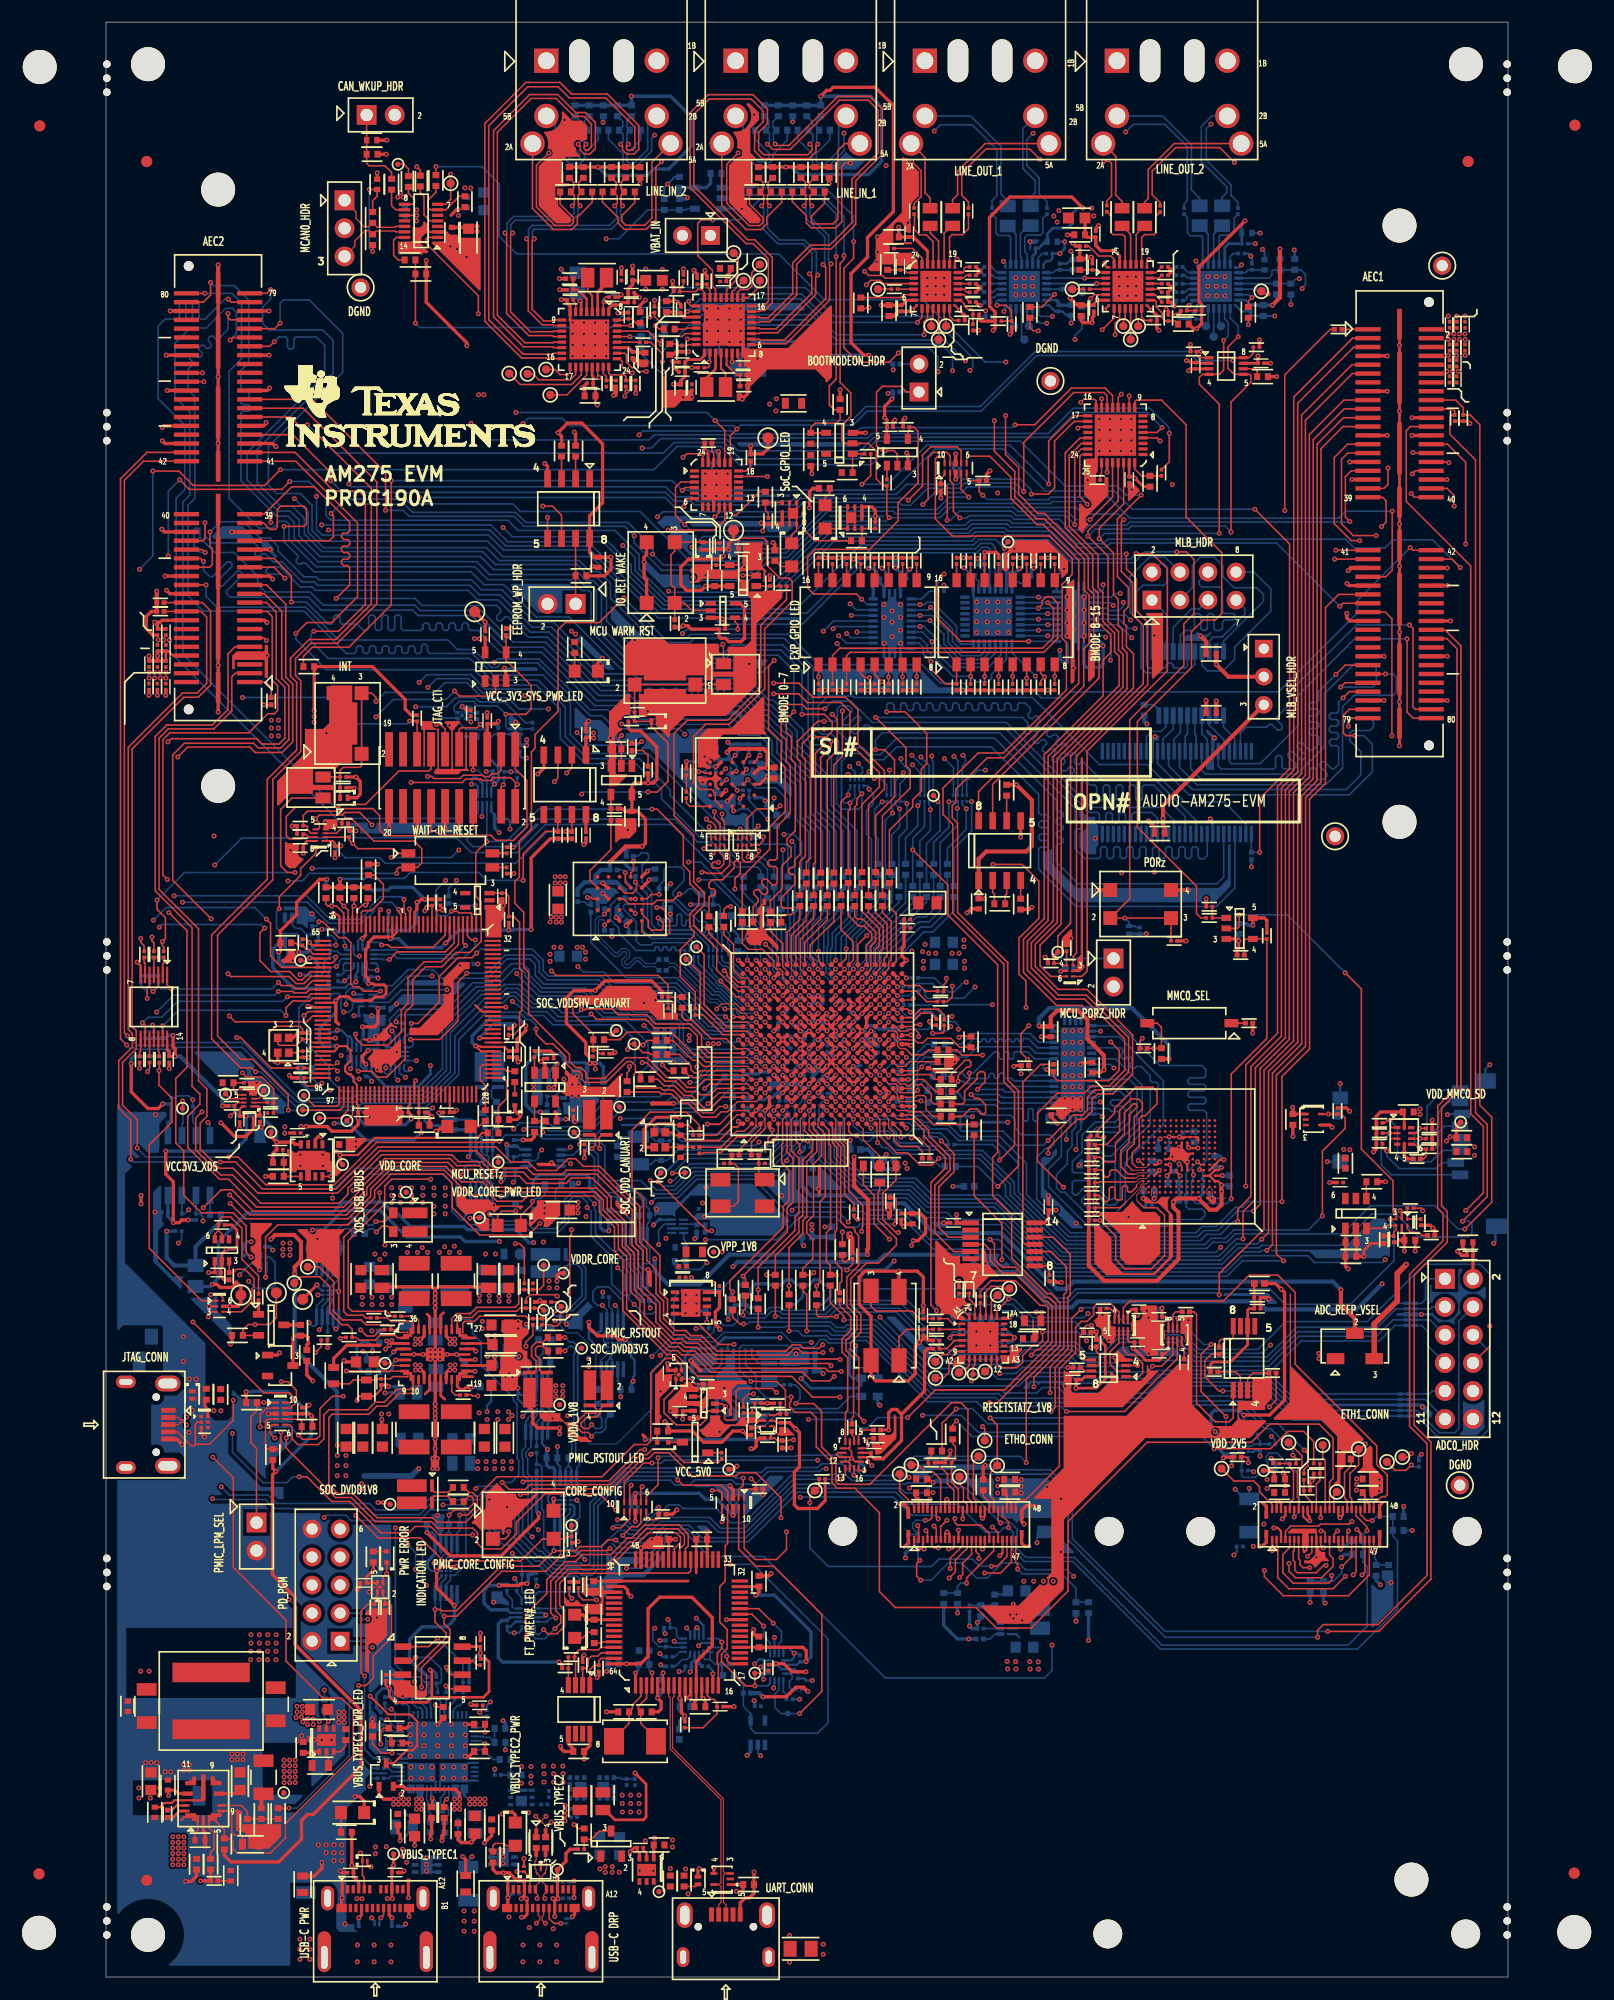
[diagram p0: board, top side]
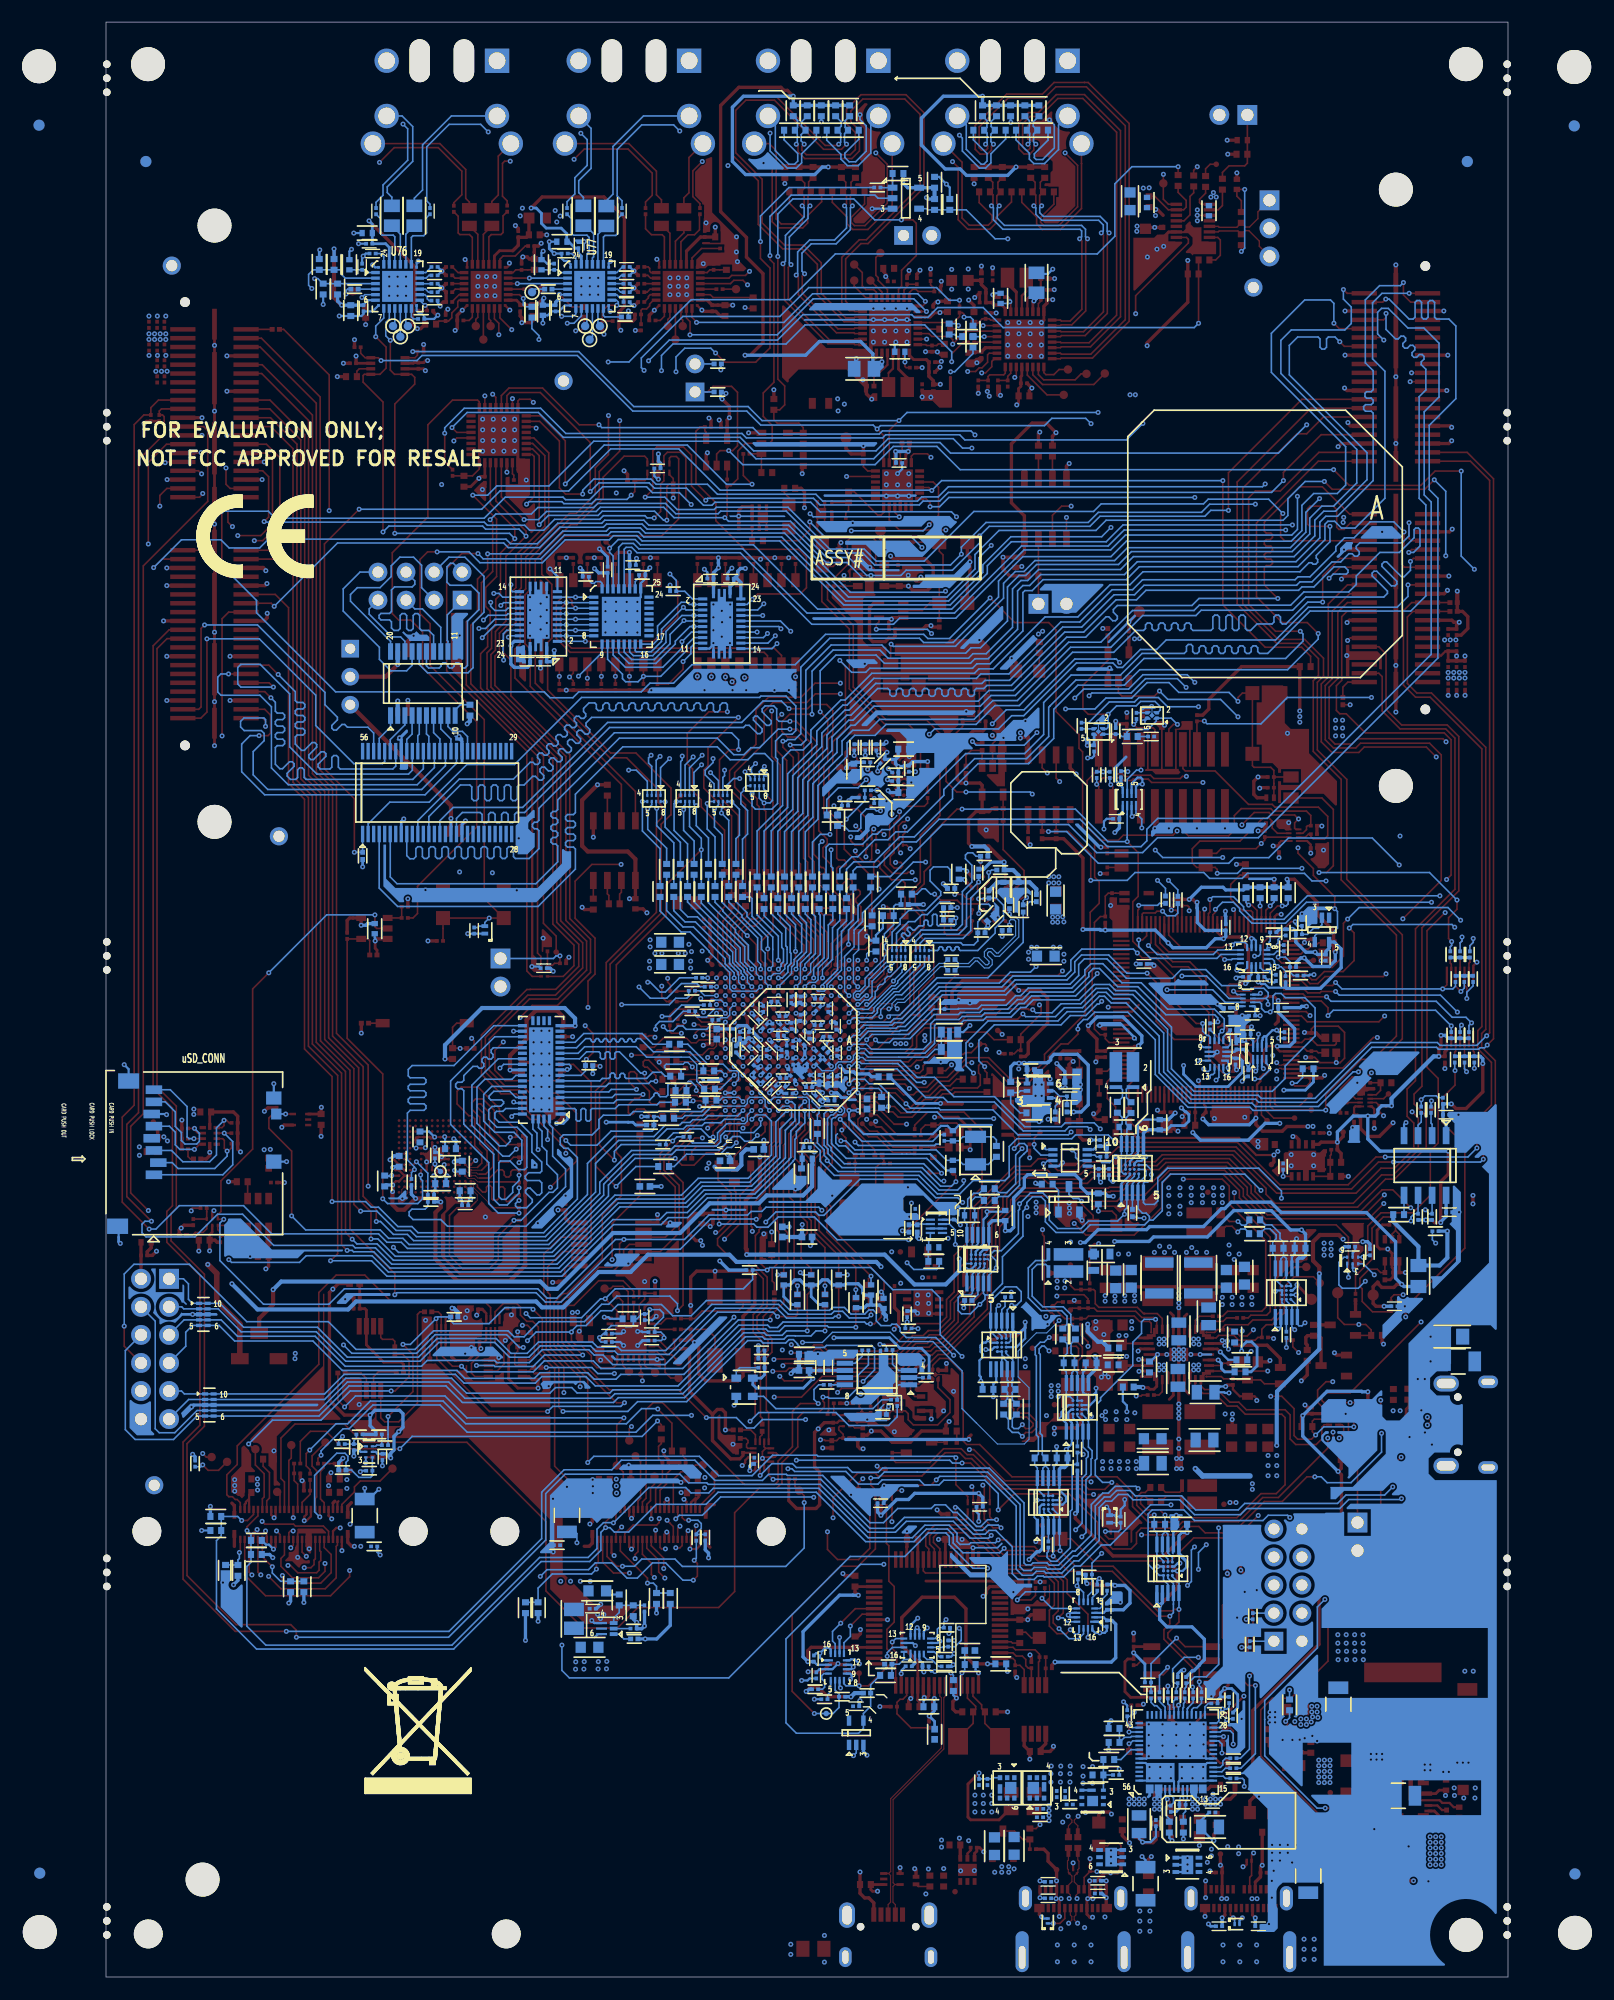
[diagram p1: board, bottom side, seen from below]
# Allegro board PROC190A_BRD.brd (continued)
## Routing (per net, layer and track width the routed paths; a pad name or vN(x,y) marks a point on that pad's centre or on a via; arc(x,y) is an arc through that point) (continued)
N28496978: length 2.4
  TOP w0.147: J12.1 R5775.2
N28497016: length 3.1
  TOP w0.147: J13.1 14.51,117.24 14.96,116.79 R5776.2
N28895418: length 3.5
  TOP w0.147: U3084.2 102.76,54.36 102.34,54.79 R5790.2
N28895646: length 3.2
  TOP w0.147: U3084.3 103.41,54.2 103.9,54.69 R5791.1
N28895649: length 2.9
  TOP w0.147: R5792.1 100.84,57.55 101.02,57.73 101.95,57.73 102.11,57.89 U3084.8
N28896188: length 1.7
  TOP w0.147: R5789.1 97.66,56.96 97.44,57.19 U3083.4
N28896306: length 2.2
  TOP w0.147: U3083.7 96.64,59.96 96.9,60.22 R5793.2
N28962728: length 4.1
  TOP w0.147: U3087.2 52.94,54.15 53.39,53.7 R5806.1 54.13,52.96 53.73,52.56 U3086.4
N29136309: length 2.2
  TOP w0.147: U2353.5 68.17,49.1 68.61,49.53 R5808.1
N29136335: length 2.1
  TOP w0.147: U2353.4 68.87,47.86 68.97,47.97 68.97,48.25 68.85,48.37 68.85,48.58 69.04,48.77 R5733.1
N29218455: length 1
  TOP w0.147: R5734.1 67.56,49.1 67.77,48.89 U2353.6
N29295413: length 6.3
  TOP w0.147: U28.C2 v1(58.14,108.41)
  BOTTOM w0.147: R5826.1 61.71,106.61 60.66,107.67 58.88,107.67 v1(58.14,108.41)
N29295438: length 6.1
  TOP w0.147: U28.A3 56.73,105.71 v1(56.85,105.59)
  BOTTOM w0.147: R5827.1 60.16,104.23 59.7,103.76 58.89,103.76 58.63,104.03 58.63,105.26 58.13,105.75 57.39,105.75 57.23,105.59 v1(56.85,105.59)
N29438875: length 4.1
  BOTTOM w0.147: C615.2 R634.2 R632.1 80.51,33.01 81.01,32.5 U127.3
N29438936: length 1.7
  BOTTOM w0.147: U127.1 80.53,31.05 80.09,30.61 R5777.2
N29440900: length 21.6
  TOP w0.147: v1(85.22,82.17) 85.22,82.15 85.4,81.97 R5758.2 85.83,81.53 86.21,81.16 90.83,81.16 91.77,82.09 91.77,83.9 v1(91.01,84.66) ; R5846.2 v1(94.92,84.07) 94.95,84.1 R5759.1 95.61,85.99 95.23,86.36 SW9.2
  L03_SIG1 w0.091: v1(91.01,84.66) 91.59,84.07 v1(94.92,84.07)
  BOTTOM w0.147: U57.9 85.25,82.13 v1(85.22,82.17) 85.01,82.17 84.9,82.28 84.9,82.49 85.05,82.63 U57.10
N29522203: length 2.1
  TOP w0.147: v1(97.21,73.61) 97.46,73.36 97.46,73.24 U49.H5
  BOTTOM w0.147: R562.1 v1(97.21,73.61) 97.21,73.43 TP116.1
N29598897: length 2
  BOTTOM w0.147: R5842.2 R5837.2 53.45,68.17 U3091.2
N29649563: length 8.9
  TOP w0.132: U136.G18 62.1,91.26 62.1,93.04
  TOP w0.147: R5672.1 63.44,95.67 62.1,94.33 62.1,93.04
N29649575: length 12.2
  TOP w0.147: U136.H16 v1(62.9,89.65)
  BOTTOM w0.132: v1(62.9,89.65) 62.5,89.26 61.93,89.26 61.7,89.5 61.7,89.84 60.38,91.16 60.38,93.7
  BOTTOM w0.147: 60.38,93.7 60.38,94.67 59.32,95.72 R5673.1
N29649587: length 9.1
  TOP w0.132: U136.H18 62.9,91.25 62.9,93.04
  TOP w0.147: R5674.1 64.74,95.78 62.9,93.94 62.9,93.04
N29649599: length 9.2
  TOP w0.147: U136.H17 v1(62.9,90.45)
  BOTTOM w0.147: v1(62.9,90.45) 62.9,91.33 61.95,92.28 61.95,96.11 61.77,96.29 R5675.1
N29649611: length 6
  TOP w0.147: R5676.1 64.09,95.82 62.5,94.22 U136.G19
N29649623: length 8.3
  TOP w0.147: U136.E19 60.9,92.34 v1(59.74,93.5)
  BOTTOM w0.147: v1(59.74,93.5) 59.74,94.79 58.88,95.66 58.88,97.03 57.73,98.17 R5677.2
N29649892: length 6.9
  TOP w0.147: U136.V1 72.01,76.54 v1(72.01,76.05)
  BOTTOM w0.147: v1(72.01,76.05) 72.36,76.05 73.1,76.78 74.12,76.78 74.47,76.43 75.59,76.43 76.28,75.74 R538.1
N29650058: length 5.9
  TOP w0.147: R178.2 66.58,94.84 67.7,93.72 67.7,92.06 U136.N19
N29729537: length 1.3
  TOP w0.147: SW9.1 R3736.1
N271759124: length 3
  TOP w0.147: U15.5 76.98,57.14 76.19,56.34 75.77,56.34 TP32.1
N271759125: length 4.1
  TOP w0.147: TP33.1 75.84,54.23 76.36,54.75 76.36,55.88 77.11,56.64 U15.6
N275664200: length 1.3
  TOP w0.147: Q3.1 R286.2
N284070661: length 1.2
  TOP w0.147: LD14.2 R195.2

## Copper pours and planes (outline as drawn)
AVDD_3V3_DAC on TOP: 88.35,157.29 88.35,158.41 88.21,158.56 88.21,160.35 88.28,160.43 89.56,160.43 89.78,160.21 89.78,159.11 89.73,159.05 89.56,159.05 89.29,158.78 89.29,157.92 89.42,157.79 90.28,157.79 90.49,157.57 90.49,156.13 90.33,155.96 89.71,155.96 89.25,156.43 89.25,157 88.97,157.28 88.36,157.28
AVDD_3V3_DAC on L03_SIG1: 87.55,162.56 71.86,162.56 70.92,161.62 70.92,157.56 72.16,157.56 72.16,160.81 72.59,161.24 86.49,161.24 88.7,159.03 90.09,159.03 90.73,159.66 97.28,159.66 98.37,158.57 103.96,158.57 103.96,159.51 103.15,160.32 99.19,160.32 98.25,161.26 88.85,161.26
DGND on TOP (solid shape): 76.57,151.67 73.77,151.67 73.77,154.47 76.57,154.47
DGND on TOP (solid shape): 93.97,151.67 91.16,151.67 91.16,154.47 93.97,154.47
DGND on TOP (solid shape): 26.85,77.29 26.65,77.09 23.52,77.09 23.39,77.22 23.39,78.96 26.85,78.96
DGND on TOP (solid shape): 80.84,58.51 80.71,58.37 80.71,57.41 80.84,57.28 80.84,56.49 78.06,56.49 78.06,59.28 80.84,59.28
DGND on TOP (solid shape): 67.46,67.31 67.8,66.98 67.8,65.39 67.22,65.39 67.22,66.83 67.08,66.83 67.08,67.42 67.08,67.49 67.46,67.49
DGND on TOP (solid shape): 23.54,75.97 23.63,75.91 23.61,75.8 22.64,74.83 21.72,74.83 21.72,75.97
DGND on TOP (solid shape): 89.57,120.08 89.57,117.77 89.12,117.32 89.01,117.3 88.95,117.39 88.95,120.09 89.26,120.39
DGND on TOP (solid shape): 35.55,97.75 36.06,97.75 36.1,97.7 36.1,96.02 36.11,95.97 36.11,95.93 36.11,95.91 35.84,95.63 35.84,94.11 34.36,94.11 34.36,97.07 35.42,97.07 35.42,97.75 35.55,97.75
DGND on TOP (solid shape): 50.48,39.11 50.53,39.11 50.53,38.75 48.61,38.75 48.61,36.95 48.32,36.95 48.32,38.75 48.3,38.75 48.25,38.78 48.26,38.84 49.27,39.84 50.48,39.84
DGND on TOP (solid shape): 48.05,146.61 48.21,146.61 48.36,146.46 49,146.46 49,145.8 48.98,145.76 48.95,145.75 48.9,145.74 48.39,145.74 48.06,146.07 47.81,146.07 47.52,146.36 47.52,146.66 48,146.66
DGND on TOP (solid shape): 56.69,133.72 55.19,133.72 55.19,133.24 55.18,133.17 55.17,133.11 55.17,132.77 55.08,132.68 54.97,132.66 54.91,132.75 54.91,133.72 53.91,133.72 53.91,136.5 56.69,136.5
DGND on TOP (solid shape): 95.76,118.42 94.91,117.57 94.8,117.55 94.74,117.64 94.74,122.84 94.24,123.33 94.22,123.44 94.32,123.51 95.76,123.51
DGND on TOP (solid shape): 87.56,126.5 87.67,126.52 87.73,126.43 87.73,117.3 87.55,117.11 87.44,117.09 87.37,117.19 87.37,120.98 86.99,121.37 86.99,125.93
DGND on TOP (solid shape): 20.98,104.18 20.73,103.93 19.86,103.93 19.82,103.93 19.77,103.92 19.72,103.93 19.71,103.98 19.71,104.01 19.71,104.65 19.71,104.65 19.68,104.77 19.78,104.83 20.98,104.83
DGND on TOP (solid shape): 50.61,144.93 50.65,144.86 50.65,143.69 53.18,143.69 53.18,142.7 52.12,142.7 51.51,142.09 50.42,142.09 50.37,142.14 50.37,144.86 50.4,144.93 50.48,144.96 50.53,144.96
DGND on TOP (solid shape): 83.91,59.51 83.94,59.55 83.99,59.54 84.05,59.49 84.05,58.55 84.36,58.55 84.43,58.51 84.46,58.43 84.45,58.39 84.46,58.35 84.46,57.76 84.25,57.55 83.91,57.55
DGND on TOP (solid shape): 82.59,56.91 82.9,56.91 83,56.85 82.97,56.74 82.65,56.42 82.65,55.83 82.37,55.55 81.19,55.55 81.08,55.66 81.08,55.99 81.07,56.08 81.03,56.16 81.03,56.17 81.03,56.31 81.86,56.31 81.86,57.21 82.29,57.21
DGND on TOP (solid shape): 46.17,104.85 46.22,104.94 46.33,104.93 47.88,104.93 48.06,104.75 48.06,103.73 47.4,103.07 46.61,103.07 46.29,102.75 46.18,102.73 46.11,102.82 46.11,104.3 46.17,104.3
DGND on TOP (solid shape): 87.36,94.85 87.47,94.87 87.53,94.78 87.53,92.87 87.48,92.81 87.42,92.8 87.39,92.85 87.39,92.91 87.38,92.95 87.38,93.25 86.6,93.25 86.6,94.09
DGND on TOP (solid shape): 88.52,78.64 88.31,78.43 87.5,78.43 86.66,77.6 86.59,77.57 86.52,77.6 86.51,77.62 86.08,78.04 86.07,78.11 86.07,78.5 85.45,78.5 85.36,78.56 85.38,78.67 86.36,79.65 88.52,79.65
DGND on TOP (solid shape): 61.12,49.73 61.74,49.73 62.36,49.11 62.36,49.07 62.34,49.04 62.3,49.02 62.24,49.02 61.77,49.02 61.75,48.99 60.91,48.99 60.76,49.14 60.89,49.27 60.97,49.4 61,49.54 61,49.63 61.03,49.7 61.11,49.73
DGND on TOP (solid shape): 77.38,83.09 76.22,81.93 76.22,81.8 75.13,81.8 75.11,81.79 74.82,82.08 74.31,82.08 74.22,82.13 74.22,82.23 74.25,82.31 74.26,82.4 74.29,82.47 74.36,82.5 74.75,82.5 74.75,82.25 75.92,82.25 75.92,83.42 76.8,83.42 76.8,83.56 76.91,83.56
DGND on TOP (solid shape): 14.53,120.62 14.57,120.63 14.65,120.6 14.68,120.53 14.68,117.62 14.37,117.62 14.37,119.25 11.67,119.25 11.67,118.42 11.54,118.42 11.51,118.39 11.46,118.38 11.43,118.43 11.43,119.63 11.83,120.04 14.37,120.04 14.37,120.53 14.4,120.6 14.48,120.63
DGND on TOP (solid shape): 77.87,56.17 77.86,56.16 77.83,56.08 77.82,55.99 77.82,55.53 77.78,55.49 77.49,55.49 77.31,55.3 77.28,55.3 77.08,55.27 76.9,55.18 76.79,55.16 76.74,55.26 76.74,55.72 77.27,56.26 77.55,56.26 77.64,56.27 77.72,56.3 77.73,56.31 77.87,56.31
DGND on TOP (solid shape): 41.17,50.65 41.58,50.24 42.11,50.24 42.12,50.25 42.23,50.27 42.29,50.18 42.29,49.61 42.98,48.92 43.53,48.92 43.63,48.82 43.64,48.81 43.78,48.63 44,48.56 44.02,48.57 44.07,48.51 43.99,48.44 42.93,48.44 42.49,48.87 41.81,48.87 41.81,49.86 41.38,50.29 39.7,50.29 39.27,50.72 39.27,51.05 41.17,51.05
DGND on TOP (solid shape): 12.38,14.88 12.39,14.82 12.34,14.79 12.28,14.79 12.28,13.82 13.32,13.82 13.32,13.93 13.55,13.93 13.55,13.82 14.59,13.82 14.59,13.93 15.07,13.93 15.07,13.82 15.88,13.82 15.88,12.73 14.75,11.61 12.89,11.61 12.89,12.71 12.74,12.71 12.74,12.84 12.38,13.21 11.84,13.21 11.76,13.29 11.76,14.91 11.69,14.98 11.67,15.09 11.77,15.15 12.1,15.15
DGND on TOP (solid shape): 22.31,115.41 22.77,115.41 22.77,111.58 22.31,111.58 22.31,109.9 21.33,109.9 20.83,109.4 20.83,109.03 20.56,109.03 20.56,109.36 18.76,109.36 18.76,107.94 20.56,107.94 20.56,108.27 20.83,108.27 20.83,108.05 20.83,108.05 20.83,106.3 20.56,106.3 20.56,107.46 18.76,107.46 18.76,107.13 16.7,107.13 15.66,106.09 15.55,106.07 15.49,106.16 15.49,108.28 18.02,110.81 18.02,113 19.68,113 20.22,113.54 20.22,116.76 20.4,116.94 22.31,116.94
DGND on TOP (solid shape): 91.6,56.73 91.71,56.75 91.78,56.66 91.78,56.63 92.45,55.96 92.96,55.96 93,55.92 93.02,55.81 92.93,55.75 92.38,55.75 92.31,55.74 92.25,55.72 91.75,55.72 91.75,55.46 91.69,55.36 91.58,55.39 91.34,55.63 91.34,56.46
DGND on TOP (solid shape): 114.48,48.12 114.57,48.09 114.73,47.93 114.73,46.25 115.67,45.31 115.67,43.86 115.39,43.86 115.13,43.61 114.96,43.61 114.68,43.33 114.44,43.57 114.44,43.83 114.4,43.87 114.4,45.71 113.6,45.71 113.5,45.77 113.53,45.88 113.85,46.2 113.85,47.35 113.97,47.49 114.04,47.68 114.04,47.69 114.31,47.96 114.37,48.01 114.41,48.07
DGND on TOP (solid shape): 50.33,55.12 50.44,55.14 50.5,55.04 50.5,54.55 51.27,54.55 51.27,54.25 51.26,54.2 51.26,54.15 51.26,53.53 50.17,52.44 50.17,50.95 50.33,50.78 50.36,50.71 50.33,50.64 50.18,50.39 50.21,50.1 50.21,50 50.12,49.95 49.73,49.95 49.73,54.51
DGND on TOP (solid shape): 88.32,110.42 88.43,110.44 88.5,110.35 88.5,91.24 88.23,90.97 87.59,90.97 87.53,90.97 87.45,90.99 87.42,91.07 87.42,91.12 87.45,91.2 87.54,91.22 87.7,91.22 87.84,91.29 87.97,91.29 87.97,91.46 87.99,91.53 87.99,91.59 87.99,92.26 88.29,92.55 88.29,110.38
DGND on TOP (solid shape): 71.6,50.76 71.6,48.75 70.22,47.37 69.74,47.37 69.72,47.39 69.72,47.46 69.71,47.56 69.68,47.66 69.67,47.67 69.67,47.83 69.52,47.83 69.45,47.86 69.39,47.88 69.35,47.89 69.35,48.25 69.35,48.35 69.98,48.35 69.98,49.11 70.08,49.11 70.13,49.1 70.18,49.1 70.74,49.1 70.75,49.1 71.16,49.16 71.35,49.53 71.35,50.89 71.39,50.93 71.44,50.93
DGND on TOP (solid shape): 17.2,93.06 17.17,93.02 17.1,92.73 17.29,92.41 17.27,92.34 17.17,92.14 17.19,91.92 17.17,91.83 17.09,91.79 16.09,91.79 15.87,92 15.85,92.11 15.94,92.18 16.05,92.18 16.46,92.58 16.46,93.12 17.14,93.12
DGND on TOP (solid shape): 14.2,80.87 14.22,80.78 14.16,80.7 13.95,80.58 13.84,80.37 13.84,80.35 13.72,80.23 13.72,79.96 13.66,79.9 13.39,79.9 13.27,79.88 13.15,79.82 12.95,79.82 12.95,80.17 12.73,80.17 12.62,80.23 12.49,80.25 12.1,80.25 11.97,80.38 12,80.44 12.03,80.44 12.03,80.59 12.43,80.59 12.5,80.58 12.58,80.59 12.87,80.59 12.87,81.1 13.97,81.1
DGND on TOP (solid shape): 16.2,102.68 16.27,102.77 16.38,102.75 16.47,102.66 17.46,102.66 17.46,102.43 17.46,102.42 17.42,102.33 17.41,102.22 17.41,101.75 17.53,101.45 17.81,101.3 17.89,101.23 17.86,101.13 17.25,100.51 17.25,100.48 17.22,100.41 17.14,100.38 17.08,100.38 16.59,100.38 16.2,100.77
DGND on TOP (solid shape): 92.94,70.22 92.99,70.23 93.02,70.19 93.02,70.17 93.17,70.02 93.21,69.94 93.26,69.89 93.87,69.27 95.04,69.27 95.51,68.8 95.51,65.46 94.53,64.49 92.46,64.49 91.84,65.1 91.84,67.24 90.34,68.74 90.19,68.86 90,68.89 89.95,68.89 89.91,68.91 89.91,68.96 89.96,69.08 89.96,69.27 92.03,69.27 92.65,69.89 92.69,69.94 92.73,70.02
DGND on TOP (solid shape): 41.55,82.05 41.62,82.14 41.73,82.12 42.24,81.61 42.72,81.61 42.75,81.58 42.75,81.1 43.23,80.62 45.47,80.62 46.65,81.8 46.76,81.82 46.82,81.73 46.82,81.59 46.68,81.59 46.68,79.65 44.65,79.65 44.65,79.76 41.66,79.76 41.27,80.14 41.55,80.42 41.55,80.93 41.59,80.94 41.86,81.31 41.59,81.67 41.55,81.68
DGND on TOP (solid shape): 59.79,97.63 59.81,97.59 59.81,97.06 59.56,97.06 59.56,94.91 59.6,94.91 59.6,94.87 59.81,94.87 59.81,94.52 60.92,93.41 60.92,93.04 60.93,92.95 60.88,92.9 60.01,93.77 59.6,93.85 59.36,93.51 59.33,93.44 59.26,93.41 58.36,93.41 58.01,93.75 58.01,94.89 59.2,94.89 59.2,96.14 58.99,96.14 58.99,96.74 59.46,97.2 59.46,97.64
DGND on TOP (solid shape): 17.04,74.65 18.87,74.65 18.87,74.68 20.19,74.68 20.32,74.55 20.32,73.86 20.75,73.86 20.75,73.59 21.11,73.24 21.2,73.16 21.31,73.12 21.39,73.05 21.36,72.95 20.92,72.51 20.82,72.48 20.75,72.56 20.6,72.8 20.33,72.87 20.33,72.87 19.99,72.87 19.99,73.07 18.58,73.07 18.58,72.11 18.04,72.11 18.04,73.07 17.28,73.07 17.28,72.87 16.58,72.87 16.58,73.01 16.48,73.01 16.48,73.24 16.58,73.24 16.58,74.28 16.48,74.28 16.48,74.53 16.4,74.61 16.4,74.96 16.74,74.96
DGND on TOP (solid shape): 41.15,68.91 41.07,68.91 40.06,67.89 39.72,67.89 39.63,67.94 39.63,68.04 39.5,68.54 39,68.46 39,68.46 38.5,67.96 38.39,67.94 38.32,68.04 38.32,68.85 38.26,68.85 38.16,68.91 38.19,69.02 39.01,69.85 39.01,70.19 39.01,70.23 39.04,70.31 39.12,70.34 41.15,70.34
DGND on TOP (solid shape): 90.25,60.16 90.54,60.16 90.59,60.15 90.63,60.15 90.8,60.15 90.98,59.97 90.98,59.53 91,59.41 91.05,59.31 91.05,58.91 91.45,58.91 91.45,58.66 91.4,58.55 91.38,58.43 91.38,57.57 91.04,57.24 90.99,57.23 90.96,57.27 90.96,57.33 90.17,58.12 90.17,58.42 90.04,58.74 89.71,58.88 89.66,58.88 89.66,58.94 89.64,59.14 89.52,59.3 89.48,59.38 89.51,59.45 89.84,59.78 89.84,60.5 89.93,60.59 90.25,60.59
DGND on TOP (solid shape): 55.65,50.41 56.02,50.04 57.03,50.04 57.45,50.47 57.45,50.69 58.1,50.69 58.1,50.69 58.22,50.69 58.22,50.69 58.78,50.69 58.98,50.49 59.64,50.49 59.69,50.49 59.78,50.47 59.81,50.39 59.81,50.34 59.77,50.26 59.69,50.24 59.65,50.24 59.61,50.25 59.17,50.25 59.02,50.09 58.86,50.09 58.86,50.15 58.03,50.15 58.03,49.93 57.98,49.84 57.88,49.84 57.78,49.87 57.68,49.89 56.61,49.89 55.59,48.87 54.33,48.87 53.77,49.44 53.75,49.55 53.84,49.61 54.02,49.61 54.71,50.29 54.71,50.85 54.71,50.85 55.65,50.85
DGND on TOP (solid shape): 55.31,151.35 55.96,151.35 56.06,151.45 57.87,151.45 57.87,147.44 58.33,147.44 58.4,147.42 58.46,147.42 59.32,147.42 59.39,147.49 61.76,147.49 65.59,151.33 65.7,151.35 65.76,151.25 65.76,144.84 65.33,144.4 65.22,144.38 65.16,144.47 65.16,144.65 64.26,145.54 59.92,145.54 58.34,143.97 58.34,143.51 58.16,143.32 58.05,143.3 57.99,143.4 57.99,145.88 57.81,145.88 57.81,146.32 57.81,146.32 57.81,146.52 57.59,146.74 57.59,147.05 57.59,147.11 57.57,147.18 57.57,147.64 56.27,147.64 56.27,147.7 55.2,147.7 55.2,147.64 54.06,147.64 54.06,149.83 54.2,149.83 54.2,150.77 54.06,150.77 54.06,151.45 55.31,151.45
DGND on TOP (solid shape): 28.96,27.46 28.99,27.51 29.04,27.5 29.08,27.46 29.08,25.5 28.88,25.3 26.39,25.3 26.1,25.59 26.1,26.12 26.06,26.28 25.97,26.42 25.78,26.62 25.78,26.81 25.77,26.87 25.76,26.93 25.76,26.99 25.89,26.99 25.89,26.86 27.59,26.86 27.59,26.76 27.74,26.41 28.13,26.38 28.14,26.38 28.2,26.38 28.2,26.3 28.58,25.87 28.96,26.3 28.96,26.3
DGND on TOP (solid shape): 18.22,67.72 18.29,67.69 18.32,67.62 18.7,67.26 19.08,67.62 19.12,67.69 19.19,67.72 21.5,67.72 21.59,67.66 21.57,67.55 21.16,67.14 21.16,60.4 21.13,60.35 21.07,60.37 21,60.44 21,63.12 19.46,64.67 18.72,64.67 18.51,64.82 18.26,64.87 18.19,64.9 18.16,64.98 18.16,66.77 17.38,67.55 17.36,67.66 17.45,67.72
DGND on TOP (solid shape): 29.51,113.72 29.59,113.67 29.6,113.57 29.64,113.19 29.99,113.03 30.14,113.03 30.2,112.98 30.17,112.91 30.16,112.91 30.16,109.38 31.28,109.38 31.28,112.91 31.1,112.91 31.1,113.15 30.7,113.54 30.68,113.65 30.78,113.72 32,113.72 32.06,113.66 32.09,113.56 32.01,113.49 31.61,113.09 31.61,112.91 31.43,112.91 31.43,109.38 32.55,109.38 32.55,112.73 32.7,112.73 32.7,109.38 32.77,109.38 32.84,109.35 32.87,109.28 32.87,109.19 32.23,109.19 31.92,108.89 29.85,108.89 29.65,109.08 29.83,109.25 29.83,109.38 30.01,109.38 30.01,112.91 28.89,112.91 28.89,109.57 28.74,109.57 28.74,112.91 28.56,112.91 28.56,113.72
DGND on TOP (solid shape): 14.97,68.28 15.06,68.21 15.04,68.1 14.07,67.14 14.07,64 14.01,63.9 13.9,63.93 13.19,64.63 13.17,64.73 13.24,64.8 13.51,65.09 13.38,65.47 13.08,65.77 13.08,66.09 13.11,66.16 13.18,66.19 13.54,66.57 13.18,66.95 13.11,66.99 13.08,67.06 13.08,68.15 13.04,68.19 13.03,68.24 13.08,68.28
DGND on TOP (solid shape): 26.55,84.84 26.66,84.86 26.72,84.77 26.72,83.29 25.87,82.43 25.78,82.41 25.7,82.47 25.13,82.63 25.09,82.04 25.12,81.93 25.03,81.86 24.74,81.86 24.21,82.4 24.08,82.4 23.99,82.43 23.98,82.52 23.98,82.76 23.86,82.96 23.69,83.14 23.69,83.19 24.05,83.55 24.15,83.71 24.18,83.89 24.21,83.97 24.28,84 25.71,84
DGND on TOP (solid shape): 49.91,89.05 49.91,88.72 49.92,88.6 49.97,88.48 49.98,88.47 49.98,88.35 50.09,88.35 50.1,88.34 50.26,88.28 50.43,88.27 50.51,88.24 50.54,88.17 50.54,87.7 50.55,87.66 50.55,87.62 50.55,87.32 51.29,87.32 51.29,87.62 51.3,87.66 51.3,87.7 51.3,88.34 51.67,88.34 51.67,87.26 51.81,87.26 51.81,86.66 49.98,86.66 49.14,87.5 46.56,87.5 46.03,88.03 43.32,88.03 43.25,87.96 43.02,87.96 42.95,87.95 42.87,87.96 42.82,88.04 42.62,88.35 42.24,88.34 42.19,88.34 42.16,88.38 42.16,88.46 42.58,88.87 44.32,88.87 44.5,88.9 44.65,89 45.38,89.74 49.22,89.74
DGND on TOP (solid shape): 96.27,70.66 96.34,70.63 96.39,70.59 96.33,70.52 96.22,70.36 96.18,70.17 96.18,69.49 96.66,69.01 96.66,65.2 94.99,63.54 90.6,63.54 89.52,64.62 89.52,67.55 89.51,67.64 89.48,67.74 89.48,68.03 89.51,68.1 89.58,68.13 89.89,68.13 91.09,66.93 91.09,64.79 92.15,63.73 94.85,63.73 96.26,65.15 96.26,69.12 95.36,70.03 94.19,70.03 93.79,70.42 93.75,70.45 93.71,70.48 93.71,70.53 93.75,70.61 93.84,70.63 94.03,70.62 94.21,70.7 94.25,70.67 94.32,70.64 94.71,70.24 94.96,70.14 95.2,70.24 95.55,70.59 95.55,70.63 95.59,70.64 95.65,70.66 95.71,70.7 95.96,70.62 96.21,70.7
DGND on TOP (solid shape): 107.21,61.83 107.25,61.87 107.3,61.86 107.34,61.82 107.34,55.32 113.91,48.75 113.94,48.67 113.89,48.59 113.83,48.55 113.78,48.5 113.63,48.35 113.61,48.36 113.02,48.16 112.93,47.55 112.93,47.46 112.84,47.41 112.28,47.41 112.28,46.37 112.31,46.32 111.81,45.83 111.81,44.57 111.77,44.49 111.68,44.47 111.51,44.5 111.34,44.48 111.25,44.5 111.21,44.58 111.21,44.66 111.53,44.98 111.53,48.95 110.04,50.44 105.86,50.44 105.77,50.5 105.79,50.62 107.21,52.04
DGND on TOP (solid shape): 32.94,91.34 32.9,91.26 32.81,91.24 32.58,91.25 32.39,91.12 32.39,91.12 31.5,90.23 31.5,86.69 30.07,85.27 27.63,85.27 27.58,85.27 27.51,85.3 27.48,85.37 27.48,85.86 27.52,85.94 27.6,85.96 27.65,85.95 27.7,85.96 28.4,85.96 30.55,88.11 30.55,88.96 30.6,89.05 30.7,89.05 31.27,89.38 30.7,89.72 30.6,89.72 30.55,89.81 30.55,90.42 32.03,91.9 32.94,91.9
DGND on TOP (solid shape): 35.36,44.7 35.45,44.73 35.53,44.66 35.58,44.56 35.65,44.48 36.37,43.77 37.06,43.77 37.13,43.74 37.16,43.67 37.29,43.4 37.58,43.31 37.59,43.31 38.38,43.31 38.89,43.81 39.05,43.81 39.14,43.75 39.12,43.64 36.81,41.33 36.81,40.76 36.76,40.67 36.66,40.67 36.26,40.65 36.1,40.29 36.1,40.14 36.01,40.05 35.88,40.05 35.88,40.51 34.2,40.51 34.2,39.35 34.17,39.31 34.12,39.32 34.03,39.4 34.03,40.38 33.39,41.02 33.22,41.02 33.12,41.08 33.14,41.19 34.39,42.44 34.39,43.73
DGND on TOP (solid shape): 59.47,115.91 59.58,115.93 59.64,115.83 59.64,112.82 59.79,112.67 59.82,112.56 59.72,112.5 55.91,112.5 55.45,112.04 55.45,110.77 55.62,110.6 55.65,110.5 55.58,110.43 55.49,110.38 55.4,110.32 55.13,110.04 55.11,110.04 55.07,110.04 55.05,110.07 54.47,110.2 54.72,109.66 54.75,109.65 54.77,109.61 54.77,109.55 54.78,109.5 54.76,109.41 54.69,109.37 54.38,109.37 54.25,109.51 53.72,109.51 53.7,109.51 53.63,109.54 53.6,109.61 53.6,112.17 54.49,113.06 56.62,113.06
DGND on TOP (solid shape): 28.73,158.85 28.79,158.94 28.9,158.92 29.19,158.63 29.21,158.63 29.21,158.27 29.32,158.16 29.33,158.15 29.41,158.06 30.76,158.06 30.84,157.99 30.84,157.97 30.86,157.97 31.06,157.76 31.78,157.76 32.06,157.48 33.94,157.48 33.94,152.79 33.88,152.7 33.77,152.72 29.54,156.95 29.51,157.06 29.61,157.13 30.04,157.13 30.11,157.13 30.17,157.15 30.77,157.15 30.77,157.86 30.17,157.86 30.11,157.88 30.04,157.88 28.97,157.88 28.58,157.49 28.58,157 28.61,156.85 28.69,156.73 29.16,156.26 29.18,156.15 29.09,156.08 28.78,156.08 28.6,155.9 28.54,155.89 28.51,155.94 28.51,155.99 26.57,155.99 26.51,155.96 26.44,156.04 26.44,157.12 26.44,157.13 27.04,157.13 27.11,157.13 27.17,157.15 27.77,157.15 27.77,158.39 27.8,158.44 27.86,158.43 27.86,158.42 28.47,158.42 28.73,158.67
DGND on TOP (solid shape): 43.51,35.44 43.72,35.23 44.66,35.23 44.82,35.39 45.06,35.39 45.06,34.99 45.77,34.99 45.89,34.94 46.02,34.92 46.72,34.92 46.79,34.85 46.79,34.7 45.06,34.7 45.06,32.78 44.75,32.78 44.75,32.83 43.82,32.83 43.39,33.26 43.26,33.26 43.26,33.55 41.74,33.55 41.48,33.81 41.48,35.49 41.51,35.52 41.56,35.53 41.59,35.48 41.59,35.3 41.59,35.26 41.58,35.21 41.58,34.39 41.59,34.38 41.92,34.05 42.24,33.91 42.54,34.09 42.61,34.14 42.7,34.11 43.05,33.76 44.41,33.76 44.41,33.76 44.83,34.14 44.41,34.52 44.41,34.52 43.36,34.52 43.18,34.7 43.18,35.21 43.18,35.26 43.17,35.3 43.17,35.5 43.26,35.77 43.18,36.03 43.17,36.05 43.17,36.17 43.51,36.17
DGND on TOP (solid shape): 24.88,34.17 24.88,33.37 25.48,33.37 25.48,30.89 24.61,30.03 24.53,30 24.45,30.04 23.86,30.11 23.93,29.52 23.98,29.45 23.95,29.36 23.83,29.24 23.83,27.63 23.77,27.53 23.66,27.55 23.66,27.55 23.48,27.73 23.48,31.92 23.52,32 23.61,32.02 24.09,32.38 23.61,32.75 23.52,32.77 23.48,32.85 23.48,32.97 23.88,33.38 23.96,33.38 23.96,33.37 24.7,33.37 24.7,33.67 24.7,33.71 24.71,33.76 24.71,34.13 24.82,34.24
DGND on TOP (solid shape): 55.25,109.14 55.32,109.11 55.35,109.03 55.42,108.76 55.66,108.62 55.74,108.55 55.71,108.45 55.63,108.36 55.62,108.36 55.35,108.03 55.55,107.65 55.61,107.58 55.58,107.49 55.49,107.41 55.07,107.83 55.08,107.86 54.8,108.37 54.35,108 54.32,107.93 54.24,107.9 53.98,107.9 53.6,108.28 53.6,108.64 53.63,108.71 53.7,108.75 53.94,108.75 54.07,108.61 54.68,108.61 54.69,108.61 54.99,108.72 55.11,109.03 55.13,109.11 55.21,109.14
DGND on TOP (solid shape): 94.41,55.34 94.52,55.03 94.83,54.92 94.84,54.92 95.2,54.92 95.3,54.85 95.27,54.74 92.11,51.58 87.04,51.58 86.95,51.58 86.87,51.56 86.78,51.57 86.74,51.66 86.74,54.91 86.8,54.97 86.98,54.83 87.17,54.8 87.17,54.76 88.14,54.76 88.23,54.68 88.26,54.68 88.3,54.64 88.29,54.59 88.24,54.53 87.98,54.53 87.98,54.54 87.79,54.54 87.62,54.47 87.61,54.46 87.5,54.46 87.5,54.34 87.49,54.33 87.44,54.21 87.42,54.09 87.42,53.44 87.42,53.44 87.54,52.98 88,52.88 88.01,52.88 89.87,52.88 90.96,53.97 90.96,54.69 91.02,54.79 91.13,54.76 91.41,54.49 91.75,54.49 91.75,54.01 92.25,54.01 92.31,54 92.38,53.99 93.74,53.99 94.28,54.52 94.28,55.4 94.41,55.4
DGND on TOP (solid shape): 93.31,137.72 89.83,137.72 89.83,137.23 89.81,137.16 89.8,137.1 89.8,136.26 89.68,136.13 89.68,135.9 89.68,135.9 89.68,135.17 89.97,135.17 90.06,135.16 90.14,135.17 90.44,135.17 90.44,135.82 90.48,135.86 90.51,135.85 90.6,135.82 90.7,135.81 90.77,135.79 90.8,135.71 90.8,134.16 88.89,132.25 88.89,132.25 88.75,131.92 88.94,131.62 88.99,131.55 88.96,131.46 88.57,131.07 88.57,130.82 88.51,130.72 88.4,130.75 88.04,131.1 88.01,131.17 88.04,131.24 88.12,131.38 88.14,131.54 88.14,133.33 88.2,133.43 88.31,133.41 88.6,133.11 88.6,133.11 89.17,133.08 89.14,133.65 89.14,133.65 88.59,134.19 88.59,137.47 88.93,137.47 88.99,137.48 89.06,137.49 89.56,137.49 89.56,141.48 93.31,141.48
DGND on TOP (solid shape): outline of 121 points within 35.59,53.09 38.58,59.46
DGND on TOP (solid shape): 59.15,168.79 59.15,168.12 58.37,167.35 58.37,165.17 58.8,164.74 58.83,164.63 58.73,164.57 58.73,164.57 58.45,164.29 58.45,163.53 58.59,163.38 58.59,162.41 59.06,162.41 59.13,162.34 59.13,162.15 58.78,162.15 58.78,162.1 57.85,162.1 57.85,161.16 58.08,161.16 58.08,160.45 59.31,159.22 59.31,158.96 59.12,158.77 58.33,158.77 56.43,160.68 56.43,164.04 57.17,164.78 57.2,164.78 57.65,165.13 57.25,165.54 57.17,165.58 57.15,165.67 57.15,166.33 56.85,166.93 56.83,167.04 56.93,167.09 58.31,167.9 58.04,169.48 58.02,169.59 58.12,169.65 58.29,169.65
DGND on TOP (solid shape): 57.94,54 58.01,53.97 58.04,53.91 58.05,53.85 58.06,53.8 58.05,53.71 57.96,53.67 57.2,53.67 56.7,53.17 56.7,50.8 56.41,50.8 56.41,51.21 56.39,51.23 56.36,51.3 56.39,51.38 56.49,51.66 56.35,51.94 56.35,51.94 56,52.29 55.75,52.29 55.75,52.31 54.58,52.31 54.58,51.64 54.43,51.64 53.95,51.16 53.95,50.61 53.71,50.37 52.8,50.37 52.72,50.4 52.7,50.48 52.7,50.52 52.7,50.8 53.17,50.8 53.28,50.81 53.38,50.85 53.75,50.85 53.75,51.66 53.38,51.66 53.28,51.7 53.17,51.71 52.28,51.71 52.13,51.7 51.98,51.64 51.97,51.63 51.86,51.63 51.86,51.51 51.85,51.5 51.8,51.38 51.79,51.26 51.79,50.65 51.72,50.55 51.61,50.57 50.92,51.26 50.92,52.12 52.01,53.21 52.01,53.69 52.17,53.69 52.35,53.74 52.46,53.89 52.47,53.92 52.84,53.92 53.3,53.47 53.7,53.47 53.7,53.28 53.75,53.28 53.75,53.12 53.6,52.96 52.58,52.96 52.58,52.15 53.75,52.15 53.75,52.18 53.88,52.18 54.51,52.8 54.51,53.28 54.56,53.28 54.56,54
DGND on TOP (solid shape): 109.58,40.6 109.66,40.56 109.67,40.47 109.67,40.33 109.72,40.19 109.72,39.09 109.81,39.09 109.81,38.99 109.88,38.92 109.88,38.89 110.01,38.58 110.34,38.49 110.42,38.47 110.46,38.39 110.46,38.05 110.77,37.74 110.77,37.72 110.73,37.64 110.64,37.62 110.56,37.64 110.47,37.64 110.13,37.64 109.58,37.09 109.48,37.07 109.41,37.14 109.26,37.37 109,37.44 109,37.44 108.59,37.44 108.53,37.49 108.53,37.66 108.58,37.74 108.68,37.75 108.93,37.71 109.15,37.85 109.15,37.85 109.61,38.31 109.61,39.62 109.6,39.73 109.55,39.83 109.55,40.16 108.92,40.16 108.92,39.83 108.87,39.73 108.86,39.62 108.86,38.63 108.62,38.39 108.59,38.36 108.48,38.34 108.41,38.43 108.41,39.62 108.4,39.73 108.35,39.83 108.35,40.16 107.06,40.16 107.06,40.26 107.4,40.6
DGND on TOP (solid shape): 72.09,164.68 72.14,164.77 72.24,164.77 72.42,164.69 72.61,164.63 72.68,164.57 72.68,164.49 72.72,164.18 73,164.05 73.03,164.05 73.64,163.44 73.64,161.28 73,160.64 73,160.49 72.88,160.49 72.88,160.45 72.82,160.45 72.82,159.99 72.83,159.99 72.83,159.69 72.82,159.6 72.83,159.52 72.83,159.22 72.86,159.22 72.86,157.99 72.29,157.99 72.29,158.07 72.27,158.07 72.27,158.44 71.81,158.89 71.35,158.44 71.35,158.07 71.33,158.07 71.33,157.03 72.29,157.03 72.29,157.08 72.96,157.08 72.98,157.05 73.01,156.94 72.91,156.88 71.37,156.88 71.33,156.88 71.28,156.87 70.99,156.87 70.99,156.13 71.28,156.13 71.33,156.13 71.37,156.12 72.9,156.12 73.54,155.48 73.54,155.07 73.54,155.01 73.56,154.94 73.56,154.68 73.3,154.68 73.23,154.69 73.17,154.7 72.7,154.7 72.45,154.95 72.32,154.95 72.32,154.95 71.59,154.95 71.59,154.95 71.32,154.95 71.32,155.05 70.28,155.05 70.28,154.44 69.23,154.44 69.01,154.67 68.98,154.7 69.72,155.45 69.72,157.4 72.09,159.77
DGND on TOP (solid shape): 31.74,71.17 31.81,71.27 31.92,71.24 32.75,70.41 34.72,70.41 35.27,69.86 37.71,69.86 37.8,69.79 37.78,69.68 37.6,69.51 37.52,69.48 37.44,69.53 37.28,69.68 37.07,69.72 37.07,69.72 35.72,69.72 35.23,69.24 35.15,69.21 35.07,69.26 34.43,69.28 34.68,68.69 34.73,68.68 34.73,67.55 34.02,67.55 33.41,68.16 33.39,68.27 33.49,68.33 33.51,68.33 33.54,68.37 33.56,68.37 34.27,68.74 33.56,69.12 33.23,69.12 33.19,69.09 32.85,69.07 32.71,68.99 32.64,68.96 32.57,68.99 31.74,69.82
DGND on TOP (solid shape): 95.12,60.81 95.2,60.77 95.22,60.68 95.2,60.62 95.2,60.55 95.2,59.77 95.22,59.64 95.27,59.53 95.28,59.51 95.28,59.4 95.39,59.4 95.4,59.39 95.56,59.32 95.73,59.31 95.81,59.29 95.84,59.21 95.84,58.7 95.87,58.57 95.93,58.45 95.93,57.85 95.87,57.73 95.84,57.6 95.84,56.99 95.81,56.92 95.73,56.89 95.57,56.88 95.42,56.82 95.41,56.81 95.3,56.81 95.3,56.69 95.29,56.68 95.24,56.56 95.22,56.44 95.22,56.32 95.16,56.26 94.39,56.26 93.62,57.02 93.62,57.48 93.61,57.61 93.56,57.72 93.55,57.73 93.55,57.85 93.44,57.85 93.43,57.86 93.3,57.92 93.17,57.94 93.12,57.93 93.07,57.93 92.99,57.95 92.95,58.03 92.95,58.43 92.93,58.57 92.86,58.68 92.86,59.26 92.94,59.39 92.96,59.53 92.96,59.67 93.04,59.67 93.05,59.65 93.56,59.48 93.88,59.92 93.88,60.18 93.75,60.31 93.75,60.45 93.73,60.58 93.68,60.69 93.68,60.71 93.68,60.81
DGND on TOP (solid shape): 75.11,66.58 75.17,66.68 75.28,66.65 76.63,65.3 77.36,65.3 77.36,64.6 79.27,64.6 79.27,65.95 79.43,65.95 79.73,65.65 79.73,64.69 80.83,63.59 80.85,63.48 80.76,63.42 80.01,63.42 78.82,62.24 78.82,61.62 78.82,61.57 78.83,61.53 78.83,61.4 78.8,61.36 78.74,61.37 78.58,61.53 78.58,61.88 78.58,61.93 78.57,61.98 78.57,62.28 77.84,62.28 77.7,62.28 77.72,62.4 77.72,62.46 77.72,62.99 77.26,63.45 76.81,62.99 76.81,62.46 76.83,62.32 76.89,62.19 76.89,61.99 76.88,61.9 76.89,61.81 76.89,61.52 77.63,61.52 77.63,61.52 77.83,61.52 77.83,61.22 78.32,60.72 78.32,60.29 78.23,60.29 78.13,60.39 78.13,60.41 77.74,60.81 77.37,60.39 77.37,60.08 77.87,59.58 77.87,59.47 77.73,59.47 77.72,59.47 77.64,59.5 77.55,59.51 76.89,59.51 76.41,59.99 75.66,59.99 75.57,60.04 75.57,60.14 75.61,60.4 75.47,60.62 75.47,60.62 75.11,60.99
DGND on TOP (solid shape): 41.32,168.9 41.44,168.88 42.24,168.08 43.13,168.08 43.59,167.62 43.59,166.43 43.56,166.36 43.49,166.33 43.32,166.29 43.19,166.18 43.13,166.12 43.07,166.18 42.5,166.21 42.53,165.65 42.58,165.61 42.58,165.25 42.86,164.97 42.88,164.86 42.79,164.8 41.68,164.8 41.25,164.36 41.25,163.58 41.45,163.38 41.45,162.41 41.91,162.41 41.99,162.34 41.99,162.15 41.63,162.15 41.63,162.1 40.71,162.1 40.71,161.16 40.94,161.16 40.94,160.43 42.14,159.22 42.14,158.96 41.95,158.77 40.77,158.77 39.19,160.36 39.19,163.94 40.08,164.83 40.1,164.83 40.45,165.16 40.1,165.49 40.01,165.53 40,165.62 40.01,166.31 39.7,166.93 39.69,167.04 39.78,167.09 40.95,167.57 41.27,168.79
DGND on TOP (solid shape): outline of 81 points within 81.23,126.68 87.14,130.09
DGND on TOP (solid shape): outline of 254 points within 79.32,31.98 105.62,59.8
DGND on TOP (solid shape): outline of 163 points within 45.57,107.81 61.27,129.9
DGND on BOTTOM (solid shape): 84.59,151.67 81.78,151.67 81.78,154.47 84.59,154.47
DGND on BOTTOM (solid shape): 88.67,78.29 86.49,78.29 86.49,85.97 88.67,85.97
DGND on BOTTOM (solid shape): 101.99,151.67 99.18,151.67 99.18,154.47 101.99,154.47
DGND on BOTTOM (solid shape): 35.94,34.49 36.42,34.01 36.42,33.78 35.05,33.78 34.9,33.93 34.9,34.8 35.03,34.92 35.94,34.92
DGND on BOTTOM (solid shape): 39.47,80.11 39.57,80.01 39.57,79.41 39.53,79.41 39.53,78.94 39.04,78.94 38.61,79.37 38.61,82.26 39.47,82.26
DGND on BOTTOM (solid shape): 37.27,86.24 37.29,86.13 37.2,86.07 35,86.07 33.68,84.75 33.63,84.8 33.63,85.03 35.07,86.46 37.04,86.46
DGND on BOTTOM (solid shape): 100.18,121.73 99.54,121.09 99.54,120.97 97.7,120.97 97.7,121.32 97.92,121.54 98.57,121.54 98.88,121.85 99.19,121.54 99.59,121.54 99.74,121.57 99.86,121.65 100.06,121.85
DGND on BOTTOM (solid shape): 46.6,97.22 46.59,97.2 46.53,97.1 46.51,96.98 46.51,96.52 46.98,96.04 46.92,95.98 46.87,95.95 46.83,95.91 46.65,95.73 46.65,95.71 46.45,95.51 46.07,95.89 46.07,96.87 46.51,97.31 46.6,97.31
DGND on BOTTOM (solid shape): 36.25,120.95 36.27,120.84 36.18,120.77 36.12,120.77 33.73,123.17 33.7,123.28 33.8,123.34 33.85,123.34
DGND on BOTTOM (solid shape): 39.13,104.45 39.22,104.38 39.2,104.27 37.11,102.18 36.91,102.18 36.81,102.24 36.83,102.36 38.93,104.45
DGND on BOTTOM (solid shape): 61.77,56.62 63.75,56.62 63.75,56.5 63.74,56.44 63.73,56.38 63.73,55.57 63.73,55.43 62.8,55.43 62.8,55.35 61.4,55.35 61.02,55.35 61.02,56 59.25,56 58.88,56.37 58.88,56.81 61.58,56.81
DGND on BOTTOM (solid shape): 75.62,55.64 75.64,55.53 75.55,55.47 74.92,55.47 70.75,59.64 70.72,59.75 70.82,59.82 71.45,59.82
DGND on BOTTOM (solid shape): 81.16,56.29 81.26,56.23 81.23,56.12 80.95,55.83 76.51,55.83 76.43,55.91 76.42,55.96 76.46,55.99 80.79,55.99 81.08,56.29
DGND on BOTTOM (solid shape): 42.39,125.7 42.42,125.59 42.32,125.53 41.33,125.53 41.33,123.52 39.12,123.52 36.67,125.97 36.65,126.08 36.74,126.14 41.96,126.14
DGND on BOTTOM (solid shape): 45.72,124.04 45.78,124.13 45.89,124.11 49.59,120.41 49.61,120.3 49.51,120.24 49.28,120.24 48.8,120.72 47.93,120.72 45.72,122.94
DGND on BOTTOM (solid shape): 58.53,113.43 58.55,113.32 58.45,113.26 58.07,113.26 57.08,114.25 48.52,114.25 48.25,114.51 48.23,114.62 48.33,114.68 57.27,114.68
DGND on BOTTOM (solid shape): 59.85,119.31 59.95,119.24 59.92,119.13 59.29,118.5 58.33,118.5 57.97,118.87 57.2,118.87 57.1,118.93 57.12,119.04 57.39,119.31
DGND on BOTTOM (solid shape): 63.29,151.06 63.31,150.95 63.22,150.89 53.86,150.89 53.62,150.64 53.31,150.64 53.21,150.71 53.23,150.82 53.98,151.56 62.78,151.56
DGND on BOTTOM (solid shape): 89.27,120.58 89.4,120.5 89.56,120.48 89.83,120.48 89.86,120.44 89.86,119.07 89.83,119.03 89.04,119.03 89.04,120.46 89.04,120.48 89.06,120.56 89.14,120.59 89.25,120.59
DGND on BOTTOM (solid shape): 13.31,130.4 13.34,130.29 13.24,130.22 9.76,130.22 9.62,130.36 9.59,130.44 9.63,130.52 9.68,130.55 9.72,130.6 10.49,131.37 12.34,131.37
DGND on BOTTOM (solid shape): 64.67,73.16 64.73,73.25 64.84,73.23 66.64,71.43 66.66,71.32 66.57,71.26 64.06,71.26 63.54,71.78 63.54,72.54 64.41,72.54 64.67,72.8
DGND on BOTTOM (solid shape): 14.4,76.63 14.4,75.79 14.51,75.69 14.53,75.58 14.44,75.51 13.48,75.51 13.38,75.58 13.41,75.69 13.44,75.72 13.44,77.09 13.49,77.14 13.89,77.14
DGND on BOTTOM (solid shape): 51.53,88.1 51.54,88.04 51.49,88.01 51.42,88.01 51.42,88.01 50.69,88.01 50.69,88.01 49.97,88.01 49.92,88.06 48.16,88.06 47.86,88.36 45.62,88.36 45.53,88.46 45.52,88.52 45.56,88.55 51.08,88.55
DGND on BOTTOM (solid shape): 55.28,56.53 55.34,56.54 55.37,56.49 55.37,56.41 55.37,56.41 55.37,55.63 55.09,55.35 53.32,55.35 53.32,54.65 53,54.65 52.98,54.65 52.9,54.67 52.87,54.75 52.87,56.04 53.32,56.49 55.25,56.49
DGND on BOTTOM (solid shape): 120.21,51.06 120.19,51.02 120.13,50.87 120.1,50.71 120.03,50.63 119.92,50.65 118.91,51.67 107.86,51.67 107.79,51.74 107.77,51.85 107.86,51.91 119.35,51.91
DGND on BOTTOM (solid shape): 58.96,128.55 59.06,128.49 59.03,128.38 57.93,127.28 57.71,127.28 57.66,127.28 55.15,127.28 55.13,127.29 55.11,127.4 55.2,127.47 57.53,127.47 58.62,128.55
DGND on BOTTOM (solid shape): 45.94,39.27 46.27,38.94 48.51,38.94 48.58,38.87 48.59,38.82 48.54,38.79 46.2,38.79 45.94,39.05 45.89,39.1 45.83,39.15 45.77,39.22 45.8,39.31 45.85,39.36
DGND on BOTTOM (solid shape): 15.22,129.36 15.22,128.96 15.5,128.67 15.53,128.56 15.43,128.5 15.32,128.5 14.68,129.13 14.56,129.22 14.41,129.25 14.12,129.25 14.12,129.69 14.07,129.75 14.04,129.86 14.14,129.92 14.65,129.92
DGND on BOTTOM (solid shape): 80.49,46.08 80.51,45.97 80.42,45.9 74.86,45.9 74.07,45.12 73.23,45.12 73.16,45.15 73.13,45.22 73.11,45.36 73.03,45.48 73,45.56 73.03,45.62 73.82,46.41 80.15,46.41
DGND on BOTTOM (solid shape): 95.41,112.4 95.45,112.37 95.44,112.31 95.37,112.24 95.37,111.94 94.9,111.94 94.9,111.12 94.88,111.05 94.87,110.99 94.87,110 94.81,109.9 94.7,109.92 94.6,110.02 94.61,110.03 94.61,110.86 94.63,110.93 94.63,110.99 94.63,112.15 94.87,112.4
DGND on BOTTOM (solid shape): 57.37,51.08 60.07,51.08 60.17,51.02 60.14,50.91 59.55,50.31 56.27,50.31 56.25,50.33 56.22,50.45 56.32,50.51 56.74,50.51 56.74,51.35 56.69,51.35 56.69,51.59 56.49,51.8 56.47,51.85 56.52,51.88 56.57,51.88
DGND on BOTTOM (solid shape): 62.52,73.34 62.52,73.3 62.55,73.28 62.55,71.37 63.65,70.27 66.95,70.27 66.97,70.25 66.99,70.14 66.9,70.08 62.28,70.08 61.92,69.72 61.9,69.7 61.83,69.68 61.76,69.71 59.44,72.03 59.42,72.14 59.51,72.2 61.18,72.2 62.42,73.44
DGND on BOTTOM (solid shape): 69.69,85.09 69.77,85.05 69.78,84.96 69.82,84.68 70.06,84.53 70.1,84.52 70.1,84.25 69.36,84.25 69.12,84.49 69.05,84.58 68.96,84.65 68.71,84.9 68.53,84.72 68.47,84.72 68.29,84.55 68.17,84.68 68.58,85.09
DGND on BOTTOM (solid shape): 63.91,82.38 64.23,82.7 64.29,82.68 64.71,82.68 64.71,81.89 64.68,81.84 64.62,81.85 64.59,81.88 63.95,81.24 63.92,81.25 63.85,81.29 63.78,81.3 63.7,81.37 63.73,81.48 63.93,81.68 63.3,82.3 63.31,82.33 63.33,82.43 63.32,82.53 63.32,82.56 63.37,82.61 63.36,82.62 63.51,82.78
DGND on BOTTOM (solid shape): 4.83,71.63 4.94,71.66 5,71.56 5,69.47 5.11,69.37 5.11,68.38 5.31,68.17 4.72,67.59 4.72,64.77 6.05,63.45 6.92,63.45 7.01,63.39 6.99,63.28 6.86,63.14 6.86,62.42 6.8,62.33 6.68,62.35 4.27,64.77 4.27,71.07
DGND on BOTTOM (solid shape): 95.71,123.16 95.71,121.16 95.64,121.09 95.64,120.97 95.59,120.97 95.59,119.42 95.54,119.34 95.45,119.33 95.37,119.36 95.29,119.36 94.89,119.36 94.81,119.29 94.7,119.26 94.64,119.36 94.64,122.91 94.22,123.33 94.2,123.44 94.29,123.51 95.36,123.51
DGND on BOTTOM (solid shape): 30.58,41.91 30.65,41.88 30.69,41.81 30.69,41.5 30.58,41.5 30.58,40.41 30.43,40.25 30.43,39.16 30.43,39.1 30.45,39.03 30.45,38.35 30.36,38.26 30.31,38.25 30.28,38.29 30.28,40.18 29.87,40.59 29.87,41.48 29.64,41.71 29.56,41.71 29.46,41.77 29.49,41.88 29.52,41.91
DGND on BOTTOM (solid shape): 88.16,105.57 88.22,105.67 88.33,105.64 88.92,105.06 89.61,105.06 89.61,104.53 89.9,104.24 89.9,102.51 89.82,102.43 89.74,102.31 89.71,102.16 89.71,101.65 88.83,101.65 88.16,102.32 88.16,103.58 88.35,103.58 88.75,103.98 88.75,104.38 88.72,104.52 88.63,104.65 88.46,104.82 88.35,104.9 88.21,104.93 88.18,104.95 88.16,104.98
DGND on BOTTOM (solid shape): 99.65,112.85 99.71,112.95 99.82,112.92 100.64,112.11 100.66,112 100.56,111.94 100.4,111.94 100.4,111.12 100.38,111.05 100.37,110.99 100.37,109.48 100.39,109.47 100.41,109.36 100.31,109.29 99.75,109.29 99.63,109.41 99.63,110.03 100.11,110.03 100.11,110.86 100.13,110.93 100.13,110.99 100.13,112.22 99.65,112.69
DGND on BOTTOM (solid shape): 116.61,33.48 114.79,31.66 114.68,31.63 114.62,31.73 114.62,35.45 114.68,35.54 114.79,35.52 115.12,35.19 115.77,35.19 115.77,35.83 115.57,36.03 115.57,36.82 116.61,36.82
DGND on BOTTOM (solid shape): 124.81,52.24 124.87,52.15 124.87,49.71 124.2,49.04 122.72,49.04 122.63,49.11 122.65,49.22 122.92,49.49 122.92,52.02 122.98,52.11 123.08,52.1 123.91,51.85 124.69,52.22
DGND on BOTTOM (solid shape): 115.85,68.68 115.92,68.65 115.95,68.59 115.99,68.43 116.1,68.31 116.3,68.1 116.3,65.3 116.24,65.21 116.13,65.23 115.84,65.33 115.58,65.18 115.47,65.08 109.63,65.08 109.02,65.68 105.64,65.68 105.57,65.71 105.54,65.78 105.54,65.86 111.97,65.86 114.78,68.68
DGND on BOTTOM (solid shape): 19.04,95.99 19.07,95.92 19.03,95.85 18.94,95.73 18.9,95.59 18.89,95.55 18.29,95.55 18.29,95.25 18.28,95.21 18.28,95.17 18.28,95.07 18.22,94.98 18.11,95 17.78,95.32 17.33,95.32 17.26,95.39 17.26,96.58 16.18,96.58 16.1,96.62 16.08,96.69 16.08,96.75 16.07,96.81 16.09,96.89 16.17,96.93 18.1,96.93
DGND on BOTTOM (solid shape): 25.31,87.12 25.4,87.06 25.38,86.95 25.33,86.9 25.33,86.11 25.17,86.12 25.08,86.11 24.79,86.11 24.79,85.38 24.79,85.38 24.79,84.56 23.7,84.56 23.61,84.62 23.63,84.73 23.72,84.82 23.72,85.14 23.75,85.24 23.77,85.35 23.77,86.14 23.56,86.35 23.47,86.42 23.36,86.47 23.29,86.54 23.32,86.64 23.42,86.74 23.42,87.12
DGND on BOTTOM (solid shape): 80.94,65.41 80.97,65.33 80.93,65.26 80.88,64.68 81.46,64.72 81.54,64.77 81.62,64.74 81.85,64.5 81.88,64.39 81.78,64.33 79.68,64.33 78.67,65.34 78.65,65.45 78.74,65.51 80.84,65.51
DGND on BOTTOM (solid shape): 92.56,57.07 92.64,57.04 92.66,56.96 93.04,56.51 93.42,56.96 93.44,57.04 93.52,57.07 96.7,57.07 97.39,56.38 97.42,56.26 97.32,56.2 91.64,56.2 91.45,56 91.12,56 91.03,56.07 91.05,56.18 91.95,57.07
DGND on BOTTOM (solid shape): 44.74,98.62 45,98.55 45.27,98.62 46.02,98.62 46.1,98.55 46.13,98.55 46.44,98.24 46.46,98.13 46.36,98.07 46.2,98.07 45.29,97.16 44.74,97.16 44.74,96.38 44.48,96.38 44.42,96.32 44.37,96.31 44.34,96.36 44.34,97.51 44.3,97.51 44.3,97.59 43.91,97.98 43.91,97.98 43.61,98.12 43.31,97.97 43.25,97.95 43.22,98 43.22,98.3 43.55,98.62
DGND on BOTTOM (solid shape): 61.28,45.39 61.38,45.33 61.35,45.22 57.88,41.75 57.77,41.73 57.71,41.82 57.71,43.31 57.5,43.51 56.9,43.51 56.57,43.18 56.57,43.07 56.5,42.98 56.39,43 55.29,44.1 55.29,44.11 55.05,44.4 54.69,44.35 53.43,44.35 53.34,44.41 53.36,44.52 53.47,44.63 56.54,44.63 56.92,44.25 59,44.25 60.14,45.39
DGND on BOTTOM (solid shape): 48.66,128.26 48.73,128.35 48.84,128.33 50.18,126.99 52.73,126.99 52.81,126.95 52.82,126.86 52.82,126.63 52.95,126.45 53.33,126.07 53.83,126.07 53.91,126.03 53.93,125.96 53.93,125.91 53.94,125.87 53.92,125.79 53.84,125.75 51.21,125.75 50.95,125.86 50.69,125.75 50.62,125.72 50.55,125.75 48.66,127.64
DGND on BOTTOM (solid shape): 43.03,80.7 43.06,80.66 43.06,79.86 44.02,79.86 44.19,79.69 44.53,79.69 44.53,79.59 44.67,79.59 44.67,79.24 44.16,78.74 44.11,78.76 43.14,78.76 43.14,77.72 43.74,77.72 43.83,77.66 43.81,77.55 43.64,77.37 42.18,77.37 42.1,77.41 42.03,77.93 41.66,78.12 41.43,78.12 41.43,78.76 41.39,78.76 41.39,79.01 41.36,79.03 41.34,79.14 41.44,79.21 41.98,79.21 41.98,80.37 42.11,80.37 42.11,82.22 43.03,82.22
DGND on BOTTOM (solid shape): 87.61,53.74 87.64,53.67 87.6,53.6 87.51,53.48 87.48,53.33 87.45,53.27 87.38,53.24 86.95,53.24 86.44,53.74 84.65,53.74 84.53,53.62 84.45,53.59 84.37,53.64 83.92,53.8 83.67,53.38 83.65,53.3 83.57,53.26 83.2,53.26 83.11,53.32 83.13,53.43 83.67,53.98 87.37,53.98
DGND on BOTTOM (solid shape): 101.87,98.75 100.43,97.3 100.09,97.3 100,97.35 100,97.45 99.66,98.01 99.32,97.45 99.31,97.35 99.23,97.3 88.02,97.3 84.86,100.46 84.86,101.92 85.2,101.92 85.34,101.95 85.46,102.03 85.53,102.1 85.64,102.12 85.7,102.03 85.7,100.81 87.91,98.61 100.79,98.61 101.63,99.44 101.63,102.53 101.87,102.53
DGND on BOTTOM (solid shape): 9.91,61.66 10,61.63 10.06,61.57 10.06,60.35 11.38,59.03 11.38,57.9 11.32,57.81 11.21,57.83 9.54,59.49 9.57,59.53 9.54,60.04 9.03,60.07 9,60.04 7.72,61.32 7.69,61.43 7.79,61.49 8.97,61.49 9.04,61.56 9.12,61.59 9.19,61.55 9.53,61.39 9.84,61.6
DGND on BOTTOM (solid shape): 29.87,90.38 29.94,90.35 30.25,90.05 32.47,90.05 32.56,89.98 32.54,89.87 30.68,88.01 26.44,88.01 25.75,87.32 25.64,87.3 25.58,87.39 25.58,87.87 25.77,87.87 26.91,89 30.84,89 30.85,89 31.27,89.38 30.85,89.76 30.84,89.76 27.22,89.76 27.13,89.82 27.15,89.93 27.46,90.25 29.5,90.25 29.66,90.27 29.8,90.35
DGND on BOTTOM (solid shape): 45.29,38.51 45.32,38.55 45.37,38.54 45.41,38.51 45.89,38.03 48.71,38.03 48.81,37.97 48.78,37.86 48.32,37.39 47.19,37.39 47.18,37.39 46.76,37.01 47.18,36.63 47.19,36.63 48.63,36.63 50.37,38.37 50.48,38.4 50.55,38.3 50.55,37.97 48.75,36.18 46.94,36.18 44.98,34.22 44.88,34.19 44.81,34.26 44.76,34.35 44.69,34.44 43.87,35.25 43.1,35.25 43.1,35.61 44.53,35.61 45.29,36.37
DGND on BOTTOM (solid shape): 50.81,84.85 50.95,84.85 50.95,84.68 50.81,84.68 50.81,83.29 51.86,83.29 51.93,83.35 52.03,83.33 52.45,82.91 52.87,82.91 52.96,82.85 52.94,82.73 52.88,82.68 50.78,82.68 50.77,82.71 50.19,82.9 50.15,82.3 50.18,82.23 50.15,82.16 49.99,81.99 49.35,81.99 49.25,82.05 49.28,82.16 49.47,82.36 49.47,84.72 49.44,84.76 49.43,84.82 49.47,84.85 50.37,84.85 50.37,85.96 50.81,85.96
DGND on BOTTOM (solid shape): 43.63,61.14 43.69,61.15 43.72,61.11 43.72,61.07 44.12,60.67 44.14,60.61 44.09,60.58 44.02,60.58 43.18,59.74 43.18,58.61 43.12,58.52 43.01,58.54 42.87,58.67 41.93,58.67 41.01,59.59 41.01,59.6 40.83,59.78 40.58,59.81 40.56,59.8 40.5,59.86 40.59,59.95 41.38,59.95 41.45,59.92 41.48,59.84 41.86,59.44 42.24,59.84 42.27,59.92 42.34,59.95 42.44,59.95
DGND on BOTTOM (solid shape): 85.99,74.96 86.1,74.98 86.16,74.89 86.16,74.48 84.99,73.31 84.99,71.4 88.45,67.94 88.47,67.83 88.38,67.76 87.51,67.76 86.28,68.99 86.25,69.07 86.29,69.14 86.32,69.71 85.75,69.68 85.68,69.64 85.6,69.67 84.68,70.59 84.68,74.04 84.94,74.3 85.01,74.33 85.08,74.3 85.53,74.24 85.72,74.66 85.71,74.68
DGND on BOTTOM (solid shape): 61.81,68.59 61.82,68.59 61.91,68.52 61.89,68.41 60.61,67.13 55.09,67.13 55.04,67.16 55.05,67.22 55.1,67.27 55.21,67.72 54.8,67.94 54.72,67.96 54.68,68.04 54.68,68.53 53.62,68.53 53.6,68.55 53.29,68.55 53.29,68.91 53.54,69.16 54.51,69.16 54.77,69.42 54.77,70.52 54.55,70.74 52.96,70.74 51.59,69.37 51.59,68.87 51.49,68.87 51.48,68.88 51.36,68.95 51.23,68.97 50.4,68.97 50.3,69 50.22,69.01 49.91,69.01 49.86,68.96 49.85,68.96 49.85,68.95 49.76,68.86 49.7,68.85 49.67,68.9 49.67,69.46 49.61,69.46 49.61,69.64 49.54,69.71 50,70.18 51.99,70.18 53.67,71.85 58.54,71.85
DGND on BOTTOM (solid shape): 60.08,81.46 60.18,81.32 60.32,81.23 60.32,81.06 61.1,81.06 61.1,81.03 62.04,81.03 62.04,81.18 62.84,81.18 62.84,81.2 62.9,81.2 63.04,81.2 63.14,81.1 63.11,81.04 63.11,81.04 63.11,80.55 63.07,80.47 62.99,80.45 62.94,80.46 62.9,80.46 62.86,80.48 62.85,80.51 62.85,80.66 61.91,80.66 61.91,80.48 61.79,80.36 61.71,80.33 61.64,80.36 61.48,80.47 61.3,80.51 60.61,80.51 60.16,80.06 60.07,80.06 60.06,80.1 60.03,80.22 59.96,80.32 59.89,80.38 59.86,80.47 60.07,80.82 59.96,81.12 59.8,81.29 59.78,81.4 59.87,81.46
DGND on BOTTOM (solid shape): 56.9,56.9 56.97,56.87 57,56.79 57,54.81 58.12,53.69 58.25,53.58 58.4,53.54 58.47,53.51 58.5,53.44 58.5,53.15 58.47,53.14 58.35,52.54 58.95,52.58 59.03,52.63 59.11,52.6 59.57,52.14 59.55,52.11 59.53,52.03 59.52,51.94 59.49,51.87 59.42,51.84 57.69,51.84 56.89,52.64 55.89,52.64 55.85,52.64 55.8,52.63 55.71,52.63 55.71,53.64 55.35,54 55.22,54 55.22,54.54 55.35,54.54 56.13,55.32 56.13,56.41 56.22,56.41 56.31,56.4 56.4,56.41 56.69,56.41 56.69,56.9
DGND on BOTTOM (solid shape): 23.95,25.04 24.02,25.02 24.05,24.94 24.05,24.19 24.54,23.71 24.54,23.46 24.53,23.38 24.54,23.29 24.54,22.99 25.24,22.99 25.38,22.85 25.4,22.74 25.31,22.68 25.01,22.68 24.51,22.18 24.51,21.13 24.51,21.12 24.89,20.7 25.27,21.12 25.27,21.13 25.27,21.87 25.33,21.92 25.41,21.92 25.41,21.86 25.42,21.63 25.57,21.45 25.61,21.37 25.58,21.29 25.53,21.24 25.53,20.32 25.53,20.28 25.5,20.21 25.43,20.19 25.16,20.19 25.12,20.18 25.07,20.17 24.69,20.17 24.64,20.18 24.6,20.19 24.39,20.19 23.8,20.78 23.8,24.94 23.83,25.02 23.9,25.05
DGND on BOTTOM (solid shape): 13.49,82.49 13.52,82.39 13.45,82.32 13.18,81.88 13.59,81.57 13.88,81.57 16.43,79.02 16.46,78.92 16.39,78.85 16.16,78.63 16.17,78.31 16.17,78.21 16.08,78.16 15.57,78.16 12.4,81.32 12.38,81.42 12.45,81.49 12.58,82.19 12,81.78 11.98,81.7 11.9,81.66 10.01,81.66 8.04,83.62 8.02,83.73 8.12,83.8 12.19,83.8
DGND on BOTTOM (solid shape): 80.29,45.15 80.36,45.12 80.4,45.05 80.43,44.92 80.51,44.8 80.52,44.77 80.51,44.73 80.39,44.48 80.48,44.21 80.5,44.14 80.48,44.08 80.74,43.43 81.05,44.06 81.02,44.13 81.05,44.19 81.15,44.46 81.04,44.73 81.03,44.76 81.04,44.8 81.12,44.91 81.16,45.05 81.19,45.12 81.26,45.15 85.25,45.15 86.79,43.6 86.79,39.4 87.66,38.54 87.68,38.42 87.59,38.36 86.4,38.36 86.4,41.56 82.98,41.56 82.63,41.21 82.56,41.12 82.46,41.15 82.09,41.52 81.17,41.52 78,44.69 74.96,44.69 74.87,44.75 74.89,44.86 75.17,45.15
DGND on BOTTOM (solid shape): 56.59,109.62 56.73,109.48 56.73,109.46 56.75,109.44 56.75,109.31 56.74,109.3 56.91,108.84 57.4,108.93 57.5,109.04 57.5,109.08 57.57,109.17 57.68,109.15 57.72,109.11 58.17,109 58.39,109.4 58.41,109.49 58.49,109.52 58.74,109.52 58.74,109.37 59.45,109.37 59.48,109.34 59.48,109.33 59.9,109 60.35,109.3 60.42,109.36 60.52,109.33 62.13,107.72 62.13,106.98 62.07,106.88 61.96,106.9 60.81,108.05 59.03,108.05 58.44,108.64 57.87,108.68 57.9,108.11 58.03,107.98 58.05,107.87 57.96,107.81 57.79,107.81 57.75,107.82 57.71,107.82 57.22,107.82 57.22,107.82 57.05,107.8 56.9,107.71 56.83,107.68 56.76,107.71 56.42,108.05 56.48,108.11 56.56,108.22 56.59,108.36 56.5,108.66 56.21,108.79 56.18,108.8 56.16,108.84 56.16,108.9 56.37,109.1 56.51,109.33 56.46,109.6 56.45,109.61 56.45,109.68 56.54,109.68
DGND on BOTTOM (solid shape): 54.66,132.29 54.73,132.26 54.76,132.19 54.9,131.92 55.18,131.83 55.19,131.83 62.54,131.83 62.64,131.77 62.62,131.66 61.77,130.81 59.97,130.81 59.89,130.84 59.87,130.91 59.75,131.21 59.45,131.32 59.44,131.32 53.14,131.32 52.72,131.73 52.16,131.77 52.19,131.2 52.83,130.56 53.43,130.56 53.52,130.5 53.5,130.39 52.85,129.74 52.85,129.74 52.82,129.17 53.38,129.2 54.23,130.05 59.95,130.05 60.03,130.01 60.05,129.93 60.05,129.86 60.05,129.79 60.03,129.7 59.96,129.66 58.16,129.66 57.07,128.57 56.41,128.57 56.34,128.6 56.31,128.67 55.93,129.03 55.55,128.67 55.52,128.6 55.45,128.57 53.04,128.57 51.09,130.52 51.06,130.61 51.11,130.68 51.2,131.28 50.59,131.2 50.52,131.15 50.43,131.18 49.95,131.66 49.93,131.76 50.01,131.83 50.15,131.88 50.26,131.97 50.58,132.29
DGND on BOTTOM (solid shape): 122.82,64.15 122.91,64.09 122.9,63.98 123.08,62.27 124.79,62.49 124.9,62.52 124.97,62.43 124.97,61.46 124.9,61.37 124.79,61.4 123.2,61.71 122.73,60.16 122.75,60.13 122.16,59.55 122.16,59.19 122.11,59.1 122,59.11 121.4,59.33 120.77,59.23 120.74,59.21 120.08,59.87 116.99,59.87 116.9,59.94 116.92,60.05 116.99,60.12 120.11,60.12 120.17,60.17 120.21,60.13 120.21,60.12 122.49,60.77 120.14,61.05 119.98,61.05 119.8,60.87 119.7,60.87 119.66,60.9 119.67,60.96 119.91,61.2 119.91,62.61 119.99,62.69 120.05,62.7 120.08,62.65 120.08,62.01 122.49,62.01 122.49,64.15
DGND on BOTTOM (solid shape): outline of 278 points within 64.44,115.69 77.96,118.44
DGND on BOTTOM (solid shape): outline of 121 points within 42.44,102.94 59.19,114.94
DGND on BOTTOM (solid shape): outline of 2238 points within 1.02,1.02 27.59,79.03
DGND on L03_SIG1 (solid shape): 1.02,59.39 1.08,59.48 1.19,59.46 2.38,58.27 7.2,58.27 8.81,56.66 8.81,53.63 8.07,52.89 7.78,52.89 7.75,52.96 7.77,52.97 7.77,54.53 6.71,55.58 1.02,55.58
DGND on L03_SIG1 (solid shape): 22.16,60.22 22.27,60.24 22.33,60.15 22.33,60.01 20.6,58.28 20.49,58.26 20.43,58.35 20.43,58.49
DGND on L03_SIG1 (solid shape): 23.94,79.27 24.05,79.29 24.11,79.2 24.11,71.43 23.94,71.27 23.83,71.25 23.77,71.34 23.77,79.1
DGND on L03_SIG1 (solid shape): 36.36,79.49 36.42,79.58 36.53,79.56 37.84,78.25 37.86,78.14 37.77,78.08 37.51,78.08 36.36,79.23
DGND on L03_SIG1 (solid shape): 48.34,75.3 48.4,75.4 48.51,75.38 50.45,73.44 50.45,73.21 50.39,73.11 50.28,73.14 48.34,75.07
DGND on L03_SIG1 (solid shape): 71.99,64.32 72.1,64.34 72.17,64.25 72.17,64.14 71.09,63.06 70.97,63.03 70.91,63.13 70.91,63.24
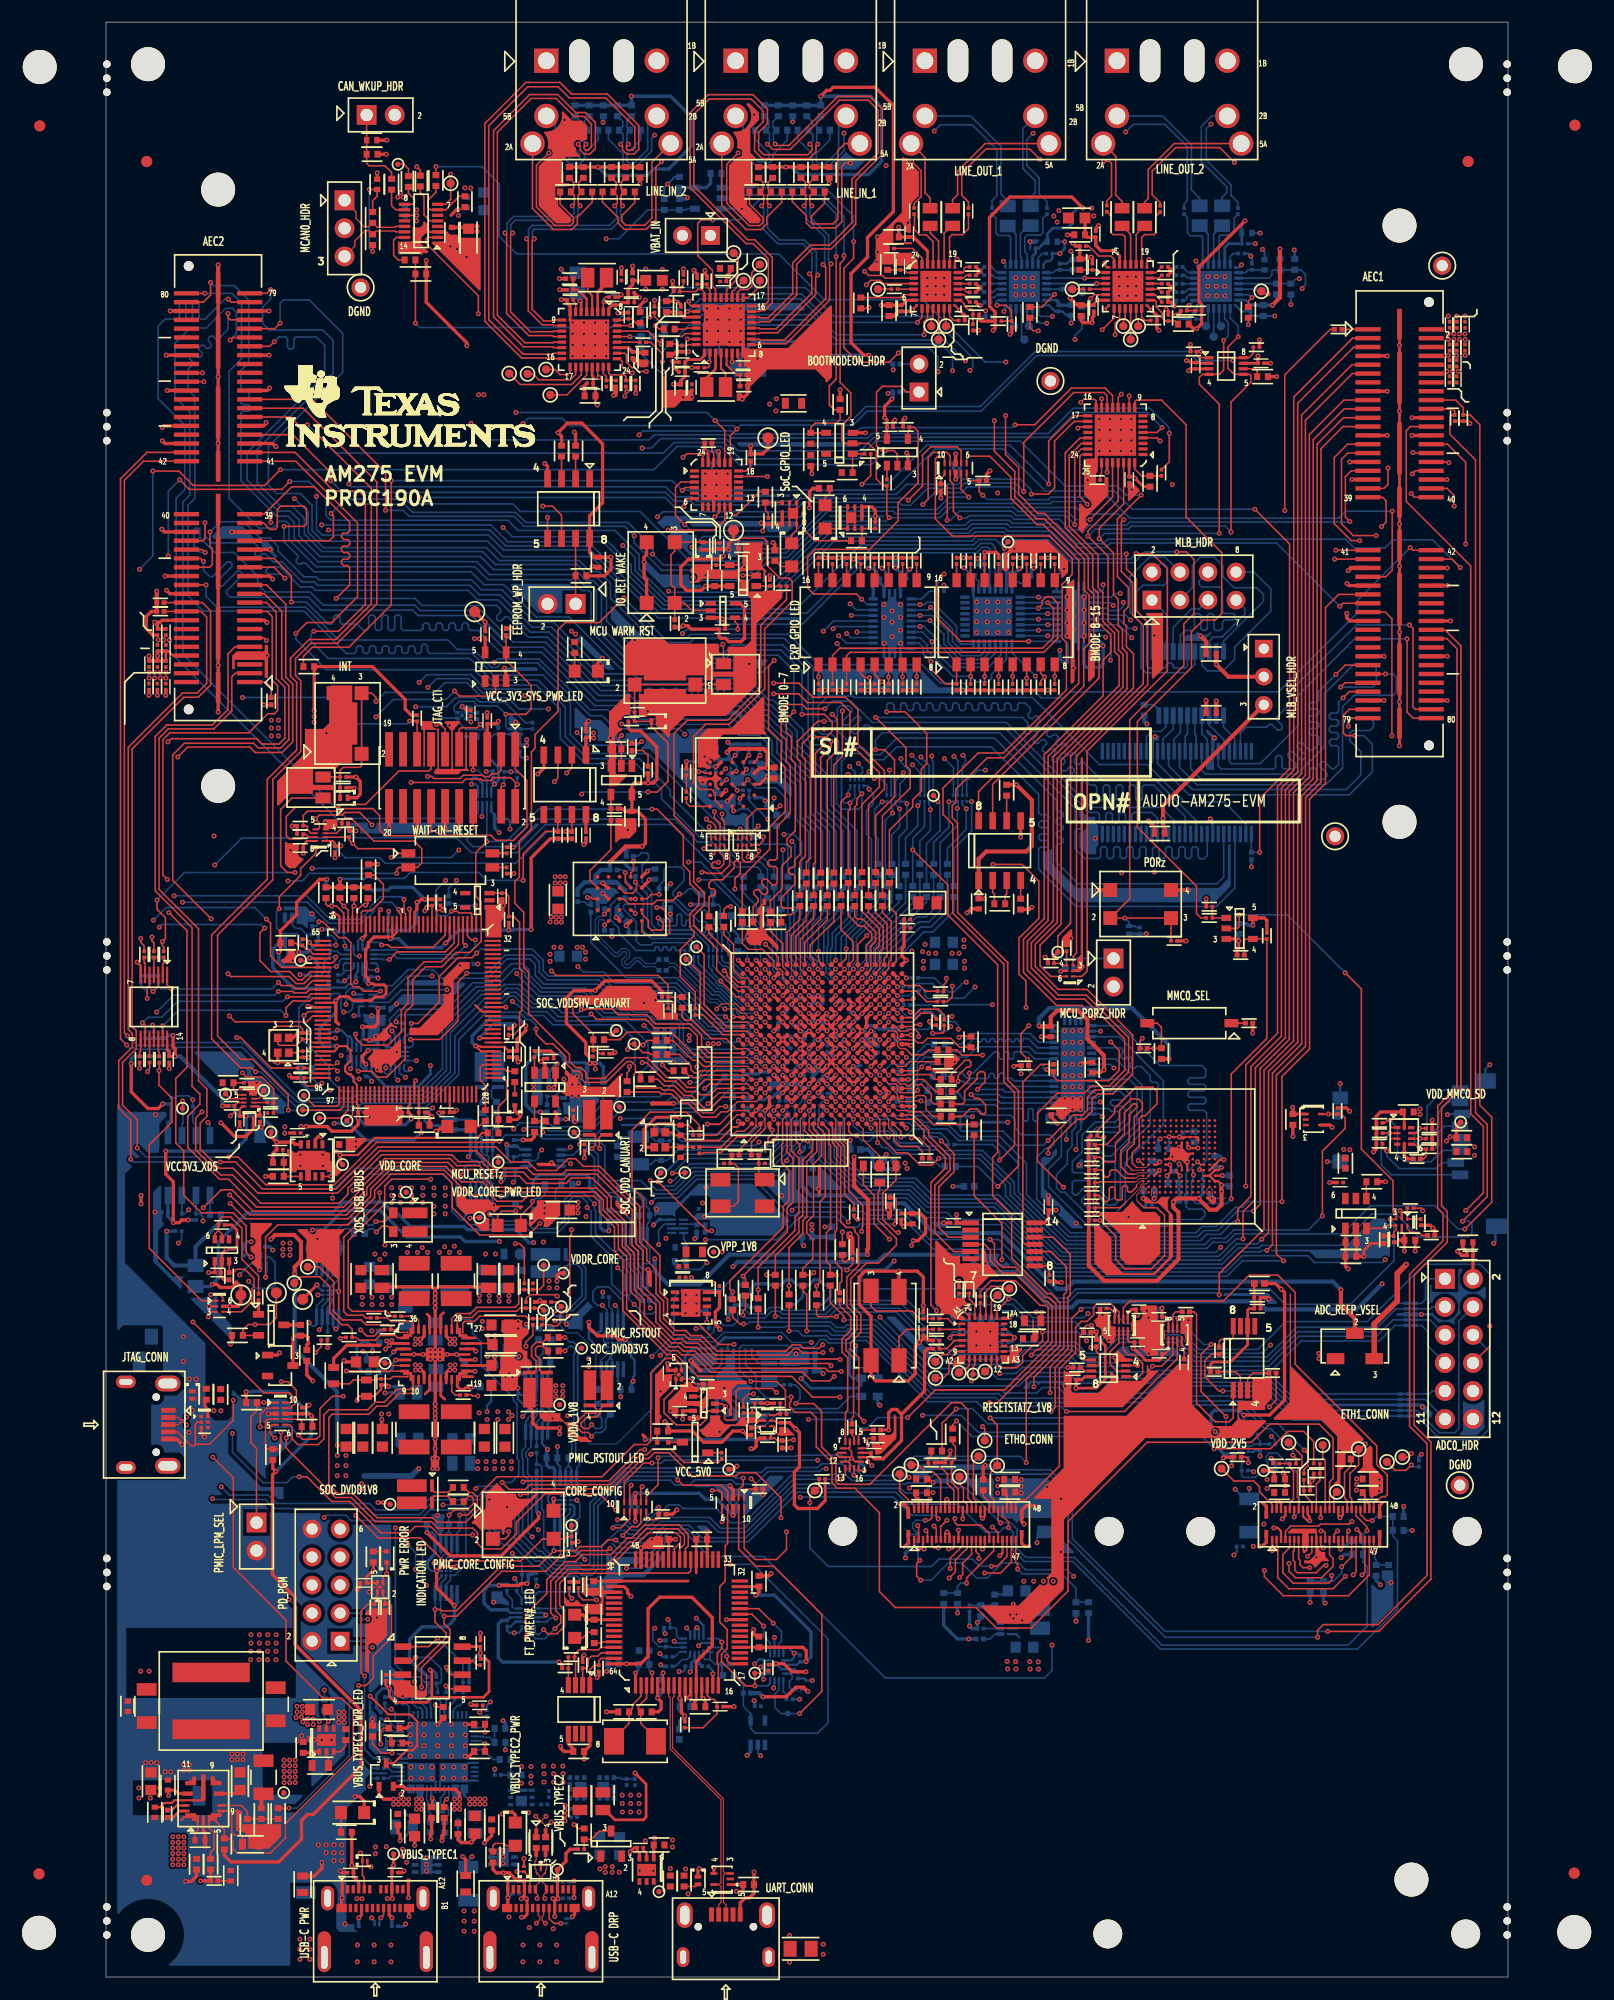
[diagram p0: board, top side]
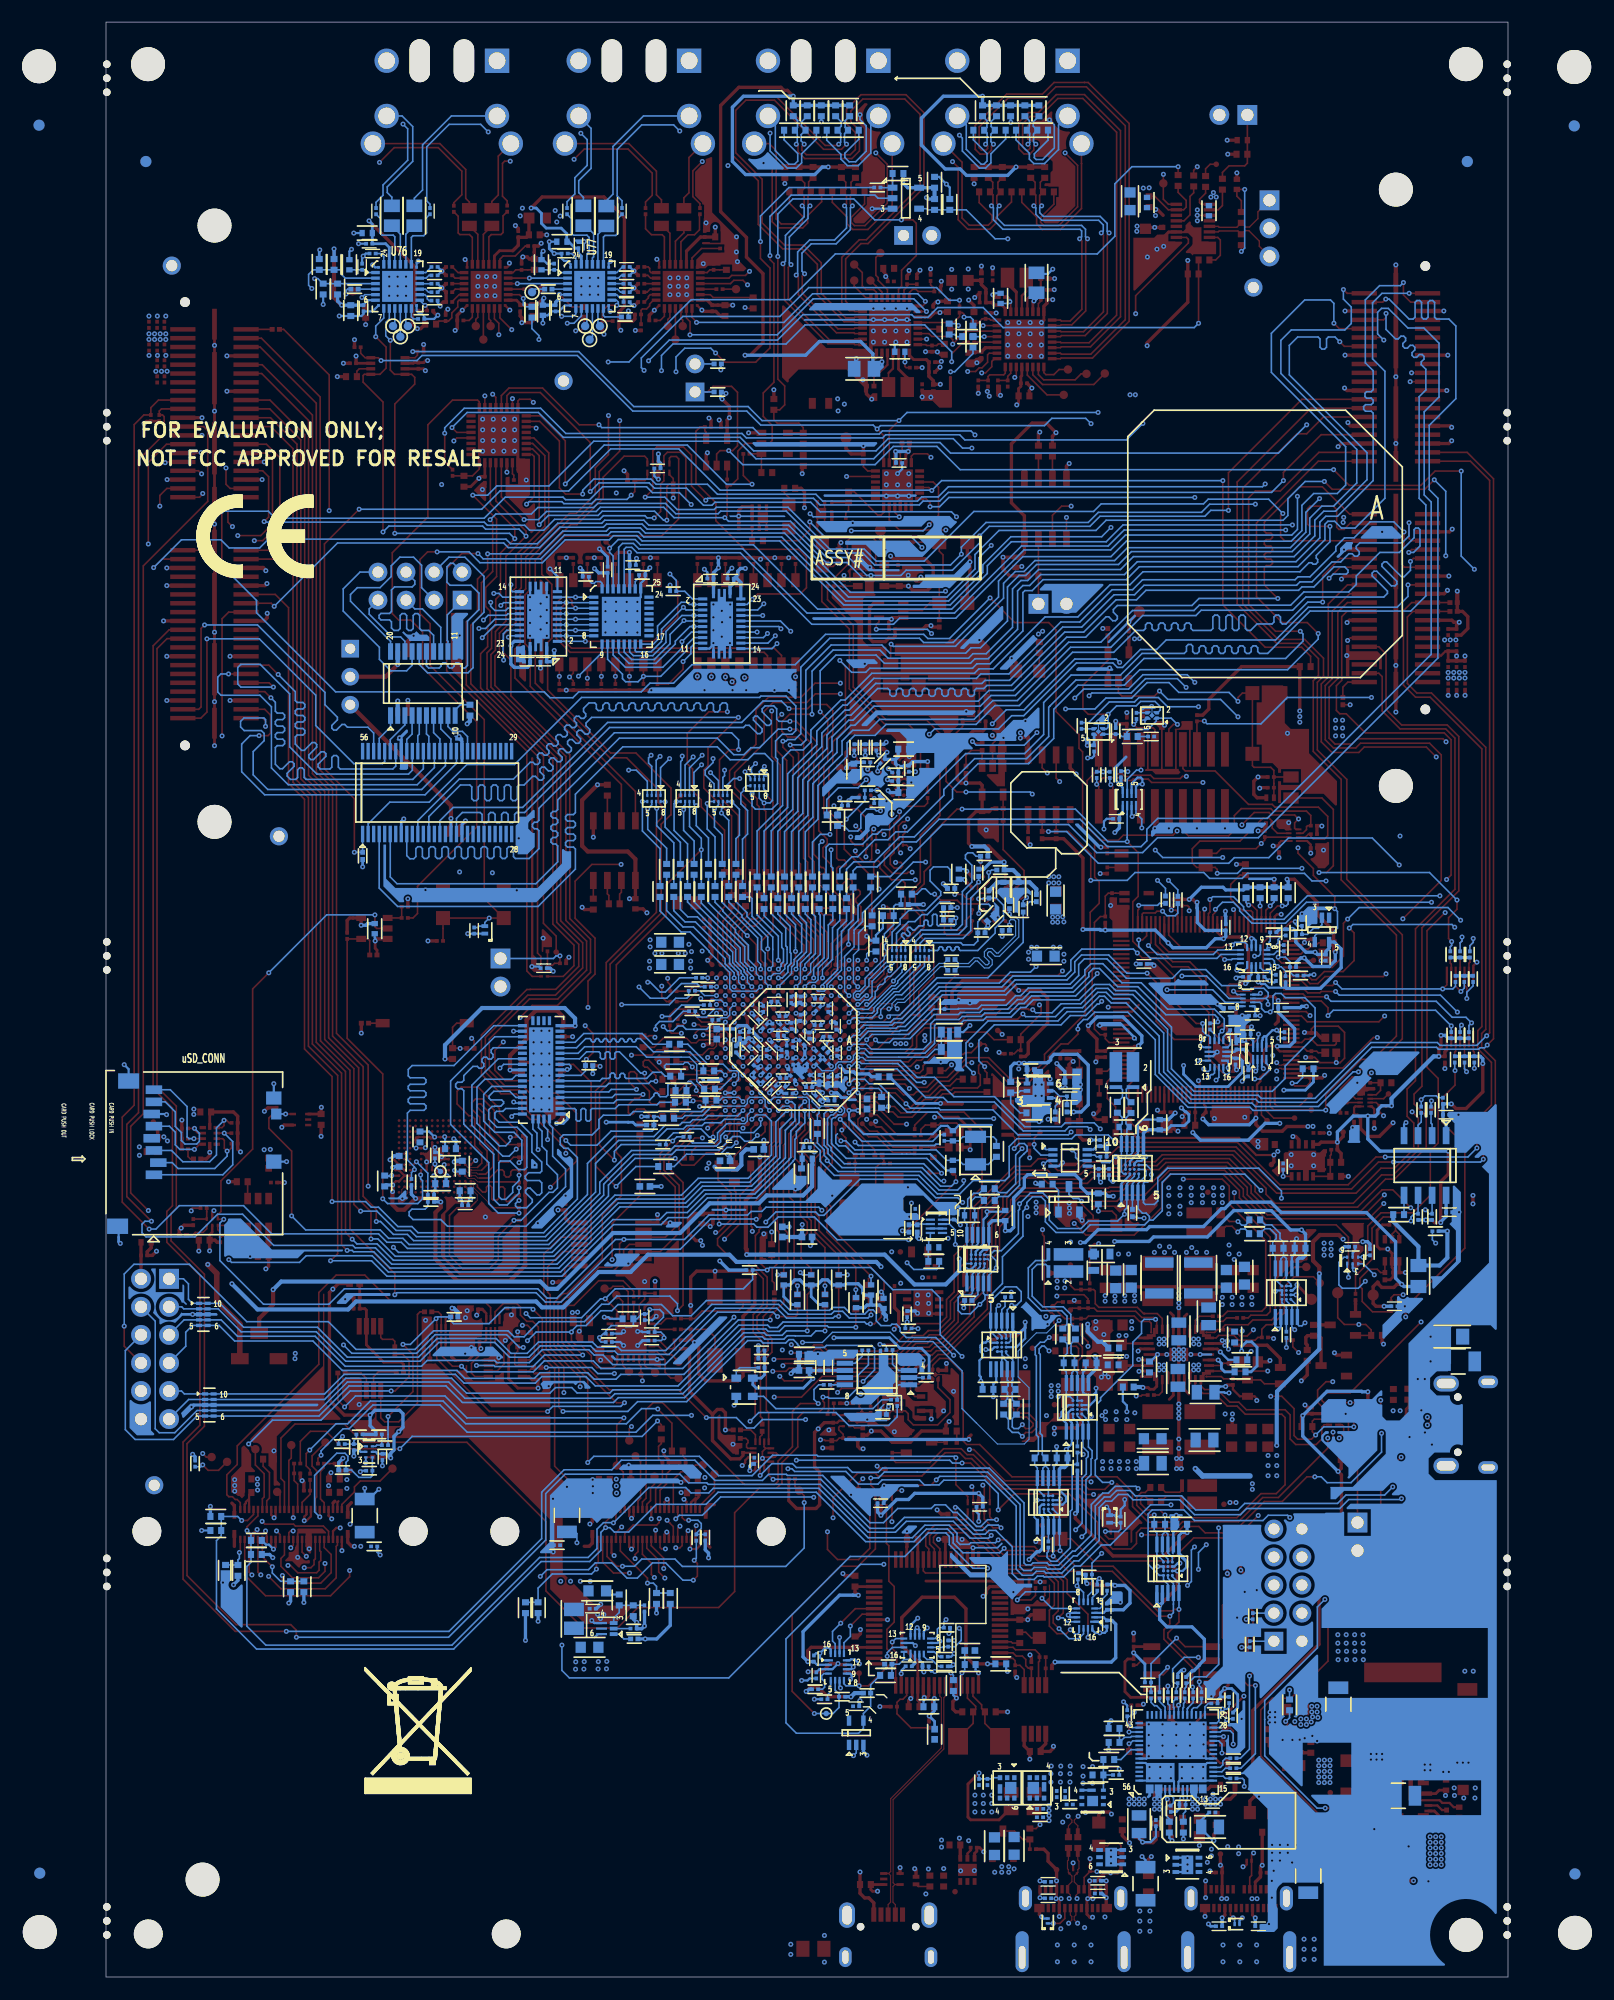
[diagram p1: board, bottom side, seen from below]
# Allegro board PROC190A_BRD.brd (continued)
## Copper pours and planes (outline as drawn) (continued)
DGND on L03_SIG1 (solid shape): 76.03,69.03 76.14,69.06 76.21,68.96 76.21,66.01 75.99,65.8 75.88,65.77 75.81,65.87 75.81,68.82
DGND on L03_SIG1 (solid shape): 109.44,76.11 109.47,76 109.37,75.94 105.33,75.94 105.03,76.23 105.01,76.35 105.1,76.41 109.15,76.41
DGND on L03_SIG1 (solid shape): 26.08,53.07 26.08,52.08 26.02,51.99 25.9,52.01 24.73,53.18 24.73,53.76 24.57,53.93 24.54,54.04 24.64,54.11 25.05,54.11
DGND on L03_SIG1 (solid shape): 40.08,94.34 40.14,94.44 40.25,94.41 41.33,93.33 41.33,91.46 41.27,91.36 41.16,91.39 40.65,91.89 40.2,91.89 40.08,92.01
DGND on L03_SIG1 (solid shape): 42.54,81.59 42.6,81.68 42.71,81.66 42.88,81.5 42.88,78.57 42.81,78.47 42.7,78.49 42.16,79.04 42.16,80.83 42.54,81.21
DGND on L03_SIG1 (solid shape): 51.51,59.26 51.57,59.35 51.68,59.33 52.66,58.35 53.26,58.35 53.26,55.76 53.2,55.66 53.09,55.69 51.75,57.02 51.51,57.02
DGND on L03_SIG1 (solid shape): 110.1,41.67 110.12,41.56 110.02,41.5 110,41.5 108.91,42.59 108.43,42.59 108.43,42.99 108.41,43.1 108.5,43.16 108.61,43.16
DGND on L03_SIG1 (solid shape): 48.98,70.31 49,70.31 49.03,70.25 47.12,68.34 44.83,68.34 44.78,68.37 44.8,68.43 44.81,68.44 44.81,69.69 44.61,69.88 44.62,69.91 44.63,70.03 44.6,70.14 44.6,70.15 44.6,72.11 45.05,72.11 46.11,73.18
DGND on L03_SIG1 (solid shape): 80.07,38.95 80.07,38.23 79.22,38.23 79.21,38.24 78.95,38.24 78.75,38.08 78.67,38.03 78.59,38.06 78.53,38.12 79.51,39.1 79.92,39.1
DGND on L03_SIG1 (solid shape): 51.74,82.69 51.69,82.64 51.69,81.37 52.09,80.97 52.11,80.86 52.02,80.79 50.83,80.79 50.33,80.29 50.22,80.27 50.15,80.36 50.15,80.65 51.2,81.69 51.2,82.84 51.4,83.03
DGND on L03_SIG1 (solid shape): 105.25,47.36 105.28,47.29 105.26,47.22 105.17,47.05 105.17,46.86 105.15,46.77 105.07,46.73 104.85,46.73 103.64,47.94 103.62,47.96 103.65,48.05 104.56,48.05
DGND on L03_SIG1 (solid shape): 105.73,39.32 105.99,39.32 105.99,38.37 105.59,37.97 105.59,37.92 105.53,37.83 105.42,37.85 105.28,37.99 105.28,39.27 105.29,39.31 105.33,39.33 105.45,39.36 105.55,39.43 105.59,39.47
DGND on L03_SIG1 (solid shape): 26.24,85.39 26.31,85.36 27.13,84.54 27.25,84.54 27.35,84.47 27.33,84.36 26.33,83.36 25.8,83.89 25.8,85.17 25.83,85.24 25.9,85.27 26.04,85.29 26.17,85.37
DGND on L03_SIG1 (solid shape): 55.43,41.28 55.43,41.26 55.48,41.03 55.66,40.87 55.66,40.87 56.09,40.44 57.23,40.44 57.32,40.38 57.3,40.27 52.06,35.03 51.95,35.01 51.89,35.1 51.89,38.45 54.79,41.35 55.36,41.35
DGND on L03_SIG1 (solid shape): 35.65,18.79 35.75,18.77 36,18.52 36,13.11 35.93,13.04 35.87,13.03 35.84,13.08 35.84,17.96 32.85,17.96 32.88,18.08 32.95,18.12 35,18.12 35.36,18.47 35.37,18.47 35.5,18.57 35.58,18.72
DGND on L03_SIG1 (solid shape): 24,65.05 24.05,65.13 24.15,65.13 24.24,65.09 24.33,65.08 24.39,65.04 24.42,64.97 24.47,64.77 24.63,64.63 24.68,64.56 24.65,64.47 24.21,64.03 24.21,58.51 24.11,58.41 24,58.41
DGND on L03_SIG1 (solid shape): 44.43,48.29 44.54,48.31 44.61,48.22 44.61,48.15 42.3,45.84 42.3,43.32 42.29,43.31 41.82,42.84 40.39,42.84 39.68,42.13 39.6,42.1 39.52,42.15 39.38,42.29 39.19,42.34 39.12,42.37 39.09,42.44 39.09,46.63 38.83,46.88 38.83,46.97 43.12,46.97
DGND on L03_SIG1 (solid shape): 37.2,90.34 37.31,90.37 37.37,90.27 37.37,89.4 36.66,88.69 36.65,88.69 36.43,88.39 36.58,88.04 36.62,87.96 36.59,87.88 36.03,87.33 35.92,87.31 35.86,87.4 35.86,89.01
DGND on L03_SIG1 (solid shape): 51.79,62.84 51.85,62.93 51.96,62.91 52.91,61.96 53.52,61.96 55.36,60.11 55.36,59.99 54.8,59.99 54.49,59.69 54.47,59.69 54.16,59.58 54.05,59.27 54.05,59.25 53.78,58.98 53.74,58.96 53.71,58.98 53.52,59.07 53.3,59.06 53.29,59.05 52.95,59.05 51.79,60.22
DGND on L03_SIG1 (solid shape): 113.3,41.2 113.35,41.21 113.39,41.16 113.39,39.87 113.31,39.79 112.36,39.79 112.33,39.85 112.34,39.86 112.34,39.92 112.38,39.99 112.46,40.01 112.84,40.14 112.9,40.53 112.9,40.54 112.9,40.87 112.94,40.88 113.1,40.96 113.21,41.1 113.21,41.11
DGND on L03_SIG1 (solid shape): 78.41,63.13 78.41,62.43 77.96,61.97 77.96,60.9 77.92,60.82 77.83,60.8 77.37,60.43 77.83,60.06 77.92,60.04 77.96,59.96 77.96,59.89 77.48,59.4 77.42,59.39 77.39,59.44 77.39,59.48 77.06,59.81 77.06,61.68 78.13,62.75 78.13,63.2 78.23,63.31
DGND on L03_SIG1 (solid shape): 85.14,74.04 85.2,74.14 85.31,74.11 85.68,73.74 85.68,70.64 86.26,70.06 86.26,69.91 86.23,69.83 86.14,69.82 85.67,69.44 86.14,69.07 86.23,69.05 86.26,68.97 86.26,68.1 86.2,68 86.09,68.02 85.14,68.98
DGND on L03_SIG1 (solid shape): 38.15,59.69 40.29,59.69 40.32,59.69 40.33,59.67 40.34,59.65 40.32,59.59 38.61,57.89 35.59,57.89 35.59,57.95 35.6,57.99 36.14,58.53 36.14,59.11 37.69,59.11 37.7,59.05 37.71,59 37.73,58.94 37.76,58.9 37.79,58.85 37.83,58.81 37.88,58.78 37.93,58.75 37.98,58.74 38.03,58.73 38.09,58.72 38.14,58.73 38.2,58.74 38.25,58.77 38.3,58.8 38.34,58.83 38.38,58.87 38.41,58.92 38.43,58.97 38.45,59.02 38.46,59.08 38.46,59.13 38.45,59.19 38.43,59.24 38.41,59.29 38.38,59.34 38.34,59.38 38.3,59.42 38.25,59.45 38.2,59.47 38.14,59.48 38.09,59.49 38.03,59.49 37.98,59.47 37.93,59.46 37.88,59.43 37.83,59.4 37.79,59.36 37.76,59.32 37.73,59.27 37.71,59.22 37.7,59.16 37.69,59.11 36.14,59.11 36.14,60.1 37.74,60.1
DGND on L03_SIG1 (solid shape): 32.34,93.09 32.5,93.02 32.67,93.02 32.76,93 32.8,92.92 32.8,91.36 32.77,91.29 32.7,91.26 32.31,90.88 32.7,90.5 32.77,90.47 32.8,90.4 32.8,88.47 32.51,88.17 32.51,83.96 32.44,83.86 32.33,83.88 31.97,84.24 31.97,92.79 32.3,93.12
DGND on L03_SIG1 (solid shape): 108.11,39.48 108.22,39.4 108.36,39.38 108.53,39.38 108.6,39.35 108.63,39.29 108.95,38.97 109.06,38.89 109.19,38.87 109.59,38.87 109.82,39.1 109.88,39.11 109.91,39.06 109.91,39.01 109.91,39 109.9,38.73 110.08,38.52 110.14,38.45 110.11,38.36 109.58,37.84 109.31,37.84 109.23,37.88 109.21,37.97 109.11,38.36 108.71,38.44 108.7,38.44 107.79,38.44 107.79,39.31 107.77,39.33 107.82,39.38 107.83,39.38 107.94,39.41 108.03,39.48 108.07,39.52
DGND on L03_SIG1 (solid shape): 49.76,69.91 49.84,69.88 49.96,69.76 49.96,68.64 49.91,68.55 49.82,68.55 49.64,68.59 49.46,68.57 49.45,68.57 49.35,68.57 47.83,67.04 39.8,67.04 39.8,68.11 39.67,68.24 39.67,68.26 39.65,68.37 39.58,68.47 39.56,68.54 39.59,68.61 39.83,68.84 41.26,67.41 41.88,67.41 42.16,67.28 42.45,67.41 43.78,67.41 44.01,67.64 45.06,67.64 45.13,67.61 45.16,67.54 45.54,67.18 45.92,67.54 45.95,67.61 46.02,67.64 47.41,67.64 49.55,69.78 49.63,69.82 49.69,69.88
DGND on L03_SIG1 (solid shape): 57.6,69.99 55.35,67.74 55.27,67.71 55.19,67.76 54.59,67.83 54.67,67.24 54.72,67.16 54.69,67.08 54.61,66.99 54.57,67.03 54.42,67.12 54.24,67.13 54.16,67.15 54.12,67.23 54.12,69.7 54.16,69.71 54.41,70.17 53.96,70.45 53.88,70.47 53.84,70.55 53.84,74.77 51.95,76.66 51.93,76.77 52.02,76.83 57.6,76.83
DGND on L03_SIG1 (solid shape): 35.96,54.54 36.02,54.63 36.13,54.61 36.6,54.14 36.6,52.69 36.25,52.34 36.25,50.35 36.97,49.63 38.12,49.63 38.21,49.57 38.19,49.46 36.99,48.26 36.99,47.12 36.95,47.04 36.86,47.02 36.62,47.03 36.42,46.9 36.34,46.86 35.96,47.05 35.58,46.86 35.2,47.05 34.82,46.86 34.44,47.05 34.06,46.86 33.98,46.9 33.85,47 33.7,47.05 33.63,47.08 33.6,47.15 33.6,51.43 35.96,53.78
DGND on L03_SIG1 (solid shape): 24.83,82.7 24.94,82.72 25,82.63 25,82.47 25,82.46 25.04,82.1 25.37,81.94 25.46,81.88 25.44,81.77 23.07,79.39 23.07,78.23 23.03,78.14 22.94,78.13 22.46,77.76 22.94,77.39 23.03,77.38 23.07,77.3 23.07,70.81 22.54,70.28 22.43,70.26 22.37,70.36 22.37,70.72 22.52,70.87 22.53,70.87 22.73,71.37 22.22,71.57 22.13,71.58 22.08,71.66 22.08,82.29 22.37,82.58 23.16,82.58 23.17,82.54 23.22,82.43 23.31,82.34 23.35,82.26 23.32,82.18 23.25,82.12 23.21,82.16 23.21,82.17 22.62,82.31 22.64,81.71 22.68,81.64 22.65,81.56 22.73,80.98 23.29,81.15 23.29,81.16
DGND on L03_SIG1 (solid shape): 19.24,43.19 19.35,43.21 19.41,43.12 19.41,41.75 19.41,41.75 19.76,41.22 20.12,41.75 20.11,41.75 20.11,42.49 20.17,42.59 20.29,42.57 20.99,41.86 21.02,41.76 20.94,41.69 20.36,39.78 22.31,40.21 23.81,40.21 24.69,39.33 24.72,39.21 24.62,39.15 21.84,39.15 21.74,39.05 21.71,39.07 20.34,38.78 20.24,37.39 20.25,37.28 20.16,37.23 19.96,37.23 19.7,37.49 19.71,37.52 19.28,39.01 17.76,38.74 17.65,38.7 17.58,38.8 17.58,41.53
DGND on L03_SIG1 (solid shape): 14.63,62.43 14.66,62.48 14.71,62.46 14.72,62.46 17.58,62.46 17.58,62.15 16.65,61.21 16.65,50.67 17.61,49.71 17.61,49.55 17.58,49.47 17.49,49.45 17.04,49.07 17.49,48.7 17.58,48.68 17.61,48.6 17.61,48.34 17.15,47.88 16.15,47.88 16.06,47.94 16.08,48.05 16.47,48.44 16.48,48.44 16.7,48.89 16.28,49.17 16.23,49.17 16.23,49.33 16.23,49.39 16.23,53.75 16.23,53.76 15.88,54.28 15.52,53.76 15.52,53.75 15.52,51.52 15.46,51.43 15.35,51.45 14.66,52.15 14.65,52.15 14.04,52.27 14.15,51.65 14.16,51.65 14.94,50.87 14.94,48.94 14.92,48.87 14.91,48.8 14.85,48.7 14.74,48.73 14.14,49.32 14.11,49.41 14.16,49.48 14.32,49.97 13.85,50.17 13.75,50.18 13.71,50.27 13.71,54.52 14.63,55.43
DGND on L03_SIG1 (solid shape): outline of 238 points within 65.98,41.78 71.79,54.94
DGND on L03_SIG1 (solid shape): outline of 243 points within 7.03,47.88 14.45,61.75
DGND on L03_SIG1 (solid shape): outline of 273 points within 36.5,16.01 56.72,38.02
DGND on L03_SIG1 (solid shape): outline of 380 points within 1.02,5.7 18.19,49.84
DGND on L03_SIG1 (solid shape): outline of 377 points within 90.42,76.59 120,86.52
DGND on L03_SIG1 (solid shape): outline of 396 points within 38.4,47.67 44.07,58.96
DGND on L03_SIG1 (solid shape): outline of 418 points within 17.6,58.13 21.38,81.96
DGND on L03_SIG1 (solid shape): outline of 422 points within 24.91,58.91 37.43,68.86
DGND on L03_SIG1 (solid shape): outline of 523 points within 23.52,46.06 32.66,60.1
DGND on TOP: 83.16,45.41 82.09,45.41 82.09,43.59 83.16,43.59
DGND on TOP: 26.37,50.16 29.24,50.16 29.64,50.57 30.02,50.57 30.43,50.16 33.1,50.16 33.53,50.6 33.53,51.08 34.06,51.61 36.57,51.61 37.01,51.17 37.01,49.35 36.78,49.12 21.23,49.12 21.13,49.23 21.13,50.55 23.95,50.55 24.71,51.31 25.81,51.31 25.98,51.13 25.98,50.55
DGND on TOP: 50.3,11.53 51.58,11.53 51.58,12.63 50.3,12.63
DGND on TOP: 124.38,74.06 124.38,76.39 123.09,76.39 123.09,74.06
DGND on TOP: 54.22,73.99 54.22,68.86 60.38,68.86 60.38,73.99
DGND on TOP: 119.45,77.83 119.45,78.84 118.15,78.84 118.15,77.83
DGND on TOP: 74.8,45.31 74.09,45.31 74.09,43.52 74.23,43.52 74.42,43.33 74.42,43 74.5,42.93 75.08,42.93 75.08,43.45 75.16,43.52 75.16,44.96
DGND on TOP: 9.93,17.53 9.75,17.7 9.75,18.92 11.4,20.57 13.16,20.57 14,21.41 14,23.55 14.38,23.93 16.26,23.93 16.26,21.74 15.25,20.74 15.25,19.01 15.16,18.92 13.74,18.92 12.83,18.01 11.28,18.01 10.79,17.53
DGND on TOP: 39.45,70.28 39.45,68.88 41.07,68.88 41.07,70.28
DGND on TOP: 63.2,3.76 63.2,1.7 65.74,1.7 65.74,3.76
DGND on TOP: 41.78,98.04 40.11,98.04 40.11,100.08 41.78,100.08
DGND on TOP: 20.62,23.42 20.62,22.74 20.58,22.71 20.58,22.06 20.36,21.84 18.1,21.84 17.83,22.12 17.01,22.12 17.01,21.13 17.08,21.05 19.26,21.05 19.39,20.92 21.03,20.92 21.08,20.97 21.08,21.89 21.34,22.15 21.62,22.15 21.7,22.23 22.02,22.23 22.02,24.03 21.24,24.81 19.71,24.81 19.62,24.72 19.62,23.69 19.77,23.54 20.5,23.54
DGND on TOP: 50.78,10.08 50.78,9.04 50.96,8.86 54.17,8.86 54.38,8.8 54.72,9.14 55.37,9.14 55.42,9.18 55.42,10.07 55.28,10.21 50.9,10.21
DGND on TOP: 120.52,143.32 120.5,143.35 118.37,143.35 117.78,143.94 117.78,149.92 118.48,150.63 123.89,150.63 124.19,150.33 124.19,143.67 123.84,143.32
DGND on TOP: 115.58,45.41 114.52,45.41 114.52,43.52 115.01,43.52 115.23,43.74 115.58,43.74
DGND on TOP: 56.95,155.07 56.31,155.07 56.21,154.97 56.21,154.18 56.01,153.97 56.01,153.34 56.03,153.31 56.41,153.31 56.64,153.54 56.64,153.95 56.97,154.28 56.97,155.04
DGND on TOP: 55.65,64.62 52.43,64.62 52.3,64.49 52.3,62.51 52.1,62.31 52.1,59.79 53.85,59.79 53.87,59.82 53.87,62.23 54,62.36 55.55,62.36 55.73,62.53 55.73,64.54
DGND on TOP: 36.07,55.96 36.07,53.06 37.01,53.06 37.01,55.96
DGND on TOP: 31.67,157.73 31.11,157.73 30.96,157.58 30.96,156.18 31.6,155.55 32.97,155.55 33.53,156.11 33.53,157.02 33.4,157.15 32.26,157.15
DGND on TOP: 30.4,57.78 29.39,57.78 28.93,57.33 28.93,56.72 28.8,56.59 26.7,56.59 26.57,56.46 26.57,56.24 26.67,56.13 28.63,56.13 28.93,55.83 28.93,55.6 29.06,55.47 29.31,55.47 29.64,55.14 29.64,54.36 29.67,54.33 29.92,54.33 30.02,54.43 30.02,55.37 30.23,55.58 30.68,55.58 30.84,55.73 30.84,55.96 31.04,56.16 32.99,56.16 33.07,56.24 33.07,56.44 32.92,56.59 30.94,56.59 30.68,56.85 30.68,57.51
DGND on TOP: 15.92,77.25 15.92,76.15 17.22,76.15 17.22,77.25
DGND on TOP: 10.36,55.27 7.21,55.27 7.21,52.97 10.64,52.97 10.82,53.14 10.82,54.81
DGND on TOP: 5.31,17.48 4.88,17.91 3.45,17.91 3.4,17.96 2.34,17.96 1.55,18.75 1.55,24.21 4.62,24.21 4.62,21.16 5.64,20.14 7.47,20.14 7.87,19.74 7.87,17.48
DGND on TOP: 36.78,63.07 36.98,62.87 36.98,61.06 36.88,60.96 33.5,60.96 33.45,61.01 33.45,62.38 33.35,62.48 30.33,62.48 30,62.15 29.62,62.15 29.29,62.48 26.47,62.48 26.11,62.13 26.11,60.66 22.96,60.66 22.58,61.04 22.58,63.07
DGND on TOP: 21.77,75.84 21.77,74.93 22.71,74.93 22.94,75.16 22.94,75.9 21.82,75.9
DGND on TOP: 107.09,45.41 107.34,45.41 106.85,45.9 106.38,45.9 106.38,45.25 106.52,45.11 106.52,43.52 107.09,43.52
DGND on BOTTOM: 83.38,30.45 83.38,27.61 85.02,27.61 85.02,30.45
DGND on BOTTOM: 38.81,19.31 37.46,19.31 37.22,19.07 37.22,16.83 37.38,16.68 38.75,16.68 39.03,16.96 39.03,19.08
DGND on BOTTOM: 15.95,22.17 16.31,22.53 16.31,24.36 16,24.66 11.13,24.66 10.52,24.05 10.52,15.42 13.39,15.42 13.39,21.13 14.43,22.17
DGND on BOTTOM: 45.72,72.49 51.87,72.49 54,74.63 59.64,74.63 60.93,75.92 60.93,77.65 59.41,77.65 58.22,76.45 52.25,76.45 51.41,77.29 46.71,77.29 45.57,76.15 45.57,72.64
DGND on BOTTOM: 58.44,144.78 58.66,144.56 59.53,144.56 59.88,144.92 59.88,146.47 59.6,146.76 58.65,146.76 58.44,146.56
DGND on BOTTOM: 26.16,161.85 26.16,160.12 27.66,160.12 27.66,161.85
DGND on BOTTOM: 36.7,55.78 36.02,55.78 35.94,55.7 35.94,54.08 36.07,53.95 37.21,53.95 37.21,54.43 36.93,54.71 36.83,54.71 36.7,54.84
DGND on BOTTOM: 27.87,45.75 27.87,49.92 27.7,50.08 23.62,50.08 23.22,50.49 23.22,54.03 21.95,55.3 21.95,59.05 22.66,59.77 22.66,62.46 23.06,62.87 23.15,62.87 23.15,63.03 23.39,63.27 24.46,63.27 24.84,62.89 34.73,62.89 34.86,63.02 36.4,63.02 36.53,62.89 36.53,60.86 36.02,60.35 25.91,60.35 25.37,59.82 25.37,58.37 24.59,57.58 24.59,56.82 24.79,56.62 28.78,56.62 29.08,56.92 29.08,57.94 29.24,58.09 30.25,58.09 30.45,57.89 30.45,56.92 30.43,56.9 30.56,56.77 32.72,56.77 32.94,56.54 32.94,55.6 32.79,55.45 32.31,55.45 32.26,55.5 32.26,55.7 32.05,55.91 30.78,55.91 30.56,55.68 30.56,54.69 30.4,54.53 29.31,54.53 29.21,54.64 29.21,55.45 29.24,55.47 28.88,55.83 27.71,55.83 27.05,55.17 27.05,52.2 27.28,51.97 36.64,51.97 36.74,51.87 36.74,51.28 37.01,51.01 37.01,50.32 36.93,50.24 31.97,50.24 31.86,50.13 31.86,45.75
DGND on BOTTOM: 41.83,99.97 40.74,99.97 40.44,99.67 40.44,97.94 41.83,97.94
DGND on BOTTOM: 78.56,94.39 78.56,91.08 76.2,91.08 76.2,94.39
DGND on BOTTOM: 44.1,11.7 44.1,8.87 47.43,8.87 47.43,11.7
DGND on BOTTOM: 39.57,81.28 38.79,81.28 38.51,81 38.51,79.88 38.79,79.6 39.52,79.6 39.57,79.65
DGND on BOTTOM: 6.69,58.69 5.25,58.69 5.25,55.06 5.42,54.89 6.99,54.89 7.26,55.16 7.26,58.12
DGND on BOTTOM: 35.18,162.26 32.28,162.26 32.28,160.96 35.2,160.96 35.2,162.23
DGND on BOTTOM: 40.16,91.52 41.43,91.52 41.43,93.6 40.26,93.6 39.98,93.32 39.98,91.69
DGND on BOTTOM: 82.27,35.46 80.51,35.46 80.08,35.03 80.08,34.39 80.2,34.27 81.12,34.27 81.31,34.08 81.31,33.11 81.62,32.81 81.62,31.98 81.68,31.92 82.99,31.92 83.25,32.18 83.25,32.4 82.68,32.97 82.68,33.66 82.27,34.06
DGND on BOTTOM: 21.62,10.24 21.62,12.77 17.95,12.77 17,11.82 17,10.01 17.18,9.83 21.2,9.83
DGND on BOTTOM: 41.89,153.77 43.47,153.77 43.67,153.96 43.67,155.22 43.31,155.57 42.14,155.57 41.89,155.32
DGND on L02_GND1: 1.02,1.02 1.02,175.98 125.98,175.98 125.98,1.02 ; 4 cut-outs
DGND on L05_GND2: 1.02,1.02 1.02,175.98 125.98,175.98 125.98,1.02 ; 3 cut-outs
VBAT_IN on TOP: 53.88,158.56 53.88,155.96 55.32,154.53 55.32,153.29 55.41,153.2 55.41,153.2 55.62,153 55.62,151.66 55.84,151.66 55.86,151.68 55.86,153.15 55.81,153.19 55.81,154.03 55.95,154.17 55.95,158.45 55.83,158.56
VBUS_TYPEC1 on TOP: 22.99,5.87 22.99,6.75 22.91,6.83 22.62,6.83 22.5,6.94 22.5,7.26 22.6,7.35 22.75,7.35 22.75,8.27 23.04,8.27 23.04,7.35 23.31,7.35 23.42,7.25 23.42,6.95 23.3,6.84 23.3,5.87
VBUS_TYPEC1 on TOP: 25.8,14.48 25.8,16.36 26.16,16.36 26.59,16.79 26.92,16.79 27.35,16.36 27.62,16.36 27.62,15.54 27.1,15.03 27.1,14.48
VBUS_TYPEC1 on TOP: 25.74,8.31 25.74,7.43 25.66,7.35 25.37,7.35 25.25,7.24 25.25,6.92 25.35,6.83 25.5,6.83 25.5,5.91 25.79,5.91 25.79,6.83 26.06,6.83 26.17,6.93 26.17,7.23 26.05,7.34 26.05,8.31
VBUS_TYPEC1 on BOTTOM: 22.07,5.11 22.07,15.09 23.58,16.59 26.42,16.59 26.79,16.96 26.79,17.36 27.98,17.36 27.98,16.56 27.67,16.25 27.67,15.42 26.8,15.42 26.7,15.32 26.7,14.25 26.59,14.25 26.59,12.09 28.3,12.09 28.3,9.02 26.59,7.32 26.59,5.11
VBUS_TYPEC1 on L04_PWR1: 27.71,16.84 22.05,16.84 22.05,8.66 22.48,8.23 22.48,4.8 26.59,4.8 26.59,8.1 27.71,9.22
VBUS_TYPEC2 on TOP: 31.32,13.64 31.32,16.19 31.46,16.33 32.1,16.33 32.23,16.2 32.23,13.64
VBUS_TYPEC2 on TOP: 40.74,8.31 40.74,7.43 40.66,7.35 40.37,7.35 40.25,7.24 40.25,6.92 40.35,6.83 40.5,6.83 40.5,5.91 40.79,5.91 40.79,6.83 41.06,6.83 41.17,6.93 41.17,7.23 41.05,7.34 41.05,8.31
VBUS_TYPEC2 on TOP: 37.99,5.87 37.99,6.77 37.93,6.83 37.53,6.83 37.38,6.97 37.38,7.21 37.53,7.35 37.75,7.35 37.75,8.27 38.04,8.27 38.04,7.35 38.18,7.35 38.3,7.23 38.3,5.87
VBUS_TYPEC2 on BOTTOM: 36.17,5.2 36.17,8.51 35.84,8.84 35.84,12.55 34.55,13.83 33.93,13.83 33.7,14.06 31.66,14.06 31.26,14.47 31.26,16.51 31.31,16.56 31.31,17.39 31.97,17.39 31.97,16.46 32.25,16.18 32.25,15.38 32.55,15.08 32.91,15.08 32.91,15.09 35.09,15.09 35.96,14.21 37.34,14.21 37.85,13.7 43.38,13.7 43.99,14.32 43.99,15.07 44.3,15.38 45.63,15.38 45.75,15.49 45.75,17.43 45.88,17.56 48.47,17.56 48.47,13.46 47.12,12.11 42.39,12.11 41.56,11.28 41.56,5.87 40.88,5.2
VBUS_TYPEC2 on L04_PWR1: 31.04,16.71 31.04,11.99 33.91,9.12 35.69,9.12 36.17,8.64 36.17,4.93 36.65,4.45 41.02,4.45 41.76,5.18 41.76,11.61 42.72,12.57 49.23,12.57 49.23,16.71
VCC1V8_SYS on TOP: 34.57,121.54 33.27,121.54 33.1,121.36 33.1,119.46 33.32,119.23 34.62,119.23 34.8,119.41 34.8,121.31
VCC1V8_SYS on TOP: 4.42,121.64 8.4,121.64 8.43,121.61 8.43,120.24 6.15,120.24 5.89,120.5 4.41,120.5 4.41,121.63
VCC1V8_SYS on TOP: 56.03,112.19 60.25,112.19 60.68,111.76 60.68,109.96 60.91,109.73 60.91,109.17 59.33,109.17 58.88,108.71 58.7,108.71 58.42,108.99 58.42,109.17 59.54,110.29 59.54,110.72 59.39,110.87 56.82,110.87 56.49,110.54 56.11,110.54 55.75,110.9 55.75,111.91
VCC1V8_SYS on TOP: 40.82,138.33 40.82,139.4 40.64,139.57 40.64,140.11 41.45,140.92 43.48,140.92 46.2,138.2 46.2,126.87 45.49,126.16 43.38,126.16 43.15,126.39 43.15,127.1 43.26,127.2 43.92,127.2 44.02,127.1 45.09,127.1 45.49,127.51 45.49,127.99 45.26,128.22 43.97,128.22 43.38,128.8 43.38,132.56 44.6,133.78 44.6,138.66 42.95,140.31 42.06,140.31 41.83,140.08 41.83,138.56 41.86,138.53 41.66,138.33
VCC1V8_SYS on TOP: 84.35,58.85 84.96,58.85 84.96,60.43 84.23,60.43 84.07,60.27 84.07,59.89 84.35,59.61
VCC1V8_SYS on TOP: 56.11,128.96 55.52,128.96 55.19,128.63 52.63,128.63 51.79,127.79 51.79,126.01 52.68,125.12 56.79,125.12 57.15,125.48 57.15,126.14 57,126.29 54.18,126.29 53.82,125.93 52.81,125.93 52.63,126.11 52.63,127.61 53.24,128.22 56.26,128.22 56.26,128.8
VCC1V8_SYS on TOP: 61.95,141.39 61.95,143.5 60.2,143.5 59.41,142.71 59.41,141.39
VCC1V8_SYS on TOP: 35.51,59.44 35.51,58.78 35.33,58.6 34.37,58.6 33.48,57.71 32.51,57.71 32.45,57.77 32.45,57.99 32.47,58.01 33.15,58.01 33.22,58.09 33.22,58.5 33.86,59.14 33.86,59.46 34.04,59.64 35.31,59.64
VCC1V8_SYS on TOP: 51.21,95.86 50.9,96.16 50.9,96.7 51.18,96.98 52.07,96.98 52.37,97.28 52.37,98.17 52.01,98.54 49.06,98.54 48.84,98.32 48.51,98.32 48.23,98.6 48.23,98.88 49.43,100.08 49.43,100.99 48.84,101.57 46.94,101.57 45.9,100.53 45.47,100.53 45.16,100.84 45.16,101.19 46.74,102.77 47.52,102.77 48.36,103.61 48.36,104.88 48.01,105.23 46.46,105.23 46.18,105.51 46.18,106.17 46.48,106.48 46.48,107.59 47.65,108.76 48.16,108.76 48.59,109.19 49.53,109.19 49.61,109.27 49.61,111.25 48.59,112.27 47.62,112.27 47.04,112.85 47.04,113.89 47.12,113.97 47.47,113.97 47.62,113.82 47.62,113.56 47.96,113.23 48.9,113.23 50.44,111.68 50.44,108.31 49.86,107.72 48.74,107.72 48.34,107.31 48.34,106.12 49.33,105.13 49.33,102.95 52.22,100.05 52.22,99.8 52.5,99.52 52.5,98.65 53.16,97.99 53.16,96.95 52.07,95.86
VCC1V8_SYS on TOP: 37.03,75.92 36.35,75.92 36.09,75.67 36.09,75.08 37.13,74.04 40.74,74.04 41.1,73.69 43.76,73.69 44.07,73.99 44.07,74.22 43.79,74.5 43.79,74.57 43.64,74.73 43.64,75.03 43.56,75.11 42.82,75.11 41.99,75.95 39.37,75.95 38.81,75.39 37.57,75.39
VCC1V8_SYS on TOP: 122.58,144.78 118.6,144.78 118.48,144.89 118.48,146.15 118.56,146.23 121,146.23 121.23,146 122.53,146 122.59,145.94 122.59,144.79
VCC1V8_SYS on TOP: 29.09,48.54 29.09,43.92 21.38,43.92 20.57,44.72 20.57,48.2 20.91,48.54
VCC1V8_SYS on BOTTOM: 25.91,83.9 25.2,83.9 24.84,84.25 23.65,84.25 23.5,84.1 23.5,83.72 23.39,83.62 23.06,83.62 22.94,83.49 22.94,82.35 23.39,81.89 23.6,81.89 23.8,82.09 23.8,83.26 24.16,83.62 25.91,83.62
VCC1V8_SYS on BOTTOM: 77.83,77.5 78.94,77.5 79.1,77.65 81.76,77.65 81.94,77.47 81.94,77.32 81.61,76.99 79.04,76.99 78.87,76.81 77.8,76.81 77.77,76.83 77.77,77.44
VCC1V8_SYS on BOTTOM: 100.69,71.93 102.37,71.93 102.37,70.89 100.69,70.89 99.85,71.73 99.85,73.38 100.15,73.69 101.12,73.69 101.37,73.43 101.37,73.25 101.22,73.1 100.76,73.1 100.53,72.87 100.53,72.09
VCC1V8_SYS on BOTTOM: 69.88,127.81 68.99,127.81 68.86,127.69 68.86,124.82 69.09,124.59 69.85,124.59 70.05,124.79 70.54,124.79 70.66,124.92 70.66,125.98 70.33,126.31 70.33,126.8 70.08,127.05 70.03,127.05 69.98,127.1 69.98,127.71
VCC1V8_SYS on BOTTOM: 52.98,68.45 51.89,68.45 51.89,69.24 53.09,70.43 54.43,70.43 54.46,70.4 54.46,69.55 54.38,69.47 53.41,69.47 52.98,69.04
VCC1V8_SYS on BOTTOM: 35.2,106.6 34.85,106.6 34.77,106.53 34.77,105.44 34.95,105.26 34.95,103.71 35.31,103.35 35.74,103.35 35.92,103.53 35.92,103.73 35.43,104.22 35.43,105.44 35.2,105.66
VCC1V8_SYS on BOTTOM: 59.23,112.04 56.82,112.04 56.44,112.42 55.24,112.42 54.79,111.96 54.79,110.34 54.53,110.08 53.87,110.08 53.44,110.52 52.27,110.52 52.27,109.78 53.9,109.78 54.25,109.42 54.56,109.42 54.79,109.19 54.79,106.98 54.91,106.86 56.13,106.86 56.5,107.23 56.5,107.53 56.26,107.77 55.55,107.77 55.5,107.82 55.5,109.4 56.08,109.98 56.39,109.98 56.72,110.31 56.72,111.07 56.97,111.33 59.39,111.33 59.46,111.4 59.46,111.81
VCC1V8_SYS on BOTTOM: 19.05,46.23 19.05,52.1 17.09,54.05 14.78,54.05 13.13,55.7 13.13,60.73 10.97,62.89 10.97,66.07 13,68.1 16.92,68.1 17.58,67.44 17.58,63.63 18.29,62.92 18.29,58.5 23.62,53.16 23.62,50.22 24.32,49.51 27.13,49.51 27.13,45.95 26.29,45.11 20.17,45.11 ; 1 cut-out
VCC1V8_SYS on BOTTOM: 47.27,42.42 47.27,43.54 47.78,44.04 54.91,44.04 56.44,42.52 56.77,42.52 56.87,42.62 56.87,43.05 57.02,43.21 57.38,43.21 57.4,43.18 57.4,41.73 57.15,41.48 56.67,41.48 55.22,42.93 53.9,42.93 53.52,43.31 48.21,43.31 47.9,43 47.9,42.42 47.88,42.39 47.29,42.39
VCC1V8_SYS on BOTTOM: 59.17,25.85 60.06,25.85 60.24,25.67 60.24,22.87 60.07,22.7 59.35,22.7 59.13,22.91 59.13,25.8
VCC1V8_SYS on BOTTOM: 38.79,75.16 37.72,75.16 37.44,75.44 36.68,75.44 36.42,75.69 36.2,75.69 36.04,75.54 36.04,74.17 36.14,74.07 36.58,74.07 36.63,74.12 36.63,74.75 36.73,74.85 37.41,74.85 37.57,74.7 38.73,74.7 38.84,74.8 38.84,75.11
VCC1V8_SYS on BOTTOM: 23.5,88.04 22.86,88.04 22.71,87.88 22.71,87.63 22.2,87.12 22.2,86.79 22.3,86.69 22.94,86.69 23.11,86.87 23.11,87.5 23.27,87.66 23.44,87.66 23.5,87.71
VCC1V8_SYS on BOTTOM: 21.16,95.12 19.35,95.12 19,94.77 19,93.75 18.29,93.04 16.92,93.04 16.61,93.34 16.61,94.06 16.46,94.21 15.44,94.21 14.81,93.57 14.81,91.41 16.92,89.31 21.64,89.31 22.1,89.76 22.71,89.76 23.01,90.07 23.01,91.87 22.91,91.97 22.73,91.97 22.63,91.87 22.63,91.14 22.33,90.83 22.33,90.37 22.12,90.17 22.02,90.17 21.67,89.81 20.6,89.81 20.52,89.89 20.52,90.22 20.45,90.3 20.04,90.3 19.89,90.14 19.89,89.92 19.81,89.84 17.14,89.84 15.39,91.59 15.39,92.91 15.75,93.27 15.8,93.27 16.18,92.89 16.18,92.51 16.33,92.35 17.4,92.35 17.65,92.61 18.59,92.61 19.51,93.52 19.51,94.44 19.66,94.59 20.62,94.59 20.83,94.39 21.23,94.39 21.23,95.05
VCC1V8_SYS on L03_SIG1: 12.7,66.29 12.7,67.21 13.11,67.61 13.11,91.62 12.17,92.56 12.17,103.86 14.12,105.82 14.12,114.15 14.25,114.27 17.6,114.27 17.93,113.94 17.93,101.47 16.68,100.22 16.68,95.99 18.09,94.57 18.09,93.84 18.21,93.73 18.21,88.09 17.78,87.66 17.78,86.23 18.21,85.8 18.21,70.13 17.42,69.34 17.42,63.65 17.25,63.47 15.14,63.47 14.86,63.75 14.86,64.14
VCC1V8_SYS on L03_SIG1: 36.75,75.74 36.27,75.74 35.92,75.39 35.92,74.93 37.57,73.28 37.57,71.65 37.19,71.27 37.19,67.01 37.39,66.8 37.39,62.43 39.01,60.81 39.47,60.81 39.78,61.11 39.78,61.49 38.79,62.48 38.79,67.69 38.33,68.15 38.33,68.78 38.86,69.32 38.86,73.63
VCC1V8_SYS on L03_SIG1: 94.03,70.03 101.37,70.03 101.63,70.28 101.63,74.78 101.37,75.03 94.03,75.03 93.78,74.78 93.78,70.28
VCC1V8_SYS on L03_SIG1: 34.95,59.82 33.96,59.82 33.66,59.51 33.66,58.75 32.41,57.51 32.41,53.98 31.24,52.81 31.24,45.26 30.89,44.91 29.79,44.91 28.42,46.28 28.14,46.28 27.97,46.1 27.97,45.52 30.35,43.13 31.88,43.13 32.59,43.84 32.59,52.02 33.83,53.26 33.83,55.98 33.3,56.52 33.3,57.12 35.13,58.95 35.13,59.64
VCC1V8_SYS on L03_SIG1: 15.11,132.44 4.57,132.44 3.1,130.96 3.1,127.99 3.51,127.58 3.51,121.01 3.73,120.78 5.87,120.78 6.1,121.01 6.1,123.67 5.05,124.71 5.05,126.49 4.75,126.8 4.75,129.82 6.22,131.29 15.15,131.29 15.2,131.34 15.2,132.35
VCC1V8_SYS on L03_SIG1: 34.52,143.79 33.73,143.79 32.79,142.85 32.79,141.53 33.4,140.92 33.4,140.49 32.82,139.9 32.82,121.21 33.2,120.83 34.14,120.83 35.18,121.87 35.18,143.13
VCC1V8_SYS on L03_SIG1: 23.27,90.47 22.5,90.47 22.28,90.25 22.28,89.61 22.5,89.38 22.5,87.5 21.72,86.72 21.72,84.43 22.56,83.59 24.03,83.59 24.41,83.97 24.41,84.68 24.13,84.96 23.37,84.96 23.11,85.22 23.11,87.71 23.62,88.21 23.62,90.12
VCC1V8_SYS on L03_SIG1: 44.78,90.45 44.07,89.74 44.07,89.08 45.57,87.58 45.57,84.71 44.98,84.12 44.98,81.94 44.63,81.58 44.63,76.17 43.66,75.21 43.66,74.98 43.05,74.37 43.05,74.12 44.04,73.13 44.63,73.13 45.72,74.22 45.72,80.49 45.97,80.75 45.97,83.16 47.22,84.4 47.22,88.62 46.51,89.33 46.51,93.78 47.88,95.15 47.88,97.23 46.02,99.09 46.02,101.19 45.73,101.49 44.18,101.49 43.97,101.27 43.97,97.97 44.78,97.16
VCC1V8_SYS on L03_SIG1: 23.19,108.08 22.23,108.08 21.79,107.65 21.79,104.19 20.73,103.12 20.73,102.21 20.93,102.01 21.49,102.01 23.01,103.53 23.01,106.3 23.32,106.6 23.32,107.95
VCC1V8_SYS on L03_SIG1: 51.33,56.01 50.85,56.01 50.62,55.78 50.62,55.19 52.43,53.39 52.43,51.16 52.07,50.8 52.07,50.27 52.88,49.45 52.88,44.22 54.74,42.37 55.78,42.37 56.67,41.48 57.07,41.48 57.33,41.73 57.33,42.19 56.13,43.38 55.24,43.38 54.28,44.35 54.28,53.06
VCC1V8_SYS on L04_PWR1: 1.02,1.02 1.02,175.98 125.98,175.98 125.98,1.02 ; 27 cut-outs
VCC1V8_SYS_SW on TOP: 26.52,50.5 26.52,52.19 27.85,52.19 29.15,53.5 29.15,54.65 29.48,54.65 29.48,50.5
VCC1V8_TA on TOP: 9.63,81.2 9.63,77.27 11.05,75.84 12.8,75.84 13.51,76.56 13.51,77.62 13.64,77.75 14.63,77.75 14.78,77.9 14.78,78.79 14.66,78.92 13.06,78.92 13.03,78.89 13.03,78.31 13.16,78.18 13.16,76.91 12.62,76.38 11.81,76.38 10.24,77.95 10.24,80.42 10.39,80.57 10.85,80.57 10.95,80.67 10.95,81.31 9.73,81.31
VCC1V8_TA on TOP: 70.26,138.91 70.41,138.76 70.97,138.76 71.09,138.89 71.09,139.83 70.94,139.98 70.94,142.04 71.6,142.7 71.6,143.46 71.42,143.64 70.46,143.64 70.26,143.43
VCC1V8_TA on TOP: 2.64,83.03 2.16,83.03 1.88,82.75 1.88,79.83 3.33,78.38 4.95,78.38 5.51,78.94 5.51,79.27 5.33,79.45 4.98,79.45 4.83,79.3 3.76,79.3 2.57,80.49 2.57,82.65 2.69,82.78 2.69,82.98
VCC1V8_TA on BOTTOM: 10.82,69.57 10.24,69.57 10.03,69.37 10.03,68.48 7.67,66.12 7.67,65.43 7.26,65.02 6.38,65.02 6.07,65.33 6.07,66.8 6.48,67.21 6.48,67.64 6.27,67.84 5.41,67.84 5.03,67.46 5.03,64.9 6.17,63.75 8.84,63.75 9.02,63.93 9.02,66.45 10.92,68.35 10.92,69.47
VCC1V8_TA on BOTTOM: 5.23,75.23 5.16,75.31 5.16,77.17 5.74,77.75 5.74,78.41 5.51,78.64 1.98,78.64 1.02,79.6 1.02,91.31 1.55,91.85 1.55,155.52 5,158.98 14.76,158.98 28.91,144.83 49.68,144.83 50.55,143.97 59.41,143.97 60.76,145.31 70.84,145.31 71.53,144.63 71.53,142.67 70.56,142.67 70.51,142.72 70.51,143.56 69.9,144.17 61.01,144.17 59.13,142.29 50.24,142.29 48.97,143.56 27.81,143.56 15.54,155.83 5.74,155.83 2.36,152.45 2.36,93.37 3.25,92.48 5.44,92.48 5.61,92.3 5.61,91.36 5.51,91.26 2.24,91.26 1.63,90.65 1.63,84.3 2.06,83.87 5,83.87 5.11,83.77 5.11,83.26 5,83.16 2.69,83.16 2.54,83.01 2.54,81.41 3.38,80.57 8.23,80.57 10.85,77.95 10.85,77.04 10.67,76.86 10.03,76.86 9.96,76.94 9.96,77.93 7.72,80.16 5.66,80.16 5.49,79.98 5.49,79.25 5.51,79.22 6.17,79.22 6.27,79.12 6.27,77.14 6.05,76.91 6.05,75.41 5.87,75.23
VCC1V8_TA on L03_SIG1: 2.64,83.03 1.65,83.03 1.65,67.89 2.39,67.16 5.49,67.16 6.15,67.82 6.15,70.84 4.7,72.29 4.7,77.72 5.84,78.87 5.84,80.9 5.54,81.2 3.02,81.2 2.64,81.58
VCC1V8_TA on L04_PWR1: 70.04,128.18 72.75,125.48 81.05,125.48 82.68,123.85 82.68,119.66 82.98,119.35 87.38,119.35 88.62,120.6 88.62,128.04 86.46,130.2 74.85,130.2 73.48,131.57 73.48,142.14 71.91,143.71 69.57,143.71 68.1,142.24 68.1,132 64.64,128.55 64.64,128.09 64.95,127.79 68.07,127.79 68.47,128.18
VCC3V3_XDS on TOP: outline of 101 points within 14.55,73.33 27.94,96.09
VCC3V3_XDS on TOP: 12.78,78.92 12.14,78.92 11.96,78.74 11.96,77.8 12.06,77.7 12.85,77.7 12.95,77.8 12.95,78.08 12.78,78.26
VCC3V3_XDS on TOP: 30.68,97.92 28.19,97.92 27.91,97.64 27.91,96.62 27.79,96.49 27.79,94.54 27.81,94.51 28.02,94.51 28.07,94.56 28.07,96.11 28.47,96.52 28.47,97.05 28.73,97.31 30.68,97.31 30.73,97.36 30.73,97.87
VCC3V3_XDS on TOP: 43.71,106.35 43.18,106.35 42.98,106.15 42.98,103.99 42.32,103.33 40.03,103.33 38.23,101.52 38.23,94.59 38.33,94.49 38.66,94.49 38.79,94.61 38.79,100.99 40.54,102.74 42.49,102.74 43.21,103.45 43.69,103.45 43.87,103.63 43.87,106.2
VCC3V3_XDS on TOP: 5.89,75.13 5.31,75.13 5.05,74.88 5.05,68.96 6.02,68 7.57,68 7.82,68.25 7.82,68.86 7.62,69.06 7.19,69.06 6.38,69.88 6.38,74.65
VCC3V3_XDS on TOP: 20.27,99.85 19.08,99.85 16.66,97.43 16.66,96.32 15.34,95 15.34,92.58 15.44,92.48 15.93,92.48 16.15,92.71 16.15,94.41 17.7,95.96 17.7,97.28 19.56,99.14 20.32,99.14 20.32,99.8
VCC3V3_XDS on TOP: 6.32,85.8 5.56,85.8 5.38,85.62 5.38,83.34 5.59,83.13 6.5,83.13 6.55,83.19 6.55,85.57
VCC3V3_XDS on TOP: 44.42,69.29 43.56,69.29 43.26,68.99 43.26,68.58 43.48,68.35 43.48,60.3 45.26,58.52 46.84,58.52 47.45,57.91 47.45,56.05 48.29,55.22 48.29,48.84 48.72,48.41 49.02,48.41 49.2,48.59 49.2,55.95 48.54,56.61 48.54,58.19 47.12,59.61 45.9,59.61 45.62,59.89 45.62,65.05 44.78,65.89 44.78,68.94
VCC3V3_XDS on TOP: 30.91,82.5 30.91,78.13 31.01,78.03 31.85,78.03 32.05,78.23 32.05,78.61 31.93,78.74 31.65,78.74 31.27,79.12 31.27,80.8 31.52,81.05 31.52,81.76 33.45,83.69 36.27,83.69 36.35,83.62 37.39,83.62 38.33,84.56 38.33,86.26 38.15,86.44 37.87,86.44 37.67,86.23 37.67,85.78 36.96,85.06 36.96,84.76 36.55,84.35 34.01,84.35 33.76,84.61 33.55,84.61 33.22,84.94 33.22,86.44 34.06,87.27 35.76,87.27 35.86,87.38 35.86,87.45 35.76,87.55 34.32,87.55 34.04,87.83 34.04,91.11 34.21,91.29 36.27,91.29 36.35,91.21 36.73,91.21 36.78,91.26 36.78,95.58 36.7,95.66 36.3,95.66 36.14,95.5 36.14,92.58 35.89,92.33 33.48,92.33 33.25,92.1 33.25,88.85 32.74,88.34 32.74,86.94 32.36,86.56 32.36,84.91 32.59,84.68 32.59,84.18
VCC3V3_XDS on BOTTOM: 20.32,99.64 19.58,99.64 19.38,99.44 19.38,98.53 19.71,98.2 25.73,98.2 25.98,98.45 27.13,98.45 27.79,97.79 27.79,95.58 27.23,95.02 25.48,95.02 25.27,94.82 25.27,94.08 25.76,93.6 26.54,93.6 27.13,93.01 30.81,93.01 32.13,94.34 38.53,94.34 38.96,94.77 38.96,95.07 38.68,95.35 31.95,95.35 30.58,93.98 27.74,93.98 27.48,94.23 27.48,94.49 28.47,95.48 28.47,97.03 28.7,97.26 29.18,97.26 29.31,97.38 29.31,97.97 28.27,99.01 20.95,99.01
VCC3V3_XDS on BOTTOM: 7.44,83.79 5.97,83.79 5.84,83.67 5.84,83.03 7.87,81 8.48,81 10.26,79.22 10.26,78.82 10.52,78.56 11.25,78.56 11.53,78.28 11.53,78.13 12.04,77.62 12.27,77.62 12.42,77.47 12.42,76.02 11.48,75.08 5.23,75.08 5.11,74.96 5.11,74.68 5.31,74.47 11.76,74.47 13.13,75.84 13.13,77.22 13.36,77.44 14.02,77.44 14.71,76.76 14.71,75.92 15.29,75.34 15.72,75.34 15.98,75.59 15.98,76.07 16.23,76.33 18.29,76.33 18.64,76.68 18.64,77.34 18.14,77.85 15.44,77.85 11.94,81.36 9.88,81.36
VCC3V3_XDS on BOTTOM: 20.95,88.67 20.73,88.67 20.55,88.49 20.55,87.53 19.1,86.08 19.1,84.61 19.68,84.02 21.06,84.02 21.18,84.15 21.18,84.45 21.06,84.58 20.07,84.58 19.86,84.79 19.86,85.95 21.11,87.2 21.11,88.52
VCC3V3_XDS on BOTTOM: 23.16,78.03 22.68,78.03 22.5,77.85 22.5,77.47 23.44,76.53 27.3,76.53 28.09,77.32 28.09,77.8 27.86,78.03 27.38,78.03 26.82,77.47 23.72,77.47
VCC3V3_XDS on BOTTOM: 6.12,71.63 5.38,71.63 5.31,71.55 5.31,69.6 5.41,69.49 5.41,68.5 5.84,68.07 8.18,68.07 8.36,68.25 8.36,68.71 8.28,68.78 6.63,68.78 6.12,69.29
VCC3V3_XDS on BOTTOM: 50.85,49.61 48.74,49.61 48.39,49.25 48.39,48.74 48.97,48.16 59.92,48.16 60.54,47.54 62.34,47.54 62.99,48.18 67.87,48.18 68.02,48.03 68.02,46.89 68.1,46.81 68.58,46.81 68.99,46.41 68.99,46.13 69.16,45.95 69.6,45.95 69.95,46.3 69.95,48.13 68.81,49.28 64.47,49.28 63.02,50.72 61.11,50.72 59.66,49.28 51.18,49.28
VCC3V3_XDS on BOTTOM: 4.98,90.96 2.67,90.96 2.13,90.42 2.13,85.6 3,84.73 5.97,84.73 6.38,85.14 6.38,85.42 6.25,85.55 5.74,85.55 5.41,85.22 3.35,85.22 2.77,85.8 2.77,87.27 3.12,87.63 3.12,89.46 2.84,89.74 2.84,90.32 2.97,90.45 4.95,90.45 5.03,90.53 5.03,90.91
VCC3V3_XDS on L03_SIG1: 28.17,78.26 27.66,78.26 27.33,77.93 27.33,77.27 27.79,76.81 30.76,76.81 32.05,78.11 32.05,78.56 31.85,78.77 31.39,78.77 30.73,78.11 30.48,78.11 30.15,77.77 29.08,77.77 28.75,78.11 28.32,78.11
VCC3V3_XDS on L03_SIG1: 40.01,86.69 38,86.69 37.67,86.36 37.67,80.04 40.03,77.67 40.03,74.8 39.73,74.5 39.73,70.38 41.68,68.43 43.36,68.43 43.79,68.86 43.79,69.27 43.66,69.39 43.26,69.39 43.15,69.49 43.15,70.05 41.84,71.37 41.84,73.4 40.61,74.62 40.61,77.34 40.84,77.57 40.84,79.71 40.21,79.71 39.7,80.21 39.7,81.79 40.44,82.52 40.44,83.69 40.84,84.1 40.84,85.85
VCC_0V85 on TOP: 35.72,56.9 35.72,58.11 35.56,58.27 34.57,58.27 33.91,57.61 32.18,57.61 32.08,57.51 32.08,57.2 32.13,57.15 33.73,57.15 33.81,57.07 33.81,56.9
VCC_0V85 on BOTTOM: 34.32,58.17 34.32,57.81 35.74,57.81 35.74,58.37 37.9,60.53 37.9,63.47 38.13,63.7 38.13,64.31 38.07,64.36 37.06,64.36 36.86,64.16 36.86,63.14 37.08,62.92 37.08,60.81 36.25,59.97 35.89,59.97 34.67,58.75 34.67,58.52
VCC_1V8_FT4232 on TOP: 53.74,39.25 53.74,40.01 53.22,40.01 53.14,39.93 53.14,39.29 53.31,39.13 53.31,36.84 52.59,36.13 43.84,36.13 43.82,36.1 43.82,35.56 43.85,35.54 44.54,35.54 44.7,35.7 52.14,35.7 52.36,35.48 52.36,34.82 52.2,34.67 49.88,34.67 48.83,33.61 48.83,29.13 48.26,28.56 46.87,28.56 46.81,28.5 45.26,28.5 45.23,28.47 45.23,28.21 45.26,28.18 46.9,28.18 47.02,28.07 48.67,28.07 49.4,28.79 49.4,33.13 50.29,34.03 52.98,34.03 54.72,32.29 54.72,30.2 53.25,28.73 53.25,25.1 52.98,24.84 52.98,23.42 53.13,23.27 53.53,23.27 53.66,23.41 53.66,28.4 55.2,29.94 55.2,32.67 53.11,34.76 53.11,35.98 53.63,36.49 53.63,39.13
VCC_1V8_IOVDD on TOP: 53.9,150.47 52.48,150.47 52.27,150.67 52.27,150.85 51.84,150.85 51.69,151 50.39,151 50.37,150.98 50.37,150.5 50.6,150.27 51.94,150.27 52.02,150.19 52.93,150.19 52.98,150.14 53.9,150.14
VCC_1V8_IOVDD on TOP: 65.71,135.76 64.82,136.65 64.82,137.16 64.62,137.36 62.71,137.36 62.33,137.74 62.33,140.98 62.6,141.25 62.6,143.62 62.33,143.89 60.15,143.89 59.11,142.85 59.11,142.39 58.19,141.48 53.01,141.48 51.59,140.06 47.27,140.06 44.96,142.37 44.96,144.07 45.16,144.27 45.47,144.27 45.62,144.12 45.62,142.93 45.8,142.75 46.38,142.75 46.66,143.03 46.66,144.09 46.79,144.22 47.35,144.22 47.45,144.12 47.45,142.16 47.9,141.71 48.92,141.71 49.3,142.09 49.3,146.58 49.12,146.76 48.49,146.76 48.29,146.96 47.52,146.96 47.19,147.29 45.9,147.29 45.85,147.35 45.85,147.7 45.87,147.73 47.57,147.73 47.85,147.45 49.56,147.45 50.06,146.94 50.06,142.01 50.29,141.78 51.64,141.78 52.25,142.39 57.66,142.39 58.65,143.38 58.65,143.84 60.05,145.24 64.14,145.24 64.85,144.52 64.85,141.25 64.7,141.1 63.8,141.1 63.12,140.41 63.12,139.4 63.32,139.19 64.24,139.19 64.34,139.09 65.68,139.09 66.98,137.79 66.98,135.92 66.83,135.76
VCC_1V8_IOVDD on BOTTOM: 55.12,163.7 54.2,163.7 54.1,163.6 54.1,162.76 53.77,162.43 51.69,162.43 51.41,162.15 51.41,160.86 51.64,160.63 53.31,160.63 55.22,162.53 55.22,163.6
VCC_1V8_IOVDD on L03_SIG1: 47.47,143.23 47.47,143.03 47.29,142.85 46.71,142.85 45.16,144.4 45.16,155.63 51.69,162.15 52.5,162.15 53.29,161.37 53.29,160.78 50.37,157.86 50.37,157.1 51.74,155.73 53.92,155.73 54.64,155.02 54.64,153.24 53.9,152.5 53.9,150.27 53.21,149.58 51.61,149.58 51.05,150.14 51.05,150.7 51.28,150.93 51.66,150.93 52.1,150.5 52.86,150.5 53.19,150.83 53.19,153.44 52.78,153.85 48.29,153.85 47.45,153.01 47.45,143.26
VCC_3V3_AVDD on TOP: 53.48,142.97 55.12,142.97 55.12,145.32 52.83,145.32 52.83,146.13 53.72,146.13 53.72,146.83 52.27,146.83 52.27,144.88 50.95,144.88 50.95,143.99 53.48,143.99
VCC_3V3_AVDD on TOP: 49.38,154.9 49.38,152.6 48.59,152.6 48.26,152.93 47.57,152.93 47.57,151.26 47.01,151.26 47.01,152.94 44.59,152.94 44.59,154.89 46.19,154.89 46.19,153.96 46.38,153.77 48.16,153.77 48.26,153.87 48.26,154.73 48.44,154.9
VCC_3V3_FT4232 on TOP: 49.42,10.45 49.42,11.6 49.32,11.69 49.32,12.03 49.25,12.1 48.71,12.1 48.59,12.21 48.59,12.56 48.85,12.82 49.78,12.82 49.92,12.69 49.92,10.45
VCC_3V3_FT4232 on BOTTOM: 43.08,18.96 48.72,18.96 49.33,18.35 49.33,13.49 48.56,12.73 48.56,11.89 48.74,11.71 49.83,11.71 50.65,12.52 50.65,18.3 51.31,18.96 53.94,18.96 55.82,20.84 57.5,20.84 57.93,21.28 57.93,22.8 57.92,22.82 57.92,25.43 56.78,26.57 55.36,26.57 54.27,27.67 54.27,28.22 53.85,28.64 53.85,29.61 53.82,29.64 53.64,29.64 53.53,29.53 53.53,22.28 53.09,21.84 45.94,21.84 44.87,22.9 44.87,28.78 45.23,29.14 48.55,29.14 48.69,29.28 48.69,33.31 50.63,35.26 57.02,35.26 57.99,34.29 58.98,34.29 59.61,34.92 59.61,35.78 58.75,36.65 52.58,36.65 52.17,37.06 52.17,39.52 51.87,39.83 51.08,39.83 50.85,39.6 50.85,37.85 48.88,35.87 47.07,35.87 43.89,32.69 42.21,32.69 41.43,31.9 41.43,30.18 40.26,29.01 40.26,24.21 43.08,21.39
VCC_3V3_SYS on TOP: 18.08,113.31 17.91,113.49 17.91,117.73 18.41,118.24 18.41,118.92 18.62,119.13 24.87,119.13 28.09,115.9 31.55,115.9 33.48,113.97 33.48,113.64 33.17,113.33 32.82,113.33 32.13,114.02 27.36,114.02 24.13,117.25 20.27,117.25 19.91,116.89 19.91,113.67 19.56,113.31
VCC_3V3_SYS on TOP: 30.36,48.56 30.36,45.95 30.64,45.67 40.92,45.67 41.5,46.25 44.63,46.25 47.96,49.58 47.96,55.17 45.11,55.17 44.78,54.84 44.78,52.25 44.88,52.15 46.28,52.15 46.28,51.54 46,51.26 46,50.01 44.12,48.13 42.8,48.13 42.37,48.56
VCC_3V3_SYS on TOP: 41.71,122.1 41.71,120.55 43,120.55 43,122.1
VCC_3V3_SYS on TOP: 112.62,68.36 112.62,64.87 112.86,64.63 112.86,63.88 112.7,63.72 111.88,63.72 111.81,63.79 111.81,68.26 112.52,68.26
VCC_3V3_SYS on TOP: 114.1,45.41 113.06,45.41 113.06,43.87 113.94,42.98 113.94,42.8 113.94,42.8 113.94,42 114.53,42 114.53,43.05 114.1,43.48
VCC_3V3_SYS on TOP: 49.91,154.86 49.91,152.51 50.94,152.51 50.94,154.86
VCC_3V3_SYS on TOP: 81.67,45.41 80.5,45.41 80.5,43.65 80.88,43.27 81.13,43.27 81.51,42.89 81.51,42 82.1,42 82.1,43.05 81.67,43.48
VCC_3V3_SYS on TOP: 87.65,158.54 85.91,158.54 85.54,158.91 85.54,160.11 85.66,160.23 87.65,160.23
VCC_3V3_SYS on BOTTOM: 45.06,60.27 44.15,60.27 43.48,59.61 43.48,57.89 44.5,56.87 45.54,56.87 45.59,56.92 45.59,57.07 45.44,57.23 44.68,57.23 44.6,57.3 44.6,58.09 45.09,58.57 45.09,60.25
VCC_3V3_SYS on BOTTOM: 35.76,66.17 32.46,66.17 31.8,66.83 26.72,66.83 24.51,69.04 21.64,69.04 19.91,67.31 18.82,67.31 18.57,67.06 18.57,66.45 18.77,66.24 18.77,65.51 19.3,64.97 19.3,63.4 19.23,63.32 18.21,63.32 17.86,63.68 17.86,67.41 18.54,68.1 19.84,68.1 21.21,69.47 24.99,69.47 27.18,67.28 32.28,67.28 32.72,66.85 35.99,66.85 36.14,66.7 36.14,66.55
VCC_3V3_SYS on BOTTOM: 117.73,45.92 112.93,45.92 112.45,45.44 112.45,43.64 112.95,43.13 116.56,43.13 117.17,42.52 117.17,41.4 117.35,41.22 118.08,41.22 118.31,41.45 118.31,45.34
VCC_3V3_SYS on BOTTOM: 32.08,35.51 31.14,35.51 31.11,35.48 31.11,33.63 31.34,33.4 31.34,32.69 30.68,32.03 28.32,32.03 27.25,30.96 27.25,28.5 28.35,27.41 28.63,27.41 28.93,27.1 28.93,27 29.01,26.92 29.34,26.92 29.39,26.97 29.39,27.3 28.35,28.35 28.19,28.35 27.71,28.83 27.71,30.3 28.75,31.34 31.29,31.34 32.26,32.31 32.26,35.33
VCC_3V3_SYS on BOTTOM: 39.32,51.56 39.67,51.56 39.98,51.26 39.98,50.42 39.73,50.16 39.73,48.41 40.31,47.83 40.31,46.58 40.87,46.02 40.87,44.12 40.18,43.43 40.18,43.13 40.34,42.98 41.3,42.98 41.43,42.85 41.43,42.67 41.35,42.6 40.21,42.6 39.85,42.95 39.85,43.64 40.34,44.12 40.34,45.57 39.62,46.28 39.62,47.83 39.32,48.13 39.32,50.14 39.67,50.5 39.67,51.08 39.57,51.18 39.29,51.18 39.22,51.26 39.22,51.46
VCC_3V3_SYS on BOTTOM: 18.14,115.11 19.43,115.11 23.09,111.46 33.32,111.46 33.55,111.68 34.95,111.68 35.15,111.89 37.67,111.89 37.9,112.12 38.25,112.12 38.38,111.99 38.38,111.35 38.35,111.33 37.11,111.33 36.26,110.48 35.04,110.48 34.54,109.98 20.88,109.98 17.6,113.26 17.6,114.58
VCC_3V3_SYS on BOTTOM: 32.49,49.89 32.49,45.69 32.31,45.52 28.42,45.52 27.71,44.81 17.04,44.81 16.38,44.15 16.38,42.62 16.71,42.29 22.78,42.29 23.83,43.33 28.8,43.33 29.18,43.71 32.44,43.71 33.58,44.86 36.12,44.86 36.96,45.69 36.96,49.89
VCC_3V3_SYS on BOTTOM: 37.82,56.46 37.16,56.46 36.98,56.29 36.98,55.17 37.85,54.31 37.85,53.04 37.9,52.98 38.15,52.98 38.23,53.06 38.23,54.61 37.69,55.14 37.69,55.83 37.87,56.01 37.87,56.41
VCC_3V3_SYS on BOTTOM: 35.61,71.09 36.17,71.09 36.42,71.35 37.16,71.35 37.72,71.91 37.72,72.39 38.28,72.95 43.61,72.95 44.09,72.47 44.09,71.48 45.03,70.54 45.03,69.01 45.31,68.73 46.81,68.73 47.24,68.3 47.24,66.14 47.42,65.96 47.62,65.96 47.98,65.61 47.98,65.33 47.88,65.23 47.78,65.23 47.62,65.38 47.62,65.53 47.5,65.66 47.12,65.66 46.74,66.04 46.74,67.84 46.46,68.12 46.18,68.12 45.97,67.92 45.97,67.54 45.75,67.31 45.03,67.31 44.6,67.74 44.6,70.18 43.46,71.32 43.46,72.03 43.23,72.26 39.27,72.26 38.96,71.96 38.96,71.4 38.13,70.56 36.45,70.56 36.27,70.38 35.61,70.38 35.46,70.54 35.46,70.94
VCC_3V3_SYS on BOTTOM: 29.51,41.4 28.85,41.4 28.7,41.25 28.7,40.13 29.21,39.62 29.21,38.18 28.93,37.9 28.93,36.83 29.26,36.5 30.12,36.5 30.2,36.58 30.45,36.58 30.56,36.68 30.56,36.83 30.4,36.98 29.46,36.98 29.31,37.13 29.31,37.54 29.97,38.2 29.97,40.06 29.57,40.46 29.57,41.35
VCC_3V3_SYS on BOTTOM: 46.23,57.61 46.48,57.61 46.86,57.99 47.55,57.99 48.16,57.38 48.16,52.93 47.96,52.73 47.35,52.73 47.19,52.88 47.19,53.85 46.76,54.28 46.69,54.28 46.69,55.68 46.71,55.7 46.71,55.75 46.51,55.96 46.51,56.21 46.66,56.36 47.27,56.36 47.6,56.69 47.6,57 47.37,57.23 46.18,57.23 46.18,57.56
VCC_3V3_SYS on BOTTOM: 97.7,74.82 99.17,74.82 99.17,75.79 97.7,75.79
VCC_3V3_SYS on L03_SIG1: 33.71,74.8 32.99,74.8 32.44,74.24 32.44,73.36 34.19,71.6 34.19,69.93 34.87,69.24 34.87,66.85 35.43,66.29 36.12,66.29 36.47,66.65 36.47,70.71 33.99,73.2 33.99,74.52
VCC_3V3_SYS on L03_SIG1: 29.97,82.98 29.46,82.98 29.06,82.58 29.06,79.4 28.88,79.22 28.88,78.82 29.26,78.44 29.87,78.44 30.51,79.07 30.51,82.45
VCC_3V3_SYS on L03_SIG1: 48.23,54.36 47.62,54.36 47.4,54.13 47.4,52.15 49.73,49.81 50.62,49.81 50.93,50.11 50.93,50.67 48.46,53.14 48.46,54.13
VCC_3V3_SYS on L03_SIG1: 42.8,122.2 41.86,122.2 41.66,122 41.66,115.77 42.25,115.18 42.25,113.17 43.08,112.34 43.08,112.12 43.41,111.79 44.35,111.79 44.96,112.39 44.96,114.73 43.93,115.76 43.93,121.07
VCC_3V3_SYS on L03_SIG1: 37.57,56.57 37.03,56.57 36.96,56.49 36.96,55.22 37.62,54.56 37.62,52.27 37.26,51.92 37.26,50.77 37.39,50.65 38.02,50.65 38.38,51 38.38,55.75
VCC_3V3_SYS on L03_SIG1: 119.76,47.6 118.97,47.6 118.59,47.22 118.59,44.86 117.02,43.28 117.02,42.67 117.53,42.16 118.03,42.16 120.09,44.22 120.09,47.27
VCC_3V3_SYS on L04_PWR1: 36.45,122.5 36.07,122.12 36.07,119.71 36.42,119.35 56.52,119.35 58.52,121.36 58.52,125.83 57,127.36 56.13,127.36 54.97,128.52 54.97,129.41 55.73,130.18 58.85,130.18 60.17,128.85 64.14,128.85 67.59,132.31 67.59,138.61 66.75,139.45 60.25,139.45 59.28,140.41 59.28,147.96 64.21,152.88 93.68,152.88 96.88,149.68 96.88,146.94 97.64,146.18 104.62,146.18 105.38,146.94 105.38,152.98 98.15,160.22 59.74,160.22 56.03,156.51 51.51,156.51 50.14,155.14 50.14,146.74 52.1,144.78 52.1,142.54 51.08,141.53 51.08,130.25 55.35,125.98 55.35,125.04 55.09,124.79 53.67,124.79 53.33,124.45 53.33,121.96 52.6,121.23 49.43,121.23 48.16,122.5
VCC_3V3_SYS on L04_PWR1: 20.12,115.27 18.92,115.27 18.62,114.96 18.62,113 16.84,111.23 16.84,105.26 14.73,103.15 14.73,62.28 15.54,61.47 15.54,50.65 19.94,46.25 19.94,44.88 20.98,43.84 23.19,43.84 23.42,44.07 23.42,47.07 19.46,51.03 19.46,71.07 17.73,72.8 17.73,91.52 16.71,92.53 16.71,94.84 18.85,96.98 18.85,102.49 20.83,104.47 20.83,114.55
VCC_3V3_SYS on L04_PWR1: outline of 106 points within 32.51,21.39 116.31,116.15
VCC_3V3_SYS on L04_PWR1: 56.95,49.56 57.51,49 59.33,49 60.68,47.65 62.15,47.65 62.84,48.34 62.84,53.8 62.33,54.31 57.91,54.31 56.95,53.34
VCC_3V3_SYS_REG_SW on TOP: 33.15,50.5 33.15,52.02 32.97,52.19 31.79,52.19 30.49,53.5 30.49,54.65 30.15,54.65 30.15,50.5
VCC_5V0 on TOP: 27.54,57.57 26.21,57.57 26.21,57.71 24.99,57.71 24.44,57.16 24.44,56.39 25.85,56.39 25.85,57.16 27.54,57.16
VCC_5V0 on TOP: 43.71,19.46 43.71,17.47 43.98,17.2 45.96,17.2 45.96,16.25 39.08,16.25 39.08,19.46
VCC_5V0 on TOP: 5.51,9.53 7.39,9.53 7.39,13.06 7.87,13.54 7.87,14.58 6.99,14.58 6.27,13.87 5.66,13.87 5.51,13.72
VCC_5V0 on TOP: 33.91,158.88 33.4,158.88 33.27,158.75 30.78,158.75 30.73,158.7 29.59,158.7 29.51,158.62 29.51,158.39 29.54,158.37 30.89,158.37 31.19,158.06 31.9,158.06 32.18,157.78 33.93,157.78 33.99,157.84 33.99,158.8
VCC_5V0 on TOP: 15.47,31.47 2.92,31.47 1.4,29.95 1.4,24.82 4.98,24.82 4.98,24.23 16.28,24.23 16.28,26.8 15.72,27.36 15.72,31.22
VCC_5V0 on TOP: 54.1,62.2 55.8,62.2 56.03,61.98 56.03,60.45 55.6,60.02 55.6,59.26 55.98,58.88 55.98,58.52 55.8,58.34 55.3,58.34 54.89,58.75 54.89,60.53 55.24,60.88 55.24,61.57 55.07,61.75 54.15,61.75 54.1,61.8
VCC_5V0 on TOP: 41.07,83.34 40.44,83.34 40.39,83.29 40.39,82.98 40.44,82.93 40.44,81.25 39.75,80.57 39.75,80.37 39.9,80.21 40.92,80.21 41.25,80.54 41.25,83.16
VCC_5V0 on TOP: 118.57,147.37 120.98,147.37 121.26,147.66 123.35,147.66 123.35,149.42 123.28,149.49 118.66,149.49 118.55,149.38 118.55,147.39
VCC_5V0 on TOP: 8.43,119.05 6.02,119.05 5.74,118.76 3.65,118.76 3.65,117.01 3.69,116.97 8.43,116.97
VCC_5V0 on BOTTOM: 27.71,55.64 27.71,52.27 32.99,52.27 33.24,52.52 33.24,53.83 33.68,54.27 33.68,54.98 33.58,55.08 31.87,55.08 31.87,55.66 30.93,55.66 30.93,53.99 28.76,53.99 28.76,55.64
VCC_5V0 on BOTTOM: 2.13,31.29 2.13,25.58 16.89,25.58 16.89,31.29
VCC_5V0 on BOTTOM: 82.8,31.19 81.69,31.19 81.33,30.84 81.33,27.74 81.61,27.46 82.78,27.46 83.01,27.69 83.01,30.99
VCC_5V0 on BOTTOM: 39.78,80.24 39.88,80.14 40.61,80.14 41.15,80.67 41.81,80.67 41.81,82.14 41.17,82.78 40.46,82.78 39.78,82.09
VCC_5V0 on BOTTOM: 28.75,56.98 28.75,58.61 30.84,58.61 30.84,56.99 32.59,56.99 32.59,59.97 25.96,59.97 25.96,58.47 25.14,57.65 24.6,57.65 24.38,57.44 24.38,56.67 24.61,56.45 25.98,56.45 26.52,56.98
VCC_5V0 on BOTTOM: 42.2,16.72 39.41,16.72 39.41,20.17 42.2,20.17
VCC_5V0 on L03_SIG1: 7.44,7.92 8,8.48 8,25.53 9.88,27.41 13.79,27.41 14.88,28.5 14.88,31.32 14.53,31.67 3.15,31.67 2.41,30.94 2.41,8.56 3.05,7.92
VCC_5V0 on L03_SIG1: 55.75,58.98 55.22,58.98 54.28,58.04 54.28,53.62 56.06,51.84 56.36,51.84 56.5,51.7 56.5,49.97 55.32,48.79 55.32,46.33 55.91,45.75 57.38,45.75 57.86,46.23 57.86,46.66 57.48,47.04 57.15,47.04 57.15,48.82 57.56,49.23 57.56,51.84 57.15,52.25 57.15,57.58
VCC_5V0 on L03_SIG1: 15.98,31.39 15.34,31.39 15.16,31.22 15.16,28.17 15.29,28.04 15.75,28.04 16.08,28.37 16.08,31.29
VCC_5V0 on L04_PWR1: outline of 96 points within 3.63,13.97 125.93,175.9
VCC_CORE on TOP: 23.49,66.8 22.33,65.63 22.33,63.6 22.45,63.47 36.98,63.47 36.98,64.64 35.61,66.01 33.91,66.01 31.81,68.11 26.84,68.11 26.84,66.8
VCC_CORE on BOTTOM: 23.15,66.45 23.15,63.55 34.82,63.55 35.05,63.32 36.55,63.32 36.55,65.96 32.31,65.96 31.83,66.45
VDD_2V5 on TOP: 106.1,45.41 104.93,45.41 104.93,43.79 105.1,43.62 105.21,43.62 105.94,42.89 105.94,42 106.53,42 106.53,43.05 106.1,43.48
VDD_2V5 on TOP: 73.67,45.44 72.5,45.44 72.5,43.84 73.51,42.82 73.51,42 74.1,42 74.1,43.05 73.67,43.48
VDD_2V5 on BOTTOM: 82.86,36.11 82.86,34.15 83.02,34 83.02,32.96 83.2,32.77 86.19,32.77 86.42,33.01 86.42,36.11
VDD_2V5 on L04_PWR1: 78.69,31.52 76.56,31.52 73.61,34.47 73.61,38.38 72.06,39.93 72.06,45.62 72.72,46.28 76.61,46.28 80.62,42.27 83.59,42.27 86.74,45.42 105.71,45.42 106.17,44.96 106.17,39.22 100.1,33.15 80.31,33.15
VDD_CANUART on TOP: 41.53,79.45 41.15,79.83 40.41,79.83 40.41,78.03 40.49,77.95 40.49,77.19 40.67,77.01 41.1,77.01 41.25,77.17 41.25,77.83 41.76,78.33 42.77,78.33 43,78.11 43,76.94 43.21,76.73 44.35,76.73 44.35,79.45
VDD_CORE on TOP: 26.76,69.9 26.76,68.68 30.99,68.68 30.99,71.68 25.63,71.68 25.63,69.9
VDD_CORE on TOP: 41.63,97.03 39.98,97.03 39.98,94.97 41.63,94.97
VDD_CORE on TOP: 75.9,98.02 74.68,98.02 74.47,97.82 74.47,94.13 73.71,93.37 73.71,91.34 74.02,91.03 75.08,91.03 75.37,91.33 75.37,95.52 75.49,95.63 75.49,96.39 75.9,96.8
VDD_CORE on BOTTOM: 41.5,97.13 40.34,97.13 40.34,96.37 39.98,96.01 39.98,95.28 41.5,95.28
VDD_CORE on BOTTOM: 73.69,93.68 73.69,91.08 75.59,91.08 75.59,94.23 74.24,94.23
VDD_CORE on BOTTOM: 42.27,91.92 43.69,91.92 43.69,93.07 43.31,93.45 42.27,93.45
VDD_CORE on L04_PWR1: 18.31,73 18.34,91.6 28.52,101.78 72.77,101.78 75.59,98.96 75.59,88.62 69.34,88.62 67.97,87.25 66.83,87.25 66.17,86.59 66.17,82.37 66.67,81.86 68.61,81.86 68.78,81.69 68.78,80.92 68.53,80.67 68.02,80.67 67.41,80.06 65.86,80.06 64.9,81.03 62.23,81.03 61.65,81.61 56.57,81.61 56.29,81.89 56.29,85.04 55.8,85.52 53.75,85.52 51.56,87.71 51.56,88.62 49.68,90.5 37.36,90.5 31.47,84.61 31.47,69.37 30.91,68.81 20.47,68.81 20.02,69.27 20.02,71.3
VDD_CORE_REG_SW1 on TOP: 28.22,60.2 29.15,59.26 29.15,58.08 29.48,58.08 29.48,61.9 29.29,62.1 26.56,62.1 26.49,62.03 26.49,60.2
VDD_CORE_REG_SW2 on TOP: 31.65,60.48 30.49,59.31 30.49,58.08 30.15,58.08 30.15,61.93 30.33,62.1 33.15,62.1 33.15,60.48
VDD_MMC0 on TOP: 111.89,69.96 113.36,69.96 113.42,70.01 113.42,73.56 111.87,73.56 111.87,69.98
VDD_MMC0_SD on TOP: 111.61,75.36 111.61,73.84 113,73.84 113,75.36
VDD_MMC0_SD on TOP: 122.76,76.43 121.62,76.43 121.23,76.05 121.23,74.63 121.62,74.24 122.73,74.24 122.76,74.27
